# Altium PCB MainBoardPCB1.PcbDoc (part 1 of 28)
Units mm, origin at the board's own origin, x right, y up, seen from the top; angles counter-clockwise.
Board outline 258.95 x 308.86 mm, 16 copper layers (L1, L2 (GND), L3 (Sign), L4 (GND), L5 (Sign), L6 (PWR/GND), L7(PWR/GND), L8 (Plane_GND), L9 (PWR/GND), L10 (PWR/GND), L11 (PWR/GND), L12 (Sign), L13 (GND), L14 (Sign), L15 (GND), L16), stack 2.502 mm thick; 2397 components, 1744 nets, 8397 pads, 4112 vias.
Unrouted connection lines stored in the file: 3547.

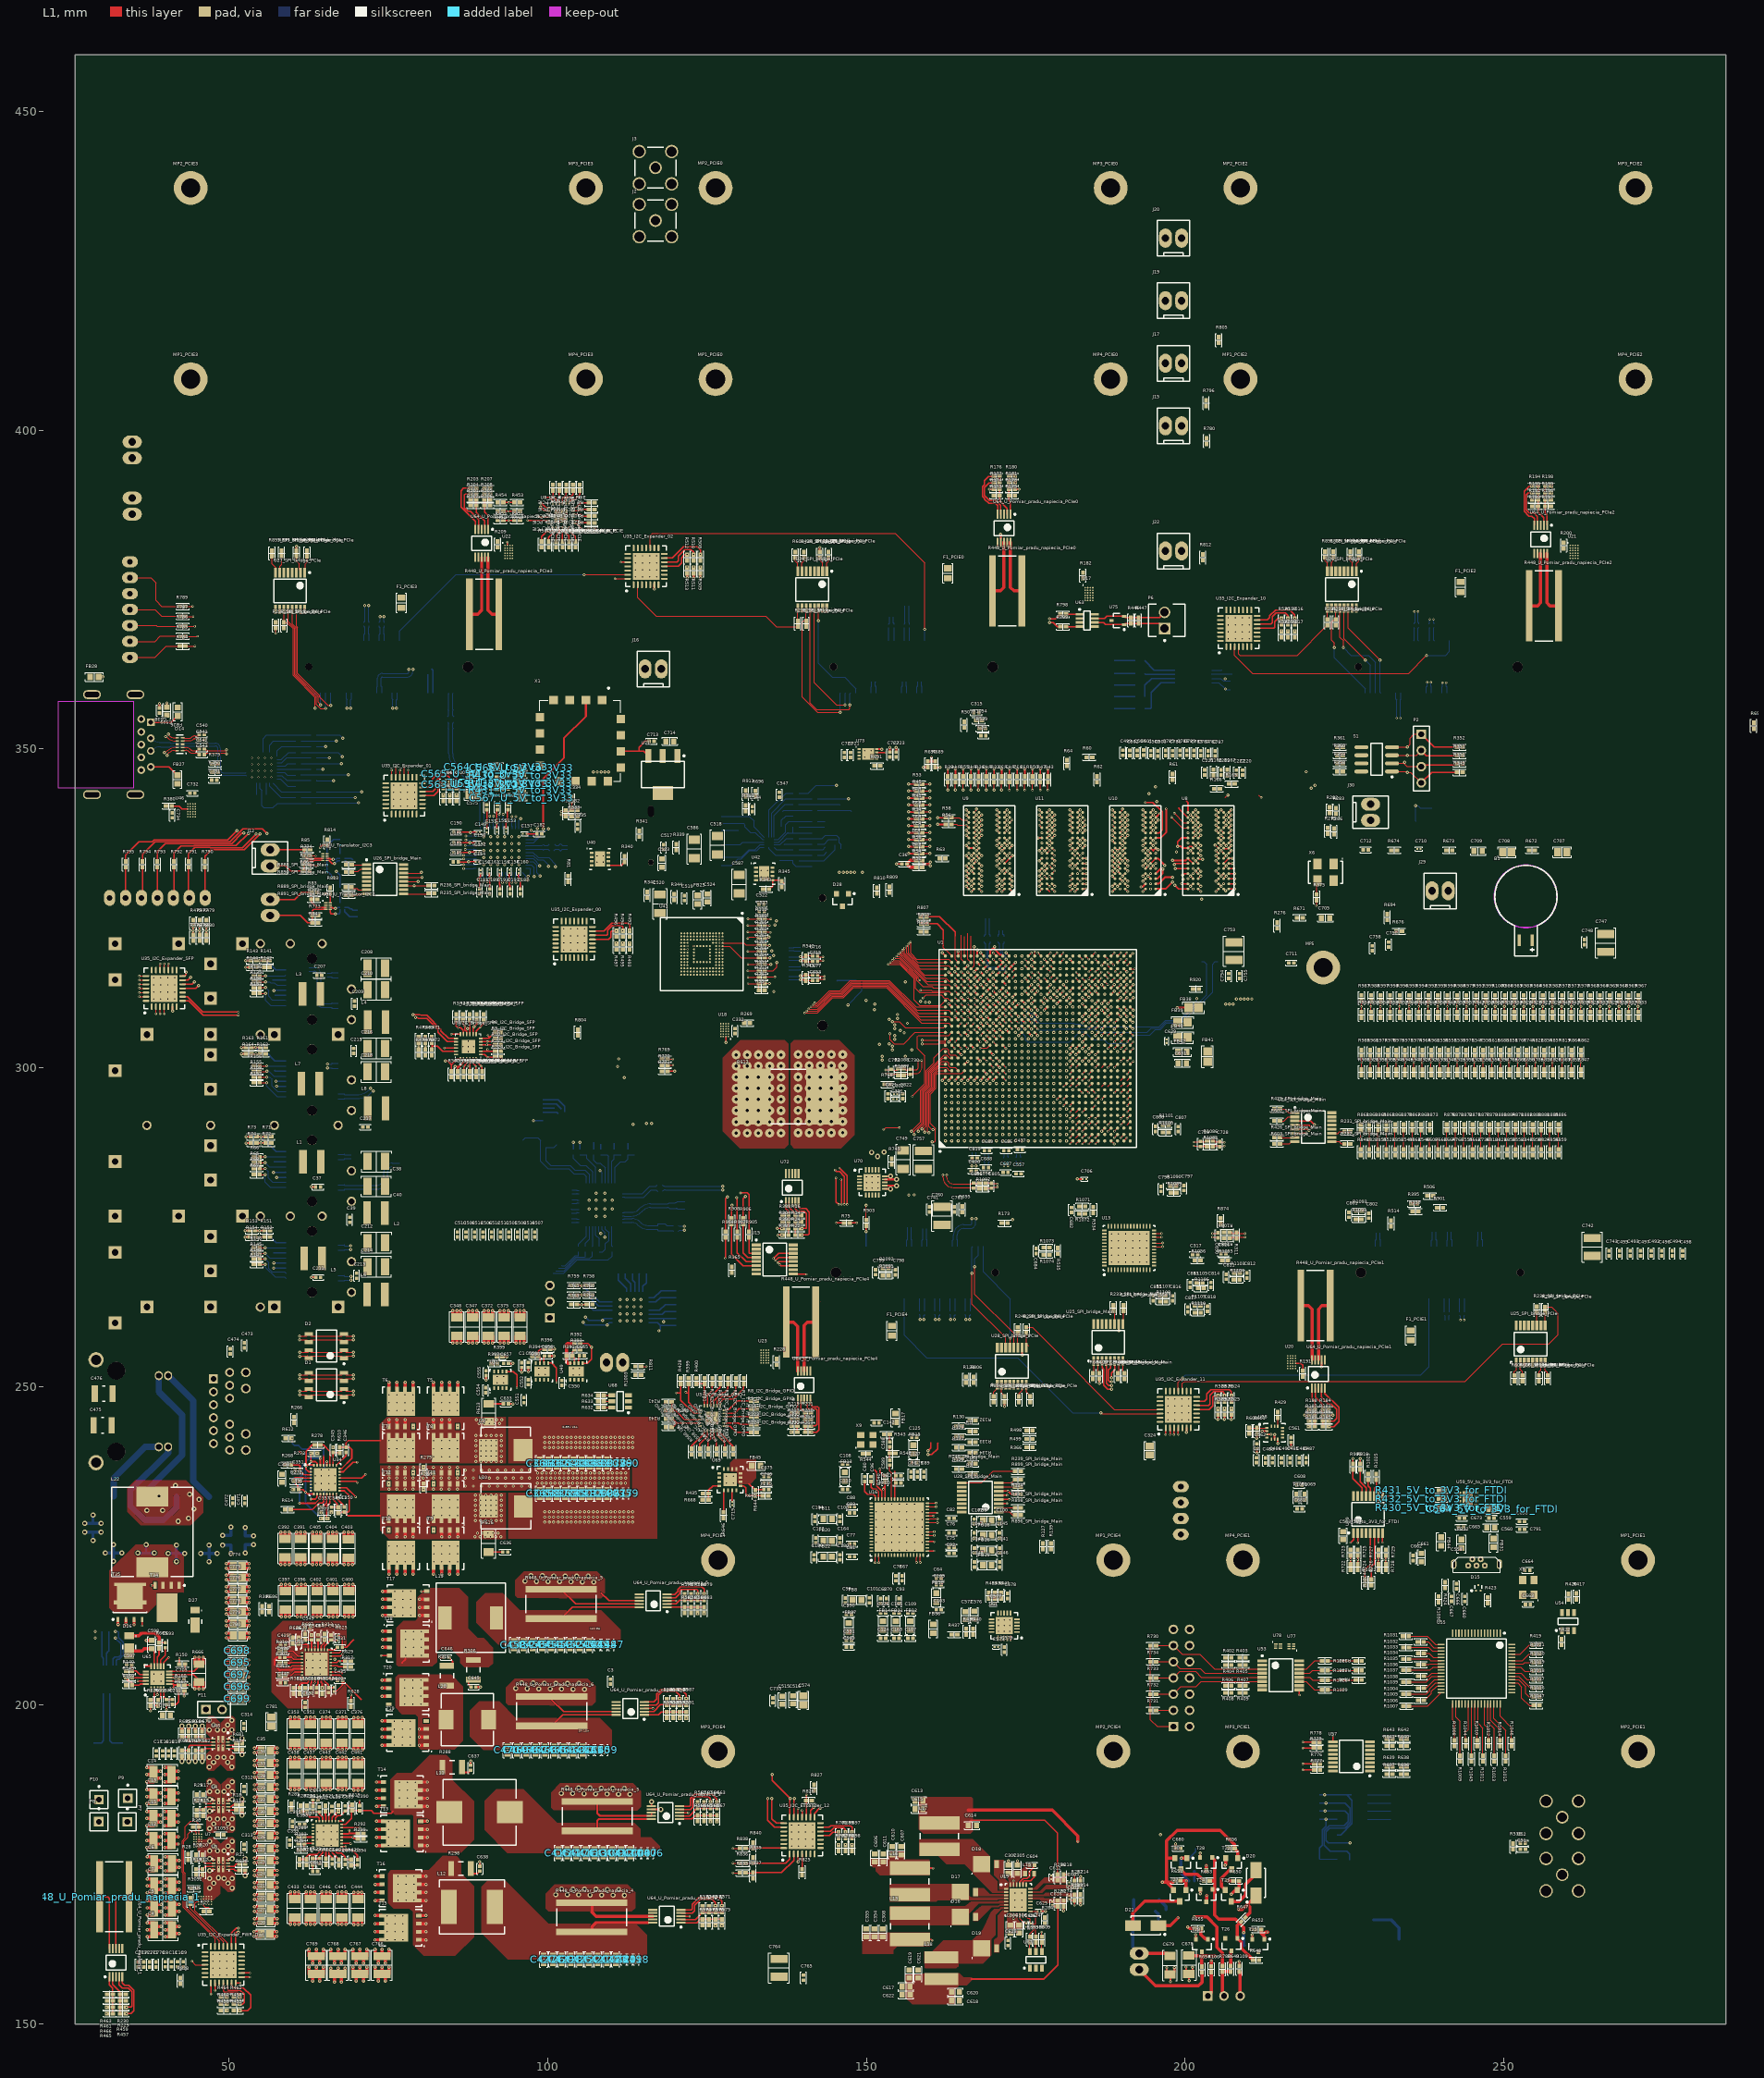
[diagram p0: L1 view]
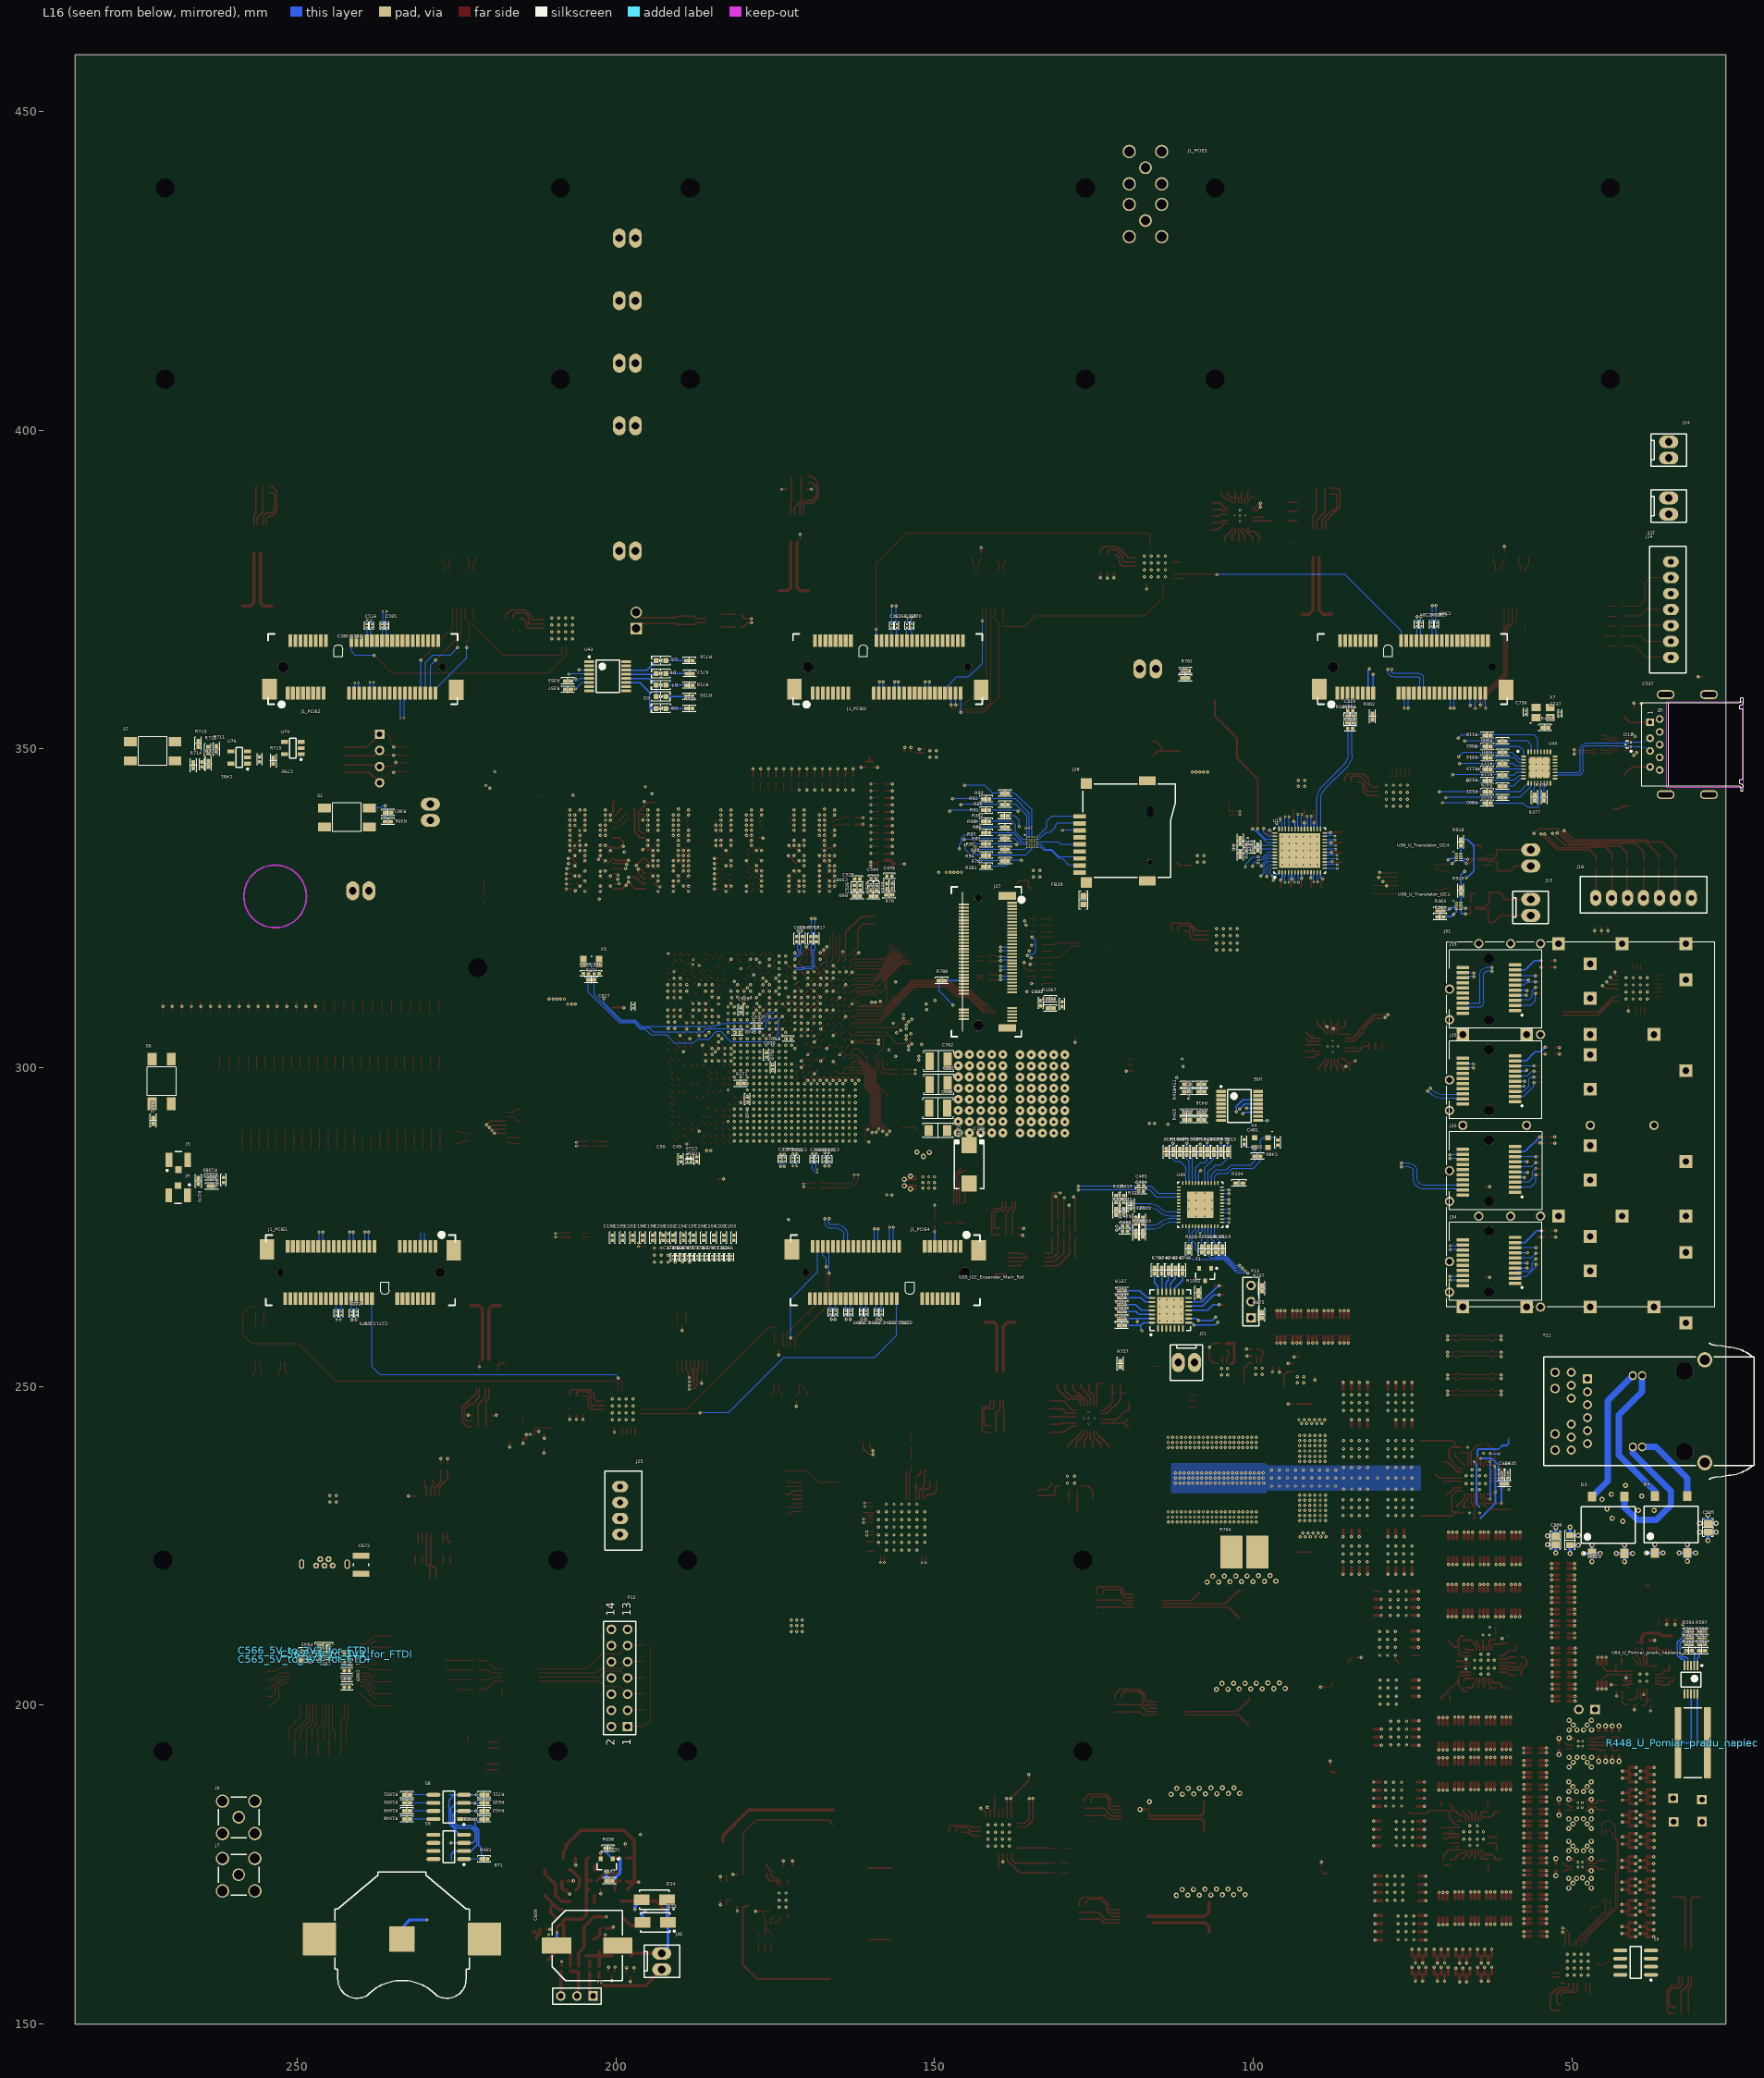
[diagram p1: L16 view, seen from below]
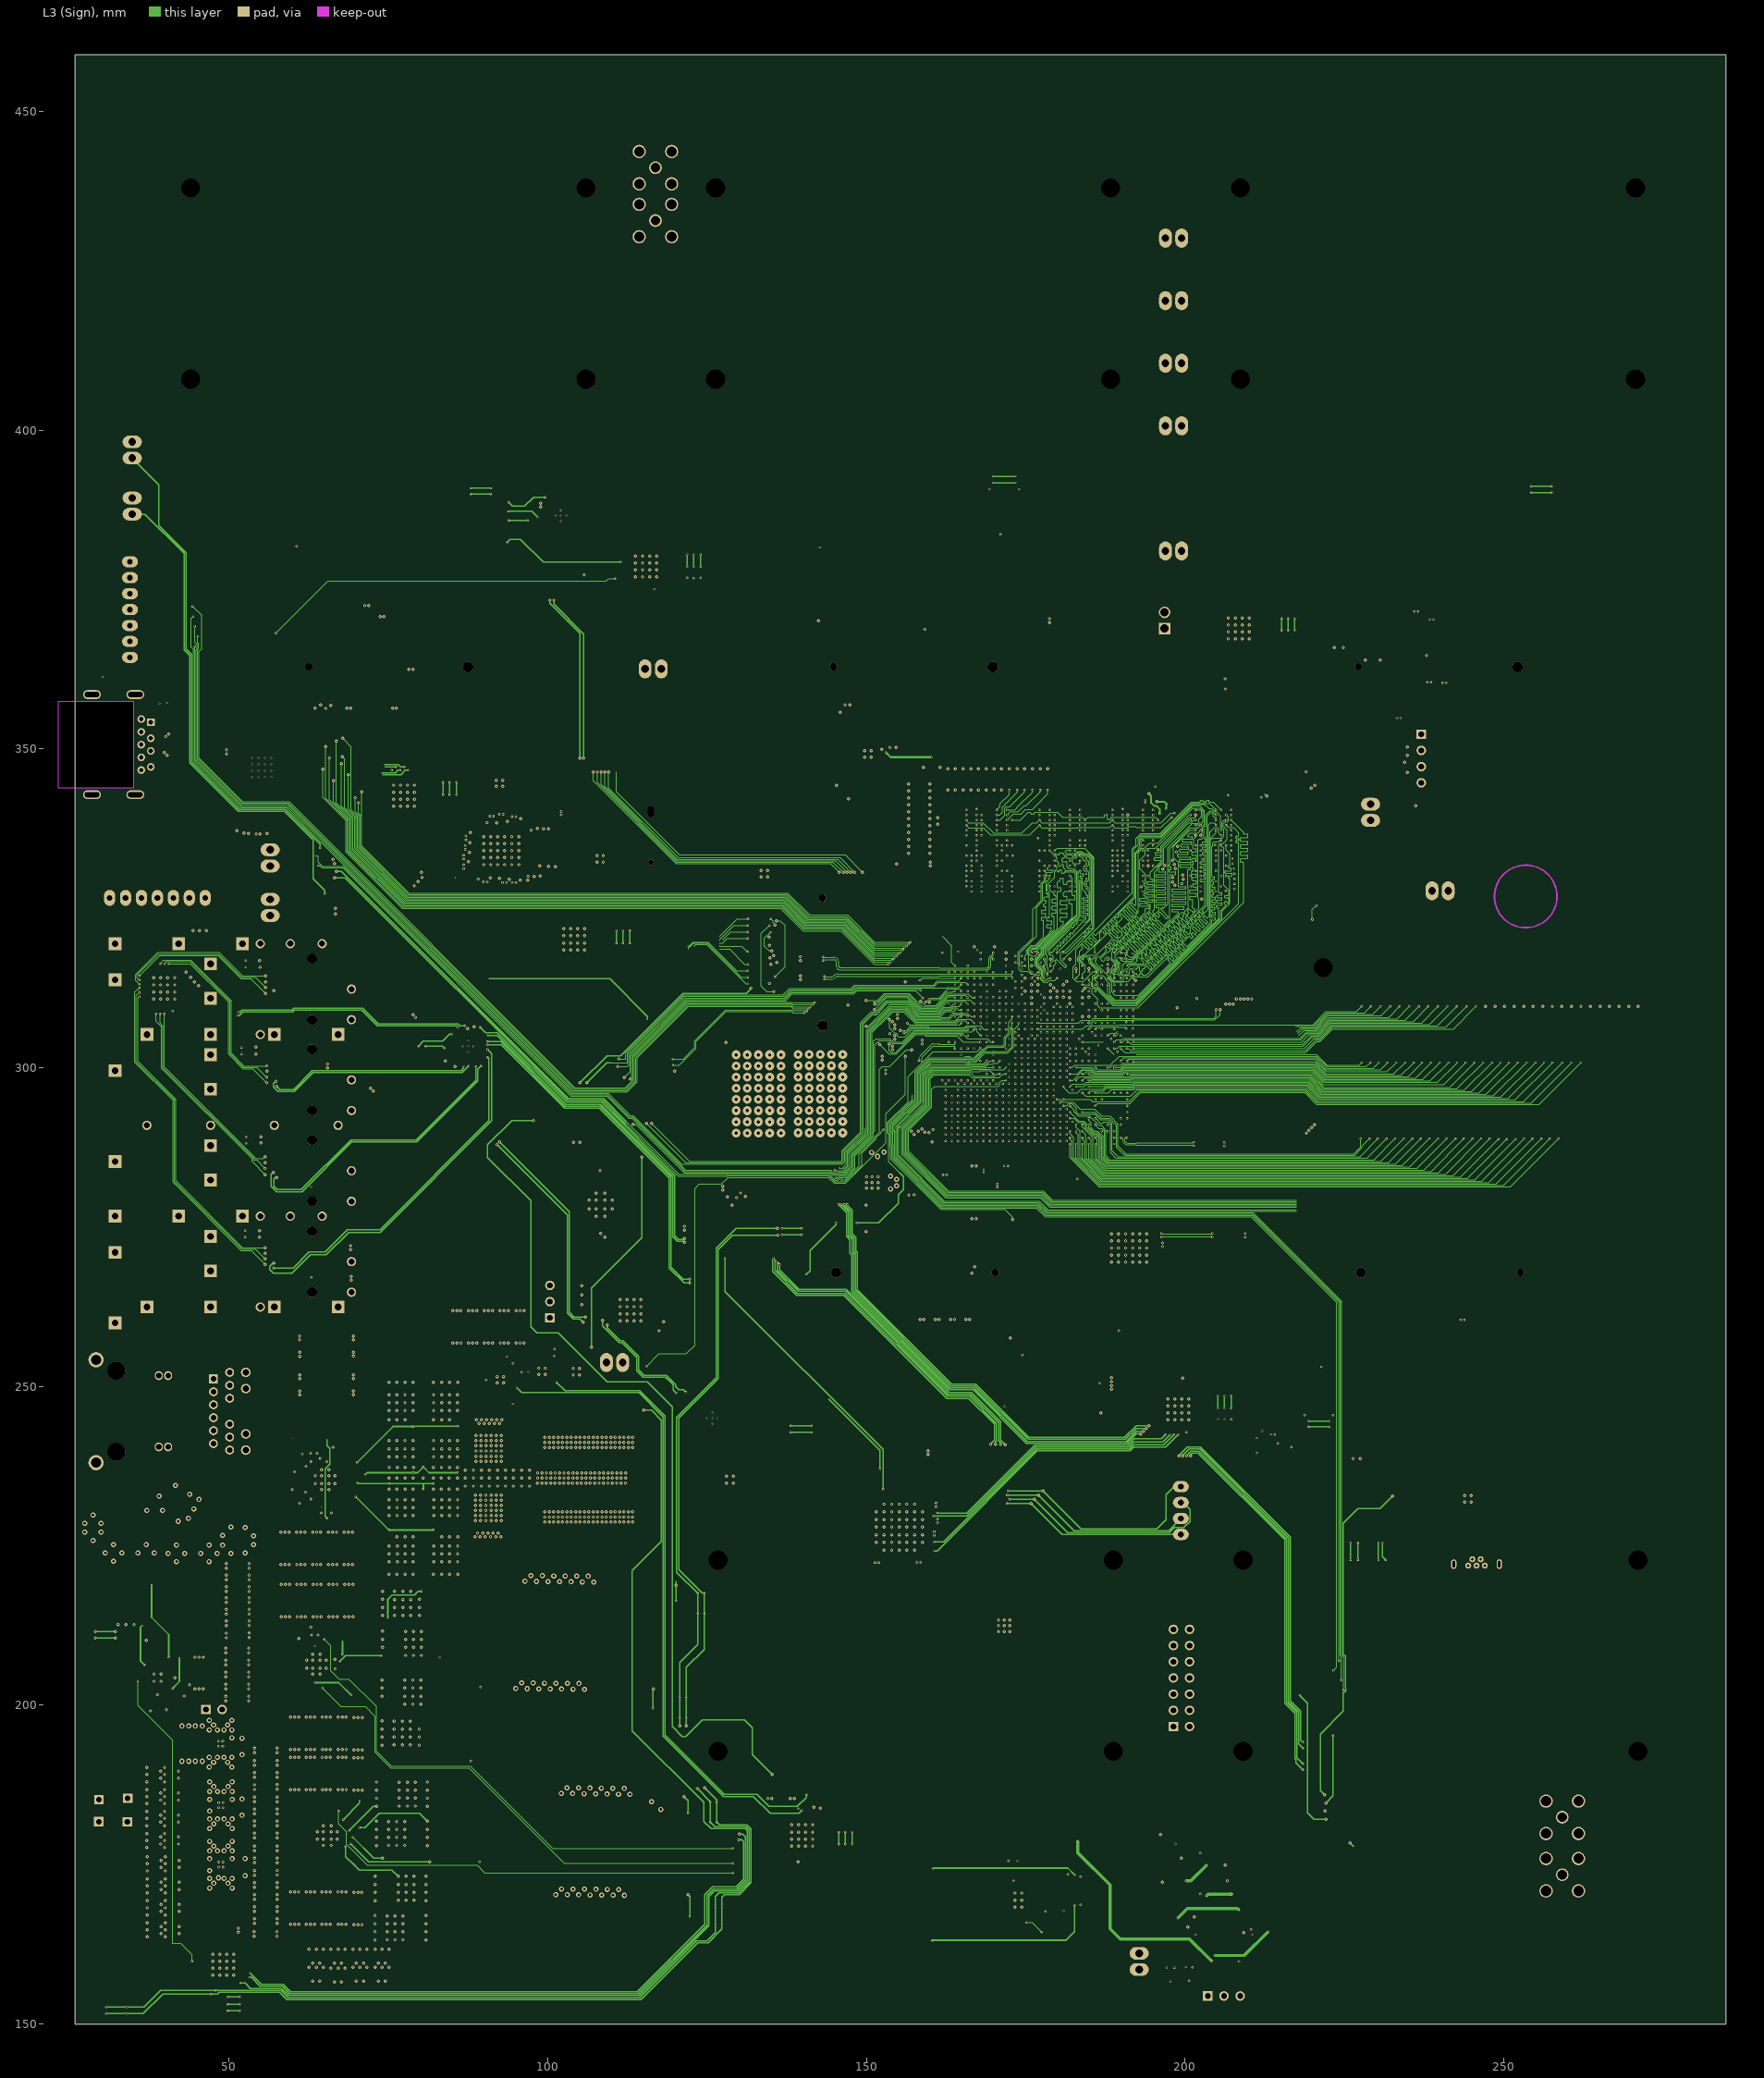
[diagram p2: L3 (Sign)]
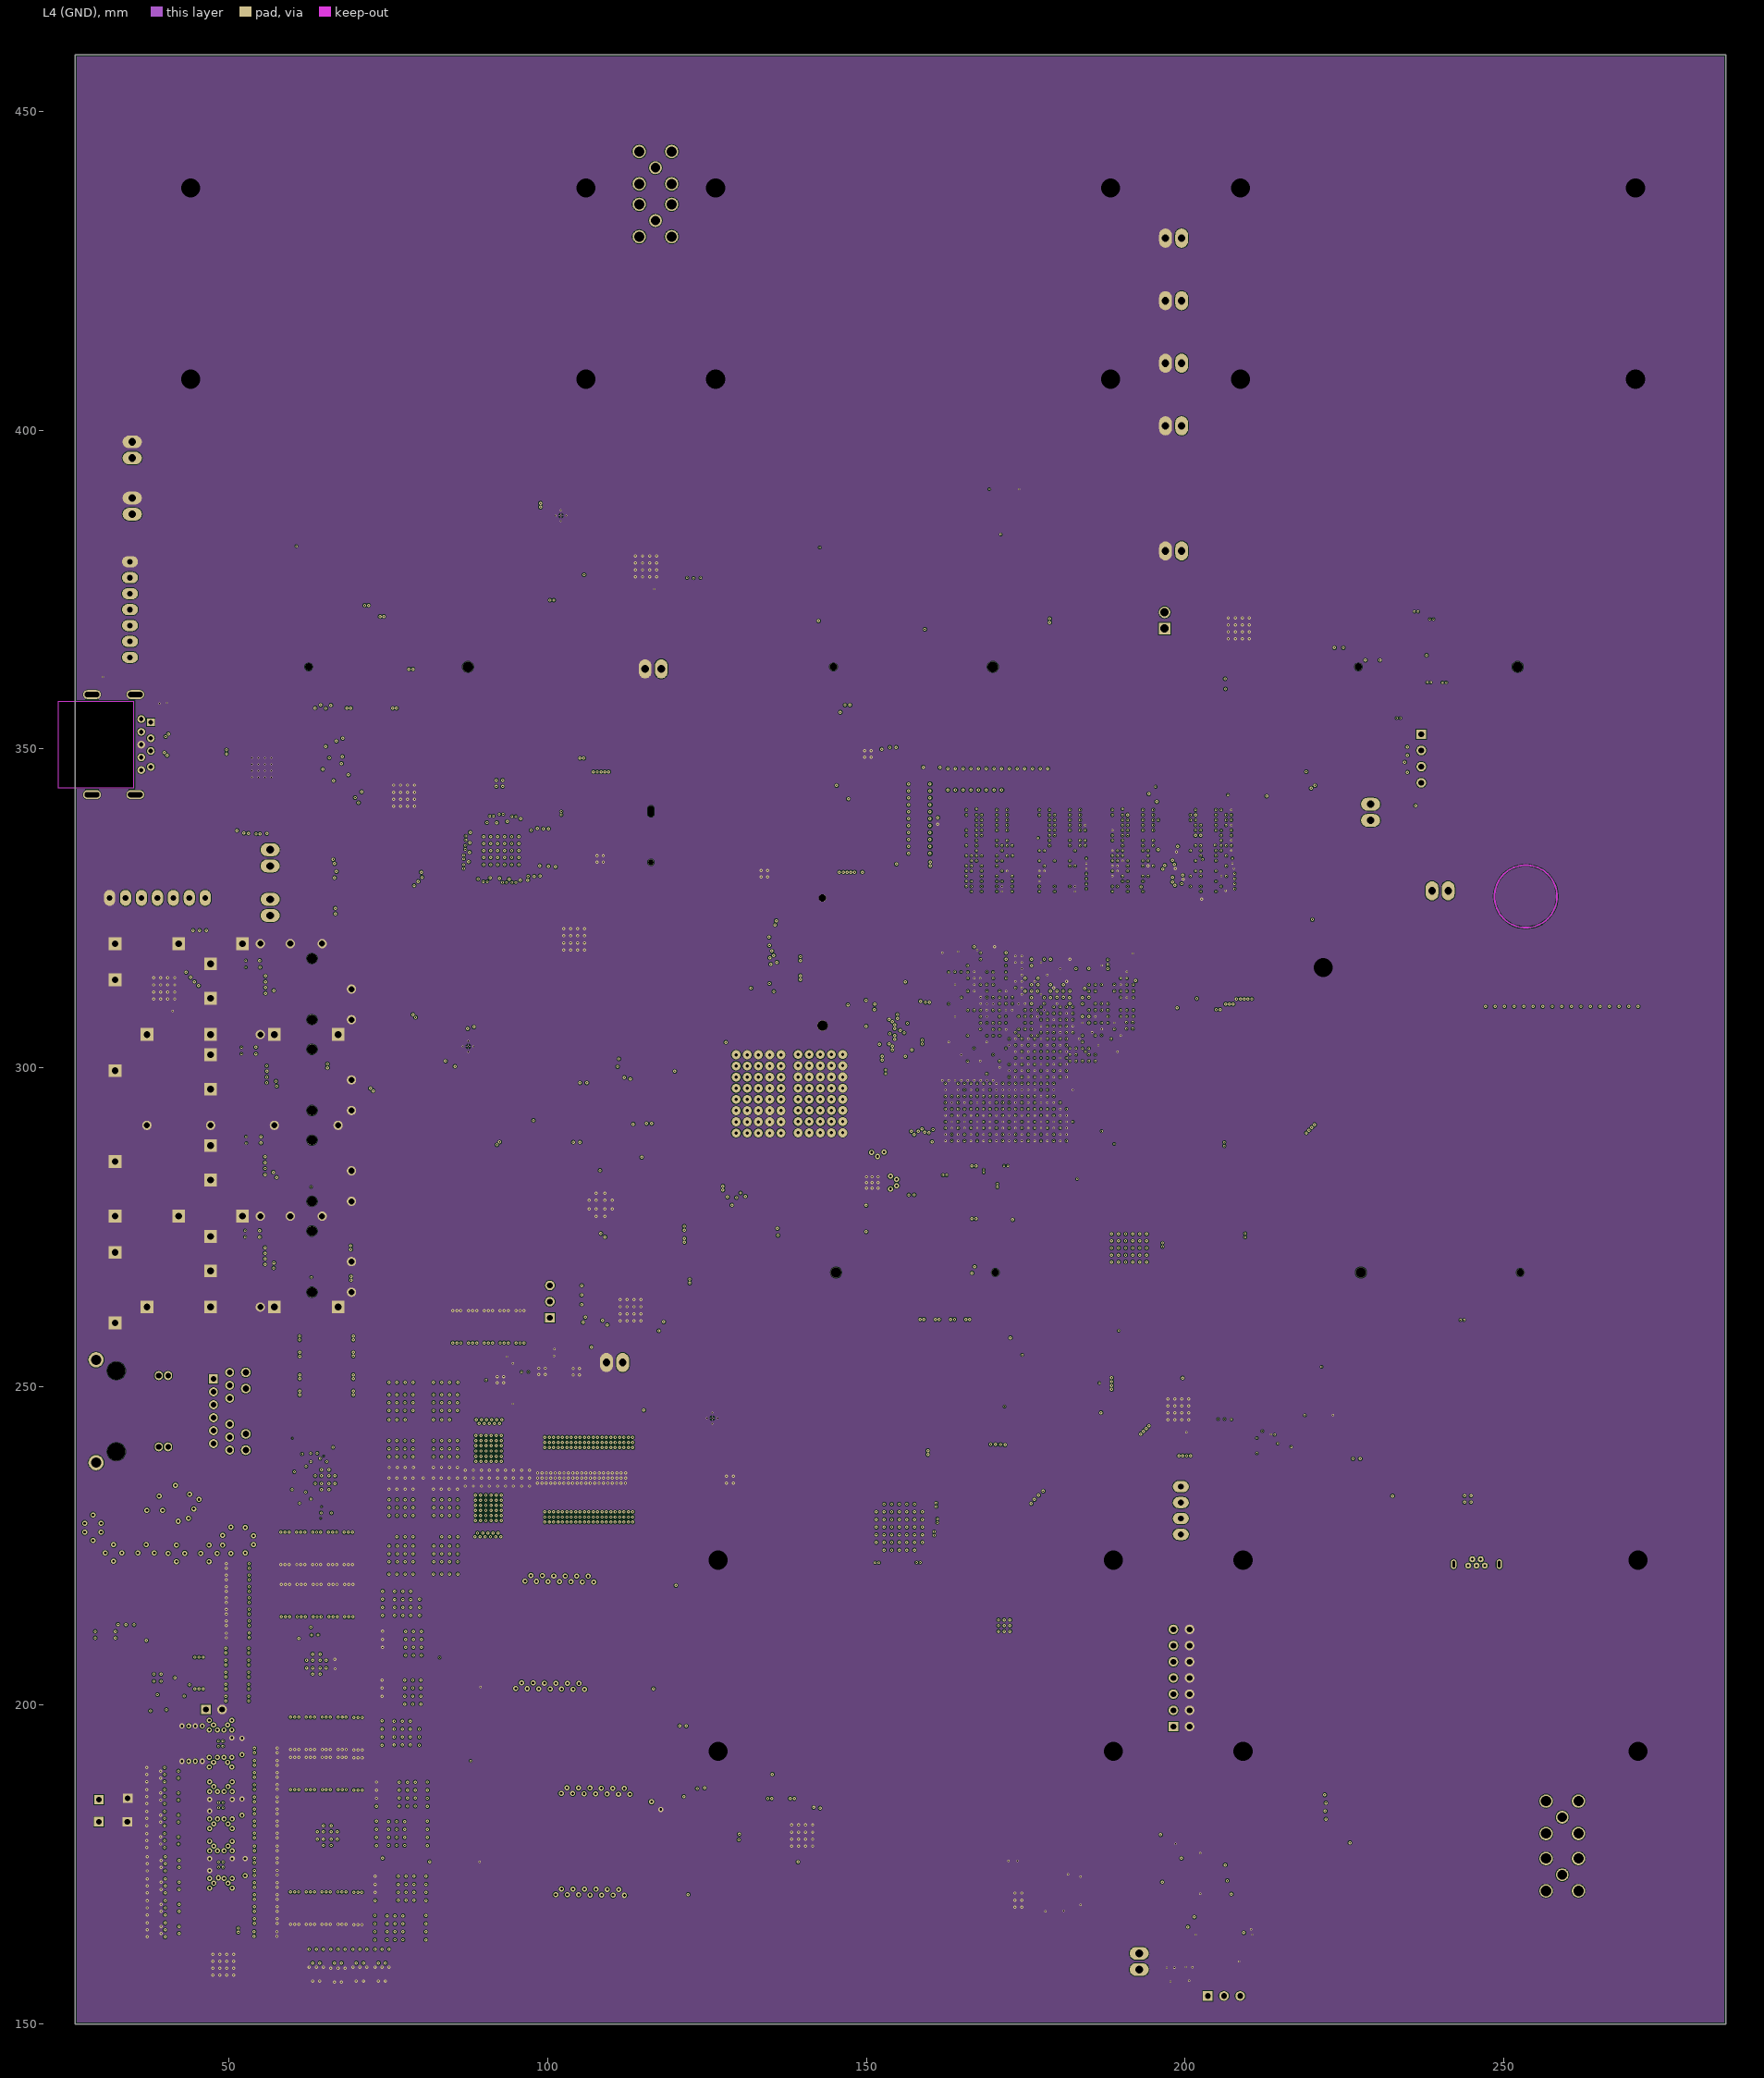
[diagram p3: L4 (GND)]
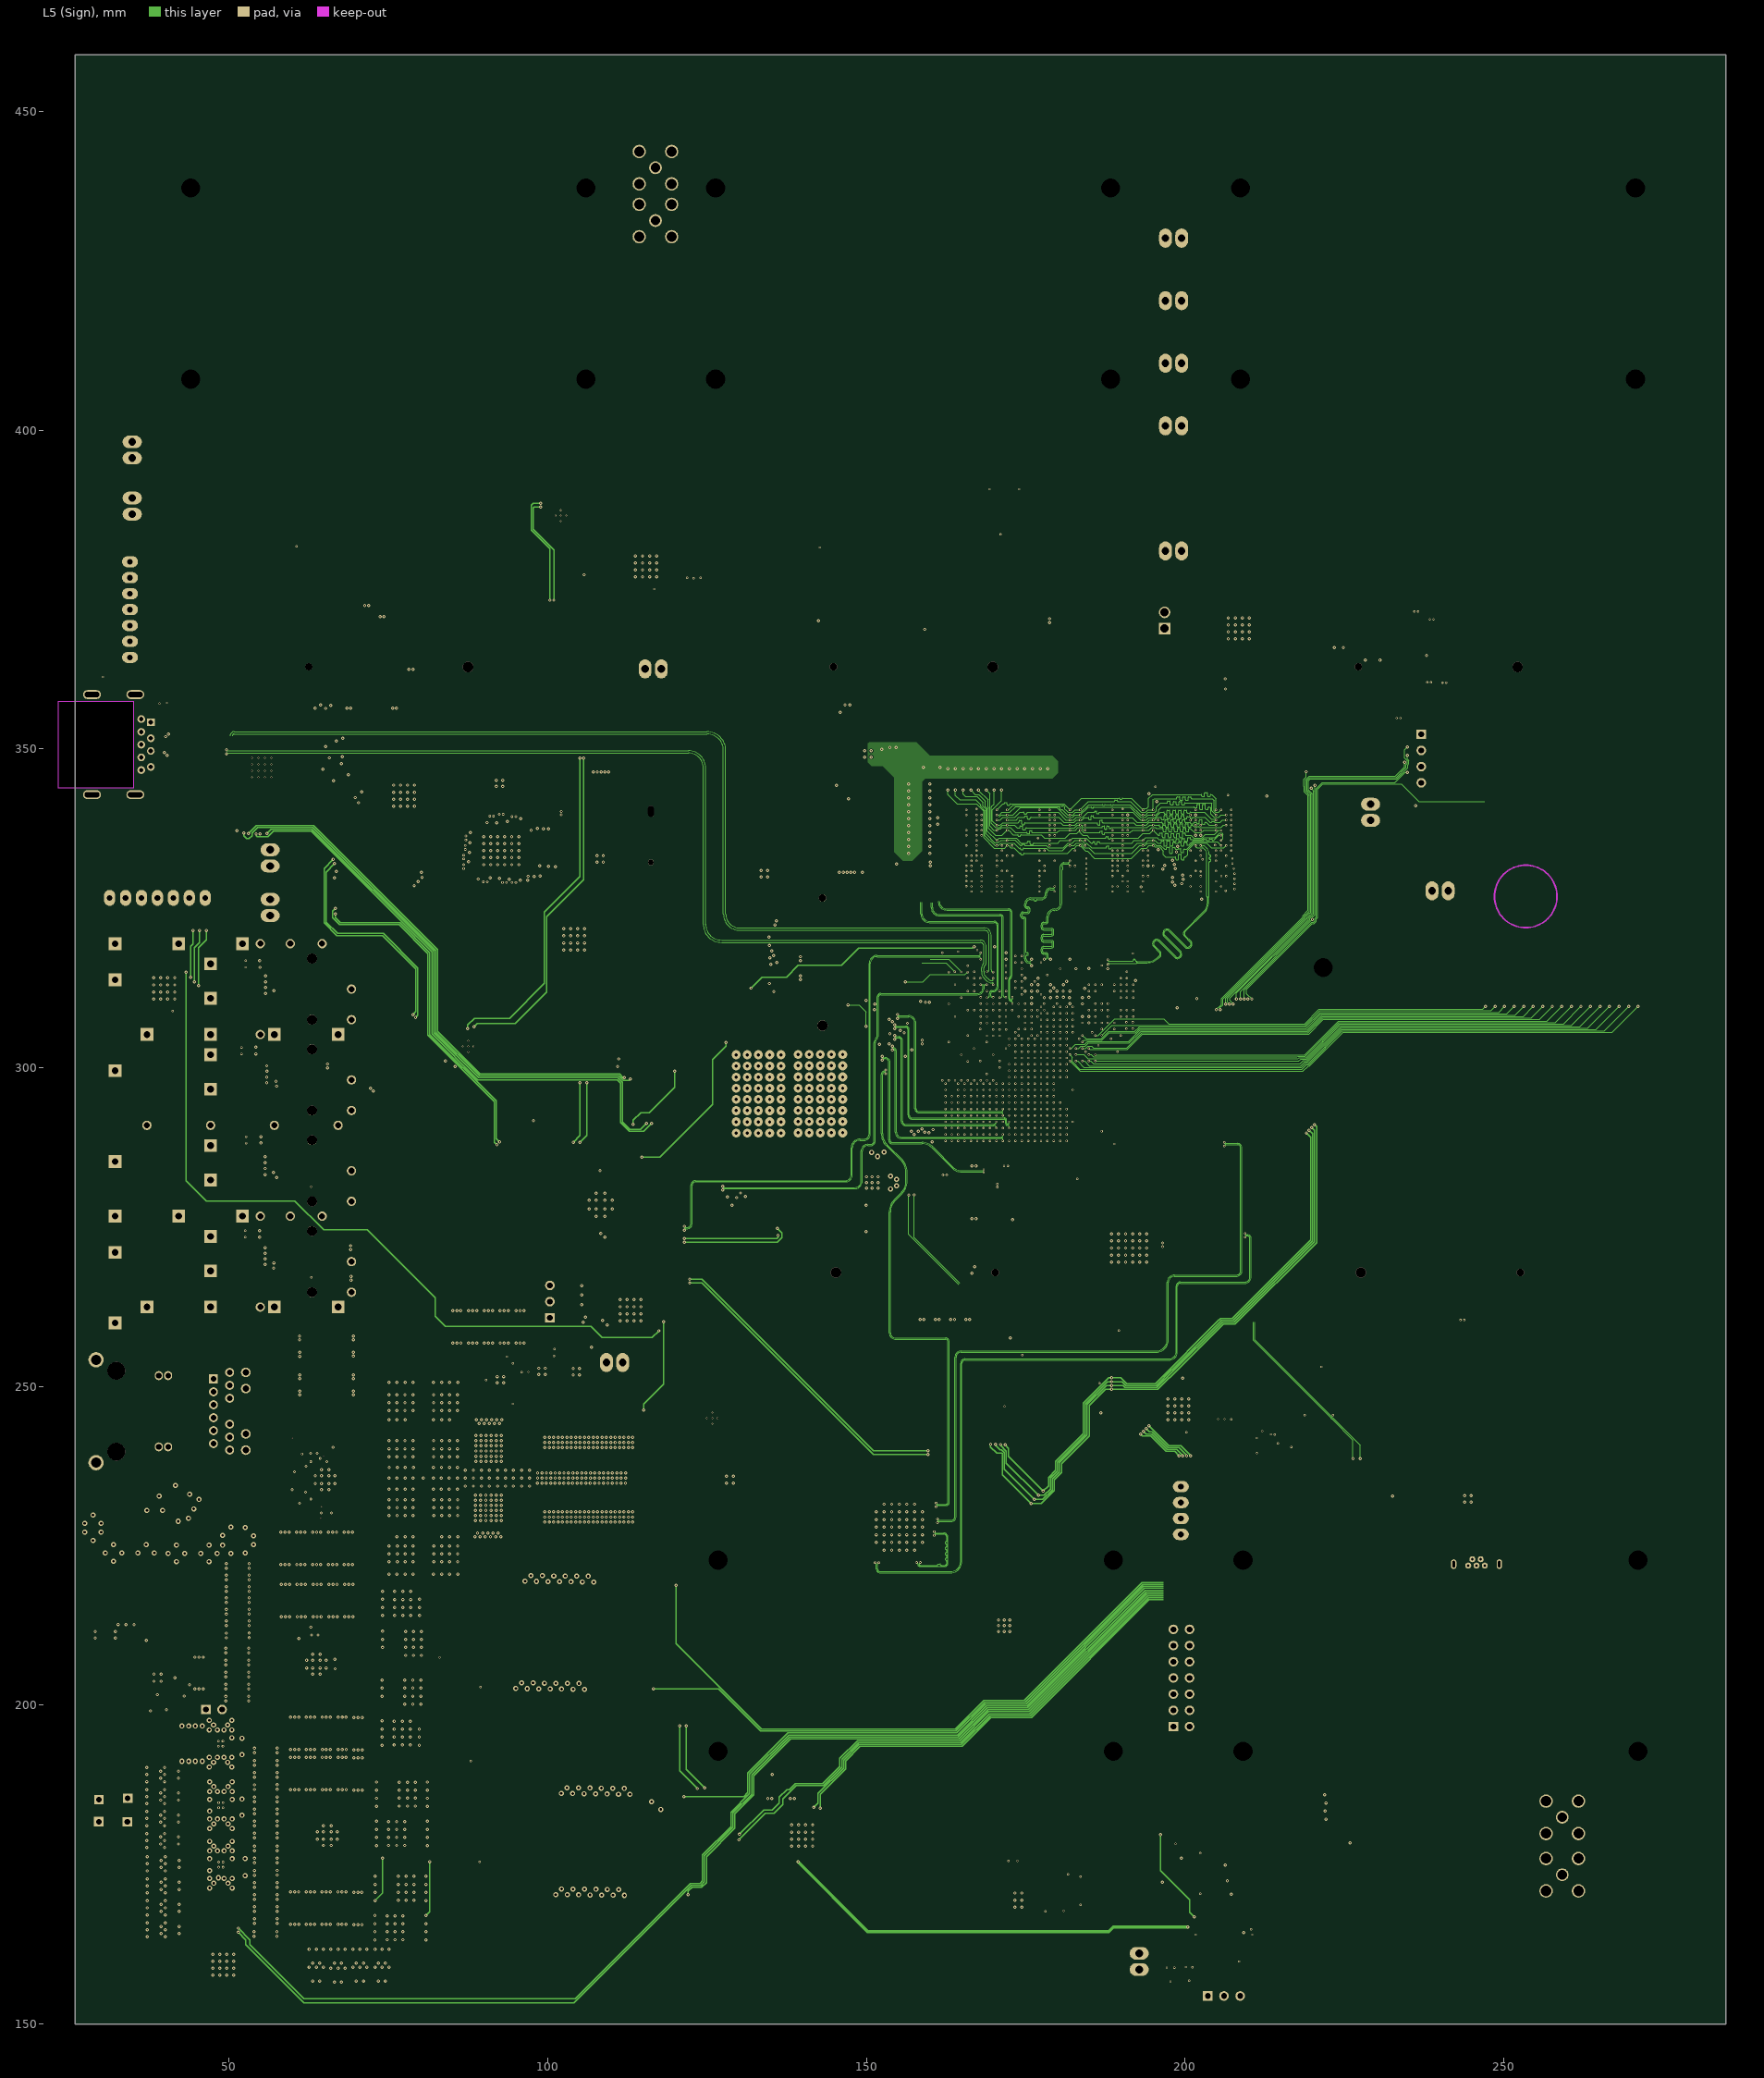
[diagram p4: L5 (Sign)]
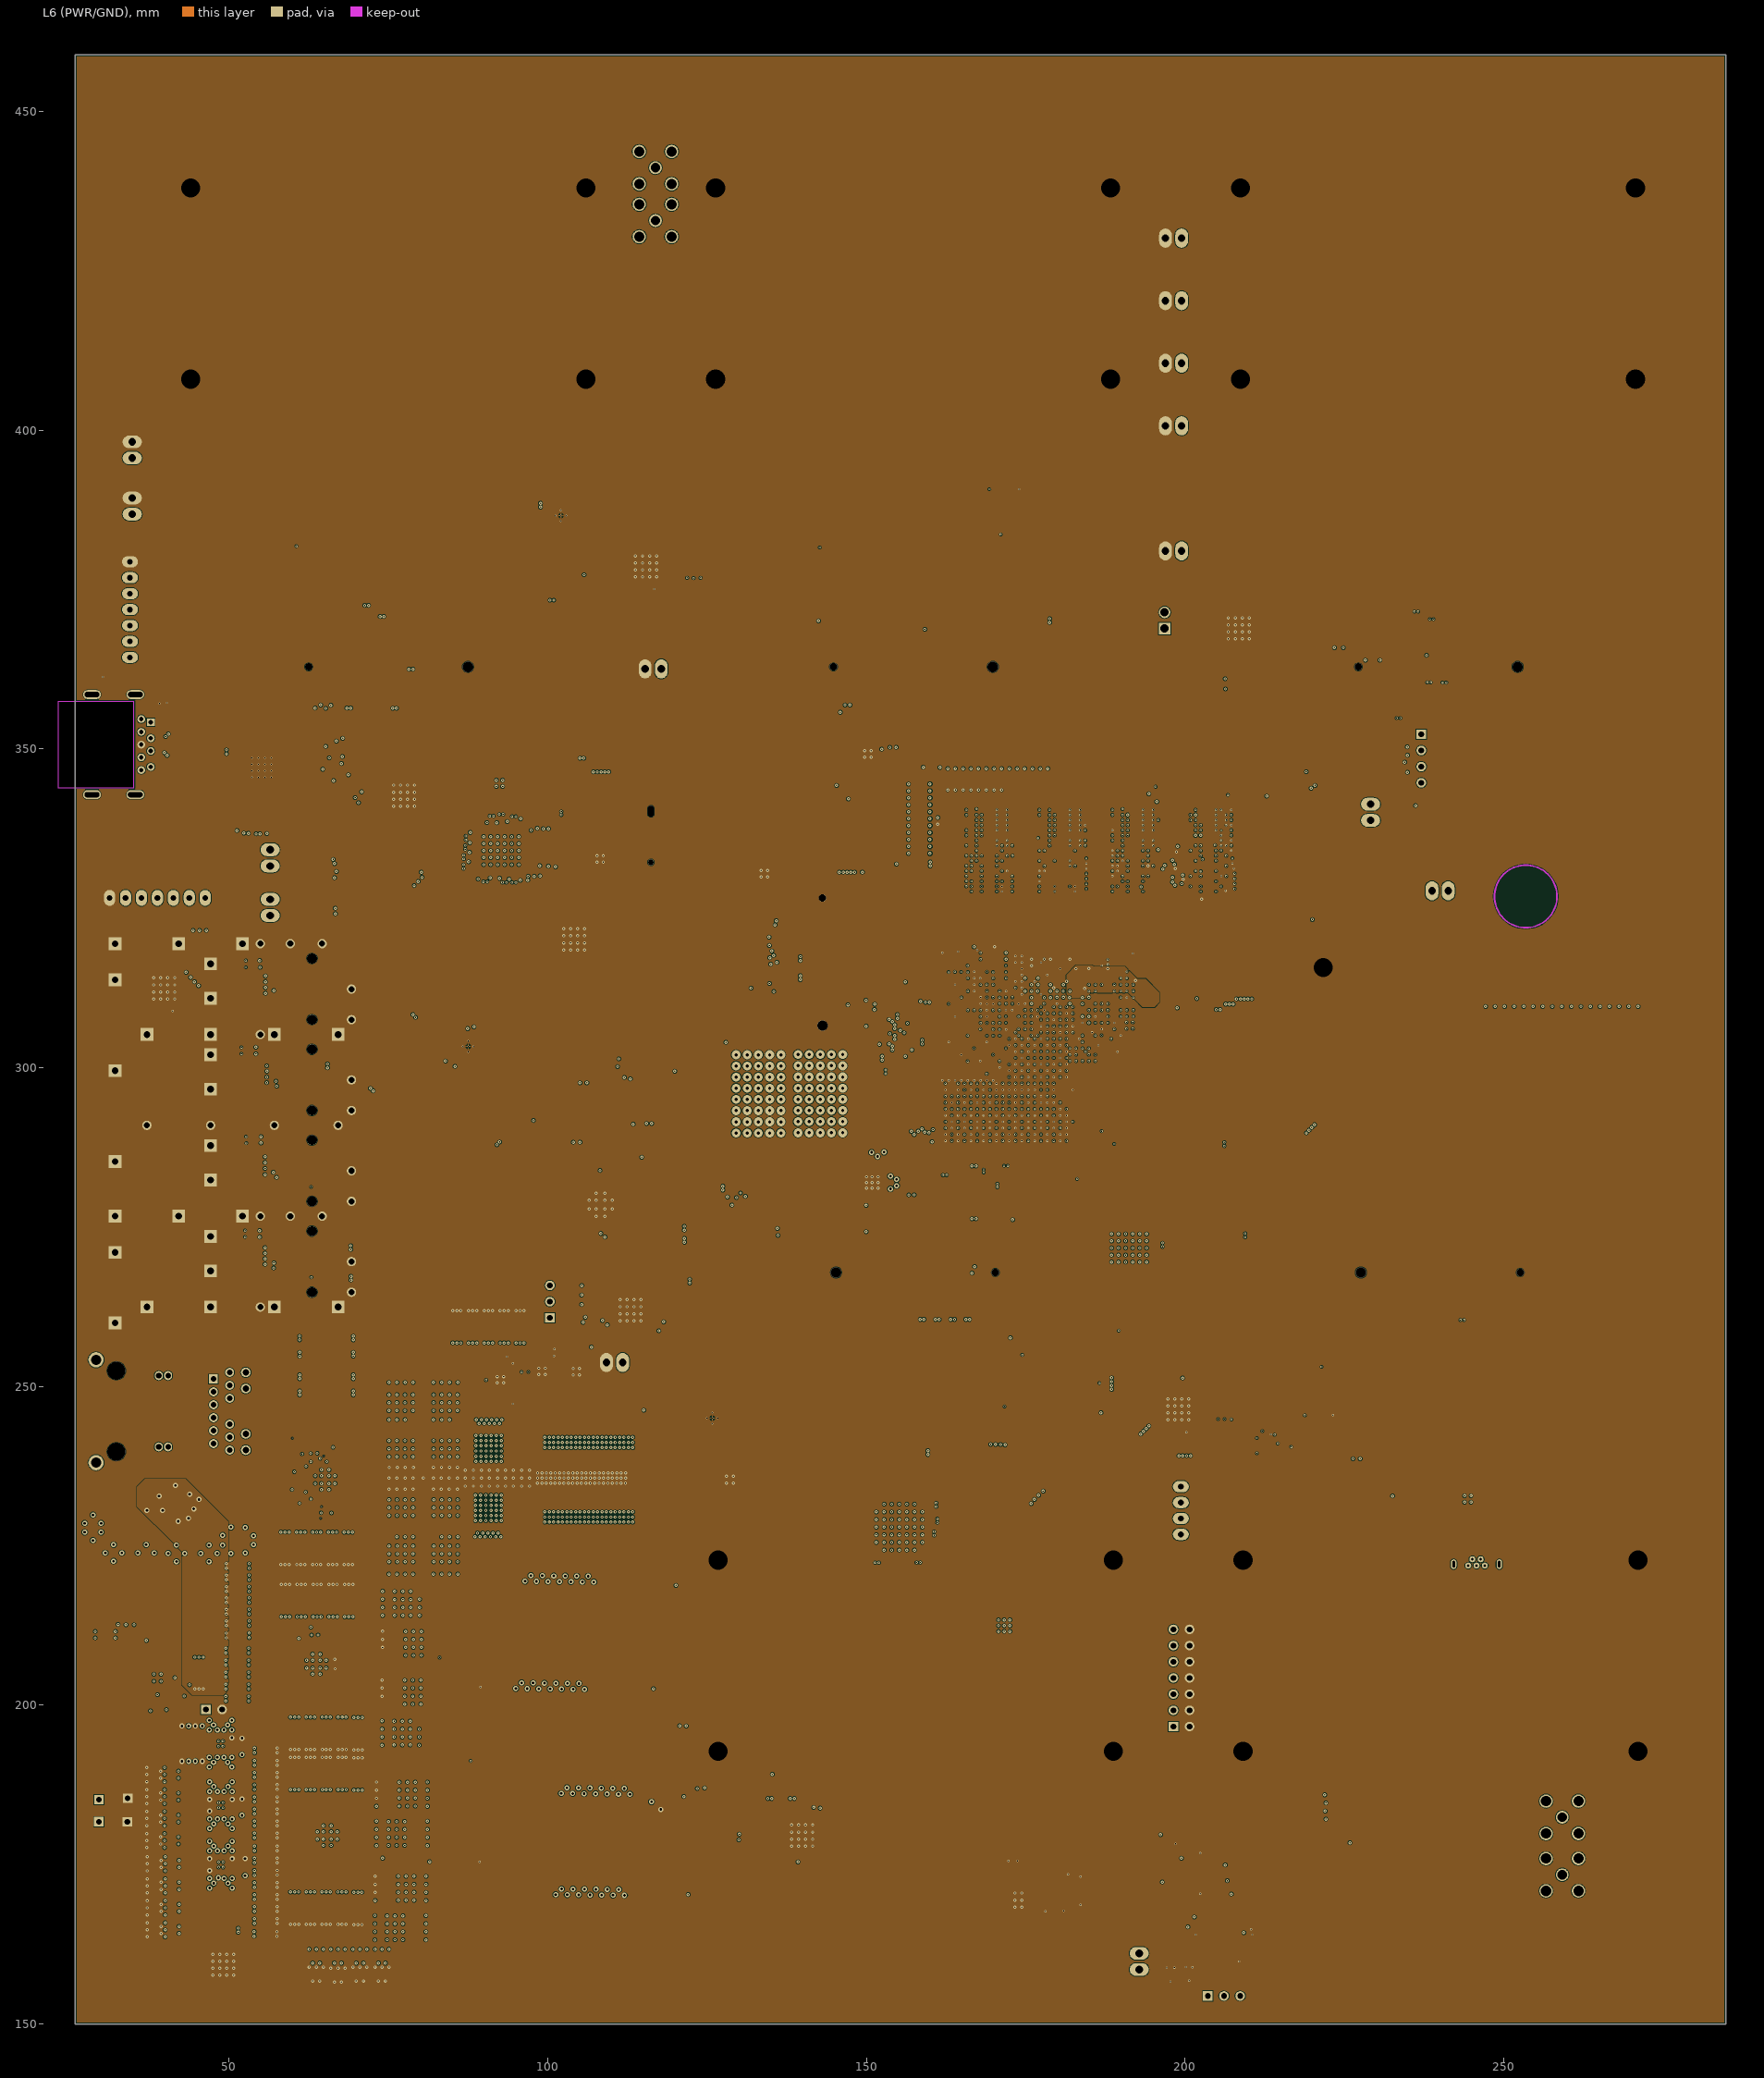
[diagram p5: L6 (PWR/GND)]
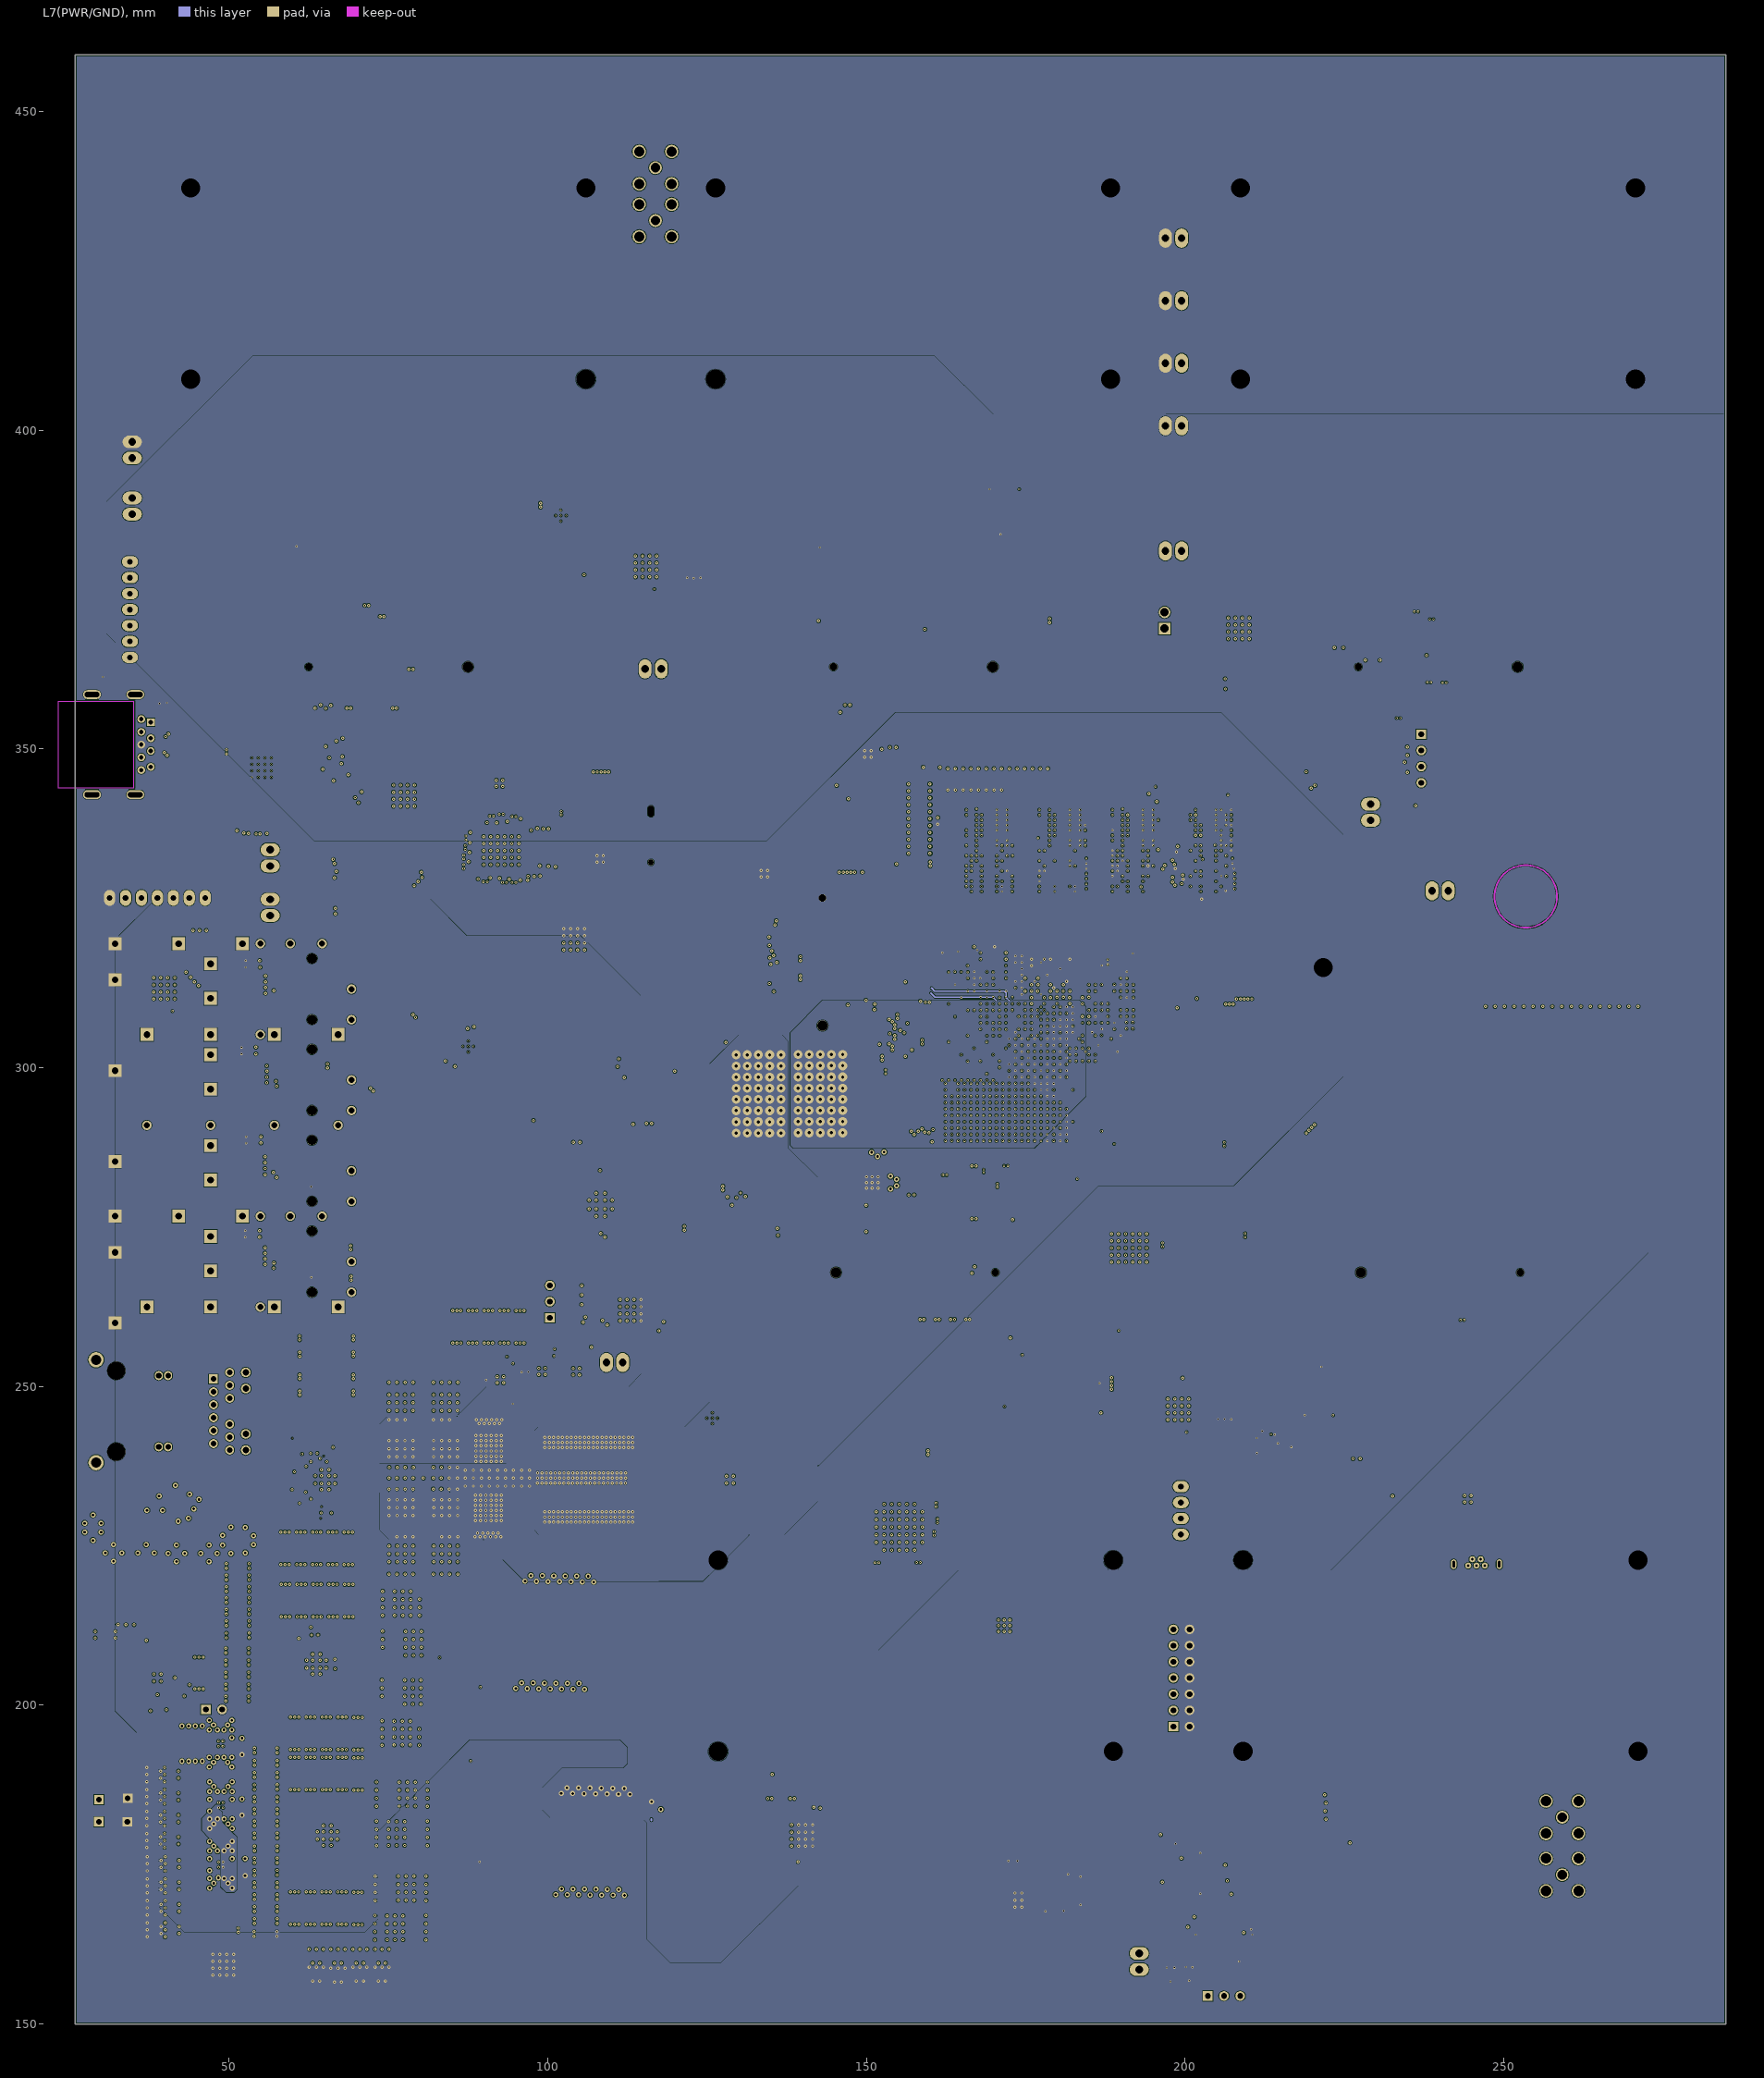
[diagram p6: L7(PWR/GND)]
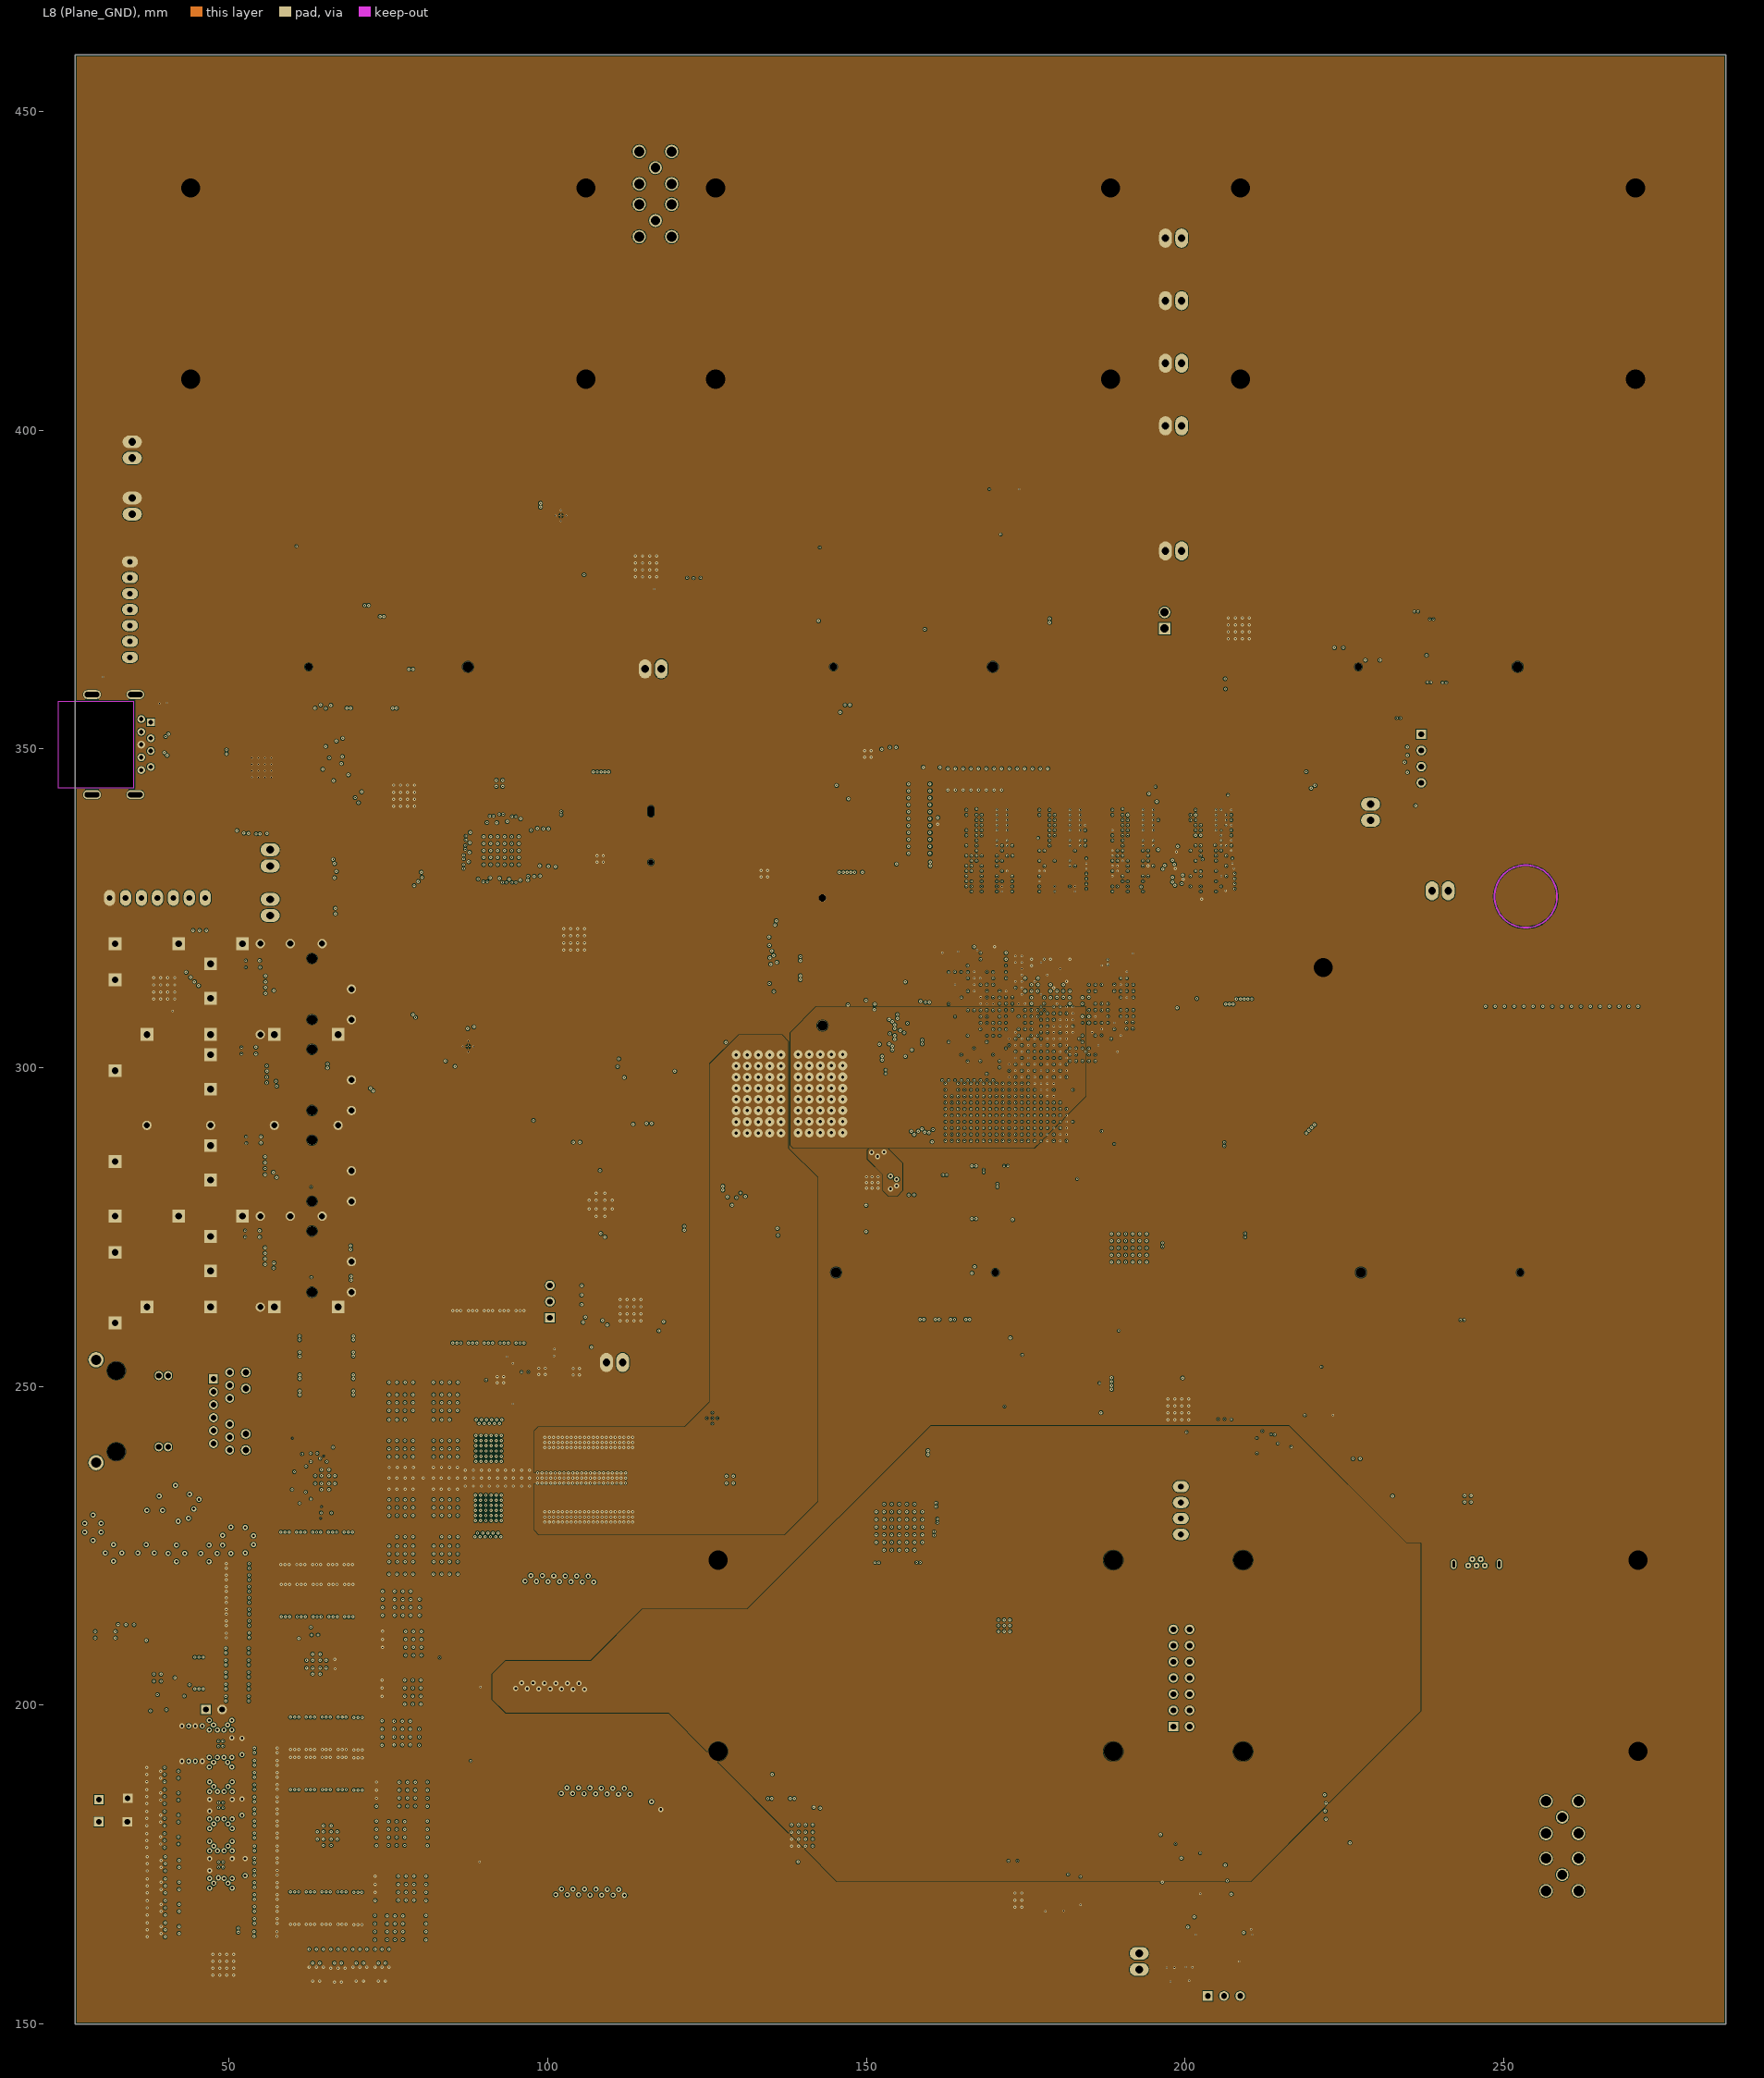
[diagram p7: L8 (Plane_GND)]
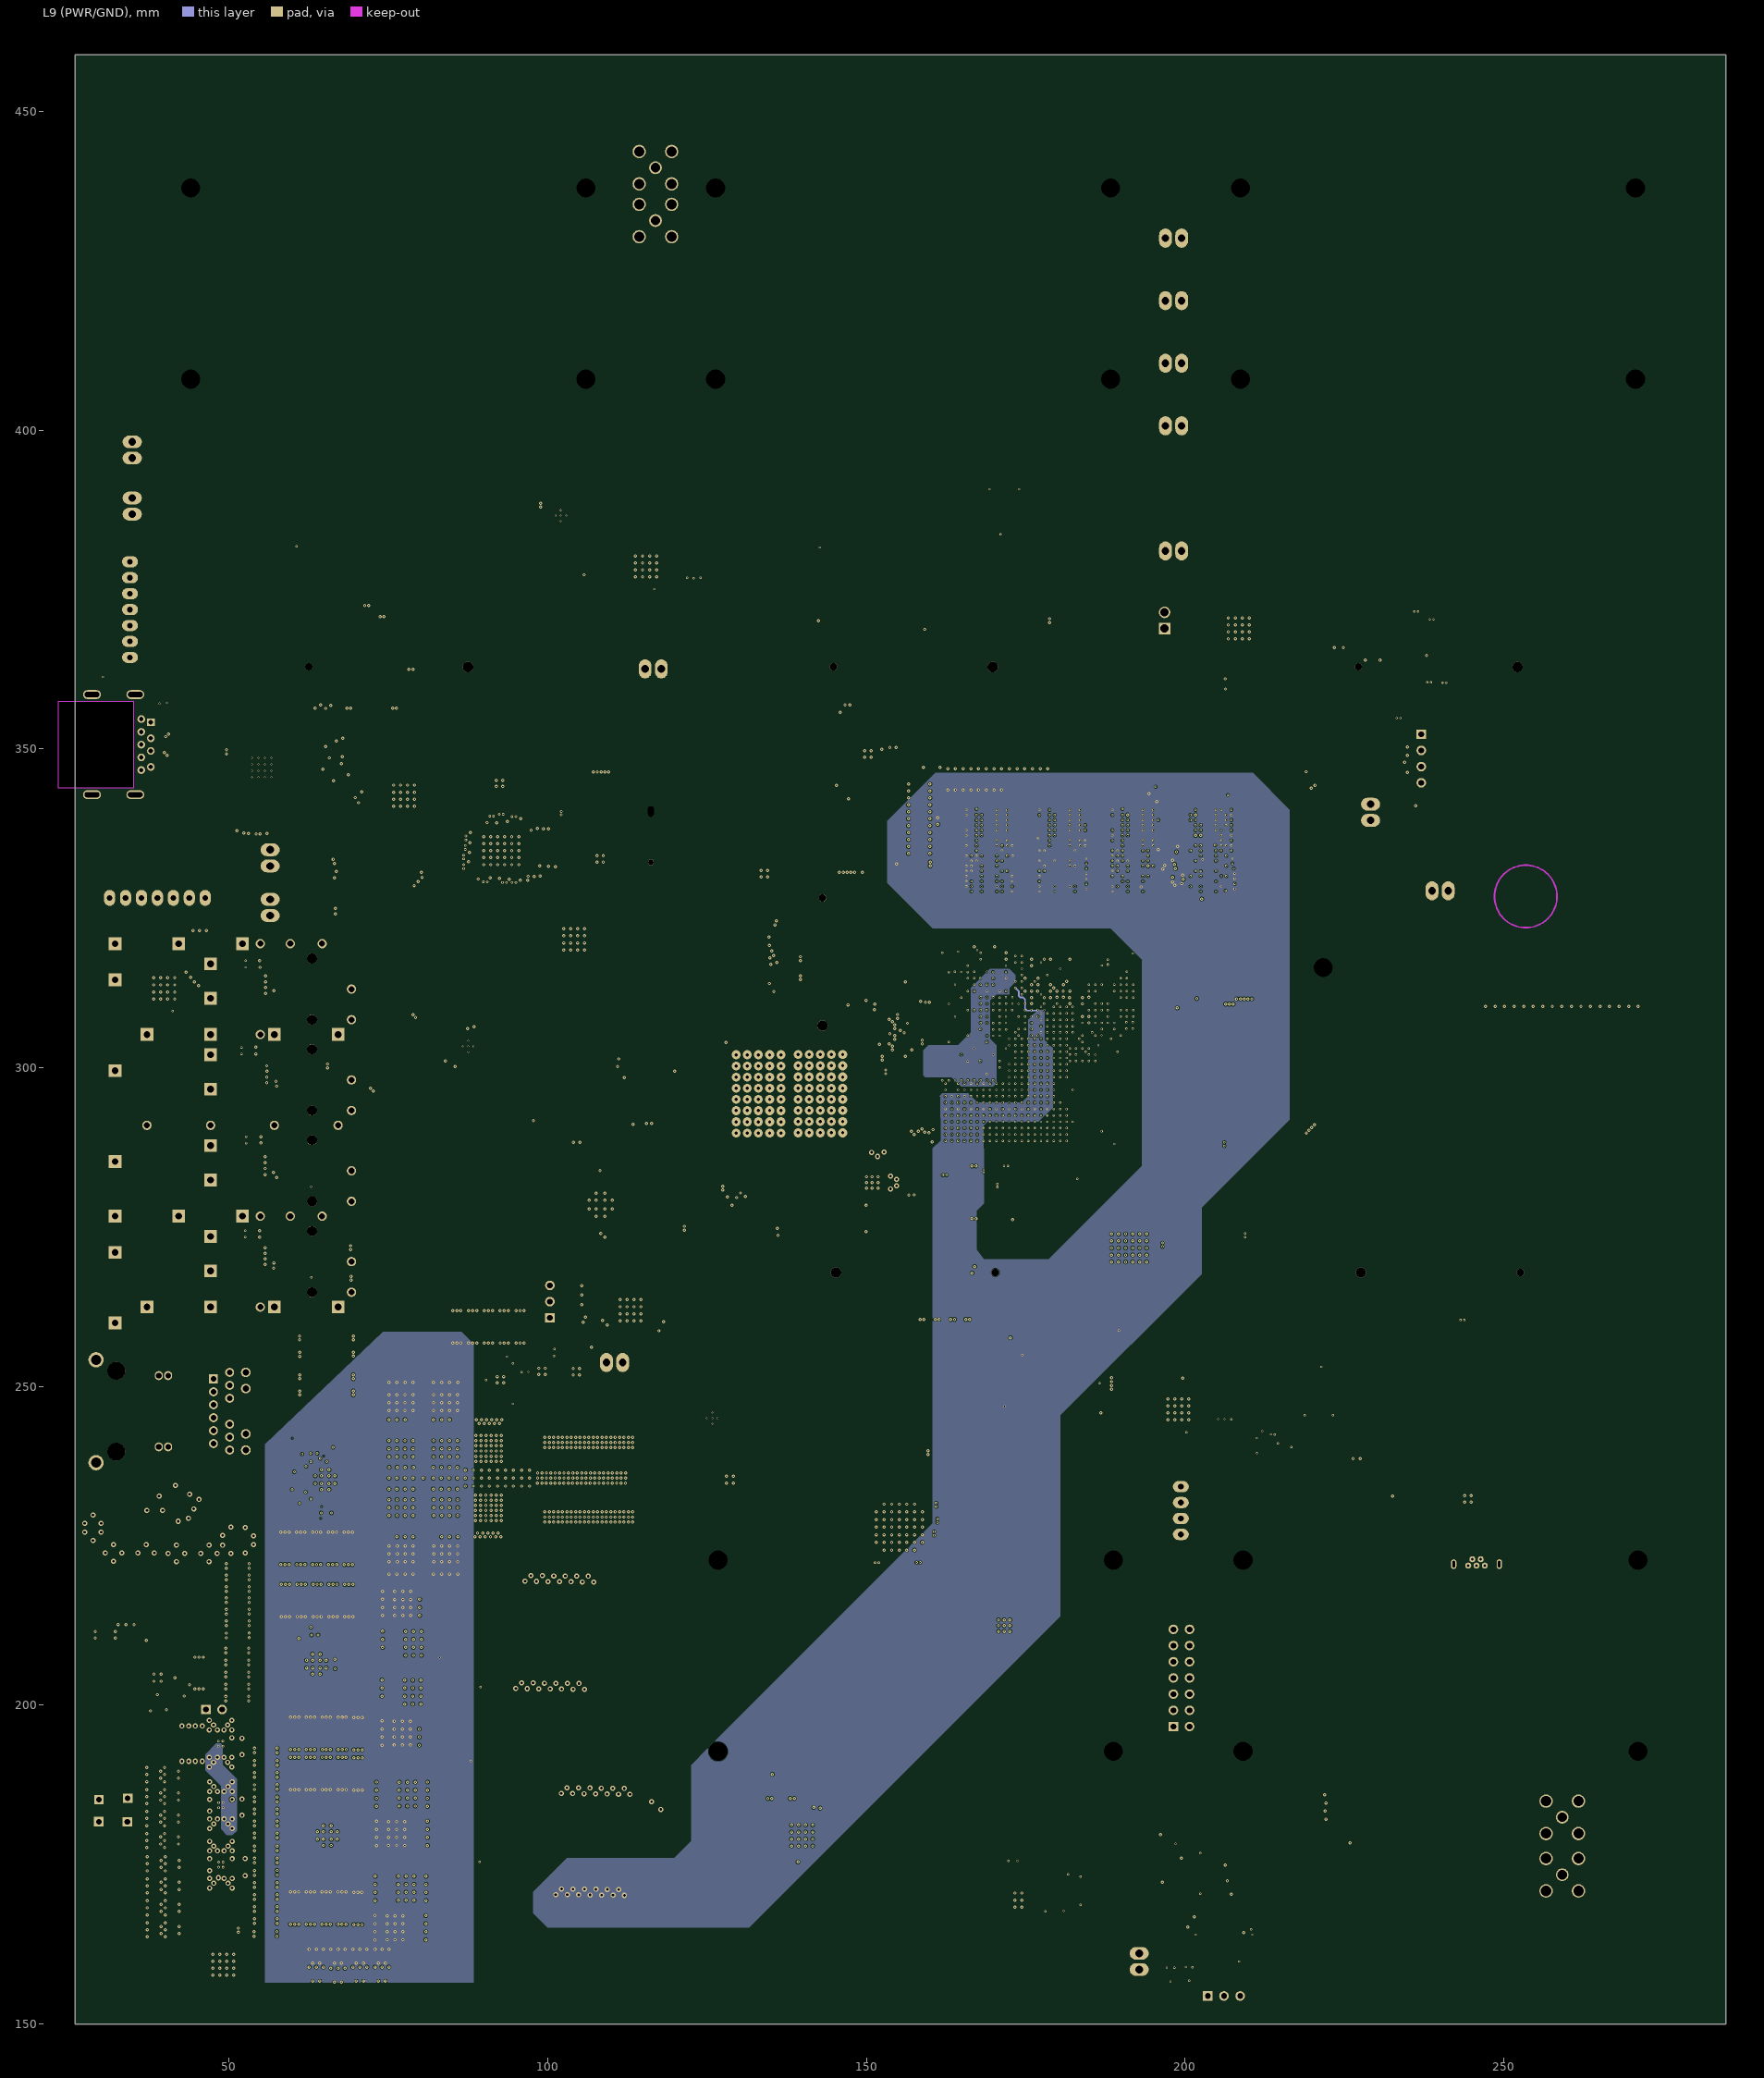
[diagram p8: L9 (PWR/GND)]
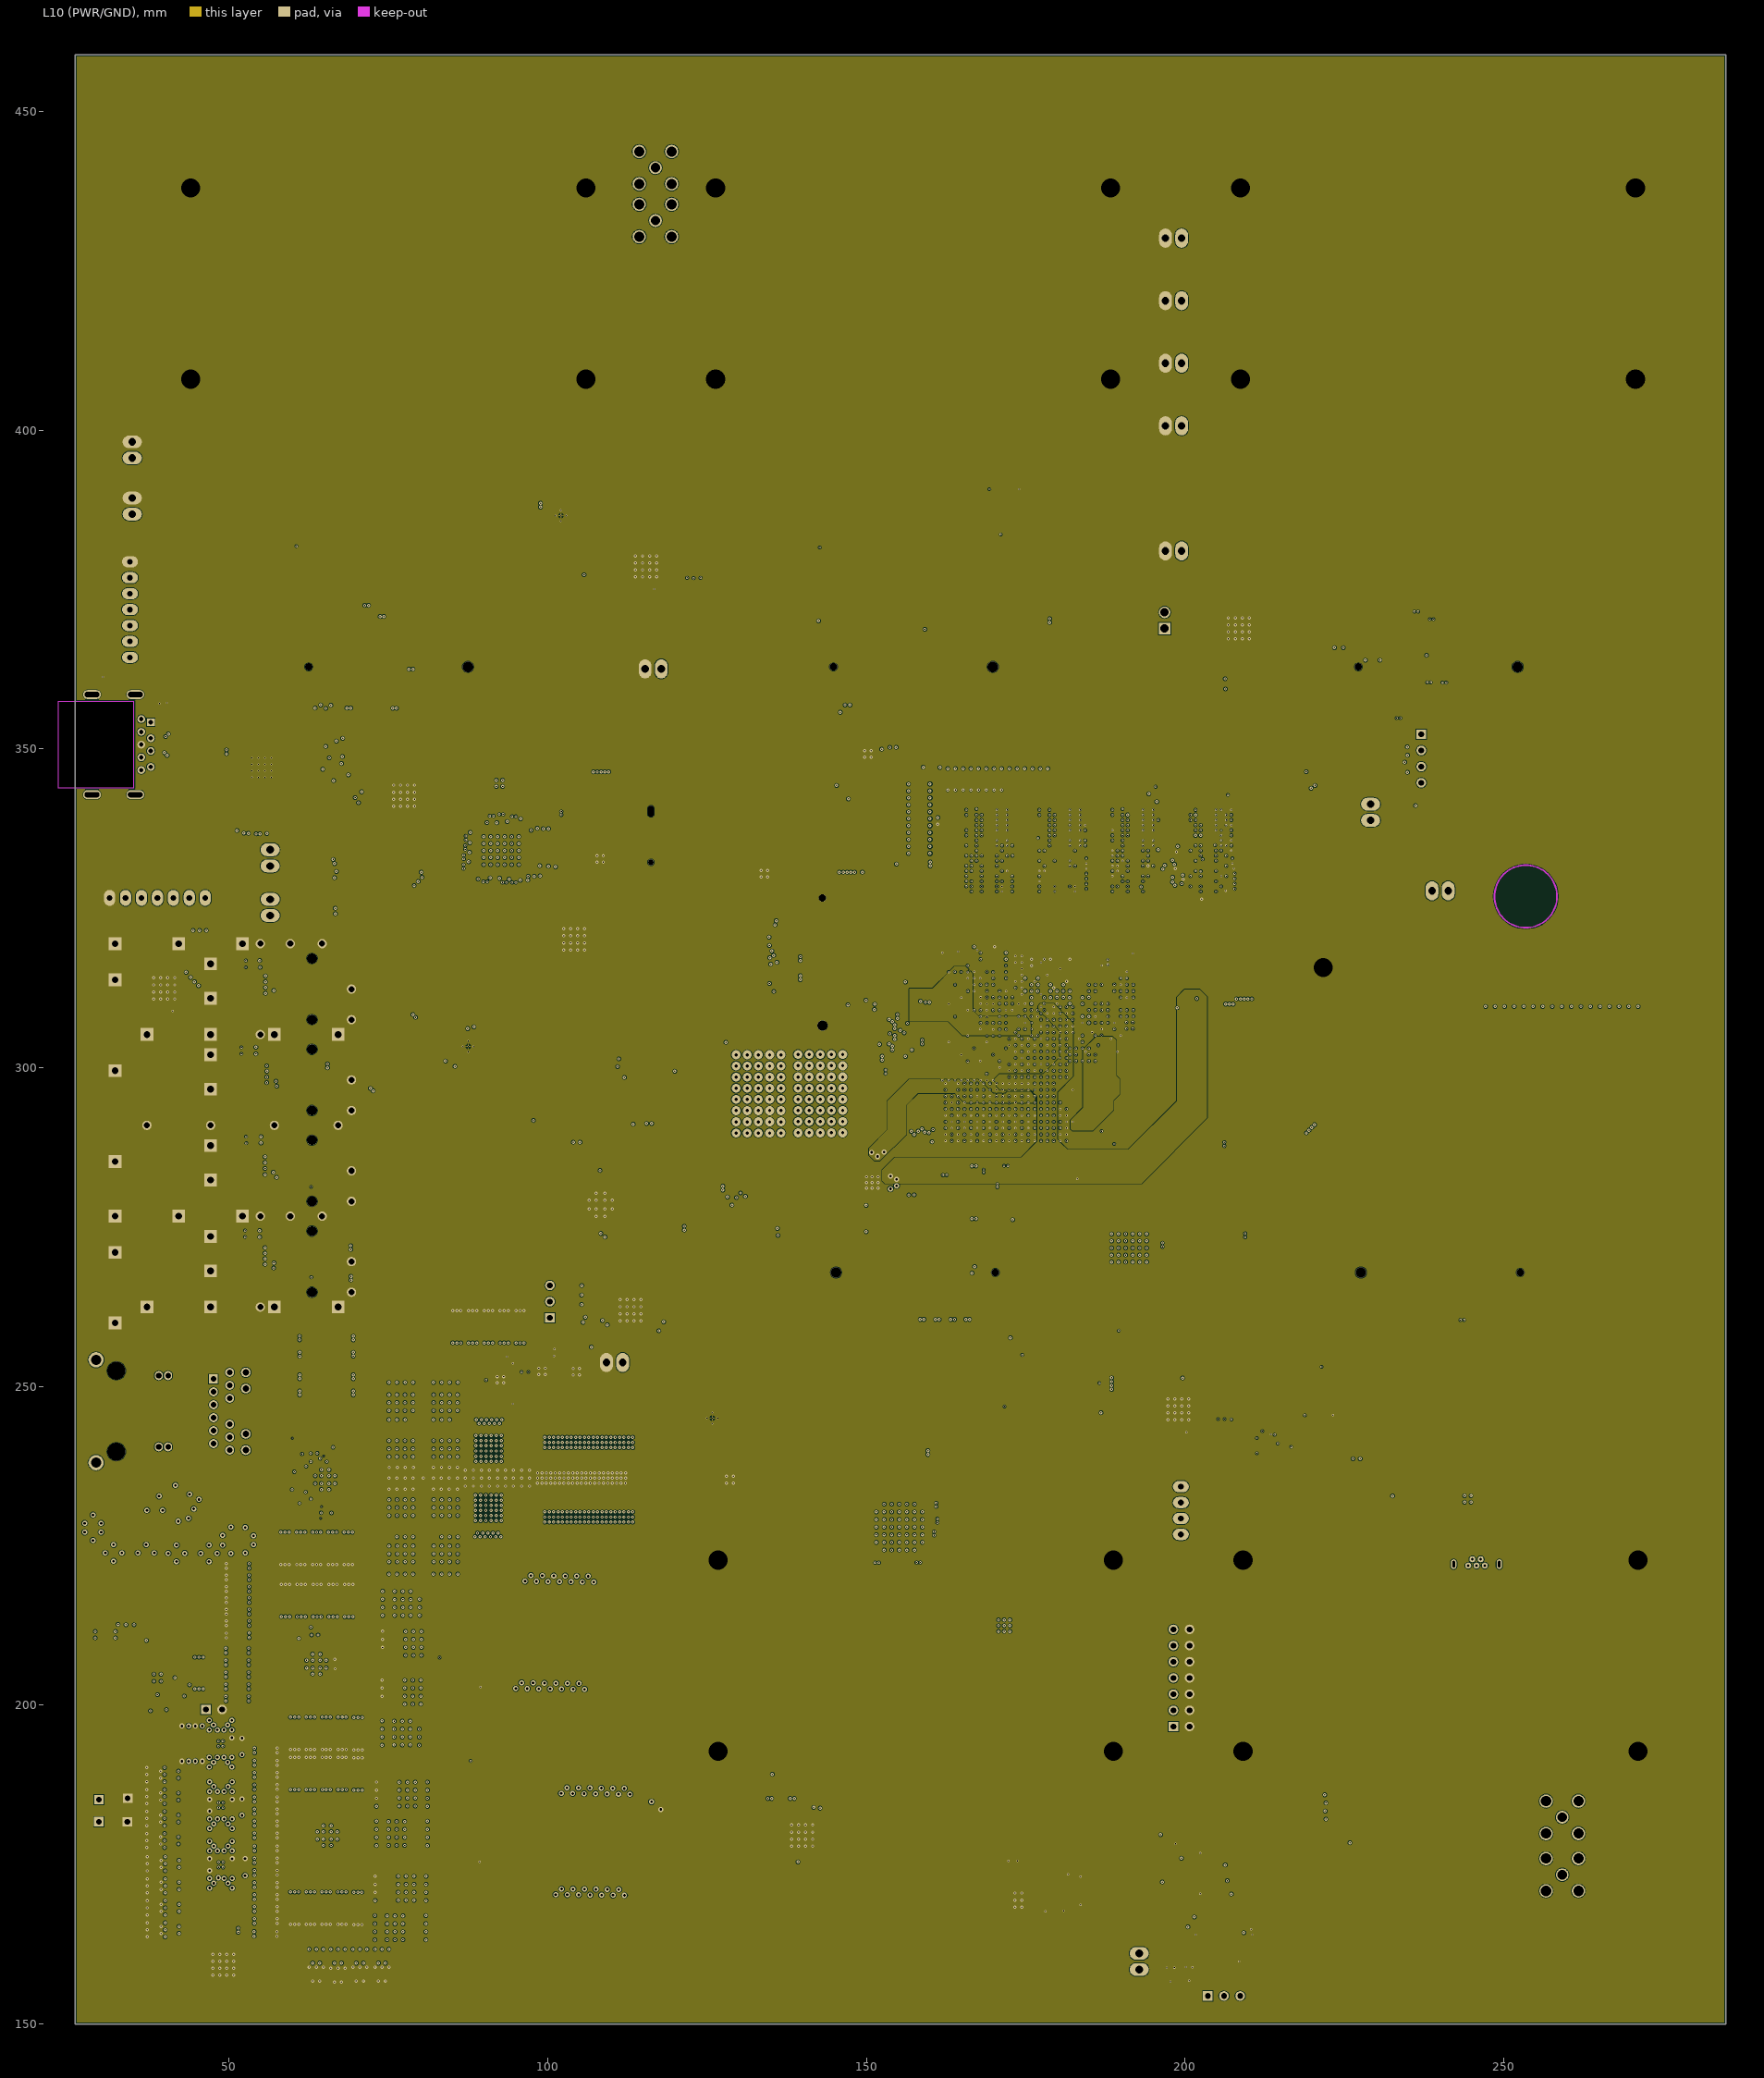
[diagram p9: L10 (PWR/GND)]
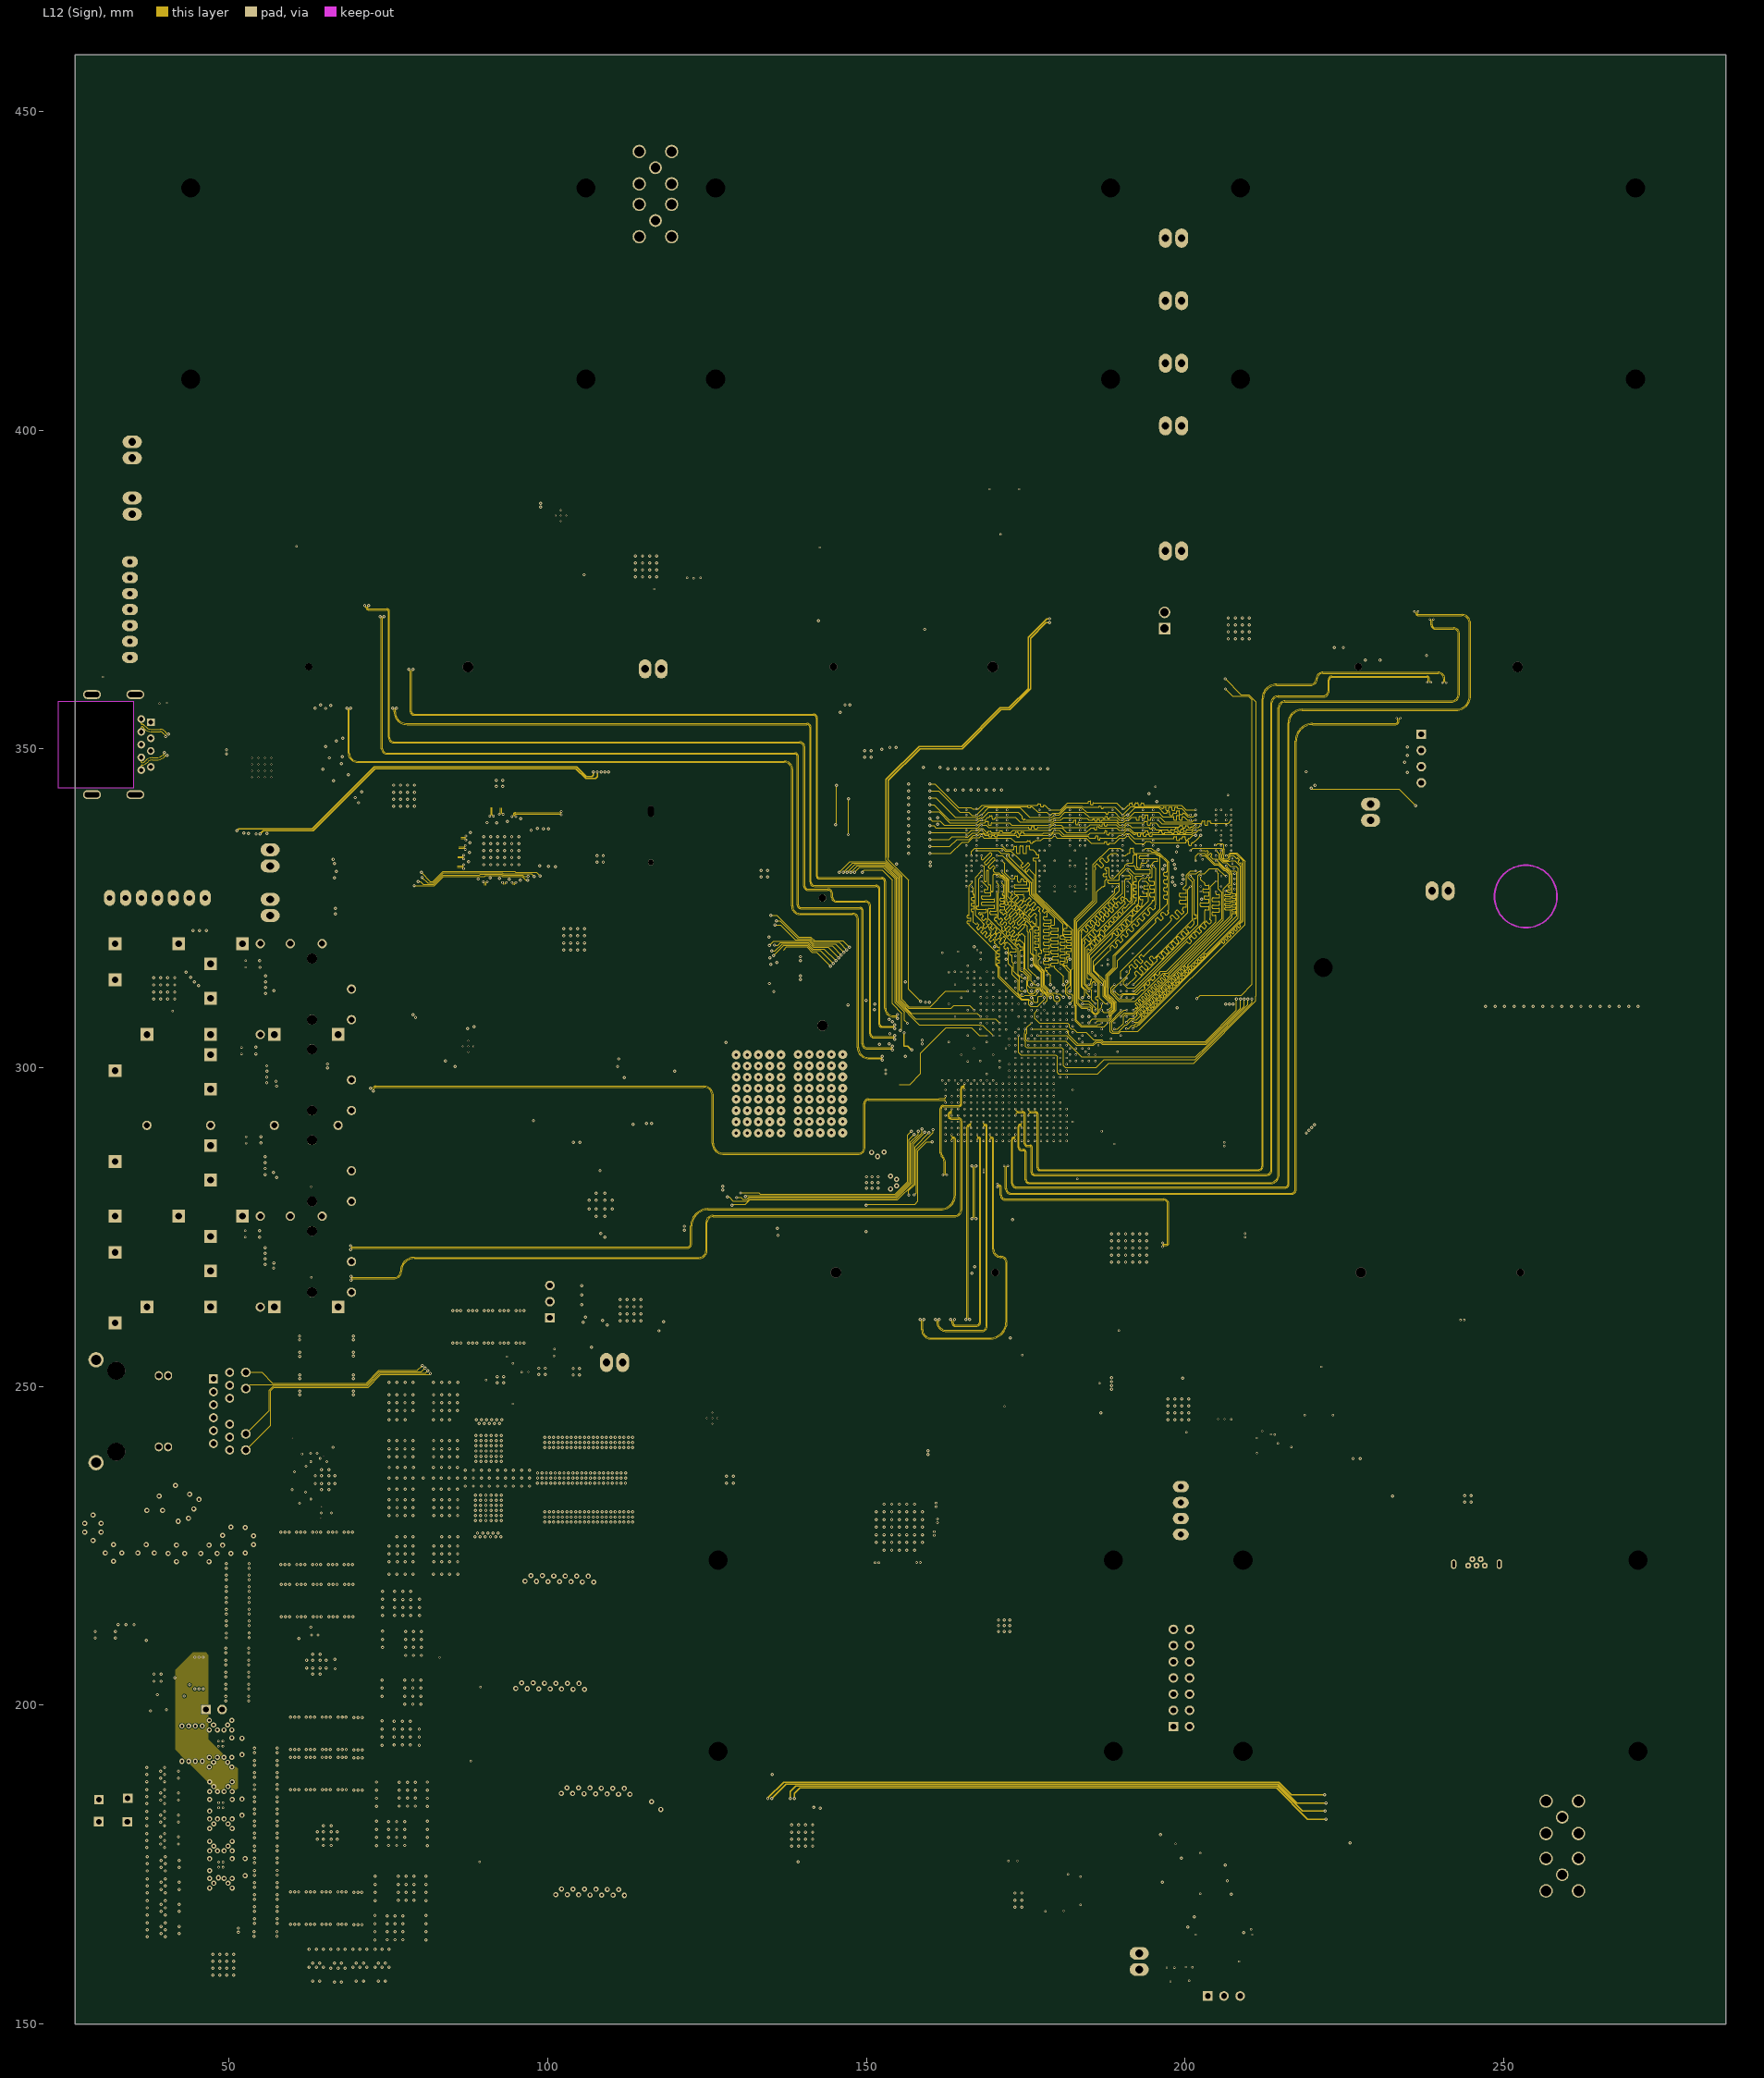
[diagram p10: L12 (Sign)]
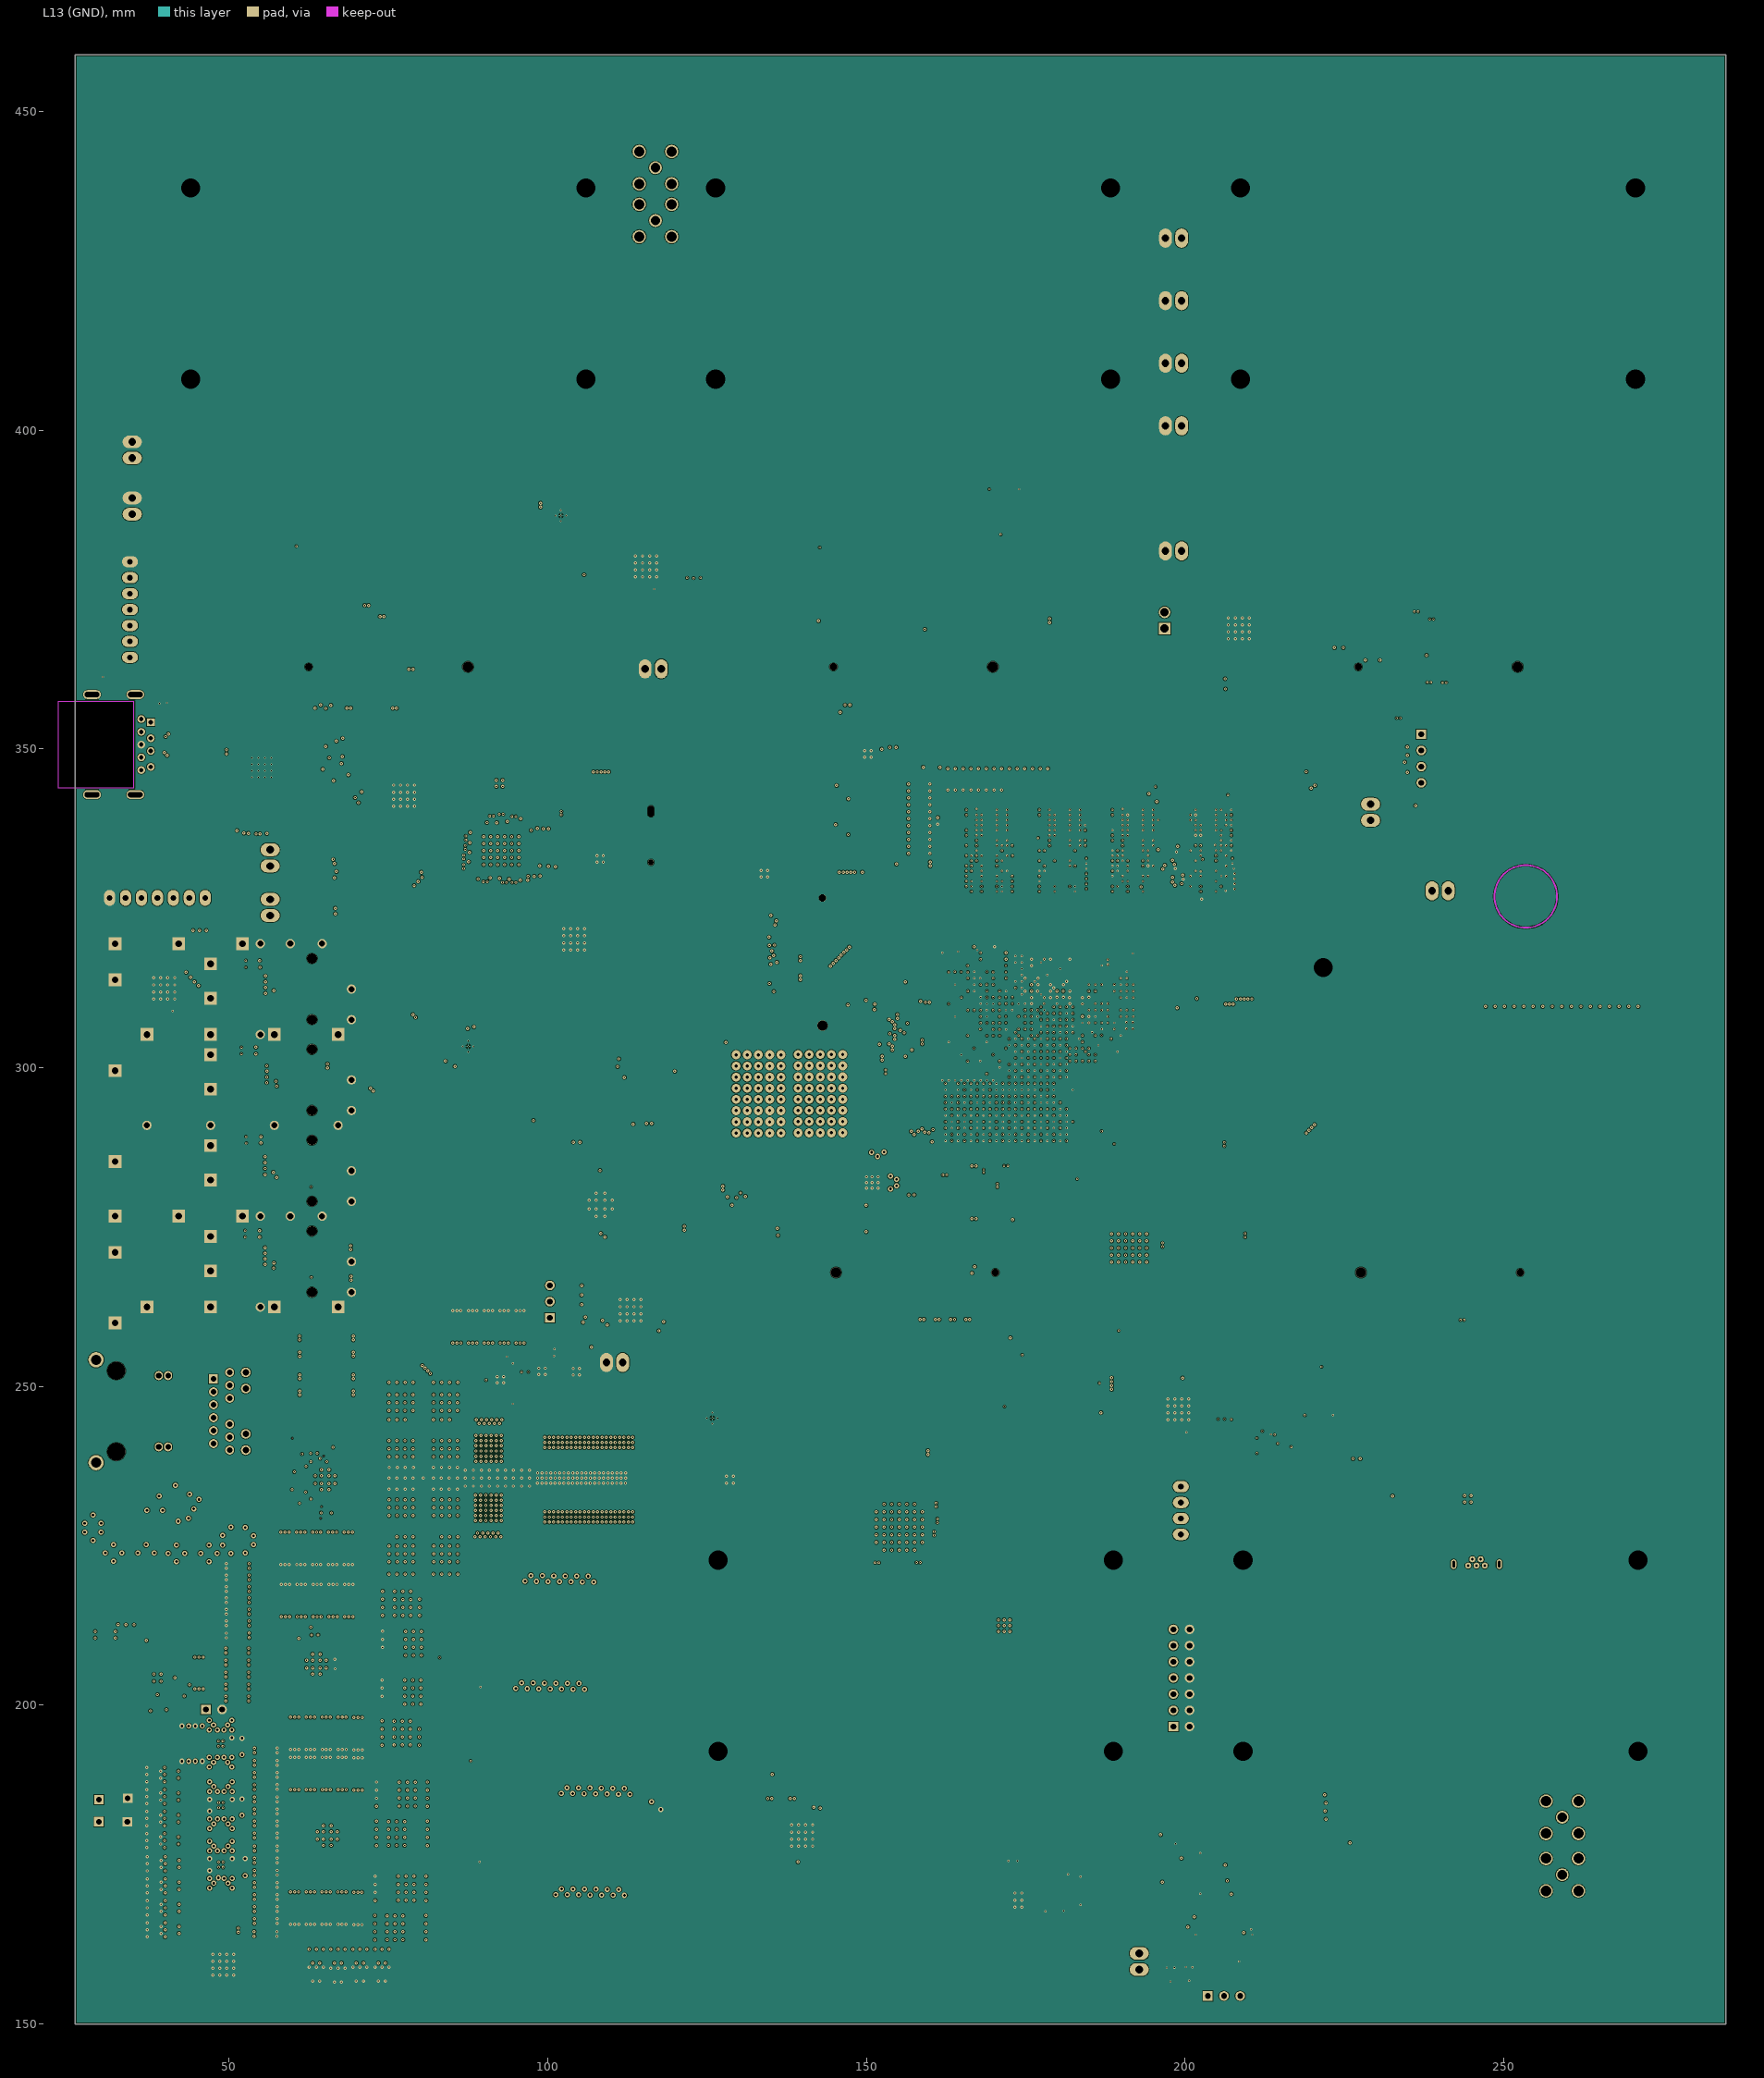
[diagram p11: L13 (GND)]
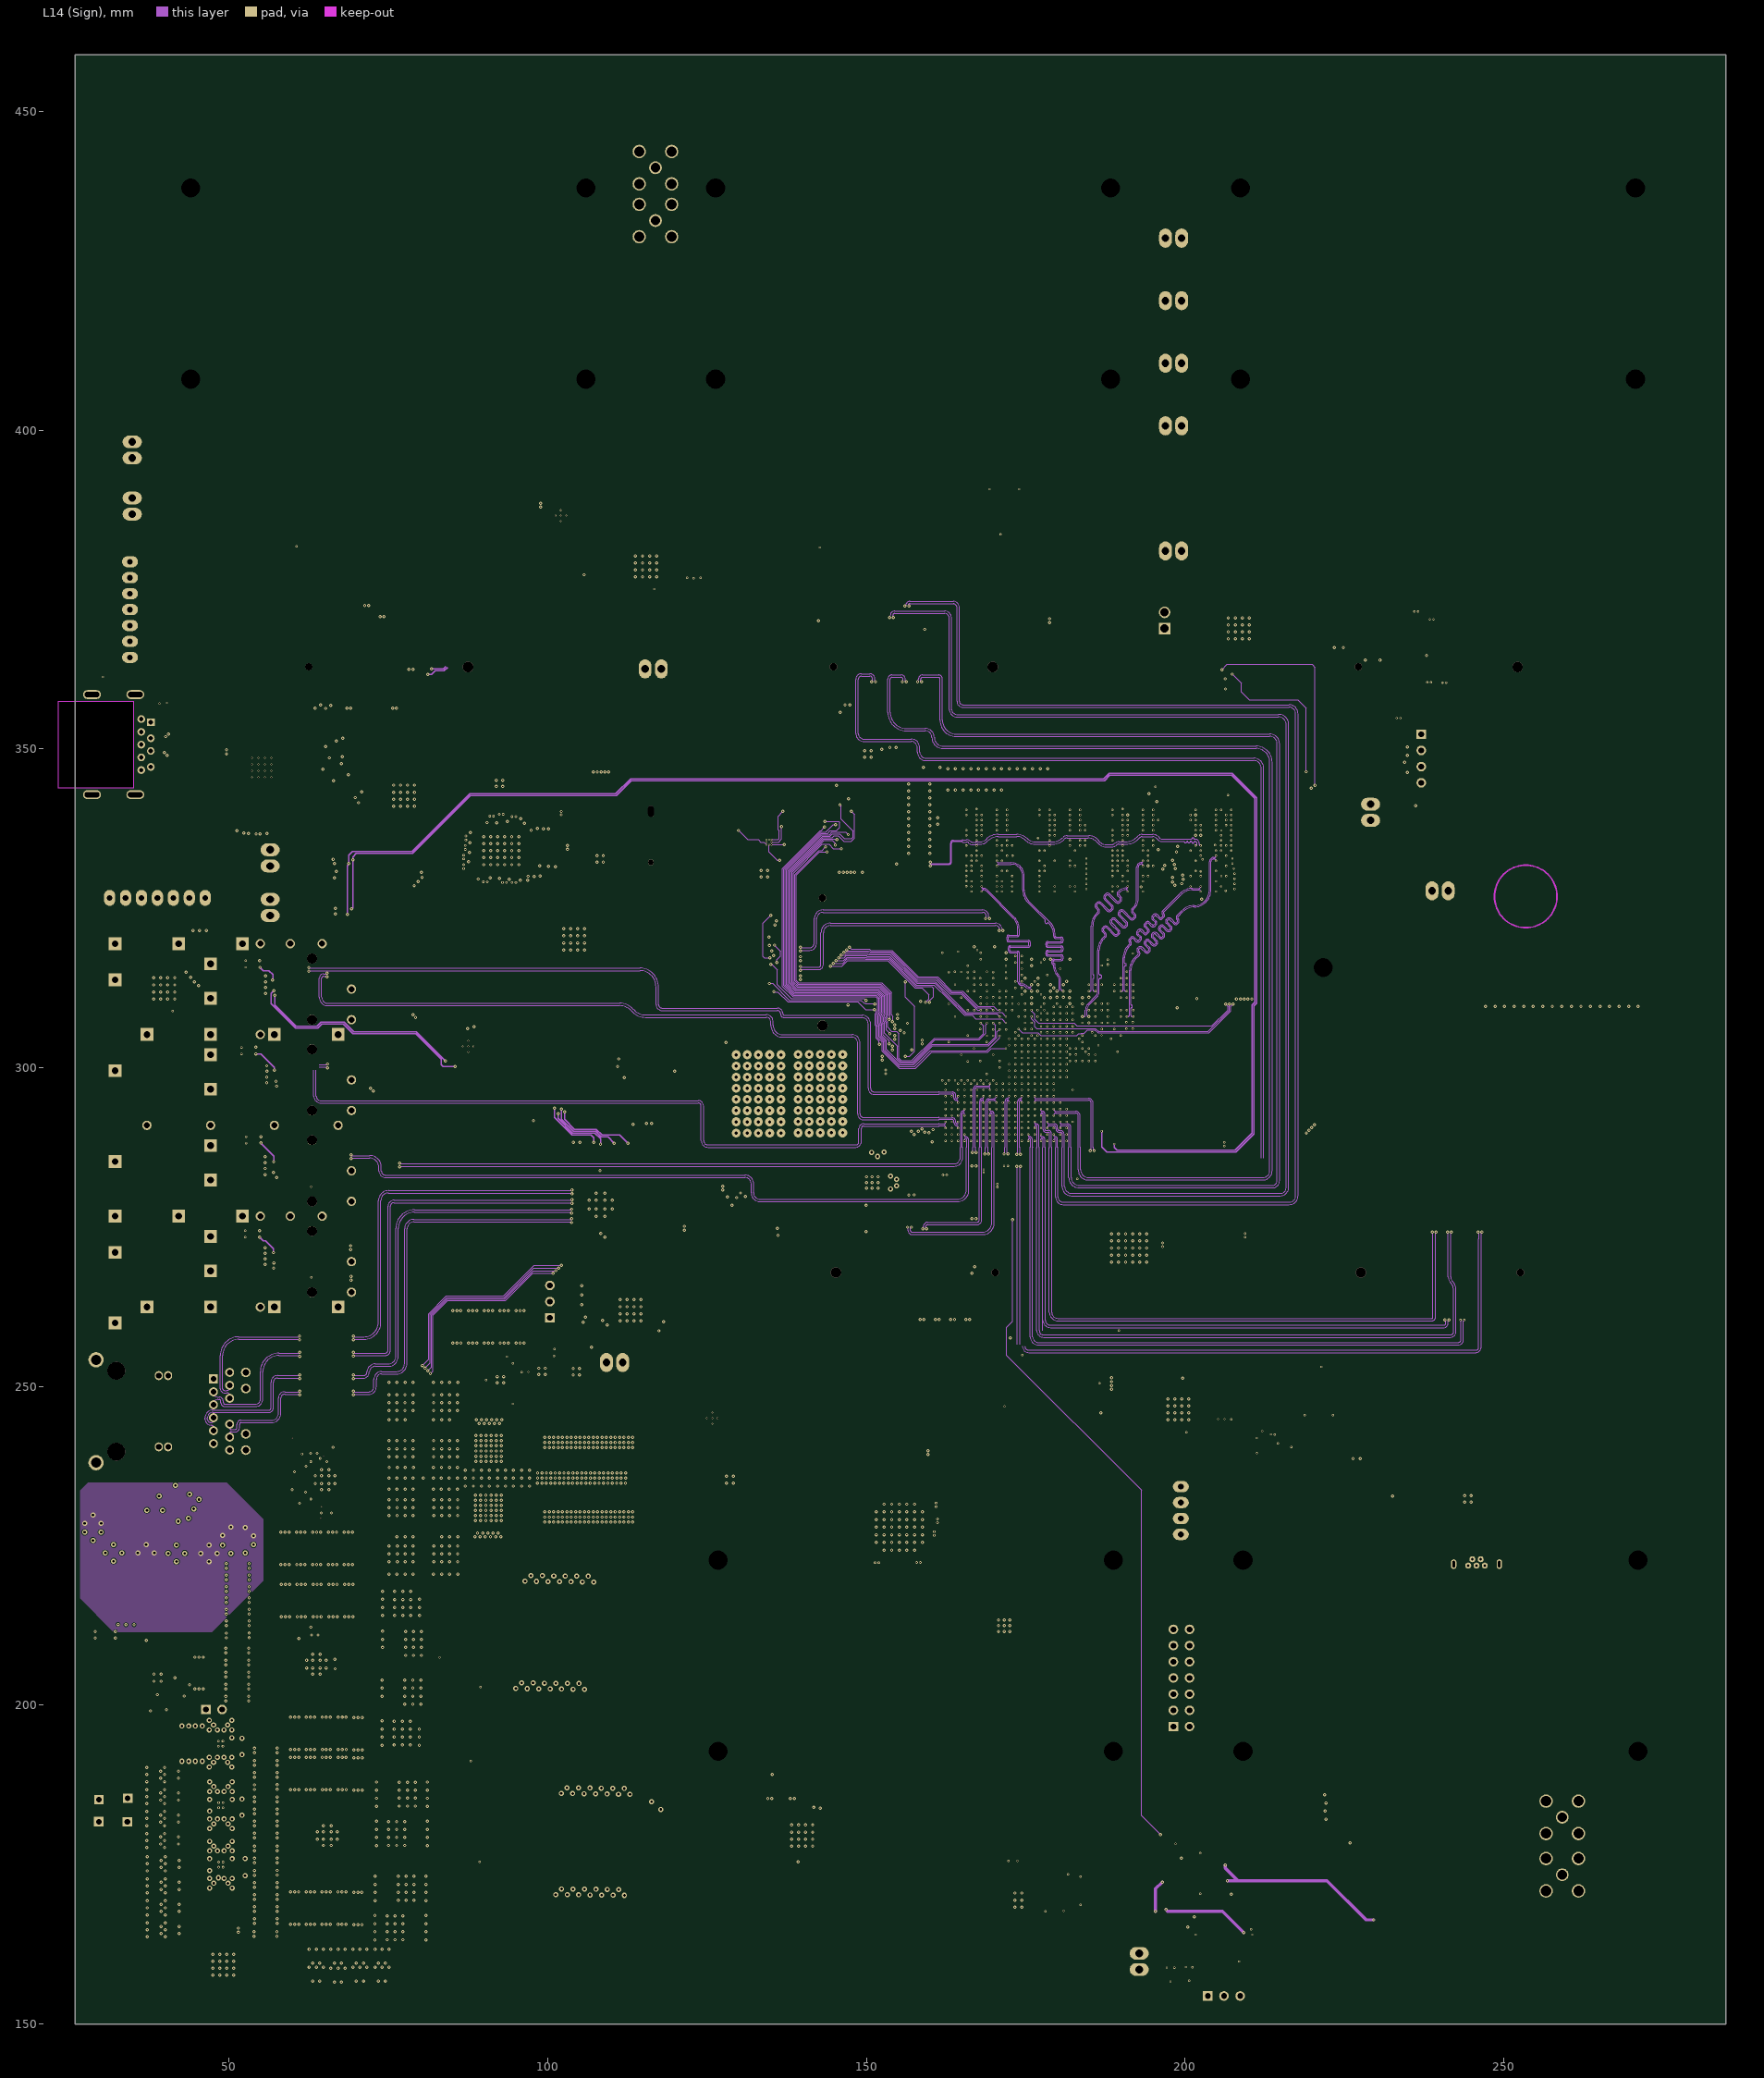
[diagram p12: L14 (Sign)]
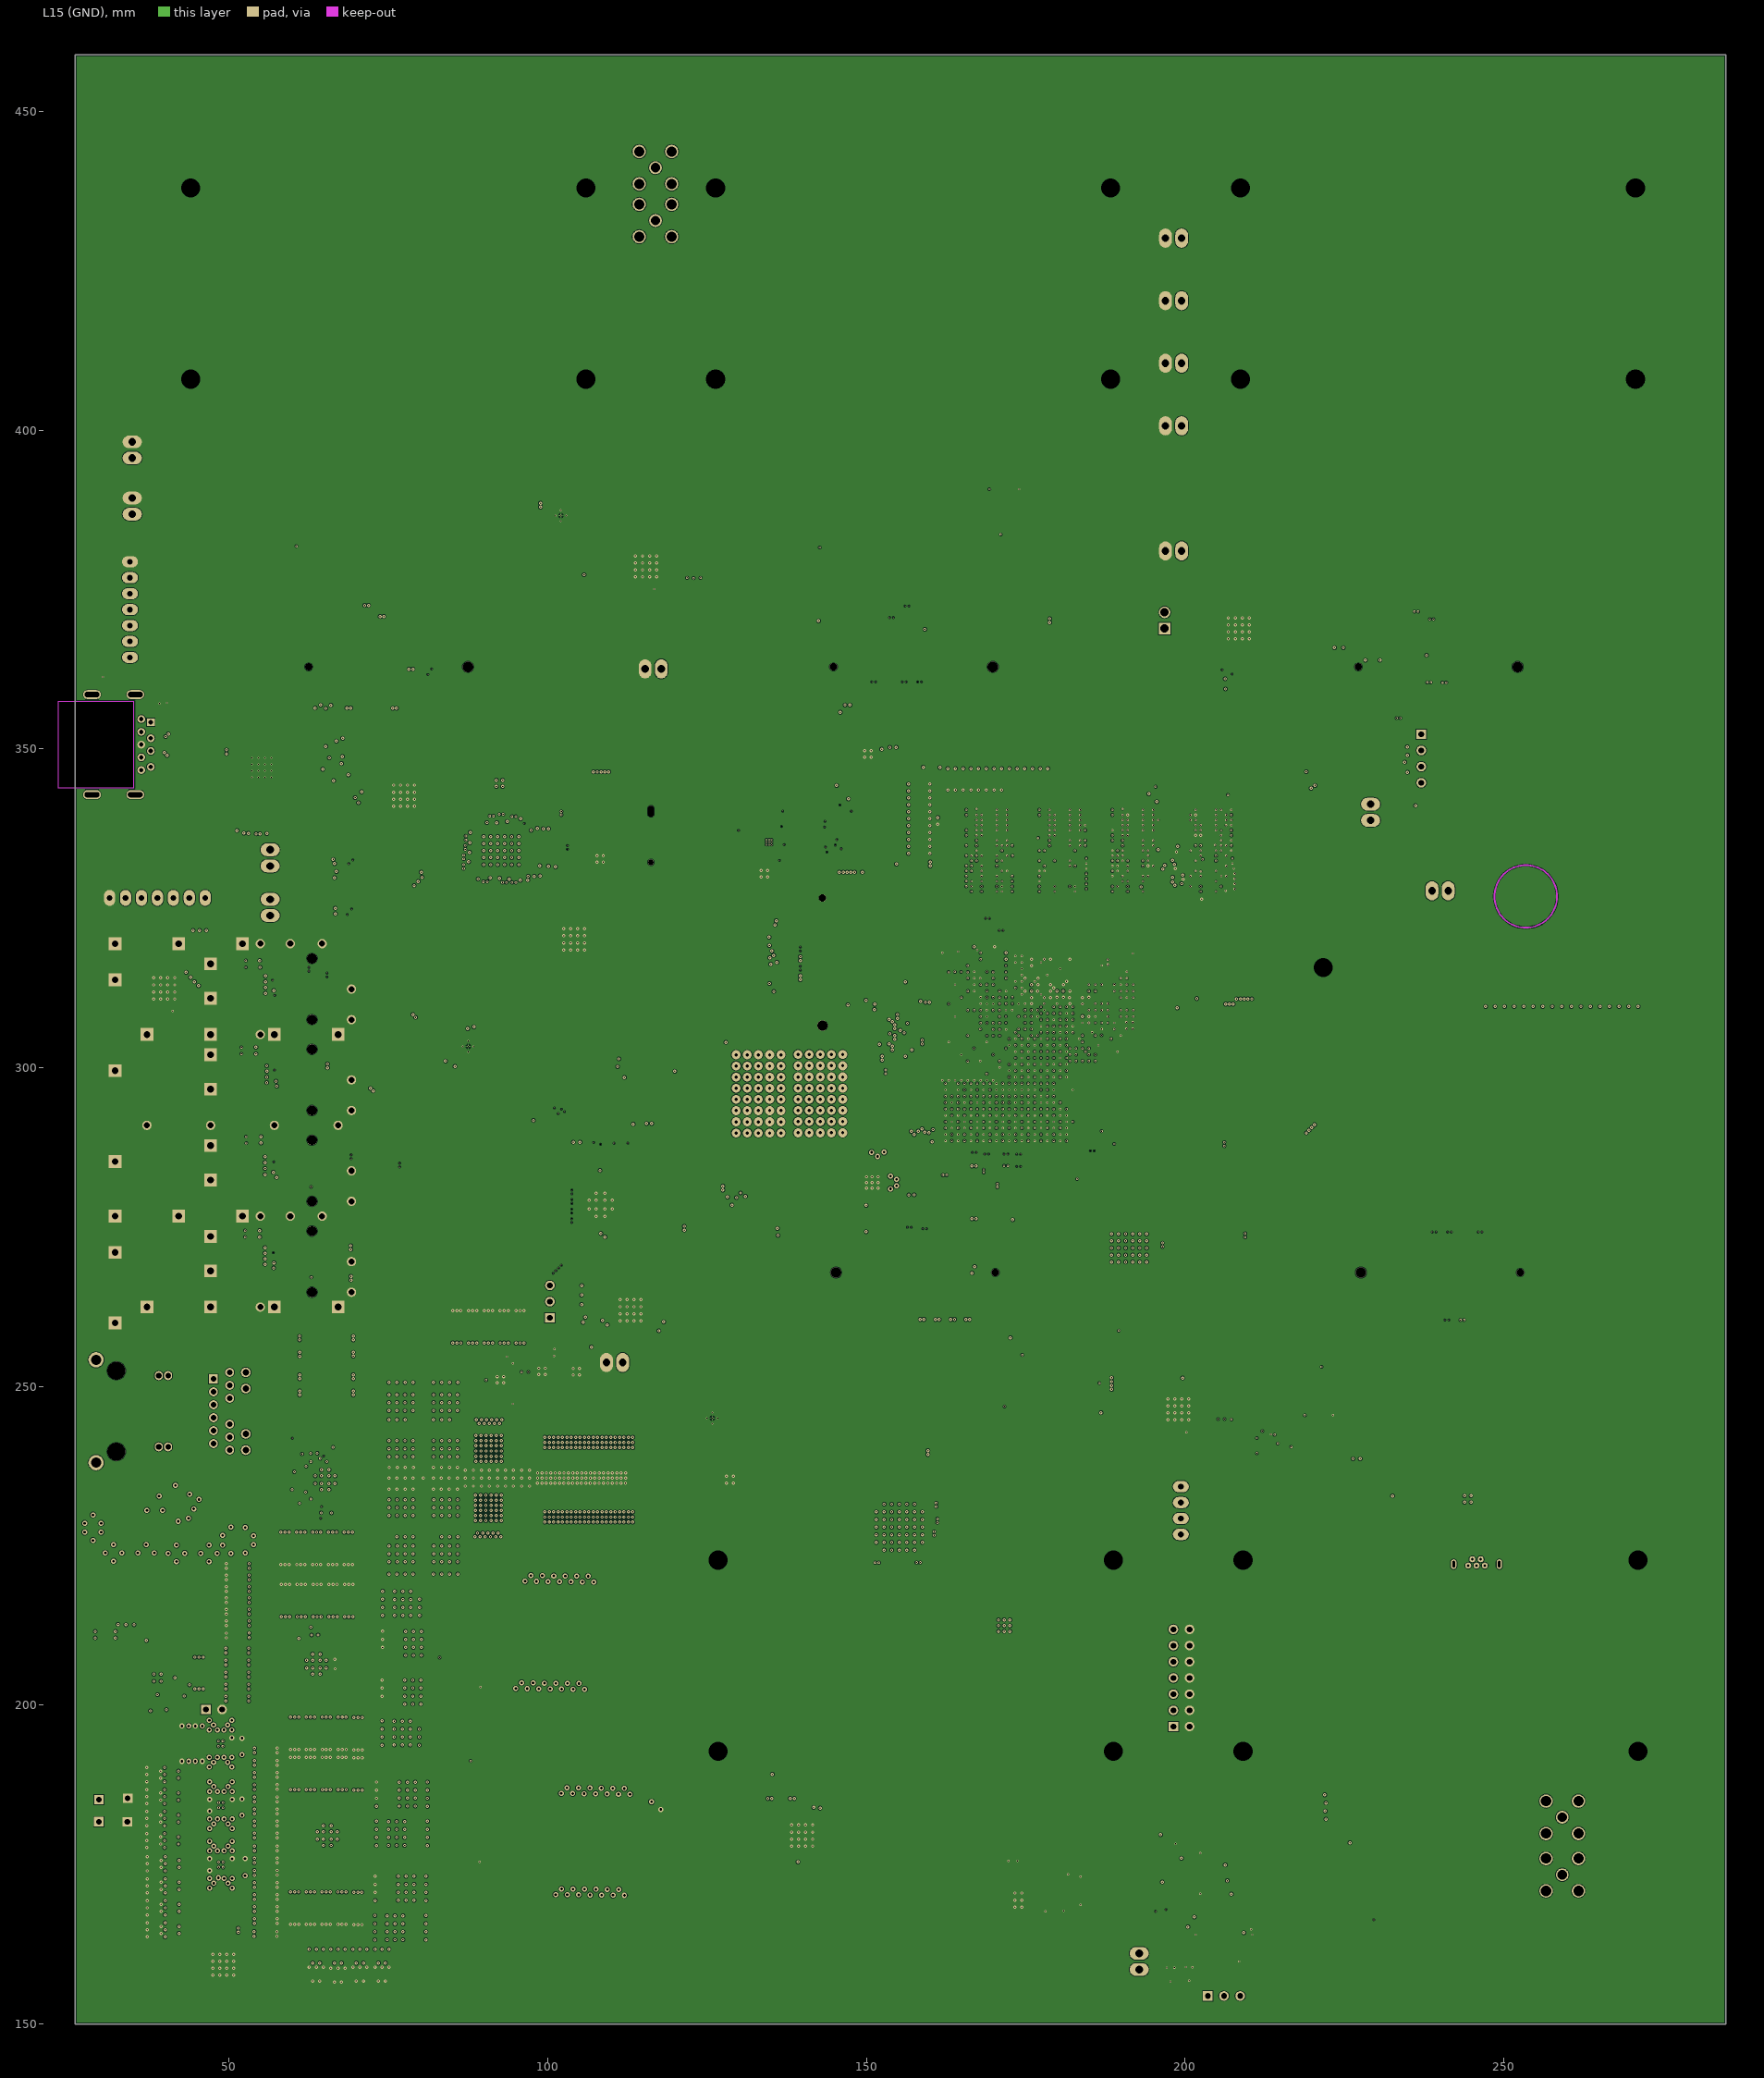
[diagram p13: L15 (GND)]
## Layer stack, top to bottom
Top Solder: solder mask 0.0254, SM-001, Dk 4
L1: signal copper 0.0635
Dielectric 1: prepreg 0.074, PP-013, Dk 4.3
L2 (GND): signal copper 0.015
Dielectric 2: core 0.114, Core-001, Dk 4.1
L3 (Sign): signal copper 0.015
Dielectric 3: prepreg 0.114, PP-013, Dk 4.3
L4 (GND): signal copper 0.015
Dielectric 4: core 0.114, Core-001, Dk 4.1
L5 (Sign): signal copper 0.015
Dielectric 5: prepreg 0.114, PP-013, Dk 4.3
L6 (PWR/GND): signal copper 0.03
Dielectric 6: core 0.203, Core-001, Dk 4.1
L7(PWR/GND): signal copper 0.03
Dielectric 7: prepreg 0.203, PP-013, Dk 4.3
L8 (Plane_GND): signal copper 0.03
Dielectric 8: core 0.203, Core-001, Dk 4.1
L9 (PWR/GND): signal copper 0.03
Dielectric 9: prepreg 0.203, PP-013, Dk 4.3
L10 (PWR/GND): signal copper 0.03
Dielectric 10: core 0.203, Core-001, Dk 4.1
L11 (PWR/GND): signal copper 0.03
Dielectric 11: prepreg 0.114, PP-013, Dk 4.3
L12 (Sign): signal copper 0.015
Dielectric 12: core 0.114, Core-001, Dk 4.1
L13 (GND): signal copper 0.015
Dielectric 13: prepreg 0.114, PP-013, Dk 4.3
L14 (Sign): signal copper 0.015
Dielectric 14: core 0.114, Core-001, Dk 4.1
L15 (GND): signal copper 0.015
Dielectric 15: prepreg 0.074, PP-013, Dk 4.3
L16: signal copper 0.0635
Bottom Solder: solder mask 0.0254, SM-001, Dk 4

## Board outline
25.87,150.012 284.823,150.012 284.823,458.876 25.87,458.876

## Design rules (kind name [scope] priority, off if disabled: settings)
BackDrilling [(InNetClass('RAM_Adress') Or InNetClass('RAM_Data_IO') Or InNetClass('RAM_Clock_Signal') Or InNetClass('RAM_DQS_Strobe'))  And IsVia] p1: maxstublength=0.381 usetopbackdrill=TRUE usebottombackdrill=TRUE holeoversize=0.025 holetolplus=0 holetolminus=0
BoardOutlineClearance [All] p1: gap=0.254 ignorepadtopadclearanceinfootprint=FALSE except(0: Arc-SplitContinuation Track-SplitContinuation SMDPad-SplitContinuation THPad-SplitContinuation Via-SplitContinuation Fill-SplitContinuation Poly-SplitContinuation Region-SplitContinuation Text-SplitContinuation)
Clearance RAM_Clearence [WithinRoom('RAM_CLK')] p1: gap=0.1 ignorepadtopadclearanceinfootprint=FALSE
Clearance "RAM_Addr to RAM_Addr" [InNetClass('Single_36_39_50_Adr') vs InNetClass('Single_36_39_50_Adr')] p2: gap=0.1 ignorepadtopadclearanceinfootprint=FALSE
Clearance "RAM_Addr to RAM_PWR" [InNetClass('Single_36_39_50_Adr') vs InNet('RAM_Vcc1V2')] p3: gap=0.1 ignorepadtopadclearanceinfootprint=FALSE
Clearance "RAM_Addr to other" [InNetClass('Single_36_39_50_Adr')] p4: gap=0.15 ignorepadtopadclearanceinfootprint=TRUE
Clearance [All] p5: gap=0.1 ignorepadtopadclearanceinfootprint=FALSE
DiffPairsRouting Diff100_Fpga [InDifferentialPairClass('Diff_100') and WithinRoom('FPGA_Room')] p1: maxlimit=0.254 minlimit=0.127 mostfreqgap=0.254 toplayer_mingap=0.2 toplayer_maxgap=0.2 toplayer_prefgap=0.2 toplayer_minwidth=0.063 toplayer_maxwidth=0.063 toplayer_prefwidth=0.063 midlayer2_maxgap=0.2 midlayer2_prefgap=0.127 midlayer2_minwidth=0.065 midlayer2_maxwidth=0.076 midlayer2_prefwidth=0.073 midlayer5_maxgap=0.2 midlayer5_prefgap=0.127 midlayer5_minwidth=0.065 midlayer5_maxwidth=0.076 midlayer5_prefwidth=0.073 midlayer8_mingap=0.2 midlayer8_maxgap=0.2 midlayer8_prefgap=0.2 midlayer8_minwidth=0.076 midlayer8_maxwidth=0.076 midlayer8_prefwidth=0.076 midlayer13_mingap=0.2 midlayer13_maxgap=0.2 midlayer13_prefgap=0.2 midlayer13_minwidth=0.076 midlayer13_maxwidth=0.076 midlayer13_prefwidth=0.076 bottomlayer_mingap=0.2 bottomlayer_maxgap=0.2 bottomlayer_prefgap=0.2 bottomlayer_minwidth=0.063 bottomlayer_maxwidth=0.063 bottomlayer_prefwidth=0.063 impedanceprofiledriven=TRUE impedanceprofileid={60D4C832-B92A-4812-B2AD-BB3BD3425739} maxuncoupledlength=12.7
DiffPairsRouting RAM_Diff86 [InDifferentialPairClass('Diff_76_to_90_Ram_CLK') and (WithinRoom('RAM_1')or WithinRoom('RAM_2')or WithinRoom('RAM_3')or WithinRoom('Ram_4')or WithinRoom('FPGA_Room'))and  OnTopLayer] p2: maxlimit=0.254 minlimit=0.148 mostfreqgap=0.254 toplayer_mingap=0.2 toplayer_maxgap=0.22 toplayer_prefgap=0.21 toplayer_minwidth=0.1 toplayer_maxwidth=0.12 toplayer_prefwidth=0.1 midlayer2_maxgap=0.15 midlayer2_prefgap=0.149 midlayer2_minwidth=0.1 midlayer2_maxwidth=0.12 midlayer2_prefwidth=0.1 midlayer5_maxgap=0.15 midlayer5_prefgap=0.149 midlayer5_minwidth=0.1 midlayer5_maxwidth=0.12 midlayer5_prefwidth=0.1 midlayer8_maxgap=0.15 midlayer8_prefgap=0.149 midlayer8_minwidth=0.1 midlayer8_maxwidth=0.12 midlayer8_prefwidth=0.1 midlayer13_maxgap=0.15 midlayer13_prefgap=0.149 midlayer13_minwidth=0.1 midlayer13_maxwidth=0.12 midlayer13_prefwidth=0.1 bottomlayer_mingap=0.2 bottomlayer_maxgap=0.22 bottomlayer_prefgap=0.21 bottomlayer_minwidth=0.1 bottomlayer_maxwidth=0.12 bottomlayer_prefwidth=0.1 impedanceprofiledriven=TRUE impedanceprofileid={1AFD27EA-460E-472B-BC44-4C5C59E93A8B} maxuncoupledlength=12.7 // breakout
DiffPairsRouting RAM_Diff90 [InDifferentialPairClass('Diff_76_to_90_Ram_CLK') and (WithinRoom('RAM_1')or WithinRoom('RAM_2')or WithinRoom('RAM_3')or WithinRoom('Ram_4')or WithinRoom('FPGA_Room')or WithinRoom('RAM_CLK'))and (not OnTopLayer)] p3: maxlimit=0.31 minlimit=0.127 mostfreqgap=0.254 toplayer_prefgap=0.31 toplayer_minwidth=0.018 toplayer_maxwidth=0.112 toplayer_prefwidth=0.1 midlayer2_maxgap=0.262 midlayer2_prefgap=0.262 midlayer2_minwidth=0.011 midlayer2_maxwidth=0.1 midlayer2_prefwidth=0.1 midlayer5_maxgap=0.262 midlayer5_prefgap=0.262 midlayer5_minwidth=0.011 midlayer5_maxwidth=0.1 midlayer5_prefwidth=0.1 midlayer8_maxgap=0.262 midlayer8_prefgap=0.262 midlayer8_minwidth=0.011 midlayer8_maxwidth=0.1 midlayer8_prefwidth=0.1 midlayer13_maxgap=0.262 midlayer13_prefgap=0.262 midlayer13_minwidth=0.011 midlayer13_maxwidth=0.1 midlayer13_prefwidth=0.1 bottomlayer_prefgap=0.31 bottomlayer_minwidth=0.018 bottomlayer_maxwidth=0.112 bottomlayer_prefwidth=0.1 impedanceprofiledriven=TRUE impedanceprofileid={1D82871A-FACB-482B-B08F-C93C2922060F} maxuncoupledlength=12.7
DiffPairsRouting Diff_76 [InDifferentialPairClass('Diff_76_to_90_Ram_CLK')] p4: maxlimit=0.254 minlimit=0.074 mostfreqgap=0.254 toplayer_mingap=0.115 toplayer_maxgap=0.154 toplayer_prefgap=0.115 toplayer_minwidth=0.1 toplayer_maxwidth=0.159 toplayer_prefwidth=0.1 midlayer2_maxgap=0.127 midlayer2_prefgap=0.074 midlayer2_minwidth=0.1 midlayer2_maxwidth=0.137 midlayer2_prefwidth=0.1 midlayer5_maxgap=0.127 midlayer5_prefgap=0.074 midlayer5_minwidth=0.1 midlayer5_maxwidth=0.137 midlayer5_prefwidth=0.1 midlayer8_maxgap=0.127 midlayer8_prefgap=0.074 midlayer8_minwidth=0.1 midlayer8_maxwidth=0.137 midlayer8_prefwidth=0.1 midlayer13_maxgap=0.127 midlayer13_prefgap=0.074 midlayer13_minwidth=0.1 midlayer13_maxwidth=0.137 midlayer13_prefwidth=0.1 bottomlayer_mingap=0.115 bottomlayer_maxgap=0.154 bottomlayer_prefgap=0.115 bottomlayer_minwidth=0.1 bottomlayer_maxwidth=0.159 bottomlayer_prefwidth=0.1 impedanceprofiledriven=TRUE impedanceprofileid={BD08387B-4D6E-4BB2-82BF-460CD7A1F64F} maxuncoupledlength=12.7
DiffPairsRouting RAM_DQS [InDifferentialPairClass('Diff_76_to_90_Ram_DQS')] p5: maxlimit=0.254 minlimit=0.127 mostfreqgap=0.254 toplayer_maxgap=0.127 toplayer_prefgap=0.127 toplayer_minwidth=0.123 toplayer_maxwidth=0.159 toplayer_prefwidth=0.124 midlayer1_maxgap=0.127 midlayer1_prefgap=0.127 midlayer1_minwidth=0.105 midlayer1_maxwidth=0.105 midlayer1_prefwidth=0.105 midlayer2_maxgap=0.127 midlayer2_prefgap=0.127 midlayer2_minwidth=0.105 midlayer2_maxwidth=0.137 midlayer2_prefwidth=0.105 midlayer3_mingap=0.254 midlayer3_minwidth=0.381 midlayer3_maxwidth=0.381 midlayer3_prefwidth=0.381 midlayer4_mingap=0.254 midlayer4_minwidth=0.381 midlayer4_maxwidth=0.381 midlayer4_prefwidth=0.381 midlayer5_maxgap=0.127 midlayer5_prefgap=0.127 midlayer5_minwidth=0.105 midlayer5_maxwidth=0.127 midlayer5_prefwidth=0.105 midlayer6_maxgap=0.127 midlayer6_prefgap=0.127 midlayer6_minwidth=0.105 midlayer6_maxwidth=0.105 midlayer6_prefwidth=0.105 midlayer7_maxgap=0.127 midlayer7_prefgap=0.127 midlayer7_minwidth=0.084 midlayer7_maxwidth=0.084 midlayer7_prefwidth=0.084 midlayer8_maxgap=0.127 midlayer8_prefgap=0.127 midlayer8_minwidth=0.105 midlayer8_maxwidth=0.137 midlayer8_prefwidth=0.105 midlayer9_mingap=0.254 midlayer9_minwidth=0.381 midlayer9_maxwidth=0.381 midlayer9_prefwidth=0.381 midlayer10_mingap=0.254 midlayer10_minwidth=0.381 midlayer10_maxwidth=0.381 midlayer10_prefwidth=0.381 midlayer11_mingap=0.254 midlayer11_minwidth=0.381 midlayer11_maxwidth=0.381 midlayer11_prefwidth=0.381 midlayer12_mingap=0.254 midlayer12_minwidth=0.381 midlayer12_maxwidth=0.381 midlayer12_prefwidth=0.381 midlayer13_maxgap=0.127 midlayer13_prefgap=0.127 midlayer13_minwidth=0.105 midlayer13_maxwidth=0.137 midlayer13_prefwidth=0.105 midlayer14_maxgap=0.127 midlayer14_prefgap=0.127 midlayer14_minwidth=0.084 midlayer14_maxwidth=0.102 midlayer14_prefwidth=0.084 bottomlayer_maxgap=0.127 bottomlayer_prefgap=0.127 bottomlayer_minwidth=0.123 bottomlayer_maxwidth=0.159 bottomlayer_prefwidth=0.124 maxuncoupledlength=12.7
DiffPairsRouting RAM_Diff_76_86_90_Addr [InDifferentialPairClass('Diff_76_to_90_Ram_CLK')] p6 off: maxlimit=0.254 minlimit=0.148 mostfreqgap=0.254 toplayer_mingap=0.2 toplayer_maxgap=0.22 toplayer_prefgap=0.21 toplayer_minwidth=0.1 toplayer_maxwidth=0.12 toplayer_prefwidth=0.1 midlayer2_maxgap=0.15 midlayer2_prefgap=0.149 midlayer2_minwidth=0.1 midlayer2_maxwidth=0.12 midlayer2_prefwidth=0.1 midlayer5_maxgap=0.15 midlayer5_prefgap=0.149 midlayer5_minwidth=0.1 midlayer5_maxwidth=0.12 midlayer5_prefwidth=0.1 midlayer8_maxgap=0.15 midlayer8_prefgap=0.149 midlayer8_minwidth=0.1 midlayer8_maxwidth=0.12 midlayer8_prefwidth=0.1 midlayer13_maxgap=0.15 midlayer13_prefgap=0.149 midlayer13_minwidth=0.1 midlayer13_maxwidth=0.12 midlayer13_prefwidth=0.1 bottomlayer_mingap=0.2 bottomlayer_maxgap=0.22 bottomlayer_prefgap=0.21 bottomlayer_minwidth=0.1 bottomlayer_maxwidth=0.12 bottomlayer_prefwidth=0.1 impedanceprofiledriven=TRUE impedanceprofileid={1AFD27EA-460E-472B-BC44-4C5C59E93A8B} maxuncoupledlength=0.2 // Differential pair 86 Ohm
DiffPairsRouting Diff100 [InDifferentialPairClass('Diff_100')] p7: maxlimit=0.504 minlimit=0.127 mostfreqgap=0.254 toplayer_prefgap=0.504 toplayer_minwidth=0.045 toplayer_maxwidth=0.1 toplayer_prefwidth=0.081 midlayer2_maxgap=0.127 midlayer2_prefgap=0.127 midlayer2_minwidth=0.072 midlayer2_maxwidth=0.073 midlayer2_prefwidth=0.073 midlayer5_maxgap=0.127 midlayer5_prefgap=0.127 midlayer5_minwidth=0.072 midlayer5_maxwidth=0.073 midlayer5_prefwidth=0.073 midlayer8_maxgap=0.3 midlayer8_prefgap=0.3 midlayer8_minwidth=0.072 midlayer8_maxwidth=0.08 midlayer8_prefwidth=0.08 midlayer13_maxgap=0.3 midlayer13_prefgap=0.3 midlayer13_minwidth=0.072 midlayer13_maxwidth=0.08 midlayer13_prefwidth=0.08 bottomlayer_prefgap=0.504 bottomlayer_minwidth=0.045 bottomlayer_maxwidth=0.1 bottomlayer_prefwidth=0.081 impedanceprofiledriven=TRUE impedanceprofileid={3149E961-6C2D-4C90-A41E-90A05D6C6F09} maxuncoupledlength=12.7 // Differential 100 Ohm
DiffPairsRouting "Diff 90" [InDifferentialPairClass('Diff_90')] p8: maxlimit=0.31 minlimit=0.127 mostfreqgap=0.254 toplayer_prefgap=0.31 toplayer_minwidth=0.018 toplayer_maxwidth=0.112 toplayer_prefwidth=0.1 midlayer2_maxgap=0.262 midlayer2_prefgap=0.262 midlayer2_minwidth=0.011 midlayer2_maxwidth=0.1 midlayer2_prefwidth=0.1 midlayer5_maxgap=0.262 midlayer5_prefgap=0.262 midlayer5_minwidth=0.011 midlayer5_maxwidth=0.1 midlayer5_prefwidth=0.1 midlayer8_maxgap=0.262 midlayer8_prefgap=0.262 midlayer8_minwidth=0.011 midlayer8_maxwidth=0.1 midlayer8_prefwidth=0.1 midlayer13_maxgap=0.262 midlayer13_prefgap=0.262 midlayer13_minwidth=0.011 midlayer13_maxwidth=0.1 midlayer13_prefwidth=0.1 bottomlayer_prefgap=0.31 bottomlayer_minwidth=0.018 bottomlayer_maxwidth=0.112 bottomlayer_prefwidth=0.1 impedanceprofiledriven=TRUE impedanceprofileid={1D82871A-FACB-482B-B08F-C93C2922060F} maxuncoupledlength=12.7 // Differential 90 Ohm
HoleSize DrillHole [All] p1: absolutevalues=TRUE maxlimit=5 minlimit=0.1 maxpercent=80.000 minpercent=20.000
HoleToHoleClearance [All] p1: gap=0.1 allowstackedmicrovias=TRUE
MatchedLengths MatchedLengths_DDR_CLOCKS_STROBES [InxSignalClass('ADDR_PP1') OR InxSignalClass('ADDR_PP2') OR InxSignalClass('ADDR_PP3') OR InxSignalClass('ADDR_PP4') OR InxSignalClass('DATA_BL0') OR InxSignalClass('DATA_BL1') OR InxSignalClass('DATA_BL2') OR InxSignalClass('DATA_BL3') OR InxSignalClass('DATA_BL4') OR InxSignalClass('DATA_BL5') OR InxSignalClass('DATA_BL6') OR InxSignalClass('DATA_BL7')] p1: tolerance=0.305 checknetsindiffpair=TRUE checkdiffpairvsdiffpair=FALSE checkxsignals=FALSE checkothers=FALSE
MatchedLengths MatchedLengths_DATA_BL7 [InxSignalClass('DATA_BL7')] p2: tolerance=1.473 checknetsindiffpair=FALSE checkdiffpairvsdiffpair=TRUE checkxsignals=TRUE checkothers=TRUE
MatchedLengths MatchedLengths_DATA_BL6 [InxSignalClass('DATA_BL6')] p3: tolerance=1.473 checknetsindiffpair=FALSE checkdiffpairvsdiffpair=TRUE checkxsignals=TRUE checkothers=TRUE
MatchedLengths MatchedLengths_DATA_BL5 [InxSignalClass('DATA_BL5')] p4: tolerance=1.473 checknetsindiffpair=FALSE checkdiffpairvsdiffpair=TRUE checkxsignals=TRUE checkothers=TRUE
MatchedLengths MatchedLengths_DATA_BL4 [InxSignalClass('DATA_BL4')] p5: tolerance=1.473 checknetsindiffpair=FALSE checkdiffpairvsdiffpair=TRUE checkxsignals=TRUE checkothers=TRUE
MatchedLengths MatchedLengths_DATA_BL3 [InxSignalClass('DATA_BL3')] p6: tolerance=1.473 checknetsindiffpair=FALSE checkdiffpairvsdiffpair=TRUE checkxsignals=TRUE checkothers=TRUE
MatchedLengths MatchedLengths_DATA_BL2 [InxSignalClass('DATA_BL2')] p7: tolerance=1.473 checknetsindiffpair=FALSE checkdiffpairvsdiffpair=TRUE checkxsignals=TRUE checkothers=TRUE
MatchedLengths MatchedLengths_DATA_BL1 [InxSignalClass('DATA_BL1')] p8: tolerance=1.473 checknetsindiffpair=FALSE checkdiffpairvsdiffpair=TRUE checkxsignals=TRUE checkothers=TRUE
MatchedLengths MatchedLengths_DATA_BL0 [InxSignalClass('DATA_BL0')] p9: tolerance=1.473 checknetsindiffpair=FALSE checkdiffpairvsdiffpair=TRUE checkxsignals=TRUE checkothers=TRUE
MatchedLengths MatchedLengths_ADDR_PP4 [InxSignalClass('ADDR_PP4')] p10: tolerance=1.194 checknetsindiffpair=FALSE checkdiffpairvsdiffpair=TRUE checkxsignals=TRUE checkothers=TRUE
MatchedLengths MatchedLengths_ADDR_PP3 [InxSignalClass('ADDR_PP3')] p11: tolerance=1.194 checknetsindiffpair=FALSE checkdiffpairvsdiffpair=TRUE checkxsignals=TRUE checkothers=TRUE
MatchedLengths MatchedLengths_ADDR_PP2 [InxSignalClass('ADDR_PP2')] p12: tolerance=1.194 checknetsindiffpair=FALSE checkdiffpairvsdiffpair=TRUE checkxsignals=TRUE checkothers=TRUE
MatchedLengths MatchedLengths_ADDR_PP1 [InxSignalClass('ADDR_PP1')] p13: tolerance=1.194 checknetsindiffpair=FALSE checkdiffpairvsdiffpair=TRUE checkxsignals=TRUE checkothers=TRUE
MatchedLengths SFP_Data [InNetClass('SFP_diff')] p14: tolerance=0.305 checknetsindiffpair=FALSE checkdiffpairvsdiffpair=TRUE checkxsignals=TRUE checkothers=TRUE
MatchedLengths DiferentialPairSkew [All] p15: tolerance=25.4 checknetsindiffpair=TRUE checkdiffpairvsdiffpair=FALSE checkxsignals=FALSE checkothers=FALSE
MatchedLengths RAM_Data_to_DQS [InNetClass('Lenght_DQS_to_Data')] p16 off: tolerance=25.4 checknetsindiffpair=FALSE checkdiffpairvsdiffpair=TRUE checkxsignals=TRUE checkothers=TRUE
MatchedLengths RAM_DQS_to_CK [InNetClass('Lenght_DQS_to_CK')] p17 off: tolerance=25.4 checknetsindiffpair=FALSE checkdiffpairvsdiffpair=TRUE checkxsignals=TRUE checkothers=TRUE
MatchedLengths MatchedLengths_DDR_DQS [InNetClass('RAM_DQS_Strobe')] p18 off: tolerance=0.305 checknetsindiffpair=TRUE checkdiffpairvsdiffpair=FALSE checkxsignals=FALSE checkothers=FALSE
MatchedLengths RAM_Addr_LenghMatch [InNetClass('RAM_Adress')] p19 off: tolerance=0.305 checknetsindiffpair=FALSE checkdiffpairvsdiffpair=TRUE checkxsignals=TRUE checkothers=TRUE
MatchedLengths Ram_Addr_Com_Ctrl_to_CK [InNetClass('Lenght_CK_to_Addr')] p20 off: tolerance=0.305 checknetsindiffpair=FALSE checkdiffpairvsdiffpair=TRUE checkxsignals=TRUE checkothers=TRUE
MatchedLengths RAM_MatchedLengths_DATA_IO [InNetClass('RAM_Data_IO')] p21 off: tolerance=0.305 checknetsindiffpair=FALSE checkdiffpairvsdiffpair=TRUE checkxsignals=TRUE checkothers=TRUE
MinimumAnnularRing DefRing [All] p1: minimumring=0.15
MinimumSolderMaskSliver [All] p1: minsoldermaskwidth=0.1
PlaneClearance [All] p1: clearance=0.2
PlaneConnect [All] p1: planeconnectstyle=Direct reliefexpansion=0.508 reliefentries=4 reliefconductorwidth=0.254 reliefairgap=0.254
PolygonConnect PowerPolygon [All] p1: connectstyle=Direct reliefconductorwidth=0.254 reliefentries=4 polygonreliefangle="90 Angle" airgapwidth=0.254
PolygonConnect PolygonConnect_1 [All] p2 off: connectstyle=Relief reliefconductorwidth=0.254 reliefentries=4 polygonreliefangle="90 Angle" airgapwidth=0.254
RoomDefinition RAM_3 [Not All] p1: confinementstyle=ConfineIn formatcopy=TRUE lockcomponents=FALSE outline 165.001,341.335 173.551,341.335 173.551,326.785 165.001,326.785
RoomDefinition Ram_4 [Not All] p2: confinementstyle=ConfineIn formatcopy=TRUE lockcomponents=FALSE outline 176.461,341.335 185.011,341.335 185.011,326.785 176.461,326.785
RoomDefinition RAM_2 [Not All] p3: confinementstyle=ConfineIn formatcopy=TRUE lockcomponents=FALSE outline 187.922,341.335 196.472,341.335 196.472,326.785 187.922,326.785
RoomDefinition RAM_1 [Not All] p4: confinementstyle=ConfineIn formatcopy=TRUE lockcomponents=FALSE outline 199.382,341.335 207.932,341.335 207.932,326.785 199.382,326.785
RoomDefinition FPGA_Room [Not All] p5: confinementstyle=ConfineIn formatcopy=TRUE lockcomponents=FALSE outline 161.397,318.539 192.397,318.539 192.397,287.539 161.397,287.539
RoomDefinition RAM_CLK [False] p6: confinementstyle=ConfineIn formatcopy=TRUE lockcomponents=FALSE outline 165.251,341.085 207.682,341.085 207.682,327.035 165.251,327.035
RoomDefinition RAMStubRoom_Addr [not All] p7: confinementstyle=ConfineIn formatcopy=TRUE lockcomponents=FALSE outline 158.259,345.172 185.298,345.172 185.298,330.46 158.259,330.46
RoutingTopology RoutingTopology_DDRAddressAndControls [InNetClass('DDR_AddressAndControls')] p1: topology=Daisy_Simple
RoutingTopology [All] p2: topology=Shortest
RoutingVias BackDrilled_1-5 [InDrillLayerPair('[BD] L5 (Sign) - L16')] p1: holewidth=0.2 width=0.5 viastyle="Through Hole" minholewidth=0.2 minwidth=0.5 maxholewidth=0.2 maxwidth=0.5
RoutingVias BackDrilled_1-14 [InDrillLayerPair('[BD] L14 (Sign) - L16')] p2: holewidth=0.2 width=0.5 viastyle="Through Hole" minholewidth=0.2 minwidth=0.5 maxholewidth=0.2 maxwidth=0.5
RoutingVias BackDrilled_1-12 [InDrillLayerPair('[BD] L12 (Sign) - L16')] p3: holewidth=0.2 width=0.5 viastyle="Through Hole" minholewidth=0.2 minwidth=0.5 maxholewidth=0.2 maxwidth=0.5
RoutingVias Vi14-16 [InDrillLayerPair('[UVIA] L14 (Sign) - L16')] p4: holewidth=0.127 width=0.35 viastyle="Through Hole" minholewidth=0.1 minwidth=0.2 maxholewidth=0.127 maxwidth=0.35
RoutingVias UVia1-2 [InDrillLayerPair('[UVIA] L1 - L2 (GND)')] p5: holewidth=0.127 width=0.35 viastyle="Through Hole" minholewidth=0.127 minwidth=0.35 maxholewidth=0.127 maxwidth=0.35
RoutingVias UVia1-3 [InDrillLayerPair('[UVIA] L1 - L3 (Sign)')] p6: holewidth=0.127 width=0.35 viastyle="Through Hole" minholewidth=0.1 minwidth=0.2 maxholewidth=0.127 maxwidth=0.35
RoutingVias UVia16-15 [InDrillLayerPair('[UVIA] L15 (GND) - L16')] p7: holewidth=0.127 width=0.35 viastyle="Through Hole" minholewidth=0.1 minwidth=0.2 maxholewidth=0.127 maxwidth=0.35
RoutingVias UVia14-15 [InDrillLayerPair('No Drill Pair')] p8: holewidth=0.127 width=0.35 viastyle="Through Hole" minholewidth=0.127 minwidth=0.35 maxholewidth=0.127 maxwidth=0.35
RoutingVias Diff_Pair_Via [InDifferentialPairClass('All Differential Pairs')] p9: holewidth=0.2 width=0.4 viastyle="Through Hole" minholewidth=0.127 minwidth=0.35 maxholewidth=0.3 maxwidth=0.5
RoutingVias [All] p10: holewidth=0.2 width=0.5 viastyle="Through Hole" minholewidth=0.1 minwidth=0.2 maxholewidth=2 maxwidth=2.25
ShortCircuit [InPadClass('All Pads') vs InPadClass('All Pads')] p1: allowed=FALSE
SilkToSilkClearance [All] p1: silktosilkclearance=0.1
SilkToSolderMaskClearance [IsPad] p1: minsilkscreentomaskgap=0 clearancetoexposedcopper=TRUE
SolderMaskExpansion [All] p1: expansion=0.102
Width Interrupts [InNetClass('Interrupt_Line')] p1: maxlimit=0.12 minlimit=0.12 preferedwidth=0.12
Width RAM_Address_50 [InNetClass('Single_36_39_50_Adr') and (WithinRoom('RAM_CLK')or WithinRoom('FPGA_Room'))] p2: maxlimit=0.254 minlimit=0.086 preferedwidth=0.254 toplayer_maxwidth=0.116 toplayer_prefwidth=0.086 midlayer2_minwidth=0.092 midlayer2_maxwidth=0.092 midlayer2_prefwidth=0.092 midlayer5_minwidth=0.092 midlayer5_maxwidth=0.092 midlayer5_prefwidth=0.092 midlayer8_minwidth=0.092 midlayer8_maxwidth=0.092 midlayer8_prefwidth=0.092 midlayer13_minwidth=0.092 midlayer13_maxwidth=0.092 midlayer13_prefwidth=0.092 bottomlayer_maxwidth=0.116 bottomlayer_prefwidth=0.086 impedanceprofiledriven=TRUE impedanceprofileid={C52096D4-C36E-4BDB-BB83-9E54FFDADA41} minimp=50.000000 maximp=50.000000 favimp=50.000000
Width RAM_StubAddress39 [InNetClass('Single_36_39_50_Adr') and WithinRoom('RAMStubRoom_Addr')] p3: maxlimit=0.254 minlimit=0.105 preferedwidth=0.254 toplayer_minwidth=0.155 toplayer_maxwidth=0.186 toplayer_prefwidth=0.155 midlayer1_minwidth=0.151 midlayer1_maxwidth=0.151 midlayer1_prefwidth=0.151 midlayer2_minwidth=0.151 midlayer2_maxwidth=0.151 midlayer2_prefwidth=0.151 midlayer5_minwidth=0.151 midlayer5_maxwidth=0.151 midlayer5_prefwidth=0.151 midlayer6_minwidth=0.151 midlayer6_maxwidth=0.151 midlayer6_prefwidth=0.151 midlayer7_maxwidth=0.115 midlayer7_prefwidth=0.105 midlayer8_minwidth=0.151 midlayer8_maxwidth=0.151 midlayer8_prefwidth=0.151 midlayer13_minwidth=0.151 midlayer13_maxwidth=0.151 midlayer13_prefwidth=0.151 midlayer14_maxwidth=0.115 midlayer14_prefwidth=0.105 bottomlayer_minwidth=0.155 bottomlayer_maxwidth=0.186 bottomlayer_prefwidth=0.155 impedanceprofiledriven=TRUE impedanceprofileid={9B370C13-2427-420A-A153-D73BE69366B2} minimp=50.000000 maximp=50.000000 favimp=50.000000
Width RAM_Addr36 [InNetClass('Single_36_39_50_Adr')and not (WithinRoom('RAM_CLK')or WithinRoom('FPGA_Room'))] p4: maxlimit=0.254 minlimit=0.122 preferedwidth=0.254 toplayer_minwidth=0.182 toplayer_maxwidth=0.212 toplayer_prefwidth=0.182 midlayer1_minwidth=0.173 midlayer1_maxwidth=0.173 midlayer1_prefwidth=0.173 midlayer2_minwidth=0.173 midlayer2_maxwidth=0.173 midlayer2_prefwidth=0.173 midlayer5_minwidth=0.173 midlayer5_maxwidth=0.173 midlayer5_prefwidth=0.173 midlayer6_minwidth=0.173 midlayer6_maxwidth=0.173 midlayer6_prefwidth=0.173 midlayer7_maxwidth=0.133 midlayer7_prefwidth=0.122 midlayer8_minwidth=0.173 midlayer8_maxwidth=0.173 midlayer8_prefwidth=0.173 midlayer13_minwidth=0.173 midlayer13_maxwidth=0.173 midlayer13_prefwidth=0.173 midlayer14_maxwidth=0.133 midlayer14_prefwidth=0.122 bottomlayer_minwidth=0.182 bottomlayer_maxwidth=0.212 bottomlayer_prefwidth=0.182 impedanceprofiledriven=TRUE impedanceprofileid={2EC469A3-C20B-4F07-A421-E0D2C58D58A8} minimp=50.000000 maximp=50.000000 favimp=50.000000
Width Single_Ram_CLK [InNetClass('RAM_Clock_Signal')] p5: maxlimit=0.152 minlimit=0.102 preferedwidth=0.127
Width Single_RAM_Com [InNetClass('RAM_Adress')] p6: maxlimit=0.254 minlimit=0.068 preferedwidth=0.254 toplayer_minwidth=0.116 toplayer_maxwidth=0.211 toplayer_prefwidth=0.184 midlayer1_minwidth=0.092 midlayer1_maxwidth=0.173 midlayer1_prefwidth=0.151 midlayer2_minwidth=0.092 midlayer2_maxwidth=0.173 midlayer2_prefwidth=0.151 midlayer3_minwidth=0.254 midlayer4_minwidth=0.254 midlayer5_minwidth=0.092 midlayer5_maxwidth=0.173 midlayer5_prefwidth=0.151 midlayer6_minwidth=0.092 midlayer6_maxwidth=0.173 midlayer6_prefwidth=0.151 midlayer7_maxwidth=0.132 midlayer7_prefwidth=0.114 midlayer8_minwidth=0.092 midlayer8_maxwidth=0.173 midlayer8_prefwidth=0.151 midlayer9_minwidth=0.092 midlayer9_prefwidth=0.151 midlayer10_minwidth=0.254 midlayer11_minwidth=0.254 midlayer12_minwidth=0.254 midlayer13_minwidth=0.092 midlayer13_maxwidth=0.173 midlayer13_prefwidth=0.151 midlayer14_maxwidth=0.132 midlayer14_prefwidth=0.114 bottomlayer_minwidth=0.116 bottomlayer_maxwidth=0.211 bottomlayer_prefwidth=0.184 minimp=50.000000 maximp=50.000000 favimp=50.000000 // Track's for Adress, comands and control
Width Single_RAM_Ten [InNet('DDR4_TEN')] p7: maxlimit=0.254 minlimit=0.068 preferedwidth=0.254 toplayer_minwidth=0.116 toplayer_maxwidth=0.211 toplayer_prefwidth=0.184 midlayer1_minwidth=0.092 midlayer1_maxwidth=0.173 midlayer1_prefwidth=0.151 midlayer2_minwidth=0.092 midlayer2_maxwidth=0.173 midlayer2_prefwidth=0.151 midlayer3_minwidth=0.254 midlayer4_minwidth=0.254 midlayer5_minwidth=0.092 midlayer5_maxwidth=0.173 midlayer5_prefwidth=0.151 midlayer6_minwidth=0.092 midlayer6_maxwidth=0.173 midlayer6_prefwidth=0.151 midlayer7_maxwidth=0.132 midlayer7_prefwidth=0.114 midlayer8_minwidth=0.092 midlayer8_maxwidth=0.173 midlayer8_prefwidth=0.151 midlayer9_minwidth=0.092 midlayer9_prefwidth=0.151 midlayer10_minwidth=0.254 midlayer11_minwidth=0.254 midlayer12_minwidth=0.254 midlayer13_minwidth=0.092 midlayer13_maxwidth=0.173 midlayer13_prefwidth=0.151 midlayer14_maxwidth=0.132 midlayer14_prefwidth=0.114 bottomlayer_minwidth=0.116 bottomlayer_maxwidth=0.211 bottomlayer_prefwidth=0.184 minimp=50.000000 maximp=50.000000 favimp=50.000000 // Track's for Adress, comands and control
Width SingleRam_Data [InNetClass('RAM_Data_IO')] p8: maxlimit=0.254 minlimit=0.068 preferedwidth=0.254 toplayer_minwidth=0.116 toplayer_maxwidth=0.211 toplayer_prefwidth=0.184 midlayer1_minwidth=0.092 midlayer1_maxwidth=0.173 midlayer1_prefwidth=0.151 midlayer2_minwidth=0.092 midlayer2_maxwidth=0.173 midlayer2_prefwidth=0.151 midlayer3_minwidth=0.254 midlayer4_minwidth=0.254 midlayer5_minwidth=0.092 midlayer5_maxwidth=0.173 midlayer5_prefwidth=0.151 midlayer6_minwidth=0.092 midlayer6_maxwidth=0.173 midlayer6_prefwidth=0.151 midlayer7_maxwidth=0.132 midlayer7_prefwidth=0.114 midlayer8_minwidth=0.092 midlayer8_maxwidth=0.173 midlayer8_prefwidth=0.151 midlayer9_minwidth=0.092 midlayer9_prefwidth=0.151 midlayer10_minwidth=0.254 midlayer11_minwidth=0.254 midlayer12_minwidth=0.254 midlayer13_minwidth=0.092 midlayer13_maxwidth=0.173 midlayer13_prefwidth=0.151 midlayer14_maxwidth=0.132 midlayer14_prefwidth=0.114 bottomlayer_minwidth=0.116 bottomlayer_maxwidth=0.211 bottomlayer_prefwidth=0.184 minimp=50.000000 maximp=50.000000 favimp=50.000000 // Track's for comand in r
Width Single45 [InNetClass('Single_45')] p9: maxlimit=0.198 minlimit=0.079 preferedwidth=0.198 toplayer_minwidth=0.113 toplayer_maxwidth=0.143 toplayer_prefwidth=0.113 midlayer1_minwidth=0.115 midlayer1_maxwidth=0.115 midlayer1_prefwidth=0.115 midlayer2_minwidth=0.115 midlayer2_maxwidth=0.115 midlayer2_prefwidth=0.115 midlayer3_minwidth=0.198 midlayer4_minwidth=0.198 midlayer5_minwidth=0.115 midlayer5_maxwidth=0.115 midlayer5_prefwidth=0.115 midlayer6_minwidth=0.115 midlayer6_maxwidth=0.115 midlayer6_prefwidth=0.115 midlayer7_maxwidth=0.087 midlayer7_prefwidth=0.079 midlayer8_minwidth=0.115 midlayer8_maxwidth=0.115 midlayer8_prefwidth=0.115 midlayer9_minwidth=0.133 midlayer9_maxwidth=0.133 midlayer9_prefwidth=0.133 midlayer10_minwidth=0.198 midlayer11_minwidth=0.198 midlayer12_minwidth=0.133 midlayer12_maxwidth=0.133 midlayer12_prefwidth=0.133 midlayer13_minwidth=0.115 midlayer13_maxwidth=0.115 midlayer13_prefwidth=0.115 midlayer14_maxwidth=0.087 midlayer14_prefwidth=0.079 bottomlayer_minwidth=0.113 bottomlayer_maxwidth=0.143 bottomlayer_prefwidth=0.113 impedanceprofiledriven=TRUE impedanceprofileid={F22BED46-E16F-4103-815A-6A081543B36A} minimp=50.000000 maximp=50.000000 favimp=50.000000 // Single line impedance 45 Ohm
Width "Single 50" [InNetClass('Single_50')] p10: maxlimit=0.254 minlimit=0.086 preferedwidth=0.254 toplayer_maxwidth=0.116 toplayer_prefwidth=0.086 midlayer2_minwidth=0.092 midlayer2_maxwidth=0.092 midlayer2_prefwidth=0.092 midlayer5_minwidth=0.092 midlayer5_maxwidth=0.092 midlayer5_prefwidth=0.092 midlayer8_minwidth=0.092 midlayer8_maxwidth=0.092 midlayer8_prefwidth=0.092 midlayer13_minwidth=0.092 midlayer13_maxwidth=0.092 midlayer13_prefwidth=0.092 bottomlayer_maxwidth=0.116 bottomlayer_prefwidth=0.086 impedanceprofiledriven=TRUE impedanceprofileid={C52096D4-C36E-4BDB-BB83-9E54FFDADA41} minimp=50.000000 maximp=50.000000 favimp=50.000000 checkconnectedcopper=TRUE // Single impedance line 50 Ohm
Width [InNetClass('SFP_diff')] p11 off: maxlimit=0.254 minlimit=0.254 preferedwidth=0.254
Width Power1A [InNetClass('Power_Line_1A')] p12: maxlimit=2 minlimit=0.2 preferedwidth=0.5
Width Power2A [InNetClass('Power_Line_2A')] p13: maxlimit=2 minlimit=0.2 preferedwidth=0.5
Width Power10A [InNetClass('Power_Line_10A')] p14: maxlimit=2 minlimit=0.2 preferedwidth=0.5
Width Power20A [InNetClass('Power_Line_20A')] p15: maxlimit=2 minlimit=0.2 preferedwidth=0.5
Width Power40A [InNetClass('Power_Line_40A')] p16: maxlimit=2 minlimit=0.2 preferedwidth=0.5
Width Power1A_5 [InNetClass('Ground')] p17: maxlimit=1 minlimit=0.2 preferedwidth=0.5
Width Other [All] p18: maxlimit=2 minlimit=0.12 preferedwidth=0.2
20 further rules are at their usual default settings.

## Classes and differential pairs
net class Ground: B503_Ground
net class USB2_Lines: MIO_52 MIO_53 MIO_54 MIO_55 MIO_56 MIO_57 MIO_58 MIO_59 MIO_60 MIO_61 MIO_62 MIO_63 USB2_CLK USB2_D0 USB2_D1 USB2_D2 USB2_D3 USB2_D4 USB2_D5 USB2_D6 USB2_D7 USB2_DIR USB2_NXT USB2_STP
net class uSD_Lines: MIO_13 MIO_14 MIO_15 MIO_16 MIO_17 MIO_18 MIO_19 MIO_20 MIO_21 MIO_22 MIO_24 uSD_CD uSD_CLK uSD_CMD uSD_D0 uSD_D1 uSD_D2 uSD_D3 uSD_D4 uSD_D5 uSD_D6 uSD_D7
net class eMMC_Lines: eMMC_clk eMMC_cmd eMMC_data0 eMMC_data1 eMMC_data2 eMMC_data3 eMMC_data4 eMMC_data5 eMMC_data6 eMMC_data7 eMMC_rst MIO_39 MIO_40 MIO_41 MIO_42 MIO_43 MIO_46 MIO_47 MIO_48 MIO_49 MIO_50 MIO_51
net class WR_CLK2: WR_LMK_CLK_RC_HF2_N WR_LMK_CLK_RC_HF2_P
net class WR_CLK1: WR_LMK_CLK_RC_HF1_N WR_LMK_CLK_RC_HF1_P
net class LTC_6952_2_MATCH_REF: LTC6952_1_REF_MATCH_N LTC6952_1_REF_MATCH_P
net class Interrupt_Line: Interrupt0 Interrupt1 Interrupt2 Interrupt3 Interrupt4 Interrupt5 Interrupt6 Interrupt7 Interrupt8 Interrupt9 Interrupt10 Interrupt11 Interrupt12 Interrupt13 Interrupt14 Interrupt15 Interrupt16 Interrupt17 Interrupt18 Interrupt19 Interrupt20 Interrupt21 Interrupt22 Interrupt23 Interrupt24 Interrupt25 Interrupt26 Interrupt27 Interrupt28 Interrupt29 Interrupt30 Interrupt31 Interrupt32 Interrupt33 Interrupt34 Interrupt35 Interrupt36 Interrupt37 Interrupt38 Interrupt39 Interrupt40 Interrupt41 Interrupt42 Interrupt43 Interrupt44 Interrupt45 Interrupt46 Interrupt47 Interrupt48 Interrupt49 Interrupt50 Interrupt51 Interrupt52 Interrupt53 Interrupt54 Interrupt55 Interrupt56 Interrupt57 Interrupt58 Interrupt59 Interrupt60 Interrupt61 Interrupt62 Interrupt63 Interrupt64 Interrupt65 Interrupt66 Interrupt67 Interrupt68 Interrupt69 Interrupt70 Interrupt71 Interrupt72 Interrupt73 Interrupt74 Interrupt75 Interrupt76 Interrupt77 Interrupt78 Interrupt79
component class I2C_Expander_02: C311_I2C_Expander_02 U35_I2C_Expander_02
component class I2C_Expander_01: C311_I2C_Expander_01 U35_I2C_Expander_01
component class I2C_Expander_00: C311_I2C_Expander_00 U35_I2C_Expander_00
net class Bank225_MGTREFx: Bank225_MGTREF0_N Bank225_MGTREF0_P Bank225_MGTREF1_N Bank225_MGTREF1_P
net class Bank224_MGTREFx: Bank224_MGTREF0_N Bank224_MGTREF0_P Bank224_MGTREF1_N Bank224_MGTREF1_P
net class Bank223_MGTREFx: Bank223_MGTREF0_N Bank223_MGTREF0_P Bank223_MGTREF1_N Bank223_MGTREF1_P
net class WR_CLK_C_LMK: CLK1_Out3.N CLK1_Out3.P
net class LTC_6952_1_REF: LTC6952_0_REF_N LTC6952_0_REF_P
component class "Xilinx FPGA": R75 R124 R363 R364 R365 R395 R398 R506 R507 R514 R900 R901 R902 R903 R904 R905 R906 R907 R908 R909 R910 R918 R919 TP43 TP44 TP45 TP46 TP47 TP48 TP49 U15
component class LTC6952_0: C43 C44 C47 C48 C54 C315 C316 C317 C318 C319 C478 C594 C599 C601 C602 C608 C681 C682 C684 J2 J3 R76 R78 R79 R80 R81 R82 R539 R1054 R1055 R1056 R1057 R1058 R1067 R1068 R1069 R1070 R1071 R1072 R1073 R1074 U12
component class Ext_GPIO: R241 R242 R243 R244 R281 R400 R428 R599 R825 R826 R827 R828 R835 R836 R837 R838 R839 R840
component class Ext_GPIO_Bank0: R492 R493 R494 R495 R496 R497 R500 R501 R502 R503 R504 R505 R508 R509 R510 R511 R512 R513
component class ClockDistrib: C45 C46 C334 C335 R77 R532 R533 TP19 TP20 X1
differential pair class Diff_86: DDR4_CK
differential pair class Diff_76: DDR4_CK
component class GND: J31
component class I2C_Expander_12: C311_I2C_Expander_12 U35_I2C_Expander_12
component class I2C_Expander_11: C311_I2C_Expander_11 U35_I2C_Expander_11
component class I2C_Expander_10: C311_I2C_Expander_10 U35_I2C_Expander_10
component class I2C_Expander_Main_Rst: C311_I2C_Expander_Main_Rst U35_I2C_Expander_Main_Rst
component class I2C_Bridge_GPIO: C303_I2C_Bridge_GPIO R3_I2C_Bridge_GPIO R4_I2C_Bridge_GPIO R5_I2C_Bridge_GPIO R6_I2C_Bridge_GPIO R7_I2C_Bridge_GPIO R8_I2C_Bridge_GPIO R9_I2C_Bridge_GPIO R10_I2C_Bridge_GPIO R223_I2C_Bridge_GPIO R224_I2C_Bridge_GPIO R225_I2C_Bridge_GPIO R226_I2C_Bridge_GPIO R227_I2C_Bridge_GPIO R558_I2C_Bridge_GPIO R559_I2C_Bridge_GPIO R560_I2C_Bridge_GPIO TP1_I2C_Bridge_GPIO TP2_I2C_Bridge_GPIO TP3_I2C_Bridge_GPIO TP4_I2C_Bridge_GPIO TP5_I2C_Bridge_GPIO TP6_I2C_Bridge_GPIO TP7_I2C_Bridge_GPIO TP8_I2C_Bridge_GPIO TP9_I2C_Bridge_GPIO TP10_I2C_Bridge_GPIO TP11_I2C_Bridge_GPIO TP12_I2C_Bridge_GPIO TP13_I2C_Bridge_GPIO TP14_I2C_Bridge_GPIO TP15_I2C_Bridge_GPIO TP16_I2C_Bridge_GPIO TP17_I2C_Bridge_GPIO TP18_I2C_Bridge_GPIO U3_I2C_Bridge_GPIO
differential pair class Diff_90: DDR4_CK USB_D USB_RX USB_RX_C USB_TX USB_TX_C
net class uSD_to_Driv: CMD_SD DATA0_SD DATA1_SD DATA2_SD DATA3_SD SD_Card_CLK
net class USB_2.0: USB_D_N
net class USB3._to_C: USB_RX_C_N USB_RX_C_P USB_TX_C_N USB_TX_C_P
net class USB3._C_to_FPGA: USB_RX_N USB_RX_P USB_TX_N USB_TX_P
net class Single_45: USB_D_N USB_D_P USB_RX_C_N USB_RX_C_P USB_RX_N USB_RX_P USB_TX_C_N USB_TX_C_P USB_TX_N USB_TX_P
net class SGMII_DATA_TO_C: SGMI_Rx_N SGMI_Rx_P SGMI_Tx_N SGMI_Tx_P
net class SGMII_DATA_C_FPGA: SGMI_C_Rx_N SGMI_C_Rx_P SGMI_C_Tx_N SGMI_C_Tx_P
net class Power_Line_40A: 0.85V@40A_INA US+_Vcc_PS_IntFp
net class Power_Line_20A: 3V3_RAIL RAM_Vcc1V2 Vout1_1 Vout2_1
net class Power_Line_10A: 3V3_NVMe 5V_RAIL 12V_LT3042 Vout1_2 Vout_5V@10A_INA
net class Power_Line_2A: 0V9@1A_REG3 0V85@2A 1V0@1.5A 1V8@0.5A_ADC_filtered 1V8@1.5A 2V5@1.5A 3.3V_LN_1 3.3V_Stable_1 3.3V_Stable_2 3.3V_Stable_3 12V_PCIE0 12V_PCIE0_CM 12V_PCIE1 12V_PCIE1_CM 12V_PCIE2 12V_PCIE2_CM 12V_PCIE3 12V_PCIE3_CM 12V_PCIE4 12V_PCIE4_CM FTDI_5V FTDI_VBUS FTDI_VccIO NetC568_2 NetC674_2
net class NVMe_DATA: NVMe_Rx_0_N NVMe_Rx_0_P NVMe_Rx_1_N NVMe_Rx_1_P NVMe_Tx_0_N NVMe_Tx_0_P NVMe_Tx_1_N NVMe_Tx_1_P
net class DATA_ETH_TO_PHY: TD_A_N TD_A_P TD_B_N TD_B_P TD_C_N TD_C_P TD_D_N TD_D_P
component class µSD: C544 C545 C546 C547 FB29 J28 R381 R382 R383 R911 U47
component class USB3.0: C1 C2 C3 C537 C538 C539 C540 C541 C542 C543 C731 C732 C733 C734 C735 C736 C737 D13 D14 FB26 FB27 FB28 R376 R377 R378 R379 R380 R490 R491 U45 U46 U74 X7
component class U_Expander_RESET: R746 R747 R748 R749 R750 R751 R752 R753 R754 R755 R756 R757 R758 R759 R760 R761 R762 R763 R1002 R1003 T1
component class U_CAN: C585 P6 R446 R447 U63 U75
component class NVMe: J27 MP5 R541 R542
component class "Gigabit Eth": C471 C472 C473 C474 C475 C476 C479 C480 C481 C482 C483 C484 C485 C486 C487 C488 C489 C490 C491 C492 C493 C494 C495 C496 C497 C498 C499 C500 C501 C502 C503 C504 C505 C506 C507 C508 C509 C510 C511 C512 C513 C514 C790 D1 D2 D3 D4 R319 R320 R321 R322 R323 R324 R325 R326 R327 R328 R329 R330 R331 R332 R333 R334 R335 R336 R337 R338 R709 R710 R711 R712 R713 R714 R715 S7 T21 U39 U76 X4
component class Flash_Memory: C515 C516 C517 C518 C519 C520 C521 C522 C523 C524 C586 C587 FB25 R339 R340 R341 R342 R343 R344 R345 U40 U41 U42
component class Debug: C558 C559 C560 C658 C659 C660 C661 C662 C663 C664 C665 C666 C667 C668 C669 C670 C671 C672 C673 C791 C792 D15 FB31 FB32 FB43 FB44 P12 R401 R402 R403 R404 R405 R406 R407 R408 R409 R410 R411 R412 R413 R414 R415 R416 R417 R418 R419 R420 R421 R422 R423 R424 R635 R636 R637 R638 R639 R640 R641 R642 R643 R721 R722 R723 R724 R725 R726 R727 R728 R729 R730 R731 R732 R733 R734 R1001 R1004 R1005 R1006 R1007 R1008 R1009 R1010 R1011 R1012 R1013 R1014 R1015 R1016 R1017 R1018 R1019 R1020 R1021 R1022 R1023 R1024 R1025 R1026 R1027 R1028 R1029 R1030 R1031 R1032 R1033 R1034 R1035 R1036 R1037 R1038 R1039 R1040 R1041 R1042 R1043 R1044 R1045 R1046 R1047 R1048 R1049 R1050 R1051 S8 S9 U53 U54 U55 U56 U57 U77 U78 U79 X8
component class 5V_to_3V3_for_FTDI: C563_5V_to_3V3_for_FTDI C564_5V_to_3V3_for_FTDI C565_5V_to_3V3_for_FTDI C566_5V_to_3V3_for_FTDI C567_5V_to_3V3_for_FTDI R430_5V_to_3V3_for_FTDI R431_5V_to_3V3_for_FTDI R432_5V_to_3V3_for_FTDI U59_5V_to_3V3_for_FTDI
component class I2C_Expander_PWR_CLK: C311_I2C_Expander_PWR_CLK U35_I2C_Expander_PWR_CLK
component class I2C_Expander_PWR_Dist: C311_I2C_Expander_PWR_Dist U35_I2C_Expander_PWR_Dist
component class U_FPGA_Decoupling: C738 C739 C740 C741 C742 C743 C744 C745 C746 C747 C748 C749 C750 C751 C752 C753 C754 C755 C756 C757 C758 C759 C760 C761 C762 C763 C764 C765
net class NVME_DATA_BANK: NVME_C_RX_1_N NVME_C_RX_1_P NVME_C_RX_O_N NVME_C_RX_O_P NVME_C_TX_1_N NVME_C_TX_1_P NVME_C_TX_O_N NVME_C_TX_O_P
component class U_ST1L08_5V_0V6: C720 C721 C722 C723 R689 R690 R691 U73
component class U_Pomiar_napiecia_high_curr: C310 R617 U72
component class U_UM78M_12_8V: C713 C714 U71
component class U_TPS7A88_3V3_1V8_0V9V@2x1A: C705 C706 C707 C708 C709 C710 C711 C712 R671 R672 R673 R674 R676 R745 U70
component class U_ADP1741_3V3_0V85: C674 C675 C676 C719 FB45 R435 R644 R645 R646 R668 U69
component class LowCurr: C304 C305 C306 C307 C308 C354 C355 C603 C604 C605 C606 C607 C610 C611 C612 C613 C614 C615 C616 C617 C618 C619 C620 C621 C622 C623 C624 C625 C626 D16 D17 D18 D19 L13 L15 L16 L17 L18 R113 R114 R212 R214 R216 R218 R220 R274 R284 R305 R308 R309 U19 U67
component class U_Detektor_otwarcia: BT1 BT? C609 C678 C679 C680 D20 D21 D23 D24 J36 R647 R648 R649 R650 R651 R652 R653 R654 R655 R656 R657 R658 T22 T23 T24 T25 T26 T27 T28 T29 T30 T31
net class RAM_DQS_Strobe: DDR4_DQS_0_N DDR4_DQS_0_P DDR4_DQS_1_N DDR4_DQS_1_P DDR4_DQS_2_N DDR4_DQS_2_P DDR4_DQS_3_N DDR4_DQS_3_P DDR4_DQS_4_N DDR4_DQS_4_P DDR4_DQS_5_N DDR4_DQS_5_P DDR4_DQS_6_N DDR4_DQS_6_P DDR4_DQS_7_N DDR4_DQS_7_P DDR4_DQS_8_N DDR4_DQS_8_P
net class RAM_Data_IO: DDR4_DM0 DDR4_DM1 DDR4_DM2 DDR4_DM3 DDR4_DM4 DDR4_DM5 DDR4_DM6 DDR4_DM7 DDR4_DQ0 DDR4_DQ1 DDR4_DQ2 DDR4_DQ3 DDR4_DQ4 DDR4_DQ5 DDR4_DQ6 DDR4_DQ7 DDR4_DQ8 DDR4_DQ9 DDR4_DQ10 DDR4_DQ11 DDR4_DQ12 DDR4_DQ13 DDR4_DQ14 DDR4_DQ15 DDR4_DQ16 DDR4_DQ17 DDR4_DQ18 DDR4_DQ19 DDR4_DQ20 DDR4_DQ21 DDR4_DQ22 DDR4_DQ23 DDR4_DQ24 DDR4_DQ25 DDR4_DQ26 DDR4_DQ27 DDR4_DQ28 DDR4_DQ29 DDR4_DQ30 DDR4_DQ31 DDR4_DQ32 DDR4_DQ33 DDR4_DQ34 DDR4_DQ35 DDR4_DQ36 DDR4_DQ37 DDR4_DQ38 DDR4_DQ39 DDR4_DQ40 DDR4_DQ41 DDR4_DQ42 DDR4_DQ43 DDR4_DQ44 DDR4_DQ45 DDR4_DQ46 DDR4_DQ47 DDR4_DQ48 DDR4_DQ49 DDR4_DQ50 DDR4_DQ51 DDR4_DQ52 DDR4_DQ53 DDR4_DQ54 DDR4_DQ55 DDR4_DQ56 DDR4_DQ57 DDR4_DQ58 DDR4_DQ59 DDR4_DQ60 DDR4_DQ61 DDR4_DQ62 DDR4_DQ63
net class Power_Line_1A: 12V_LT3042 ADP1741_3.6V ETH_VDDIO NetD16_2 NetD17_1 NetD17_2 NetD18_1 NetD18_2 NetD19_1 NetD19_2 Power_3.3_1 Power_3.3_2 US+_MGTVccAux US+_Vcc_PS_DDR_504
net class Lenght_DQS_to_Data: DDR4_DM0 DDR4_DM1 DDR4_DM2 DDR4_DM3 DDR4_DM4 DDR4_DM5 DDR4_DM6 DDR4_DM7 DDR4_DQ0 DDR4_DQ1 DDR4_DQ2 DDR4_DQ3 DDR4_DQ4 DDR4_DQ5 DDR4_DQ6 DDR4_DQ7 DDR4_DQ8 DDR4_DQ9 DDR4_DQ10 DDR4_DQ11 DDR4_DQ12 DDR4_DQ13 DDR4_DQ14 DDR4_DQ15 DDR4_DQ16 DDR4_DQ17 DDR4_DQ18 DDR4_DQ19 DDR4_DQ20 DDR4_DQ21 DDR4_DQ22 DDR4_DQ23 DDR4_DQ24 DDR4_DQ25 DDR4_DQ26 DDR4_DQ27 DDR4_DQ28 DDR4_DQ29 DDR4_DQ30 DDR4_DQ31 DDR4_DQ32 DDR4_DQ33 DDR4_DQ34 DDR4_DQ35 DDR4_DQ36 DDR4_DQ37 DDR4_DQ38 DDR4_DQ39 DDR4_DQ40 DDR4_DQ41 DDR4_DQ42 DDR4_DQ43 DDR4_DQ44 DDR4_DQ45 DDR4_DQ46 DDR4_DQ47 DDR4_DQ48 DDR4_DQ49 DDR4_DQ50 DDR4_DQ51 DDR4_DQ52 DDR4_DQ53 DDR4_DQ54 DDR4_DQ55 DDR4_DQ56 DDR4_DQ57 DDR4_DQ58 DDR4_DQ59 DDR4_DQ60 DDR4_DQ61 DDR4_DQ62 DDR4_DQ63
net class Lenght_DQS_to_CK: DDR4_DQS_0_N DDR4_DQS_0_P DDR4_DQS_1_N DDR4_DQS_1_P DDR4_DQS_2_N DDR4_DQS_2_P DDR4_DQS_3_N DDR4_DQS_3_P DDR4_DQS_4_N DDR4_DQS_4_P DDR4_DQS_5_N DDR4_DQS_5_P DDR4_DQS_6_N DDR4_DQS_6_P DDR4_DQS_7_N DDR4_DQS_7_P DDR4_DQS_8_N DDR4_DQS_8_P
net class Lenght_CK_to_Addr: DDR4_CK_N DDR4_CK_P
differential pair class Diff_76_to_90_Ram_CLK: DDR4_CK
net class RAM_Adress: DDR4_A0 DDR4_A1 DDR4_A2 DDR4_A3 DDR4_A4 DDR4_A5 DDR4_A6 DDR4_A7 DDR4_A8 DDR4_A9 DDR4_A10 DDR4_A11 DDR4_A12 DDR4_A13 DDR4_ACT_N DDR4_ALERT_N DDR4_BA0 DDR4_BA1 DDR4_BG0 DDR4_CAS DDR4_CKE0 DDR4_CS_B DDR4_DQS_ODT0 DDR4_PARITY DDR4_RAM_RST_N DDR4_RAS DDR4_TEN DDR4_WE
component class U_Power_48_20V@3A: C595 C596 C597 C598 C693 C694 C695 C696 C697 C698 C699 C700 C701 C702 C703 C704 D26 D27 L22 R140 R149 R150 R159 R160 R665 R666 R667 R669 R670 R764 T34 T35 U65
net class WR_CLK_C: WR_LMK_CLK_IN_N WR_LMK_CLK_IN_P
net class WR_CLK2_RC: WR_LMK_CLK_HF2_N WR_LMK_CLK_HF2_P
net class WR_CLK1_RC: WR_LMK_CLK_HF1_N WR_LMK_CLK_HF1_P
component class U_Pomiar_pradu_napiecia_1: C309_U_Pomiar_pradu_napiecia_1 R448_U_Pomiar_pradu_napiecia_1 U64_U_Pomiar_pradu_napiecia_1
component class U_Pomiar_pradu_napiecia_2: C309_U_Pomiar_pradu_napiecia_2 R448_U_Pomiar_pradu_napiecia_2 U64_U_Pomiar_pradu_napiecia_2
component class U_Pomiar_pradu_napiecia_3: C309_U_Pomiar_pradu_napiecia_3 R448_U_Pomiar_pradu_napiecia_3 U64_U_Pomiar_pradu_napiecia_3
component class U_Pomiar_pradu_napiecia_4: C309_U_Pomiar_pradu_napiecia_4 R448_U_Pomiar_pradu_napiecia_4 U64_U_Pomiar_pradu_napiecia_4
net class LTC_6952_2_REF_SMA: LTC6952_1_C_N LTC6952_1_C_P
component class DAC: C320 C321 C322 C323 R481 R608 R609 U30 X2 X3
net class Si53323_2_Q2_LVDS: Si53323_2_Q2_LVDS_N Si53323_2_Q2_LVDS_P
net class Si53323_1_Q2_LVDS: Si53323_1_Q2_LVDS_N Si53323_1_Q2_LVDS_P
component class SFP_Group+IMU: R469 R470 R471 R472 R473 R474 R475 R476 R477 R478 R479 R480
component class HighSpeed: R449 R450 R451 R452 R453 R454
component class CLK_MUX: C53 C324 C325 C326 C327 C328 C329 C330 C333 C336 C337 C338 C339 C340 C341 C342 C343 C344 C724 C725 C726 C727 FB23 FB24 J26 R245 R246 R247 R248 R249 R250 R251 R252 R253 R254 R255 R256 R257 R258 R259 R260 R261 R262 R263 R264 R265 R291 R301 R384 R385 R386 R387 R482 R483 R484 R485 R486 R487 R488 R489 R537 T36 U31 U32 U33
net class Si53323_2_Q2: Si53323_2_Q2_N Si53323_2_Q2_P
net class Si53323_2_Q1: Si53323_2_Q1_P
net class Si53323_2_CLK1: Si53323_2_CLK1_N Si53323_2_CLK1_P
net class Si53323_1_Q2: Si53323_1_Q2_N Si53323_1_Q2_P
net class Si53323_1_Q1: Si53323_1_Q1_N
net class RefClk_Si53323: RefClk_Si53323_P
net class MUX_DIV_OUT: OSC_Out_DIV_P
net class MUX_DIV_OUT_I: Osc_in_Si53323_2_P
net class CLM_M_OSC_IN_C: OSC_500Out
net class CLK_SMA1_C: CLK_SMA0_C_N CLK_SMA0_C_P LTC6952_1_C_Out10_N LTC6952_1_C_Out10_P
net class CLK_M_OSC_In: CLK_M_OSC_In
differential pair class Diff_76_to_90_Ram_DQS: DDR4_DQS_0 DDR4_DQS_1 DDR4_DQS_2 DDR4_DQS_3 DDR4_DQS_4 DDR4_DQS_5 DDR4_DQS_6 DDR4_DQS_7 DDR4_DQS_8
net class Single_36_39_50_Adr: DDR4_A0 DDR4_A1 DDR4_A2 DDR4_A3 DDR4_A4 DDR4_A5 DDR4_A6 DDR4_A7 DDR4_A8 DDR4_A9 DDR4_A10 DDR4_A11 DDR4_A12 DDR4_A13 DDR4_ACT_N DDR4_ALERT_N DDR4_BA0 DDR4_BA1 DDR4_BG0 DDR4_CAS DDR4_CKE0 DDR4_CS_B DDR4_DQS_ODT0 DDR4_PARITY DDR4_RAM_RST_N DDR4_RAS DDR4_TEN DDR4_WE
net class Diff_76_86_90: DDR4_DQS_0_N DDR4_DQS_0_P DDR4_DQS_1_N DDR4_DQS_1_P DDR4_DQS_2_N DDR4_DQS_2_P DDR4_DQS_3_N DDR4_DQS_3_P DDR4_DQS_4_N DDR4_DQS_4_P DDR4_DQS_5_N DDR4_DQS_5_P DDR4_DQS_6_N DDR4_DQS_6_P DDR4_DQS_7_N DDR4_DQS_7_P DDR4_DQS_8_N DDR4_DQS_8_P
net class RAM_Clock_Signal: DDR4_CK_N DDR4_CK_P
component class U_Pomiar_pradu_napiecia_5: C309_U_Pomiar_pradu_napiecia_5 R448_U_Pomiar_pradu_napiecia_5 U64_U_Pomiar_pradu_napiecia_5
component class U_Pomiar_pradu_napiecia_6: C309_U_Pomiar_pradu_napiecia_6 R448_U_Pomiar_pradu_napiecia_6 U64_U_Pomiar_pradu_napiecia_6
component class U_Pomiar_pradu_napiecia_PCIe0: C309_U_Pomiar_pradu_napiecia_PCIe0 R448_U_Pomiar_pradu_napiecia_PCIe0 U64_U_Pomiar_pradu_napiecia_PCIe0
component class U_Pomiar_pradu_napiecia_PCIe1: C309_U_Pomiar_pradu_napiecia_PCIe1 R448_U_Pomiar_pradu_napiecia_PCIe1 U64_U_Pomiar_pradu_napiecia_PCIe1
component class U_Pomiar_pradu_napiecia_PCIe2: C309_U_Pomiar_pradu_napiecia_PCIe2 R448_U_Pomiar_pradu_napiecia_PCIe2 U64_U_Pomiar_pradu_napiecia_PCIe2
component class U_5V_to_3V31: C563_U_5V_to_3V31 C564_U_5V_to_3V31 C565_U_5V_to_3V31 C566_U_5V_to_3V31 C567_U_5V_to_3V31 R430_U_5V_to_3V31 R431_U_5V_to_3V31 R432_U_5V_to_3V31 U59_U_5V_to_3V31
channel class Pomiar_pradu_napiecia: U_Pomiar_pradu_napiecia_PCIe3 U_Pomiar_pradu_napiecia_PCIe4
net class Single_39_50_D: DDR4_DM0 DDR4_DM1 DDR4_DM2 DDR4_DM3 DDR4_DM4 DDR4_DM5 DDR4_DM6 DDR4_DM7 DDR4_DQ0 DDR4_DQ1 DDR4_DQ2 DDR4_DQ3 DDR4_DQ4 DDR4_DQ5 DDR4_DQ6 DDR4_DQ7 DDR4_DQ8 DDR4_DQ9 DDR4_DQ10 DDR4_DQ11 DDR4_DQ12 DDR4_DQ13 DDR4_DQ14 DDR4_DQ15 DDR4_DQ16 DDR4_DQ17 DDR4_DQ18 DDR4_DQ19 DDR4_DQ20 DDR4_DQ21 DDR4_DQ22 DDR4_DQ23 DDR4_DQ24 DDR4_DQ25 DDR4_DQ26 DDR4_DQ27 DDR4_DQ28 DDR4_DQ29 DDR4_DQ30 DDR4_DQ31 DDR4_DQ32 DDR4_DQ33 DDR4_DQ34 DDR4_DQ35 DDR4_DQ36 DDR4_DQ37 DDR4_DQ38 DDR4_DQ39 DDR4_DQ40 DDR4_DQ41 DDR4_DQ42 DDR4_DQ43 DDR4_DQ44 DDR4_DQ45 DDR4_DQ46 DDR4_DQ47 DDR4_DQ48 DDR4_DQ49 DDR4_DQ50 DDR4_DQ51 DDR4_DQ52 DDR4_DQ53 DDR4_DQ54 DDR4_DQ55 DDR4_DQ56 DDR4_DQ57 DDR4_DQ58 DDR4_DQ59 DDR4_DQ60 DDR4_DQ61 DDR4_DQ62 DDR4_DQ63
component class US+_Interrupts: R515 R522 R523 R530 R531 R546 R547 R548 R549 R550 R551 R552 R553 R554 R555 R556 R557 R607 R618 R659 R660 R661 R662 R663 R664 R688 R735 R736 R744 R765 R766 R767 R817 R818 R819 R820 R821 R822 R823 R824 R847 R848 R849 R850 R851 R852 R853 R854 R855 R856 R857 R858 R859 R860 R861 R862 R863 R864 R865 R866 R867 R868 R869 R870 R871 R872 R873 R874 R875 R876 R877 R878 R879 R880 R881 R882 R883 R884 R885 R886 R921 R922 R923 R924 R925 R926 R927 R928 R929 R930 R931 R932 R933 R934 R935 R936 R937 R938 R939 R940 R941 R942 R943 R944 R945 R946 R947 R948 R949 R950 R951 R952 R953 R954 R955 R956 R957 R958 R959 R960 R961 R962 R963 R964 R965 R966 R967 R968 R969 R970 R971 R972 R973 R974 R975 R976 R977 R978 R979 R980 R981 R982 R983 R984 R985 R986 R987 R988 R989 R990 R991 R992 R993 R994 R995 R996 R997 R998 R999 R1000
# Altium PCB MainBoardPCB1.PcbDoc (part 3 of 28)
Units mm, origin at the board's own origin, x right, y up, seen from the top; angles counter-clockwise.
Board outline 258.95 x 308.86 mm, 16 copper layers (L1, L2 (GND), L3 (Sign), L4 (GND), L5 (Sign), L6 (PWR/GND), L7(PWR/GND), L8 (Plane_GND), L9 (PWR/GND), L10 (PWR/GND), L11 (PWR/GND), L12 (Sign), L13 (GND), L14 (Sign), L15 (GND), L16), stack 2.502 mm thick; 2397 components, 1744 nets, 8397 pads, 4112 vias.
Unrouted connection lines stored in the file: 3547.

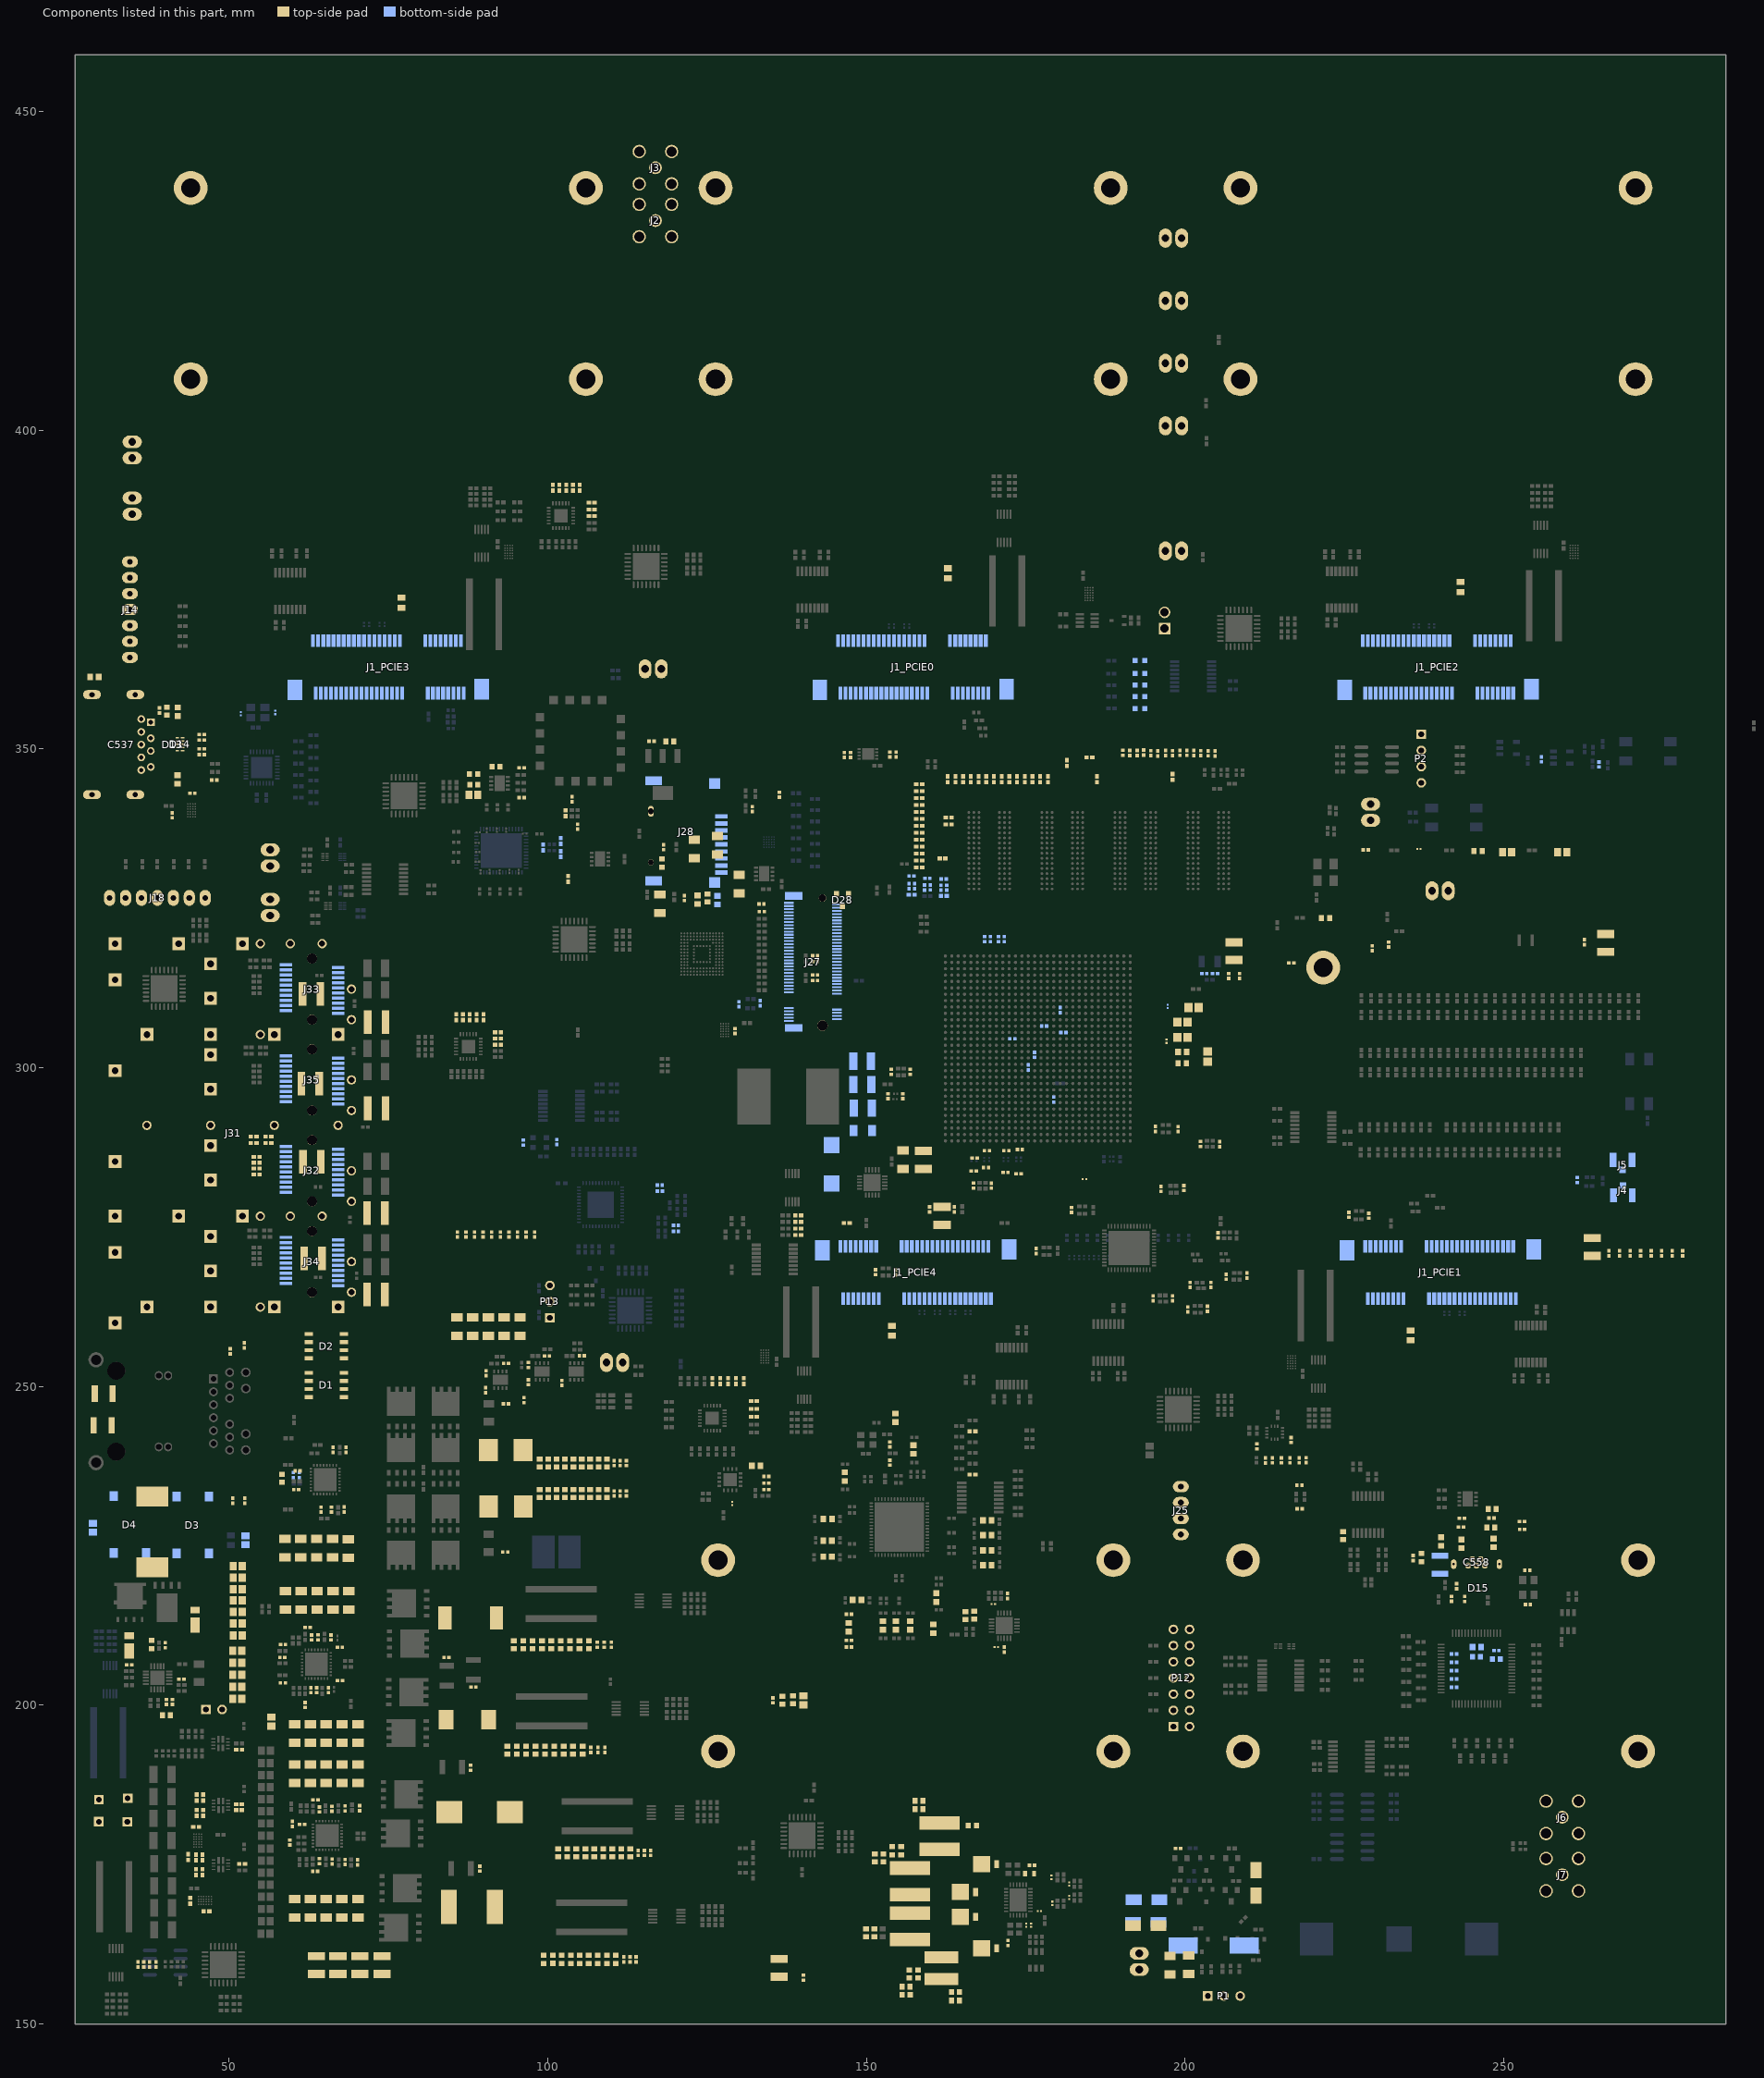
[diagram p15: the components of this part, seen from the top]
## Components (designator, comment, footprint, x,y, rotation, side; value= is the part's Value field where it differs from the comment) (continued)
C325 "100nF" "CAP 0402/1005 RF" 47.51,533.718 r0 top
C326 "1uF" "CAP 0402/1005 RF" 352.209,337.248 r90 top
C327 "1uF" "CAP 0402/1005 RF" 355.092,337.147 r90 top
C328 "1uF" "CAP 0402/1005 RF" 353.505,337.248 r90 top
C329 "1uF" "CAP 0402/1005 RF" 356.387,337.147 r90 top
C330 "100nF" "CAP 0402/1005 RF" 47.51,532.517 r0 top
C331 "1uF" "CAP 0402/1005 RF" 73.355,536.702 r270 top
C332 "1uF" "CAP 0402/1005 RF" 129.388,305.765 r270 top
C333 "10nF" "CAP 0201/0603 RF" 56.329,518.605 r270 top
C334 "100nF" "CAP 0402/1005 RF" 103.797,342.129 r270 top
C335 "100nF" "CAP 0402/1005 RF" 104.697,337.82 r90 top
C336 "100nF" "CAP 0402/1005 RF" 74.82,521.694 r90 top
C337 "100nF" "CAP 0402/1005 RF" 75.878,521.694 r90 top
C338 "100nF" "CAP 0402/1005 RF" 76.937,521.694 r90 top
C339 "10uF" "CAP 0805/2012 RF" 68.682,521.765 r90 top
C340 "1uF" "CAP 0402/1005 RF" 73.762,521.694 r90 top
C341 "100nF" "CAP 0402/1005 RF" 38.998,529.592 r90 top
C342 "100nF" "CAP 0402/1005 RF" 56.918,527.113 r90 top
C343 "100nF" "CAP 0402/1005 RF" 55.918,527.113 r90 top
C344 "10nF" "CAP 0201/0603 RF" 57.414,518.605 r270 top
C345 "22pF" "CAP 0402/1005 RF" 66.32,240.08 r270 top
C346 "100nF" "CAP 0402/1005 RF" 68.336,240.08 r90 top
C347 "10uF" "CAP 1206/3216" 88.21,259.372 r270 top
C348 "10uF" "CAP 1206/3216" 85.728,259.372 r270 top
C349 "22pF" "CAP 0402/1005 RF" 66.055,230.697 r90 top
C350 "100nF" "CAP 0402/1005 RF" 68.072,230.712 r270 top
C351 "1uF" "CAP 0402/1005 RF" 60.756,236.764 r0 top
C352 "10uF" "CAP 1206/3216" 62.772,195.58 r90 top
C353 "10uF" "CAP 1206/3216" 60.29,195.58 r90 top
C354 "4.7 µF" "CAP 0603/1608 RF" 151.25,164.289 r270 top
C355 "4.7 µF" "CAP 0603/1608 RF" 149.956,164.301 r270 top
C356 "1uF" "CAP 0402/1005 RF" 60.541,233.839 r0 top
C357 "100nF" "CAP 0402/1005 RF" 64.44,230.697 r90 top
C358 "1uF" "CAP 0603/1608 RF" 58.293,235.623 r270 top
C359 "100nF" "CAP 0402/1005 RF" 112.323,233.238 r270 top
C360 "470nF" "CAP 0402/1005 RF" 112.324,237.989 r90 top
C361 "1uF" "CAP 0402/1005 RF" 110.434,233.237 r270 top
C362 "4.7uF" "CAP 0603/1608 RF" 101.381,237.989 r90 top
C363 "10uF" "CAP 0603/1608 RF" 100.061,237.989 r90 top
C364 "22uF" "CAP 0603/1608 RF" 102.7,237.989 r90 top
C365 "10uF" "CAP 0603/1608 RF" 98.742,233.237 r270 top
C366 "22uF" "CAP 0603/1608 RF" 98.742,237.989 r90 top
C367 "10uF" "CAP 0603/1608 RF" 101.381,233.237 r270 top
C368 "22uF" "CAP 0603/1608 RF" 100.061,233.237 r270 top
C369 "10uF" "CAP 0603/1608 RF" 102.7,233.237 r270 top
C370 "22uF" "CAP 0603/1608 RF" 104.02,237.989 r90 top
C371 "10uF" "CAP 1206/3216 - 0.8MM" 67.736,195.58 r90 top
C372 "10uF" "CAP 1206/3216 - 0.8MM" 90.692,259.372 r270 top
C373 "10uF" "CAP 1206/3216 - 0.8MM" 95.656,259.372 r270 top
C374 "10uF" "CAP 1206/3216 - 0.8MM" 65.254,195.58 r90 top
C375 "10uF" "CAP 1206/3216 - 0.8MM" 93.174,259.372 r270 top
C376 "10uF" "CAP 1206/3216 - 0.8MM" 70.218,195.58 r90 top
C377 "100nF" "CAP 0402/1005 RF" 111.364,233.238 r270 top
C378 "470nF" "CAP 0402/1005 RF" 110.435,237.989 r90 top
C379 "1uF" "CAP 0402/1005 RF" 111.365,237.989 r90 top
C380 "4.7uF" "CAP 0603/1608 RF" 105.339,237.989 r90 top
C381 "10uF" "CAP 0603/1608 RF" 105.339,233.237 r270 top
C382 "22uF" "CAP 0603/1608 RF" 106.659,233.237 r270 top
C383 "10uF" "CAP 0603/1608 RF" 109.298,237.989 r90 top
C384 "22uF" "CAP 0603/1608 RF" 107.978,233.238 r270 top
C385 "10uF" "CAP 0603/1608 RF" 104.02,233.237 r270 top
C386 "22uF" "CAP 0603/1608 RF" 106.659,237.989 r90 top
C387 "10uF" "CAP 0603/1608 RF" 109.297,233.238 r270 top
C388 "22uF" "CAP 0603/1608 RF" 107.978,237.989 r90 top
C389 "22pF" "CAP 0402/1005 RF" 68.211,183.823 r270 top
C390 "100nF" "CAP 0402/1005 RF" 70.485,183.85 r270 top
C391 "10uF" "CAP 1206/3216" 61.258,224.638 r270 top
C392 "10uF" "CAP 1206/3216" 58.776,224.638 r90 top
C393 "22pF" "CAP 0402/1005 RF" 68.185,175.427 r90 top
C394 "100nF" "CAP 0402/1005 RF" 70.142,175.373 r270 top
C395 "1uF" "CAP 0402/1005 RF" 59.93,181.401 r270 top
C396 "10uF" "CAP 1206/3216" 61.334,216.433 r270 top
C397 "10uF" "CAP 1206/3216" 58.852,216.433 r90 top
C398 "1uF" "CAP 0402/1005 RF" 61.458,181.317 r0 top
C399 "100nF" "CAP 0402/1005 RF" 59.524,178.467 r90 top
C400 "10uF" "CAP 1206/3216 - 0.8MM" 68.78,216.433 r270 top
C401 "10uF" "CAP 1206/3216 - 0.8MM" 66.298,216.433 r270 top
C402 "10uF" "CAP 1206/3216 - 0.8MM" 63.816,216.433 r270 top
C403 "10uF" "CAP 1206/3216 - 0.8MM" 68.704,224.607 r90 top
C404 "10uF" "CAP 1206/3216 - 0.8MM" 66.222,224.637 r90 top
C405 "10uF" "CAP 1206/3216 - 0.8MM" 63.74,224.637 r90 top
C406 "100nF" "CAP 0402/1005 RF" 116.15,176.851 r90 top
C407 "470nF" "CAP 0402/1005 RF" 115.176,176.847 r90 top
C408 "1uF" "CAP 0402/1005 RF" 114.205,176.851 r90 top
C409 "4.7uF" "CAP 0603/1608 RF" 110.122,176.847 r90 top
C410 "10uF" "CAP 0603/1608 RF" 108.699,176.847 r90 top
C411 "22uF" "CAP 0603/1608 RF" 112.941,176.847 r90 top
C412 "10uF" "CAP 0603/1608 RF" 111.544,176.847 r90 top
C413 "22uF" "CAP 0603/1608 RF" 107.302,176.847 r90 top
C414 "10uF" "CAP 0603/1608 RF" 103.061,176.847 r90 top
C415 "22uF" "CAP 0603/1608 RF" 101.638,176.847 r90 top
C416 "10uF" "CAP 0603/1608 RF" 105.905,176.847 r90 top
C417 "22uF" "CAP 0603/1608 RF" 104.47,176.851 r90 top
C418 "100nF" "CAP 0402/1005 RF" 113.877,160.146 r90 top
C419 "470nF" "CAP 0402/1005 RF" 112.903,160.146 r90 top
C420 "1uF" "CAP 0402/1005 RF" 111.932,160.146 r90 top
C421 "4.7uF" "CAP 0603/1608 RF" 107.849,160.146 r90 top
C422 "10uF" "CAP 0603/1608 RF" 106.426,160.146 r90 top
C423 "22uF" "CAP 0603/1608 RF" 110.668,160.146 r90 top
C424 "10uF" "CAP 0603/1608 RF" 109.271,160.146 r90 top
C425 "22uF" "CAP 0603/1608 RF" 105.029,160.147 r90 top
C426 "10uF" "CAP 0603/1608 RF" 100.787,160.147 r90 top
C427 "22uF" "CAP 0603/1608 RF" 99.37,160.137 r90 top
C428 "10uF" "CAP 0603/1608 RF" 103.632,160.147 r90 top
C429 "22uF" "CAP 0603/1608 RF" 102.197,160.147 r90 top
C430 "22pF" "CAP 0402/1005 RF" 65.978,210.639 r270 top
C431 "100nF" "CAP 0402/1005 RF" 67.391,209.114 r0 top
C432 "10uF" "CAP 1206/3216" 62.758,168.173 r270 top
C433 "10uF" "CAP 1206/3216" 60.276,168.173 r90 top
C434 "22pF" "CAP 0402/1005 RF" 65.578,202.374 r90 top
C435 "100nF" "CAP 0402/1005 RF" 67.406,203.864 r0 top
C436 "1uF" "CAP 0402/1005 RF" 58.356,207.523 r0 top
C437 "10uF" "CAP 1206/3216" 62.772,189.281 r270 top
C438 "10uF" "CAP 1206/3216" 60.29,189.281 r90 top
C439 "1uF" "CAP 0402/1005 RF" 58.455,209.529 r0 top
C440 "100nF" "CAP 0402/1005 RF" 58.449,203.522 r0 top
C441 "10uF" "CAP 1206/3216 - 0.8MM" 70.218,189.281 r270 top
C442 "10uF" "CAP 1206/3216 - 0.8MM" 67.736,189.281 r270 top
C443 "10uF" "CAP 1206/3216 - 0.8MM" 65.254,189.281 r270 top
C444 "10uF" "CAP 1206/3216 - 0.8MM" 70.204,168.173 r90 top
C445 "10uF" "CAP 1206/3216 - 0.8MM" 67.722,168.173 r90 top
C446 "10uF" "CAP 1206/3216 - 0.8MM" 65.24,168.173 r90 top
C447 "100nF" "CAP 0402/1005 RF" 109.987,209.5 r90 top
C448 "470nF" "CAP 0402/1005 RF" 108.87,209.5 r90 top
C449 "1uF" "CAP 0402/1005 RF" 107.777,209.5 r90 top
C450 "4.7uF" "CAP 0603/1608 RF" 106.482,209.5 r90 top
C451 "10uF" "CAP 0603/1608 RF" 104.983,209.5 r90 top
C452 "22uF" "CAP 0603/1608 RF" 103.51,209.499 r90 top
C453 "10uF" "CAP 0603/1608 RF" 102.037,209.499 r90 top
C454 "22uF" "CAP 0603/1608 RF" 100.564,209.499 r90 top
C455 "10uF" "CAP 0603/1608 RF" 99.091,209.499 r90 top
C456 "22uF" "CAP 0603/1608 RF" 97.617,209.499 r90 top
C457 "10uF" "CAP 0603/1608 RF" 96.144,209.498 r90 top
C458 "22uF" "CAP 0603/1608 RF" 94.671,209.498 r90 top
C459 "100nF" "CAP 0402/1005 RF" 108.979,192.987 r90 top
C460 "470nF" "CAP 0402/1005 RF" 107.861,192.987 r90 top
C461 "1uF" "CAP 0402/1005 RF" 106.769,192.987 r90 top
C462 "4.7uF" "CAP 0603/1608 RF" 105.474,192.987 r90 top
C463 "10uF" "CAP 0603/1608 RF" 103.975,192.986 r90 top
C464 "22uF" "CAP 0603/1608 RF" 102.502,192.971 r90 top
C465 "10uF" "CAP 0603/1608 RF" 101.028,192.986 r90 top
C466 "22uF" "CAP 0603/1608 RF" 99.555,192.986 r90 top
C467 "10uF" "CAP 0603/1608 RF" 98.082,192.986 r90 top
C468 "22uF" "CAP 0603/1608 RF" 96.609,192.986 r90 top
C469 "10uF" "CAP 0603/1608 RF" 95.136,192.986 r90 top
C470 "22uF" "CAP 0603/1608 RF" 93.662,192.986 r90 top
C471 "100nF" "CAP 0402/1005 RF" 52.467,232.083 r90 top
C472 "100nF" "CAP 0402/1005 RF" 50.578,232.095 r90 top
C473 "100nF" "CAP 0402/1005 RF" 52.387,256.453 r270 top
C474 "100nF" "CAP 0402/1005 RF" 50.178,255.53 r270 top
C475 "Capacitor_1210" CAPC3326X17L 30.174,243.916 r180 top
C476 "Capacitor_1210" CAPC3326X17L 30.328,248.856 r180 top
C477 "100nF" "CAP 0402/1005 RF" 174.085,287.185 r0 top
C478 "100nF" "CAP 0402/1005 RF" 157.08,330.089 r0 bottom
C479 "100nF" "CAP 0402/1005 RF" 120.113,275.285 r180 bottom
C480 "27pF" "CAP 0402/1005 RF" 101.403,288.349 r270 bottom
C481 "27pF" "CAP 0402/1005 RF" 96.15,288.272 r90 bottom
C482 "100nF" "CAP 0402/1005 RF" 120.113,274.345 r180 bottom
C483 "100nF" "CAP 0402/1005 RF" 117.584,281.61 r180 bottom
C484 "100nF" "CAP 0402/1005 RF" 117.606,280.645 r180 bottom
C485 "1uF" "CAP 0402/1005 RF" 216.471,238.426 r90 top
C486 "1uF" "CAP 0402/1005 RF" 213.703,238.426 r90 top
C487 "100nF" "CAP 0402/1005 RF" 218.986,238.457 r90 top
C488 "100nF" "CAP 0402/1005 RF" 212.611,238.395 r90 top
C489 "10uF" "CAP 0402/1005 RF" 217.894,238.426 r90 top
C490 "10nF" "CAP 0402/1005 RF" 215.125,238.426 r90 top
C491 "1uF" "CAP 0402/1005 RF" 264.96,347.586 r270 bottom
C492 "1uF" "CAP 0402/1005 RF" 273.133,270.896 r90 top
C493 "1uF" "CAP 0402/1005 RF" 269.828,270.896 r90 top
C494 "100nF" "CAP 0402/1005 RF" 276.439,270.896 r90 top
C495 "100nF" "CAP 0402/1005 RF" 268.175,270.896 r90 top
C496 "100nF" "CAP 0402/1005 RF" 274.786,270.896 r90 top
C497 "10uF" "CAP 0402/1005 RF" 271.481,270.896 r90 top
C498 "10nF" "CAP 0402/1005 RF" 278.092,270.896 r90 top
C499 "1uF" "CAP 0402/1005 RF" 190.25,349.412 r90 top
C500 "1uF" "CAP 0402/1005 RF" 194.645,349.353 r90 top
C501 "100nF" "CAP 0402/1005 RF" 193.489,349.451 r90 top
C502 "100nF" "CAP 0402/1005 RF" 191.33,349.367 r90 top
C503 "10uF" "CAP 0402/1005 RF" 195.724,349.308 r90 top
C504 "10nF" "CAP 0402/1005 RF" 192.473,349.381 r90 top
C505 "1uF" "CAP 0402/1005 RF" 93.902,273.844 r90 top
C506 "1uF" "CAP 0402/1005 RF" 89.859,273.844 r90 top
C507 "1uF" "CAP 0402/1005 RF" 97.945,273.844 r90 top
C508 "1uF" "CAP 0402/1005 RF" 87.164,273.844 r90 top
C509 "100nF" "CAP 0402/1005 RF" 95.25,273.844 r90 top
C510 "100nF" "CAP 0402/1005 RF" 85.816,273.844 r90 top
C511 "100nF" "CAP 0402/1005 RF" 92.554,273.844 r90 top
C512 "100nF" "CAP 0402/1005 RF" 91.207,273.844 r90 top
C513 "10uF" "CAP 0402/1005 RF" 88.512,273.844 r90 top
C514 "10nF" "CAP 0402/1005 RF" 96.597,273.844 r90 top
C515 "4.7uF" "CAP 0603/1608 RF" 136.804,200.812 r90 top
C516 "4.7uF" "CAP 0603/1608 RF" 138.493,200.85 r90 top
C517 "100nF" "CAP 0402/1005 RF" 118.173,334.607 r90 top
C518 "2.2uF" "CAP 1206/3216 - 0.8MM" 126.632,334.937 r90 top
C519 "100nF" "CAP 0402/1005 RF" 121.45,326.621 r90 top
C520 "2.2uF" "CAP 1206/3216 - 0.8MM" 117.602,325.734 r90 top
C521 "100nF" "CAP 0402/1005 RF" 133.591,324.504 r180 top
C522 "1uF" "CAP 0402/1005 RF" 133.541,325.685 r180 top
C523 "4.7uF" "CAP 0603/1608 RF" 117.907,332.121 r90 top
C524 "4.7uF" "CAP 0603/1608 RF" 125.057,326.649 r90 top
C525 "10nF" "CAP 0402/1005 RF" 161.704,328.249 r270 bottom
C526 "10nF" "CAP 0402/1005 RF" 162.593,328.257 r270 bottom
C527 "10nF" "CAP 0402/1005 RF" 160.022,328.291 r270 bottom
C528 "10nF" "CAP 0402/1005 RF" 159.121,328.268 r270 bottom
C529 "10nF" "CAP 0402/1005 RF" 156.68,328.488 r270 bottom
C530 "10nF" "CAP 0402/1005 RF" 157.569,328.489 r270 bottom
C531 "100nF" "CAP 0402/1005 RF" 307.454,280.073 r180 top
C532 "100nF" "CAP 0402/1005 RF" 322.136,281.906 r90 top
C533 "100nF" "CAP 0402/1005 RF" 320.929,281.906 r90 top
C534 "100nF" "CAP 0402/1005 RF" 319.722,281.906 r90 top
C535 "22pF" "CAP 0402/1005 RF" 204.7,314.782 r180 bottom
C536 "22pF" "CAP 0402/1005 RF" 203.02,314.782 r0 bottom
C537 "WE-Communication Connectors 692121130100" 692121130100 35.291,358.548 r90 bottom locked
C538 "1uF" "CAP 0402/1005 RF" 39.078,356.048 r270 top
C539 "4.7uF" "CAP 0603/1608 RF" 40.237,355.93 r270 top
C540 "100nF" "CAP 0402/1005 RF" 45.72,352.291 r180 top
C541 "100nF" "CAP 0402/1005 RF" 45.72,351.396 r180 top
C542 "100nF" "CAP 0402/1005 RF" 45.72,350.012 r180 top
C543 "100nF" "CAP 0402/1005 RF" 45.72,349.116 r180 top
C544 "1uF" "CAP 0402/1005 RF" 132.117,340.589 r90 top
C545 "100nF" "CAP 0402/1005 RF" 360.832,215.989 r90 top
C546 "100nF" "CAP 0402/1005 RF" 365.185,215.849 r90 top
C547 "100nF" "CAP 0402/1005 RF" 136.334,342.83 r90 top
C548 "11pF" "CAP 0402/1005 RF" 62.953,210.639 r270 top
C549 "220pF" "CAP 0402/1005 RF" 62.338,212.229 r180 top
C550 "4.7uF" "CAP 0402/1005 RF" 102.225,250.563 r90 top
C551 "10uF" "CAP 0402/1005 RF" 96.268,247.873 r90 top
C552 "4.7uF" "CAP 0402/1005 RF" 96.964,250.684 r90 top
C553 "10uF" "CAP 0402/1005 RF" 96.964,253.376 r90 top
C554 "4.7uF" "CAP 0402/1005 RF" 90.265,249.429 r90 top
C555 "10uF" "CAP 0402/1005 RF" 90.322,252.088 r90 top
C557 "100nF" "CAP 0402/1005 RF" 173.876,283.362 r0 top
C558 "WR-Communication Connectors 614105150721" 614105150721 245.732,221.915 r180 top
C559 "1uF" "CAP 0402/1005 RF" 248.094,229.362 r0 top
C560 "4.7uF" "CAP 0603/1608 RF" 247.976,227.876 r0 top
C561 "100nF" "CAP 0402/1005 RF" 216.649,241.614 r90 top
C562 "100nF" "CAP 0402/1005 RF" 211.277,240.614 r90 top
C563_5V_to_3V3_for_FTDI "4.7uF" "CAP 0603/1608 RF" 224.799,226.593 r90 top (schematic designator C563)
C563_U_5V_to_3V31 "4.7uF" "CAP 0603/1608 RF" 348.304,346.04 r90 top (schematic designator C563)
C563_U_5V_to_3V32 "4.7uF" "CAP 0603/1608 RF" 333.619,326.268 r270 top (schematic designator C563)
C563_U_5V_to_3V33 "4.7uF" "CAP 0603/1608 RF" 88.395,344.43 r0 top (schematic designator C563)
C564_5V_to_3V3_for_FTDI "4.7uF" "CAP 0603/1608 RF" 248.219,230.784 r0 top (schematic designator C564)
C564_U_5V_to_3V31 "4.7uF" "CAP 0603/1608 RF" 350.298,345.95 r90 top (schematic designator C564)
C564_U_5V_to_3V32 "4.7uF" "CAP 0603/1608 RF" 336.004,326.369 r270 top (schematic designator C564)
C564_U_5V_to_3V33 "4.7uF" "CAP 0603/1608 RF" 91.885,347.231 r180 top (schematic designator C564)
C565_5V_to_3V3_for_FTDI "4.7uF" "CAP 0603/1608 RF" 248.844,207.246 r0 bottom (schematic designator C565)
C565_U_5V_to_3V31 "4.7uF" "CAP 0603/1608 RF" 357.13,348.52 r270 top (schematic designator C565)
C565_U_5V_to_3V32 "4.7uF" "CAP 0603/1608 RF" 322.682,325.332 r270 top (schematic designator C565)
C565_U_5V_to_3V33 "4.7uF" "CAP 0603/1608 RF" 88.372,346.081 r0 top (schematic designator C565)
C566_5V_to_3V3_for_FTDI "100nF" "CAP 0402/1005 RF" 248.862,208.605 r0 bottom (schematic designator C566)
C566_U_5V_to_3V31 "100nF" "CAP 0402/1005 RF" 363.067,345.65 r90 top (schematic designator C566)
C566_U_5V_to_3V32 "100nF" "CAP 0402/1005 RF" 324.612,325.366 r270 top (schematic designator C566)
C566_U_5V_to_3V33 "100nF" "CAP 0402/1005 RF" 95.905,347.053 r0 top (schematic designator C566)
C567_5V_to_3V3_for_FTDI "2.2uF" "CAP 0402/1005 RF" 242.221,208.034 r180 bottom (schematic designator C567)
C567_U_5V_to_3V31 "2.2uF" "CAP 0402/1005 RF" 361.779,345.662 r90 top (schematic designator C567)
C567_U_5V_to_3V32 "2.2uF" "CAP 0402/1005 RF" 326.655,322.61 r90 top (schematic designator C567)
C567_U_5V_to_3V33 "2.2uF" "CAP 0402/1005 RF" 95.905,342.367 r0 top (schematic designator C567)
C568 "4.7uF" "CAP 0402/1005 RF" 345.24,361.209 r0 top
C569 "4.7uF" "CAP 0402/1005 RF" 348.488,362.146 r0 top
C570 "4.7uF" "CAP 0402/1005 RF" 337.147,361.659 r0 top
C571 "1nF" "CAP 0201/0603 RF" 342.919,357.06 r0 top
C572 "10uF" "CAP 0603/1608 RF" 165.532,214.092 r270 top
C573 "10nF" "CAP 0201/0603 RF" 170.368,209.139 r180 top
C574 "10uF" "CAP 0805/2012 RF" 140.132,200.771 r90 top
C575 "10uF" "CAP 0805/2012 RF" 88.328,342.811 r0 top
C576 "10uF" "CAP 0603/1608 RF" 166.929,214.123 r270 top
C577 "10nF" "CAP 0201/0603 RF" 169.921,215.87 r180 top
C578 "100nF" "CAP 0402/1005 RF" 172.128,217.14 r270 top
C579 "100nF" "CAP 0402/1005 RF" 171.628,208.749 r90 top
C580 "4.7uF" "CAP 0805/2012 RF" 46.507,509.154 r270 top
C581 "10uF" "CAP 0805/2012 RF" 38.291,507.974 r270 top
C582 "4.7uF" "CAP 0805/2012 RF" 38.291,505.155 r90 top
C583 "100nF" "CAP 0402/1005 RF" 39.725,507.663 r270 top
C584 "4.7uF" "CAP 0805/2012 RF" 45.047,503.43 r90 top
C585 "100nF" "CAP 0402/1005 RF" 352.057,170.802 r90 top
C586 "2.2uF" "CAP 1206/3216 - 0.8MM" 122.999,334.34 r90 top
C587 "2.2uF" "CAP 1206/3216 - 0.8MM" 130.035,328.79 r90 top
C588 "100nF" "CAP 0402/1005 RF" 153.67,240.917 r270 top
C589 "100nF" "CAP 0402/1005 RF" 153.67,238.054 r270 top
C590 "100nF" "CAP 0402/1005 RF" 147.253,214.27 r0 top
C591 "10uF" "CAP 0402/1005 RF" 147.253,210.206 r0 top
C592 "100nF" "CAP 0402/1005 RF" 147.253,209.121 r0 top
C594 "100nF" "CAP 0402/1005 RF" 159.572,329.705 r0 bottom
C595 "10uF" "CAP 0805/2012 RF" 28.639,227.851 r90 bottom
C596 "10uF" "CAP 0805/2012 RF" 52.54,225.895 r90 bottom
C597 "1uF" "CAP 0402/1005 RF" 34.332,206.35 r0 top
C598 "10uF" "CAP 0603/1608 RF" 37.846,209.537 r270 top
C599 "100nF" "CAP 0402/1005 RF" 162.136,329.616 r0 bottom
C601 "100nF" "CAP 0402/1005 RF" 130.002,309.969 r270 bottom
C602 "100nF" "CAP 0402/1005 RF" 133.342,310.134 r90 bottom
C603 "43pF" "CAP 0201/0603 RF" 181.834,169.866 r270 top
C604 "1µF" "CAP 0402/1005 RF" 175.978,174.908 r180 top
C605 "100pF" "CAP 0201/0603 RF" 181.826,171.962 r90 top
C606 "4.7 µF" "CAP 0603/1608 RF" 151.325,176.047 r270 top
C607 "4.7 µF" "CAP 0603/1608 RF" 155.45,177.182 r270 top
C608 "100nF" "CAP 0402/1005 RF" 217.941,234.531 r180 top
C609 "FC0H224ZFTBR24" FC0H224ZFTBR24 204.495,162.332 r180 bottom
C610 "4.7 µF" "CAP 0603/1608 RF" 154.055,177.183 r270 top
C611 "4.7 µF" "CAP 0603/1608 RF" 152.653,176.047 r270 top
C612 "43pF" "CAP 0201/0603 RF" 179.024,173.015 r90 top
C613 "4.7 µF" "CAP 0603/1608 RF" 158.243,185.022 r0 top
C614 "4.7 µF" "CAP 0603/1608 RF" 166.626,181.153 r180 top
C615 "4.7 µF" "CAP 0603/1608 RF" 158.243,183.706 r0 top
C616 "100pF" "CAP 0201/0603 RF" 179.174,168.95 r270 top
C617 "4.7 µF" "CAP 0603/1608 RF" 156.237,155.868 r0 top
C618 "4.7 µF" "CAP 0603/1608 RF" 163.975,153.678 r180 top
C619 "4.7 µF" "CAP 0603/1608 RF" 156.729,157.871 r270 top
C620 "4.7 µF" "CAP 0603/1608 RF" 163.975,155.006 r180 top
C621 "4.7 µF" "CAP 0603/1608 RF" 158.119,157.87 r270 top
C622 "4.7 µF" "CAP 0603/1608 RF" 156.25,154.593 r0 top
C623 "100nF" "CAP 0402/1005 RF" 172.202,162.711 r90 top
C624 "10nF" "CAP 0201/0603 RF" 175.841,165.493 r90 top
C625 "10nF" "CAP 0201/0603 RF" 177.122,167.7 r180 top
C626 "10nF" "CAP 0201/0603 RF" 175.078,165.493 r90 top
C627 "100nF" "CAP 0201/0603 RF" 197.272,309.647 r90 bottom
C628 "470nF" "CAP 0402/1005 RF" 180.397,309.042 r90 bottom
C629 "100nF" "CAP 0201/0603 RF" 197.104,304.165 r90 top
C630 "470nF" "CAP 0402/1005 RF" 176.39,302.031 r90 bottom
C631 "10uF" "CAP 0603/1608 RF" 199.567,300.723 r180 top
C632 "470nF" "CAP 0402/1005 RF" 177.902,306.54 r0 bottom
C633 "3nF" "CAP 0402/1005 RF" 93.442,247.284 r180 top
C634 "330pF" "CAP 0402/1005 RF" 61.028,236.114 r270 bottom
C635 "6.8nF" "CAP 0402/1005 RF" 60.062,236.114 r270 bottom
C636 "3nF" "CAP 0402/1005 RF" 93.332,224.031 r180 top
C637 "1.2nF" "CAP 0402/1005 RF" 87.909,190.2 r270 top
C638 "1.2nF" "CAP 0402/1005 RF" 89.332,174.38 r270 top
C639 "47nF" "CAP 0402/1005 RF" 66.141,183.759 r270 top
C640 "47nF" "CAP 0402/1005 RF" 66.161,175.503 r90 top
C641 "470pF" "CAP 0402/1005 RF" 64.175,175.557 r90 top
C642 "56pF" "CAP 0402/1005 RF" 64.175,183.66 r270 top
C643 "8.2nF" "CAP 0402/1005 RF" 63.51,173.949 r180 top
C644 "820pF" "CAP 0402/1005 RF" 63.565,185.176 r180 top
C645 "1.2nF" "CAP 0402/1005 RF" 88.354,202.857 r180 top
C646 "1.2nF" "CAP 0402/1005 RF" 84.112,207.488 r0 top
C647 "47nF" "CAP 0402/1005 RF" 63.953,210.654 r270 top
C648 "47nF" "CAP 0402/1005 RF" 63.741,202.373 r90 top
C649 "100nF" "CAP 0402/1005 RF" 170.726,320.189 r90 bottom
C650 "180pF" "CAP 0402/1005 RF" 62.828,202.374 r90 top
C651 "100nF" "CAP 0402/1005 RF" 171.635,320.189 r90 bottom
C652 "2.2nF" "CAP 0402/1005 RF" 61.925,200.059 r90 top
C653 "100nF" "CAP 0402/1005 RF" 141.944,313.674 r180 top
C654 "100nF" "CAP 0402/1005 RF" 374.205,55.74 r0 top
C655 "5.6nF" "CAP 0402/1005 RF" 105.362,254.83 r0 top
C656 "5.6nF" "CAP 0402/1005 RF" 99.88,254.796 r0 top
C657 "5.6nF" "CAP 0402/1005 RF" 93.466,253.617 r0 top
C658 "100nF" "CAP 0402/1005 RF" 252.87,228.816 r0 top
C659 "4.7uF" "CAP 0603/1608 RF" 245.707,207.632 r180 bottom
C660 "100nF" "CAP 0402/1005 RF" 243.891,216.675 r270 top
C661 "4.7uF" "CAP 0603/1608 RF" 237.109,223.178 r270 top
C662 "100nF" "CAP 0402/1005 RF" 235.788,223.097 r270 top
C663 "27pF" "CAP 0402/1005 RF" 253.801,215.824 r0 top
C664 "27pF" "CAP 0402/1005 RF" 253.712,221.171 r180 top
C665 "100nF" "CAP 0402/1005 RF" 243.307,227.978 r180 top
C666 "100nF" "CAP 0402/1005 RF" 242.595,218.682 r270 top
C667 "100nF" "CAP 0402/1005 RF" 241.821,216.693 r270 top
C668 "100nF" "CAP 0402/1005 RF" 242.221,202.82 r180 bottom
C669 "100nF" "CAP 0402/1005 RF" 242.221,204.124 r180 bottom
C670 "100nF" "CAP 0402/1005 RF" 242.221,205.427 r180 bottom
C671 "100nF" "CAP 0402/1005 RF" 242.221,206.731 r180 bottom
C672 "Capacitor_1210" CAPC3326X17L 239.992,222.04 r90 bottom
C673 "100nF" "CAP 0402/1005 RF" 243.446,229.324 r180 top
C674 "4.7uF" "CAP 0402/1005 RF" 134.297,233.837 r180 top
C675 "4.7uF" "CAP 0402/1005 RF" 134.297,235.893 r180 top
C676 "4.7uF" "CAP 0402/1005 RF" 374.231,50.521 r0 top
C677 "100nF" "CAP 0402/1005 RF" 141.944,314.574 r180 top
C678 "100uF" "CAP 1206/3216" 200.596,159.284 r90 top
C679 "100uF" "CAP 1206/3216" 197.637,159.208 r90 top
C680 "1uF" "CAP 0402/1005 RF" 198.895,177.56 r0 top
C681 "100nF" "CAP 0402/1005 RF" 217.983,230.822 r0 top
C682 "100nF" "CAP 0402/1005 RF" 182.194,277.698 r270 top
C684 "100nF" "CAP 0402/1005 RF" 176.619,271.272 r270 top
C686 "100nF" "CAP 0402/1005 RF" 171.963,286.995 r180 top
C687 "100nF" "CAP 0402/1005 RF" 171.826,283.578 r180 top
C688 "100nF" "CAP 0402/1005 RF" 168.77,284.353 r0 top
C689 "100nF" "CAP 0402/1005 RF" 168.909,287.02 r0 top
C690 "100nF" "CAP 0402/1005 RF" 205.175,273.723 r270 top
C693 "470nF" "CAP 0402/1005 RF" 39.98,209.427 r90 top
C694 "4.7uF" "CAP 0603/1608 RF" 18.637,238.218 r0 top
C695 "10uF" "CAP 0805/2012 RF" 51.294,206.694 r180 top
C696 "10uF" "CAP 0805/2012 RF" 51.294,202.914 r180 top
C697 "10uF" "CAP 0805/2012 RF" 51.294,204.804 r180 top
C698 "10uF" "CAP 0805/2012 RF" 51.294,208.585 r180 top
C699 "10uF" "CAP 0805/2012 RF" 51.294,201.023 r180 top
C700 "1uF" "CAP 0402/1005 RF" 18.637,239.357 r0 top
C701 "12nF" "CAP 0402/1005 RF" 41.097,200.511 r90 top
C702 "36pF" "CAP 0402/1005 RF" 40.17,200.511 r90 top
C703 "15nF" "CAP 0402/1005 RF" 42.517,204.097 r180 top
C704 "1uF" "CAP 0603/1608 RF" 40.157,198.45 r180 top
C705 "10uF" "CAP 0603/1608 RF" 222.045,323.494 r0 top
C706 "10nF" "CAP 0201/0603 RF" 184.219,282.55 r180 top
C707 "10uF" "CAP 0805/2012 RF" 259.183,333.794 r0 top
C708 "10uF" "CAP 0805/2012 RF" 250.534,333.794 r0 top
C709 "10uF" "CAP 0603/1608 RF" 245.988,333.997 r0 top
C710 "10nF" "CAP 0201/0603 RF" 236.679,334.327 r0 top
C711 "100nF" "CAP 0402/1005 RF" 216.682,316.433 r0 top
C712 "100nF" "CAP 0402/1005 RF" 228.36,334.175 r0 top
C713 "100nF" "CAP 0402/1005 RF" 116.287,351.231 r180 top
C714 "330nF" "CAP 0603/1608 RF" 119.177,351.206 r0 top
C715 "100nF" "CAP 0402/1005 RF" 141.944,316.674 r180 top
C716 "100nF" "CAP 0402/1005 RF" 141.944,317.575 r180 top
C717 "100nF" "CAP 0402/1005 RF" 168.542,320.189 r90 bottom
C718 "100nF" "CAP 0402/1005 RF" 169.451,320.189 r90 bottom
C719 "1nF" "CAP 0201/0603 RF" 128.93,231.655 r90 top
C720 "1uF" "CAP 0402/1005 RF" 146.52,349.06 r90 top
C721 "1uF" "CAP 0402/1005 RF" 147.511,349.06 r90 top
C722 "1uF" "CAP 0402/1005 RF" 153.683,349.142 r90 top
C723 "1uF" "CAP 0402/1005 RF" 154.673,349.142 r90 top
C724 "10nF" "CAP 0201/0603 RF" 49.544,536.58 r0 top
C725 "10nF" "CAP 0201/0603 RF" 49.544,537.566 r0 top
C726 "10nF" "CAP 0201/0603 RF" 65.144,533.64 r0 top
C727 "10nF" "CAP 0201/0603 RF" 65.144,534.792 r0 top
C728 "100nF" "CAP 0402/1005 RF" 205.454,288.027 r90 top
C729 "100nF" "CAP 0402/1005 RF" 202.425,288.052 r270 top
C730 "100nF" "CAP 0402/1005 RF" 156.889,299.371 r270 top
C731 "2.2uF" "CAP 0402/1005 RF" 47.672,345.123 r0 top
C732 "100nF" "CAP 0402/1005 RF" 44.245,343.078 r0 top
C733 "1uF" "CAP 0402/1005 RF" 135.319,200.787 r90 top
C734 "1uF" "CAP 0402/1005 RF" 41.072,339.61 r90 top
C735 "100nF" "CAP 0402/1005 RF" 460.87,179.032 r90 top
C736 "9pF" "CAP 0201/0603 RF" 57.264,355.733 r270 bottom
C737 "9pF" "CAP 0201/0603 RF" 51.854,355.549 r90 bottom
C738 "6TPE680MI" "CAP POL 2917/7343" 144.564,284.861 r270 bottom
C739 "100uF" "CAP 1210/3225 - 1MM" 149.428,293.649 r0 bottom
C740 "4.7uF" "CAP 0402/1005 RF" 179.387,295.021 r90 bottom
C741 "4.7uF" "CAP 0402/1005 RF" 159.918,277.794 r90 top
C742 "100uF" "CAP 1210/3225 - 1MM" 263.893,271.894 r90 top
C743 "4.7uF" "CAP 0402/1005 RF" 266.522,270.896 r270 top
C744 "47uF" "CAP 1206/3216 - 0.8MM" 149.441,290.157 r180 bottom
C745 "4.7uF" "CAP 0402/1005 RF" 180.911,305.537 r0 bottom
C746 "4.7uF" "CAP 0402/1005 RF" 134.297,234.865 r180 top
C747 "100uF" "CAP 1210/3225 - 1MM" 265.997,319.591 r90 top
C748 "4.7uF" "CAP 0402/1005 RF" 262.669,319.706 r270 top
C749 "47uF" "CAP 1206/3216 - 0.8MM" 155.753,285.612 r270 top
C750 "4.7uF" "CAP 0402/1005 RF" 231.951,319.325 r90 top
C751 "100uF" "CAP 1210/3225 - 1MM" 149.368,297.37 r0 bottom
C752 "4.7uF" "CAP 0402/1005 RF" 175.387,300.047 r270 bottom
C753 "100uF" "CAP 1210/3225 - 1MM" 207.67,318.29 r90 top
C754 "4.7uF" "CAP 0402/1005 RF" 206.836,314.392 r90 top
C755 "4.7uF" "CAP 0402/1005 RF" 208.534,314.392 r90 top
C756 "47uF" "CAP 1206/3216 - 0.8MM" 488.683,267.03 r90 top
C757 "100uF" "CAP 1210/3225 - 1MM" 158.966,285.56 r90 top
C758 "4.7uF" "CAP 0402/1005 RF" 229.361,318.746 r90 top
C759 "47uF" "CAP 1206/3216 - 0.8MM" 485.762,267.221 r90 top
C760 "100uF" "CAP 1210/3225 - 1MM" 161.874,276.784 r270 top
C761 "4.7uF" "CAP 0402/1005 RF" 163.792,277.794 r90 top
C762 "100uF" "CAP 1210/3225 - 1MM" 149.339,301.028 r0 bottom
C763 "4.7uF" "CAP 0402/1005 RF" 172.899,304.533 r180 bottom
C764 "100uF" "CAP 1210/3225 - 1MM" 136.296,158.811 r90 top
C765 "4.7uF" "CAP 0402/1005 RF" 140.119,157.274 r90 top
C766 "22uF" "CAP 1210/3225 - 1MM" 73.992,159.249 r270 top
C767 "22uF" "CAP 1210/3225 - 1MM" 70.524,159.25 r270 top
C768 "22uF" "CAP 1210/3225 - 1MM" 67.084,159.249 r270 top
C769 "22uF" "CAP 1210/3225 - 1MM" 63.68,159.249 r270 top
C770 "100nF" "CAP 0402/1005 RF" 38.538,159.341 r270 top
C771 "100nF" "CAP 0402/1005 RF" 37.531,159.341 r270 top
C772 "100nF" "CAP 0402/1005 RF" 36.624,159.341 r270 top
C773 "100nF" "CAP 0402/1005 RF" 35.693,159.341 r270 top
C774 "10uF" "CAP 0805/2012 RF" 51.366,221.852 r0 top
C775 "10uF" "CAP 0805/2012 RF" 51.366,220.038 r0 top
C776 "10uF" "CAP 0805/2012 RF" 51.366,218.215 r0 top
C777 "10uF" "CAP 0805/2012 RF" 51.366,216.47 r0 top
C778 "4.7uF" "CAP 0805/2012 RF" 51.366,214.657 r0 top
C779 "4.7uF" "CAP 0805/2012 RF" 51.366,212.847 r0 top
C780 "4.7uF" "CAP 0805/2012 RF" 51.366,210.952 r0 top
C781 "4.7uF" "CAP 0805/2012 RF" 56.629,197.434 r90 top
C782 "4.7uF" "CAP 0402/1005 RF" 203.623,349.327 r90 top
C783 "100nF" "CAP 0402/1005 RF" 201.376,349.377 r90 top
C784 "4.7uF" "CAP 0402/1005 RF" 202.468,349.352 r90 top
C785 "100nF" "CAP 0402/1005 RF" 196.943,349.384 r90 top
C786 "4.7uF" "CAP 0402/1005 RF" 198.023,349.359 r90 top
C787 "100nF" "CAP 0402/1005 RF" 204.703,349.302 r90 top
C788 "4.7uF" "CAP 0402/1005 RF" 199.204,349.397 r90 top
C789 "100nF" "CAP 0402/1005 RF" 200.271,349.397 r90 top
C790 "100nF" "CAP 0402/1005 RF" 255.918,348.377 r270 bottom
C791 "100nF" "CAP 0402/1005 RF" 252.899,227.609 r0 top
C792 "100nF" "CAP 0402/1005 RF" 375.602,226.987 r90 top
C793 "100nF" "CAP 0402/1005 RF" 153.886,299.371 r270 top
C796 "100nF" "CAP 0402/1005 RF" 196.24,280.994 r90 top
C797 "100nF" "CAP 0402/1005 RF" 199.809,281.153 r270 top
C798 "100nF" "CAP 0402/1005 RF" 154.564,267.932 r90 top
C799 "100nF" "CAP 0402/1005 RF" 151.427,267.941 r270 top
C800 "100nF" "CAP 0402/1005 RF" 261.55,282.393 r90 bottom
C801 "100nF" "CAP 0402/1005 RF" 225.717,276.936 r270 top
C802 "100nF" "CAP 0402/1005 RF" 228.829,276.8 r90 top
C805 "100nF" "CAP 0402/1005 RF" 169.608,281.515 r90 top
C806 "100nF" "CAP 0402/1005 RF" 166.814,281.521 r270 top
C807 "100nF" "CAP 0402/1005 RF" 198.925,290.385 r90 top
C808 "100nF" "CAP 0402/1005 RF" 195.356,290.411 r270 top
C811 "100nF" "CAP 0402/1005 RF" 206.439,267.229 r270 top
C812 "100nF" "CAP 0402/1005 RF" 209.702,267.428 r90 top
C813 "100nF" "CAP 0402/1005 RF" 200.774,265.947 r270 top
C814 "100nF" "CAP 0402/1005 RF" 204.064,265.947 r90 top
C815 "100nF" "CAP 0402/1005 RF" 194.988,263.847 r270 top
C816 "100nF" "CAP 0402/1005 RF" 198.036,263.847 r90 top
C817 "100nF" "CAP 0402/1005 RF" 200.44,262.107 r270 top
C818 "100nF" "CAP 0402/1005 RF" 203.501,262.184 r90 top
C819 "100nF" "CAP 0402/1005 RF" 166.997,285.839 r180 top
C820 "100nF" "CAP 0402/1005 RF" 166.853,283.794 r180 top
C821 "100nF" "CAP 0402/1005 RF" 153.391,295.538 r90 top
C822 "100nF" "CAP 0402/1005 RF" 155.702,295.538 r90 top
D1 "SLVU2.8-4BTG TVS Array" SLVU2.8-4 65.278,250.254 r180 top
D2 "SLVU2.8-4BTG TVS Array" SLVU2.8-4 65.278,256.337 r180 top
D3 "DF01S2" "DF005S2 - DF10S2" 44.298,228.282 r90 bottom locked
D4 "DF01S2" "DF005S2 - DF10S2" 34.43,228.346 r90 bottom locked
D5 "LTST-C190GKT" "LED 0603/1608 GREEN" 192.916,363.868 r0 bottom
D6 "LTST-C190GKT" "LED 0603/1608 GREEN" 192.916,361.831 r0 bottom
D7 "LTST-C190GKT" "LED 0603/1608 GREEN" 192.916,360.007 r0 bottom
D8 "LTST-C190GKT" "LED 0603/1608 GREEN" 192.916,356.362 r0 bottom
D9 "LTST-C190GKT" "LED 0603/1608 GREEN" 192.916,358.229 r180 bottom
D10 "LTST-C190GKT" "LED 0603/1608 GREEN" 326.085,281.516 r270 bottom
D11 "BAT54T1G" BAT54T1G 326.377,272.999 r180 bottom
D12 "BAT54T1G" BAT54T1G 326.238,270.091 r180 bottom
D13 "TPD2EUSB30DRTR" TPD2EUSB30 41.148,350.698 r0 bottom
D14 "TPD4EUSB30DQAR" TPD4EUSB30 42.291,350.761 r180 top
D15 "TPD2EUSB30DRTR" TPD2EUSB30 246.024,218.402 r90 top
D16 "MBRM140T3" "CASE 457" 166.424,166.813 r0 top
D17 "MBRM140T3" "CASE 457" 166.423,170.7 r0 top
D18 "MBRM140T3" "CASE 457" 169.724,175.069 r0 top
D19 "MBRM140T3" "CASE 457" 169.724,161.863 r0 top
D20 "S1M-13-F" S1M-13-F 211.142,172.137 r90 top
D21 "S1M-13-F" S1M-13-F 193.826,165.452 r180 top
D23 "S1M-13-F" S1M-13-F 193.826,165.952 r0 bottom
D24 "S1M-13-F" S1M-13-F 193.954,169.495 r0 bottom
D26 "DFLS1100-7" DFLS1100 34.353,210.071 r270 top
D27 "DFLS1100-7" DFLS1100 44.666,214.084 r270 top
D28 "BAS40-04-TP" BAS40-04-TP 146.24,326.314 r270 top
F1_PCIE0 "Current" "RES 0805/2012 RF" 162.789,377.584 r90 top (schematic designator F1)
F1_PCIE1 "Current" "RES 0805/2012 RF" 235.407,258.039 r90 top (schematic designator F1)
F1_PCIE2 "Current" "RES 0805/2012 RF" 243.205,375.425 r90 top (schematic designator F1)
F1_PCIE3 "Current" "RES 0805/2012 RF" 77.025,372.961 r90 top (schematic designator F1)
F1_PCIE4 "Current" "RES 0805/2012 RF" 153.987,258.762 r90 top (schematic designator F1)
FB2 "220Ohm" "FER 0603/1608" 208.374,476.355 r90 top
FB3 "220Ohm" "FER 0603/1608" 201.955,479.026 r180 top
FB4 "220Ohm" "FER 0603/1608" 210.152,476.355 r90 top
FB5 "220Ohm" "FER 0603/1608" 198.312,480.423 r180 top
FB6 "220Ohm" "FER 0603/1608" 197.637,475.978 r180 top
FB7 "220Ohm" "FER 0603/1608" 201.955,480.677 r180 top
FB8 "220R" "FER 0603/1608" 148.532,216.525 r0 top
FB9 "220R" "FER 0603/1608" 168.961,228.993 r180 top
FB10 "220R" "FER 0603/1608" 160.969,216.897 r90 top
FB11 "220R" "FER 0603/1608" 143.924,229.212 r0 top
FB12 "220R" "FER 0603/1608" 156.896,212.528 r90 top
FB13 "220R" "FER 0603/1608" 146.609,235.867 r270 top
FB14 "220R" "FER 0603/1608" 152.622,212.528 r90 top
FB15 "220R" "FER 0603/1608" 157.404,240.127 r270 top
FB16 "220R" "FER 0603/1608" 168.961,224.318 r180 top
FB17 "220R" "FER 0603/1608" 154.534,245.097 r270 top
FB18 "220R" "FER 0603/1608" 168.961,226.665 r180 top
FB19 "220R" "FER 0603/1608" 168.961,221.966 r180 top
FB20 "220R" "FER 0603/1608" 143.902,225.818 r0 top
FB21 "220R" "FER 0603/1608" 154.622,212.528 r90 top
FB22 "220R" "FER 0603/1608" 143.902,223.318 r0 top
FB23 "Ferrite Chip" "FER 0603/1608" 41.573,543.674 r0 top
FB24 "Ferrite Chip" "FER 0603/1608" 71.389,522.465 r0 top
FB25 "Ferrite Chip" "FER 0603/1608" 123.533,326.369 r90 top
FB26 "220R" "FER 0603/1608" 41.948,355.864 r270 top
FB27 "220R" "FER 0603/1608" 41.93,345.237 r90 top
FB28 "220R" "FER 0603/1608" 28.854,361.315 r0 top
FB29 "220R" "FER 0603/1608" 126.606,326.288 r90 bottom
FB31 "220R" "FER 0603/1608" 248.412,225.463 r270 top
FB32 "220R" "FER 0603/1608" 243.37,225.323 r270 top
FB33 "120R" "FER 0603/1608" 348.992,360.026 r90 top
FB34 "330R" "FER 0603/1608" 35.903,506.463 r0 top
FB35 "220Ohm" "FER 0603/1608" 81.153,527.977 r90 top
FB36 "220R" "FER 0603/1608" 160.477,212.001 r270 top
FB37 "220R" "FER 0603/1608" 147.253,212.238 r270 top
FB38 "600R" "FER 0805/2012" 201.358,309.448 r180 top
FB39 "600R" "FER 0805/2012" 199.568,307.149 r180 top
FB40 "600R" "FER 0805/2012" 199.579,304.749 r180 top
FB41 "600R" "FER 0805/2012" 203.53,301.765 r90 top
FB42 "120R" "FER 0603/1608" 199.593,302.489 r180 top
FB43 "220R" "FER 0603/1608" 245.792,209.131 r180 bottom
FB44 "220R" "FER 0603/1608" 240.182,225.679 r90 top
FB45 "120R" "FER 0603/1608" 132.702,237.553 r0 top
J1_PCIE0 "2041262-1" "PCI Express / PCI Connectors Mini PCI-E 6.8H G/F - z otowrami" 161.187,362.892 r180 bottom locked (schematic designator J1)
J1_PCIE1 "2041262-1" "PCI Express / PCI Connectors Mini PCI-E 6.8H G/F - z otowrami" 236.24,267.894 r0 bottom locked (schematic designator J1)
J1_PCIE2 "2041262-1" "PCI Express / PCI Connectors Mini PCI-E 6.8H G/F - z otowrami" 243.54,362.892 r180 bottom locked (schematic designator J1)
J1_PCIE3 "2041262-1" "PCI Express / PCI Connectors Mini PCI-E 6.8H G/F - z otowrami" 78.835,362.892 r180 bottom locked (schematic designator J1)
J1_PCIE4 "2041262-1" "PCI Express / PCI Connectors Mini PCI-E 6.8H G/F - z otowrami" 153.887,267.894 r0 bottom locked (schematic designator J1)
J2 "5-1814832-1" TECO-5-1814832-1_V 116.902,432.905 r90 top
J3 "5-1814832-1" TECO-5-1814832-1_V 116.902,441.185 r90 top
J4 "1909763-1" TECO-1909763-1_V 268.699,279.997 r0 bottom
J5 "1909763-1" TECO-1909763-1_V 268.648,285.547 r180 bottom
J6 "5-1814832-1" TECO-5-1814832-1_V 259.183,182.432 r90 bottom
J7 "5-1814832-1" TECO-5-1814832-1_V 259.183,173.415 r90 bottom
J12 "MOLEX - 22-27-2021 - WIRE-BOARD CONNECTOR HEADER 2 POSITION, 2.54MM" "MOLEX KK 0022272021" 56.439,332.93 r270 top
J13 "MOLEX - 22-27-2021 - WIRE-BOARD CONNECTOR HEADER 2 POSITION, 2.54MM" "MOLEX KK 0022272021" 56.446,325.158 r270 bottom
J14 "7 Pin" "JST XH B7B-XH-A" 34.455,371.876 r270 bottom
J15 "MOLEX - 22-27-2021 - WIRE-BOARD CONNECTOR HEADER 2 POSITION, 2.54MM" "MOLEX KK 0022272021" 198.196,400.704 r0 top
J16 "MOLEX - 22-27-2021 - WIRE-BOARD CONNECTOR HEADER 2 POSITION, 2.54MM" "MOLEX KK 0022272021" 116.548,362.572 r0 top
J17 "MOLEX - 22-27-2021 - WIRE-BOARD CONNECTOR HEADER 2 POSITION, 2.54MM" "MOLEX KK 0022272021" 198.196,410.519 r0 top
J18 "7 Pin" "JST XH B7B-XH-A" 38.757,326.657 r0 bottom
J19 "MOLEX - 22-27-2021 - WIRE-BOARD CONNECTOR HEADER 2 POSITION, 2.54MM" "MOLEX KK 0022272021" 198.196,420.334 r0 top
J20 "MOLEX - 22-27-2021 - WIRE-BOARD CONNECTOR HEADER 2 POSITION, 2.54MM" "MOLEX KK 0022272021" 198.196,430.149 r0 top
J21 "MOLEX - 22-27-2021 - WIRE-BOARD CONNECTOR HEADER 2 POSITION, 2.54MM" "MOLEX KK 0022272021" 110.477,253.771 r0 bottom
J22 "MOLEX - 22-27-2021 - WIRE-BOARD CONNECTOR HEADER 2 POSITION, 2.54MM" "MOLEX KK 0022272021" 198.196,381.074 r0 top
J23 "MOLEX - 22-27-2021 - WIRE-BOARD CONNECTOR HEADER 2 POSITION, 2.54MM" "MOLEX KK 0022272021" 34.799,388.112 r270 bottom
J24 "MOLEX - 22-27-2021 - WIRE-BOARD CONNECTOR HEADER 2 POSITION, 2.54MM" "MOLEX KK 0022272021" 34.799,396.913 r270 bottom
J25 "JST (JAPAN SOLDERLESS TERMINALS) - B4B-XH-A (LF)(SN) - Wire-To-Board-Steckverbinder, vertikal, 2.5 mm, 4 Kontakt(e), Stiftleiste, Baureihe XH" "JST XH B4B-XH-A" 199.336,230.55 r90 bottom
J26 "5-1814832-1" TECO-5-1814832-1_V 31.966,524.624 r90 bottom
J27 "Key M-SATA CHINA" "M.2 KEY M - NVMe" 141.668,316.624 r270 bottom locked
J28 "693071020811" 693071020811 119.487,337.182 r90 bottom locked
J29 "SYSMON_VP_VN" "MOLEX KK 0022272021" 240.017,327.762 r0 top
J30 "SYSMON_VP_VN" "MOLEX KK 0022272021" 229.108,340.081 r270 top
J31 "SFP Connector" 2007132 37.104,262.472 r90 bottom locked
J32 "1703820001" 1703820001 63.005,279.047 r90 bottom locked
J33 "1703820001" 1703820001 63.005,307.547 r90 bottom locked
J34 "1703820001" 1703820001 63.005,264.797 r90 bottom locked
J35 "1703820001" 1703820001 63.004,293.297 r90 bottom locked
J36 "MOLEX - 22-27-2021 - WIRE-BOARD CONNECTOR HEADER 2 POSITION, 2.54MM" "MOLEX KK 0022272021" 192.799,159.817 r270 bottom
L1 "NRS4018T4R7MDGJV" NRS8040 62.992,285.258 r0 top
L2 "NRS4018T4R7MDGJV" NRS8040 73.051,277.241 r180 top
L3 "NRS4018T4R7MDGJV" NRS8040 62.916,311.582 r0 top
L4 "NRS4018T4R7MDGJV" NRS8040 73.151,307.134 r180 top
L5 "NRS4018T4R7MDGJV" NRS8040 63.185,270.104 r0 top
L6 "NRS4018T4R7MDGJV" NRS8040 73.051,264.465 r180 top
L7 "NRS4018T4R7MDGJV" NRS8040 62.738,297.539 r0 top
L8 "NRS4018T4R7MDGJV" NRS8040 73.151,293.637 r180 top
L9 "MGV0605R22M-10" MGV0605 93.417,240.05 r0 top
L10 "MGV0605R22M-10" MGV0605 93.442,231.202 r0 top
L11 "MGV10041R2M-10" "MGV1004 Series" 89.295,183.236 r0 top
L12 "744373560068" 744373560068 88.108,168.37 r0 top
L13 "CDRH5D28-8R2" CDRH5D28 156.819,165.326 r270 top
L15 "Inductance" FB0603 175.603,173.617 r0 top
L16 "CDRH5D28-4R2" CDRH5D28 156.819,172.367 r90 top
L17 "CDRH5D28-8R2" CDRH5D28 161.461,179.472 r90 top
L18 "CDRH4D28NP-3R3NC" CDRH4D28NP 161.768,158.743 r270 top
L19 "3.3uH, 13.8A" WE-CHSA_1011 87.928,213.721 r0 top
L20 "1.5 uH, 16.5 A" WE-HCC_8070 87.389,197.752 r0 top
L22 "SRP1265A-220M" SRP1265A-220M 37.948,227.19 r90 top locked
MP1_PCIE0 "M2x4.5mm" 9774045243 126.337,408.024 r90 top (schematic designator MP1)
MP1_PCIE1 "M2x4.5mm" 9774045243 271.09,222.762 r90 top (schematic designator MP1)
MP1_PCIE2 "M2x4.5mm" 9774045243 208.69,408.024 r90 top (schematic designator MP1)
MP1_PCIE3 "M2x4.5mm" 9774045243 43.985,408.024 r90 top (schematic designator MP1)
MP1_PCIE4 "M2x4.5mm" 9774045243 188.737,222.762 r90 top (schematic designator MP1)
MP2_PCIE0 "M2x4.5mm" 9774045243 126.337,438.024 r90 top (schematic designator MP2)
MP2_PCIE1 "M2x4.5mm" 9774045243 271.09,192.762 r90 top (schematic designator MP2)
MP2_PCIE2 "M2x4.5mm" 9774045243 208.69,438.024 r90 top (schematic designator MP2)
MP2_PCIE3 "M2x4.5mm" 9774045243 43.985,438.024 r90 top (schematic designator MP2)
MP2_PCIE4 "M2x4.5mm" 9774045243 188.737,192.762 r90 top (schematic designator MP2)
MP3_PCIE0 "M2x4.5mm" 9774045243 188.337,438.024 r90 top (schematic designator MP3)
MP3_PCIE1 "M2x4.5mm" 9774045243 209.09,192.762 r90 top (schematic designator MP3)
MP3_PCIE2 "M2x4.5mm" 9774045243 270.69,438.024 r90 top (schematic designator MP3)
MP3_PCIE3 "M2x4.5mm" 9774045243 105.985,438.024 r90 top (schematic designator MP3)
MP3_PCIE4 "M2x4.5mm" 9774045243 126.737,192.762 r90 top (schematic designator MP3)
MP4_PCIE0 "M2x4.5mm" 9774045243 188.337,408.024 r90 top (schematic designator MP4)
MP4_PCIE1 "M2x4.5mm" 9774045243 209.09,222.762 r90 top (schematic designator MP4)
MP4_PCIE2 "M2x4.5mm" 9774045243 270.69,408.024 r90 top (schematic designator MP4)
MP4_PCIE3 "M2x4.5mm" 9774045243 105.985,408.024 r90 top (schematic designator MP4)
MP4_PCIE4 "M2x4.5mm" 9774045243 126.737,222.762 r90 top (schematic designator MP4)
MP5 "M2x2.5mm" 9774025243 221.669,315.724 r0 top
P1 "Header 3" HDR1X3 203.568,154.407 r0 bottom
P2 "Header 4" HDR1X4 237.071,352.323 r270 top
P3 "Header 2" HDR1X2 327.558,286.029 r90 top
P4 "Header 2" HDR1X2 331.203,288.388 r270 top
P5 "Header 2" HDR1X2 323.85,286.106 r90 top
P6 "640456-2" TECO-640456-2_V 196.799,370.167 r270 top
P7 "Plug" PIN1 34.034,181.709 r0 top
P8 "Plug" PIN1 29.564,181.734 r0 top
P9 "Plug" PIN1 34.092,185.417 r0 top
P10 "Plug" PIN1 29.583,185.201 r0 top
P11 "Header 2" HDR1X2 46.368,199.339 r0 top
P12 "Header 7X2" HDR2X7 198.171,196.669 r90 bottom
P13 "Header 3" HDR1X3 100.343,260.782 r90 bottom
R1 "0mR" "RES 0402/1005 RF" 166.647,242.974 r180 top
R2 "0mR" "RES 0402/1005 RF" 166.649,236.195 r180 top
R3_I2C_Bridge_GPIO "1kR" "RES 0402/1005 RF" 125.807,250.869 r270 top (schematic designator R3)
R3_I2C_Bridge_PCIE "1kR" "RES 0402/1005 RF" 100.82,390.989 r270 top (schematic designator R3)
R3_I2C_Bridge_SFP "1kR" "RES 0402/1005 RF" 85.62,307.942 r270 top (schematic designator R3)
R4_I2C_Bridge_GPIO "1kR" "RES 0402/1005 RF" 127.043,250.869 r270 top (schematic designator R4)
R4_I2C_Bridge_PCIE "1kR" "RES 0402/1005 RF" 101.82,390.989 r270 top (schematic designator R4)
R4_I2C_Bridge_SFP "1kR" "RES 0402/1005 RF" 86.698,307.942 r270 top (schematic designator R4)
R5_I2C_Bridge_GPIO "1kR" "RES 0402/1005 RF" 128.28,250.869 r270 top (schematic designator R5)
R5_I2C_Bridge_PCIE "1kR" "RES 0402/1005 RF" 102.895,390.989 r270 top (schematic designator R5)
R5_I2C_Bridge_SFP "1kR" "RES 0402/1005 RF" 87.775,307.942 r270 top (schematic designator R5)
R6_I2C_Bridge_GPIO "1kR" "RES 0402/1005 RF" 129.517,250.869 r270 top (schematic designator R6)
R6_I2C_Bridge_PCIE "1kR" "RES 0402/1005 RF" 103.955,390.989 r270 top (schematic designator R6)
R6_I2C_Bridge_SFP "1kR" "RES 0402/1005 RF" 88.853,307.942 r270 top (schematic designator R6)
R7_I2C_Bridge_GPIO "1kR" "RES 0402/1005 RF" 130.753,250.869 r270 top (schematic designator R7)
R7_I2C_Bridge_PCIE "1kR" "RES 0402/1005 RF" 105.028,390.989 r270 top (schematic designator R7)
R7_I2C_Bridge_SFP "1kR" "RES 0402/1005 RF" 89.93,307.942 r270 top (schematic designator R7)
R8_I2C_Bridge_GPIO "1kR" "RES 0402/1005 RF" 132.354,247.732 r180 top (schematic designator R8)
R8_I2C_Bridge_PCIE "1kR" "RES 0402/1005 RF" 106.896,388.645 r180 top (schematic designator R8)
R8_I2C_Bridge_SFP "1kR" "RES 0402/1005 RF" 92.188,305.56 r180 top (schematic designator R8)
R9_I2C_Bridge_GPIO "1kR" "RES 0402/1005 RF" 132.354,246.497 r180 top (schematic designator R9)
R9_I2C_Bridge_PCIE "1kR" "RES 0402/1005 RF" 106.896,387.59 r180 top (schematic designator R9)
R9_I2C_Bridge_SFP "1kR" "RES 0402/1005 RF" 92.188,304.586 r180 top (schematic designator R9)
R10_I2C_Bridge_GPIO "1kR" "RES 0402/1005 RF" 132.354,245.261 r180 top (schematic designator R10)
R10_I2C_Bridge_PCIE "1kR" "RES 0402/1005 RF" 106.896,386.535 r180 top (schematic designator R10)
R10_I2C_Bridge_SFP "1kR" "RES 0402/1005 RF" 92.188,303.612 r180 top (schematic designator R10)
R11 "10kR" "RES 0402/1005 RF" 51.56,183.563 r0 top
R12 "95.3kR" "RES 0402/1005 RF" 45.844,173.839 r270 top
R13 "10kR" "RES 0402/1005 RF" 51.568,193.051 r180 top
R14 "1kR" "RES 0402/1005 RF" 139.304,275.821 r0 top
R15 "95.3kR" "RES 0402/1005 RF" 45.94,183.113 r270 top
R16 "1kR" "RES 0402/1005 RF" 139.304,276.846 r0 top
R17 "95.3kR" "RES 0402/1005 RF" 45.94,185.524 r90 top
R18 "24.9kR" "RES 0402/1005 RF" 51.56,184.471 r180 top
R19 "4.87kR" "RES 0402/1005 RF" 44.801,173.839 r90 top
R20 "95.3kR" "RES 0402/1005 RF" 45.822,176.136 r90 top
R21 "24.9kR" "RES 0402/1005 RF" 52.05,175.125 r180 top
R22 "1kR" "RES 0402/1005 RF" 139.304,273.772 r0 top
R23 "4.87kR" "RES 0402/1005 RF" 44.92,183.113 r90 top
R24 "1kR" "RES 0402/1005 RF" 139.304,274.797 r0 top
R25 "4.87kR" "RES 0402/1005 RF" 44.92,185.524 r270 top
R26 "4.87kR" "RES 0402/1005 RF" 44.801,176.136 r270 top
R27 "1.02kR" "RES 0402/1005 RF" 46.46,167.684 r0 top
R28 "1.02kR" "RES 0402/1005 RF" 43.574,176.177 r270 top
R29 "10kR" "RES 0402/1005 RF" 43.904,169.348 r90 top
R30 "10kR" "RES 0402/1005 RF" 44.831,180.9 r180 top
R31 "39.2R" "RES 0402/1005 RF" 174.855,345.25 r90 top
R32 "39.2R" "RES 0402/1005 RF" 170.02,345.25 r90 top
R33 "39.2R" "RES 0402/1005 RF" 158.287,340.144 r180 top
R34 "39.2R" "RES 0402/1005 RF" 158.287,339.055 r180 top
R35 "39.2R" "RES 0402/1005 RF" 173.646,345.25 r90 top
R36 "39.2R" "RES 0402/1005 RF" 167.603,345.25 r90 top
R37 "39.2R" "RES 0402/1005 RF" 158.287,337.967 r180 top
R38 "39.2R" "RES 0402/1005 RF" 162.769,345.25 r90 top
R39 "39.2R" "RES 0402/1005 RF" 171.229,345.25 r90 top
R40 "39.2R" "RES 0402/1005 RF" 166.395,345.25 r90 top
R41 "39.2R" "RES 0402/1005 RF" 158.287,341.233 r180 top
R42 "39.2R" "RES 0402/1005 RF" 172.438,345.25 r90 top
R43 "39.2R" "RES 0402/1005 RF" 178.481,345.25 r90 top
R44 "39.2R" "RES 0402/1005 RF" 163.977,345.25 r90 top
R45 "39.2R" "RES 0402/1005 RF" 158.287,343.411 r180 top
R46 "39.2R" "RES 0402/1005 RF" 158.287,333.611 r180 top
R47 "39.2R" "RES 0402/1005 RF" 177.272,345.25 r90 top
R48 "39.2R" "RES 0402/1005 RF" 158.287,342.322 r180 top
R49 "39.2R" "RES 0402/1005 RF" 168.812,345.25 r90 top
R50 "39.2R" "RES 0402/1005 RF" 176.063,345.25 r90 top
R51 "39.2R" "RES 0402/1005 RF" 158.287,335.789 r180 top
R52 "36R" "RES 0402/1005 RF" 158.287,331.433 r180 top
R53 "39.2R" "RES 0402/1005 RF" 158.287,344.5 r180 top
R54 "36R" "RES 0402/1005 RF" 158.287,332.522 r180 top
R55 "39.2R" "RES 0402/1005 RF" 165.186,345.25 r90 top
R56 "499R" "RES 0402/1005 RF" 162.91,338.184 r180 top
R57 "39.2R" "RES 0402/1005 RF" 158.287,336.878 r180 top
R58 "4.7kR" "RES 0402/1005 RF" 162.91,339.242 r180 top
R59 "39.2R" "RES 0402/1005 RF" 158.287,334.7 r180 top
R60 "1kR" "RES 0402/1005 RF" 184.994,348.704 r180 top
R61 "240R" "RES 0402/1005 RF" 198.031,345.611 r90 top
R62 "240R" "RES 0402/1005 RF" 186.195,345.262 r90 top
R63 "240R" "RES 0402/1005 RF" 161.95,332.842 r180 top
R64 "240R" "RES 0402/1005 RF" 181.458,347.789 r90 top
R65 "4.7kR" "RES 0402/1005 RF" 54.329,285.118 r180 top
R66 "4.7kR" "RES 0402/1005 RF" 54.329,286.047 r180 top
R67 "4.7kR" "RES 0402/1005 RF" 54.329,283.247 r180 top
R68 "4.7kR" "RES 0402/1005 RF" 54.329,284.205 r180 top
R69 "100R" "RES 0402/1005 RF" 162.149,326.956 r0 bottom
R70 "100R" "RES 0402/1005 RF" 157.119,327.139 r0 bottom
R71 "0mR" "RES 0402/1005 RF" 56.183,289.204 r180 top
R72 "0mR" "RES 0402/1005 RF" 56.183,288.188 r180 top
R73 "0mR" "RES 0402/1005 RF" 53.843,289.204 r180 top
R74 "0mR" "RES 0402/1005 RF" 53.843,288.188 r180 top
R75 "0mR" "RES 0402/1005 RF" 146.908,275.654 r180 top
R76 "150R" "RES 0402/1005 RF" 102.019,335.59 r90 bottom
R77 "7.5kR" "RES 0402/1005 RF" 61.036,538.05 r180 top
R78 "100R" "RES 0402/1005 RF" 99.293,334.575 r90 bottom
R79 "150R" "RES 0402/1005 RF" 102.019,333.535 r90 bottom
R80 "160R" "RES 0402/1005 RF" 102.806,339.934 r90 top
R81 "100R" "RES 0402/1005 RF" 103.2,329.628 r90 top
R82 "100R" "RES 0402/1005 RF" 82.347,512.059 r90 top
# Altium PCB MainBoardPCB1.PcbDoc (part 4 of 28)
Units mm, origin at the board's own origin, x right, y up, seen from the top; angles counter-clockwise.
Board outline 258.95 x 308.86 mm, 16 copper layers (L1, L2 (GND), L3 (Sign), L4 (GND), L5 (Sign), L6 (PWR/GND), L7(PWR/GND), L8 (Plane_GND), L9 (PWR/GND), L10 (PWR/GND), L11 (PWR/GND), L12 (Sign), L13 (GND), L14 (Sign), L15 (GND), L16), stack 2.502 mm thick; 2397 components, 1744 nets, 8397 pads, 4112 vias.
Unrouted connection lines stored in the file: 3547.

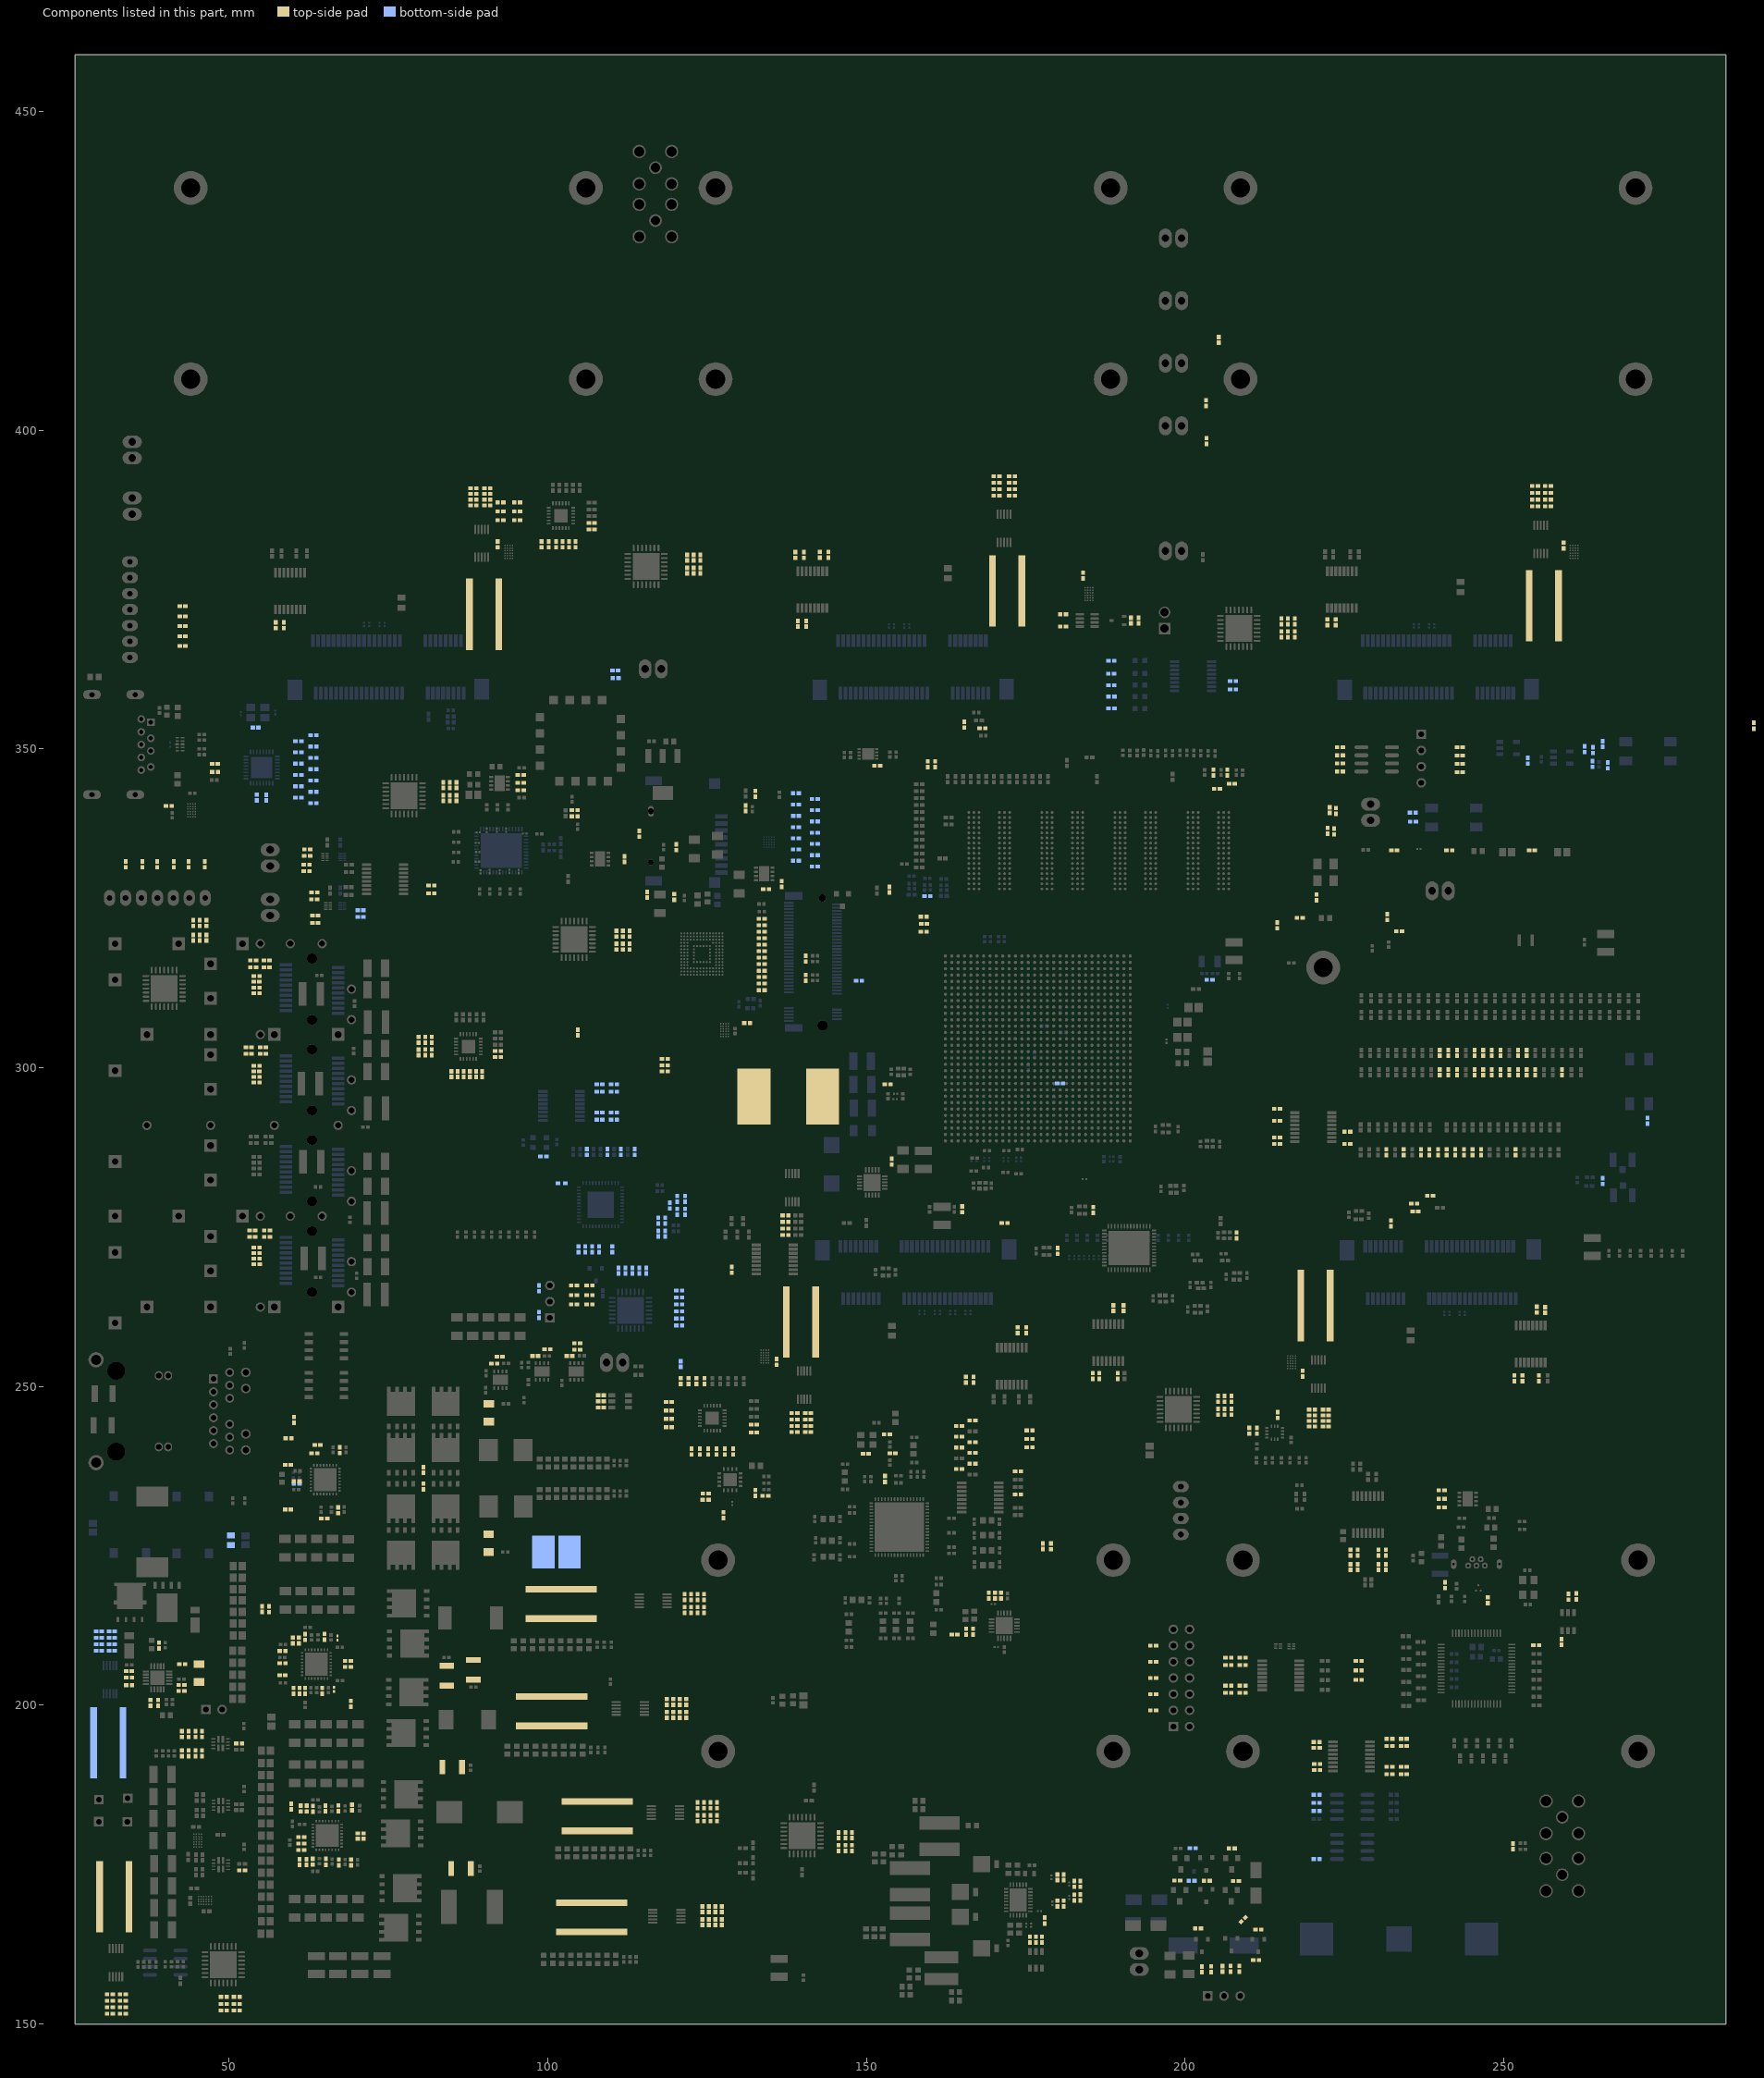
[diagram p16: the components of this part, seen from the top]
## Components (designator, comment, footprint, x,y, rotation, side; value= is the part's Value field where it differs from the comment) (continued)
R83 "4.7kR" "RES 0402/1005 RF" 63.409,327.515 r0 top
R84 "4.7kR" "RES 0402/1005 RF" 63.525,322.724 r0 top
R85 "4.7kR" "RES 0402/1005 RF" 62.261,334.259 r0 top
R86 "4.7kR" "RES 0402/1005 RF" 62.166,330.848 r0 top
R87 "30R" "RES 0402/1005 RF" 138.945,335.989 r180 bottom
R88 "30R" "RES 0402/1005 RF" 138.945,334.231 r180 bottom
R89 "30R" "RES 0402/1005 RF" 138.925,341.312 r180 bottom
R90 "30R" "RES 0402/1005 RF" 141.911,338.645 r180 bottom
R91 "0mR" "RES 0402/1005 RF" 141.911,340.411 r180 bottom
R92 "0mR" "RES 0402/1005 RF" 141.911,342.176 r180 bottom
R93 "0mR" "RES 0402/1005 RF" 138.945,343.065 r180 bottom
R94 "0mR" "RES 0402/1005 RF" 141.911,333.35 r180 bottom
R95 "30R" "RES 0402/1005 RF" 141.911,335.115 r180 bottom
R96 "30R" "RES 0402/1005 RF" 138.945,337.753 r180 bottom
R97 "4.7kR" "RES 0402/1005 RF" 141.911,336.88 r0 bottom
R98 "4.7kR" "RES 0402/1005 RF" 110.661,361.137 r180 bottom
R99 "4.7kR" "RES 0402/1005 RF" 133.579,312.179 r0 top
R101 "30R" "RES 0402/1005 RF" 133.566,322.351 r180 top
R102 "30R" "RES 0402/1005 RF" 133.566,320.319 r180 top
R103 "30R" "RES 0402/1005 RF" 133.566,318.287 r180 top
R104 "30R" "RES 0402/1005 RF" 133.566,316.255 r180 top
R105 "30R" "RES 0402/1005 RF" 133.566,321.335 r180 top
R106 "1kR" "RES 0402/1005 RF" 204.114,158.598 r270 top
R107 "30R" "RES 0402/1005 RF" 133.566,319.303 r180 top
R108 "30R" "RES 0402/1005 RF" 133.566,317.271 r180 top
R109 "1kR" "RES 0402/1005 RF" 208.509,158.674 r270 top
R110 "30R" "RES 0402/1005 RF" 133.566,323.367 r180 top
R111 "30R" "RES 0402/1005 RF" 133.566,315.214 r180 top
R112 "30R" "RES 0402/1005 RF" 133.566,314.223 r180 top
R113 "34.8kR" "RES 0402/1005 RF" 182.642,169.852 r270 top
R114 "10kR" "RES 0402/1005 RF" 183.592,169.86 r90 top
R115 "30R" "RES 0402/1005 RF" 63.251,346.841 r180 bottom
R116 "30R" "RES 0402/1005 RF" 63.251,348.619 r180 bottom
R117 "30R" "RES 0402/1005 RF" 60.877,347.702 r180 bottom
R118 "30R" "RES 0402/1005 RF" 63.251,352.175 r180 bottom
R119 "30R" "RES 0402/1005 RF" 60.877,345.929 r180 bottom
R120 "30R" "RES 0402/1005 RF" 63.251,345.063 r180 bottom
R121 "30R" "RES 0402/1005 RF" 63.251,343.285 r180 bottom
R122 "30R" "RES 0402/1005 RF" 60.877,342.383 r180 bottom
R123 "4.7kR" "RES 0402/1005 RF" 165.621,251.079 r270 top
R124 "1kR" "RES 0402/1005 RF" 173.803,233.083 r0 top
R126 "100R" "RES 0402/1005 RF" 159.572,326.943 r180 bottom
R127 "10kR" "RES 0402/1005 RF" 177.707,224.947 r90 top
R128 "10kR" "RES 0402/1005 RF" 164.528,242.135 r180 top
R129 "10kR" "RES 0402/1005 RF" 164.528,237.058 r0 top
R130 "0mR" "RES 0402/1005 RF" 164.529,243.828 r180 top
R131 "0mR" "RES 0402/1005 RF" 164.529,240.443 r0 top
R132 "0mR" "RES 0402/1005 RF" 166.647,244.669 r180 top
R133 "0mR" "RES 0402/1005 RF" 166.647,241.279 r180 top
R134 "0mR" "RES 0402/1005 RF" 166.647,239.584 r180 top
R135 "4.7kR" "RES 0402/1005 RF" 54.317,313.497 r180 top
R136 "4.7kR" "RES 0402/1005 RF" 54.326,314.403 r180 top
R137 "4.7kR" "RES 0402/1005 RF" 54.329,311.684 r180 top
R138 "4.7kR" "RES 0402/1005 RF" 54.329,312.59 r180 top
R139 "0mR" "RES 0402/1005 RF" 178.964,224.917 r270 top
R140 "2.2R" "RES 0402/1005 RF" 34.297,205.384 r180 top
R141 "0mR" "RES 0402/1005 RF" 55.911,316.827 r180 top
R142 "0mR" "RES 0402/1005 RF" 55.911,315.741 r180 top
R143 "0mR" "RES 0402/1005 RF" 53.772,316.827 r180 top
R144 "0mR" "RES 0402/1005 RF" 53.772,315.759 r180 top
R145 "4.7kR" "RES 0402/1005 RF" 54.344,270.912 r180 top
R146 "4.7kR" "RES 0402/1005 RF" 54.344,271.797 r180 top
R147 "4.7kR" "RES 0402/1005 RF" 54.348,269.173 r180 top
R148 "4.7kR" "RES 0402/1005 RF" 54.344,270.046 r180 top
R149 "196kR" "RES 0402/1005 RF" 34.323,204.343 r0 top
R150 "22k" "RES 0402/1005 RF" 42.652,206.468 r0 top
R151 "0mR" "RES 0402/1005 RF" 55.964,274.472 r180 top
R152 "0mR" "RES 0402/1005 RF" 55.964,273.456 r180 top
R153 "0mR" "RES 0402/1005 RF" 53.655,274.472 r180 top
R154 "0mR" "RES 0402/1005 RF" 53.655,273.456 r180 top
R155 "4.7kR" "RES 0402/1005 RF" 54.317,299.431 r180 top
R156 "4.7kR" "RES 0402/1005 RF" 54.326,300.308 r180 top
R157 "4.7kR" "RES 0402/1005 RF" 54.329,297.677 r180 top
R158 "4.7kR" "RES 0402/1005 RF" 54.329,298.554 r180 top
R159 "10kR" "RES 0402/1005 RF" 34.323,203.149 r0 top
R160 "910R" "RES 0402/1005 RF" 42.528,203.203 r180 top
R161 "0mR" "RES 0402/1005 RF" 55.321,303.205 r180 top
R162 "0mR" "RES 0402/1005 RF" 55.321,302.189 r180 top
R163 "0mR" "RES 0402/1005 RF" 53.082,303.205 r180 top
R164 "0mR" "RES 0402/1005 RF" 53.082,302.189 r180 top
R165 "100R" "RES 0402/1005 RF" 207.348,344.531 r0 top
R166 "100R" "RES 0402/1005 RF" 205.004,343.769 r0 top
R167 "100R" "RES 0402/1005 RF" 206.639,346.325 r90 top
R168 "100R" "RES 0402/1005 RF" 204.48,346.325 r90 top
R169 "100R" "RES 0402/1005 RF" 332.74,379.408 r0 top
R170 "100R" "RES 0402/1005 RF" 328.93,378.392 r0 top
R171 "100R" "RES 0402/1005 RF" 336.537,378.392 r0 top
R172 "100R" "RES 0402/1005 RF" 324.993,377.757 r0 top
R173 "500R" "RES 0402/1005 RF" 171.691,275.641 r180 top
R174 "1kR" "RES 0402/1005 RF" 170.427,390.756 r180 top
R175 "1kR" "RES 0402/1005 RF" 170.427,389.74 r180 top
R176 "1kR" "RES 0402/1005 RF" 170.427,392.788 r180 top
R177 "1kR" "RES 0402/1005 RF" 170.427,391.772 r180 top
R178 "1kR" "RES 0402/1005 RF" 172.84,390.756 r0 top
R179 "1kR" "RES 0402/1005 RF" 172.84,389.74 r0 top
R180 "1kR" "RES 0402/1005 RF" 172.84,392.788 r0 top
R181 "1kR" "RES 0402/1005 RF" 172.84,391.772 r0 top
R182 "1.02kR" "RES 0402/1005 RF" 183.978,377.216 r90 top
R183 "1kR" "RES 0402/1005 RF" 222.087,245.492 r0 top
R184 "1kR" "RES 0402/1005 RF" 222.087,246.381 r0 top
R185 "1kR" "RES 0402/1005 RF" 222.087,243.714 r0 top
R186 "1kR" "RES 0402/1005 RF" 222.087,244.603 r0 top
R187 "1kR" "RES 0402/1005 RF" 219.928,245.492 r180 top
R188 "1kR" "RES 0402/1005 RF" 219.928,246.381 r180 top
R189 "1kR" "RES 0402/1005 RF" 219.928,243.714 r180 top
R190 "1kR" "RES 0402/1005 RF" 219.928,244.603 r180 top
R191 "1.02kR" "RES 0402/1005 RF" 218.456,252.026 r90 top
R192 "1kR" "RES 0402/1005 RF" 254.924,389.134 r180 top
R193 "1kR" "RES 0402/1005 RF" 254.924,388.075 r180 top
R194 "1kR" "RES 0402/1005 RF" 254.924,391.25 r180 top
R195 "1kR" "RES 0402/1005 RF" 254.924,390.192 r180 top
R196 "1kR" "RES 0402/1005 RF" 256.956,389.134 r0 top
R197 "1kR" "RES 0402/1005 RF" 256.956,388.075 r0 top
R198 "1kR" "RES 0402/1005 RF" 256.956,391.25 r0 top
R199 "1kR" "RES 0402/1005 RF" 256.956,390.192 r0 top
R200 "1.02kR" "RES 0402/1005 RF" 259.399,381.94 r270 top
R201 "1kR" "RES 0402/1005 RF" 88.363,389.129 r180 top
R202 "1kR" "RES 0402/1005 RF" 88.363,388.24 r180 top
R203 "1kR" "RES 0402/1005 RF" 88.363,390.907 r180 top
R204 "1kR" "RES 0402/1005 RF" 88.363,390.018 r180 top
R205 "1kR" "RES 0402/1005 RF" 90.522,389.129 r0 top
R206 "1kR" "RES 0402/1005 RF" 90.522,388.24 r0 top
R207 "1kR" "RES 0402/1005 RF" 90.522,390.907 r0 top
R208 "1kR" "RES 0402/1005 RF" 90.522,390.018 r0 top
R209 "1.02kR" "RES 0402/1005 RF" 92.133,382.099 r270 top
R210 "1kR" "RES 0402/1005 RF" 140.841,244.823 r0 top
R211 "1kR" "RES 0402/1005 RF" 140.841,245.818 r0 top
R212 "12.5k" "RES 0402/1005 RF" 182.642,171.965 r90 top
R213 "1kR" "RES 0402/1005 RF" 140.844,242.844 r0 top
R214 "10kR" "RES 0402/1005 RF" 183.592,171.965 r270 top
R215 "1kR" "RES 0402/1005 RF" 140.844,243.828 r0 top
R216 "31.2kR" "RES 0402/1005 RF" 179.984,173.015 r270 top
R217 "1kR" "RES 0402/1005 RF" 138.715,244.823 r180 top
R218 "10kR" "RES 0402/1005 RF" 180.95,173.015 r270 top
R219 "1kR" "RES 0402/1005 RF" 138.714,245.818 r180 top
R220 "4.99kR" "RES 0402/1005 RF" 179.984,168.89 r270 top
R221 "1kR" "RES 0402/1005 RF" 138.715,242.844 r180 top
R222 "1kR" "RES 0402/1005 RF" 138.715,243.828 r180 top
R223_I2C_Bridge_GPIO "1kR" "RES 0402/1005 RF" 132.354,244.026 r180 top (schematic designator R223)
R223_I2C_Bridge_PCIE "1kR" "RES 0402/1005 RF" 106.896,385.48 r180 top (schematic designator R223)
R223_I2C_Bridge_SFP "1kR" "RES 0402/1005 RF" 92.188,302.638 r180 top (schematic designator R223)
R224_I2C_Bridge_GPIO "1kR" "RES 0402/1005 RF" 132.354,242.791 r180 top (schematic designator R224)
R224_I2C_Bridge_PCIE "1kR" "RES 0402/1005 RF" 106.896,384.424 r180 top (schematic designator R224)
R224_I2C_Bridge_SFP "1kR" "RES 0402/1005 RF" 92.188,301.665 r180 top (schematic designator R224)
R225_I2C_Bridge_GPIO "1kR" "RES 0402/1005 RF" 129.09,239.794 r90 top (schematic designator R225)
R225_I2C_Bridge_PCIE "1kR" "RES 0402/1005 RF" 104.356,382.099 r90 top (schematic designator R225)
R225_I2C_Bridge_SFP "1kR" "RES 0402/1005 RF" 89.707,298.998 r90 top (schematic designator R225)
R226_I2C_Bridge_GPIO "1kR" "RES 0402/1005 RF" 127.784,239.794 r90 top (schematic designator R226)
R226_I2C_Bridge_PCIE "1kR" "RES 0402/1005 RF" 103.32,382.099 r90 top (schematic designator R226)
R226_I2C_Bridge_SFP "1kR" "RES 0402/1005 RF" 88.742,298.998 r90 top (schematic designator R226)
R227_I2C_Bridge_GPIO "1kR" "RES 0402/1005 RF" 126.479,239.794 r90 top (schematic designator R227)
R227_I2C_Bridge_PCIE "1kR" "RES 0402/1005 RF" 102.32,382.099 r90 top (schematic designator R227)
R227_I2C_Bridge_SFP "1kR" "RES 0402/1005 RF" 87.777,298.998 r90 top (schematic designator R227)
R228 "1.02kR" "RES 0402/1005 RF" 135.903,253.873 r90 top
R229 "1kR" "RES 0402/1005 RF" 33.32,153.653 r0 top
R230 "1kR" "RES 0402/1005 RF" 33.32,154.669 r0 top
R231_SPI_bridge_Main "1kR" "RES 0402/1005 RF" 225.457,289.983 r0 top (schematic designator R231)
R231_SPI_bridge_PCIe "1kR" "RES 0402/1005 RF" 140.532,369.66 r270 top (schematic designator R231)
R232_SPI_bridge_Main "1kR" "RES 0402/1005 RF" 225.457,288.068 r180 top (schematic designator R232)
R232_SPI_bridge_PCIe "1kR" "RES 0402/1005 RF" 139.232,369.66 r90 top (schematic designator R232)
R233_SPI_bridge_Main "1kR" "RES 0402/1005 RF" 188.754,262.311 r90 top (schematic designator R233)
R233_SPI_bridge_PCIe "1kR" "RES 0402/1005 RF" 255.191,262.064 r90 top (schematic designator R233)
R234_SPI_bridge_Main "1kR" "RES 0402/1005 RF" 190.348,262.311 r270 top (schematic designator R234)
R234_SPI_bridge_PCIe "1kR" "RES 0402/1005 RF" 256.491,262.014 r270 top (schematic designator R234)
R235_SPI_bridge_Main "1kR" "RES 0402/1005 RF" 81.755,327.34 r0 top (schematic designator R235)
R235_SPI_bridge_PCIe "1kR" "RES 0402/1005 RF" 222.34,369.89 r270 top (schematic designator R235)
R236_SPI_bridge_Main "1kR" "RES 0402/1005 RF" 81.755,328.59 r0 top (schematic designator R236)
R236_SPI_bridge_PCIe "1kR" "RES 0402/1005 RF" 223.64,369.89 r270 top (schematic designator R236)
R237_SPI_bridge_Main "1kR" "RES 0402/1005 RF" 54.343,494.982 r0 top (schematic designator R237)
R237_SPI_bridge_PCIe "1kR" "RES 0402/1005 RF" 57.328,369.413 r270 top (schematic designator R237)
R238_SPI_bridge_Main "1kR" "RES 0402/1005 RF" 49.945,495.579 r180 top (schematic designator R238)
R238_SPI_bridge_PCIe "1kR" "RES 0402/1005 RF" 58.613,369.413 r270 top (schematic designator R238)
R239_SPI_bridge_Main "1kR" "RES 0402/1005 RF" 173.803,236.703 r180 top (schematic designator R239)
R239_SPI_bridge_PCIe "1kR" "RES 0402/1005 RF" 175.098,258.849 r270 top (schematic designator R239)
R240_SPI_bridge_Main "1kR" "RES 0402/1005 RF" 166.647,237.889 r180 top (schematic designator R240)
R240_SPI_bridge_PCIe "1kR" "RES 0402/1005 RF" 173.746,258.849 r90 top (schematic designator R240)
R241 "1kR" "RES 0402/1005 RF" 119.006,247.554 r0 top
R242 "0mR" "RES 0402/1005 RF" 119.006,246.246 r180 top
R243 "1kR" "RES 0402/1005 RF" 119.006,244.938 r0 top
R244 "0mR" "RES 0402/1005 RF" 119.006,243.63 r180 top
R245 "100R" "RES 0402/1005 RF" 51.105,533.133 r270 top
R246 "120R" "RES 0402/1005 RF" 46.122,534.168 r270 top
R247 "127R" "RES 0402/1005 RF" 49.932,534.168 r270 top
R248 "127R" "RES 0402/1005 RF" 49.932,532.067 r90 top
R249 "120R" "RES 0402/1005 RF" 46.122,532.067 r270 top
R250 "82.5R" "RES 0402/1005 RF" 48.916,534.168 r270 top
R251 "82.5R" "RES 0402/1005 RF" 48.916,532.067 r90 top
R252 "1kR" "RES 0402/1005 RF" 38.548,530.998 r180 top
R253 "1kR" "RES 0402/1005 RF" 40.552,530.998 r0 top
R254 "1kR" "RES 0402/1005 RF" 38.548,532.014 r0 top
R255 "1kR" "RES 0402/1005 RF" 40.552,532.014 r180 top
R256 "120R" "RES 0402/1005 RF" 57.397,525.716 r180 top
R257 "49.9R" "RES 0402/1005 RF" 56.779,519.869 r180 top
R258 "120R" "RES 0402/1005 RF" 55.46,525.716 r180 top
R259 "82.5R" "RES 0402/1005 RF" 55.46,529.526 r0 top
R260 "82.5R" "RES 0402/1005 RF" 57.397,529.526 r180 top
R261 "127R" "RES 0402/1005 RF" 55.46,528.51 r0 top
R262 "127R" "RES 0402/1005 RF" 57.397,528.51 r180 top
R263 "60.4kR" "RES 0402/1005 RF" 52.958,521.52 r0 top
R264 "0mR" "RES 0402/1005 RF" 52.958,524.03 r0 top
R265 "0mR" "RES 0402/1005 RF" 52.958,522.805 r0 top
R266 "84.5kR" "RES 0402/1005 RF" 60.181,244.78 r90 top
R267 "4.7kR" "RES 0402/1005 RF" 11.786,218.63 r0 top
R268 "2R" "RES 0402/1005 RF" 59.242,237.714 r0 top
R269 "1.02kR" "RES 0402/1005 RF" 131.293,307.022 r0 top
R270 "100R" "RES 0402/1005 RF" 265.511,282.219 r270 bottom
R271 "5kR" "RES 0402/1005 RF" 180.397,297.539 r180 bottom
R272 "2R" "RES 0402/1005 RF" 60.606,235.139 r180 top
R273 "12kR" "RES 0402/1005 RF" 63.389,239.52 r180 top
R274 "10kR" "RES 0402/1005 RF" 180.95,168.894 r90 top
R275 "47kR" "RES 0402/1005 RF" 80.488,236.914 r90 top
R276 "4.7kR" "RES 0402/1005 RF" 214.452,322.344 r270 top
R277 "12kR" "RES 0402/1005 RF" 64.94,229.317 r0 top
R278 "12kR" "RES 0402/1005 RF" 63.889,240.855 r0 top
R279 "0mR" "RES 0402/1005 RF" 222.377,337.185 r270 top
R280 "47kR" "RES 0402/1005 RF" 80.488,234.339 r270 top
R281 "1kR" "RES 0402/1005 RF" 124.57,250.869 r270 top
R282 "0mR" "RES 0402/1005 RF" 222.707,340.416 r270 top
R283 "0mR" "RES 0402/1005 RF" 223.698,340.296 r270 top
R284 "18.2k (1MHz)" "RES 0402/1005 RF" 177.98,166.233 r90 top
R285 "2R" "RES 0402/1005 RF" 59.753,184.12 r270 top
R286 "0mR" "RES 0402/1005 RF" 223.368,337.058 r270 top
R287 "49.9kR" "RES 0402/1005 RF" 61.241,183.809 r90 top
R288 "Resistor_1210" RES_1210 85.014,190.309 r180 top value=3.6R
R289 "2R" "RES 0402/1005 RF" 61.331,179.317 r180 top
R290 "10kR" "RES 0402/1005 RF" 62.191,183.809 r270 top
R291 "150R" "RES 0402/1005 RF" 46.122,536.13 r270 top
R292 "Resistance" "RES 0402/1005 RF" 70.661,179.917 r180 top
R293 "0mR" "RES 0402/1005 RF" 61.331,178.317 r180 top
R294 "0mR" "RES 0402/1005 RF" 61.331,177.317 r180 top
R295 "12kR" "RES 0402/1005 RF" 67.169,183.85 r270 top
R296 "12kR" "RES 0402/1005 RF" 67.204,175.367 r90 top
R297 "10kR" "RES 0402/1005 RF" 62.14,175.401 r270 top
R298 "Resistor_1210" RES_1210 86.39,174.414 r180 top value=3.6R
R299 "47kR" "RES 0402/1005 RF" 70.661,179.067 r180 top
R300 "10kR" "RES 0402/1005 RF" 61.068,175.401 r90 top
R301 "150R" "RES 0402/1005 RF" 46.122,538.016 r90 top
R302 "1.4kR" "RES 0201/0603" 66.453,202.488 r90 top
R303 "2R" "RES 0402/1005 RF" 55.203,215.087 r270 top
R304 "1kR" "RES 0402/1005 RF" 137.316,275.821 r180 top
R305 "100R" "RES 0402/1005 RF" 175.639,163.255 r270 top
R306 "Resistor_1210" RES_1210 88.316,205.562 r90 top value=3.6R
R307 "2R" "RES 0402/1005 RF" 58.395,206.596 r0 top
R308 "100R" "RES 0402/1005 RF" 176.589,163.255 r270 top
R309 "100R" "RES 0402/1005 RF" 177.539,163.255 r270 top
R310 "0mR" "RES 0402/1005 RF" 58.395,208.526 r180 top
R311 "100R" "RES 0402/1005 RF" 208.089,273.723 r90 top
R312 "0mR" "RES 0402/1005 RF" 58.376,204.716 r0 top
R313 "12kR" "RES 0402/1005 RF" 64.953,210.754 r270 top
R314 "12kR" "RES 0402/1005 RF" 64.623,202.273 r90 top
R315 "196kR" "RES 0402/1005 RF" 61.041,202.273 r270 top
R316 "Resistor_1210" RES_1210 84.163,204.643 r270 top value=3.6R
R317 "47kR" "RES 0402/1005 RF" 68.656,206.039 r180 top
R318 "27kR" "RES 0402/1005 RF" 60.114,202.273 r90 top
R319 "10kR" "RES 0402/1005 RF" 120.332,279.437 r90 bottom
R320 "10kR" "RES 0402/1005 RF" 120.332,277.401 r270 bottom
R321 "100R" "RES 0402/1005 RF" 119.139,278.384 r90 bottom
R322 "5.76kR" "RES 0402/1005 RF" 117.334,276.022 r90 bottom
R323 "5.76kR" "RES 0402/1005 RF" 117.334,273.977 r270 bottom
R324 "100kR" "RES 0805/2012 RF" 50.292,225.882 r90 bottom
R325 "2.49kR" "RES 0402/1005 RF" 121.539,279.437 r270 bottom
R326 "2.49kR" "RES 0402/1005 RF" 121.539,277.401 r90 bottom
R327 "2.49kR" "RES 0402/1005 RF" 118.427,276.022 r270 bottom
R328 "2.49kR" "RES 0402/1005 RF" 118.427,273.977 r90 bottom
R329 "100R" "RES 0402/1005 RF" 104.826,271.544 r270 bottom
R330 "100R" "RES 0402/1005 RF" 105.908,271.544 r270 bottom
R331 "100R" "RES 0402/1005 RF" 106.991,271.544 r270 bottom
R332 "100R" "RES 0402/1005 RF" 110.122,271.544 r90 bottom
R333 "2.2kR" "RES 0402/1005 RF" 106.145,286.787 r270 bottom
R334 "11kR" "RES 0402/1005" 102.197,281.889 r180 bottom
R335 "1MR" "RES 0402/1005 RF" 99.32,286.117 r180 bottom
R336 "2.2kR" "RES 0402/1005 RF" 113.633,286.787 r270 bottom
R337 "2.2kR" "RES 0402/1005 RF" 109.354,286.787 r270 bottom
R338 "2.2kR" "RES 0402/1005 RF" 111.494,286.787 r270 bottom
R339 "105kR" "RES 0402/1005 RF" 120.155,334.607 r90 top
R340 "10kR" "RES 0402/1005 RF" 112.037,332.737 r90 top
R341 "15kR" "RES 0402/1005 RF" 114.38,336.692 r90 top
R342 "105kR" "RES 0402/1005 RF" 115.595,327.144 r90 top
R343 "10kR" "RES 0402/1005 RF" 134.277,328.019 r180 top
R344 "15kR" "RES 0402/1005 RF" 119.837,326.801 r90 top
R345 "0mR" "RES 0402/1005 RF" 136.729,328.835 r90 top
R346 "4.7kR" "RES 0402/1005 RF" 227.247,203.962 r180 top
R347 "4.7kR" "RES 0402/1005 RF" 227.247,206.983 r180 top
R348 "4.7kR" "RES 0402/1005 RF" 227.247,205.472 r180 top
R349 "4.7kR" "RES 0402/1005 RF" 243.109,346.354 r0 top
R350 "4.7kR" "RES 0402/1005 RF" 243.109,347.667 r0 top
R351 "4.7kR" "RES 0402/1005 RF" 243.109,348.979 r0 top
R352 "4.7kR" "RES 0402/1005 RF" 243.109,350.291 r0 top
R353 "4.7kR" "RES 0402/1005 RF" 207.518,360.667 r180 bottom
R354 "4.7kR" "RES 0402/1005 RF" 330.975,290.665 r180 top
R355 "4.7kR" "RES 0402/1005 RF" 327.292,290.779 r0 top
R356 "4.7kR" "RES 0402/1005 RF" 235.757,338.633 r0 bottom
R357 "4.7kR" "RES 0402/1005 RF" 207.518,359.346 r0 bottom
R358 "499R" "RES 0402/1005 RF" 224.315,346.481 r180 top
R359 "499R" "RES 0402/1005 RF" 224.315,347.751 r180 top
R360 "499R" "RES 0402/1005 RF" 224.315,349.021 r180 top
R361 "499R" "RES 0402/1005 RF" 224.315,350.291 r180 top
R362 "30R" "RES 0402/1005 RF" 63.251,350.397 r180 bottom
R363 "4.7kR" "RES 0402/1005 RF" 70.63,324.714 r180 bottom
R364 "4.7kR" "RES 0402/1005 RF" 70.63,323.685 r180 bottom
R365 "4.7kR" "RES 0402/1005 RF" 128.892,268.301 r90 top
R366 "10kR" "RES 0402/1005 RF" 175.616,240.479 r0 top
R367 "4.7kR" "RES 0402/1005 RF" 235.744,340.03 r180 bottom
R368 "261R" "RES 0402/1005 RF" 324.599,282.047 r90 top
R369 "10kR" "RES 0402/1005 RF" 320.523,271.932 r270 top
R370 "10kR" "RES 0402/1005 RF" 321.755,271.958 r270 top
R371 "10kR" "RES 0402/1005 RF" 323.393,282.047 r90 top
R372 "8.06kR" "RES 0402/1005 RF" 316.717,275.45 r180 top
R373 "10kR" "RES 0402/1005 RF" 316.717,276.847 r0 top
R374 "4.7MR" "RES 0402/1005 RF" 203.86,313.797 r180 bottom
R375 "40.2R" "RES 0402/1005 RF" 220.65,326.735 r270 top
R376 "0mR" "RES 0402/1005 RF" 60.877,344.156 r0 bottom
R377 "0mR" "RES 0402/1005 RF" 55.855,342.386 r270 bottom
R378 "0mR" "RES 0402/1005 RF" 54.355,342.397 r270 bottom
R379 "8.06kR" "RES 0402/1005 RF" 47.79,347.688 r0 top
R380 "4.22kR" "RES 0402/1005 RF" 40.548,341.072 r0 top
R381 "4.7kR" "RES 0402/1005 RF" 141.911,331.584 r0 bottom
R382 "4.7kR" "RES 0402/1005 RF" 138.963,339.522 r0 bottom
R383 "10kR" "RES 0402/1005 RF" 131.051,340.703 r90 top
R384 "71.5R" "RES 0402/1005 RF" 47.79,536.58 r180 top
R385 "71.5R" "RES 0402/1005 RF" 47.79,537.566 r180 top
R386 "8.87kR" "RES 0402/1005 RF" 52.172,538.023 r270 top
R387 "5.1kR" "RES 0402/1005 RF" 51.13,538.016 r270 top
R388 "1kR" "RES 0402/1005 RF" 137.316,276.846 r180 top
R389 "1kR" "RES 0402/1005 RF" 137.316,273.772 r180 top
R390 "1kR" "RES 0402/1005 RF" 137.316,274.797 r180 top
R391 "75kR" "RES 0402/1005 RF" 103.42,254.796 r180 top
R392 "100kR" "RES 0402/1005 RF" 104.619,256.769 r180 top
R393 "15kR" "RES 0402/1005 RF" 104.62,255.77 r180 top
R394 "51.1kR" "RES 0402/1005 RF" 98.051,254.796 r180 top
R395 "0mR" "RES 0402/1005 RF" 235.964,278.676 r0 top
R396 "15kR" "RES 0402/1005 RF" 99.944,255.867 r180 top
R397 "21.5kR" "RES 0402/1005 RF" 91.606,253.618 r180 top
R398 "0mR" "RES 0402/1005 RF" 236.16,277.47 r0 top
R399 "15kR" "RES 0402/1005 RF" 92.461,254.68 r180 top
R400 "0mR" "RES 0402/1005 RF" 123.333,250.869 r90 top
R401 "10k" "RES 0402/1005 RF" 220.642,175.874 r180 bottom
R402 "0mR" "RES 0402/1005 RF" 206.789,207.472 r0 top
R403 "0mR" "RES 0402/1005 RF" 209.049,207.472 r180 top
R404 "0mR" "RES 0402/1005 RF" 206.789,206.333 r0 top
R405 "0mR" "RES 0402/1005 RF" 209.049,206.333 r180 top
R406 "0mR" "RES 0402/1005 RF" 206.789,203.083 r0 top
R407 "0mR" "RES 0402/1005 RF" 209.049,203.083 r180 top
R408 "0mR" "RES 0402/1005 RF" 206.789,201.944 r0 top
R409 "0mR" "RES 0402/1005 RF" 209.049,201.944 r180 top
R410 "10k" "RES 0402/1005 RF" 220.642,183.418 r180 bottom
R411 "0mR" "RES 0402/1005 RF" 110.394,297.394 r180 bottom
R412 "0mR" "RES 0402/1005 RF" 108.133,297.394 r0 bottom
R413 "0mR" "RES 0402/1005 RF" 110.394,296.255 r180 bottom
R414 "0mR" "RES 0402/1005 RF" 108.133,296.255 r0 bottom
R415 "0mR" "RES 0402/1005 RF" 110.394,293.005 r180 bottom
R416 "0mR" "RES 0402/1005 RF" 108.133,293.005 r0 bottom
R417 "10k" "RES 0402/1005 RF" 261.417,217.076 r270 top
R418 "0mR" "RES 0402/1005 RF" 110.394,291.866 r180 bottom
R419 "2kR" "RES 0402/1005 RF" 255.115,209.431 r0 top
R420 "10k" "RES 0402/1005 RF" 260.159,217.013 r270 top
R421 "0mR" "RES 0402/1005 RF" 108.133,291.866 r0 bottom
R422 "10k" "RES 0402/1005 RF" 259.093,209.926 r270 top
R423 "12kR" "RES 0402/1005 RF" 247.51,216.472 r270 top
R424 "1kR" "RES 0402/1005 RF" 240.805,218.84 r270 top
R425_SPI_bridge_Main "0mR" "RES 0402/1005 RF" 214.452,293.539 r180 top (schematic designator R425)
R425_SPI_bridge_PCIe "0mR" "RES 0402/1005 RF" 144.057,380.477 r90 top (schematic designator R425)
R426_SPI_bridge_Main "0mR" "RES 0402/1005 RF" 214.452,289.052 r0 top (schematic designator R426)
R426_SPI_bridge_PCIe "0mR" "RES 0402/1005 RF" 140.183,380.427 r270 top (schematic designator R426)
R428 "1kR" "RES 0402/1005 RF" 120.86,250.869 r90 top
R429 "0mR" "RES 0402/1005 RF" 214.553,245.515 r90 top
R430_5V_to_3V3_for_FTDI "105kR" "RES 0402/1005 RF" 240.271,231.026 r180 top (schematic designator R430)
R430_U_5V_to_3V31 "105kR" "RES 0402/1005 RF" 360.267,345.625 r270 top (schematic designator R430)
R430_U_5V_to_3V32 "105kR" "RES 0402/1005 RF" 326.428,325.332 r270 top (schematic designator R430)
R430_U_5V_to_3V33 "105kR" "RES 0402/1005 RF" 95.764,345.91 r0 top (schematic designator R430)
R431_5V_to_3V3_for_FTDI "100kR" "RES 0402/1005 RF" 240.271,233.729 r180 top (schematic designator R431)
R431_U_5V_to_3V31 "100kR" "RES 0402/1005 RF" 357.194,345.625 r90 top (schematic designator R431)
R431_U_5V_to_3V32 "100kR" "RES 0402/1005 RF" 324.904,327.558 r90 top (schematic designator R431)
R431_U_5V_to_3V33 "100kR" "RES 0402/1005 RF" 95.764,343.56 r0 top (schematic designator R431)
R432_5V_to_3V3_for_FTDI "15kR" "RES 0402/1005 RF" 240.271,232.378 r0 top (schematic designator R432)
R432_U_5V_to_3V31 "15kR" "RES 0402/1005 RF" 358.667,345.65 r90 top (schematic designator R432)
R432_U_5V_to_3V32 "15kR" "RES 0402/1005 RF" 330.086,323.042 r180 top (schematic designator R432)
R432_U_5V_to_3V33 "15kR" "RES 0402/1005 RF" 95.764,344.678 r180 top (schematic designator R432)
R433 "56kR" "RES 0402/1005 RF" 345.444,359.939 r0 top
R434 "10kR" "RES 0402/1005 RF" 344.834,358.707 r0 top
R435 "10kR" "RES 0402/1005 RF" 124.786,233.243 r180 top
R436 "3.57kR" "RES 0402/1005 RF" 165.659,211.548 r90 top
R437 "1.15kR" "RES 0402/1005 RF" 163.83,211.087 r0 top
R438 "3.57kR" "RES 0402/1005 RF" 170.181,217.2 r90 top
R439 "1.15kR" "RES 0402/1005 RF" 169.215,217.2 r270 top
R440 "20kR" "RES 0402/1005 RF" 166.736,211.548 r90 top
R441 "20kR" "RES 0402/1005 RF" 171.128,217.2 r90 top
R442 "100kR" "RES 0402/1005 RF" 39.725,505.754 r90 top
R443 "698kR" "RES 0805/2012 RF" 46.507,506.323 r90 top
R444 "49.9kR" "RES 0402/1005 RF" 43.075,503.93 r0 top
R445 "49.9kR" "RES 0402/1005 RF" 45.021,506.096 r270 top
R446 "120R" "RES 0402/1005 RF" 191.516,370.167 r90 top
R447 "120R" "RES 0402/1005 RF" 192.684,370.167 r90 top
R448_U_Pomiar_pradu_napiecia_1 "FCSL110R005FER" FCSL110R005FERCT-ND 31.979,169.964 r0 top (schematic designator R448)
R448_U_Pomiar_pradu_napiecia_2 "FCSL110R005FER" FCSL110R005FERCT-ND 31.033,194.11 r0 bottom (schematic designator R448)
R448_U_Pomiar_pradu_napiecia_3 "FCSL110R005FER" FCSL110R005FERCT-ND 107.759,182.601 r90 top (schematic designator R448)
R448_U_Pomiar_pradu_napiecia_4 "FCSL110R005FER" FCSL110R005FERCT-ND 106.904,166.738 r90 top (schematic designator R448)
R448_U_Pomiar_pradu_napiecia_5 "FCSL110R005FER" FCSL110R005FERCT-ND 102.092,215.887 r90 top (schematic designator R448)
R448_U_Pomiar_pradu_napiecia_6 "FCSL110R005FER" FCSL110R005FERCT-ND 100.635,199.06 r90 top (schematic designator R448)
R448_U_Pomiar_pradu_napiecia_PCIe0 "FCSL110R005FER" FCSL110R005FERCT-ND 172.087,374.81 r180 top (schematic designator R448)
R448_U_Pomiar_pradu_napiecia_PCIe1 "FCSL110R005FER" FCSL110R005FERCT-ND 220.463,262.693 r0 top (schematic designator R448)
R448_U_Pomiar_pradu_napiecia_PCIe2 "FCSL110R005FER" FCSL110R005FERCT-ND 256.299,372.466 r180 top (schematic designator R448)
R448_U_Pomiar_pradu_napiecia_PCIe3 "FCSL110R005FER" FCSL110R005FERCT-ND 90.022,371.136 r180 top (schematic designator R448)
R448_U_Pomiar_pradu_napiecia_PCIe4 "FCSL110R005FER" FCSL110R005FERCT-ND 139.729,260.108 r0 top (schematic designator R448)
R449 "1kR" "RES 0402/1005 RF" 95.195,387.28 r180 top
R450 "0mR" "RES 0402/1005 RF" 92.583,387.28 r180 top
R451 "1kR" "RES 0402/1005 RF" 95.195,385.877 r180 top
R452 "0mR" "RES 0402/1005 RF" 92.583,385.877 r180 top
R453 "1kR" "RES 0402/1005 RF" 95.195,388.683 r180 top
R454 "0mR" "RES 0402/1005 RF" 92.583,388.683 r180 top
R455 "1kR" "RES 0402/1005 RF" 51.217,152.11 r0 top
R456 "0mR" "RES 0402/1005 RF" 49.185,152.11 r180 top
R457 "1kR" "RES 0402/1005 RF" 33.32,151.621 r0 top
R458 "1kR" "RES 0402/1005 RF" 51.217,153.126 r0 top
R459 "1kR" "RES 0402/1005 RF" 33.32,152.637 r0 top
R460 "0mR" "RES 0402/1005 RF" 49.185,153.126 r180 top
R461 "1kR" "RES 0402/1005 RF" 31.288,153.653 r180 top
R462 "1kR" "RES 0402/1005 RF" 51.217,154.269 r0 top
R463 "1kR" "RES 0402/1005 RF" 31.288,154.669 r180 top
R464 "0mR" "RES 0402/1005 RF" 49.185,154.269 r180 top
R465 "1kR" "RES 0402/1005 RF" 31.288,151.621 r180 top
R466 "1kR" "RES 0402/1005 RF" 31.288,152.637 r180 top
R467 "1kR" "RES 0402/1005 RF" 31.608,209.555 r0 bottom
R468 "1kR" "RES 0402/1005 RF" 31.608,208.539 r0 bottom
R469 "1kR" "RES 0402/1005 RF" 80.807,304.401 r270 top
R470 "0mR" "RES 0402/1005 RF" 80.807,302.427 r270 top
R471 "1kR" "RES 0402/1005 RF" 81.823,304.401 r270 top
R472 "0mR" "RES 0402/1005 RF" 81.823,302.427 r270 top
R473 "1kR" "RES 0402/1005 RF" 79.743,304.389 r270 top
R474 "0mR" "RES 0402/1005 RF" 79.743,302.415 r270 top
R475 "1kR" "RES 0402/1005 RF" 44.356,322.712 r270 top
R476 "0mR" "RES 0402/1005 RF" 44.356,320.403 r270 top
R477 "1kR" "RES 0402/1005 RF" 45.372,322.712 r270 top
R478 "0mR" "RES 0402/1005 RF" 45.372,320.403 r270 top
R479 "1kR" "RES 0402/1005 RF" 46.434,322.712 r270 top
R480 "0mR" "RES 0402/1005 RF" 46.434,320.403 r270 top
R481 "0mR" "RES 0402/1005 RF" 52.807,496.519 r180 top
R482 "150R" "RES 0402/1005 RF" 61.226,533.19 r270 top
R483 "150R" "RES 0402/1005 RF" 61.217,535.242 r90 top
R484 "71.5R" "RES 0402/1005 RF" 62.721,533.64 r180 top
R485 "71.5R" "RES 0402/1005 RF" 62.721,534.792 r180 top
R486 "8.87kR" "RES 0402/1005 RF" 66.459,535.325 r270 top
R487 "5.1kR" "RES 0402/1005 RF" 67.539,535.325 r270 top
R488 "1kR" "RES 0402/1005 RF" 53.886,541.658 r180 top
R489 "100R" "RES 0402/1005 RF" 56.426,530.695 r0 top
R490 "10kR" "RES 0402/1005 RF" 47.808,346.405 r180 top
R491 "1MR" "RES 0402/1005 RF" 54.16,353.366 r180 bottom
R492 "1kR" "RES 0402/1005 RF" 112.859,321.035 r90 top
R493 "0mR" "RES 0402/1005 RF" 112.859,319.003 r270 top
R494 "1kR" "RES 0402/1005 RF" 111.785,321.035 r90 top
R495 "0mR" "RES 0402/1005 RF" 111.785,319.003 r270 top
R496 "1kR" "RES 0402/1005 RF" 110.769,321.035 r90 top
R497 "0mR" "RES 0402/1005 RF" 110.769,319.003 r270 top
R498 "0mR" "RES 0402/1005 RF" 175.616,243.12 r0 top
R499 "1kR" "RES 0402/1005 RF" 175.616,241.799 r0 top
R500 "1kR" "RES 0402/1005 RF" 85.683,344.334 r90 top
R501 "0mR" "RES 0402/1005 RF" 85.683,342.302 r270 top
R502 "1kR" "RES 0402/1005 RF" 84.609,344.334 r90 top
R503 "0mR" "RES 0402/1005 RF" 84.609,342.302 r270 top
R504 "1kR" "RES 0402/1005 RF" 83.593,344.334 r90 top
R505 "0mR" "RES 0402/1005 RF" 83.593,342.302 r270 top
R506 "0mR" "RES 0402/1005 RF" 238.449,279.904 r180 top
R507 "0mR" "RES 0402/1005 RF" 165.341,353.816 r90 top
R508 "1kR" "RES 0402/1005 RF" 123.963,380.028 r90 top
R509 "0mR" "RES 0402/1005 RF" 123.963,377.996 r270 top
R510 "1kR" "RES 0402/1005 RF" 122.889,380.028 r90 top
R511 "0mR" "RES 0402/1005 RF" 122.889,377.996 r270 top
R512 "1kR" "RES 0402/1005 RF" 121.873,380.028 r90 top
R513 "0mR" "RES 0402/1005 RF" 121.873,377.996 r270 top
R514 "0mR" "RES 0402/1005 RF" 232.321,275.596 r270 top
R515 "10kR" "RES 0402/1005 RF" 242.686,299.297 r90 top
R516 "1kR" "RES 0402/1005 RF" 217.215,370.045 r90 top
R517 "0mR" "RES 0402/1005 RF" 217.215,368.013 r270 top
R518 "1kR" "RES 0402/1005 RF" 216.141,370.045 r90 top
R519 "0mR" "RES 0402/1005 RF" 216.141,368.013 r270 top
R520 "1kR" "RES 0402/1005 RF" 215.125,370.045 r90 top
R521 "0mR" "RES 0402/1005 RF" 215.125,368.013 r270 top
R522 "10kR" "RES 0402/1005 RF" 245.413,299.297 r90 top
R523 "10kR" "RES 0402/1005 RF" 231.607,286.757 r270 top
R524 "1kR" "RES 0402/1005 RF" 207.265,248.06 r90 top
R525 "0mR" "RES 0402/1005 RF" 207.265,246.028 r270 top
R526 "1kR" "RES 0402/1005 RF" 206.191,248.06 r90 top
R527 "0mR" "RES 0402/1005 RF" 206.191,246.028 r270 top
R528 "1kR" "RES 0402/1005 RF" 205.175,248.06 r90 top
R529 "0mR" "RES 0402/1005 RF" 205.175,246.028 r270 top
R530 "0mR" "RES 0402/1005 RF" 242.686,302.335 r90 top
R531 "10kR" "RES 0402/1005 RF" 239.96,299.297 r90 top
R532 "75R" "RES 0402/1005 RF" 104.247,340.411 r180 top
R533 "30R" "RES 0402/1005 RF" 104.247,339.432 r0 top
R534 "160R" "RES 0402/1005 RF" 185.623,277.698 r90 top
R535 "100R" "RES 0402/1005 RF" 180.01,271.272 r90 top
R536 "100R" "RES 0402/1005 RF" 251.482,177.873 r270 top
R537 "0mR" "RES 0402/1005 RF" 53.946,518.622 r180 top
R539 "0mR" "RES 0402/1005 RF" 168.204,353.238 r0 top
R540 "0mR" "RES 0402/1005 RF" 152.915,235.5 r90 top
R541 "100R" "RES 0402/1005 RF" 140.462,314.124 r90 top
R542 "100R" "RES 0402/1005 RF" 140.462,317.125 r90 top
R543 "100R" "RES 0402/1005 RF" 153.22,242.481 r0 top
R544 "1kR" "RES 0402/1005 RF" 149.911,239.433 r0 top
R545 "49.9R" "RES 0402/1005 RF" 154.12,239.511 r180 top
R546 "10kR" "RES 0402/1005 RF" 237.005,286.757 r270 top
R547 "0mR" "RES 0402/1005 RF" 245.413,302.335 r90 top
R548 "10kR" "RES 0402/1005 RF" 241.323,299.297 r90 top
R549 "10kR" "RES 0402/1005 RF" 234.306,286.757 r270 top
R550 "0mR" "RES 0402/1005 RF" 239.96,302.335 r90 top
R551 "10kR" "RES 0402/1005 RF" 246.776,299.297 r90 top
R552 "10kR" "RES 0402/1005 RF" 251.85,286.757 r270 top
R553 "0mR" "RES 0402/1005 RF" 241.323,302.335 r90 top
R554 "10kR" "RES 0402/1005 RF" 248.14,299.297 r90 top
R555 "10kR" "RES 0402/1005 RF" 243.753,286.757 r270 top
R556 "0mR" "RES 0402/1005 RF" 246.776,302.335 r90 top
R557 "10kR" "RES 0402/1005 RF" 249.503,299.297 r90 top
R558_I2C_Bridge_GPIO "1kR" "RES 0402/1005 RF" 125.173,239.794 r90 top (schematic designator R558)
R558_I2C_Bridge_PCIE "1kR" "RES 0402/1005 RF" 101.32,382.099 r90 top (schematic designator R558)
R558_I2C_Bridge_SFP "1kR" "RES 0402/1005 RF" 86.811,298.998 r90 top (schematic designator R558)
R559_I2C_Bridge_GPIO "1kR" "RES 0402/1005 RF" 123.867,239.794 r90 top (schematic designator R559)
R559_I2C_Bridge_PCIE "1kR" "RES 0402/1005 RF" 100.135,382.099 r90 top (schematic designator R559)
R559_I2C_Bridge_SFP "1kR" "RES 0402/1005 RF" 85.846,298.998 r90 top (schematic designator R559)
R560_I2C_Bridge_GPIO "1kR" "RES 0402/1005 RF" 122.562,239.794 r90 top (schematic designator R560)
R560_I2C_Bridge_PCIE "1kR" "RES 0402/1005 RF" 99.022,382.099 r90 top (schematic designator R560)
R560_I2C_Bridge_SFP "1kR" "RES 0402/1005 RF" 84.88,298.998 r90 top (schematic designator R560)
R561 "1kR" "RES 0402/1005 RF" 124.498,184.31 r90 top
R562 "1kR" "RES 0402/1005 RF" 123.482,184.31 r90 top
R563 "1kR" "RES 0402/1005 RF" 126.53,184.31 r90 top
R564 "1kR" "RES 0402/1005 RF" 125.514,184.31 r90 top
R565 "1kR" "RES 0402/1005 RF" 124.498,182.278 r270 top
R566 "1kR" "RES 0402/1005 RF" 123.482,182.278 r270 top
R567 "1kR" "RES 0402/1005 RF" 126.53,182.278 r270 top
R568 "1kR" "RES 0402/1005 RF" 125.514,182.278 r270 top
R569 "1kR" "RES 0402/1005 RF" 125.281,168.011 r90 top
R570 "1kR" "RES 0402/1005 RF" 124.265,168.011 r90 top
R571 "1kR" "RES 0402/1005 RF" 127.313,168.011 r90 top
R572 "1kR" "RES 0402/1005 RF" 126.297,168.011 r90 top
R573 "1kR" "RES 0402/1005 RF" 125.281,165.979 r270 top
R574 "1kR" "RES 0402/1005 RF" 124.265,165.979 r270 top
R575 "1kR" "RES 0402/1005 RF" 127.313,165.979 r270 top
R576 "1kR" "RES 0402/1005 RF" 126.297,165.979 r270 top
R577 "1kR" "RES 0402/1005 RF" 122.504,216.987 r90 top
R578 "1kR" "RES 0402/1005 RF" 121.488,216.987 r90 top
R579 "1kR" "RES 0402/1005 RF" 124.536,216.987 r90 top
R580 "1kR" "RES 0402/1005 RF" 123.52,216.987 r90 top
R581 "1kR" "RES 0402/1005 RF" 122.504,214.955 r270 top
R582 "1kR" "RES 0402/1005 RF" 121.488,214.955 r270 top
R583 "1kR" "RES 0402/1005 RF" 124.536,214.955 r270 top
R584 "1kR" "RES 0402/1005 RF" 123.52,214.955 r270 top
R585 "1kR" "RES 0402/1005 RF" 119.698,200.521 r90 top
R586 "1kR" "RES 0402/1005 RF" 118.682,200.521 r90 top
R587 "1kR" "RES 0402/1005 RF" 121.73,200.521 r90 top
R588 "1kR" "RES 0402/1005 RF" 120.714,200.521 r90 top
R589 "1kR" "RES 0402/1005 RF" 119.698,198.489 r270 top
R590 "1kR" "RES 0402/1005 RF" 118.682,198.489 r270 top
R591 "1kR" "RES 0402/1005 RF" 121.73,198.489 r270 top
R592 "1kR" "RES 0402/1005 RF" 120.714,198.489 r270 top
R593 "1kR" "RES 0402/1005 RF" 31.608,211.587 r0 bottom
R594 "1kR" "RES 0402/1005 RF" 31.608,210.571 r0 bottom
R595 "1kR" "RES 0402/1005 RF" 29.576,209.555 r180 bottom
R596 "1kR" "RES 0402/1005 RF" 29.576,208.539 r180 bottom
R597 "1kR" "RES 0402/1005 RF" 29.576,211.587 r180 bottom
R598 "1kR" "RES 0402/1005 RF" 29.576,210.571 r180 bottom
R599 "1kR" "RES 0402/1005 RF" 122.097,250.869 r90 top
R600 "0mR" "RES 0402/1005 RF" 210.075,243.054 r270 top
R601 "0mR" "RES 0402/1005 RF" 211.261,243.054 r90 top
R602_SPI_bridge_Main "0mR" "RES 0402/1005 RF" 214.452,291.652 r180 top (schematic designator R602)
R602_SPI_bridge_PCIe "0mR" "RES 0402/1005 RF" 142.687,380.477 r90 top (schematic designator R602)
R603_SPI_bridge_Main "0mR" "RES 0402/1005 RF" 214.452,288.068 r0 top (schematic designator R603)
R603_SPI_bridge_PCIe "0mR" "RES 0402/1005 RF" 138.857,380.427 r270 top (schematic designator R603)
R604_SPI_bridge_Main "0mR" "RES 0402/1005 RF" 185.538,251.673 r270 top (schematic designator R604)
R604_SPI_bridge_PCIe "0mR" "RES 0402/1005 RF" 251.666,251.289 r270 top (schematic designator R604)
R605_SPI_bridge_Main "0mR" "RES 0402/1005 RF" 189.416,251.673 r90 top (schematic designator R605)
R605_SPI_bridge_PCIe "0mR" "RES 0402/1005 RF" 255.537,251.289 r90 top (schematic designator R605)
R606_SPI_bridge_Main "0mR" "RES 0402/1005 RF" 186.548,251.673 r270 top (schematic designator R606)
R606_SPI_bridge_PCIe "0mR" "RES 0402/1005 RF" 252.94,251.289 r270 top (schematic designator R606)
R607 "10kR" "RES 0402/1005 RF" 238.355,286.758 r270 top
R608 "10kR" "RES 0402/1005 RF" 60.341,496.291 r180 top
R609 "10kR" "RES 0402/1005 RF" 60.333,495.3 r0 top
R610 "1.33kR" "RES 0402/1005 RF" 67.378,240.02 r90 top
R611 "1.33kR" "RES 0402/1005 RF" 67.113,230.597 r270 top
R612 "270R" "RES 0402/1005 RF" 59.342,241.891 r180 top
R613 "2.4R" "RES 1206/3216" 90.765,245.884 r270 top
R614 "270R" "RES 0402/1005 RF" 59.242,230.712 r180 top
R615 "10kR" "RES 0402/1005 RF" 60.606,234.739 r0 bottom
R616 "2.4R" "RES 1206/3216" 90.717,225.431 r90 top
R617 "PU5931FKMP70R004L" PU5931 137.735,295.465 r0 top
R618 "0mR" "RES 0402/1005 RF" 248.14,302.335 r90 top
R619 "1.91kR" "RES 0402/1005 RF" 69.291,183.959 r270 top
R620 "2kR" "RES 0402/1005 RF" 69.151,175.367 r270 top
R621 "147kR" "RES 0402/1005 RF" 65.137,183.819 r90 top
R622 "340kR" "RES 0402/1005 RF" 65.175,175.443 r270 top
R623 "1.43kR" "RES 0402/1005 RF" 63.12,175.457 r90 top
R624 "15kR" "RES 0402/1005 RF" 63.175,183.76 r270 top
R625 "1.4kR" "RES 0201/0603" 67.001,210.554 r270 top
R626 "200kR" "RES 0402/1005 RF" 59.997,210.161 r90 top
R627 "10.5kR" "RES 0402/1005 RF" 60.944,210.183 r270 top
R628 "750kR" "RES 0402/1005 RF" 69.132,200.233 r270 top
R629 "Resistance" "RES 0402/1005 RF" 68.656,206.964 r180 top
R630 "10kR" "RES 0402/1005 RF" 52.05,174.091 r180 top
R631 "5.9kR" "RES 0402/1005 RF" 61.938,202.273 r90 top
R632 "100kR" "RES 0402/1005 RF" 108.341,246.733 r180 top
R633 "100kR" "RES 0402/1005 RF" 108.341,247.684 r180 top
R634 "100kR" "RES 0402/1005 RF" 108.341,248.634 r180 top
R635 "10k" "RES 0402/1005 RF" 220.642,184.688 r180 bottom
R636 "0mR" "RES 0402/1005 RF" 234.333,189.21 r180 top
R637 "0mR" "RES 0402/1005 RF" 232.073,189.21 r0 top
R638 "0mR" "RES 0402/1005 RF" 234.333,190.348 r180 top
R639 "0mR" "RES 0402/1005 RF" 232.073,190.348 r0 top
R640 "0mR" "RES 0402/1005 RF" 234.333,193.598 r180 top
R641 "0mR" "RES 0402/1005 RF" 232.073,193.598 r0 top
R642 "0mR" "RES 0402/1005 RF" 234.333,194.737 r180 top
R643 "0mR" "RES 0402/1005 RF" 232.073,194.737 r0 top
R644 "9.1kR" "RES 0402/1005 RF" 132.588,233.309 r90 top
R645 "13kR" "RES 0402/1005 RF" 134.156,232.859 r180 top
R646 "100kR" "RES 0402/1005 RF" 127.572,229.826 r90 top
R647 "100kR" "RES 0402/1005 RF" 209.143,166.395 r225 top
R648 "2R" "RES 0402/1005 RF" 211.137,160.033 r180 top
R649 "10kR" "RES 0402/1005 RF" 207.162,158.686 r90 top
R650 "100MR" "RES 0402/1005 RF" 208.001,172.453 r0 top
R651 "10kR" "RES 0402/1005 RF" 198.788,172.492 r180 top
R652 "1MR" "RES 0402/1005 RF" 211.506,164.834 r0 top
R653 "20R" "RES 0402/1005 RF" 203.416,172.467 r180 top
R654 "100R" "RES 0402/1005 RF" 202.667,158.573 r90 top
R655 "10kR" "RES 0402/1005 RF" 202.039,164.999 r180 top
R656 "10kR" "RES 0402/1005 RF" 207.34,177.547 r0 top
R657 "100R" "RES 0402/1005 RF" 201.028,172.467 r0 bottom
R658 "10kR" "RES 0402/1005 RF" 201.206,177.56 r180 bottom
R659 "10kR" "RES 0402/1005 RF" 253.593,299.297 r90 top
R660 "10kR" "RES 0402/1005 RF" 239.704,286.758 r270 top
R661 "10kR" "RES 0402/1005 RF" 252.23,299.297 r90 top
R662 "10kR" "RES 0402/1005 RF" 245.102,286.758 r270 top
R663 "10kR" "RES 0402/1005 RF" 259.161,299.297 r90 top
R664 "10kR" "RES 0402/1005 RF" 241.054,286.758 r270 top
R665 "0mR" "RES 0402/1005 RF" 39.014,209.378 r270 top
R666 "12mR" "RES 1206/3216" 45.266,205.057 r90 top
R667 "24.9kR" "RES 0402/1005 RF" 42.528,202.265 r180 top
R668 "20kR" "RES 0402/1005 RF" 124.777,232.245 r0 top
R669 "0mR" "RES 0402/1005 RF" 38.887,200.381 r270 top
R670 "0mR" "RES 0402/1005 RF" 37.668,200.388 r270 top
R671 "1.87kR" "RES 0402/1005 RF" 218.007,323.545 r0 top
R672 "1.5kR" "RES 0402/1005 RF" 254.433,334.124 r0 top
R673 "1.87kR" "RES 0402/1005 RF" 241.467,334.124 r0 top
R674 "15kR" "RES 0402/1005 RF" 232.818,334.124 r0 top
R675 "0mR" "RES 0402/1005 RF" 98.654,261.232 r270 bottom
R676 "20kR" "RES 0402/1005 RF" 233.582,321.424 r0 top
R677 "95.3kR" "RES 0402/1005 RF" 44.716,192.483 r270 top
R678 "95.3kR" "RES 0402/1005 RF" 43.658,192.483 r270 top
R679 "95.3kR" "RES 0402/1005 RF" 45.775,195.483 r90 top
R680 "95.3kR" "RES 0402/1005 RF" 43.658,195.483 r90 top
R681 "24.9kR" "RES 0402/1005 RF" 51.568,194.019 r180 top
R682 "7.5kR" "RES 0402/1005 RF" 45.775,192.483 r90 top
R683 "4.87kR" "RES 0402/1005 RF" 42.6,192.483 r90 top
R684 "7.15kR" "RES 0402/1005 RF" 44.716,195.483 r270 top
R685 "5.9kR" "RES 0402/1005 RF" 42.6,195.483 r270 top
R686 "412kR" "RES 0402/1005 RF" 56.27,215.062 r90 top
R687 "57.6kR" "RES 0402/1005 RF" 61.953,210.719 r270 top
R688 "0mR" "RES 0402/1005 RF" 249.503,302.335 r90 top
R689 "20kR" "RES 0402/1005 RF" 160.795,347.612 r90 top
R690 "100kR" "RES 0402/1005 RF" 159.652,347.612 r90 top
R691 "20kR" "RES 0402/1005 RF" 151.692,347.358 r0 top
R692 "0mR" "RES 0402/1005 RF" 272.586,291.706 r90 bottom
R693 "0mR" "RES 0402/1005 RF" 289.222,353.657 r90 top
R694 "1kR" "RES 0402/1005 RF" 231.723,323.635 r90 top
R695 "100R" "RES 0402/1005 RF" 165.024,277.812 r90 top
R696 "0mR" "RES 0402/1005 RF" 132.563,342.99 r90 top
R697 "1kR" "RES 0402/1005 RF" 147.739,179.615 r90 top
R698 "0mR" "RES 0402/1005 RF" 147.739,177.615 r270 top
R699 "1kR" "RES 0402/1005 RF" 146.698,179.615 r90 top
R700 "0mR" "RES 0402/1005 RF" 146.698,177.615 r270 top
R701 "1kR" "RES 0402/1005 RF" 145.653,179.615 r90 top
R702 "0mR" "RES 0402/1005 RF" 145.653,177.615 r270 top
R709 "2.2kR" "RES 0402/1005 RF" 108.074,271.544 r90 bottom
R710 "10kR" "RES 0402/1005 RF" 263.919,347.657 r270 bottom
R711 "0mR" "RES 0402/1005 RF" 262.674,349.961 r90 bottom
R712 "0mR" "RES 0402/1005 RF" 264.008,349.821 r270 bottom
R713 "0mR" "RES 0402/1005 RF" 265.532,350.794 r270 bottom
R714 "2.2kR" "RES 0402/1005 RF" 266.306,347.434 r90 bottom
R715 "10kR" "RES 0402/1005 RF" 253.771,348.166 r270 bottom
R716 "261R" "RES 0402/1005 RF" 188.452,363.868 r180 bottom
R717 "261R" "RES 0402/1005 RF" 188.412,361.831 r180 bottom
R718 "261R" "RES 0402/1005 RF" 188.455,360.007 r180 bottom
R719 "261R" "RES 0402/1005 RF" 188.462,356.362 r180 bottom
R720 "261R" "RES 0402/1005 RF" 188.462,358.229 r180 bottom
R721 "10k" "RES 0402/1005 RF" 220.642,185.958 r180 bottom
R722 "0mR" "RES 0402/1005 RF" 225.959,221.69 r90 top
R723 "0mR" "RES 0402/1005 RF" 225.959,223.95 r270 top
R724 "0mR" "RES 0402/1005 RF" 227.098,221.69 r90 top
R725 "0mR" "RES 0402/1005 RF" 227.098,223.95 r270 top
R726 "0mR" "RES 0402/1005 RF" 230.348,221.69 r90 top
R727 "0mR" "RES 0402/1005 RF" 230.348,223.95 r270 top
R728 "0mR" "RES 0402/1005 RF" 231.487,221.69 r90 top
R729 "0mR" "RES 0402/1005 RF" 231.487,223.95 r270 top
R730 "4.7kR" "RES 0402/1005 RF" 195.016,209.369 r180 top
R731 "4.7kR" "RES 0402/1005 RF" 195.016,199.209 r180 top
R732 "4.7kR" "RES 0402/1005 RF" 195.016,201.749 r180 top
R733 "4.7kR" "RES 0402/1005 RF" 195.016,204.289 r180 top
R734 "4.7kR" "RES 0402/1005 RF" 195.016,206.829 r180 top
R735 "10kR" "RES 0402/1005 RF" 254.956,299.297 r90 top
R736 "10kR" "RES 0402/1005 RF" 246.452,286.758 r270 top
R737 "10kR" "RES 0402/1005 RF" 98.641,265.412 r270 bottom
R738 "1kR" "RES 0402/1005 RF" 340.627,352.9 r90 top
R739 "1kR" "RES 0402/1005 RF" 338.995,352.931 r90 top
R740 "1kR" "RES 0402/1005 RF" 339.014,357.079 r90 top
R741 "1kR" "RES 0402/1005 RF" 340.563,357.244 r90 top
R742 "1kR" "RES 0402/1005 RF" 338.847,349.662 r90 top
R743 "1kR" "RES 0402/1005 RF" 337.4,349.535 r90 top
R744 "0mR" "RES 0402/1005 RF" 253.593,302.335 r90 top
R745 "20kR" "RES 0402/1005 RF" 153.962,285.28 r90 top
R746 "10kR" "RES 0402/1005 RF" 111.087,268.181 r90 bottom
R747 "10kR" "RES 0402/1005 RF" 112.185,268.181 r90 bottom
R748 "10kR" "RES 0402/1005 RF" 113.284,268.181 r90 bottom
R749 "10kR" "RES 0402/1005 RF" 114.383,268.181 r90 bottom
R750 "10kR" "RES 0402/1005 RF" 115.481,268.181 r90 bottom
R751 "10kR" "RES 0402/1005 RF" 120.619,265.049 r0 bottom
R752 "10kR" "RES 0402/1005 RF" 120.619,263.957 r0 bottom
R753 "10kR" "RES 0402/1005 RF" 120.619,262.865 r0 bottom
R754 "10kR" "RES 0402/1005 RF" 120.619,261.772 r0 bottom
R755 "10kR" "RES 0402/1005 RF" 120.619,260.68 r0 bottom
R756 "10kR" "RES 0402/1005 RF" 120.619,259.588 r0 bottom
R757 "10kR" "RES 0402/1005 RF" 120.853,253.53 r270 bottom
R758 "1kR" "RES 0402/1005 RF" 106.559,265.852 r180 top
R759 "0mR" "RES 0402/1005 RF" 104.133,265.852 r180 top
R760 "1kR" "RES 0402/1005 RF" 106.559,264.358 r180 top
R761 "0mR" "RES 0402/1005 RF" 104.133,264.358 r180 top
R762 "1kR" "RES 0402/1005 RF" 106.559,262.865 r180 top
R763 "0mR" "RES 0402/1005 RF" 104.133,262.865 r180 top
R764 "WSHP28184L000FEA" WSHP2818 101.381,224.041 r0 bottom
R765 "10kR" "RES 0402/1005 RF" 250.866,299.297 r90 top
R766 "10kR" "RES 0402/1005 RF" 242.403,286.758 r270 top
R767 "0mR" "RES 0402/1005 RF" 252.23,302.335 r90 top
R768 "0mR" "RES 0402/1005 RF" 153.34,297.394 r0 top
R769 "0mR" "RES 0402/1005 RF" 118.377,301.384 r0 top
R770 "0mR" "RES 0402/1005 RF" 118.377,300.406 r0 top
R771 "0mR" "RES 0402/1005 RF" 118.377,299.453 r0 top
R772 "0mR" "RES 0402/1005 RF" 63.366,326.428 r0 top
R773 "0mR" "RES 0402/1005 RF" 63.531,323.863 r0 top
R774 "0mR" "RES 0402/1005 RF" 62.255,333.235 r0 top
R775 "0mR" "RES 0402/1005 RF" 62.179,331.864 r0 top
R776 "0mR" "RES 0402/1005 RF" 220.717,190.809 r180 top
R777 "0mR" "RES 0402/1005 RF" 220.718,189.856 r180 top
R778 "0mR" "RES 0402/1005 RF" 220.664,194.229 r180 top
R779 "0mR" "RES 0402/1005 RF" 220.668,193.302 r180 top
R780 "0mR" "RES 0402/1005 RF" 203.378,398.335 r90 top
R781 "0mR" "RES 0402/1005 RF" 110.597,362.318 r180 bottom
R782 "0mR" "RES 0402/1005 RF" 138.945,332.473 r0 bottom
R783 "0mR" "RES 0402/1005 RF" 205.867,158.649 r90 top
R784 "0mR" "RES 0402/1005 RF" 42.71,366.145 r0 top
R785 "0mR" "RES 0402/1005 RF" 42.71,367.706 r0 top
R786 "0mR" "RES 0402/1005 RF" 42.71,369.267 r0 top
R787 "0mR" "RES 0402/1005 RF" 42.71,370.828 r0 top
R788 "0mR" "RES 0402/1005 RF" 148.849,313.665 r0 bottom
R789 "0mR" "RES 0402/1005 RF" 42.71,372.389 r0 top
R790 "0mR" "RES 0402/1005 RF" 46.199,331.914 r90 top
R791 "0mR" "RES 0402/1005 RF" 43.646,331.914 r90 top
R792 "0mR" "RES 0402/1005 RF" 41.335,331.914 r90 top
R793 "0mR" "RES 0402/1005 RF" 38.731,331.914 r90 top
R794 "0mR" "RES 0402/1005 RF" 36.407,331.914 r90 top
R795 "0mR" "RES 0402/1005 RF" 33.766,331.914 r90 top
R796 "0mR" "RES 0402/1005 RF" 203.302,404.261 r270 top
R797 "0mR" "RES 0402/1005 RF" 133.566,313.233 r0 top
R798 "0mR" "RES 0402/1005 RF" 180.855,371.142 r180 top
R799 "0mR" "RES 0402/1005 RF" 180.855,369.192 r180 top
R800 "0mR" "RES 0402/1005 RF" 60.877,351.248 r0 bottom
R801 "0mR" "RES 0402/1005 RF" 60.877,349.475 r0 bottom
R802 "0mR" "RES 0402/1005 RF" 63.251,341.507 r0 bottom
R803 "0mR" "RES 0402/1005 RF" 159.042,322.58 r0 top
R804 "0mR" "RES 0402/1005 RF" 104.699,305.539 r270 top
R805 "0mR" "RES 0402/1005 RF" 205.296,414.185 r270 top
R806 "0mR" "RES 0402/1005 RF" 166.814,251.074 r270 top
R807 "0mR" "RES 0402/1005 RF" 158.989,323.693 r0 top
R808 "0mR" "RES 0402/1005 RF" 159.004,321.348 r0 top
R809 "0mR" "RES 0402/1005 RF" 153.599,327.939 r90 top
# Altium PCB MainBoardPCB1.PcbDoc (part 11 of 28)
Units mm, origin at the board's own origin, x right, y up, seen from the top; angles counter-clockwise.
Board outline 258.95 x 308.86 mm, 16 copper layers (L1, L2 (GND), L3 (Sign), L4 (GND), L5 (Sign), L6 (PWR/GND), L7(PWR/GND), L8 (Plane_GND), L9 (PWR/GND), L10 (PWR/GND), L11 (PWR/GND), L12 (Sign), L13 (GND), L14 (Sign), L15 (GND), L16), stack 2.502 mm thick; 2397 components, 1744 nets, 8397 pads, 4112 vias.
Unrouted connection lines stored in the file: 3547.

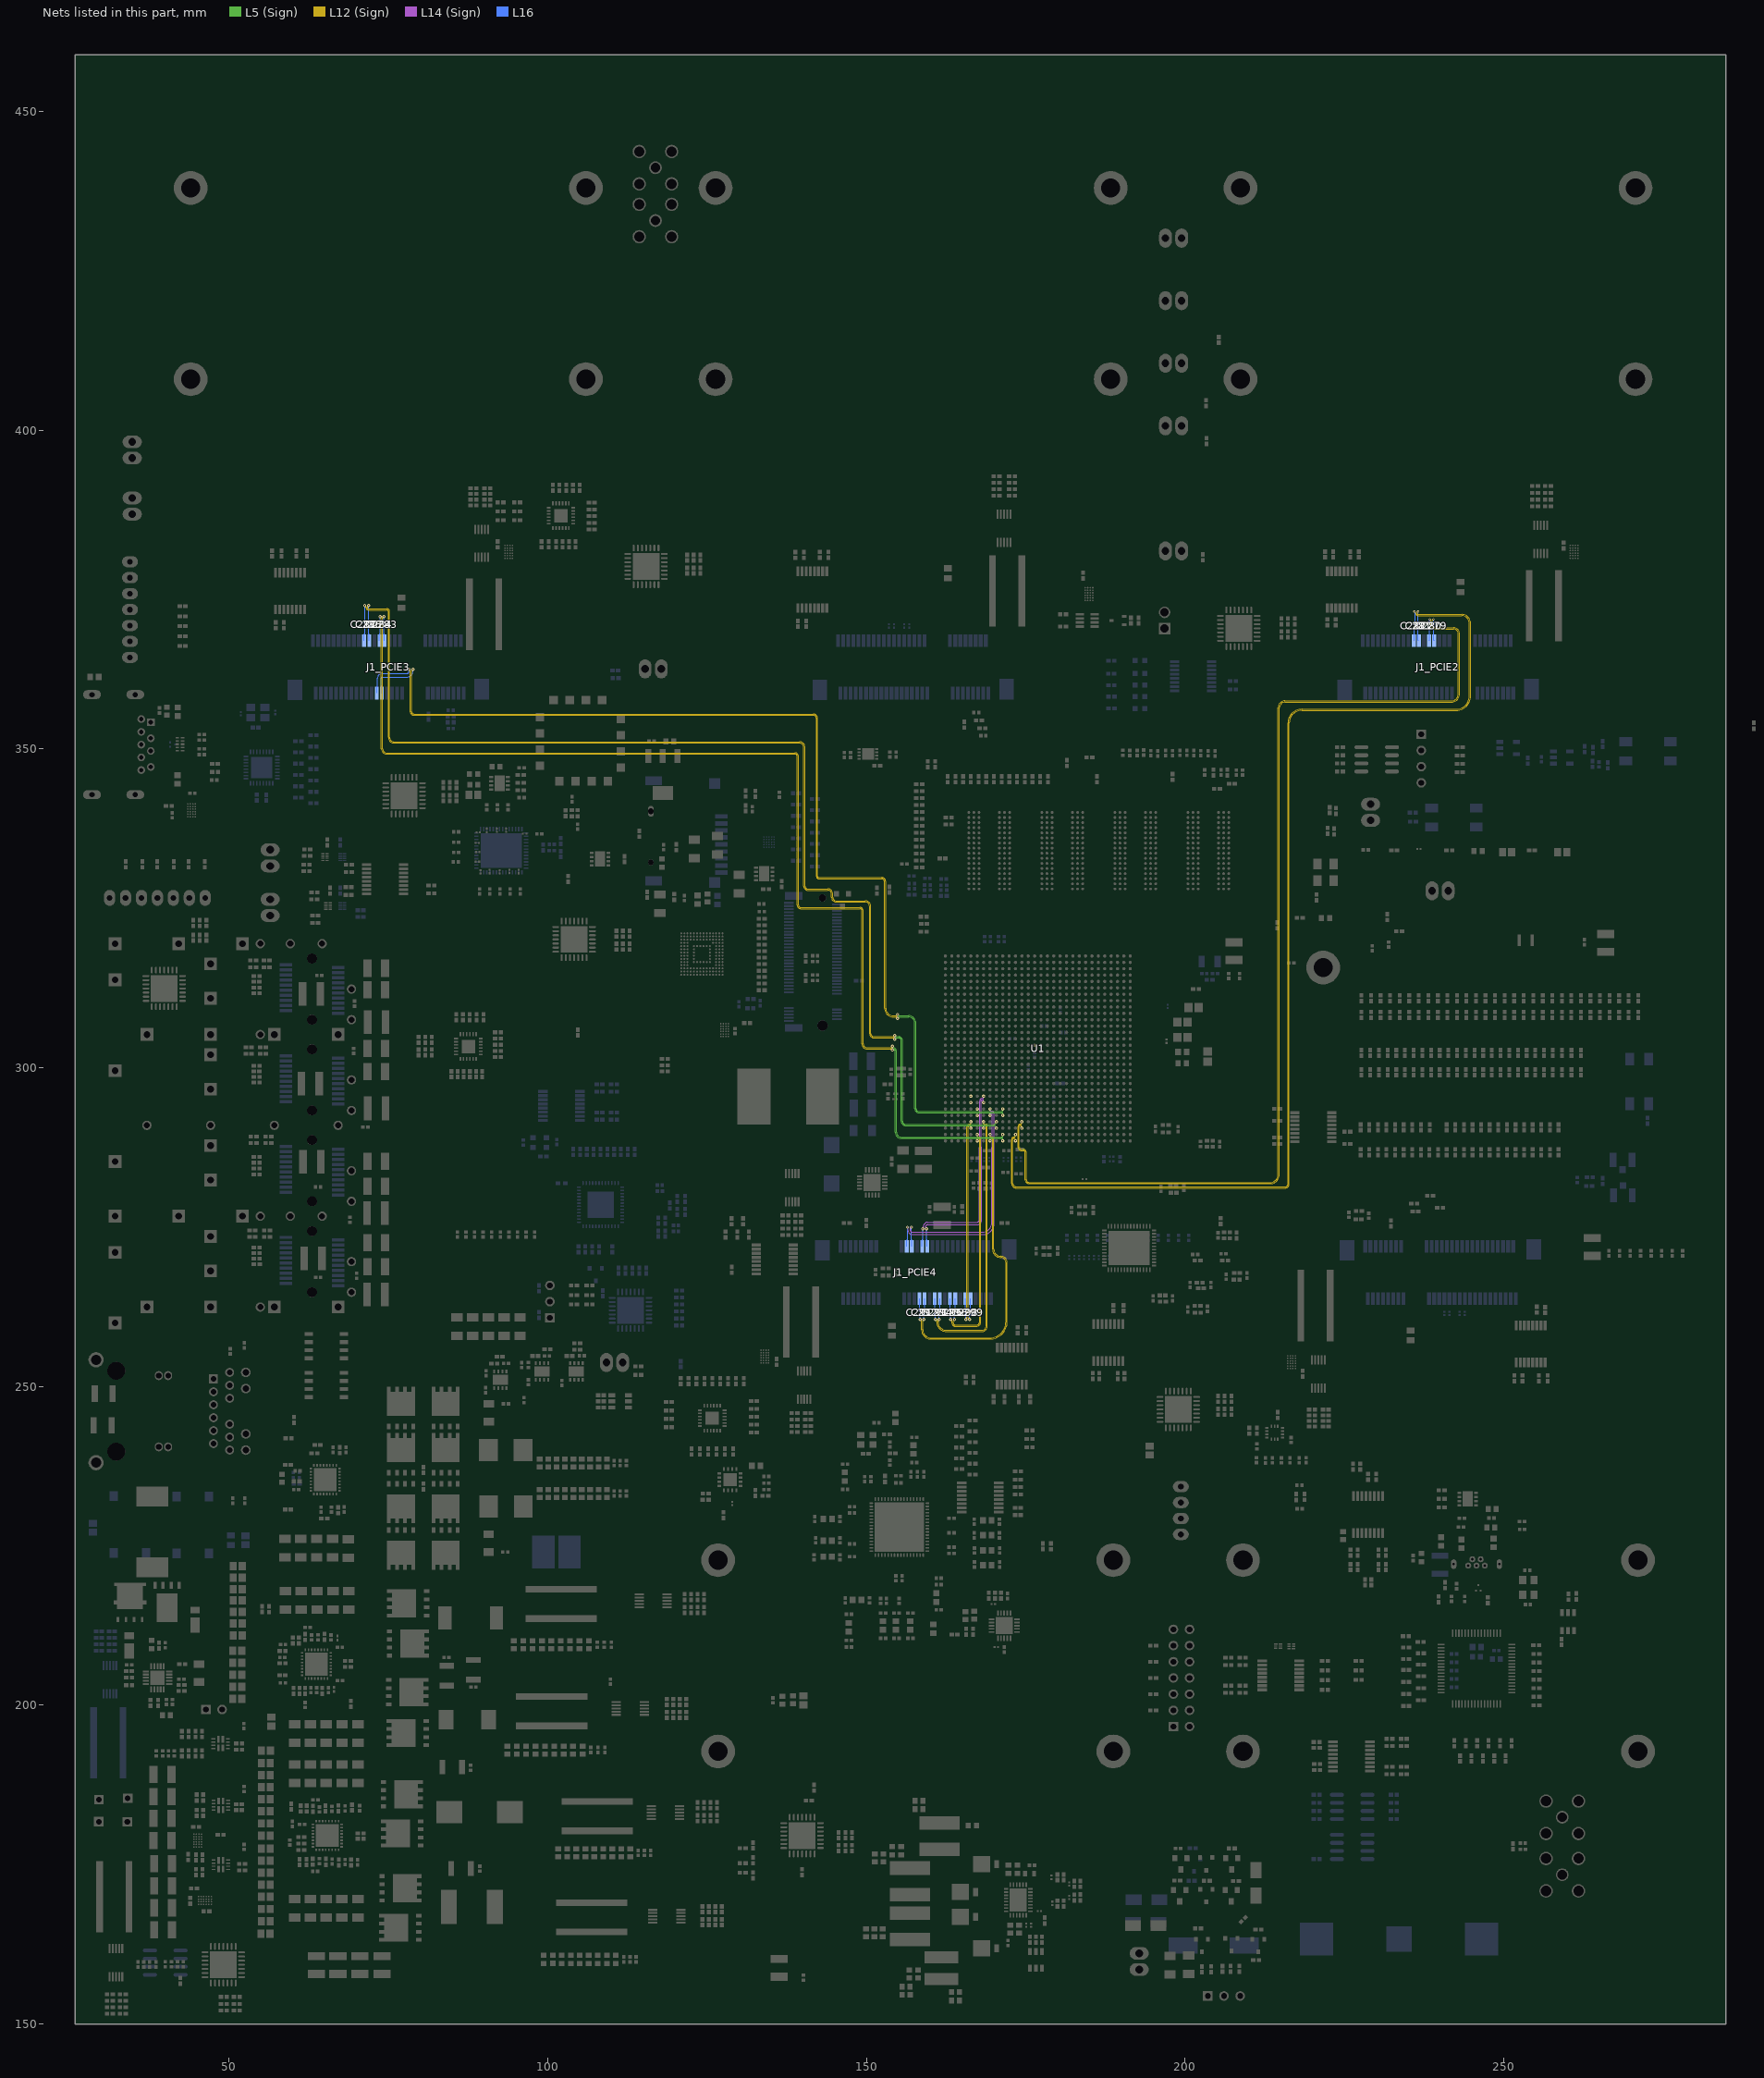
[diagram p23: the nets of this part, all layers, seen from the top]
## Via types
v1: diameter 0.5, hole 0.2, L1 to L16, tented both sides, 1457 vias
v2: diameter 0.35/0/0.35 (per signal layer), hole 0.127, L1 to L3 (Sign), tented both sides, 479 vias
v3: diameter 0.5/0.35/0.35/0.35/0.35/0.35/0.35/0.35/0.35/0.35/0.35/0.35/0.35/0.35/0.35/0.5 (per signal layer), hole 0.15, L1 to L16, tented both sides, 453 vias
v4: diameter 0.5, hole 0.2, L1 to L16, 451 vias
v5: diameter 0.5/0.35/0.35/0.35/0.35/0.35/0.35/0.35/0.35/0.35/0.35/0.35/0.35/0.35/0.35/0.5 (per signal layer), hole 0.2, L1 to L16, tented both sides, 373 vias
v6: diameter 0.8, hole 0.4, L1 to L16, tented both sides, 168 vias
v7: diameter 0.35/0/0.35 (per signal layer), hole 0.127, L1 to L3 (Sign), 138 vias
v8: diameter 2.54, hole 1.02, L1 to L16, 113 vias
v9: diameter 0.5/0/0.5 (per signal layer), hole 0.2, L14 (Sign) to L16, tented both sides, 102 vias
v10: diameter 1.4, hole 0.5, L1 to L16, tented both sides, 80 vias
v11: diameter 0.5, hole 0.2, L3 (Sign) to L6 (PWR/GND), tented both sides, 54 vias
v12: diameter 0.35, hole 0.127, L1 to L2 (GND), tented both sides, 47 vias
v13: diameter 0.4, hole 0.2, L1 to L16, tented both sides, 46 vias
v14: diameter 0.35, hole 0.127, L1 to L16, tented both sides, 16 vias
v15: diameter 0.25, hole 0.2, L1 to L16, 16 vias
v16: diameter 0.5, hole 0.2, L11 (PWR/GND) to L14 (Sign), tented both sides, 16 vias
v17: diameter 0.4, hole 0.2, L1 to L16, 16 vias
v18: diameter 0.3, hole 0.2, L1 to L16, 15 vias
v19: diameter 0.45, hole 0.15, L1 to L16, 12 vias
v20: diameter 0.5/0.35/0.35/0.35/0.35/0.35/0.35/0.35/0.35/0.35/0.35/0.35/0.35/0.35/0.35/0.45 (per signal layer), hole 0.15, L1 to L16, tented both sides, 10 vias
v21: diameter 0.2/0/0.2 (per signal layer), hole 0.1, L1 to L3 (Sign), tented both sides, 9 vias
v22: diameter 0.3, hole 0.127, L14 (Sign) to L16, tented both sides, 8 vias
v23: diameter 0.4, hole 0.1, L1 to L16, 7 vias
v24: diameter 1.15, hole 1.15, L1 to L16, 5 vias
v25: diameter 1.65, hole 1.65, L1 to L16, 5 vias
v26: diameter 0.2, hole 0.1, L1 to L16, 4 vias
v27: diameter 0.4, hole 0.15, L1 to L16, 2 vias
v28: diameter 0.5/0.35/0.35/0.35/0.35/0.35/0.35/0.35/0.35/0.35/0.35/0.35/0.35/0.35/0.35/0.5 (per signal layer), hole 0.15, L1 to L16, 2 vias
v29: diameter 0.35, hole 0.127, L3 (Sign) to L6 (PWR/GND), tented both sides, 2 vias
v30: diameter 0.3, hole 0.127, L15 (GND) to L16, tented both sides, 1 vias
v31: diameter 0.35, hole 0.127, L1 to L2 (GND), 1 vias
v32: diameter 0.5/0.35/0.35/0.35/0.35/0.35/0.35/0.35/0.35/0.35/0.35/0.35/0.35/0.35/0.35/0.5 (per signal layer), hole 0.2, L1 to L16, 1 vias
v33: diameter 0.35/0.35/0.35 (per signal layer), hole 0.127, L1 to L3 (Sign), tented both sides, 1 vias
v34: diameter 0.45/0/0.45 (per signal layer), hole 0.15, L1 to L3 (Sign), tented both sides, 1 vias
v35: diameter 0.45/0/0.45 (per signal layer), hole 0.2, L14 (Sign) to L16, tented both sides, 1 vias

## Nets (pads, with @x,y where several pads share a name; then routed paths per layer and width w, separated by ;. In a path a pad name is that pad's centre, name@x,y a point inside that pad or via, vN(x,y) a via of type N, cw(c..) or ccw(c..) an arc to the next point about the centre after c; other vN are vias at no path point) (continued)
B224_Rx3_N: J1_PCIE3.27 U1.K5 | length 169.4
  L5 (Sign) w0.073: v1(154.862,307.762) cw(c155.062,307.762) 155.062,307.962 156.62,307.962 cw(c156.62,306.984) 157.598,306.984 157.598,293.599 ccw(c158.257,293.599) 158.257,292.94 161.397,292.94 171.247,292.939 cw(c171.247,292.789) 171.397,292.789 v3(171.397,292.539)
  L12 (Sign) w0.073: v1(78.237,362.522) cw(c78.237,362.321) 78.438,362.321 78.438,355.867 ccw(c78.996,355.867) 78.996,355.308 141.656,355.308 cw(c141.656,354.813) 142.151,354.813 142.151,330.013 ccw(c142.507,330.013) 142.507,329.658 152.384,329.658 cw(c152.384,329.209) 152.832,329.209 152.832,309.363 ccw(c154.232,309.363) 154.232,307.962 154.662,307.962 cw(c154.662,307.762) v1(154.862,307.762)
  L16 w0.081: J1_PCIE3.27@73.185,358.792 73.185,359.725 cw(c73.292,359.725) 73.292,359.832 73.292,361.111 cw(c74.068,361.111) 74.068,361.888 78.005,361.888 ccw(c78.005,362.128) 78.245,362.128 78.245,362.522 v1(78.237,362.522)
B224_Rx3_P: J1_PCIE3.25 U1.K6 | length 169.1
  L5 (Sign) w0.073: v1(154.862,308.362) ccw(c155.062,308.362) 155.062,308.162 156.62,308.162 cw(c156.62,306.984) 157.797,306.984 157.797,293.599 ccw(c158.257,293.599) 158.257,293.139 161.397,293.139 171.247,293.139 ccw(c171.247,293.289) 171.397,293.289 v3(171.397,293.539)
  L12 (Sign) w0.073: v1(78.837,362.522) ccw(c78.837,362.321) 78.637,362.321 78.637,355.867 ccw(c78.996,355.867) 78.996,355.507 141.656,355.507 cw(c141.656,354.813) 142.351,354.813 142.351,330.013 ccw(c142.507,330.013) 142.507,329.857 152.384,329.857 cw(c152.384,329.209) 153.031,329.209 153.031,309.363 ccw(c154.232,309.363) 154.232,308.162 154.662,308.162 ccw(c154.662,308.362) v1(154.862,308.362)
  L16 w0.081: J1_PCIE3.25@73.985,358.792 73.985,359.725 ccw(c73.877,359.725) 73.877,359.832 73.877,361.111 cw(c74.068,361.111) 74.068,361.302 78.005,361.302 ccw(c78.005,362.128) 78.83,362.128 78.83,362.522 v1(78.837,362.522)
B224_Tx0_to_C_N: C280.1 J1_PCIE2.26 | length 2.2
  L16 w0.081: J1_PCIE2.26@238.29,366.992 238.397,367.099 238.397,368.967 C280.1@238.29,369.075
B224_Tx0_to_C_P: C279.1 J1_PCIE2.24 | length 2.2
  L16 w0.081: J1_PCIE2.24@239.09,366.992 238.982,367.099 238.982,368.967 C279.1@239.09,369.075
B224_Tx0C_to_B_N: C280.2 U1.N3 | length 169.5
  L12 (Sign) w0.073: v3(174.397,290.539) 174.397,290.698 ccw(c174.155,290.698) 174.155,290.939 ccw(c174.155,290.774) 173.99,290.774 173.99,287.539 ccw(c174.332,287.539) 174.332,287.198 174.634,287.198 cw(c174.634,286.74) 175.091,286.74 175.091,282.464 ccw(c175.539,282.464) 175.539,282.016 213.373,282.016 ccw(c213.373,283.248) 214.605,283.248 214.605,356.464 cw(c215.697,356.464) 215.697,357.556 241.795,357.556 ccw(c241.795,358.635) 242.875,358.635 242.875,368.109 ccw(c242.16,368.109) 242.16,368.824 239.208,368.824 cw(c239.208,369.443) 238.59,369.443 238.59,370.177 ccw(c238.397,370.177) v14(238.397,370.37)
  L16 w0.081: C280.2@238.29,369.595 238.29,369.678 cw(c238.397,369.678) 238.397,369.785 v14(238.397,370.37)
B224_Tx0C_to_B_P: C279.2 U1.N4 | length 170.4
  L12 (Sign) w0.073: v3(174.397,291.539) 174.397,291.381 cw(c174.155,291.381) 174.155,291.139 ccw(c174.155,290.774) 173.79,290.774 173.79,287.539 ccw(c174.331,287.539) 174.331,286.998 174.634,286.998 cw(c174.634,286.74) 174.892,286.74 174.892,282.464 ccw(c175.539,282.464) 175.539,281.817 213.373,281.817 ccw(c213.373,283.248) 214.804,283.248 214.804,356.464 cw(c215.697,356.464) 215.697,357.356 241.795,357.356 ccw(c241.795,358.635) 243.074,358.635 243.074,368.109 ccw(c242.16,368.109) 242.16,369.024 239.208,369.024 cw(c239.208,369.443) 238.789,369.443 238.789,370.177 cw(c238.982,370.177) v14(238.982,370.37)
  L16 w0.081: v14(238.982,370.37) 238.982,369.785 cw(c238.982,369.678) 239.09,369.678 C279.2@239.09,369.595
B224_Tx1_to_C_N: C282.1 J1_PCIE2.32 | length 2.2
  L16 w0.081: J1_PCIE2.32@235.89,366.992 235.997,367.099 235.997,368.967 C282.1@235.89,369.075
B224_Tx1_to_C_P: C281.1 J1_PCIE2.30 | length 2.2
  L16 w0.081: J1_PCIE2.30@236.69,366.992 236.582,367.099 236.582,368.967 C281.1@236.69,369.075
B224_Tx1C_to_B_N: C282.2 U1.M1 | length 177.9
  L12 (Sign) w0.073: v3(173.397,288.539) 173.397,288.707 ccw(c173.165,288.707) 173.165,288.939 ccw(c173.165,288.749) 172.974,288.749 172.974,287.539 172.974,281.876 ccw(c173.52,281.876) 173.52,281.33 215.709,281.33 ccw(c215.709,281.762) 216.141,281.762 216.141,354.072 cw(c218.313,354.072) 218.313,356.244 242.541,356.244 ccw(c242.541,358.318) 244.615,358.318 244.615,369.722 ccw(c243.421,369.722) 243.421,370.916 236.616,370.916 cw(c236.616,371.348) 236.184,371.348 236.184,371.371 ccw(c235.991,371.371) v14(235.991,371.564)
  L16 w0.073: v14(235.991,371.564) cw(c235.991,371.47) 236.086,371.47 236.086,369.785
  L16 w0.081: C282.2@235.89,369.595 cw(c236.08,369.595) 236.08,369.785 236.086,369.785
B224_Tx1C_to_B_P: C281.2 U1.M2 | length 178.7
  L12 (Sign) w0.073: v3(173.397,289.539) 173.397,289.372 cw(c173.165,289.372) 173.165,289.139 ccw(c173.165,288.749) 172.774,288.749 172.774,287.539 172.774,281.877 ccw(c173.52,281.877) 173.52,281.131 215.709,281.131 ccw(c215.709,281.762) 216.341,281.762 216.341,354.072 cw(c218.313,354.072) 218.313,356.044 242.541,356.044 ccw(c242.541,358.318) 244.814,358.318 244.814,369.722 ccw(c243.421,369.722) 243.421,371.116 236.616,371.116 cw(c236.616,371.348) 236.384,371.348 236.384,371.371 cw(c236.577,371.371) v14(236.577,371.564)
  L16 w0.073: v14(236.577,371.564) ccw(c236.577,371.523) 236.536,371.523 236.536,369.939 ccw(c236.69,369.939) 236.69,369.785
  L16 w0.081: C281.2@236.69,369.595 236.69,369.785
B224_Tx2_to_C_N: C284.1 J1_PCIE3.26 | length 2.4
  L16 w0.081: J1_PCIE3.26@73.585,366.992 73.585,367.925 cw(c73.692,367.925) 73.692,368.032 73.692,369.005 ccw(c73.585,369.005) 73.585,369.113 C284.1@73.585,369.303
B224_Tx2_to_C_P: C283.1 J1_PCIE3.24 | length 2.4
  L16 w0.081: J1_PCIE3.24@74.385,366.992 74.385,367.925 ccw(c74.277,367.925) 74.277,368.032 74.277,369.113 ccw(c74.277,369.22) 74.385,369.22 C283.1@74.385,369.303
B224_Tx2C_to_B_N: C284.2 U1.K1 | length 179.4
  L5 (Sign) w0.073: v1(154.076,302.784) 154.076,302.946 cw(c154.114,302.946) 154.114,302.984 cw(c154.114,302.587) 154.512,302.587 154.512,289.89 ccw(c155.463,289.89) 155.463,288.939 171.247,288.939 cw(c171.247,288.789) 171.397,288.789 v3(171.397,288.539)
  L12 (Sign) w0.073: v1(73.685,370.789) cw(c73.685,370.589) 73.885,370.589 73.885,350.059 ccw(c74.741,350.059) 74.741,349.203 138.798,349.203 cw(c138.798,348.869) 139.132,348.869 139.132,325.514 ccw(c139.678,325.514) 139.678,324.968 148.996,324.968 cw(c148.996,324.672) 149.292,324.672 149.292,303.739 ccw(c150.048,303.739) 150.048,302.984 153.876,302.984 cw(c153.876,302.784) v1(154.076,302.784)
  L16 w0.081: C284.2@73.585,369.823 73.585,369.907 cw(c73.692,369.907) 73.692,370.014 73.692,370.789 v1(73.685,370.789)
B224_Tx2C_to_B_P: C283.2 U1.K2 | length 179.1
  L5 (Sign) w0.073: v1(154.076,303.384) 154.076,303.222 ccw(c154.114,303.222) 154.114,303.183 cw(c154.114,302.587) 154.711,302.587 154.711,289.89 ccw(c155.462,289.89) 155.462,289.139 171.247,289.139 ccw(c171.247,289.29) 171.397,289.29 v3(171.397,289.539)
  L12 (Sign) w0.073: v1(74.285,370.789) ccw(c74.285,370.589) 74.084,370.589 74.084,350.059 ccw(c74.741,350.059) 74.741,349.402 138.798,349.402 cw(c138.798,348.869) 139.332,348.869 139.332,325.514 ccw(c139.678,325.514) 139.678,325.167 148.996,325.167 cw(c148.996,324.672) 149.492,324.672 149.492,303.739 ccw(c150.048,303.739) 150.048,303.183 153.876,303.183 ccw(c153.876,303.384) v1(154.076,303.384)
  L16 w0.081: v1(74.285,370.789) 74.277,370.789 74.277,370.014 cw(c74.277,369.907) 74.385,369.907 C283.2@74.385,369.823
B224_Tx3_to_C_N: C287.1 J1_PCIE3.32 | length 2.4
  L16 w0.081: J1_PCIE3.32@71.185,366.992 71.185,367.925 cw(c71.292,367.925) 71.292,368.032 71.292,369.113 cw(c71.292,369.22) 71.185,369.22 C287.1@71.185,369.303
B224_Tx3_to_C_P: C286.1 J1_PCIE3.30 | length 2.4
  L16 w0.081: J1_PCIE3.30@71.985,366.992 71.985,367.925 ccw(c71.877,367.925) 71.877,368.032 71.877,369.005 cw(c71.985,369.005) 71.985,369.113 C286.1@71.985,369.303
B224_Tx3C_to_B_N: C287.2 U1.J3 | length 181
  L5 (Sign) w0.073: v1(154.445,304.485) cw(c154.645,304.485) 154.645,304.686 155.092,304.686 cw(c155.092,304.326) 155.452,304.326 155.452,291.643 ccw(c156.15,291.643) 156.15,290.945 161.397,290.945 169.992,290.944 cw(c169.992,290.539) v3(170.397,290.539)
  L12 (Sign) w0.073: v1(71.285,372.529) cw(c71.285,372.329) 71.485,372.329 71.485,372.212 ccw(c71.879,372.212) 71.879,371.818 74.765,371.818 cw(c74.765,371.598) 74.984,371.598 74.984,351.815 ccw(c75.861,351.815) 75.861,350.939 77.216,350.939 139.497,350.939 cw(c139.497,350.262) 140.174,350.262 140.174,328.46 ccw(c140.772,328.46) 140.772,327.862 143.942,327.862 cw(c143.942,327.283) 144.521,327.283 144.521,326.771 ccw(c145.3,326.771) 145.3,325.992 149.809,325.992 cw(c149.809,325.303) 150.499,325.303 150.499,305.384 ccw(c151.197,305.384) 151.197,304.686 154.244,304.686 cw(c154.244,304.485) v1(154.445,304.485)
  L16 w0.081: C287.2@71.185,369.823 71.185,369.907 cw(c71.292,369.907) 71.292,370.014 71.292,372.529 v1(71.285,372.529)
B224_Tx3C_to_B_P: C286.2 U1.J4 | length 180.7
  L5 (Sign) w0.073: v1(154.445,305.085) ccw(c154.645,305.085) 154.645,304.885 155.092,304.885 cw(c155.092,304.326) 155.651,304.326 155.651,291.643 ccw(c156.15,291.643) 156.15,291.144 161.397,291.144 170.002,291.144 ccw(c170.002,291.539) v3(170.397,291.539)
  L12 (Sign) w0.073: v1(71.885,372.529) ccw(c71.885,372.329) 71.684,372.329 71.684,372.212 ccw(c71.879,372.212) 71.879,372.017 74.765,372.017 cw(c74.765,371.598) 75.184,371.598 75.184,351.815 ccw(c75.861,351.815) 75.861,351.139 77.216,351.139 139.497,351.139 cw(c139.497,350.262) 140.373,350.262 140.373,328.46 ccw(c140.772,328.46) 140.772,328.061 143.942,328.061 cw(c143.942,327.283) 144.721,327.283 144.721,326.771 ccw(c145.3,326.771) 145.3,326.192 149.809,326.192 cw(c149.809,325.303) 150.698,325.303 150.698,305.384 ccw(c151.197,305.384) 151.197,304.885 154.244,304.885 ccw(c154.244,305.085) v1(154.445,305.085)
  L16 w0.081: v1(71.885,372.529) 71.877,372.529 71.877,370.014 cw(c71.877,369.907) 71.985,369.907 C286.2@71.985,369.823
B225_Rx0_N: J1_PCIE4.21 U1.H5 | length 35.2
  L14 (Sign) w0.076: v3(169.397,292.539) 169.397,292.779 cw(c169.52,292.779) 169.52,292.902 169.62,292.902 cw(c169.62,292.786) 169.736,292.786 169.736,287.539 ccw(c169.736,287.487) 169.683,287.487
  L14 (Sign) w0.08: v9(157.037,274.993) ccw(c157.037,274.883) 156.927,274.883 156.927,274.467 ccw(c157.175,274.467) 157.175,274.218 168.212,274.218 ccw(c168.212,275.69) 169.683,275.69 169.683,287.487
  L16 w0.081: v9(157.037,274.993) 157.03,274.993 157.03,273.034 cw(c157.03,272.927) 157.137,272.927 J1_PCIE4.21@157.137,271.994
B225_Rx0_P: J1_PCIE4.19 U1.H6 | length 36.9
  L14 (Sign) w0.076: v3(169.397,293.539) 169.397,293.3 ccw(c169.52,293.3) 169.52,293.177 169.62,293.177 cw(c169.62,292.786) 170.011,292.786 170.011,287.539 cw(c170.011,287.487) 170.063,287.487
  L14 (Sign) w0.08: v9(156.437,274.993) cw(c156.437,274.883) 156.547,274.883 156.547,274.467 ccw(c157.175,274.467) 157.175,273.839 168.212,273.839 ccw(c168.212,275.69) 170.063,275.69 170.063,287.487
  L16 w0.081: J1_PCIE4.19@156.337,271.994 156.337,272.927 cw(c156.444,272.927) 156.444,273.034 156.444,274.993 v9(156.437,274.993)
B225_Rx1_N: J1_PCIE4.27 U1.G7 | length 32
  L14 (Sign) w0.076: 168.086,287.487 ccw(c168.034,287.487) 168.034,287.539 168.034,294.754 cw(c168.181,294.754) 168.181,294.902 168.313,294.902 cw(c168.313,294.818) 168.397,294.818 v3(168.397,294.539)
  L14 (Sign) w0.08: v9(159.437,274.752) cw(c159.437,274.862) 159.327,274.862 159.327,275.133 cw(c159.568,275.133) 159.568,275.374 167.321,275.374 ccw(c167.321,276.139) 168.086,276.139 168.086,287.487
  L16 w0.081: v9(159.437,274.752) 159.43,274.752 159.43,273.034 cw(c159.43,272.927) 159.537,272.927 J1_PCIE4.27@159.537,271.994
B225_Rx1_P: J1_PCIE4.25 U1.G8 | length 32.5
  L14 (Sign) w0.076: 167.706,287.487 cw(c167.758,287.487) 167.758,287.539 167.758,294.754 cw(c168.181,294.754) 168.181,295.177 168.313,295.177 ccw(c168.313,295.261) 168.397,295.261 v3(168.397,295.539)
  L14 (Sign) w0.08: v9(158.837,274.752) ccw(c158.837,274.862) 158.947,274.862 158.947,275.133 cw(c159.568,275.133) 159.568,275.754 167.321,275.754 ccw(c167.321,276.139) 167.706,276.139 167.706,287.487
  L16 w0.081: J1_PCIE4.25@158.737,271.994 158.737,272.927 cw(c158.844,272.927) 158.844,273.034 158.844,274.752 v9(158.837,274.752)
B225_Rx2_N: U1.F5
  other v3: 167.397,292.539
B225_Rx2_P: U1.F6
  other v3: 167.397,293.539
B225_Rx3_N: U1.E7
  other v3: 166.397,294.539
B225_Rx3_P: U1.E8
  other v3: 166.397,295.539
B225_Tx0_to_C_N: C292.1 J1_PCIE4.26 | length 1.9
  L16 w0.081: C292.1@159.137,261.861 J1_PCIE4.26@159.137,263.794
B225_Tx0_to_C_P: C291.1 J1_PCIE4.24 | length 1.9
  L16 w0.081: C291.1@158.337,261.861 J1_PCIE4.24@158.337,263.794
B225_Tx0C_to_B_N: C292.2 U1.H1 | length 48.4
  L12 (Sign) w0.073: v1(159.037,260.528) ccw(c159.037,260.328) 158.837,260.328 158.837,258.942 ccw(c160.134,258.942) 160.134,257.645 169.355,257.645 ccw(c169.355,260.185) 171.894,260.185 171.894,269.46 ccw(c171.12,269.46) 171.12,270.234 cw(c171.12,271.555) 169.799,271.555 169.799,287.539 169.799,288.698 ccw(c169.558,288.698) 169.558,288.939 ccw(c169.558,288.779) 169.397,288.779 v3(169.397,288.539)
  L16 w0.081: v1(159.037,260.528) 159.03,260.528 159.03,261.151 ccw(c159.03,261.258) 159.137,261.258 C292.2@159.137,261.341
B225_Tx0C_to_B_P: C291.2 U1.H2 | length 49.4
  L12 (Sign) w0.073: v1(158.437,260.528) cw(c158.437,260.328) 158.637,260.328 158.637,258.942 ccw(c160.134,258.942) 160.134,257.445 169.355,257.445 ccw(c169.355,260.185) 172.094,260.185 172.094,269.46 ccw(c171.12,269.46) 171.12,270.434 cw(c171.12,271.555) 169.999,271.555 169.999,287.539 169.999,288.698 ccw(c169.558,288.698) 169.558,289.139 cw(c169.558,289.3) 169.397,289.3 v3(169.397,289.539)
  L16 w0.081: C291.2@158.337,261.341 158.337,261.258 ccw(c158.444,261.258) 158.444,261.151 158.444,260.528 v1(158.437,260.528)
B225_Tx1_to_C_N: C294.1 J1_PCIE4.32 | length 1.9
  L16 w0.081: C294.1@161.537,261.861 J1_PCIE4.32@161.537,263.794
B225_Tx1_to_C_P: C293.1 J1_PCIE4.30 | length 1.9
  L16 w0.081: C293.1@160.737,261.861 J1_PCIE4.30@160.737,263.794
B225_Tx1C_to_B_N: C294.2 U1.G3 | length 42.2
  L12 (Sign) w0.073: v1(161.437,260.502) ccw(c161.437,260.292) 161.226,260.292 161.226,260.172 ccw(c162.573,260.172) 162.573,258.826 168.097,258.826 ccw(c168.097,259.512) 168.783,259.512 168.783,287.539 168.783,290.792 ccw(c168.635,290.792) 168.635,290.939 168.542,290.939 ccw(c168.542,290.795) 168.397,290.795 v3(168.397,290.539)
  L16 w0.081: v1(161.437,260.502) 161.43,260.502 161.43,261.151 ccw(c161.43,261.258) 161.537,261.258 C294.2@161.537,261.341
B225_Tx1C_to_B_P: C293.2 U1.G4 | length 43.1
  L12 (Sign) w0.073: v1(160.837,260.502) cw(c160.837,260.313) 161.027,260.313 161.027,260.172 ccw(c162.573,260.172) 162.573,258.626 168.097,258.626 ccw(c168.097,259.512) 168.983,259.512 168.983,287.539 168.983,290.792 ccw(c168.635,290.792) 168.635,291.139 168.542,291.139 cw(c168.542,291.284) 168.397,291.284 v3(168.397,291.539)
  L16 w0.081: C293.2@160.737,261.341 160.737,261.258 ccw(c160.844,261.258) 160.844,261.151 160.844,260.502 v1(160.837,260.502)
B225_Tx2_to_C_N: C296.1 J1_PCIE4.38 | length 1.9
  L16 w0.081: C296.1@163.937,261.861 J1_PCIE4.38@163.937,263.794
B225_Tx2_to_C_P: C295.1 J1_PCIE4.36 | length 1.9
  L16 w0.081: C295.1@163.137,261.861 J1_PCIE4.36@163.137,263.794
B225_Tx2C_to_B_N: C296.2 U1.F1 | length 35.6
  L12 (Sign) w0.073: v1(163.837,260.528) ccw(c163.837,260.328) 163.637,260.328 163.637,259.921 ccw(c163.893,259.921) 163.893,259.664 167.259,259.664 ccw(c167.259,260.172) 167.767,260.172 167.767,287.539 167.767,288.785 ccw(c167.613,288.785) 167.613,288.939 167.475,288.939 ccw(c167.475,288.861) 167.397,288.861 v3(167.397,288.539)
  L16 w0.081: v1(163.837,260.528) 163.83,260.528 163.83,261.151 ccw(c163.83,261.258) 163.937,261.258 C296.2@163.937,261.341
B225_Tx2C_to_B_P: C295.2 U1.F2 | length 36.5
  L12 (Sign) w0.073: v1(163.237,260.528) cw(c163.237,260.328) 163.437,260.328 163.437,259.921 ccw(c163.893,259.921) 163.893,259.465 167.259,259.465 ccw(c167.259,260.172) 167.967,260.172 167.967,287.539 167.967,288.785 ccw(c167.613,288.785) 167.613,289.139 167.475,289.139 cw(c167.475,289.217) 167.397,289.217 v3(167.397,289.539)
  L16 w0.081: C295.2@163.137,261.341 163.137,261.258 ccw(c163.244,261.258) 163.244,261.151 163.244,260.528 v1(163.237,260.528)
B225_Tx3_to_C_N: C299.1 J1_PCIE4.44 | length 1.9
  L16 w0.081: C299.1@166.337,261.861 J1_PCIE4.44@166.337,263.794
B225_Tx3_to_C_P: C298.1 J1_PCIE4.42 | length 1.9
  L16 w0.081: C298.1@165.537,261.861 J1_PCIE4.42@165.537,263.794
B225_Tx3C_to_B_N: C299.2 U1.E3 | length 32.1
  L12 (Sign) w0.073: v1(166.189,260.528) 166.179,260.528 cw(c166.179,260.718) 165.989,260.718 165.989,287.539 165.989,290.673 cw(c166.256,290.673) 166.256,290.939 cw(c166.256,290.798) 166.397,290.798 v3(166.397,290.539)
  L16 w0.081: v1(166.189,260.528) 166.189,261.151 ccw(c166.189,261.299) 166.337,261.299 C299.2@166.337,261.341
B225_Tx3C_to_B_P: C298.2 U1.E4 | length 32.3
  L12 (Sign) w0.073: v1(165.589,260.528) 165.599,260.528 ccw(c165.599,260.718) 165.789,260.718 165.789,287.539 165.789,290.673 cw(c166.256,290.673) 166.256,291.139 ccw(c166.256,291.281) 166.397,291.281 v3(166.397,291.539)
  L16 w0.081: C298.2@165.537,261.341 165.537,261.203 ccw(c165.589,261.203) 165.589,261.151 v1(165.589,260.528)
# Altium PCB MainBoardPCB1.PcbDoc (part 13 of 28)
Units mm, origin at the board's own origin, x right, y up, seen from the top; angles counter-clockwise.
Board outline 258.95 x 308.86 mm, 16 copper layers (L1, L2 (GND), L3 (Sign), L4 (GND), L5 (Sign), L6 (PWR/GND), L7(PWR/GND), L8 (Plane_GND), L9 (PWR/GND), L10 (PWR/GND), L11 (PWR/GND), L12 (Sign), L13 (GND), L14 (Sign), L15 (GND), L16), stack 2.502 mm thick; 2397 components, 1744 nets, 8397 pads, 4112 vias.
Unrouted connection lines stored in the file: 3547.

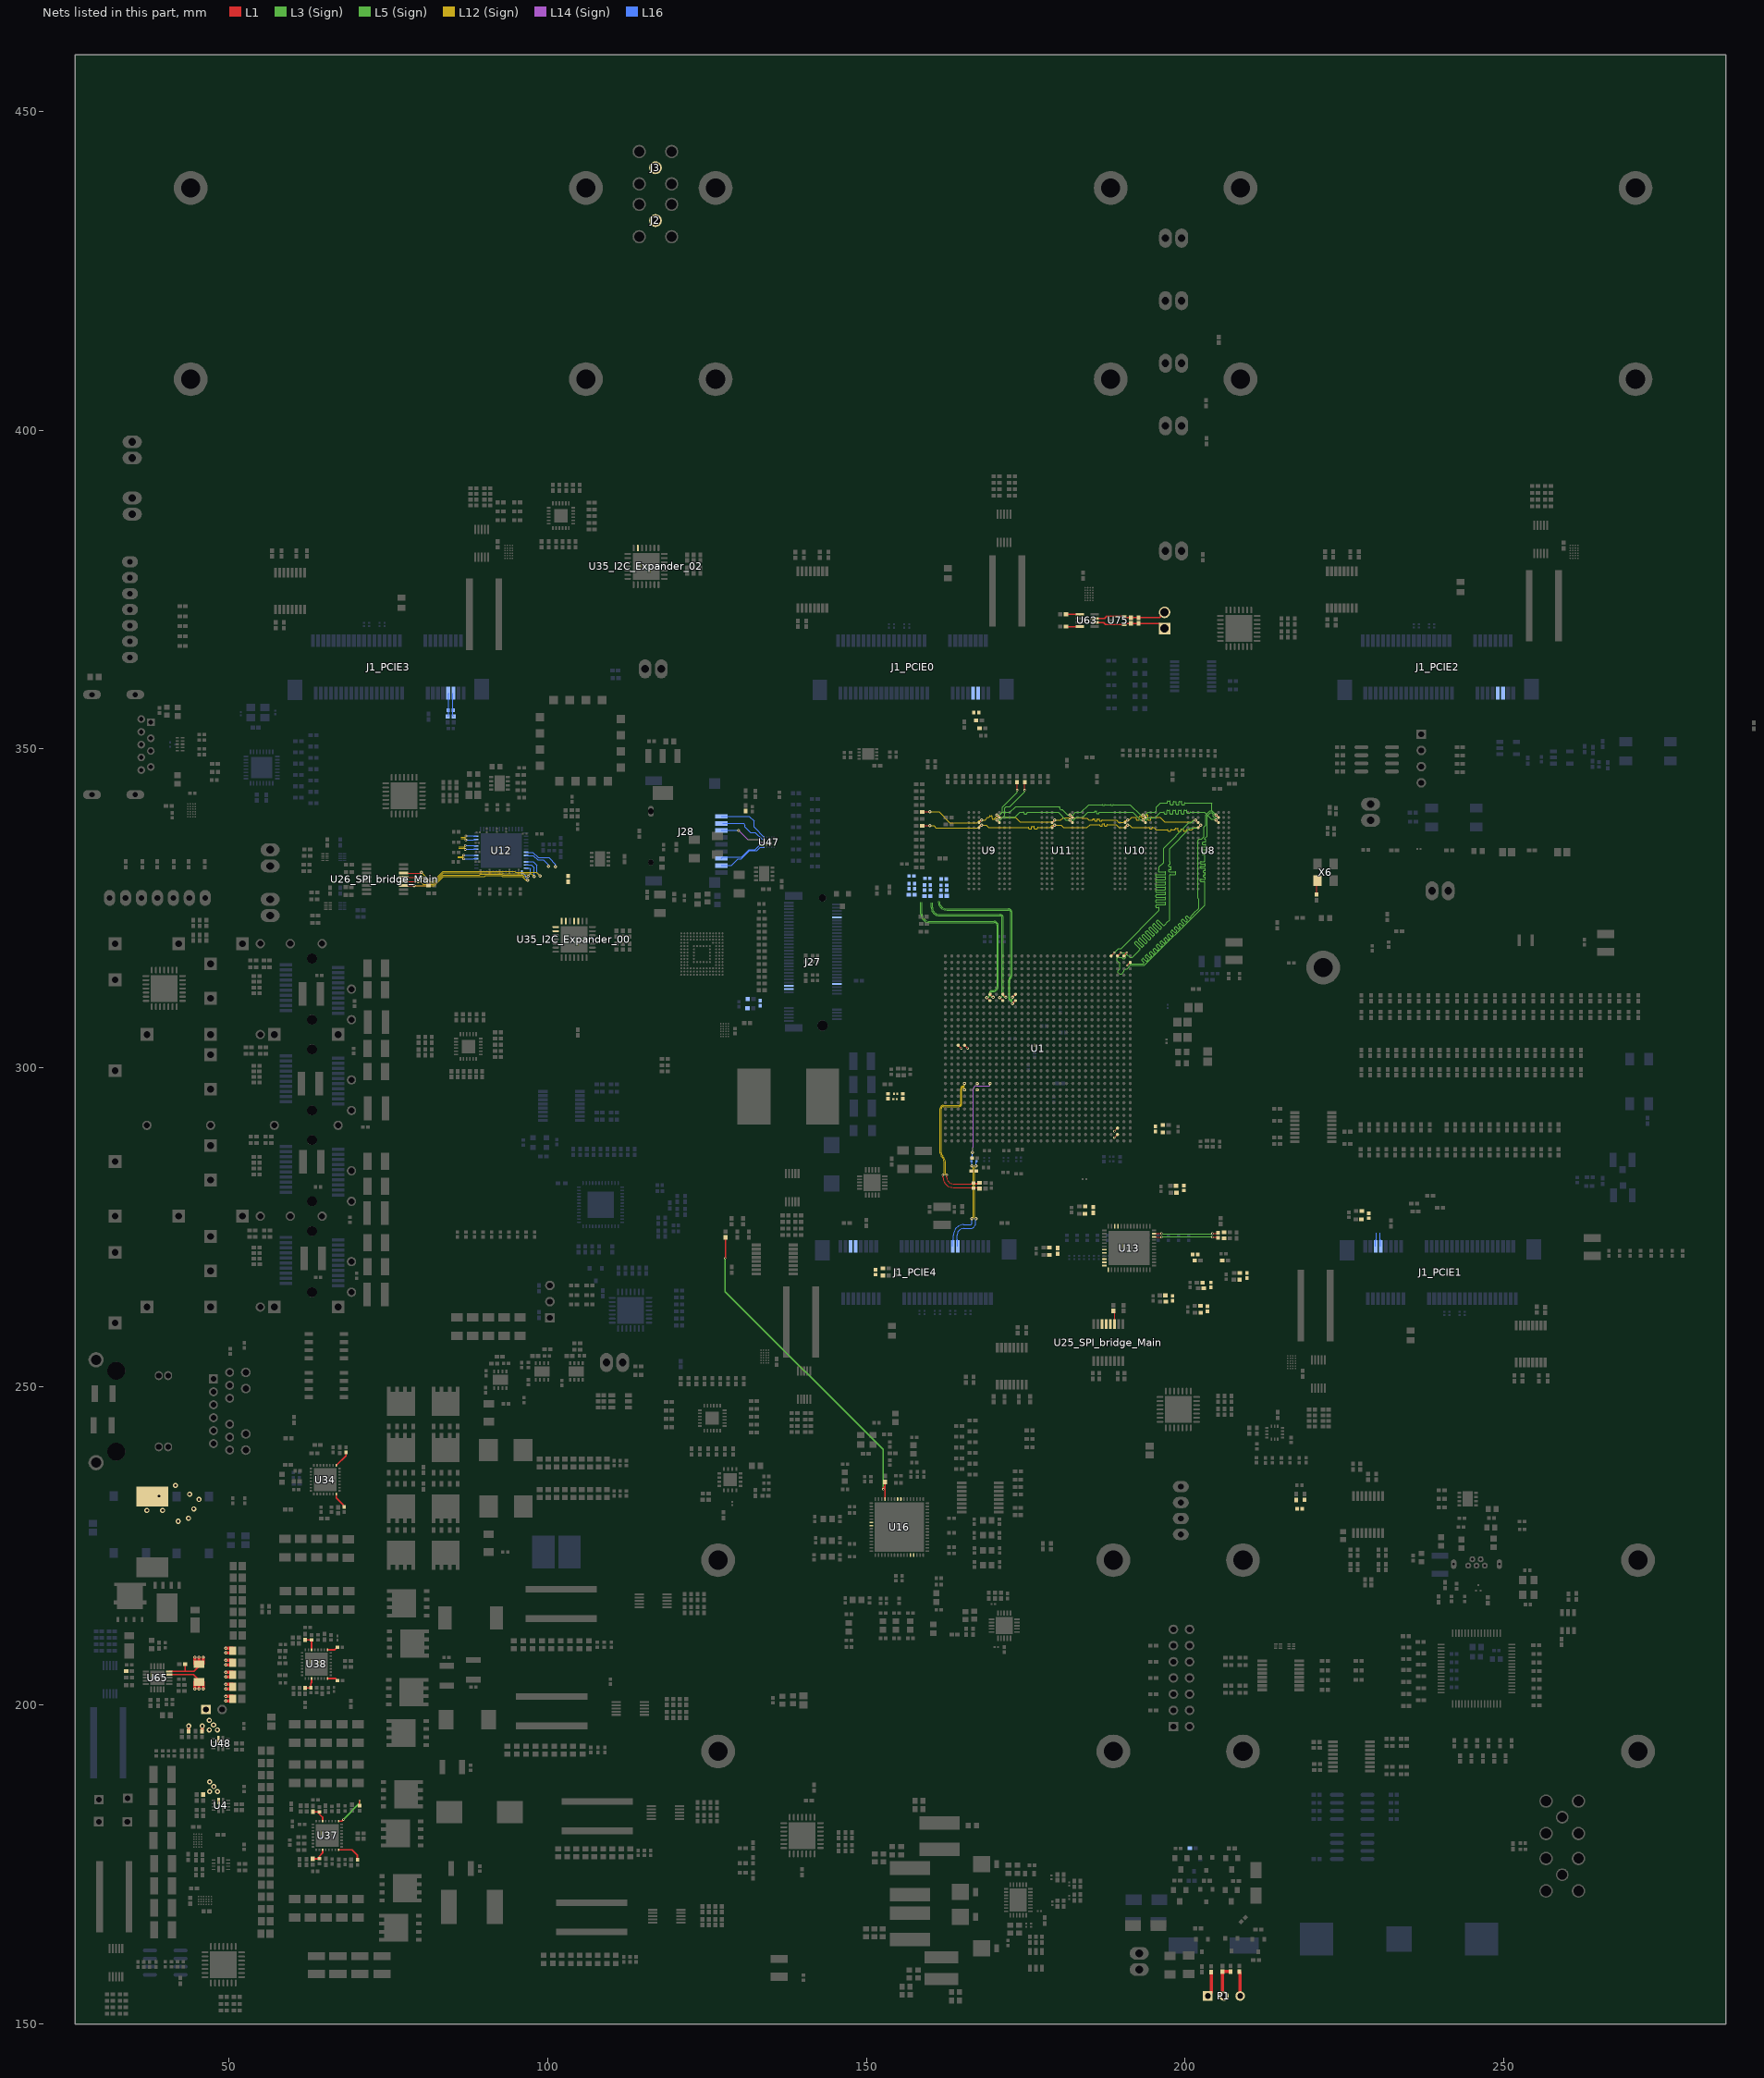
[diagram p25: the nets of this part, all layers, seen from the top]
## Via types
v1: diameter 0.5, hole 0.2, L1 to L16, tented both sides, 1457 vias
v2: diameter 0.35/0/0.35 (per signal layer), hole 0.127, L1 to L3 (Sign), tented both sides, 479 vias
v3: diameter 0.5/0.35/0.35/0.35/0.35/0.35/0.35/0.35/0.35/0.35/0.35/0.35/0.35/0.35/0.35/0.5 (per signal layer), hole 0.15, L1 to L16, tented both sides, 453 vias
v4: diameter 0.5, hole 0.2, L1 to L16, 451 vias
v5: diameter 0.5/0.35/0.35/0.35/0.35/0.35/0.35/0.35/0.35/0.35/0.35/0.35/0.35/0.35/0.35/0.5 (per signal layer), hole 0.2, L1 to L16, tented both sides, 373 vias
v6: diameter 0.8, hole 0.4, L1 to L16, tented both sides, 168 vias
v7: diameter 0.35/0/0.35 (per signal layer), hole 0.127, L1 to L3 (Sign), 138 vias
v8: diameter 2.54, hole 1.02, L1 to L16, 113 vias
v9: diameter 0.5/0/0.5 (per signal layer), hole 0.2, L14 (Sign) to L16, tented both sides, 102 vias
v10: diameter 1.4, hole 0.5, L1 to L16, tented both sides, 80 vias
v11: diameter 0.5, hole 0.2, L3 (Sign) to L6 (PWR/GND), tented both sides, 54 vias
v12: diameter 0.35, hole 0.127, L1 to L2 (GND), tented both sides, 47 vias
v13: diameter 0.4, hole 0.2, L1 to L16, tented both sides, 46 vias
v14: diameter 0.35, hole 0.127, L1 to L16, tented both sides, 16 vias
v15: diameter 0.25, hole 0.2, L1 to L16, 16 vias
v16: diameter 0.5, hole 0.2, L11 (PWR/GND) to L14 (Sign), tented both sides, 16 vias
v17: diameter 0.4, hole 0.2, L1 to L16, 16 vias
v18: diameter 0.3, hole 0.2, L1 to L16, 15 vias
v19: diameter 0.45, hole 0.15, L1 to L16, 12 vias
v20: diameter 0.5/0.35/0.35/0.35/0.35/0.35/0.35/0.35/0.35/0.35/0.35/0.35/0.35/0.35/0.35/0.45 (per signal layer), hole 0.15, L1 to L16, tented both sides, 10 vias
v21: diameter 0.2/0/0.2 (per signal layer), hole 0.1, L1 to L3 (Sign), tented both sides, 9 vias
v22: diameter 0.3, hole 0.127, L14 (Sign) to L16, tented both sides, 8 vias
v23: diameter 0.4, hole 0.1, L1 to L16, 7 vias
v24: diameter 1.15, hole 1.15, L1 to L16, 5 vias
v25: diameter 1.65, hole 1.65, L1 to L16, 5 vias
v26: diameter 0.2, hole 0.1, L1 to L16, 4 vias
v27: diameter 0.4, hole 0.15, L1 to L16, 2 vias
v28: diameter 0.5/0.35/0.35/0.35/0.35/0.35/0.35/0.35/0.35/0.35/0.35/0.35/0.35/0.35/0.35/0.5 (per signal layer), hole 0.15, L1 to L16, 2 vias
v29: diameter 0.35, hole 0.127, L3 (Sign) to L6 (PWR/GND), tented both sides, 2 vias
v30: diameter 0.3, hole 0.127, L15 (GND) to L16, tented both sides, 1 vias
v31: diameter 0.35, hole 0.127, L1 to L2 (GND), 1 vias
v32: diameter 0.5/0.35/0.35/0.35/0.35/0.35/0.35/0.35/0.35/0.35/0.35/0.35/0.35/0.35/0.35/0.5 (per signal layer), hole 0.2, L1 to L16, 1 vias
v33: diameter 0.35/0.35/0.35 (per signal layer), hole 0.127, L1 to L3 (Sign), tented both sides, 1 vias
v34: diameter 0.45/0/0.45 (per signal layer), hole 0.15, L1 to L3 (Sign), tented both sides, 1 vias
v35: diameter 0.45/0/0.45 (per signal layer), hole 0.2, L14 (Sign) to L16, tented both sides, 1 vias

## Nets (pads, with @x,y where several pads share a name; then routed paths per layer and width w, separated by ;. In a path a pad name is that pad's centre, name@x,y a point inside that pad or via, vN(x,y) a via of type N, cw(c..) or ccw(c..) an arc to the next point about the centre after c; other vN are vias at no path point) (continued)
Bank225_MGTREF0_C_P: C297.1 C819.2 U1.H10 | length 14.1
  L14 (Sign) w0.076: 166.728,287.487 cw(c166.78,287.487) 166.78,287.539 166.78,296.659 cw(c167.298,296.659) 167.298,297.177 169.227,297.177 ccw(c169.227,297.347) 169.397,297.347 v3(169.397,297.539)
  L14 (Sign) w0.08: v9(166.618,286.741) ccw(c166.618,286.851) 166.728,286.851 166.728,287.487
  L16 w0.081: C297.1@166.472,285.89 166.472,285.934 cw(c166.618,285.934) 166.618,286.08 v9(166.618,286.741)
Bank225_MGTREF0_N: C300.2 C820.1 J1_PCIE4.39 | length 15.9
  L12 (Sign) w0.073: v1(167.181,276.314) 167.158,276.314 cw(c167.158,276.492) 166.98,276.492 166.98,284.381 cw(c167.181,284.381) v1(167.181,284.582)
  L16 w0.073: v1@167.173,276.314 v1(167.181,276.314)
  L16 w0.081: J1_PCIE4.39@164.337,271.994 164.337,272.927 ccw(c164.23,272.927) 164.23,273.034 164.23,273.744 cw(c165.275,273.744) 165.275,274.789 166.258,274.789 ccw(c166.258,275.704) 167.173,275.704 v1@167.173,276.314 ; v1@167.177,284.493 v1@167.177,284.582 ; v1(167.181,284.582) v1@167.177,284.582 ; C300.2@167.297,285.37 167.297,285.299 cw(c167.177,285.299) 167.177,285.179 v1@167.177,284.582
Bank225_MGTREF0_P: C297.2 C820.2 J1_PCIE4.37 | length 16
  L12 (Sign) w0.073: v1(166.581,276.314) 166.603,276.314 ccw(c166.603,276.492) 166.781,276.492 166.781,284.381 ccw(c166.581,284.381) v1(166.581,284.582)
  L16 w0.073: v1(166.581,276.314) v1@166.588,276.314
  L16 w0.081: J1_PCIE4.37@163.537,271.994 163.537,272.927 cw(c163.644,272.927) 163.644,273.034 163.644,273.744 cw(c165.275,273.744) 165.275,275.374 166.258,275.374 ccw(c166.258,275.704) 166.588,275.704 v1@166.588,276.314 ; C297.2@166.472,285.37 166.472,285.299 ccw(c166.592,285.299) 166.592,285.179 166.592,284.493 166.584,284.493 166.584,284.582 v1(166.581,284.582)
Bank225_MGTREF1_C_N: C302.1 C821.2 U1.F9
  other v3: 167.397,296.539
Bank225_MGTREF1_C_P: C301.1 C821.1 U1.F10
  other v3: 167.397,297.539
Bank225_MGTREF1_N: C302.2 C822.2
Bank225_MGTREF1_P: C301.2 C822.1
Bank505_MGTRREF0_C_N: C526.2 R69.2 U1.M24 | length 27.5
  L1 w0.116: v5(172.909,311.052) U1.M24@173.397,311.539
  L5 (Sign) w0.073: 161.442,326.123 ccw(c162.614,326.123) 162.614,324.951 172.301,324.951 cw(c172.301,324.421) 172.831,324.421 172.831,318.539 172.831,314.49 cw(c172.272,314.49) 172.667,314.095 172.606,314.033 ccw(c172.79,313.849) 172.529,313.849 172.529,310.855 ccw(c172.733,310.855) 172.733,310.652 ccw(c172.733,310.829) 172.909,310.829 v5(172.909,311.052)
Bank505_MGTRREF0_C_P: C525.2 R69.1 U1.M23 | length 27.8
  L1 w0.116: v5(172.909,310.052) U1.M23@173.397,310.539
  L5 (Sign) w0.073: 161.243,326.123 ccw(c162.614,326.123) 162.614,324.752 172.301,324.752 cw(c172.301,324.421) 172.631,324.421 172.631,318.539 172.631,314.49 cw(c172.271,314.49) 172.526,314.236 172.463,314.173 ccw(c172.786,313.85) 172.329,313.85 172.33,310.855 ccw(c172.733,310.855) 172.733,310.452 cw(c172.733,310.275) 172.909,310.275 v5(172.909,310.052)
Bank505_MGTRREF2_C_N: C528.2 R126.2 U1.K24 | length 26.2
  L1 w0.116: U1.K24@171.397,311.539 v5(171.884,311.052)
  L5 (Sign) w0.073: 160.363,325.895 160.363,325.145 ccw(c161.471,325.145) 161.471,324.037 170.996,324.037 cw(c170.996,323.536) 171.497,323.536 171.497,318.539 171.497,311.328 ccw(c171.773,311.328) 171.773,311.052 v5(171.884,311.052)
Bank505_MGTRREF2_C_P: C527.2 R126.1 U1.K23 | length 26.3
  L1 w0.116: v5(170.909,311.027) U1.K23@171.397,310.539
  L5 (Sign) w0.073: 160.163,325.895 160.163,325.145 ccw(c161.471,325.145) 161.471,323.837 170.996,323.837 cw(c170.996,323.536) 171.297,323.536 171.297,318.539 171.297,311.328 cw(c170.996,311.328) 170.996,311.027 v5(170.909,311.027)
Bank505_MGTRREF3_C_N: C530.2 R70.2 U1.H24 | length 27.8
  L1 w0.116: U1.H24@169.397,311.539 v5(169.884,311.052)
  L5 (Sign) w0.073: 158.737,325.971 158.737,324.142 ccw(c159.897,324.142) 159.897,322.983 170.02,322.983 cw(c170.02,322.293) 170.71,322.293 170.71,318.539 170.71,312.788 cw(c169.847,312.788) 169.847,311.925 169.736,311.925 ccw(c169.736,311.686) 169.497,311.686 169.497,311.328 ccw(c169.773,311.328) 169.773,311.052 v5(169.884,311.052)
Bank505_MGTRREF3_C_P: C529.2 R70.1 U1.H23 | length 27.8
  L1 w0.116: v5(168.909,311.027) U1.H23@169.397,310.539
  L5 (Sign) w0.073: 158.538,325.971 158.538,324.142 ccw(c159.897,324.142) 159.897,322.783 170.02,322.783 cw(c170.02,322.293) 170.51,322.293 170.51,318.539 170.51,312.788 cw(c169.847,312.788) 169.847,312.125 169.736,312.125 ccw(c169.736,311.686) 169.297,311.686 169.297,311.328 cw(c168.996,311.328) 168.996,311.027 v5(168.909,311.027)
Battery_PWR: P11.1 R679.2 R680.2 U48.2 | length 1.6
  L1 w0.5: R680.2@43.658,195.933 v6(43.658,196.747) ; R679.2@45.775,195.933 v6(45.775,196.747)
  other v6: 46.906,196.145 48.155,196.145 47.566,196.91 46.907,197.647
  other v17: 48.327,194.383
BST1: C346.1 U34.25 | length 2.7
  L1 w0.254: U34.25@66.822,237.639 66.822,237.71 66.824,237.712 66.895,237.712 68.336,239.154 C346.1@68.336,239.69
BST1_1: C390.1 U37.25 | length 5.7
  L1 w0.2: U37.25@67.175,181.817 67.675,181.817 v2(67.925,182.067) ; C390.1@70.485,184.24 v2(70.485,185.052)
  L3 (Sign) w0.2: v2(67.925,182.067) 70.485,184.627 v2(70.485,185.052)
BST1_2: C431.1 U38.25 | length 1.7
  L1 w0.254: U38.25@65.453,208.714 66.596,208.714 66.996,209.114 C431.1@67.001,209.114
BST2: C350.1 U34.16 | length 2.6
  L1 w0.254: U34.16@66.822,233.139 66.822,232.556 67.929,231.449 67.929,231.245 C350.1@68.072,231.102
BST2_1: C394.1 U37.16 | length 4
  L1 w0.254: U37.16@67.175,177.317 69.292,177.317 70.142,176.466 C394.1@70.142,175.763
BST2_2: C435.1 U38.16 | length 1.7
  L1 w0.254: U38.16@65.453,204.214 66.661,204.214 67.011,203.864 C435.1@67.016,203.864
CAN0_H: P6.2 R446.2 R447.2 U63.7 U75.2 | length 11.5
  L1 w0.2: U63.7@185.82,370.492 187.392,370.492 187.717,370.817 U75.2@190.459,370.817 190.659,370.617 R446.2@191.516,370.617 195.979,370.617 P6.2@196.799,371.437
CAN0_L: P6.1 R446.1 R447.1 U63.6 U75.1 | length 11.5
  L1 w0.2: U63.6@185.82,369.842 187.227,369.842 187.552,369.517 U75.1@190.459,369.517 190.659,369.717 R446.1@191.516,369.717 R447.1@192.684,369.717 195.979,369.717 P6.1@196.799,368.897
CAN1_RxD: R798.1 U63.1 | length 2.2
  L1 w0.2: R798.1@181.305,371.142 U63.1@183.47,371.142
CAN1_TxD: R799.1 U63.4 | length 2.2
  L1 w0.2: R799.1@181.305,369.192 U63.4@183.47,369.192
Charge_CAP: R658.2 U35_I2C_Expander_02.20
CLK0_EZS.N: R81.1 U1.C16 U12.48 | length 5
  L1 w0.116: U1.C16@164.397,303.539 v2(164.884,303.052)
  L16 w0.12: U12.48@96.597,333.311 97.74,333.311 98.438,332.613 99.314,332.613 100.114,331.813 v1(100.114,331.635)
CLK0_EZS.P: R81.2 U1.D16 U12.47 | length 6.5
  L1 w0.116: U1.D16@165.397,303.539 v2(165.884,303.052)
  L3 (Sign) w0.12: v2@165.877,303.052 v2(165.884,303.052)
  L16 w0.12: U12.47@96.597,333.811 97.678,333.811 98.528,332.961 100.185,332.961 101.232,331.914 v1(101.232,331.521)
CLK0_Out0.N: C315.1 J1_PCIE0.7 R1054.1
CLK0_Out0.P: C315.2 J1_PCIE0.5 R539.1
CLK0_Out1.N: C317.1 J1_PCIE2.7 R1056.1
CLK0_Out1.P: C317.2 J1_PCIE2.5 R1055.1
CLK0_Out2.N: C319.1 J1_PCIE3.7 R1058.1 | length 3.9
  L16 w0.1: R1058.1@84.303,355.105 84.47,355.273 84.47,356.007 C319.1@84.383,356.095 84.483,356.195 84.483,358.694 J1_PCIE3.7@84.385,358.792
CLK0_Out2.P: C319.2 J1_PCIE3.5 R1057.1 | length 3.9
  L16 w0.1: J1_PCIE3.5@85.185,358.792 85.087,358.694 85.087,356.171 C319.2@85.163,356.095 85.075,356.007 85.075,355.273 R1057.1@85.242,355.105
CLK0_Out3.N: C478.2 C530.1 U12.24 | length 2.6
  L12 (Sign) w0.073: 86.374,335.961 86.958,335.961 cw(c86.958,335.759) v13(87.16,335.759)
  L16 w0.1: v13(87.16,335.759) 88.397,335.759 cw(c88.449,335.759) 88.449,335.811 U12.24@88.797,335.811
CLK0_Out3.P: C478.1 C529.1 U12.25 | length 2.6
  L12 (Sign) w0.073: 86.374,336.161 86.958,336.161 ccw(c86.958,336.363) v13(87.16,336.363)
  L16 w0.1: v13(87.16,336.363) 88.397,336.363 ccw(c88.449,336.363) 88.449,336.311 U12.25@88.797,336.311
CLK0_Out4.N: C528.1 C594.1 U12.21 | length 2.9
  L12 (Sign) w0.073: 86.03,334.461 86.844,334.461 cw(c86.844,334.259) v13(87.046,334.259)
  L16 w0.1: v13(87.046,334.259) 88.397,334.259 cw(c88.449,334.259) 88.449,334.311 U12.21@88.797,334.311
CLK0_Out4.P: C527.1 C594.2 U12.22 | length 2.9
  L12 (Sign) w0.073: 86.03,334.661 86.844,334.661 ccw(c86.844,334.863) v13(87.046,334.863)
  L16 w0.1: v13(87.046,334.863) 88.397,334.863 ccw(c88.449,334.863) 88.449,334.811 U12.22@88.797,334.811
CLK0_Out5.N: C526.1 C599.2 U12.18 | length 3
  L12 (Sign) w0.073: 85.915,332.961 86.615,332.961 cw(c86.615,332.759) v13(86.817,332.759)
  L16 w0.1: v13(86.817,332.759) 88.397,332.759 cw(c88.449,332.759) 88.449,332.811 U12.18@88.797,332.811
CLK0_Out5.P: C525.1 C599.1 U12.19 | length 3
  L12 (Sign) w0.073: 85.915,333.161 86.615,333.161 ccw(c86.615,333.363) v13(86.817,333.363)
  L16 w0.1: v13(86.817,333.363) 88.397,333.363 ccw(c88.449,333.363) 88.449,333.311 U12.19@88.797,333.311
CLK0_Out6.N: C602.1 J27.53 R1068.1
CLK0_Out6.P: C602.2 J27.55 R1067.1
CLK0_Out7.N: C681.1 R1070.1
CLK0_Out7.P: C681.2 R1069.1
CLK0_Out8.N: R534.1 R1072.1 U13.38
CLK0_Out8.P: R534.2 R1071.1 U13.37
CLK0_Out9.N: R535.1 R1074.1 U13.48
CLK0_Out9.P: R535.2 R1073.1 U13.47
CLK0_SPI.C\S\: R236_SPI_bridge_Main.1 U12.1 U26_SPI_bridge_Main.11 | length 24.4
  L1 w0.12: U26_SPI_bridge_Main.11@77.363,328.6 U26_SPI_bridge_Main.11@77.373,328.59 ; U26_SPI_bridge_Main.11@77.371,328.59 U26_SPI_bridge_Main.11@77.373,328.59 ; R236_SPI_bridge_Main.1@81.305,328.59 v1(79.045,328.59) U26_SPI_bridge_Main.11@77.373,328.59
  L12 (Sign) w0.12: v1(79.045,328.59) 79.064,328.57 82.228,328.57 83.684,330.026 90.101,330.026 90.258,330.182 92.687,330.182 92.869,330 96.008,330 96.571,329.438 v1(96.863,329.438)
  L16 w0.12: U12.1@95.947,330.661 96.542,330.066 96.542,329.876 96.782,329.636 96.863,329.636 v1(96.863,329.438)
CLK0_SPI.CLK: U12.50 U26_SPI_bridge_Main.14 | length 26.8
  L1 w0.12: U26_SPI_bridge_Main.14@77.373,330.54 80.02,330.54 v1(80.15,330.67)
  L12 (Sign) w0.12: v1(80.15,330.67) 81.572,329.248 81.972,329.248 83.567,330.842 94.799,330.842 94.964,330.677 98.214,330.677 v1(98.781,330.111)
  L16 w0.12: U12.50@96.597,332.311 97.724,332.311 98.285,331.749 98.285,330.606 v1(98.781,330.111)
CLK0_SPI.MISO: U12.51 U26_SPI_bridge_Main.13 | length 24.6
  L1 w0.12: U26_SPI_bridge_Main.13@77.373,329.895 v1(80.277,329.895)
  L12 (Sign) w0.12: v1(80.277,329.895) 81.152,329.02 82.056,329.02 83.658,330.622 92.87,330.622 93.035,330.457 97.444,330.457 v1(97.879,330.022)
  L16 w0.12: U12.51@96.597,331.811 97.437,331.811 97.879,331.368 v1(97.879,330.022)
CLK0_SPI.MOSI: U12.52 U26_SPI_bridge_Main.12 | length 22.6
  L1 w0.12: U26_SPI_bridge_Main.12@77.373,329.24 v1(79.667,329.24)
  L12 (Sign) w0.12: v1(79.667,329.24) 80.043,329.24 80.493,328.79 82.137,328.79 83.593,330.246 89.333,330.246 89.489,330.402 92.779,330.402 92.944,330.237 96.083,330.237 96.274,330.046 v1(96.952,330.046)
  L16 w0.12: U12.52@96.597,331.311 97.162,331.311 97.32,331.152 97.32,330.414 v1(96.952,330.046)
CLK1_Out0.N: C797.1 R1090.1
CLK1_Out0.P: C797.2 R1089.1
CLK1_Out1.N: C799.1 J1_PCIE4.7 R1092.1
CLK1_Out1.P: C799.2 J1_PCIE4.5 R1091.1
CLK1_Out2.N: C802.1 J1_PCIE1.7 R1094.1 | length 2.2
  L16 w0.081: 230.582,274.117 230.582,273.034 cw(c230.582,272.927) 230.69,272.927 J1_PCIE1.7@230.69,271.994
CLK1_Out2.P: C802.2 J1_PCIE1.5 R1093.1 | length 2.2
  L16 w0.081: J1_PCIE1.5@229.89,271.994 229.89,272.927 cw(c229.997,272.927) 229.997,273.034 229.997,274.117
CLK1_Out3.N: C690.2 R1084.1 U13.24 | length 10.2
  L1 w0.081: U13.24@195.123,273.481 195.471,273.481 cw(c195.471,273.439) 195.513,273.439 v2(196.317,273.439) ; v2(204.29,273.43) 204.94,273.43 cw(c204.94,273.098) C690.2@205.175,273.333
  L3 (Sign) w0.08: v2(196.317,273.439) cw(c196.419,273.439) 196.419,273.541 204.022,273.541 cw(c204.022,273.163) v2(204.29,273.43)
CLK1_Out3.P: C690.1 R1083.1 U13.25 | length 10.2
  L1 w0.081: U13.25@195.123,273.981 195.471,273.981 ccw(c195.471,274.024) 195.513,274.024 v2(196.317,274.024) ; v2(204.29,274.016) 204.94,274.016 ccw(c204.94,274.348) C690.1@205.175,274.113
  L3 (Sign) w0.08: v2(196.317,274.024) ccw(c196.419,274.024) 196.419,273.921 204.061,273.921 ccw(c204.061,274.244) v2(204.29,274.016)
CLK1_Out4.N: C806.1 R1098.1 U1.D9 | length 23.9
  L1 w0.081: v13(162.599,283.178) 162.599,282.842 ccw(c163.627,282.842) 163.627,281.814 166.504,281.814 cw(c166.601,281.814) 166.601,281.911 C806.1@166.814,281.911 167.125,281.911 167.125,281.898 ccw(c167.215,281.898) 167.215,281.808 167.384,281.808 cw(c167.554,281.808) 167.554,281.978 R1098.1@167.774,281.978
  L12 (Sign) w0.073: v13(162.599,283.178) cw(c162.599,283.371) 162.406,283.371 162.406,285.078 ccw(c160.865,285.078) 161.955,286.168 cw(c162.394,286.607) 161.773,286.607 161.773,287.539 161.773,293.624 cw(c162.067,293.624) 162.067,293.918 164.567,293.918 ccw(c164.567,294.347) 164.995,294.347 164.995,296.72 cw(c165.214,296.72) 165.214,296.939 cw(c165.214,296.756) 165.397,296.756 v3(165.397,296.539)
CLK1_Out4.P: C806.2 R1097.1 U1.D10 | length 25.1
  L1 w0.081: v13(162.014,283.178) 162.014,282.842 ccw(c163.627,282.842) 163.627,281.228 166.504,281.228 ccw(c166.601,281.228) 166.601,281.131 C806.2@166.814,281.131 167.033,281.131 ccw(c167.033,281.223) 167.125,281.223 167.384,281.223 ccw(c167.554,281.223) 167.554,281.053 R1097.1@167.774,281.053
  L12 (Sign) w0.073: v13(162.014,283.178) ccw(c162.014,283.371) 162.206,283.371 162.206,285.074 ccw(c160.855,285.074) 161.811,286.029 ; v3(165.397,297.539) 165.397,297.321 cw(c165.214,297.321) 165.214,297.139 ccw(c165.214,296.72) 164.795,296.72 164.795,294.347 cw(c164.567,294.347) 164.567,294.118 162.067,294.118 ccw(c162.067,293.624) 161.573,293.624 161.573,287.539 161.573,286.607 ccw(c162.394,286.607) 161.811,286.029 ; 161.811,286.029 ccw(c162.394,286.607) 161.813,286.026 161.811,286.029
CLK1_Out5.N: C808.1 R1101.1 U1.AH2 | length 0.7
  L1 w0.116: v2(188.909,289.052) U1.AH2@189.397,289.539
CLK1_Out5.P: C808.2 R1100.1 U1.AH3 | length 0.7
  L1 w0.116: v2(188.909,290.052) U1.AH3@189.397,290.539
CLK1_Out6.N: C812.1 R1104.1
CLK1_Out6.P: C812.2 R1103.1
CLK1_Out7.N: C814.1 R1106.1
CLK1_Out7.P: C814.2 R1105.1
CLK1_Out8.N: C816.1 R1108.1
CLK1_Out8.P: C816.2 R1107.1
CLK1_Out9.N: C818.1 R1110.1
CLK1_Out9.P: C818.2 R1109.1
CLK1_SPI.C\S\: R233_SPI_bridge_Main.1 U13.1 U25_SPI_bridge_Main.11 | length 2.1
  L1 w0.12: R233_SPI_bridge_Main.1@188.754,261.861 188.948,261.668 U25_SPI_bridge_Main.11@188.948,259.821
CLK1_SPI.CLK: U13.50 U25_SPI_bridge_Main.14
CLK1_SPI.MISO: U13.51 U25_SPI_bridge_Main.13
CLK1_SPI.MOSI: U13.52 U25_SPI_bridge_Main.12
CLK_M_OSC_In: C53.2 R257.2 R537.1 U33.2
CLK_SMA0_C_N: C48.2 J2.1
CLK_SMA0_C_P: C47.2 J3.1
CLKREF_R: R375.1 X6.3 | length 2.2
  L1 w0.12: R375.1@220.65,327.185 220.65,329.245 X6.3@220.777,329.372
CLKREQ: J27.52
CMD_SD: J28.3 U47.D4 | length 8
  L14 (Sign) w0.098: v35(129.927,337.233) 131.355,335.804 133.045,335.804 133.445,335.404 133.929,335.404 v22(134.329,335.004)
  L16 w0.098: J28.3@127.237,337.232 v35(129.927,337.233)
COMP1_1: C642.2 R624.2 U37.30 | length 2.7
  L1 w0.254: R624.2@63.175,183.31 63.195,183.29 64.155,183.29 C642.2@64.175,183.27 64.175,182.936 64.675,182.436 U37.30@64.675,181.817
COMP1_2: C548.2 R687.2 U38.30 | length 2.5
  L1 w0.254: R687.2@61.953,210.269 61.963,210.259 62.943,210.259 C548.2@62.953,210.249 U38.30@62.953,208.714
COMP2_1: C641.2 R623.2 U37.11 | length 2.6
  L1 w0.254: R623.2@63.12,175.907 63.14,175.927 64.155,175.927 C641.2@64.175,175.947 64.175,176.323 64.675,176.823 U37.11@64.675,177.317
COMP2_2: C650.2 R631.2 U38.11 | length 2.4
  L1 w0.254: R631.2@61.938,202.723 62.788,202.723 C650.2@62.828,202.764 62.828,203.439 62.953,203.564 U38.11@62.953,204.214
CSN: C694.2 C695.2 C696.2 C697.2 C698.2 C699.2 C700.2 R17.2 R140.2 R150.2 R666.2 U4.2 U65.10 | length 20.6
  L1 w0.254: U65.10@40.6,205.318 43.104,205.318 ; R150.2@43.102,206.468 43.102,205.319 43.104,205.318 ; R666.2@45.266,206.456 45.266,206.112 44.472,205.318 43.104,205.318
  L1 w0.5: R666.2@44.621,206.456 v1(44.621,207.543) ; R666.2@45.266,206.456 v1(45.266,207.543) ; R666.2@45.904,206.456 v1(45.904,207.543) ; v1(49.507,200.659) C699.2@50.594,200.659 ; v1(49.507,201.383) C699.2@50.593,201.383 ; v1(49.507,202.549) C696.2@50.594,202.549 ; v1(49.507,203.273) C696.2@50.593,203.273 ; v1(49.507,204.44) C697.2@50.594,204.44 ; v1(49.507,205.164) C697.2@50.594,205.164 ; v1(49.507,206.33) C695.2@50.594,206.33 ; v1(49.507,207.054) C695.2@50.593,207.054 ; v1(49.507,208.221) C698.2@50.594,208.221 ; v1(49.507,208.944) C698.2@50.594,208.944
  other v6: 46.939,186.483 48.188,186.483 47.599,187.248 46.94,187.985
  other v17: 48.36,184.721
CSP: L22.2 R666.1 U65.9 | length 8.6
  L1 w0.254: U65.9@40.6,204.818 44.43,204.818 45.266,203.981 R666.1@45.266,203.657
  L1 w0.5: v1(44.629,202.57) R666.1@44.629,203.657 ; v1(45.266,202.57) R666.1@45.266,203.657 ; v1(45.912,202.57) R666.1@45.912,203.657
  other v6: 42.02,228.866 43.644,229.333 37.109,230.581 39.58,230.581 44.463,230.811 45.281,232.29 39.025,232.804 43.802,233.108 41.58,234.493
CSU: P1.2 R649.1 R783.1 | length 5.2
  L1 w0.5: P1.2@206.108,154.407 205.867,154.649 R783.1@205.867,158.199 205.904,158.237 R649.1@207.162,158.237
CSU_Neg: P1.3 R109.2 | length 3.9
  L1 w0.5: R109.2@208.509,158.224 208.648,158.084 P1.3@208.648,154.407
CSU_Pos: P1.1 R106.2 | length 4
  L1 w0.5: P1.1@203.568,154.407 204.114,154.954 R106.2@204.114,158.148
D_05028_G0: R540.1 R904.2 U16.45 | length 53
  L1 w0.2: v2(127.851,270.142) 127.889,270.18 R904.2@127.889,273.4 ; v2(152.641,233.896) 152.641,234.04 152.915,234.314 ; U16.45@152.915,232.345 152.915,234.314 ; R540.1@152.915,235.05 152.915,234.314
  L3 (Sign) w0.2: v2(127.851,270.142) 127.851,264.909 128.004,264.756 152.641,240.119 v2(152.641,233.896)
D_05028_G3: U16.40 U35_I2C_Expander_00.20
D_05028_G4: U16.41 U35_I2C_Expander_00.21
D_05028_G5: U16.12 U35_I2C_Expander_00.22
D_05028_G6: U16.13 U35_I2C_Expander_00.23
D_05028_S0: U16.55 U35_I2C_Expander_00.18
D_05028_S1: U16.56 U35_I2C_Expander_00.17
DAC1220_Vref: C320.2 R608.1 R609.2 U30.12 | length 9.3
  L1 w0.2: v2(60.719,496.989) 60.719,496.363 R608.1@60.791,496.291 60.791,494.707 61.027,494.471 U30.12@61.027,492.711 ; C320.2@64.453,495.436 v2(64.453,496.252)
  L3 (Sign) w0.2: v2(60.719,496.989) 61.455,496.252 v2(64.453,496.252)
DAC_OUT: C321.2 U30.11 X2.2 | length 2.9
  L1 w0.2: U30.11@61.662,492.711 61.662,494.226 61.935,494.5 C321.2@61.935,495.465
DAC_SPI_CLK: U27_SPI_bridge_Main.14 U30.16 | length 12.2
  L1 w0.2: U27_SPI_bridge_Main.14@49.934,492.853 v2(49.934,494.6) ; U30.16@58.487,492.711 58.487,494.592 v2(58.496,494.601)
  L3 (Sign) w0.2: v2(49.934,494.6) v2@58.496,494.6
DAC_SPI_MOSI: R481.1 U27_SPI_bridge_Main.12 U30.15 | length 13.3
  L1 w0.2: U27_SPI_bridge_Main.12@51.234,492.853 51.257,492.876 v2(51.257,494.182) ; v2(52.514,494.182) 52.514,495.198 53.257,495.94 R481.1@53.257,496.519 ; U30.15@59.122,492.711 v2(59.122,494.182)
  L3 (Sign) w0.2: v2@51.244,494.182 v2(51.257,494.182) v2(52.514,494.182) v2(59.122,494.182)
DAS/DSS#: J27.10
DATA0_SD: J28.7 U47.D5 | length 7.6
  L16 w0.098: J28.7@127.237,332.832 127.468,333.064 130.429,333.064 131.61,334.244 132.563,334.244 133.324,335.004 U47.D5@133.927,335.004
DATA1_SD: J28.8 U47.E5 | length 7.9
  L16 w0.098: J28.8@127.237,331.732 128.871,331.732 129.876,332.737 130.384,332.737 131.692,334.046 132.797,334.046 133.356,334.604 U47.E5@133.927,334.604
DATA2_SD: J28.1 U47.A5 | length 8.6
  L16 w0.098: J28.1@127.237,339.432 131.629,339.432 132.374,338.687 132.374,337.757 U47.A5@133.927,336.204
DATA3_SD: J28.2 R383.1 U47.B5 | length 7.7
  L16 w0.098: J28.2@127.452,338.336 130.729,338.336 130.975,338.09 130.975,337.798 131.844,336.928 132.556,336.928 133.68,335.804 U47.B5@133.927,335.804
DDR4_A0: R31.1 U1.AH30 U8.P3 U9.P3 U10.P3 U11.P3 | length 101.4
  L1 w0.116: v3(170.472,338.864) U9.P3@170.876,338.46 ; v3(181.933,338.864) U11.P3@182.336,338.46 ; U1.AH30@189.397,317.539 v2(189.884,318.027) ; v3(193.393,338.864) U10.P3@193.797,338.46 ; v20(204.853,338.864) U8.P3@205.257,338.46
  L1 w0.155: v2(174.855,343.555) R31.1@174.855,344.8
  L5 (Sign) w0.092: v3(170.472,338.864) 171.003,338.864 171.42,339.28 173.296,339.28 174.076,340.06 174.498,340.06 174.632,340.06 cw(c174.632,339.971) 174.722,339.971 174.722,339.917 ccw(c174.811,339.917) 174.811,339.828 175.08,339.828 ccw(c175.08,339.917) 175.17,339.917 175.17,339.971 cw(c175.259,339.971) 175.259,340.06 176.111,340.06 180.091,340.06 181.287,338.864 v3(181.933,338.864) 182.528,338.864 182.944,339.28 183.962,339.28 184.742,340.06 185.649,340.06 185.752,340.06 ccw(c185.752,340.13) 185.822,340.13 185.822,340.205 cw(c185.891,340.205) 185.891,340.274 186.099,340.274 cw(c186.099,340.205) 186.168,340.205 186.168,340.06 186.168,339.916 ccw(c186.237,339.916) 186.237,339.847 186.445,339.847 ccw(c186.445,339.916) 186.514,339.916 186.514,339.991 cw(c186.583,339.991) 186.583,340.06 186.944,340.06 191.829,340.06 193.025,338.864 v3(193.393,338.864) 193.902,338.864 194.281,339.242 195.294,339.242 196.17,340.119 196.647,340.119 cw(c196.647,340.029) 196.736,340.029 196.736,339.923 ccw(c196.826,339.923) 196.826,339.833 197.094,339.833 ccw(c197.094,339.923) 197.184,339.923 197.184,340.119 197.184,340.314 cw(c197.273,340.314) 197.273,340.404 197.542,340.404 cw(c197.542,340.314) 197.632,340.314 197.632,340.119 197.632,339.923 ccw(c197.721,339.923) 197.721,339.833 197.99,339.833 ccw(c197.99,339.923) 198.08,339.923 198.08,340.119 198.08,340.314 cw(c198.169,340.314) 198.169,340.404 198.438,340.404 cw(c198.438,340.314) 198.527,340.314 198.527,340.119 198.527,339.923 ccw(c198.617,339.923) 198.617,339.833 198.886,339.833 ccw(c198.886,339.923) 198.975,339.923 198.975,340.119 198.975,340.314 cw(c199.065,340.314) 199.065,340.404 199.333,340.404 cw(c199.333,340.314) 199.423,340.314 199.423,340.119 199.423,339.923 ccw(c199.512,339.923) 199.512,339.833 199.781,339.833 ccw(c199.781,339.923) 199.871,339.923 199.871,340.119 199.871,340.314 cw(c199.96,340.314) 199.96,340.404 200.229,340.404 cw(c200.229,340.314) 200.319,340.314 200.319,340.119 200.319,340.034 ccw(c200.408,340.034) 200.408,339.945 200.677,339.945 ccw(c200.677,340.034) 200.766,340.034 cw(c200.851,340.034) 200.851,340.119 200.99,340.119 203.022,340.119 204.102,339.039 204.678,339.039 v20(204.853,338.864)
  L3 (Sign) w0.092: v3(170.472,338.864) 171.003,338.864 171.739,339.6 171.739,340.77 171.922,340.953 172.538,340.953 172.671,341.085 ; v2(189.884,318.027) 190.395,318.027 190.64,317.782 190.64,317.763 190.692,317.71 ; 190.692,317.709 190.74,317.661 190.74,317.349 190.517,317.125 190.303,317.125 190.081,317.348 189.55,317.348 189.36,317.158 189.36,316.828 189.738,316.449 189.738,315.504 189.479,315.245 189.479,314.952 189.674,314.757 189.7,314.757 189.751,314.706 190.024,314.706 190.452,315.134 190.452,315.263 190.728,315.539 190.896,315.539 191.437,316.081 193.641,316.081 203.086,325.526 203.086,328.902 203.086,329.13 ccw(c202.999,329.13) 202.999,329.217 202.511,329.217 cw(c202.511,329.303) 202.424,329.303 202.424,329.476 cw(c202.511,329.476) 202.511,329.563 203.086,329.563 203.093,329.563 ccw(c203.093,329.649) 203.179,329.649 203.179,329.822 ccw(c203.093,329.822) 203.093,329.909 203.086,329.909 202.981,329.909 cw(c202.981,329.996) 202.894,329.996 202.894,330.169 cw(c202.981,330.169) 202.981,330.255 203.086,330.255 203.093,330.255 ccw(c203.093,330.342) 203.179,330.342 203.179,330.515 ccw(c203.093,330.515) 203.093,330.601 203.086,330.601 202.994,330.601 cw(c202.994,330.688) 202.907,330.688 202.907,330.861 cw(c202.994,330.861) 202.994,330.948 203.086,330.948 203.093,330.948 ccw(c203.093,331.034) 203.179,331.034 203.179,331.207 ccw(c203.093,331.207) 203.093,331.294 203.086,331.294 202.511,331.294 cw(c202.511,331.38) 202.424,331.38 202.424,331.553 cw(c202.511,331.553) 202.511,331.64 203.086,331.64 203.093,331.64 ccw(c203.093,331.727) 203.179,331.727 203.179,331.9 ccw(c203.093,331.9) 203.093,331.986 203.086,331.986 202.511,331.986 cw(c202.511,332.073) 202.424,332.073 202.424,332.246 cw(c202.511,332.246) 202.511,332.332 202.999,332.332 ccw(c202.999,332.419) 203.086,332.419 203.086,332.506 203.128,332.548 203.128,332.856 203.122,332.862 203.122,333.257 203.122,333.337 ccw(c203.023,333.337) 203.023,333.436 202.839,333.436 cw(c202.839,333.536) 202.74,333.536 202.74,333.734 cw(c202.839,333.734) 202.839,333.833 203.122,333.833 203.143,333.833 ccw(c203.143,333.933) 203.242,333.933 203.242,334.131 ccw(c203.143,334.131) 203.143,334.23 203.122,334.23 202.844,334.23 cw(c202.844,334.33) 202.744,334.33 202.744,334.528 cw(c202.844,334.528) 202.844,334.627 203.122,334.627 203.143,334.627 ccw(c203.143,334.727) 203.242,334.727 203.242,334.925 ccw(c203.143,334.925) 203.143,335.024 203.122,335.024 202.844,335.024 cw(c202.844,335.124) 202.745,335.124 202.745,335.322 cw(c202.844,335.322) 202.844,335.421 203.122,335.421 203.143,335.421 ccw(c203.143,335.521) 203.242,335.521 203.242,335.719 ccw(c203.143,335.719) 203.143,335.818 cw(c203.143,335.839) 203.122,335.839 203.122,336.017 203.456,336.351 203.456,339.499 203.949,339.992 204.174,339.992 204.432,339.734 204.432,339.407 204.559,339.28 204.768,339.28 204.853,339.195 v20(204.853,338.864)
  L3 (Sign) w0.151: 172.671,341.085 174.855,343.27 v2(174.855,343.555)
DDR4_A1: R33.1 U1.AG30 U8.P4 U9.P4 U10.P4 U11.P4 | length 100.3
  L1 w0.116: U9.P4@167.676,338.46 168.072,338.857 v3(168.075,338.857) ; U11.P4@179.136,338.46 179.533,338.857 v3(179.535,338.857) ; U1.AG30@188.397,317.539 v2(188.884,318.027) ; U10.P4@190.597,338.46 190.993,338.857 v3(190.995,338.857) v3@190.954,338.815 ; v20(201.646,338.856) U8.P4@202.049,338.453
  L1 w0.155: R33.1@158.737,340.144 v1(159.982,340.144)
  L12 (Sign) w0.092: 165.251,338.46 166.723,338.46 167.356,338.46 167.711,338.815 168.033,338.815 v3(168.075,338.857) ; v3@168.072,338.857 v3(168.075,338.857) ; v3@179.533,338.857 v3(179.535,338.857) ; v20(201.646,338.856) 201.379,338.856 201.058,338.536 196.832,338.536 196.108,339.26 194.843,339.26 194.709,339.26 ccw(c194.709,339.171) 194.62,339.171 194.62,338.947 cw(c194.53,338.947) 194.53,338.858 194.261,338.858 cw(c194.261,338.947) 194.172,338.947 194.172,339.26 194.172,339.573 ccw(c194.082,339.573) 194.082,339.663 193.813,339.663 ccw(c193.813,339.573) 193.724,339.573 193.724,339.26 193.724,339.241 cw(c193.634,339.241) 193.634,339.152 193.366,339.152 cw(c193.366,339.241) 193.276,339.241 193.276,339.26 193.276,339.349 ccw(c193.187,339.349) 193.187,339.439 192.918,339.439 ccw(c192.918,339.349) 192.828,339.349 192.828,339.26 192.828,338.947 cw(c192.739,338.947) 192.739,338.858 192.47,338.858 cw(c192.47,338.947) 192.381,338.947 192.381,339.171 ccw(c192.291,339.171) 192.291,339.26 191.795,339.26 191.636,339.26 191.232,338.857 v3(190.995,338.857) 190.954,338.815 190.632,338.815 190.335,338.518 189.586,338.518 189.24,338.864 187.088,338.864 186.984,338.864 ccw(c186.984,338.795) 186.914,338.795 186.914,338.77 cw(c186.845,338.77) 186.845,338.701 186.637,338.701 cw(c186.637,338.77) 186.568,338.77 186.568,338.864 186.568,338.97 ccw(c186.499,338.97) 186.499,339.04 186.291,339.04 ccw(c186.291,338.97) 186.222,338.97 186.222,338.864 186.222,338.77 cw(c186.153,338.77) 186.153,338.701 185.945,338.701 cw(c185.945,338.77) 185.876,338.77 185.876,338.864 185.876,338.97 ccw(c185.807,338.97) 185.807,339.04 185.599,339.04 ccw(c185.599,338.97) 185.53,338.97 185.53,338.933 cw(c185.46,338.933) 185.46,338.864 185.204,338.864 184.935,338.864 184.633,339.166 183.804,339.166 183.715,339.255 180.886,339.255 180.488,338.857 v3(179.535,338.857) ; v3(168.075,338.857) 168.651,338.857 169.055,339.26 169.189,339.26 ccw(c169.189,339.35) 169.279,339.35 169.279,339.404 cw(c169.368,339.404) 169.368,339.493 169.637,339.493 cw(c169.637,339.404) 169.727,339.404 169.727,339.26 169.727,339.117 ccw(c169.816,339.117) 169.816,339.027 170.085,339.027 ccw(c170.085,339.117) 170.175,339.117 170.175,339.171 cw(c170.264,339.171) 170.264,339.26 170.472,339.26 173.402,339.26 174.126,338.536 179.214,338.536 v3(179.535,338.857)
  L12 (Sign) w0.151: v1(159.982,340.144) 161.387,340.144 163.071,338.46 165.251,338.46
  L3 (Sign) w0.092: v2(188.884,318.027) 189.551,318.694 189.968,318.694 195.968,324.694 195.968,324.965 195.968,325.064 ccw(c195.869,325.064) 195.869,325.164 195.517,325.164 cw(c195.517,325.263) 195.418,325.263 195.418,325.461 cw(c195.517,325.461) 195.517,325.561 195.968,325.561 196.862,325.561 ccw(c196.862,325.66) 196.961,325.66 196.961,325.858 ccw(c196.862,325.858) 196.862,325.958 195.968,325.958 195.517,325.958 cw(c195.517,326.057) 195.418,326.057 195.418,326.255 cw(c195.517,326.255) 195.517,326.355 195.968,326.355 196.874,326.355 ccw(c196.874,326.454) 196.974,326.454 196.974,326.652 ccw(c196.874,326.652) 196.874,326.752 195.968,326.752 195.517,326.752 cw(c195.517,326.851) 195.418,326.851 195.418,327.049 cw(c195.517,327.049) 195.517,327.149 195.968,327.149 196.874,327.149 ccw(c196.874,327.248) 196.974,327.248 196.974,327.446 ccw(c196.874,327.446) 196.874,327.546 195.968,327.546 195.517,327.546 cw(c195.517,327.645) 195.418,327.645 195.418,327.843 cw(c195.517,327.843) 195.517,327.943 195.968,327.943 196.874,327.943 ccw(c196.874,328.042) 196.974,328.042 196.974,328.24 ccw(c196.874,328.24) 196.874,328.34 195.968,328.34 195.517,328.34 cw(c195.517,328.439) 195.418,328.439 195.418,328.637 cw(c195.517,328.637) 195.517,328.737 195.968,328.737 196.874,328.737 ccw(c196.874,328.836) 196.974,328.836 196.974,329.034 ccw(c196.874,329.034) 196.874,329.134 195.968,329.134 195.517,329.134 cw(c195.517,329.233) 195.418,329.233 195.418,329.431 cw(c195.517,329.431) 195.517,329.531 195.968,329.531 196.874,329.531 ccw(c196.874,329.63) 196.974,329.63 196.974,329.828 ccw(c196.874,329.828) 196.874,329.928 195.968,329.928 195.517,329.928 cw(c195.517,330.027) 195.418,330.027 195.418,330.225 cw(c195.517,330.225) 195.517,330.325 195.968,330.325 196.874,330.325 ccw(c196.874,330.424) 196.974,330.424 196.974,330.622 ccw(c196.874,330.622) 196.874,330.722 195.968,330.722 195.933,330.722 cw(c195.933,330.821) 195.833,330.821 195.833,331.019 cw(c195.933,331.019) 195.933,331.119 195.918,331.119 ccw(c195.918,331.169) 195.968,331.169 195.968,331.241 195.968,331.549 196.63,332.21 196.63,334.457 200.602,338.43 200.947,338.43 201.088,338.571 201.093,338.571 201.379,338.856 v20(201.646,338.856)
DDR4_A2: R35.1 U1.AK29 U8.R3 U9.R3 U10.R3 U11.R3 | length 99
  L1 w0.116: v3(170.472,339.664) U9.R3@170.876,339.26 ; v3(181.933,339.664) U11.R3@182.336,339.26 ; v2(190.909,316.052) U1.AK29@191.397,316.539 ; v3(193.393,339.664) U10.R3@193.797,339.26 ; v20(204.853,339.664) U8.R3@205.257,339.26
  L1 w0.155: v2(173.646,343.555) R35.1@173.646,344.8
  L5 (Sign) w0.092: v3(170.472,339.664) 170.901,339.664 171.305,340.068 172.536,340.068 173.449,340.981 180.235,340.981 180.335,340.881 cw(c180.276,340.822) 180.335,340.764 ccw(c180.398,340.701) 180.335,340.637 180.525,340.447 ccw(c180.588,340.511) 180.651,340.447 cw(c180.71,340.389) 180.768,340.447 181.326,339.89 181.552,339.664 v3(181.933,339.664) 182.433,339.664 182.837,340.068 183.672,340.068 184.891,341.287 186.792,341.287 186.987,341.287 cw(c186.987,341.218) 187.056,341.218 187.056,341.216 ccw(c187.125,341.216) 187.125,341.147 187.333,341.147 ccw(c187.333,341.216) 187.402,341.216 187.402,341.218 cw(c187.471,341.218) 187.471,341.287 187.748,341.287 187.922,341.287 188.299,341.287 cw(c188.299,341.218) 188.368,341.218 188.368,341.216 ccw(c188.437,341.216) 188.437,341.147 188.645,341.147 ccw(c188.645,341.216) 188.714,341.216 188.714,341.218 cw(c188.783,341.218) 188.783,341.287 188.887,341.287 191.389,341.287 193.012,339.664 v3(193.393,339.664) 193.822,339.664 194.226,340.068 195.277,340.068 195.516,340.307 195.516,340.906 196.164,341.554 196.913,341.554 197.164,341.554 ccw(c197.164,341.643) 197.254,341.643 197.254,341.758 cw(c197.344,341.758) 197.344,341.848 197.612,341.848 cw(c197.612,341.758) 197.702,341.758 197.702,341.554 197.702,341.349 ccw(c197.791,341.349) 197.791,341.26 198.06,341.26 ccw(c198.06,341.349) 198.15,341.349 198.15,341.554 198.15,341.658 cw(c198.239,341.658) 198.239,341.748 198.508,341.748 cw(c198.508,341.658) 198.597,341.658 198.597,341.554 198.597,341.349 ccw(c198.687,341.349) 198.687,341.26 198.956,341.26 ccw(c198.956,341.349) 199.045,341.349 199.045,341.554 199.045,341.658 cw(c199.135,341.658) 199.135,341.748 199.403,341.748 cw(c199.403,341.658) 199.493,341.658 199.493,341.554 199.493,341.349 ccw(c199.583,341.349) 199.583,341.26 199.851,341.26 ccw(c199.851,341.349) 199.941,341.349 199.941,341.464 cw(c200.03,341.464) 200.03,341.554 200.165,341.554 204.127,341.554 204.23,341.451 204.23,340.289 204.853,339.666 v20(204.853,339.664)
  L3 (Sign) w0.092: v3(170.472,339.664) 170.901,339.664 171.317,340.079 171.317,340.881 171.456,341.02 171.471,341.02 171.536,341.085 ; v2(190.909,316.052) 191.179,316.322 193.462,316.322 193.533,316.392 ccw(c193.462,316.462) 193.533,316.532 193.212,316.853 cw(c193.282,316.924) 193.212,316.994 193.352,317.134 cw(c193.422,317.064) 193.492,317.134 193.884,316.743 ccw(c193.954,316.813) 194.024,316.743 194.164,316.883 ccw(c194.094,316.953) 194.164,317.024 193.773,317.415 cw(c193.843,317.485) 193.773,317.555 193.913,317.696 cw(c193.984,317.625) 194.054,317.696 194.445,317.304 ccw(c194.515,317.374) 194.585,317.304 194.726,317.445 ccw(c194.656,317.515) 194.726,317.585 194.416,317.895 cw(c194.486,317.965) 194.416,318.035 194.556,318.175 cw(c194.627,318.105) 194.697,318.175 195.006,317.866 ccw(c195.077,317.936) 195.147,317.866 195.287,318.006 ccw(c195.217,318.076) 195.287,318.146 195.021,318.412 cw(c195.092,318.482) 195.021,318.553 195.162,318.693 cw(c195.232,318.623) 195.302,318.693 195.568,318.427 ccw(c195.638,318.497) 195.708,318.427 195.849,318.568 ccw(c195.778,318.638) 195.849,318.708 195.508,319.048 cw(c195.579,319.118) 195.508,319.188 195.649,319.329 cw(c195.719,319.259) 195.789,319.329 196.129,318.989 ccw(c196.199,319.059) 196.27,318.989 196.41,319.129 ccw(c196.34,319.199) 196.41,319.269 196.093,319.586 cw(c196.163,319.657) 196.093,319.727 196.233,319.867 cw(c196.304,319.797) 196.374,319.867 196.691,319.55 ccw(c196.761,319.62) 196.831,319.55 196.971,319.69 ccw(c196.901,319.761) 196.971,319.831 196.707,320.095 cw(c196.778,320.165) 196.707,320.235 196.848,320.376 cw(c196.918,320.305) 196.988,320.376 197.252,320.112 ccw(c197.322,320.182) 197.393,320.112 197.533,320.252 ccw(c197.463,320.322) 197.533,320.392 197.269,320.656 cw(c197.34,320.726) 197.269,320.796 197.41,320.936 cw(c197.48,320.866) 197.55,320.936 197.814,320.673 ccw(c197.884,320.743) 197.954,320.673 198.094,320.813 ccw(c198.024,320.884) 198.094,320.954 197.769,321.279 cw(c197.839,321.349) 197.769,321.419 197.909,321.56 cw(c197.98,321.489) 198.05,321.56 198.375,321.234 ccw(c198.445,321.305) 198.515,321.234 198.656,321.375 ccw(c198.586,321.445) 198.656,321.515 198.358,321.813 cw(c198.428,321.883) 198.358,321.953 198.499,322.093 cw(c198.569,322.023) 198.639,322.093 198.937,321.796 ccw(c199.007,321.866) 199.077,321.796 199.217,321.936 ccw(c199.147,322.006) 199.217,322.077 198.955,322.338 cw(c199.026,322.409) 198.955,322.479 199.096,322.619 cw(c199.166,322.549) 199.236,322.619 199.498,322.357 ccw(c199.568,322.427) 199.638,322.357 199.779,322.498 ccw(c199.708,322.568) 199.779,322.638 199.444,322.973 cw(c199.514,323.043) 199.444,323.113 199.584,323.253 cw(c199.654,323.183) 199.725,323.253 200.059,322.919 ccw(c200.13,322.989) 200.2,322.919 200.34,323.059 ccw(c200.27,323.129) 200.34,323.199 200.079,323.46 cw(c200.15,323.53) 200.079,323.6 200.22,323.741 cw(c200.29,323.671) 200.36,323.741 200.621,323.48 ccw(c200.691,323.55) 200.761,323.48 200.902,323.621 ccw(c200.831,323.691) 200.902,323.761 201.068,323.928 201.077,323.928 201.147,323.998 201.154,323.991 201.215,324.052 201.215,324.074 201.247,324.106 201.269,324.106 201.33,324.167 201.323,324.174 201.393,324.244 201.393,324.253 202.135,324.994 202.135,326.499 202.057,326.576 202.057,335.669 202.253,335.864 202.578,335.864 202.969,336.255 202.969,337.779 203.249,338.06 203.249,339.66 203.898,340.309 204.208,340.309 v20(204.853,339.664)
  L3 (Sign) w0.151: 171.536,341.085 173.63,343.18 173.63,343.539 v2(173.646,343.555)
DDR4_A3: R37.1 U1.AJ30 U8.N4 U9.N4 U10.N4 U11.N4 | length 99.3
  L1 w0.116: U9.N4@167.676,337.66 168.072,338.057 v3(168.075,338.057) ; U11.N4@179.136,337.66 179.533,338.057 v3(179.535,338.057) ; U1.AJ30@190.397,317.539 v2(190.884,318.027) ; U10.N4@190.597,337.66 190.993,338.057 v3(190.995,338.057) ; U8.N4@202.057,337.66 202.453,338.057 v3(202.456,338.057)
  L1 w0.155: R37.1@158.737,337.967 v1(159.982,337.967)
  L12 (Sign) w0.092: 165.251,337.661 166.76,337.661 167.508,337.661 167.896,338.049 v3(168.075,338.057) ; v3@168.075,338.049 168.821,338.049 169.171,337.698 173.927,337.698 175.389,337.698 cw(c175.389,337.609) 175.479,337.609 175.479,337.545 ccw(c175.568,337.545) 175.568,337.456 175.837,337.456 ccw(c175.837,337.545) 175.927,337.545 175.927,337.698 175.927,337.773 cw(c176.016,337.773) 176.016,337.863 176.285,337.863 cw(c176.285,337.773) 176.374,337.773 176.374,337.698 176.374,337.545 ccw(c176.464,337.545) 176.464,337.456 176.733,337.456 ccw(c176.733,337.545) 176.822,337.545 176.822,337.609 cw(c176.912,337.609) 176.912,337.698 177.046,337.698 177.931,337.698 177.934,337.695 178.053,337.695 178.053,337.698 178.201,337.698 178.201,337.695 178.32,337.695 178.323,337.698 178.831,337.698 179.189,338.057 v3@179.533,338.057 ; v3(179.535,338.057) 180.56,338.057 180.95,337.668 184.651,337.668 185.134,338.15 186.39,338.15 186.616,338.15 cw(c186.616,338.081) 186.685,338.081 186.685,337.958 ccw(c186.754,337.958) 186.754,337.889 186.962,337.889 ccw(c186.962,337.958) 187.031,337.958 187.031,338.15 187.031,338.183 cw(c187.1,338.183) 187.1,338.252 187.308,338.252 cw(c187.308,338.183) 187.377,338.183 187.377,338.15 187.377,337.958 ccw(c187.446,337.958) 187.446,337.889 187.654,337.889 ccw(c187.654,337.958) 187.723,337.958 187.723,338.081 cw(c187.793,338.081) 187.793,338.15 187.897,338.15 189.219,338.15 189.633,337.736 190.504,337.736 190.817,338.049 191.312,338.049 191.662,337.698 193.827,337.698 194.311,337.698 cw(c194.311,337.609) 194.4,337.609 ; 194.4,337.608 ccw(c194.49,337.608) 194.49,337.519 194.759,337.519 ccw(c194.759,337.608) 194.848,337.608 ; 194.848,337.609 cw(c194.938,337.609) 194.938,337.698 195.072,337.698 195.123,337.698 195.458,337.363 196.532,337.363 197.232,337.363 cw(c197.232,337.273) 197.321,337.273 197.321,337.214 ccw(c197.411,337.214) 197.411,337.125 197.68,337.125 ccw(c197.68,337.214) 197.769,337.214 197.769,337.273 cw(c197.859,337.273) 197.859,337.363 197.993,337.363 198.352,337.363 ccw(c198.352,337.452) 198.442,337.452 198.442,337.5 cw(c198.531,337.5) 198.531,337.59 198.8,337.59 cw(c198.8,337.5) 198.89,337.5 198.89,337.363 198.89,337.214 ccw(c198.979,337.214) 198.979,337.125 199.248,337.125 ccw(c199.248,337.214) 199.337,337.214 199.337,337.363 cw(c199.427,337.363) 199.427,337.452 199.696,337.452 cw(c199.696,337.363) 199.785,337.363 199.785,337.214 ccw(c199.875,337.214) 199.875,337.125 200.143,337.125 ccw(c200.143,337.214) 200.233,337.214 200.233,337.273 cw(c200.322,337.273) 200.322,337.363 200.457,337.363 201.112,337.363 201.447,337.698 202.097,337.698 v3(202.456,338.057)
  L12 (Sign) w0.151: v1(159.982,337.967) 160.623,337.967 160.928,337.661 165.251,337.661
  L3 (Sign) w0.092: v2(190.884,318.027) 190.884,317.789 191.329,317.344 191.726,317.344 191.867,317.484 192.147,317.765 192.428,318.046 192.709,318.327 192.919,318.537 ccw(c192.849,318.607) 192.919,318.677 192.123,319.474 cw(c192.193,319.544) 192.123,319.614 192.263,319.755 cw(c192.333,319.684) 192.403,319.755 193.2,318.958 ccw(c193.27,319.028) 193.34,318.958 193.481,319.099 ccw(c193.411,319.169) 193.481,319.239 192.684,320.035 cw(c192.754,320.106) 192.684,320.176 192.825,320.316 cw(c192.895,320.246) 192.965,320.316 193.761,319.52 ccw(c193.832,319.59) 193.902,319.52 194.042,319.66 ccw(c193.972,319.73) 194.042,319.8 193.246,320.597 cw(c193.316,320.667) 193.246,320.737 193.386,320.878 cw(c193.456,320.807) 193.526,320.878 194.323,320.081 ccw(c194.393,320.151) 194.463,320.081 194.604,320.221 ccw(c194.533,320.292) 194.604,320.362 193.807,321.158 cw(c193.877,321.228) 193.807,321.299 193.947,321.439 cw(c194.018,321.369) 194.088,321.439 194.884,320.642 ccw(c194.954,320.713) 195.025,320.642 195.165,320.783 ccw(c195.095,320.853) 195.165,320.923 194.368,321.72 cw(c194.439,321.79) 194.368,321.86 194.509,322 cw(c194.579,321.93) 194.649,322 195.446,321.204 ccw(c195.516,321.274) 195.586,321.204 195.726,321.344 ccw(c195.656,321.414) 195.726,321.485 194.93,322.281 cw(c195,322.351) 194.93,322.422 195.07,322.562 cw(c195.14,322.492) 195.211,322.562 196.007,321.765 ccw(c196.077,321.836) 196.148,321.765 196.288,321.906 ccw(c196.218,321.976) 196.288,322.046 195.491,322.843 cw(c195.562,322.913) 195.491,322.983 195.632,323.123 cw(c195.702,323.053) 195.772,323.123 196.569,322.327 ccw(c196.639,322.397) 196.709,322.327 196.92,322.537 197.2,322.818 197.574,323.192 197.574,329.171 197.574,330.229 cw(c197.673,330.229) 197.673,330.328 198.456,330.328 ccw(c198.456,330.427) 198.555,330.427 198.555,330.626 ccw(c198.456,330.626) 198.456,330.725 197.574,330.725 cw(c197.574,330.824) 197.475,330.824 197.475,331.023 cw(c197.574,331.023) 197.574,331.122 197.75,331.122 ccw(c197.75,331.221) 197.849,331.221 197.849,331.42 ccw(c197.75,331.42) 197.75,331.519 197.574,331.519 cw(c197.574,331.618) 197.475,331.618 197.475,331.817 cw(c197.574,331.817) 197.574,331.916 ccw(c197.574,332.015) 197.673,332.015 197.673,332.214 ccw(c197.574,332.214) 197.574,332.313 197.574,332.511 197.574,334.379 200.822,337.627 202.026,337.627 v3(202.456,338.057)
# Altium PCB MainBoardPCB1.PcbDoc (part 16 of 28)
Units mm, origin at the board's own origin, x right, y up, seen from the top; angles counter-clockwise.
Board outline 258.95 x 308.86 mm, 16 copper layers (L1, L2 (GND), L3 (Sign), L4 (GND), L5 (Sign), L6 (PWR/GND), L7(PWR/GND), L8 (Plane_GND), L9 (PWR/GND), L10 (PWR/GND), L11 (PWR/GND), L12 (Sign), L13 (GND), L14 (Sign), L15 (GND), L16), stack 2.502 mm thick; 2397 components, 1744 nets, 8397 pads, 4112 vias.
Unrouted connection lines stored in the file: 3547.

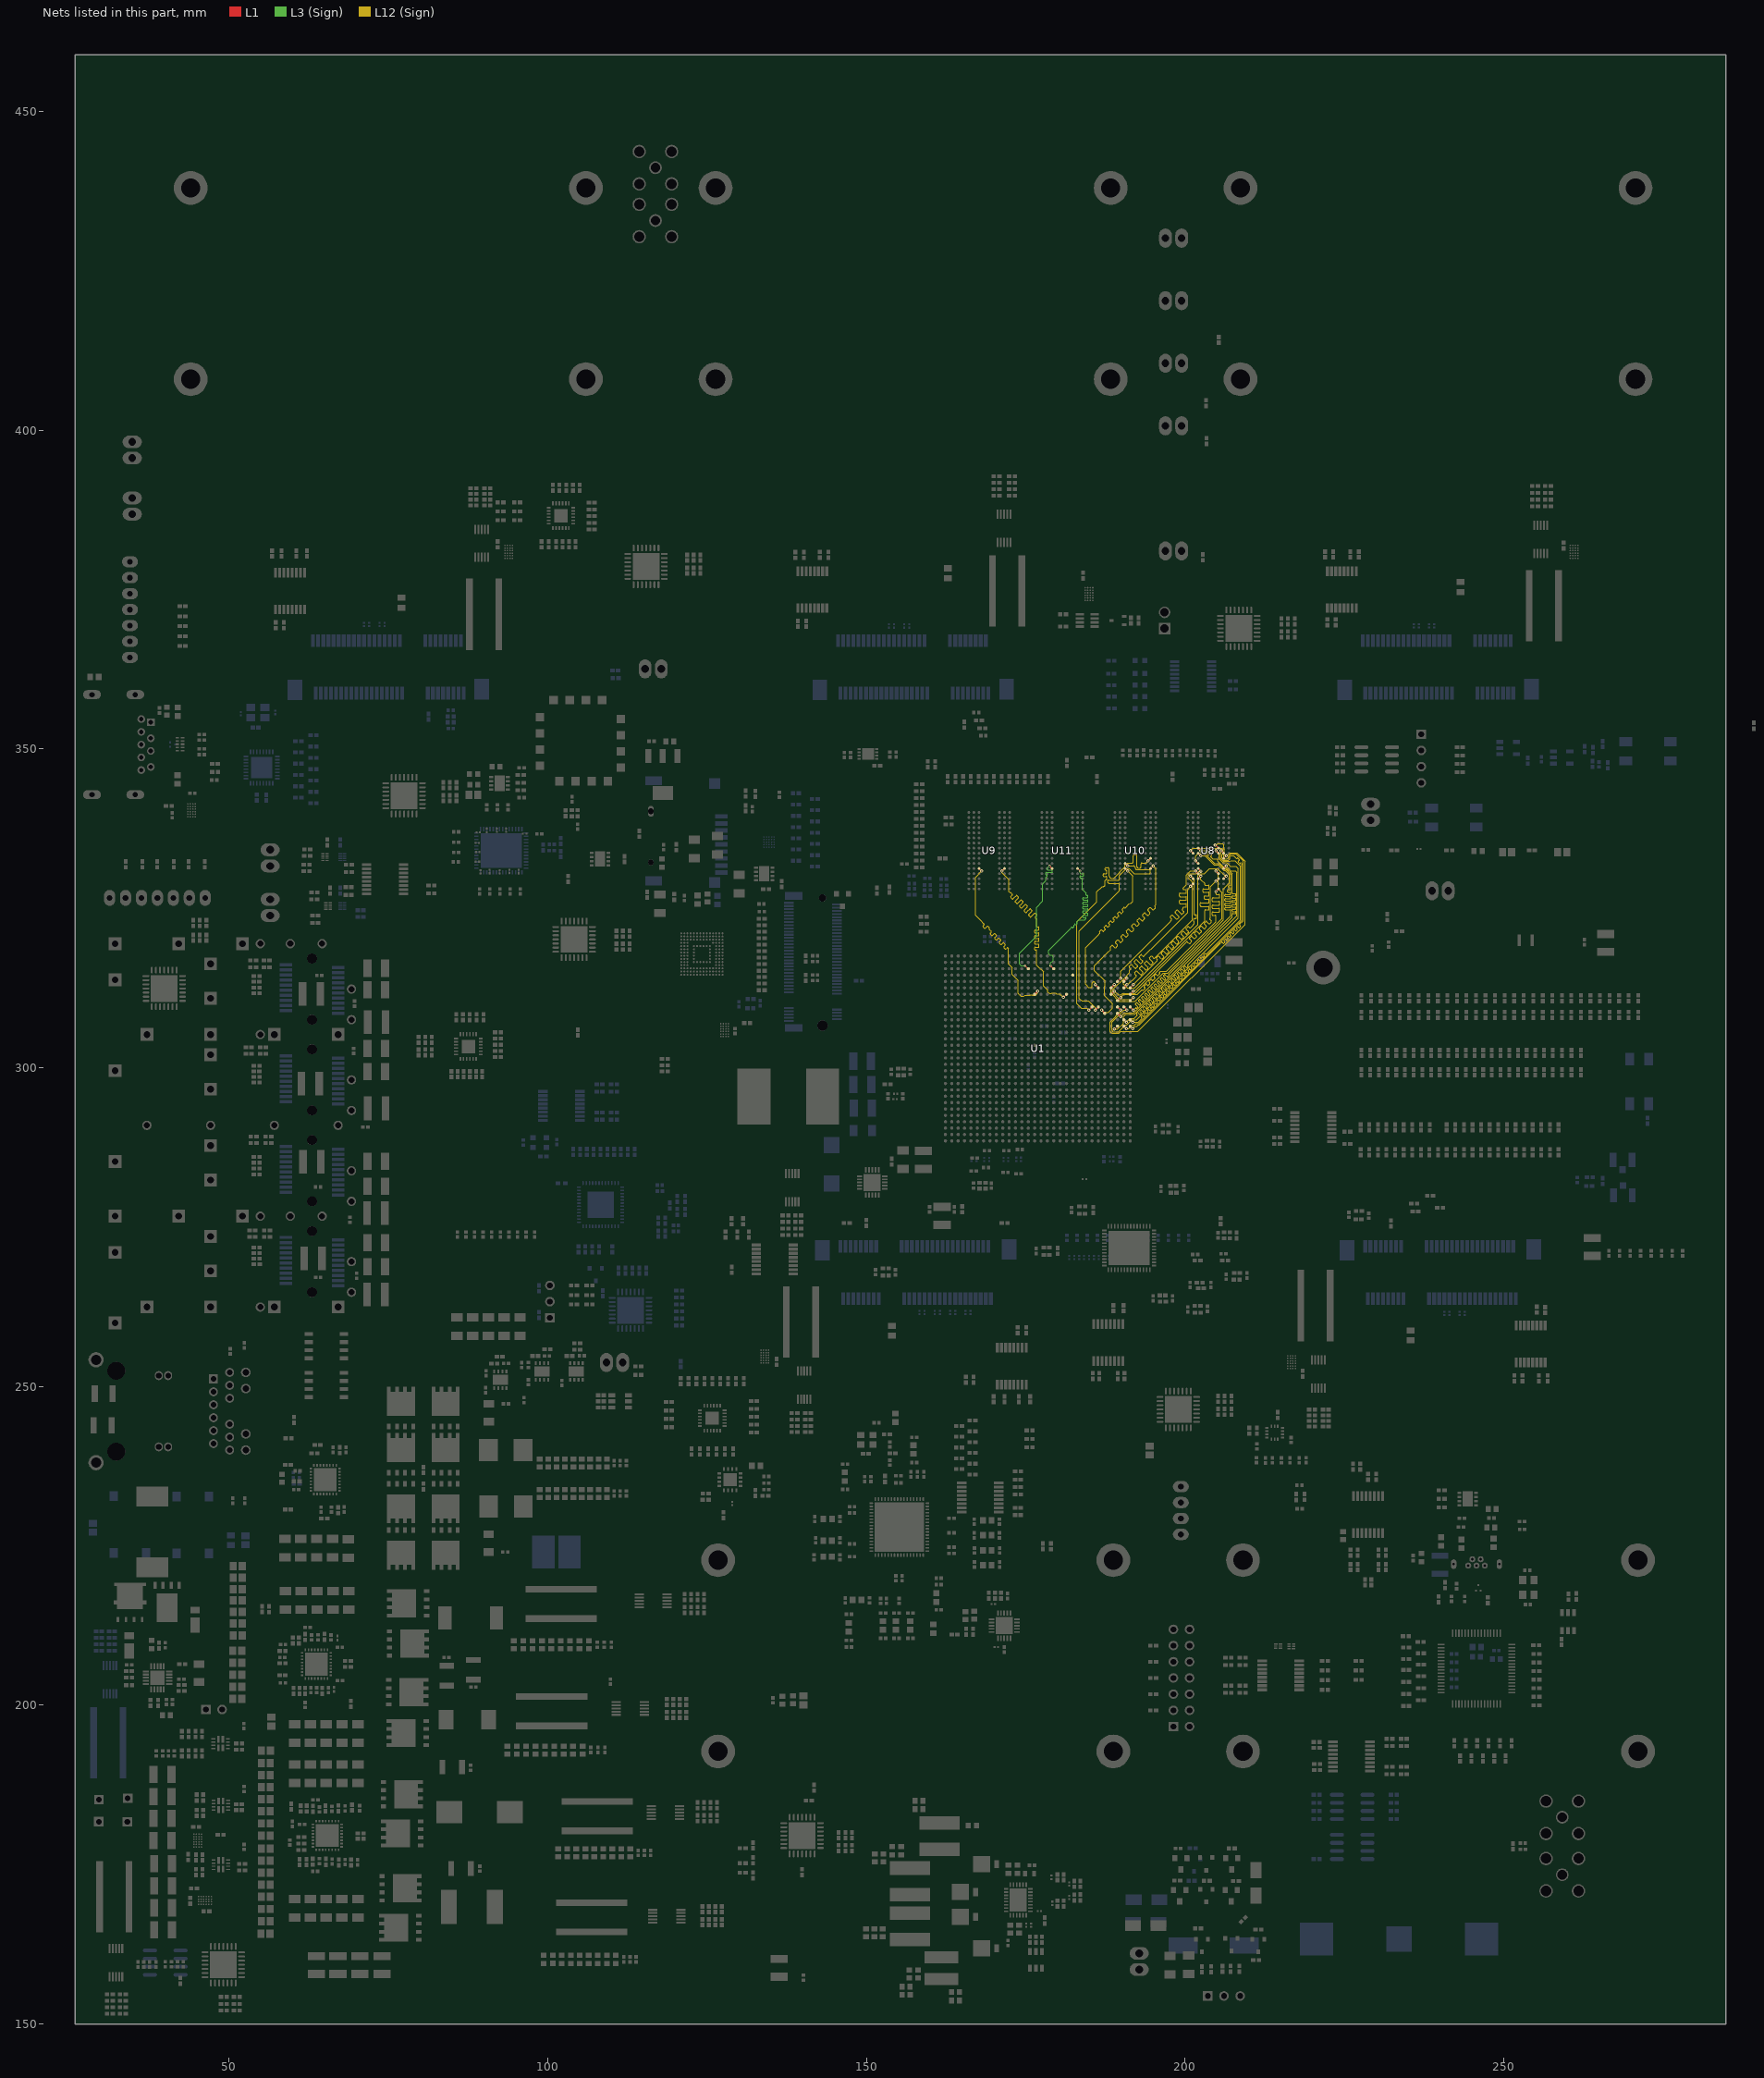
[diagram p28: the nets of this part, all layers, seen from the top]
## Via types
v1: diameter 0.5, hole 0.2, L1 to L16, tented both sides, 1457 vias
v2: diameter 0.35/0/0.35 (per signal layer), hole 0.127, L1 to L3 (Sign), tented both sides, 479 vias
v3: diameter 0.5/0.35/0.35/0.35/0.35/0.35/0.35/0.35/0.35/0.35/0.35/0.35/0.35/0.35/0.35/0.5 (per signal layer), hole 0.15, L1 to L16, tented both sides, 453 vias
v4: diameter 0.5, hole 0.2, L1 to L16, 451 vias
v5: diameter 0.5/0.35/0.35/0.35/0.35/0.35/0.35/0.35/0.35/0.35/0.35/0.35/0.35/0.35/0.35/0.5 (per signal layer), hole 0.2, L1 to L16, tented both sides, 373 vias
v6: diameter 0.8, hole 0.4, L1 to L16, tented both sides, 168 vias
v7: diameter 0.35/0/0.35 (per signal layer), hole 0.127, L1 to L3 (Sign), 138 vias
v8: diameter 2.54, hole 1.02, L1 to L16, 113 vias
v9: diameter 0.5/0/0.5 (per signal layer), hole 0.2, L14 (Sign) to L16, tented both sides, 102 vias
v10: diameter 1.4, hole 0.5, L1 to L16, tented both sides, 80 vias
v11: diameter 0.5, hole 0.2, L3 (Sign) to L6 (PWR/GND), tented both sides, 54 vias
v12: diameter 0.35, hole 0.127, L1 to L2 (GND), tented both sides, 47 vias
v13: diameter 0.4, hole 0.2, L1 to L16, tented both sides, 46 vias
v14: diameter 0.35, hole 0.127, L1 to L16, tented both sides, 16 vias
v15: diameter 0.25, hole 0.2, L1 to L16, 16 vias
v16: diameter 0.5, hole 0.2, L11 (PWR/GND) to L14 (Sign), tented both sides, 16 vias
v17: diameter 0.4, hole 0.2, L1 to L16, 16 vias
v18: diameter 0.3, hole 0.2, L1 to L16, 15 vias
v19: diameter 0.45, hole 0.15, L1 to L16, 12 vias
v20: diameter 0.5/0.35/0.35/0.35/0.35/0.35/0.35/0.35/0.35/0.35/0.35/0.35/0.35/0.35/0.35/0.45 (per signal layer), hole 0.15, L1 to L16, tented both sides, 10 vias
v21: diameter 0.2/0/0.2 (per signal layer), hole 0.1, L1 to L3 (Sign), tented both sides, 9 vias
v22: diameter 0.3, hole 0.127, L14 (Sign) to L16, tented both sides, 8 vias
v23: diameter 0.4, hole 0.1, L1 to L16, 7 vias
v24: diameter 1.15, hole 1.15, L1 to L16, 5 vias
v25: diameter 1.65, hole 1.65, L1 to L16, 5 vias
v26: diameter 0.2, hole 0.1, L1 to L16, 4 vias
v27: diameter 0.4, hole 0.15, L1 to L16, 2 vias
v28: diameter 0.5/0.35/0.35/0.35/0.35/0.35/0.35/0.35/0.35/0.35/0.35/0.35/0.35/0.35/0.35/0.5 (per signal layer), hole 0.15, L1 to L16, 2 vias
v29: diameter 0.35, hole 0.127, L3 (Sign) to L6 (PWR/GND), tented both sides, 2 vias
v30: diameter 0.3, hole 0.127, L15 (GND) to L16, tented both sides, 1 vias
v31: diameter 0.35, hole 0.127, L1 to L2 (GND), 1 vias
v32: diameter 0.5/0.35/0.35/0.35/0.35/0.35/0.35/0.35/0.35/0.35/0.35/0.35/0.35/0.35/0.35/0.5 (per signal layer), hole 0.2, L1 to L16, 1 vias
v33: diameter 0.35/0.35/0.35 (per signal layer), hole 0.127, L1 to L3 (Sign), tented both sides, 1 vias
v34: diameter 0.45/0/0.45 (per signal layer), hole 0.15, L1 to L3 (Sign), tented both sides, 1 vias
v35: diameter 0.45/0/0.45 (per signal layer), hole 0.2, L14 (Sign) to L16, tented both sides, 1 vias

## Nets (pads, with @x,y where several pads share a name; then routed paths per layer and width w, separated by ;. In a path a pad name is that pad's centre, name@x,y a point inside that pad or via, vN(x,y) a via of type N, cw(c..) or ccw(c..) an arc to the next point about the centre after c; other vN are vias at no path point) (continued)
DDR4_DM0: U1.AJ20 U8.E2 | length 46.3
  L1 w0.116: U1.AJ20@190.397,307.539 v3(190.8,307.136) ; U8.E2@206.057,331.26 v3(206.461,331.664)
  L12 (Sign) w0.092: v3(190.8,307.136) 191.396,307.731 191.751,307.731 192.017,307.731 192.401,308.115 192.462,308.176 ccw(c192.401,308.237) 192.462,308.298 192.426,308.334 cw(c192.487,308.396) 192.426,308.457 192.549,308.579 cw(c192.61,308.518) 192.671,308.579 192.768,308.482 192.866,308.384 ccw(c192.928,308.445) 192.989,308.384 193.111,308.506 ccw(c193.05,308.567) 193.111,308.629 193.013,308.727 192.916,308.824 cw(c192.977,308.885) 192.916,308.946 193.038,309.069 cw(c193.099,309.008) 193.161,309.069 193.258,308.971 193.356,308.873 ccw(c193.417,308.935) 193.478,308.873 193.601,308.996 ccw(c193.54,309.057) 193.601,309.118 193.503,309.216 193.405,309.314 cw(c193.467,309.375) 193.405,309.436 193.528,309.558 cw(c193.589,309.497) 193.65,309.558 193.747,309.461 193.846,309.363 ccw(c193.907,309.424) 193.968,309.363 194.09,309.485 ccw(c194.029,309.547) 194.09,309.608 193.992,309.706 193.895,309.803 cw(c193.956,309.864) 193.895,309.926 194.017,310.048 cw(c194.079,309.987) 194.14,310.048 194.237,309.951 194.335,309.853 ccw(c194.396,309.914) 194.458,309.853 194.58,309.975 ccw(c194.519,310.036) 194.58,310.097 194.482,310.195 194.385,310.293 cw(c194.446,310.354) 194.385,310.415 194.507,310.538 cw(c194.568,310.476) 194.629,310.538 194.727,310.44 194.825,310.342 ccw(c194.886,310.403) 194.947,310.342 195.07,310.465 ccw(c195.008,310.526) 195.07,310.587 194.971,310.685 194.874,310.782 cw(c194.935,310.844) 194.874,310.905 194.997,311.027 cw(c195.058,310.966) 195.119,311.027 195.216,310.93 195.314,310.832 ccw(c195.376,310.893) 195.437,310.832 195.559,310.954 ccw(c195.498,311.015) 195.559,311.077 195.461,311.175 195.364,311.272 cw(c195.425,311.333) 195.364,311.394 195.486,311.517 cw(c195.547,311.456) 195.609,311.517 195.706,311.419 195.804,311.321 ccw(c195.865,311.383) 195.926,311.321 196.049,311.444 ccw(c195.988,311.505) 196.049,311.566 195.951,311.664 195.853,311.762 cw(c195.915,311.823) 195.853,311.884 195.976,312.006 cw(c196.037,311.945) 196.098,312.006 196.195,311.909 196.294,311.811 ccw(c196.355,311.872) 196.416,311.811 196.538,311.933 ccw(c196.477,311.995) 196.538,312.056 196.44,312.154 196.343,312.251 cw(c196.404,312.312) 196.343,312.374 196.465,312.496 cw(c196.527,312.435) 196.588,312.496 196.685,312.399 196.783,312.301 ccw(c196.844,312.362) 196.906,312.301 197.028,312.423 ccw(c196.967,312.484) 197.028,312.545 196.93,312.643 196.833,312.741 cw(c196.894,312.802) 196.833,312.863 196.955,312.986 cw(c197.016,312.924) 197.077,312.986 197.175,312.888 197.273,312.79 ccw(c197.334,312.851) 197.395,312.79 197.518,312.913 ccw(c197.456,312.974) 197.518,313.035 197.419,313.133 197.322,313.23 cw(c197.383,313.292) 197.322,313.353 197.445,313.475 cw(c197.506,313.414) 197.567,313.475 197.664,313.378 197.762,313.28 ccw(c197.824,313.341) 197.885,313.28 198.007,313.402 ccw(c197.946,313.463) 198.007,313.525 197.909,313.623 197.812,313.72 cw(c197.873,313.781) 197.812,313.842 197.934,313.965 cw(c197.995,313.904) 198.057,313.965 198.154,313.867 198.252,313.769 ccw(c198.313,313.831) 198.374,313.769 198.497,313.892 ccw(c198.436,313.953) 198.497,314.014 198.399,314.112 198.301,314.21 cw(c198.363,314.271) 198.301,314.332 198.424,314.454 cw(c198.485,314.393) 198.546,314.454 198.643,314.357 198.742,314.259 ccw(c198.803,314.32) 198.864,314.259 198.986,314.381 ccw(c198.925,314.443) 198.986,314.504 198.888,314.602 198.791,314.699 cw(c198.852,314.76) 198.791,314.822 198.913,314.944 cw(c198.975,314.883) 199.036,314.944 199.133,314.847 199.231,314.749 ccw(c199.292,314.81) 199.354,314.749 199.476,314.871 ccw(c199.415,314.932) 199.476,314.993 199.378,315.091 199.281,315.189 cw(c199.342,315.25) 199.281,315.311 199.403,315.434 cw(c199.464,315.372) 199.525,315.434 199.623,315.336 199.721,315.238 ccw(c199.782,315.299) 199.843,315.238 199.966,315.361 ccw(c199.904,315.422) 199.966,315.483 199.867,315.581 199.77,315.678 cw(c199.831,315.74) 199.77,315.801 199.893,315.923 cw(c199.954,315.862) 200.015,315.923 200.112,315.826 200.21,315.728 ccw(c200.272,315.789) 200.333,315.728 200.455,315.85 ccw(c200.394,315.911) 200.455,315.973 200.418,316.009 cw(c200.479,316.071) 200.418,316.132 204.906,320.62 208.152,323.865 208.152,330.633 207.912,330.873 207.191,330.873 206.461,331.604 v3(206.461,331.664)
DDR4_DM1: U1.AJ25 U8.E4 | length 31.4
  L1 w0.116: U1.AJ25@190.397,312.539 v5(190.884,313.027) ; U8.E4@202.07,331.241 v3(202.473,330.838)
  L12 (Sign) w0.092: v5(190.884,313.027) 191.031,313.027 192.22,314.216 192.336,314.333 ccw(c192.259,314.41) 192.336,314.488 192.089,314.735 cw(c192.167,314.813) 192.089,314.89 192.322,315.123 cw(c192.4,315.046) 192.478,315.123 192.803,314.799 192.999,314.603 ccw(c193.076,314.68) 193.154,314.603 193.387,314.836 ccw(c193.309,314.913) 193.387,314.991 193.191,315.187 192.866,315.512 cw(c192.944,315.59) 192.866,315.667 193.099,315.9 cw(c193.177,315.823) 193.255,315.9 193.579,315.576 193.776,315.38 ccw(c193.853,315.457) 193.931,315.38 194.164,315.613 ccw(c194.086,315.69) 194.164,315.768 193.968,315.964 193.643,316.289 cw(c193.721,316.367) 193.643,316.444 193.876,316.677 cw(c193.954,316.6) 194.032,316.677 194.356,316.353 194.553,316.156 ccw(c194.63,316.234) 194.708,316.156 194.941,316.39 ccw(c194.863,316.467) 194.941,316.545 194.745,316.741 194.42,317.066 cw(c194.498,317.143) 194.42,317.221 194.653,317.454 cw(c194.731,317.377) 194.809,317.454 195.056,317.207 ccw(c195.133,317.285) 195.211,317.207 196.361,318.357 201.178,323.174 201.178,329.123 200.5,329.802 200.5,330.193 200.738,330.432 201.757,330.432 202.16,330.835 202.471,330.835 v3(202.473,330.838)
DDR4_DM2: U1.AF21 U10.E2 | length 39.6
  L1 w0.116: v5(186.909,309.027) U1.AF21@187.397,308.539 ; U10.E2@194.597,331.26 v3(195,331.664)
  L12 (Sign) w0.092: v5(186.909,309.027) 187.261,308.675 187.96,308.675 188.016,308.731 188.017,308.731 188.205,308.919 188.205,308.921 188.62,309.335 188.62,310.067 188.122,310.565 188.092,310.565 187.357,311.3 187.357,312.749 187.422,312.814 187.422,313.589 185.814,315.198 185.814,316.001 187.966,318.154 188.281,318.468 ccw(c188.175,318.575) 188.281,318.681 188.256,318.706 cw(c188.362,318.812) 188.256,318.918 188.468,319.13 cw(c188.574,319.024) 188.68,319.13 188.811,318.999 188.942,318.868 ccw(c189.049,318.974) 189.155,318.868 189.367,319.08 ccw(c189.261,319.186) 189.367,319.292 189.236,319.423 189.104,319.555 cw(c189.21,319.661) 189.104,319.767 189.317,319.979 cw(c189.423,319.873) 189.529,319.979 189.66,319.848 189.791,319.716 ccw(c189.897,319.823) 190.003,319.716 190.216,319.929 ccw(c190.11,320.035) 190.216,320.141 190.084,320.272 189.953,320.403 cw(c190.059,320.509) 189.953,320.616 190.165,320.828 cw(c190.271,320.722) 190.378,320.828 190.509,320.697 190.64,320.565 ccw(c190.746,320.671) 190.852,320.565 191.064,320.777 ccw(c190.958,320.884) 191.064,320.99 190.933,321.121 190.802,321.252 cw(c190.908,321.358) 190.802,321.464 191.014,321.677 cw(c191.12,321.57) 191.226,321.677 191.358,321.545 191.489,321.414 ccw(c191.595,321.52) 191.701,321.414 191.913,321.626 ccw(c191.807,321.732) 191.913,321.839 191.782,321.97 191.651,322.101 cw(c191.757,322.207) 191.651,322.313 191.863,322.525 cw(c191.969,322.419) 192.075,322.525 192.206,322.394 192.338,322.263 ccw(c192.444,322.369) 192.55,322.263 192.762,322.475 ccw(c192.656,322.581) 192.762,322.687 192.631,322.819 192.5,322.95 cw(c192.606,323.056) 192.5,323.162 192.712,323.374 cw(c192.818,323.268) 192.924,323.374 193.055,323.243 193.187,323.112 ccw(c193.293,323.218) 193.399,323.112 193.611,323.324 ccw(c193.505,323.43) 193.611,323.536 193.48,323.667 193.348,323.799 cw(c193.455,323.905) 193.348,324.011 193.561,324.223 cw(c193.667,324.117) 193.773,324.223 193.904,324.092 194.035,323.961 ccw(c194.141,324.067) 194.248,323.961 194.46,324.173 ccw(c194.354,324.279) 194.46,324.385 194.328,324.516 194.197,324.647 cw(c194.303,324.754) 194.197,324.86 194.409,325.072 cw(c194.516,324.966) 194.622,325.072 194.753,324.941 194.884,324.809 ccw(c194.99,324.915) 195.096,324.809 195.309,325.022 ccw(c195.202,325.128) 195.309,325.234 195.283,325.259 cw(c195.39,325.365) 195.283,325.471 195.389,325.577 195.389,331.275 v3(195,331.664)
DDR4_DM3: U1.AE25 U10.E4 | length 29
  L1 w0.116: v5(185.909,313.027) U1.AE25@186.397,312.539 ; U10.E4@190.597,331.26 v3(191,330.857)
  L12 (Sign) w0.092: v5(185.909,313.027) 185.909,313.251 ccw(c185.712,313.251) 185.712,313.449 185.603,313.449 ccw(c185.603,313.278) 185.433,313.278 185.433,312.793 cw(c185.255,312.793) 185.255,312.615 184.868,312.615 184.396,313.086 184.396,318.867 186.505,320.975 186.611,321.081 ccw(c186.54,321.152) 186.611,321.222 186.608,321.225 cw(c186.678,321.295) 186.608,321.366 186.819,321.577 cw(c186.89,321.507) 186.96,321.577 187.034,321.504 187.107,321.431 ccw(c187.177,321.502) 187.248,321.431 187.459,321.643 ccw(c187.389,321.713) 187.459,321.784 187.386,321.857 187.313,321.93 cw(c187.384,322) 187.313,322.071 187.525,322.283 cw(c187.595,322.212) 187.666,322.283 187.739,322.209 187.812,322.136 ccw(c187.882,322.207) 187.953,322.136 188.165,322.348 ccw(c188.094,322.418) 188.165,322.489 188.091,322.562 188.018,322.635 cw(c188.089,322.706) 188.018,322.776 188.23,322.988 cw(c188.3,322.917) 188.371,322.988 188.444,322.914 188.517,322.841 ccw(c188.588,322.912) 188.658,322.841 188.87,323.053 ccw(c188.799,323.123) 188.87,323.194 188.796,323.267 188.723,323.34 cw(c188.794,323.411) 188.723,323.481 188.935,323.693 cw(c189.005,323.622) 189.076,323.693 189.149,323.62 189.222,323.546 ccw(c189.293,323.617) 189.363,323.546 189.575,323.758 ccw(c189.504,323.829) 189.575,323.899 189.502,323.972 189.428,324.045 cw(c189.499,324.116) 189.428,324.186 189.64,324.398 cw(c189.71,324.327) 189.781,324.398 189.854,324.325 189.927,324.252 ccw(c189.998,324.322) 190.068,324.252 190.28,324.463 ccw(c190.209,324.534) 190.28,324.604 190.207,324.677 190.134,324.75 cw(c190.204,324.821) 190.134,324.891 190.345,325.103 cw(c190.416,325.033) 190.486,325.103 190.489,325.1 ccw(c190.559,325.171) 190.63,325.1 191.253,325.723 191.358,325.829 191.476,325.829 191.771,326.125 ; v3(191,330.857) 191.771,330.085 191.771,326.125 ; 191.771,326.432 191.771,326.125
DDR4_DM4: U1.Y24 U9.E2 | length 39.1
  L1 w0.116: v3(171.272,330.857) U9.E2@171.676,331.26 ; v1(180.909,311.052) U1.Y24@181.397,311.539
  L12 (Sign) w0.092: v3(171.272,330.857) 171.272,330.591 172.37,329.493 172.37,327.634 172.547,327.458 cw(c172.586,327.419) 172.625,327.458 172.899,327.183 cw(c172.86,327.144) 172.899,327.105 172.646,326.852 ccw(c172.717,326.782) 172.646,326.711 172.858,326.5 ccw(c172.929,326.57) 172.999,326.5 173.252,326.752 173.489,326.99 cw(c173.56,326.919) 173.63,326.99 173.842,326.778 cw(c173.771,326.708) 173.842,326.637 173.604,326.4 173.352,326.147 ccw(c173.422,326.077) 173.352,326.006 173.563,325.794 ccw(c173.634,325.865) 173.704,325.794 173.957,326.047 174.21,326.3 cw(c174.28,326.23) 174.351,326.3 174.562,326.089 cw(c174.492,326.018) 174.562,325.947 174.309,325.695 174.057,325.442 ccw(c174.127,325.371) 174.057,325.301 174.268,325.089 ccw(c174.339,325.16) 174.409,325.089 174.662,325.342 174.915,325.595 cw(c174.985,325.524) 175.056,325.595 175.267,325.383 cw(c175.197,325.313) 175.267,325.242 175.015,324.99 174.762,324.737 ccw(c174.832,324.666) 174.762,324.596 174.973,324.384 ccw(c175.044,324.455) 175.114,324.384 175.367,324.637 175.62,324.89 cw(c175.69,324.819) 175.761,324.89 175.973,324.678 cw(c175.902,324.608) 175.973,324.537 175.72,324.284 175.467,324.032 ccw(c175.537,323.961) 175.467,323.891 175.678,323.679 ccw(c175.749,323.75) 175.82,323.679 176.072,323.932 176.325,324.185 cw(c176.396,324.114) 176.466,324.185 176.678,323.973 cw(c176.607,323.903) 176.678,323.832 176.495,323.65 ccw(c176.566,323.579) 176.495,323.509 176.662,323.342 176.746,323.258 176.746,322.999 176.746,322.165 ccw(c176.835,322.165) 176.835,322.075 176.998,322.075 cw(c176.998,321.986) 177.088,321.986 177.088,321.717 cw(c176.998,321.717) 176.998,321.627 176.746,321.627 176.492,321.627 ccw(c176.492,321.538) 176.402,321.538 176.402,321.269 ccw(c176.492,321.269) 176.492,321.18 176.746,321.18 176.998,321.18 cw(c176.998,321.09) 177.088,321.09 177.088,320.821 cw(c176.998,320.821) 176.998,320.732 176.746,320.732 176.492,320.732 ccw(c176.492,320.642) 176.402,320.642 176.402,320.373 ccw(c176.492,320.373) 176.492,320.284 176.746,320.284 176.998,320.284 cw(c176.998,320.194) 177.088,320.194 177.088,319.926 cw(c176.998,319.926) 176.998,319.836 176.746,319.836 176.492,319.836 ccw(c176.492,319.747) 176.402,319.747 176.402,319.478 ccw(c176.492,319.478) 176.492,319.388 176.746,319.388 176.998,319.388 cw(c176.998,319.299) 177.088,319.299 177.088,319.03 cw(c176.998,319.03) 176.998,318.941 176.746,318.941 176.492,318.941 ccw(c176.492,318.851) 176.402,318.851 176.402,318.582 ccw(c176.492,318.582) 176.492,318.493 176.656,318.493 cw(c176.656,318.403) 176.746,318.403 176.746,318.269 176.746,316.114 177.786,315.074 177.786,312.854 178.488,312.151 178.488,311.863 178.72,311.631 179.048,311.631 179.124,311.706 179.695,311.706 179.812,311.589 180.325,311.589 180.862,311.052 v1(180.909,311.052)
DDR4_DM5: U1.R24 U9.E4 | length 31.6
  L1 w0.116: U9.E4@167.676,331.26 v3(168.079,330.857) ; U1.R24@176.397,311.539 v1(176.884,312.027)
  L12 (Sign) w0.092: v3(168.079,330.857) 167.118,329.895 167.118,323.904 167.781,323.241 168.448,322.574 cw(c168.36,322.486) 168.448,322.397 168.317,322.266 ccw(c168.405,322.178) 168.317,322.089 168.493,321.913 ccw(c168.581,322.001) 168.669,321.913 168.889,322.133 168.916,322.16 cw(c169.004,322.072) 169.092,322.16 169.269,321.983 cw(c169.18,321.895) 169.269,321.807 ; 169.269,321.807 ccw(c169.295,321.78) 169.269,321.754 169.418,321.604 169.58,321.442 cw(c169.492,321.354) 169.58,321.266 169.448,321.134 ccw(c169.536,321.046) 169.448,320.958 169.624,320.782 ccw(c169.713,320.87) 169.801,320.782 170.021,321.002 cw(c170.093,320.929) 170.165,321.002 170.373,320.793 cw(c170.301,320.721) 170.373,320.649 170.153,320.429 ccw(c170.241,320.341) 170.153,320.253 170.33,320.077 ccw(c170.418,320.165) 170.506,320.077 170.726,320.296 cw(c170.798,320.224) 170.87,320.296 171.078,320.088 cw(c171.006,320.016) 171.078,319.944 170.858,319.724 ccw(c170.947,319.636) 170.858,319.548 171.035,319.372 ccw(c171.123,319.46) 171.211,319.372 171.431,319.591 cw(c171.503,319.519) 171.575,319.591 171.783,319.383 cw(c171.711,319.311) 171.783,319.239 171.564,319.019 ccw(c171.652,318.931) 171.564,318.843 171.74,318.666 ccw(c171.828,318.755) 171.916,318.666 172.048,318.798 cw(c172.136,318.71) 172.224,318.798 172.312,318.71 172.312,316.282 172.885,315.709 172.885,314.617 173.841,313.662 173.841,311.654 174.076,311.418 174.076,311.406 174.264,311.218 174.276,311.218 174.293,311.201 174.701,311.201 174.892,311.391 175.689,311.391 175.72,311.423 176.048,311.423 176.08,311.391 176.545,311.391 176.884,311.73 v1(176.884,312.027)
DDR4_DM6: U1.V28 U11.E2 | length 28.8
  L1 w0.116: v2(178.91,316.027) U1.V28@179.397,315.539 ; U11.E2@183.136,331.26 183.533,330.864 v2(183.533,330.862)
  L3 (Sign) w0.092: v2(178.91,316.027) 178.91,316.425 179.324,316.84 179.324,317.462 179.08,317.706 178.751,317.706 178.563,317.894 178.563,318.416 182.062,321.915 182.149,322.001 cw(c182.21,321.94) 182.271,322.001 182.303,321.97 ccw(c182.364,322.031) 182.425,321.97 182.548,322.092 ccw(c182.487,322.153) 182.548,322.215 182.516,322.246 cw(c182.577,322.307) 182.516,322.369 182.639,322.491 cw(c182.7,322.43) 182.761,322.491 182.793,322.459 ccw(c182.854,322.521) 182.915,322.459 183.037,322.582 ccw(c182.976,322.643) 183.037,322.704 183.006,322.736 cw(c183.067,322.797) 183.006,322.858 183.189,323.042 183.312,323.164 184.273,323.164 184.507,323.398 184.507,323.484 ccw(c184.42,323.484) 184.42,323.571 184.06,323.571 cw(c184.06,323.658) 183.973,323.658 183.973,323.831 cw(c184.06,323.831) 184.06,323.917 184.507,323.917 184.66,323.917 ccw(c184.66,324.004) 184.746,324.004 184.746,324.177 ccw(c184.66,324.177) 184.66,324.263 184.507,324.263 184.06,324.263 cw(c184.06,324.35) 183.973,324.35 183.973,324.523 cw(c184.06,324.523) 184.06,324.61 184.507,324.61 184.66,324.61 ccw(c184.66,324.696) 184.746,324.696 184.746,324.869 ccw(c184.66,324.869) 184.66,324.956 184.507,324.956 184.06,324.956 cw(c184.06,325.042) 183.973,325.042 183.973,325.215 cw(c184.06,325.215) 184.06,325.302 184.507,325.302 184.66,325.302 ccw(c184.66,325.389) 184.746,325.389 184.746,325.562 ccw(c184.66,325.562) 184.66,325.648 184.507,325.648 184.06,325.648 cw(c184.06,325.735) 183.973,325.735 183.973,325.908 cw(c184.06,325.908) 184.06,325.994 184.507,325.994 184.66,325.994 ccw(c184.66,326.081) 184.746,326.081 184.746,326.254 ccw(c184.66,326.254) 184.66,326.341 184.507,326.341 184.06,326.341 cw(c184.06,326.427) 183.973,326.427 183.973,326.6 cw(c184.06,326.6) 184.06,326.687 184.507,326.687 184.66,326.687 ccw(c184.66,326.773) 184.746,326.773 184.746,326.946 ccw(c184.66,326.946) 184.66,327.033 184.593,327.033 cw(c184.593,327.12) 184.507,327.12 184.507,327.381 184.507,327.411 183.909,328.009 183.909,329.603 ccw(c183.777,329.603) 183.777,329.735 183.642,329.735 cw(c183.642,329.862) 183.515,329.862 183.515,329.991 cw(c183.623,329.991) 183.623,330.098 183.972,330.098 ccw(c183.972,330.247) 184.121,330.247 184.121,330.276 ccw(c183.962,330.276) 183.962,330.436 183.693,330.436 cw(c183.693,330.596) 183.533,330.596 v2(183.533,330.862)
DDR4_DM7: U1.P28 U11.E4 | length 21.5
  L1 w0.116: v2(174.91,316.027) U1.P28@175.397,315.539 ; v2(178.74,331.659) 178.74,331.657 U11.E4@179.136,331.26
  L3 (Sign) w0.092: v2(174.91,316.027) 174.249,316.027 174.001,316.274 174.001,317.963 176.682,320.645 176.682,325.153 177.662,326.133 177.662,328.85 178.192,329.38 178.192,329.857 178.384,330.05 178.384,330.169 ccw(c178.305,330.169) 178.305,330.248 178.248,330.248 cw(c178.248,330.328) 178.169,330.328 178.169,330.566 cw(c178.248,330.566) 178.248,330.645 178.384,330.645 179.123,330.645 ccw(c179.123,330.725) 179.203,330.725 179.203,330.963 ccw(c179.123,330.963) 179.123,331.042 178.464,331.042 cw(c178.464,331.122) 178.384,331.122 178.384,331.304 v2(178.74,331.659)
DDR4_DM8: U1.AA27
DDR4_DQ0: U1.AH22 U8.G2 | length 47.3
  L1 w0.116: U1.AH22@189.397,309.539 v5(189.884,309.052) ; U8.G2@206.057,332.86 v3(206.461,333.264)
  L12 (Sign) w0.092: v5(189.884,309.052) 189.884,308.898 189.128,308.142 189.128,308.056 188.314,307.242 188.265,307.242 188.265,305.671 188.539,305.397 189.635,305.397 189.947,305.709 192.629,305.709 209.396,322.477 209.396,332.421 208.083,333.734 207.084,333.734 206.614,333.264 v3(206.461,333.264)
DDR4_DQ1: U1.AH21 U8.F4 | length 47.3
  L1 w0.116: U1.AH21@189.397,308.539 v5(189.884,308.052) ; v3(201.653,332.464) U8.F4@202.057,332.06
  L12 (Sign) w0.092: v5(189.884,308.052) 190.468,308.635 191.96,308.635 207.166,323.84 207.166,323.875 207.166,324.438 207.166,324.697 ccw(c207.079,324.697) 207.079,324.784 206.353,324.784 cw(c206.353,324.871) 206.266,324.871 206.266,325.044 cw(c206.353,325.044) 206.353,325.13 207.079,325.13 ccw(c207.079,325.217) 207.166,325.217 207.166,325.39 ccw(c207.079,325.39) 207.079,325.476 206.353,325.476 cw(c206.353,325.563) 206.266,325.563 206.266,325.736 cw(c206.353,325.736) 206.353,325.823 207.079,325.823 ccw(c207.079,325.909) 207.166,325.909 207.166,326.082 ccw(c207.079,326.082) 207.079,326.169 206.353,326.169 cw(c206.353,326.255) 206.266,326.255 206.266,326.428 cw(c206.353,326.428) 206.353,326.515 207.079,326.515 ccw(c207.079,326.602) 207.166,326.602 207.166,326.775 ccw(c207.079,326.775) 207.079,326.861 206.353,326.861 cw(c206.353,326.948) 206.266,326.948 206.266,327.121 cw(c206.353,327.121) 206.353,327.207 207.079,327.207 ccw(c207.079,327.294) 207.166,327.294 207.166,327.467 ccw(c207.079,327.467) 207.079,327.554 206.782,327.554 cw(c206.782,327.64) 206.696,327.64 206.696,327.813 cw(c206.782,327.813) 206.782,327.9 207.079,327.9 ccw(c207.079,327.986) 207.166,327.986 207.166,328.159 ccw(c207.079,328.159) 207.079,328.246 206.921,328.246 cw(c206.921,328.333) 206.835,328.333 206.835,328.506 cw(c206.921,328.506) 206.921,328.592 207.079,328.592 ccw(c207.079,328.679) 207.166,328.679 207.166,328.765 207.166,330.356 206.371,331.151 206.188,331.151 205.325,332.014 204.659,332.014 203.019,333.654 202.129,333.654 201.653,333.179 v3(201.653,332.464)
DDR4_DQ2: U1.AJ22 U8.H3 | length 45.9
  L1 w0.116: U1.AJ22@190.397,309.539 v5(190.884,309.052) ; v3(204.853,334.064) U8.H3@205.257,333.66
  L12 (Sign) w0.092: v5(190.884,309.052) 190.396,309.052 188.506,307.162 188.506,305.829 188.659,305.676 189.585,305.676 190.664,306.756 190.874,306.756 191.636,307.518 192.399,307.518 208.343,323.463 208.343,331.254 207.982,331.615 207.132,331.615 206.549,332.198 205.912,332.198 205.366,332.744 205.366,333.551 v3(204.853,334.064)
DDR4_DQ3: U1.AK22 U8.H4 | length 45.5
  L1 w0.116: U1.AK22@191.397,309.539 v5(191.884,309.052) ; U8.H4@202.06,333.66 U8.H4@202.057,333.66 v3(202.461,333.257)
  L12 (Sign) w0.092: v5(191.884,309.052) 192.007,309.174 192.202,309.37 cw(c192.252,309.32) 192.301,309.37 ccw(c192.362,309.431) 192.423,309.37 192.546,309.492 ccw(c192.485,309.553) 192.546,309.615 192.496,309.664 192.22,309.94 cw(c192.282,310.001) 192.22,310.062 192.343,310.185 cw(c192.404,310.124) 192.465,310.185 192.741,309.909 192.778,309.872 ccw(c192.839,309.933) 192.9,309.872 193.023,309.994 ccw(c192.962,310.055) 193.023,310.117 192.986,310.154 192.71,310.43 cw(c192.771,310.491) 192.71,310.552 192.832,310.674 cw(c192.894,310.613) 192.955,310.674 193.231,310.398 193.268,310.361 ccw(c193.329,310.423) 193.39,310.361 193.512,310.484 ; 193.512,310.484 ccw(c193.451,310.545) 193.512,310.606 193.476,310.643 193.2,310.919 cw(c193.261,310.98) 193.2,311.042 193.322,311.164 cw(c193.383,311.103) 193.444,311.164 193.72,310.888 193.757,310.851 ccw(c193.818,310.912) 193.88,310.851 194.002,310.973 ccw(c193.941,311.035) 194.002,311.096 193.965,311.133 193.689,311.409 cw(c193.75,311.47) 193.689,311.531 193.812,311.654 cw(c193.873,311.592) 193.934,311.654 194.21,311.378 194.247,311.341 ccw(c194.308,311.402) 194.369,311.341 194.492,311.463 ccw(c194.43,311.524) 194.492,311.585 194.455,311.622 194.179,311.898 cw(c194.24,311.96) 194.179,312.021 194.301,312.143 cw(c194.362,312.082) 194.424,312.143 194.7,311.867 194.736,311.83 ccw(c194.798,311.891) 194.859,311.83 194.981,311.953 ccw(c194.92,312.014) 194.981,312.075 194.944,312.112 194.668,312.388 cw(c194.73,312.449) 194.668,312.51 194.791,312.633 cw(c194.852,312.572) 194.913,312.633 195.189,312.357 195.226,312.32 ccw(c195.287,312.381) 195.348,312.32 195.471,312.442 ccw(c195.41,312.503) 195.471,312.565 195.434,312.602 195.158,312.878 cw(c195.219,312.939) 195.158,313 195.28,313.122 cw(c195.342,313.061) 195.403,313.122 195.679,312.846 195.716,312.809 ccw(c195.777,312.871) 195.838,312.809 195.96,312.932 ccw(c195.899,312.993) 195.96,313.054 195.924,313.091 195.648,313.367 cw(c195.709,313.428) 195.648,313.49 195.77,313.612 cw(c195.831,313.551) 195.892,313.612 196.168,313.336 196.205,313.299 ccw(c196.266,313.36) 196.328,313.299 196.45,313.421 ccw(c196.389,313.483) 196.45,313.544 196.413,313.581 196.137,313.857 cw(c196.198,313.918) 196.137,313.979 196.26,314.102 cw(c196.321,314.04) 196.382,314.102 196.658,313.826 196.695,313.789 ccw(c196.756,313.85) 196.817,313.789 196.94,313.911 ccw(c196.878,313.972) 196.94,314.033 196.903,314.07 196.627,314.346 cw(c196.688,314.408) 196.627,314.469 196.749,314.591 cw(c196.81,314.53) 196.872,314.591 197.148,314.315 197.184,314.278 ccw(c197.246,314.339) 197.307,314.278 197.429,314.401 ccw(c197.368,314.462) 197.429,314.523 197.441,314.511 cw(c197.491,314.56) 197.442,314.609 200.84,318.007 206.029,323.196 206.029,328.039 206.974,328.984 206.974,330.276 206.291,330.959 206.109,330.959 205.245,331.822 204.579,331.822 203.145,333.257 v3(202.461,333.257)
DDR4_DQ4: U1.AK20 U8.H2 | length 45.7
  L1 w0.116: U1.AK20@191.397,307.539 v3(191.8,307.136) ; v3(205.653,334.064) U8.H2@206.057,333.66
  L12 (Sign) w0.092: v3(191.8,307.136) 192.653,307.136 192.776,307.258 193.02,307.503 193.204,307.687 ccw(c193.143,307.748) 193.204,307.809 193.147,307.866 cw(c193.208,307.927) 193.147,307.988 193.27,308.111 cw(c193.331,308.049) 193.392,308.111 193.449,308.054 ccw(c193.51,308.115) 193.571,308.054 193.694,308.176 ccw(c193.632,308.237) 193.694,308.299 193.637,308.355 cw(c193.698,308.417) 193.637,308.478 193.759,308.6 cw(c193.82,308.539) 193.882,308.6 193.938,308.543 ccw(c194,308.605) 194.061,308.543 194.183,308.666 ccw(c194.122,308.727) 194.183,308.788 194.126,308.845 cw(c194.188,308.906) 194.126,308.967 194.249,309.09 cw(c194.31,309.029) 194.371,309.09 194.428,309.033 ccw(c194.489,309.094) 194.55,309.033 194.673,309.155 ccw(c194.612,309.217) 194.673,309.278 194.616,309.335 cw(c194.677,309.396) 194.616,309.457 194.738,309.579 cw(c194.8,309.518) 194.861,309.579 194.918,309.523 ccw(c194.979,309.584) 195.04,309.523 195.162,309.645 ccw(c195.101,309.706) 195.162,309.767 195.106,309.824 cw(c195.167,309.885) 195.106,309.947 195.228,310.069 cw(c195.289,310.008) 195.35,310.069 195.407,310.012 ccw(c195.468,310.073) 195.53,310.012 195.652,310.135 ccw(c195.591,310.196) 195.652,310.257 195.595,310.314 cw(c195.656,310.375) 195.595,310.436 195.718,310.559 cw(c195.779,310.497) 195.84,310.559 195.897,310.502 ccw(c195.958,310.563) 196.019,310.502 196.142,310.624 ccw(c196.08,310.685) 196.142,310.747 196.085,310.803 cw(c196.146,310.865) 196.085,310.926 196.207,311.048 cw(c196.268,310.987) 196.33,311.048 196.386,310.991 ccw(c196.448,311.053) 196.509,310.991 196.631,311.114 ccw(c196.57,311.175) 196.631,311.236 196.574,311.293 cw(c196.636,311.354) 196.574,311.415 196.697,311.538 cw(c196.758,311.477) 196.819,311.538 196.876,311.481 ccw(c196.937,311.542) 196.998,311.481 197.121,311.603 ccw(c197.06,311.665) 197.121,311.726 197.064,311.783 cw(c197.125,311.844) 197.064,311.905 197.186,312.027 cw(c197.248,311.966) 197.309,312.027 197.366,311.971 ccw(c197.427,312.032) 197.488,311.971 197.61,312.093 ccw(c197.549,312.154) 197.61,312.215 197.554,312.272 cw(c197.615,312.333) 197.554,312.395 197.676,312.517 cw(c197.737,312.456) 197.798,312.517 197.855,312.46 ccw(c197.916,312.521) 197.978,312.46 198.1,312.583 ccw(c198.039,312.644) 198.1,312.705 198.043,312.762 cw(c198.104,312.823) 198.043,312.884 198.166,313.007 cw(c198.227,312.945) 198.288,313.007 198.345,312.95 ccw(c198.406,313.011) 198.467,312.95 198.59,313.072 ccw(c198.528,313.133) 198.59,313.195 198.533,313.251 cw(c198.594,313.313) 198.533,313.374 198.655,313.496 cw(c198.716,313.435) 198.778,313.496 198.834,313.439 ccw(c198.896,313.501) 198.957,313.439 199.079,313.562 ccw(c199.018,313.623) 199.079,313.684 199.022,313.741 cw(c199.084,313.802) 199.022,313.863 199.145,313.986 cw(c199.206,313.925) 199.267,313.986 199.324,313.929 ccw(c199.385,313.99) 199.446,313.929 199.569,314.051 ccw(c199.508,314.113) 199.569,314.174 199.512,314.231 cw(c199.573,314.292) 199.512,314.353 199.634,314.475 cw(c199.696,314.414) 199.757,314.475 199.814,314.419 ccw(c199.875,314.48) 199.936,314.419 200.058,314.541 ccw(c199.997,314.602) 200.058,314.663 200.002,314.72 cw(c200.063,314.781) 200.002,314.843 200.124,314.965 cw(c200.185,314.904) 200.246,314.965 200.303,314.908 ccw(c200.364,314.969) 200.426,314.908 200.548,315.031 ccw(c200.487,315.092) 200.548,315.153 200.491,315.21 cw(c200.552,315.271) 200.491,315.332 200.614,315.455 cw(c200.675,315.393) 200.736,315.455 200.793,315.398 ccw(c200.854,315.459) 200.915,315.398 201.038,315.52 ccw(c200.976,315.581) 201.038,315.643 200.981,315.699 cw(c201.042,315.761) 200.981,315.822 201.103,315.944 cw(c201.164,315.883) 201.226,315.944 201.282,315.887 ccw(c201.344,315.949) 201.405,315.887 201.527,316.01 ccw(c201.466,316.071) 201.527,316.132 201.47,316.189 cw(c201.532,316.25) 201.47,316.311 201.593,316.434 cw(c201.654,316.373) 201.715,316.434 201.772,316.377 ccw(c201.833,316.438) 201.894,316.377 202.017,316.499 ccw(c201.956,316.561) 202.017,316.622 201.96,316.679 cw(c202.021,316.74) 201.96,316.801 202.082,316.923 cw(c202.144,316.862) 202.205,316.923 202.262,316.867 ccw(c202.323,316.928) 202.384,316.867 202.506,316.989 ccw(c202.445,317.05) 202.506,317.111 202.45,317.168 cw(c202.511,317.229) 202.45,317.291 202.572,317.413 cw(c202.633,317.352) 202.694,317.413 202.751,317.356 ccw(c202.812,317.417) 202.874,317.356 202.996,317.479 ccw(c202.935,317.54) 202.996,317.601 202.939,317.658 cw(c203,317.719) 202.939,317.78 203.062,317.903 cw(c203.123,317.841) 203.184,317.903 203.241,317.846 ccw(c203.302,317.907) 203.363,317.846 206.44,320.923 208.715,323.198 208.715,331.594 207.797,332.511 207.141,332.511 207.019,332.39 205.992,332.39 205.558,332.823 205.558,333.572 205.653,333.667 v3(205.653,334.064)
DDR4_DQ5: U1.AJ19 U8.H5 | length 46.7
  L1 w0.116: U1.AJ19@190.397,306.539 v3(190.8,306.136) ; v3(200.853,334.064) U8.H5@201.257,333.66
  L12 (Sign) w0.092: v3(190.8,306.136) 191.125,306.136 191.618,306.629 192.016,306.629 192.331,306.944 192.733,306.944 208.907,323.118 208.907,332 208.812,332.095 ccw(c208.748,332.031) 208.685,332.095 cw(c208.622,332.158) 208.558,332.095 208.369,332.285 cw(c208.432,332.348) 208.369,332.411 208.432,332.474 208.501,332.543 ccw(c208.437,332.607) 208.501,332.67 208.311,332.86 ccw(c208.247,332.797) 208.184,332.86 208.179,332.854 cw(c208.115,332.918) 208.052,332.854 207.956,332.95 207.633,333.273 207.169,333.273 207.01,333.114 207.01,332.778 206.814,332.582 206.071,332.582 205.765,332.888 205.765,333.389 205.974,333.598 205.974,334.197 205.711,334.46 201.25,334.46 v3(200.853,334.064)
DDR4_DQ6: U1.AK19 U8.J3 | length 46
  L1 w0.116: U1.AK19@191.397,306.539 v3(191.8,306.136) ; v3(204.72,334.924) 204.793,334.924 U8.J3@205.257,334.46
  L12 (Sign) w0.092: v3(191.8,306.136) 192.001,306.337 192.19,306.526 192.431,306.526 192.657,306.752 192.812,306.752 205.603,319.542 205.733,319.672 cw(c205.794,319.611) 205.855,319.672 205.977,319.55 ccw(c206.038,319.612) 206.1,319.55 206.222,319.673 ccw(c206.161,319.734) 206.222,319.795 206.1,319.917 cw(c206.161,319.978) 206.1,320.04 206.222,320.162 cw(c206.284,320.101) 206.345,320.162 206.467,320.04 ccw(c206.528,320.101) 206.589,320.04 206.712,320.162 ccw(c206.65,320.224) 206.712,320.285 206.59,320.407 cw(c206.651,320.468) 206.59,320.529 206.712,320.652 cw(c206.773,320.59) 206.834,320.652 206.956,320.53 ccw(c207.018,320.591) 207.079,320.53 207.201,320.652 ccw(c207.14,320.713) 207.201,320.774 207.079,320.896 cw(c207.14,320.958) 207.079,321.019 207.202,321.141 cw(c207.263,321.08) 207.324,321.141 207.446,321.019 ccw(c207.507,321.08) 207.568,321.019 207.691,321.142 ccw(c207.63,321.203) 207.691,321.264 207.569,321.386 cw(c207.63,321.447) 207.569,321.508 207.691,321.631 cw(c207.752,321.57) 207.814,321.631 207.936,321.509 ccw(c207.997,321.57) 208.058,321.509 208.18,321.631 ccw(c208.119,321.692) 208.18,321.754 208.058,321.876 cw(c208.12,321.937) 208.058,321.998 208.181,322.12 cw(c208.242,322.059) 208.303,322.12 208.425,321.998 ccw(c208.486,322.06) 208.548,321.998 208.67,322.121 ccw(c208.609,322.182) 208.67,322.243 208.548,322.365 cw(c208.609,322.426) 208.548,322.488 208.732,322.671 208.976,322.916 209.099,323.038 209.099,332.447 208.004,333.542 207.166,333.542 206.785,333.161 206.785,332.947 206.612,332.774 206.151,332.774 206.057,332.868 206.057,333.409 206.166,333.518 206.166,334.276 206.084,334.359 206.084,334.949 205.863,335.17 205.159,335.17 204.85,334.861 204.787,334.924 v3(204.72,334.924)
DDR4_DQ7: U1.AH19 U8.J4 | length 47.5
  L1 w0.116: v5(188.909,306.052) U1.AH19@189.397,306.539 ; U8.J4@202.06,334.46 U8.J4@202.057,334.46 v3(202.461,334.057)
  L12 (Sign) w0.092: v5(188.909,306.052) 189.436,306.052 190.332,306.948 190.335,306.948 190.335,308.067 190.69,308.423 192.116,308.423 207.358,323.664 207.358,323.837 207.358,324.097 cw(c207.444,324.097) 207.444,324.183 207.873,324.183 ccw(c207.873,324.27) 207.96,324.27 207.96,324.443 ccw(c207.873,324.443) 207.873,324.53 207.444,324.53 cw(c207.444,324.616) 207.358,324.616 207.358,324.789 cw(c207.444,324.789) 207.444,324.876 207.873,324.876 ccw(c207.873,324.962) 207.96,324.962 207.96,325.135 ccw(c207.873,325.135) 207.873,325.222 207.444,325.222 cw(c207.444,325.309) 207.358,325.309 207.358,325.482 cw(c207.444,325.482) 207.444,325.568 207.873,325.568 ccw(c207.873,325.655) 207.96,325.655 207.96,325.828 ccw(c207.873,325.828) 207.873,325.914 207.444,325.914 cw(c207.444,326.001) 207.358,326.001 207.358,326.174 cw(c207.444,326.174) 207.444,326.261 207.873,326.261 ccw(c207.873,326.347) 207.96,326.347 207.96,326.52 ccw(c207.873,326.52) 207.873,326.607 207.444,326.607 cw(c207.444,326.693) 207.358,326.693 207.358,326.866 cw(c207.444,326.866) 207.444,326.953 207.873,326.953 ccw(c207.873,327.04) 207.96,327.04 207.96,327.213 ccw(c207.873,327.213) 207.873,327.299 207.444,327.299 cw(c207.444,327.386) 207.358,327.386 207.358,327.645 207.358,327.736 207.358,330.436 206.45,331.343 206.268,331.343 205.174,332.436 205.174,332.597 204.986,332.785 204.35,332.785 204.228,332.907 204.044,333.091 cw(c204.105,333.152) 204.044,333.213 204.211,333.38 ccw(c204.15,333.442) 204.211,333.503 204.089,333.625 ccw(c204.027,333.564) 203.966,333.625 203.738,333.397 cw(c203.677,333.458) 203.616,333.397 203.493,333.519 cw(c203.554,333.581) 203.493,333.642 203.643,333.791 ccw(c203.582,333.853) 203.643,333.914 203.52,334.036 ccw(c203.459,333.975) 203.398,334.036 203.275,333.913 cw(c203.248,333.939) 203.222,333.913 203.078,334.057 v3(202.461,334.057)
DDR4_DQ8: U1.AH23 U8.A3 | length 34
  L1 w0.116: U1.AH23@189.397,310.539 v5(189.884,311.027) ; v3(204.853,327.657) U8.A3@205.257,328.06
  L12 (Sign) w0.092: v5(189.884,311.027) 190.341,311.483 192.499,311.483 192.87,311.854 193.198,312.182 cw(c193.253,312.128) 193.307,312.182 ccw(c193.385,312.26) 193.462,312.182 193.696,312.415 ccw(c193.618,312.493) 193.696,312.571 193.641,312.625 193.589,312.677 cw(c193.667,312.755) 193.589,312.833 193.822,313.066 cw(c193.9,312.988) 193.978,313.066 194.03,313.014 194.084,312.959 ccw(c194.162,313.037) 194.239,312.959 194.473,313.192 ccw(c194.395,313.27) 194.473,313.348 194.418,313.402 194.366,313.454 cw(c194.444,313.532) 194.366,313.61 194.599,313.843 cw(c194.677,313.765) 194.755,313.843 194.806,313.791 194.861,313.736 ccw(c194.939,313.814) 195.016,313.736 195.25,313.969 ccw(c195.172,314.047) 195.249,314.125 195.195,314.179 195.143,314.231 cw(c195.221,314.309) 195.143,314.387 195.376,314.62 cw(c195.454,314.542) 195.531,314.62 195.583,314.568 195.638,314.513 ccw(c195.716,314.591) 195.793,314.513 196.026,314.746 ccw(c195.949,314.824) 196.026,314.902 cw(c196.081,314.956) 196.026,315.011 196.166,315.15 197.098,315.15 204.853,322.906 204.853,323.497 204.853,323.784 ccw(c204.744,323.784) 204.744,323.894 204.388,323.894 cw(c204.388,324.004) 204.278,324.004 204.278,324.334 cw(c204.388,324.334) 204.388,324.444 204.853,324.444 205.319,324.444 ccw(c205.319,324.554) 205.429,324.554 205.429,324.883 ccw(c205.319,324.883) 205.319,324.993 204.853,324.993 204.388,324.993 cw(c204.388,325.103) 204.278,325.103 204.278,325.433 cw(c204.388,325.433) 204.388,325.543 204.853,325.543 205.319,325.543 ccw(c205.319,325.652) 205.429,325.652 205.429,325.982 ccw(c205.319,325.982) 205.319,326.092 204.853,326.092 204.388,326.092 cw(c204.388,326.202) 204.278,326.202 204.278,326.531 cw(c204.388,326.531) 204.388,326.641 204.853,326.641 205.319,326.641 ccw(c205.319,326.751) 205.429,326.751 205.429,327.081 ccw(c205.319,327.081) 205.319,327.191 204.963,327.191 cw(c204.963,327.301) 204.853,327.301 204.853,327.465 v3(204.853,327.657)
DDR4_DQ9: U1.AK23 U8.B5 | length 31.1
  L1 w0.116: U1.AK23@191.397,310.539 v5(191.884,311.027) ; v3(200.853,328.457) U8.B5@201.257,328.86
  L12 (Sign) w0.092: v5(191.884,311.027) 191.55,310.693 189.73,310.693 188.579,311.844 188.579,312.172 188.767,312.36 188.767,312.363 190.563,314.16 191.318,314.914 191.318,315.295 191.434,315.412 ccw(c191.357,315.489) 191.434,315.567 191.251,315.751 cw(c191.328,315.829) 191.251,315.906 191.484,316.139 cw(c191.562,316.062) 191.639,316.139 191.901,315.878 192.162,315.617 ccw(c192.24,315.694) 192.317,315.617 192.55,315.85 ccw(c192.473,315.927) 192.55,316.005 192.289,316.266 192.028,316.528 cw(c192.105,316.605) 192.028,316.683 192.261,316.916 cw(c192.339,316.839) 192.416,316.916 192.678,316.655 192.939,316.394 ccw(c193.017,316.471) 193.094,316.394 193.327,316.627 ccw(c193.25,316.704) 193.327,316.782 193.066,317.043 192.805,317.305 cw(c192.882,317.382) 192.805,317.46 193.038,317.693 cw(c193.115,317.616) 193.193,317.693 193.377,317.51 ccw(c193.455,317.587) 193.532,317.51 195.682,319.659 200.408,324.385 200.408,328.011 v3(200.853,328.457)
DDR4_DQ10: U1.AG24 U8.C3 | length 33.1
  L1 w0.116: U1.AG24@188.397,311.539 188.4,311.539 v5(188.9,312.039) ; v3(204.853,329.257) U8.C3@205.257,329.66
  L12 (Sign) w0.092: v5(188.9,312.039) 189.522,311.417 189.942,311.417 190.201,311.675 192.16,311.675 198.535,318.05 200.232,319.747 cw(c200.31,319.669) 200.387,319.747 200.614,319.52 ccw(c200.692,319.597) 200.77,319.52 201.003,319.753 ccw(c200.925,319.83) 201.003,319.908 200.698,320.213 cw(c200.776,320.291) 200.698,320.368 200.931,320.602 cw(c201.009,320.524) 201.086,320.602 201.391,320.297 ccw(c201.469,320.374) 201.547,320.297 201.78,320.53 ccw(c201.702,320.607) 201.78,320.685 201.475,320.99 cw(c201.553,321.068) 201.475,321.145 201.708,321.379 cw(c201.786,321.301) 201.863,321.379 202.168,321.074 ccw(c202.246,321.151) 202.324,321.074 202.557,321.307 ccw(c202.479,321.384) 202.557,321.462 202.252,321.767 cw(c202.33,321.845) 202.252,321.922 202.485,322.155 cw(c202.563,322.078) 202.64,322.155 202.945,321.85 ccw(c203.023,321.928) 203.101,321.85 203.334,322.084 ccw(c203.256,322.161) 203.334,322.239 203.029,322.544 cw(c203.107,322.622) 203.029,322.699 203.262,322.932 cw(c203.34,322.855) 203.417,322.932 203.722,322.627 ccw(c203.8,322.705) 203.878,322.627 204.111,322.861 ccw(c204.033,322.938) 204.111,323.016 203.884,323.243 cw(c203.961,323.321) 203.884,323.399 204,323.515 204,328.404 v3(204.853,329.257)
DDR4_DQ11: U1.AK24 U8.C4 | length 31.4
  L1 w0.116: U1.AK24@191.397,311.539 v5(191.884,312.027) ; U8.C4@202.057,329.66 v3(202.461,330.064)
  L12 (Sign) w0.092: v5(191.884,312.027) 192.07,312.027 203.086,323.043 203.086,324.396 203.086,324.672 cw(c203.196,324.672) 203.196,324.782 203.687,324.782 ccw(c203.687,324.892) 203.797,324.892 203.797,325.221 ccw(c203.687,325.221) 203.687,325.331 203.086,325.331 202.484,325.331 cw(c202.484,325.441) 202.374,325.441 202.374,325.771 cw(c202.484,325.771) 202.484,325.88 203.086,325.88 203.687,325.88 ccw(c203.687,325.99) 203.797,325.99 203.797,326.32 ccw(c203.687,326.32) 203.687,326.43 203.086,326.43 cw(c203.086,326.501) 203.015,326.501 203.015,326.908 cw(c203.086,326.908) 203.086,326.979 203.687,326.979 ccw(c203.687,327.089) 203.797,327.089 203.797,327.419 ccw(c203.687,327.419) 203.687,327.529 203.086,327.529 202.897,327.529 cw(c202.897,327.639) 202.787,327.639 202.787,327.968 cw(c202.897,327.968) 202.897,328.078 203.086,328.078 203.687,328.078 ccw(c203.687,328.188) 203.797,328.188 203.797,328.518 ccw(c203.687,328.518) 203.687,328.627 203.196,328.627 cw(c203.196,328.737) 203.086,328.737 203.086,328.902 202.461,329.527 v3(202.461,330.064)
DDR4_DQ12: U1.AJ26 U8.C2 | length 31.5
  L1 w0.116: U1.AJ26@190.397,313.539 v5(190.884,314.027) ; U8.C2@206.057,329.66 v3(206.461,330.064)
  L12 (Sign) w0.092: v5(190.884,314.027) 190.375,313.517 190.375,313.082 190.943,312.514 192.097,312.514 202.026,322.443 202.026,330.171 202.283,330.429 203.035,330.429 203.867,331.26 205.081,331.26 206.277,330.064 v3(206.461,330.064)
DDR4_DQ13: U1.AK25 U8.C5 | length 31.5
  L1 w0.116: U1.AK25@191.397,312.539 v5(191.884,313.027) ; v3(200.853,330.064) U8.C5@201.257,329.66
  L12 (Sign) w0.092: v5(191.884,313.027) 195.527,316.67 195.644,316.787 ccw(c195.566,316.864) 195.644,316.942 195.508,317.078 cw(c195.586,317.155) 195.508,317.233 195.741,317.466 cw(c195.819,317.388) 195.897,317.466 196.11,317.253 196.259,317.103 ccw(c196.337,317.181) 196.415,317.103 196.648,317.336 ccw(c196.57,317.414) 196.648,317.492 196.499,317.641 196.285,317.855 cw(c196.363,317.932) 196.285,318.01 196.518,318.243 cw(c196.596,318.165) 196.674,318.243 196.887,318.03 197.036,317.88 ccw(c197.114,317.958) 197.192,317.88 197.425,318.113 ccw(c197.347,318.191) 197.425,318.269 197.276,318.418 197.062,318.632 cw(c197.14,318.709) 197.062,318.787 197.295,319.02 cw(c197.373,318.942) 197.451,319.02 197.664,318.807 197.813,318.657 ccw(c197.891,318.735) 197.969,318.657 198.202,318.89 ccw(c198.124,318.968) 198.202,319.046 198.053,319.195 197.839,319.409 cw(c197.917,319.486) 197.839,319.564 198.072,319.797 cw(c198.15,319.719) 198.228,319.797 198.441,319.584 198.59,319.434 ccw(c198.668,319.512) 198.746,319.434 198.979,319.667 ccw(c198.901,319.745) 198.979,319.823 198.83,319.972 198.616,320.185 cw(c198.694,320.263) 198.616,320.341 198.849,320.574 cw(c198.927,320.496) 199.005,320.574 199.218,320.361 199.367,320.211 ccw(c199.445,320.289) 199.523,320.211 199.756,320.444 ccw(c199.678,320.522) 199.756,320.6 199.607,320.749 199.393,320.962 cw(c199.471,321.04) 199.393,321.118 199.626,321.351 cw(c199.704,321.273) 199.782,321.351 199.995,321.138 200.144,320.988 ccw(c200.222,321.066) 200.3,320.988 200.533,321.221 ccw(c200.455,321.299) 200.533,321.377 200.384,321.526 200.17,321.739 cw(c200.248,321.817) 200.17,321.895 200.403,322.128 cw(c200.481,322.05) 200.559,322.128 200.694,321.992 ccw(c200.772,322.07) 200.85,321.992 201.136,322.278 201.46,322.603 201.46,322.877 cw(c201.46,322.967) 201.37,322.967 201.37,323.337 cw(c201.46,323.337) 201.46,323.427 201.692,323.427 ccw(c201.692,323.537) 201.802,323.537 201.802,323.866 ccw(c201.692,323.866) 201.692,323.976 201.57,323.976 cw(c201.57,324.086) 201.46,324.086 201.46,326.643 201.46,329.457 v3(200.853,330.064)
DDR4_DQ14: U1.AG25 U8.D3 | length 34.1
  L1 w0.116: U1.AG25@188.397,312.539 188.403,312.539 188.9,313.036 v5(188.9,313.068) ; v3(204.853,330.864) U8.D3@205.257,330.46
  L12 (Sign) w0.092: v5(188.9,313.068) 188.359,312.527 188.359,311.737 189.631,310.465 192.16,310.465 196.554,314.858 197.279,314.858 205.811,323.391 205.811,327.506 205.245,328.072 205.245,330.472 v3(204.853,330.864)
DDR4_DQ15: U1.AH26 U8.D4 | length 32
  L1 w0.116: U1.AH26@189.397,313.539 v5(189.884,314.027) ; v3(201.653,330.864) U8.D4@202.057,330.46
  L12 (Sign) w0.092: v5(189.884,314.027) 189.884,315.174 197.57,322.859 197.878,323.167 ccw(c197.8,323.245) 197.878,323.322 197.67,323.53 cw(c197.748,323.607) 197.67,323.685 197.903,323.918 cw(c197.981,323.841) 198.059,323.918 198.344,323.633 198.629,323.348 ccw(c198.707,323.426) 198.784,323.348 199.017,323.581 ccw(c198.94,323.659) 199.017,323.737 198.732,324.022 198.447,324.307 cw(c198.525,324.384) 198.447,324.462 198.68,324.695 cw(c198.758,324.618) 198.836,324.695 199.121,324.41 199.406,324.125 ccw(c199.484,324.203) 199.561,324.125 199.794,324.358 ccw(c199.717,324.436) 199.794,324.513 199.587,324.721 cw(c199.665,324.799) 199.587,324.876 199.704,324.993 199.704,325.166 cw(c199.736,325.166) 199.736,325.199 200.106,325.199 ccw(c200.106,325.309) 200.216,325.309 200.216,325.638 ccw(c200.106,325.638) 200.106,325.748 199.704,325.748 199.22,325.748 cw(c199.22,325.858) 199.11,325.858 199.11,326.188 cw(c199.22,326.188) 199.22,326.298 199.704,326.298 200.106,326.298 ccw(c200.106,326.408) 200.216,326.408 200.216,326.737 ccw(c200.106,326.737) 200.106,326.847 199.704,326.847 199.22,326.847 cw(c199.22,326.957) 199.11,326.957 199.11,327.287 cw(c199.22,327.287) 199.22,327.397 199.704,327.397 200.106,327.397 ccw(c200.106,327.506) 200.216,327.506 200.216,327.836 ccw(c200.106,327.836) 200.106,327.946 199.813,327.946 cw(c199.813,328.056) 199.704,328.056 199.704,328.221 200.207,328.724 200.207,330.233 200.838,330.864 v3(201.653,330.864)
DDR4_DQ16: U1.AD22 U10.G2 | length 41.3
  L1 w0.116: v5(184.909,309.052) U1.AD22@185.397,309.539 ; v3(194.193,332.457) U10.G2@194.597,332.86
  L12 (Sign) w0.092: v5(184.909,309.052) 184.617,309.344 183.735,309.344 183.013,310.066 183.013,322.87 186.169,326.026 186.169,327.624 186.993,328.447 187.173,328.447 ccw(c187.173,328.743) 187.469,328.743 187.469,329.334 cw(c187.618,329.334) 187.618,329.484 187.621,329.484 ccw(c187.621,329.633) 187.77,329.633 187.77,329.833 ccw(c187.621,329.833) 187.621,329.982 187.469,329.982 187.317,329.982 cw(c187.317,330.132) 187.167,330.132 187.167,330.331 cw(c187.317,330.331) 187.317,330.481 187.469,330.481 187.621,330.481 ccw(c187.621,330.63) 187.77,330.63 187.77,330.83 ccw(c187.621,330.83) 187.621,330.979 187.618,330.979 cw(c187.618,331.129) 187.469,331.129 187.469,331.229 cw(c187.621,331.229) 187.621,331.381 187.897,331.381 cw(c187.897,331.179) 188.098,331.179 188.098,330.098 ccw(c188.48,330.098) 188.48,329.717 188.789,329.717 190.597,331.525 190.597,331.767 190.966,332.136 191.186,332.136 191.27,332.136 191.69,332.136 ccw(c191.69,332.316) 191.87,332.316 191.87,333.26 cw(c192.05,333.26) 192.05,333.44 192.29,333.44 cw(c192.29,333.26) 192.47,333.26 192.47,332.136 192.47,331.511 ccw(c192.65,331.511) 192.65,331.331 192.89,331.331 ccw(c192.89,331.511) 193.07,331.511 193.07,331.956 cw(c193.25,331.956) 193.25,332.136 193.37,332.136 193.872,332.136 v3(194.193,332.457)
DDR4_DQ17: U1.AE22 U10.F4 | length 40.2
  L1 w0.116: v5(185.909,309.052) U1.AE22@186.397,309.539 ; U10.F4@190.597,332.06 v3(191,331.657)
  L12 (Sign) w0.092: v5(185.909,309.052) 186.095,309.238 184.856,310.477 183.789,310.477 183.397,310.869 183.397,321.424 189.714,327.741 189.714,328.59 189.714,328.879 ccw(c189.64,328.879) 189.64,328.953 188.047,328.953 cw(c188.047,329.103) 187.897,329.103 187.897,329.302 cw(c188.047,329.302) 188.047,329.452 189.564,329.452 ccw(c189.564,329.601) 189.714,329.601 189.714,329.701 189.714,330.125 190.805,331.216 191.249,331.216 192.024,330.441 194.404,330.441 ccw(c194.404,330.581) 194.543,330.581 194.543,330.955 ccw(c194.409,330.955) 194.409,331.089 192.497,331.089 cw(c192.497,331.457) 192.129,331.457 ccw(c191.929,331.457) 191.929,331.657 v3(191,331.657)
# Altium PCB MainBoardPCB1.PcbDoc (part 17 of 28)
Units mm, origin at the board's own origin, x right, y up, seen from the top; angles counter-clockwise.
Board outline 258.95 x 308.86 mm, 16 copper layers (L1, L2 (GND), L3 (Sign), L4 (GND), L5 (Sign), L6 (PWR/GND), L7(PWR/GND), L8 (Plane_GND), L9 (PWR/GND), L10 (PWR/GND), L11 (PWR/GND), L12 (Sign), L13 (GND), L14 (Sign), L15 (GND), L16), stack 2.502 mm thick; 2397 components, 1744 nets, 8397 pads, 4112 vias.
Unrouted connection lines stored in the file: 3547.

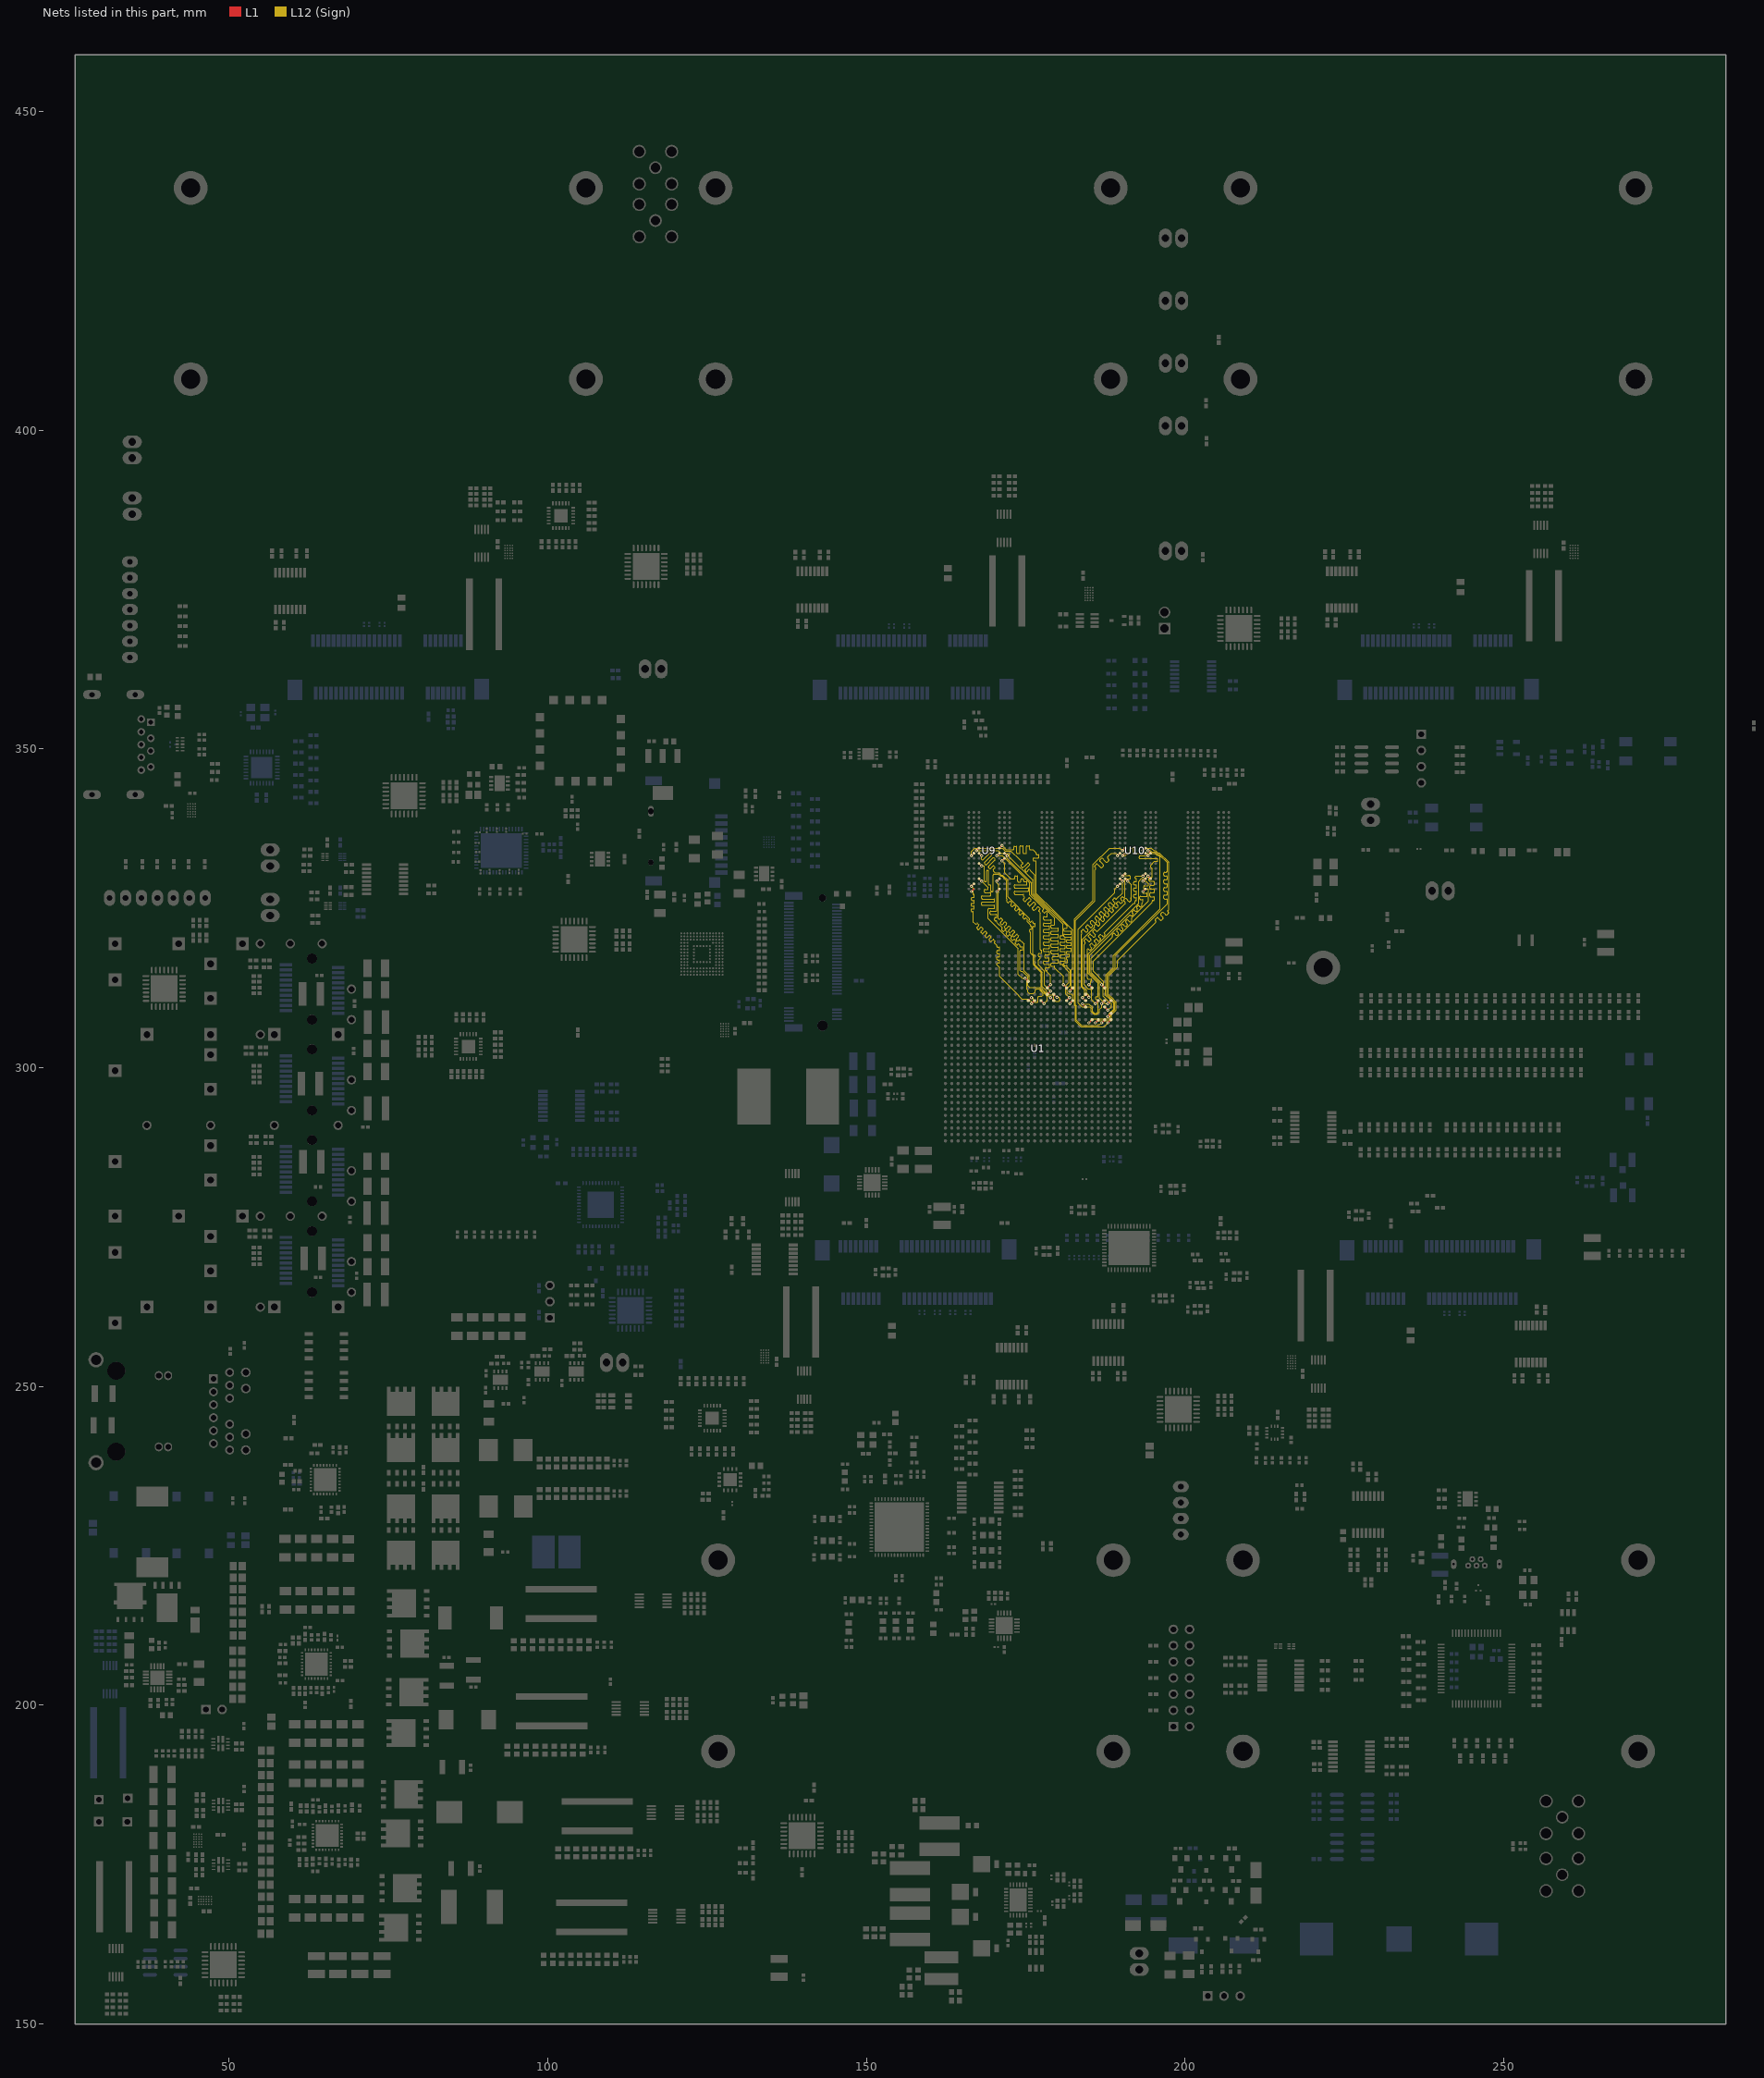
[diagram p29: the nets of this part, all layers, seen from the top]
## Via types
v1: diameter 0.5, hole 0.2, L1 to L16, tented both sides, 1457 vias
v2: diameter 0.35/0/0.35 (per signal layer), hole 0.127, L1 to L3 (Sign), tented both sides, 479 vias
v3: diameter 0.5/0.35/0.35/0.35/0.35/0.35/0.35/0.35/0.35/0.35/0.35/0.35/0.35/0.35/0.35/0.5 (per signal layer), hole 0.15, L1 to L16, tented both sides, 453 vias
v4: diameter 0.5, hole 0.2, L1 to L16, 451 vias
v5: diameter 0.5/0.35/0.35/0.35/0.35/0.35/0.35/0.35/0.35/0.35/0.35/0.35/0.35/0.35/0.35/0.5 (per signal layer), hole 0.2, L1 to L16, tented both sides, 373 vias
v6: diameter 0.8, hole 0.4, L1 to L16, tented both sides, 168 vias
v7: diameter 0.35/0/0.35 (per signal layer), hole 0.127, L1 to L3 (Sign), 138 vias
v8: diameter 2.54, hole 1.02, L1 to L16, 113 vias
v9: diameter 0.5/0/0.5 (per signal layer), hole 0.2, L14 (Sign) to L16, tented both sides, 102 vias
v10: diameter 1.4, hole 0.5, L1 to L16, tented both sides, 80 vias
v11: diameter 0.5, hole 0.2, L3 (Sign) to L6 (PWR/GND), tented both sides, 54 vias
v12: diameter 0.35, hole 0.127, L1 to L2 (GND), tented both sides, 47 vias
v13: diameter 0.4, hole 0.2, L1 to L16, tented both sides, 46 vias
v14: diameter 0.35, hole 0.127, L1 to L16, tented both sides, 16 vias
v15: diameter 0.25, hole 0.2, L1 to L16, 16 vias
v16: diameter 0.5, hole 0.2, L11 (PWR/GND) to L14 (Sign), tented both sides, 16 vias
v17: diameter 0.4, hole 0.2, L1 to L16, 16 vias
v18: diameter 0.3, hole 0.2, L1 to L16, 15 vias
v19: diameter 0.45, hole 0.15, L1 to L16, 12 vias
v20: diameter 0.5/0.35/0.35/0.35/0.35/0.35/0.35/0.35/0.35/0.35/0.35/0.35/0.35/0.35/0.35/0.45 (per signal layer), hole 0.15, L1 to L16, tented both sides, 10 vias
v21: diameter 0.2/0/0.2 (per signal layer), hole 0.1, L1 to L3 (Sign), tented both sides, 9 vias
v22: diameter 0.3, hole 0.127, L14 (Sign) to L16, tented both sides, 8 vias
v23: diameter 0.4, hole 0.1, L1 to L16, 7 vias
v24: diameter 1.15, hole 1.15, L1 to L16, 5 vias
v25: diameter 1.65, hole 1.65, L1 to L16, 5 vias
v26: diameter 0.2, hole 0.1, L1 to L16, 4 vias
v27: diameter 0.4, hole 0.15, L1 to L16, 2 vias
v28: diameter 0.5/0.35/0.35/0.35/0.35/0.35/0.35/0.35/0.35/0.35/0.35/0.35/0.35/0.35/0.35/0.5 (per signal layer), hole 0.15, L1 to L16, 2 vias
v29: diameter 0.35, hole 0.127, L3 (Sign) to L6 (PWR/GND), tented both sides, 2 vias
v30: diameter 0.3, hole 0.127, L15 (GND) to L16, tented both sides, 1 vias
v31: diameter 0.35, hole 0.127, L1 to L2 (GND), 1 vias
v32: diameter 0.5/0.35/0.35/0.35/0.35/0.35/0.35/0.35/0.35/0.35/0.35/0.35/0.35/0.35/0.35/0.5 (per signal layer), hole 0.2, L1 to L16, 1 vias
v33: diameter 0.35/0.35/0.35 (per signal layer), hole 0.127, L1 to L3 (Sign), tented both sides, 1 vias
v34: diameter 0.45/0/0.45 (per signal layer), hole 0.15, L1 to L3 (Sign), tented both sides, 1 vias
v35: diameter 0.45/0/0.45 (per signal layer), hole 0.2, L14 (Sign) to L16, tented both sides, 1 vias

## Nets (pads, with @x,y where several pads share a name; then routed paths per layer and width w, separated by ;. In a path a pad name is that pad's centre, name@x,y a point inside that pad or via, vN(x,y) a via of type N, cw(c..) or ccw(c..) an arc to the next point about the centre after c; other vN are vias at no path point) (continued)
DDR4_DQ18: U1.AF22 U10.H3 | length 39.4
  L1 w0.116: U1.AF22@187.397,309.539 v5(187.884,309.052) ; U10.H3@193.797,333.66 v3(194.2,333.257)
  L12 (Sign) w0.092: v5(187.884,309.052) 187.906,309.052 188.428,309.573 188.428,309.987 188.042,310.373 188.013,310.373 187.165,311.221 187.165,312.828 187.23,312.894 187.23,313.51 185.622,315.118 185.622,316.741 194.831,325.95 194.831,326.1 cw(c194.981,326.1) 194.981,326.25 195.031,326.25 ccw(c195.031,326.4) 195.181,326.4 195.181,326.7 ccw(c195.031,326.7) 195.031,326.85 194.831,326.85 194.605,326.85 cw(c194.605,327) 194.455,327 194.455,327.3 cw(c194.605,327.3) 194.605,327.45 194.831,327.45 195.031,327.45 ccw(c195.031,327.601) 195.181,327.601 195.181,327.901 ccw(c195.031,327.901) 195.031,328.051 194.831,328.051 194.605,328.051 cw(c194.605,328.201) 194.455,328.201 194.455,328.501 cw(c194.605,328.501) 194.605,328.651 194.831,328.651 195.031,328.651 ccw(c195.031,328.801) 195.181,328.801 195.181,329.101 ccw(c195.031,329.101) 195.031,329.251 194.831,329.251 194.51,329.251 cw(c194.51,329.401) 194.36,329.401 194.36,329.701 cw(c194.51,329.701) 194.51,329.851 194.685,329.851 ccw(c194.685,329.997) 194.831,329.997 194.831,331.219 194.591,331.459 194.591,331.753 195.229,332.39 195.598,332.39 ccw(c195.598,332.524) 195.732,332.524 195.732,332.699 ccw(c195.616,332.699) 195.616,332.816 192.918,332.816 cw(c192.918,332.947) 192.788,332.947 192.788,333.081 cw(c192.955,333.081) 192.955,333.248 194.2,333.248 v3(194.2,333.257)
DDR4_DQ19: U1.AG21 U10.H4 | length 38.3
  L1 w0.116: v5(187.909,308.052) U1.AG21@188.397,308.539 ; v3(190.193,333.257) U10.H4@190.597,333.66
  L12 (Sign) w0.092: v5(187.909,308.052) 188.038,308.181 188.038,308.211 188.094,308.266 188.094,308.513 188.812,309.231 188.812,310.147 188.201,310.757 188.172,310.757 187.549,311.38 187.549,312.669 187.614,312.735 187.614,314.572 188.785,315.743 188.785,317.598 196.098,324.911 196.098,333.027 195.793,333.332 195.535,333.332 195.206,333.66 193.332,333.66 192.102,333.66 cw(c192.102,333.81) 191.952,333.81 191.952,334.282 ccw(c191.802,334.282) 191.802,334.432 191.502,334.432 ccw(c191.502,334.282) 191.352,334.282 191.352,333.81 cw(c191.202,333.81) 191.202,333.66 191.052,333.66 190.649,333.257 v3(190.193,333.257)
DDR4_DQ20: U1.AD20 U10.H2 | length 41.2
  L1 w0.116: v1(184.909,307.052) U1.AD20@185.397,307.539 ; v3(194.193,334.064) U10.H2@194.597,333.66
  L12 (Sign) w0.092: v1(184.909,307.052) 185.513,307.656 188.098,307.656 188.254,307.812 188.254,308.155 188.256,308.155 188.286,308.185 188.286,308.434 189.004,309.151 189.004,310.226 188.281,310.949 188.251,310.949 187.741,311.459 187.741,312.59 187.806,312.655 187.806,314.492 189.04,315.725 189.04,317.58 197.208,325.749 197.208,325.831 197.208,326.337 ccw(c197.058,326.337) 197.058,326.487 196.817,326.487 cw(c196.817,326.637) 196.667,326.637 196.667,326.937 cw(c196.817,326.937) 196.817,327.087 197.058,327.087 ccw(c197.058,327.237) 197.208,327.237 197.208,327.537 ccw(c197.058,327.537) 197.058,327.687 196.817,327.687 cw(c196.817,327.837) 196.667,327.837 196.667,328.137 cw(c196.817,328.137) 196.817,328.287 197.058,328.287 ccw(c197.058,328.437) 197.208,328.437 197.208,328.737 ccw(c197.058,328.737) 197.058,328.887 196.817,328.887 cw(c196.817,329.038) 196.667,329.038 196.667,329.338 cw(c196.817,329.338) 196.817,329.488 197.058,329.488 ccw(c197.058,329.638) 197.208,329.638 197.208,329.938 ccw(c197.058,329.938) 197.058,330.088 196.817,330.088 cw(c196.817,330.238) 196.667,330.238 196.667,330.538 cw(c196.817,330.538) 196.817,330.688 197.058,330.688 ccw(c197.058,330.838) 197.208,330.838 197.208,331.288 197.208,331.888 197.208,332.189 195.873,333.524 195.629,333.524 195.3,333.852 194.746,333.852 194.534,334.064 v3(194.193,334.064)
DDR4_DQ21: U1.AF20 U10.H5 | length 39.1
  L1 w0.116: v5(186.909,307.052) U1.AF20@187.397,307.539 ; v3(189.393,333.257) U10.H5@189.797,333.66
  L12 (Sign) w0.092: v5(186.909,307.052) 186.656,306.799 186.385,306.799 186.24,306.654 183.747,306.654 182.982,307.42 182.982,309.705 182.821,309.866 182.821,323.125 185.852,326.156 185.852,331.058 185.958,331.164 ccw(c185.852,331.27) 185.958,331.376 185.83,331.504 cw(c185.936,331.61) 185.83,331.716 186.042,331.928 cw(c186.148,331.822) 186.254,331.928 186.488,331.694 186.762,331.421 ccw(c186.868,331.527) 186.974,331.421 187.186,331.633 ccw(c187.08,331.739) 187.186,331.845 186.913,332.119 186.639,332.392 cw(c186.746,332.498) 186.639,332.604 186.852,332.816 cw(c186.958,332.71) 187.064,332.816 187.337,332.543 187.611,332.27 ccw(c187.717,332.376) 187.823,332.27 188.035,332.482 ccw(c187.929,332.588) 188.035,332.694 187.868,332.861 cw(c187.974,332.967) 187.868,333.073 188.058,333.264 188.455,333.66 189.195,333.66 189.393,333.462 v3(189.393,333.257)
DDR4_DQ22: U1.AE20 U10.J3 | length 41
  L1 w0.116: v5(185.909,307.052) U1.AE20@186.397,307.539 ; v3(193.393,334.057) U10.J3@193.797,334.46
  L12 (Sign) w0.092: v5(185.909,307.052) 186.261,307.404 188.117,307.404 188.478,307.765 188.478,308.354 189.196,309.072 189.196,310.306 188.361,311.141 188.331,311.141 187.933,311.539 187.933,312.51 187.998,312.576 187.998,314.412 189.397,315.811 189.397,316.791 193.735,321.129 195.406,322.799 ccw(c195.299,322.905) 195.406,323.011 195.343,323.074 cw(c195.449,323.18) 195.343,323.286 195.555,323.498 cw(c195.661,323.392) 195.767,323.498 195.936,323.33 196.105,323.161 ccw(c196.211,323.267) 196.317,323.161 196.529,323.373 ccw(c196.423,323.479) 196.529,323.586 196.36,323.754 196.192,323.923 cw(c196.298,324.029) 196.192,324.135 196.404,324.347 cw(c196.51,324.241) 196.616,324.347 196.785,324.179 196.954,324.01 ccw(c197.06,324.116) 197.166,324.01 197.378,324.222 ccw(c197.272,324.328) 197.378,324.434 197.315,324.497 cw(c197.422,324.603) 197.315,324.709 197.421,324.815 197.421,332.246 195.952,333.716 195.708,333.716 195.375,334.049 195.122,334.049 194.711,334.46 193.797,334.46 v3(193.393,334.057)
DDR4_DQ23: U1.AG20 U10.J4 | length 38.7
  L1 w0.116: v5(187.909,307.052) U1.AG20@188.397,307.539 ; v3(190.193,334.057) U10.J4@190.597,334.46
  L12 (Sign) w0.092: v5(187.909,307.052) 187.308,306.451 183.642,306.451 183.23,306.863 183.23,306.899 182.79,307.34 182.79,309.626 182.629,309.786 182.629,323.307 185.59,326.267 185.59,331.501 185.587,331.503 185.587,331.717 185.59,331.72 185.59,331.906 188.144,334.46 189.789,334.46 v3(190.193,334.057)
DDR4_DQ24: U1.AG23 U10.A3 | length 27.3
  L1 w0.116: v5(187.909,310.052) U1.AG23@188.397,310.539 ; v3(193.393,327.657) U10.A3@193.797,328.06
  L12 (Sign) w0.092: v5(187.909,310.052) 187.431,310.052 186.578,310.905 186.578,313.348 185.046,314.88 185.046,317.652 191.062,323.669 191.295,323.902 cw(c191.368,323.829) 191.44,323.902 ccw(c191.58,324.043) 191.721,323.902 191.792,323.973 ccw(c191.651,324.114) 191.792,324.255 191.72,324.326 cw(c191.817,324.423) 191.72,324.519 191.88,324.679 cw(c191.976,324.583) 192.073,324.679 192.145,324.607 ccw(c192.286,324.748) 192.427,324.607 192.497,324.678 ccw(c192.356,324.819) 192.497,324.96 192.425,325.032 cw(c192.522,325.128) 192.425,325.224 192.585,325.384 cw(c192.681,325.288) 192.778,325.384 192.85,325.312 ccw(c192.991,325.453) 193.132,325.312 193.203,325.382 ccw(c193.062,325.523) 193.203,325.664 cw(c193.275,325.737) 193.203,325.809 193.307,325.913 193.393,325.999 193.393,326.263 193.393,326.311 ccw(c193.293,326.311) 193.293,326.41 193.012,326.41 cw(c193.012,326.51) 192.912,326.51 192.912,326.809 cw(c193.012,326.809) 193.012,326.909 193.393,326.909 193.955,326.909 ccw(c193.955,327.009) 194.055,327.009 194.055,327.308 ccw(c193.955,327.308) 193.955,327.408 193.493,327.408 cw(c193.493,327.507) 193.393,327.507 v3(193.393,327.657)
DDR4_DQ25: U1.AF23 U10.B5 | length 28.1
  L1 w0.116: v5(186.909,310.052) U1.AF23@187.397,310.539 ; v3(189.393,328.457) U10.B5@189.797,328.86
  L12 (Sign) w0.092: v5(186.909,310.052) 186.909,309.481 186.588,309.16 186.588,308.731 186.233,308.375 185.675,308.375 185.242,308.808 185.242,309.33 185.033,309.539 183.837,309.539 183.205,310.171 183.205,321.724 188.981,327.5 188.981,328.045 v3(189.393,328.457)
DDR4_DQ26: U1.AF25 U10.C3 | length 27.7
  L1 w0.116: v5(186.909,313.027) U1.AF25@187.397,312.539 ; v3(193.393,329.257) U10.C3@193.797,329.66
  L12 (Sign) w0.092: v5(186.909,313.027) 186.909,313.287 185.238,314.959 185.238,317.146 188.243,320.151 188.606,320.514 ccw(c188.534,320.587) 188.606,320.659 188.609,320.656 ; 188.61,320.655 cw(c188.751,320.796) 188.61,320.937 188.68,321.008 cw(c188.821,320.867) 188.962,321.008 189.031,320.939 189.145,320.825 ccw(c189.286,320.966) 189.427,320.825 189.497,320.895 ccw(c189.356,321.036) 189.497,321.177 189.383,321.292 189.315,321.36 cw(c189.456,321.501) 189.315,321.642 189.385,321.713 cw(c189.526,321.572) 189.667,321.713 189.736,321.644 189.85,321.53 ccw(c189.991,321.671) 190.132,321.53 190.203,321.6 ccw(c190.062,321.742) 190.203,321.883 190.088,321.997 190.02,322.065 cw(c190.161,322.206) 190.02,322.347 190.09,322.418 cw(c190.231,322.277) 190.372,322.418 190.441,322.349 190.555,322.235 ccw(c190.696,322.376) 190.837,322.235 190.908,322.306 ccw(c190.767,322.447) 190.908,322.588 190.794,322.702 190.725,322.771 cw(c190.866,322.912) 190.725,323.053 190.795,323.123 cw(c190.936,322.982) 191.077,323.123 191.146,323.054 191.264,322.937 ccw(c191.405,323.078) 191.546,322.937 191.616,323.007 ccw(c191.475,323.148) 191.616,323.289 cw(c191.734,323.407) 191.616,323.525 191.675,323.583 194.246,326.155 194.246,327.8 194.246,327.949 ccw(c194.147,327.949) 194.147,328.049 193.612,328.049 cw(c193.612,328.149) 193.512,328.149 193.512,328.448 cw(c193.612,328.448) 193.612,328.548 194.147,328.548 ccw(c194.147,328.647) 194.246,328.647 194.246,328.879 193.84,329.286 193.422,329.286 v3(193.393,329.257)
DDR4_DQ27: U1.AE23 U10.C4 | length 29.6
  L1 w0.116: v5(185.909,310.052) U1.AE23@186.397,310.539 ; U10.C4@190.597,329.66 v3(191,329.257)
  L12 (Sign) w0.092: v5(185.909,310.052) 185.331,310.63 185.331,312.165 185.073,312.423 184.788,312.423 184.204,313.006 184.204,319.358 184.239,319.392 184.309,319.463 ccw(c184.204,319.569) 184.309,319.674 184.158,319.826 cw(c184.264,319.931) 184.158,320.037 184.299,320.178 cw(c184.405,320.072) 184.511,320.178 184.768,319.921 184.857,319.832 ccw(c184.963,319.938) 185.069,319.832 185.21,319.973 ccw(c185.104,320.079) 185.21,320.184 185.12,320.274 184.838,320.556 cw(c184.943,320.662) 184.838,320.768 184.979,320.909 cw(c185.084,320.803) 185.19,320.909 185.473,320.626 185.562,320.537 ccw(c185.668,320.643) 185.774,320.537 185.915,320.678 ccw(c185.809,320.784) 185.915,320.89 185.825,320.979 185.543,321.262 cw(c185.649,321.367) 185.543,321.473 185.684,321.614 cw(c185.79,321.508) 185.895,321.614 186.072,321.437 ccw(c186.178,321.543) 186.284,321.437 186.938,322.091 190.525,325.679 190.592,325.746 ccw(c190.487,325.851) 190.592,325.957 190.405,326.145 cw(c190.511,326.251) 190.405,326.356 190.546,326.497 cw(c190.652,326.392) 190.757,326.497 191.051,326.204 191.183,326.072 ccw(c191.289,326.177) 191.395,326.072 191.536,326.213 ccw(c191.43,326.318) 191.536,326.424 191.509,326.451 cw(c191.615,326.557) 191.509,326.662 191.579,326.733 191.579,328.677 v3(191,329.257)
DDR4_DQ28: U1.AC22 U10.C2 | length 31.5
  L1 w0.116: v1(183.909,310.027) U1.AC22@184.397,309.539 ; v3(194.193,330.064) U10.C2@194.597,329.66
  L12 (Sign) w0.092: v1(183.909,310.027) 184.909,310.027 185.481,309.455 185.481,308.84 185.754,308.567 186.127,308.567 186.386,308.826 186.386,310.236 186.386,310.578 ccw(c186.286,310.578) 186.286,310.678 186.128,310.678 cw(c186.128,310.778) 186.028,310.778 186.028,311.077 cw(c186.128,311.077) 186.128,311.177 186.286,311.177 ccw(c186.286,311.277) 186.386,311.277 186.386,311.675 186.386,311.925 186.386,313.268 184.854,314.8 184.854,317.924 192.72,325.791 192.72,329.25 193.16,329.69 193.819,329.69 v3(194.193,330.064)
DDR4_DQ29: U1.AC23 U10.C5 | length 31.3
  L1 w0.116: v1(183.909,311.027) U1.AC23@184.397,310.539 ; U10.C5@189.797,329.66 v3(190.2,329.257)
  L12 (Sign) w0.092: v1(183.909,311.027) 184.266,311.383 184.266,312.156 183.72,312.702 183.72,320.943 183.79,321.014 ccw(c183.684,321.119) 183.79,321.225 183.746,321.269 cw(c183.852,321.375) 183.746,321.481 183.887,321.622 cw(c183.993,321.516) 184.099,321.622 184.249,321.472 184.398,321.322 ccw(c184.504,321.428) 184.61,321.322 184.751,321.463 ccw(c184.645,321.569) 184.751,321.675 184.601,321.825 184.451,321.974 cw(c184.557,322.08) 184.451,322.186 184.592,322.327 cw(c184.698,322.221) 184.804,322.327 184.954,322.177 185.103,322.028 ccw(c185.209,322.133) 185.315,322.028 185.456,322.169 ccw(c185.35,322.274) 185.456,322.38 185.306,322.53 185.157,322.679 cw(c185.262,322.785) 185.157,322.891 185.298,323.032 cw(c185.403,322.926) 185.509,323.032 185.659,322.882 185.808,322.733 ccw(c185.914,322.838) 186.02,322.733 186.161,322.874 ccw(c186.055,322.979) 186.161,323.085 186.011,323.235 185.862,323.385 cw(c185.967,323.49) 185.862,323.596 186.003,323.737 cw(c186.108,323.631) 186.214,323.737 186.364,323.587 186.514,323.438 ccw(c186.619,323.544) 186.725,323.438 186.866,323.579 ccw(c186.76,323.685) 186.866,323.79 186.716,323.94 186.567,324.09 cw(c186.673,324.195) 186.567,324.301 186.708,324.442 cw(c186.814,324.336) 186.919,324.442 187.069,324.293 187.219,324.143 ccw(c187.324,324.249) 187.43,324.143 187.571,324.284 ccw(c187.465,324.39) 187.571,324.495 187.422,324.645 187.272,324.795 cw(c187.378,324.901) 187.272,325.006 187.413,325.147 cw(c187.519,325.042) 187.625,325.147 187.774,324.998 187.924,324.848 ccw(c188.03,324.954) 188.135,324.848 188.276,324.989 ccw(c188.171,325.095) 188.276,325.201 188.127,325.35 187.977,325.5 cw(c188.083,325.606) 187.977,325.711 188.118,325.852 cw(c188.224,325.747) 188.33,325.852 188.479,325.703 188.629,325.553 ccw(c188.735,325.659) 188.84,325.553 188.982,325.694 ccw(c188.876,325.8) 188.982,325.906 188.832,326.055 188.682,326.205 cw(c188.788,326.311) 188.682,326.417 188.823,326.558 cw(c188.929,326.452) 189.035,326.558 189.079,326.514 ccw(c189.184,326.619) 189.29,326.514 190.2,327.424 190.2,327.469 v3(190.2,329.257)
DDR4_DQ30: U1.AD25 U10.D3 | length 29.3
  L1 w0.116: v5(184.909,313.027) U1.AD25@185.397,312.539 ; v3(193.393,330.057) U10.D3@193.797,330.46
  L12 (Sign) w0.092: v5(184.909,313.027) 184.998,313.027 ccw(c184.998,313.195) 185.166,313.195 185.166,313.521 cw(c185.255,313.521) 185.255,313.61 ccw(c185.255,313.711) 185.356,313.711 185.356,313.826 ccw(c185.272,313.826) 185.272,313.911 184.831,313.911 cw(c184.831,314.084) 184.658,314.084 184.658,318.524 184.683,318.549 184.725,318.591 cw(c184.795,318.52) 184.866,318.591 184.976,318.48 ccw(c185.047,318.551) 185.117,318.48 185.329,318.692 ccw(c185.258,318.762) 185.329,318.833 185.148,319.014 185.052,319.11 cw(c185.122,319.18) 185.052,319.251 185.263,319.462 cw(c185.334,319.392) 185.404,319.462 185.5,319.366 185.681,319.185 ccw(c185.752,319.256) 185.822,319.185 186.034,319.397 ccw(c185.963,319.467) 186.034,319.538 185.853,319.719 185.757,319.815 cw(c185.827,319.885) 185.757,319.956 185.968,320.167 cw(c186.039,320.097) 186.109,320.167 186.205,320.071 186.386,319.89 ccw(c186.457,319.961) 186.527,319.89 186.739,320.102 ccw(c186.668,320.172) 186.739,320.243 186.558,320.424 186.462,320.52 cw(c186.532,320.59) 186.462,320.661 186.673,320.873 cw(c186.744,320.802) 186.814,320.873 186.91,320.776 187.091,320.596 ccw(c187.162,320.666) 187.232,320.596 187.444,320.807 ccw(c187.373,320.878) 187.444,320.948 187.334,321.059 cw(c187.404,321.129) 187.334,321.2 187.439,321.305 191.955,325.821 192.174,325.821 192.176,325.823 192.176,326.107 cw(c192.276,326.107) 192.276,326.206 192.279,326.206 ccw(c192.279,326.306) 192.379,326.306 192.379,326.605 ccw(c192.279,326.605) 192.279,326.705 192.176,326.705 192.072,326.705 cw(c192.072,326.805) 191.973,326.805 191.973,327.104 cw(c192.072,327.104) 192.072,327.204 192.176,327.204 192.279,327.204 ccw(c192.279,327.303) 192.379,327.303 192.379,327.602 ccw(c192.279,327.602) 192.279,327.702 192.176,327.702 192.072,327.702 cw(c192.072,327.802) 191.973,327.802 191.973,328.101 cw(c192.072,328.101) 192.072,328.201 192.176,328.201 192.279,328.201 ccw(c192.279,328.3) 192.379,328.3 192.379,328.6 ccw(c192.279,328.6) 192.279,328.699 192.176,328.699 192.072,328.699 cw(c192.072,328.799) 191.973,328.799 191.973,329.098 cw(c192.072,329.098) 192.072,329.198 192.176,329.198 192.279,329.198 ccw(c192.279,329.298) 192.379,329.298 192.379,329.597 ccw(c192.279,329.597) 192.279,329.697 192.276,329.697 cw(c192.276,329.796) 192.176,329.796 192.176,329.946 192.287,330.057 v3(193.393,330.057)
DDR4_DQ31: U1.AC24 U10.D4 | length 30.7
  L1 w0.116: U1.AC24@184.397,311.539 v1(184.884,311.052) ; v3(190.193,330.057) U10.D4@190.597,330.46
  L12 (Sign) w0.092: v1(184.884,311.052) 184.884,311.372 184.519,311.737 184.519,312.175 183.912,312.782 183.912,320.157 184.849,321.094 185.762,322.008 ccw(c185.712,322.059) 185.762,322.11 185.763,322.109 cw(c185.869,322.214) 185.763,322.32 185.905,322.461 cw(c186.01,322.355) 186.116,322.461 186.166,322.411 186.279,322.299 ccw(c186.384,322.405) 186.49,322.299 186.631,322.44 ccw(c186.525,322.546) 186.631,322.651 186.518,322.764 186.469,322.814 cw(c186.574,322.92) 186.469,323.025 186.61,323.166 cw(c186.715,323.061) 186.821,323.166 186.871,323.117 186.984,323.004 ccw(c187.089,323.11) 187.195,323.004 187.336,323.145 ccw(c187.23,323.251) 187.336,323.356 187.224,323.469 187.174,323.519 cw(c187.28,323.625) 187.174,323.73 187.315,323.872 cw(c187.421,323.766) 187.526,323.872 187.576,323.822 187.689,323.709 ccw(c187.795,323.815) 187.9,323.709 188.041,323.85 ccw(c187.936,323.956) 188.041,324.062 187.929,324.174 187.879,324.224 cw(c187.985,324.33) 187.879,324.436 188.02,324.577 cw(c188.126,324.471) 188.231,324.577 188.281,324.527 188.394,324.414 ccw(c188.5,324.52) 188.605,324.414 188.746,324.555 ccw(c188.641,324.661) 188.746,324.767 188.634,324.879 188.584,324.929 cw(c188.69,325.035) 188.584,325.141 188.725,325.282 cw(c188.831,325.176) 188.937,325.282 188.986,325.232 189.099,325.119 ccw(c189.205,325.225) 189.311,325.119 189.452,325.26 ccw(c189.346,325.366) 189.452,325.472 189.339,325.585 189.261,325.662 cw(c189.367,325.768) 189.261,325.874 189.402,326.015 cw(c189.508,325.909) 189.614,326.015 189.691,325.937 189.804,325.824 ccw(c189.91,325.93) 190.016,325.824 190.157,325.965 ccw(c190.051,326.071) 190.157,326.177 190.044,326.29 189.931,326.402 cw(c190.037,326.508) 189.931,326.614 190.072,326.755 cw(c190.178,326.649) 190.284,326.755 190.291,326.748 ccw(c190.397,326.854) 190.502,326.748 190.573,326.818 190.573,329.438 cw(c190.751,329.438) 190.751,329.616 191.3,329.616 ccw(c191.3,329.73) 191.414,329.73 191.414,329.933 ccw(c191.173,329.933) 191.173,330.175 190.311,330.175 ccw(c190.311,330.057) v3(190.193,330.057)
DDR4_DQ32: U1.U24 U9.G2 | length 41.6
  L1 w0.116: v3(171.272,332.457) U9.G2@171.676,332.86 ; U1.U24@178.397,311.539 v1(178.884,312.027)
  L12 (Sign) w0.092: v3(171.272,332.457) 171.704,332.025 171.704,330.594 172.668,329.63 173.152,329.63 173.169,329.63 ccw(c173.169,329.73) 173.268,329.73 173.268,329.987 cw(c173.368,329.987) 173.368,330.087 173.667,330.087 cw(c173.667,329.987) 173.767,329.987 173.767,329.63 173.767,329.273 ccw(c173.867,329.273) 173.867,329.173 174.166,329.173 ccw(c174.166,329.273) 174.266,329.273 174.266,329.53 cw(c174.365,329.53) 174.365,329.63 174.515,329.63 174.69,329.455 174.69,329.305 ccw(c174.79,329.305) 174.79,329.206 175.101,329.206 cw(c175.101,329.106) 175.201,329.106 175.201,328.807 cw(c175.101,328.807) 175.101,328.707 174.69,328.707 173.3,328.707 ccw(c173.3,328.607) 173.2,328.607 173.2,328.308 ccw(c173.3,328.308) 173.3,328.208 174.69,328.208 175.362,328.208 cw(c175.362,328.109) 175.462,328.109 175.462,327.809 cw(c175.362,327.809) 175.362,327.71 174.69,327.71 173.297,327.71 ccw(c173.297,327.61) 173.198,327.61 173.198,327.311 ccw(c173.297,327.311) 173.297,327.211 174.618,327.211 cw(c174.618,327.139) 174.69,327.139 174.69,326.904 174.796,326.798 cw(c174.725,326.728) 174.796,326.657 174.613,326.475 ccw(c174.684,326.405) 174.613,326.334 174.825,326.123 ccw(c174.896,326.193) 174.966,326.123 175.219,326.375 175.472,326.628 cw(c175.542,326.558) 175.613,326.628 175.824,326.417 cw(c175.754,326.346) 175.824,326.276 175.571,326.023 175.319,325.77 ccw(c175.389,325.699) 175.319,325.629 175.53,325.417 ccw(c175.601,325.488) 175.671,325.417 175.924,325.67 176.177,325.923 cw(c176.247,325.852) 176.318,325.923 176.529,325.711 cw(c176.459,325.641) 176.529,325.57 176.276,325.318 176.024,325.065 ccw(c176.094,324.994) 176.024,324.924 176.235,324.712 ccw(c176.306,324.783) 176.376,324.712 176.629,324.965 176.882,325.218 cw(c176.952,325.147) 177.023,325.218 177.234,325.006 cw(c177.164,324.936) 177.234,324.865 177.052,324.683 ccw(c177.123,324.613) 177.052,324.542 177.283,324.311 177.292,324.302 177.292,319.214 177.292,318.541 ccw(c177.392,318.541) 177.392,318.442 177.445,318.442 cw(c177.445,318.342) 177.545,318.342 177.545,318.043 cw(c177.445,318.043) 177.445,317.943 177.292,317.943 177.099,317.943 ccw(c177.099,317.843) 176.999,317.843 176.999,317.544 ccw(c177.099,317.544) 177.099,317.444 177.192,317.444 cw(c177.192,317.345) 177.292,317.345 177.292,317.195 177,316.903 177,316.132 177.978,315.154 177.978,312.933 v1(178.884,312.027)
DDR4_DQ33: U1.V23 U9.F4 | length 40.2
  L1 w0.116: U9.F4@167.676,332.06 v3(168.079,331.657) ; v1(178.909,311.027) U1.V23@179.397,310.539
  L12 (Sign) w0.092: v3(168.079,331.657) 168.415,331.657 cw(c168.415,331.568) 168.504,331.568 168.504,329.324 ccw(c168.618,329.324) 168.618,329.209 168.732,329.209 ccw(c168.732,329.349) 168.872,329.349 168.872,330.848 cw(c168.974,330.848) 168.974,330.949 169.086,330.949 cw(c169.086,330.848) 169.188,330.848 169.188,328.792 ccw(c169.304,328.792) 169.304,328.676 169.398,328.676 cw(c169.398,328.542) 169.532,328.542 169.532,327.79 ccw(c169.675,327.79) 169.675,327.647 169.783,327.647 ccw(c169.783,327.762) 169.897,327.762 169.897,330.26 cw(c170.028,330.26) 170.028,330.39 170.713,330.39 171.032,330.072 171.249,330.072 171.986,329.334 171.986,326.539 172.05,326.476 cw(c171.955,326.381) 172.05,326.286 172.026,326.262 ccw(c172.121,326.167) 172.026,326.072 172.152,325.945 ccw(c172.247,326.04) 172.342,325.945 172.461,326.064 172.472,326.075 cw(c172.567,325.98) 172.662,326.075 172.789,325.948 cw(c172.694,325.853) 172.789,325.758 172.778,325.748 172.653,325.623 ccw(c172.748,325.528) 172.653,325.433 172.78,325.306 ccw(c172.875,325.401) 172.97,325.306 173.095,325.431 173.105,325.442 cw(c173.2,325.347) 173.295,325.442 173.422,325.315 cw(c173.327,325.22) 173.422,325.125 173.411,325.115 173.287,324.99 ccw(c173.382,324.895) 173.287,324.8 173.413,324.673 ccw(c173.508,324.768) 173.603,324.673 173.728,324.798 173.738,324.808 cw(c173.833,324.713) 173.928,324.808 174.055,324.682 cw(c173.96,324.587) 174.055,324.492 174.045,324.481 173.92,324.356 ccw(c174.015,324.261) 173.92,324.167 174.046,324.04 ccw(c174.141,324.135) 174.236,324.04 174.361,324.165 174.372,324.175 cw(c174.467,324.08) 174.562,324.175 174.688,324.049 cw(c174.593,323.954) 174.688,323.859 174.678,323.848 174.553,323.723 ccw(c174.648,323.628) 174.553,323.533 174.68,323.407 ccw(c174.775,323.502) 174.87,323.407 174.9,323.436 cw(c174.994,323.341) 175.089,323.436 175.244,323.281 175.244,322.923 175.778,322.389 175.778,322.233 ccw(c175.845,322.233) 175.845,322.166 cw(c175.845,322.054) 175.957,322.054 175.957,321.83 cw(c175.845,321.83) 175.845,321.718 175.778,321.718 175.711,321.718 ccw(c175.711,321.606) 175.599,321.606 175.599,321.382 ccw(c175.711,321.382) 175.711,321.27 ; 175.691,321.27 cw(c175.691,321.183) 175.778,321.183 175.778,317.947 176.211,317.514 176.211,316.273 176.251,316.233 176.251,316.067 177.402,314.915 177.402,312.612 177.664,312.35 177.664,312.272 178.104,311.832 178.104,311.704 178.561,311.247 178.581,311.247 178.801,311.027 v1(178.909,311.027)
DDR4_DQ34: U1.U25 U9.H3 | length 40.7
  L1 w0.116: v3(170.472,333.257) U9.H3@170.876,333.66 ; U1.U25@178.397,312.539 v1(178.884,313.027)
  L12 (Sign) w0.092: v3(170.472,333.257) 171.363,333.257 175.654,328.966 175.654,327.147 176.623,326.178 177.528,325.272 177.81,324.99 cw(c177.74,324.92) 177.81,324.849 177.632,324.671 ccw(c177.703,324.601) 177.632,324.53 177.844,324.319 ccw(c177.914,324.389) 177.985,324.319 178.163,324.497 cw(c178.233,324.426) 178.304,324.497 178.41,324.391 178.41,324.155 178.41,323.819 cw(c178.31,323.819) 178.31,323.719 177.9,323.719 ccw(c177.9,323.619) 177.8,323.619 177.8,323.32 ccw(c177.9,323.32) 177.9,323.221 178.41,323.221 178.919,323.221 cw(c178.919,323.121) 179.019,323.121 179.019,322.822 cw(c178.919,322.822) 178.919,322.722 178.41,322.722 177.9,322.722 ccw(c177.9,322.622) 177.8,322.622 177.8,322.323 ccw(c177.9,322.323) 177.9,322.223 178.41,322.223 178.671,322.223 cw(c178.671,322.124) 178.771,322.124 178.771,321.825 cw(c178.671,321.825) 178.671,321.725 178.41,321.725 177.9,321.725 ccw(c177.9,321.625) 177.8,321.625 177.8,321.326 ccw(c177.9,321.326) 177.9,321.226 178.41,321.226 178.671,321.226 cw(c178.671,321.126) 178.771,321.126 178.771,320.827 cw(c178.671,320.827) 178.671,320.728 178.41,320.728 177.9,320.728 ccw(c177.9,320.628) 177.8,320.628 177.8,320.329 ccw(c177.9,320.329) 177.9,320.229 178.41,320.229 178.671,320.229 cw(c178.671,320.129) 178.771,320.129 178.771,319.83 cw(c178.671,319.83) 178.671,319.73 178.41,319.73 177.9,319.73 ccw(c177.9,319.631) 177.8,319.631 177.8,319.332 ccw(c177.9,319.332) 177.9,319.232 178.41,319.232 178.671,319.232 cw(c178.671,319.132) 178.771,319.132 178.771,318.833 cw(c178.671,318.833) 178.671,318.733 178.41,318.733 177.9,318.733 ccw(c177.9,318.633) 177.8,318.633 177.8,318.334 ccw(c177.9,318.334) 177.9,318.235 178.41,318.235 178.671,318.235 cw(c178.671,318.135) 178.771,318.135 178.771,317.836 cw(c178.671,317.836) 178.671,317.736 178.41,317.736 178.089,317.736 ccw(c178.089,317.636) 177.989,317.636 177.989,317.337 ccw(c178.089,317.337) 178.089,317.237 178.41,317.237 178.551,317.237 cw(c178.551,317.138) 178.651,317.138 178.651,316.839 cw(c178.551,316.839) 178.551,316.739 178.41,316.739 177.9,316.739 ccw(c177.9,316.639) 177.8,316.639 177.8,316.34 ccw(c177.9,316.34) 177.9,316.24 178.41,316.24 178.671,316.24 cw(c178.671,316.14) 178.771,316.14 178.771,315.841 cw(c178.671,315.841) 178.671,315.742 178.41,315.742 178.2,315.742 ccw(c178.2,315.642) 178.1,315.642 178.1,315.343 ccw(c178.2,315.343) 178.2,315.243 178.31,315.243 cw(c178.31,315.143) 178.41,315.143 178.41,314.994 178.884,314.519 v1(178.884,313.027)
DDR4_DQ35: U1.V24 U9.H4 | length 39.9
  L1 w0.116: U9.H4@167.676,333.66 v3(168.079,333.257) ; U1.V24@179.397,311.539 v1(179.884,311.052)
  L12 (Sign) w0.092: v3(168.079,333.257) 168.079,332.72 168.143,332.657 ccw(c168.238,332.751) 168.333,332.657 169.354,333.678 cw(c169.449,333.583) 169.544,333.678 169.671,333.551 cw(c169.576,333.456) 169.671,333.361 168.554,332.245 168.519,332.21 ccw(c168.614,332.115) 168.519,332.02 168.646,331.893 ccw(c168.741,331.988) 168.836,331.893 168.871,331.928 169.829,332.887 cw(c169.924,332.792) 170.019,332.887 170.146,332.76 cw(c170.051,332.665) 170.146,332.57 169.188,331.612 169.165,331.589 ccw(c169.26,331.494) 169.165,331.399 169.291,331.272 ccw(c169.386,331.367) 169.481,331.272 169.504,331.295 169.819,331.61 cw(c169.914,331.515) 170.009,331.61 170.136,331.483 cw(c170.041,331.388) 170.136,331.293 169.916,331.073 ccw(c170.011,330.978) 169.916,330.883 169.989,330.81 170.217,330.582 170.793,330.582 171.112,330.263 171.328,330.263 172.178,329.413 172.178,326.83 175.565,323.444 175.611,323.398 cw(c175.547,323.334) 175.611,323.271 175.486,323.146 ccw(c175.549,323.083) 175.486,323.02 175.676,322.83 ccw(c175.739,322.893) 175.803,322.83 175.927,322.954 cw(c175.991,322.891) 176.054,322.954 176.149,322.859 176.149,322.725 ccw(c176.239,322.725) 176.239,322.636 176.415,322.636 cw(c176.415,322.546) 176.505,322.546 176.505,322.277 cw(c176.415,322.277) 176.415,322.188 176.239,322.188 ccw(c176.239,322.098) 176.149,322.098 176.149,322.047 176.149,317.848 176.403,317.594 176.403,316.352 176.451,316.304 176.451,316.138 177.594,314.995 177.594,312.715 178.296,312.013 178.296,311.783 178.65,311.429 179.197,311.429 cw(c179.197,311.233) 179.393,311.233 179.393,310.801 ccw(c179.743,310.801) 179.743,310.452 180.111,310.452 ccw(c180.111,310.718) 180.378,310.718 ccw(c180.044,310.718) 180.044,311.052 v1(179.884,311.052)
DDR4_DQ36: U1.Y25 U9.H2 | length 38.8
  L1 w0.116: U9.H2@171.676,333.66 v3(172.079,333.257) ; v1(180.909,313.027) U1.Y25@181.397,312.539
  L12 (Sign) w0.092: v3(172.079,333.257) 172.079,332.822 175.91,328.992 175.91,327.163 178.602,324.47 178.602,324.445 179.553,323.494 179.553,322.847 179.553,322.514 cw(c179.453,322.514) 179.453,322.414 179.063,322.414 ccw(c179.063,322.315) 178.963,322.315 178.963,322.016 ccw(c179.063,322.016) 179.063,321.916 179.553,321.916 180.042,321.916 cw(c180.042,321.816) 180.142,321.816 180.142,321.517 cw(c180.042,321.517) 180.042,321.417 179.553,321.417 179.063,321.417 ccw(c179.063,321.318) 178.963,321.318 178.963,321.018 ccw(c179.063,321.018) 179.063,320.919 179.553,320.919 180.042,320.919 cw(c180.042,320.819) 180.142,320.819 180.142,320.52 cw(c180.042,320.52) 180.042,320.42 179.553,320.42 179.063,320.42 ccw(c179.063,320.32) 178.963,320.32 178.963,320.021 ccw(c179.063,320.021) 179.063,319.921 179.553,319.921 180.042,319.921 cw(c180.042,319.822) 180.142,319.822 180.142,319.523 cw(c180.042,319.523) 180.042,319.423 179.553,319.423 179.063,319.423 ccw(c179.063,319.323) 178.963,319.323 178.963,319.024 ccw(c179.063,319.024) 179.063,318.924 179.553,318.924 180.042,318.924 cw(c180.042,318.825) 180.142,318.825 180.142,318.525 cw(c180.042,318.525) 180.042,318.426 179.553,318.426 179.063,318.426 ccw(c179.063,318.326) 178.963,318.326 178.963,318.027 ccw(c179.063,318.027) 179.063,317.927 179.553,317.927 180.042,317.927 cw(c180.042,317.827) 180.142,317.827 180.142,317.528 cw(c180.042,317.528) 180.042,317.428 179.553,317.428 179.288,317.428 ccw(c179.288,317.329) 179.188,317.329 179.188,317.03 ccw(c179.288,317.03) 179.288,316.93 179.553,316.93 180.042,316.93 cw(c180.042,316.83) 180.142,316.83 180.142,316.531 cw(c180.042,316.531) 180.042,316.431 179.553,316.431 179.063,316.431 ccw(c179.063,316.332) 178.963,316.332 178.963,316.032 ccw(c179.063,316.032) 179.063,315.933 179.453,315.933 cw(c179.453,315.833) 179.553,315.833 179.553,315.683 180.909,314.326 v1(180.909,313.027)
DDR4_DQ37: U1.AA23 U9.H5 | length 49.6
  L1 w0.116: v3(166.472,333.257) U9.H5@166.876,333.66 ; v1(181.909,310.052) U1.AA23@182.397,310.539
  L12 (Sign) w0.092: v3@166.472,333.257 166.472,333.934 166.998,334.46 171.343,334.46 171.78,334.023 172.683,334.023 174.022,332.684 174.558,332.148 cw(c174.494,332.085) 174.558,332.022 174.253,331.717 ccw(c174.317,331.654) 174.253,331.591 174.443,331.401 ccw(c174.507,331.464) 174.57,331.401 174.938,331.768 175.305,332.136 cw(c175.369,332.073) 175.432,332.136 175.622,331.946 cw(c175.559,331.883) 175.622,331.819 175.254,331.452 174.887,331.084 ccw(c174.95,331.021) 174.887,330.957 175.076,330.767 ccw(c175.14,330.831) 175.203,330.767 175.508,331.072 cw(c175.571,331.008) 175.634,331.072 175.729,330.977 176.451,330.255 176.451,327.244 181.47,322.224 181.47,322.174 181.47,321.958 cw(c181.381,321.958) 181.381,321.869 181.091,321.869 ccw(c181.091,321.779) 181.002,321.779 181.002,321.511 ccw(c181.091,321.511) 181.091,321.421 181.47,321.421 182.09,321.421 cw(c182.09,321.332) 182.18,321.332 182.18,321.063 cw(c182.09,321.063) 182.09,320.973 181.47,320.973 181.091,320.973 ccw(c181.091,320.884) 181.002,320.884 181.002,320.615 ccw(c181.091,320.615) 181.091,320.525 181.47,320.525 182.09,320.525 cw(c182.09,320.436) 182.18,320.436 182.18,320.167 cw(c182.09,320.167) 182.09,320.078 181.47,320.078 ccw(c181.47,320.006) 181.398,320.006 181.398,319.702 ccw(c181.47,319.702) 181.47,319.63 182.09,319.63 cw(c182.09,319.54) 182.18,319.54 182.18,319.272 cw(c182.09,319.272) 182.09,319.182 181.47,319.182 ccw(c181.47,319.11) 181.398,319.11 181.398,318.806 ccw(c181.47,318.806) 181.47,318.734 182.09,318.734 cw(c182.09,318.645) 182.18,318.645 182.18,318.376 cw(c182.09,318.376) 182.09,318.286 181.47,318.286 ccw(c181.47,318.214) 181.398,318.214 181.398,317.911 ccw(c181.47,317.911) 181.47,317.839 181.736,317.839 cw(c181.736,317.749) 181.826,317.749 181.826,317.48 cw(c181.736,317.48) 181.736,317.391 181.47,317.391 ccw(c181.47,317.319) 181.398,317.319 181.398,317.015 ccw(c181.47,317.015) 181.47,316.943 cw(c181.47,316.874) 181.539,316.874 181.539,316.564 cw(c181.47,316.564) 181.47,316.495 181.091,316.495 ccw(c181.091,316.406) 181.002,316.406 181.002,316.137 ccw(c181.091,316.137) 181.091,316.047 181.381,316.047 cw(c181.381,315.958) 181.47,315.958 181.47,315.824 181.985,315.309 181.985,312.941 181.508,312.464 181.508,311.839 181.781,311.566 182.172,311.566 182.397,311.341 182.397,310.539 v1(181.909,310.052)
DDR4_DQ38: U1.AA25 U9.J3 | length 38.2
  L1 w0.116: U9.J3@170.876,334.46 v3(171.279,334.864) ; v1(181.909,312.052) U1.AA25@182.397,312.539
  L12 (Sign) w0.092: v3(171.279,334.864) 171.929,334.215 172.872,334.215 173.022,334.215 ccw(c173.022,334.314) 173.122,334.314 173.122,334.619 cw(c173.221,334.619) 173.221,334.719 173.521,334.719 cw(c173.521,334.619) 173.62,334.619 173.62,334.215 173.62,333.705 ccw(c173.72,333.705) 173.72,333.605 174.019,333.605 ccw(c174.019,333.705) 174.119,333.705 174.119,334.215 174.119,334.725 cw(c174.219,334.725) 174.219,334.824 174.518,334.824 cw(c174.518,334.725) 174.617,334.725 174.617,334.215 174.617,333.705 ccw(c174.717,333.705) 174.717,333.605 175.016,333.605 ccw(c175.016,333.705) 175.116,333.705 175.116,334.215 175.116,334.725 cw(c175.216,334.725) 175.216,334.824 175.515,334.824 cw(c175.515,334.725) 175.615,334.725 175.615,334.314 ccw(c175.714,334.314) 175.714,334.215 175.844,334.215 176.122,334.215 176.643,333.694 176.643,333.544 ccw(c176.743,333.544) 176.743,333.445 176.98,333.445 cw(c176.98,333.345) 177.08,333.345 177.08,333.046 cw(c176.98,333.046) 176.98,332.946 176.643,332.946 176.306,332.946 ccw(c176.306,332.846) 176.206,332.846 176.206,332.547 ccw(c176.306,332.547) 176.306,332.448 176.543,332.448 cw(c176.543,332.348) 176.643,332.348 176.643,331.483 176.643,327.352 179.36,324.634 179.36,324.617 182.372,321.605 182.372,315.584 182.177,315.389 182.177,312.319 v1(181.909,312.052)
DDR4_DQ39: U1.Y23 U9.J4 | length 39.7
  L1 w0.116: v3(167.272,334.057) U9.J4@167.676,334.46 ; U1.Y23@181.397,310.539 v1(181.884,311.027)
  L12 (Sign) w0.092: 170.679,334.057 171.12,333.616 172.273,333.616 172.466,333.424 172.466,333.054 176.102,329.418 176.102,327.262 180.81,322.554 180.81,321.462 180.81,320.825 cw(c180.71,320.825) 180.71,320.725 180.513,320.725 ccw(c180.513,320.626) 180.414,320.626 180.414,320.327 ccw(c180.513,320.327) 180.513,320.227 180.81,320.227 181.106,320.227 cw(c181.106,320.127) 181.206,320.127 181.206,319.828 cw(c181.106,319.828) 181.106,319.728 180.81,319.728 180.513,319.728 ccw(c180.513,319.628) 180.414,319.628 180.414,319.329 ccw(c180.513,319.329) 180.513,319.23 180.81,319.23 181.106,319.23 cw(c181.106,319.13) 181.206,319.13 181.206,318.831 cw(c181.106,318.831) 181.106,318.731 180.81,318.731 180.513,318.731 ccw(c180.513,318.631) 180.414,318.631 180.414,318.332 ccw(c180.513,318.332) 180.513,318.232 180.81,318.232 181.106,318.232 cw(c181.106,318.133) 181.206,318.133 181.206,317.834 cw(c181.106,317.834) 181.106,317.734 180.81,317.734 180.513,317.734 ccw(c180.513,317.634) 180.414,317.634 180.414,317.335 ccw(c180.513,317.335) 180.513,317.235 180.81,317.235 181.106,317.235 cw(c181.106,317.135) 181.206,317.135 181.206,316.836 cw(c181.106,316.836) 181.106,316.737 180.81,316.737 180.513,316.737 ccw(c180.513,316.637) 180.414,316.637 180.414,316.338 ccw(c180.513,316.338) 180.513,316.238 180.71,316.238 cw(c180.71,316.138) 180.81,316.138 180.81,315.989 181.793,315.006 181.793,313.375 181.316,312.899 181.316,311.595 v1(181.884,311.027)
  L12 (Sign) w0.1: v3(167.272,334.057) 170.679,334.057
DDR4_DQ40: U1.P23 U9.A3 | length 31.5
  L1 w0.116: v3(170.472,327.657) U9.A3@170.876,328.06 ; U1.P23@175.397,310.539 v1(175.884,311.027)
  L12 (Sign) w0.092: v3(170.472,327.657) 170.472,325.12 170.472,325.056 170.472,324.682 cw(c170.348,324.682) 170.348,324.558 169.524,324.558 ccw(c169.524,324.433) 169.399,324.433 169.399,324.184 ccw(c169.524,324.184) 169.524,324.059 170.348,324.059 cw(c170.348,323.934) 170.472,323.934 170.472,323.685 cw(c170.348,323.685) 170.348,323.56 170.226,323.56 ccw(c170.226,323.436) 170.101,323.436 170.101,323.186 ccw(c170.226,323.186) 170.226,323.062 170.348,323.062 cw(c170.348,322.937) 170.472,322.937 170.472,322.813 170.574,322.711 171.287,321.998 cw(c171.199,321.91) 171.287,321.821 171.245,321.779 ccw(c171.333,321.691) 171.245,321.603 171.421,321.427 ccw(c171.509,321.515) 171.597,321.427 171.728,321.557 cw(c171.788,321.497) 171.847,321.557 172.08,321.324 cw(c172.02,321.264) 172.08,321.204 171.95,321.074 ccw(c172.038,320.986) 171.95,320.898 172.126,320.722 ccw(c172.214,320.81) 172.303,320.722 172.433,320.852 cw(c172.48,320.805) 172.527,320.852 172.785,320.594 cw(c172.738,320.546) 172.785,320.499 172.655,320.369 ccw(c172.743,320.281) 172.655,320.193 172.831,320.016 ccw(c172.92,320.105) 173.008,320.016 173.138,320.147 cw(c173.185,320.1) 173.232,320.147 173.491,319.889 cw(c173.443,319.841) 173.491,319.794 173.36,319.664 ccw(c173.448,319.576) 173.36,319.488 173.537,319.311 ccw(c173.625,319.399) 173.713,319.311 173.755,319.353 cw(c173.843,319.265) 173.931,319.353 174.019,319.265 174.079,319.206 174.079,319.081 ccw(c174.204,319.081) 174.204,318.956 174.401,318.956 cw(c174.401,318.832) 174.526,318.832 174.526,318.583 cw(c174.401,318.583) 174.401,318.458 174.204,318.458 ccw(c174.204,318.333) 174.079,318.333 174.079,318.072 174.079,317.675 174.076,317.672 174.076,317.406 174.079,317.403 174.079,316.675 174.076,316.672 174.076,316.406 174.079,316.403 174.079,315.675 174.076,315.672 174.076,315.406 174.079,315.403 174.079,315.303 174.23,315.152 174.484,315.152 175.362,314.274 175.362,313.919 175.158,313.716 175.158,312.338 175.305,312.191 175.305,311.875 175.524,311.656 176.073,311.656 176.076,311.658 176.234,311.658 176.488,311.912 176.488,312.191 176.72,312.423 177.048,312.423 177.28,312.191 177.28,312.113 177.718,311.675 177.718,311.406 177.508,311.196 177.032,311.196 ccw(c177.032,311.114) 176.949,311.114 176.949,310.483 cw(c176.771,310.483) 176.771,310.306 176.371,310.306 cw(c176.371,310.452) 176.225,310.452 176.225,310.686 ccw(c175.884,310.686) v1(175.884,311.027)
DDR4_DQ41: U1.R23 U9.B5 | length 33.5
  L1 w0.116: v3(166.472,328.457) U9.B5@166.876,328.86 ; v1(175.909,310.052) U1.R23@176.397,310.539
  L1 w0.25: v3(166.472,327.657) 166.876,328.06
  L12 (Sign) w0.092: v3(166.472,328.457) 166.795,328.134 166.795,327.389 166.795,327.206 ccw(c166.836,327.206) 166.836,327.165 cw(c166.836,327.075) 166.926,327.075 166.926,326.806 cw(c166.836,326.806) 166.836,326.717 166.795,326.717 166.582,326.717 ccw(c166.582,326.627) 166.492,326.627 166.492,326.359 ccw(c166.582,326.359) 166.582,326.269 166.795,326.269 166.834,326.269 cw(c166.834,326.18) 166.923,326.18 166.923,325.911 cw(c166.834,325.911) 166.834,325.821 166.795,325.821 166.582,325.821 ccw(c166.582,325.732) 166.492,325.732 166.492,325.463 ccw(c166.582,325.463) 166.582,325.374 166.795,325.374 166.834,325.374 cw(c166.834,325.284) 166.923,325.284 166.923,325.015 cw(c166.834,325.015) 166.834,324.926 166.795,324.926 166.582,324.926 ccw(c166.582,324.836) 166.492,324.836 166.492,324.567 ccw(c166.582,324.567) 166.582,324.478 166.705,324.478 cw(c166.705,324.388) 166.795,324.388 166.795,323.698 166.795,322.866 166.96,322.7 167.111,322.549 ccw(c167.174,322.613) 167.238,322.549 167.326,322.638 cw(c167.39,322.575) 167.453,322.638 167.643,322.448 cw(c167.58,322.385) 167.643,322.322 167.491,322.169 167.339,322.017 ccw(c167.402,321.954) 167.339,321.89 167.529,321.701 ccw(c167.592,321.764) 167.655,321.701 167.808,321.853 167.96,322.005 cw(c168.023,321.942) 168.086,322.005 168.276,321.815 cw(c168.213,321.752) 168.276,321.688 168.124,321.536 167.972,321.384 ccw(c168.035,321.321) 167.972,321.257 168.162,321.067 ccw(c168.225,321.131) 168.289,321.067 168.441,321.219 168.593,321.372 cw(c168.656,321.308) 168.72,321.372 168.91,321.182 cw(c168.846,321.118) 168.91,321.055 168.757,320.903 168.605,320.751 ccw(c168.669,320.687) 168.605,320.624 168.795,320.434 ccw(c168.859,320.497) 168.922,320.434 169.074,320.586 169.226,320.738 cw(c169.29,320.675) 169.353,320.738 169.543,320.548 cw(c169.48,320.485) 169.543,320.422 169.391,320.269 169.239,320.117 ccw(c169.302,320.054) 169.239,319.991 169.429,319.801 ccw(c169.492,319.864) 169.555,319.801 169.707,319.953 169.86,320.105 cw(c169.923,320.042) 169.986,320.105 170.176,319.915 cw(c170.113,319.852) 170.176,319.788 170.087,319.7 ccw(c170.151,319.636) 170.087,319.573 170.341,319.32 170.499,319.161 170.499,319.037 ccw(c170.624,319.037) 170.624,318.912 170.813,318.912 cw(c170.813,318.787) 170.937,318.787 170.937,318.538 cw(c170.813,318.538) 170.813,318.413 170.624,318.413 ccw(c170.624,318.289) 170.499,318.289 170.499,318.039 ccw(c170.624,318.039) 170.624,317.915 170.813,317.915 cw(c170.813,317.79) 170.937,317.79 170.937,317.541 cw(c170.813,317.541) 170.813,317.416 170.624,317.416 ccw(c170.624,317.292) 170.499,317.292 170.499,317.042 ccw(c170.624,317.042) 170.624,316.918 170.813,316.918 cw(c170.813,316.793) 170.937,316.793 170.937,316.544 cw(c170.813,316.544) 170.813,316.419 170.624,316.419 ccw(c170.624,316.294) 170.499,316.294 170.499,316.167 170.912,315.754 170.912,314.311 173.884,311.339 173.884,311.327 174.184,311.026 174.196,311.026 174.401,310.822 175.433,310.822 175.909,310.346 v1(175.909,310.052)
DDR4_DQ42: U1.T23 U9.C3 | length 30.8
  L1 w0.116: v3(170.472,329.257) U9.C3@170.876,329.66 ; U1.T23@177.397,310.539 v5(177.884,310.052)
  L12 (Sign) w0.092: v3(170.472,329.257) 170.472,328.975 170.793,328.654 170.793,327.465 170.709,327.381 170.709,323.429 170.788,323.35 ccw(c170.868,323.429) 170.947,323.35 171.032,323.436 cw(c171.112,323.357) 171.191,323.436 171.349,323.278 cw(c171.27,323.198) 171.349,323.119 171.184,322.954 171.019,322.79 ccw(c171.098,322.71) 171.019,322.631 171.178,322.473 ccw(c171.257,322.552) 171.336,322.473 171.501,322.638 171.666,322.803 cw(c171.745,322.723) 171.824,322.803 171.982,322.644 cw(c171.903,322.565) 171.982,322.486 171.817,322.321 171.653,322.156 ccw(c171.732,322.077) 171.653,321.998 171.811,321.84 ccw(c171.89,321.919) 171.969,321.84 172.134,322.004 172.299,322.169 cw(c172.378,322.09) 172.457,322.169 172.616,322.011 cw(c172.536,321.932) 172.616,321.853 172.451,321.688 172.286,321.523 ccw(c172.365,321.444) 172.286,321.365 172.444,321.206 ccw(c172.523,321.286) 172.603,321.206 172.767,321.371 172.932,321.536 cw(c173.011,321.457) 173.091,321.536 173.249,321.378 cw(c173.17,321.299) 173.249,321.219 173.084,321.055 172.919,320.89 ccw(c172.998,320.811) 172.919,320.731 173.077,320.573 ccw(c173.157,320.652) 173.236,320.573 173.401,320.738 173.541,320.878 cw(c173.62,320.799) 173.699,320.878 173.858,320.72 cw(c173.779,320.641) 173.858,320.562 173.717,320.421 173.552,320.256 ccw(c173.632,320.177) 173.552,320.098 173.711,319.94 ccw(c173.79,320.019) 173.869,319.94 173.955,320.025 cw(c174.034,319.946) 174.113,320.025 174.387,319.751 174.718,319.421 174.718,315.218 175.552,314.384 175.552,314.355 175.554,314.354 175.554,313.839 175.552,313.838 175.552,313.779 175.362,313.588 175.362,312.885 175.616,312.631 177.112,312.631 177.472,312.27 177.472,312.192 177.91,311.755 177.91,311.627 178.371,311.165 178.371,310.539 v5(177.884,310.052)
DDR4_DQ43: U1.P26 U9.C4 | length 29.3
  L1 w0.116: U9.C4@167.676,329.66 v3(168.079,329.257) ; v1(174.909,314.027) U1.P26@175.397,313.539
  L12 (Sign) w0.092: v3(168.079,329.257) 169.1,328.236 169.1,328.111 cw(c168.976,328.111) 168.976,327.986 168.612,327.986 ccw(c168.612,327.862) 168.487,327.862 168.487,327.612 ccw(c168.612,327.612) 168.612,327.488 169.1,327.488 169.418,327.488 cw(c169.418,327.363) 169.543,327.363 169.543,327.114 cw(c169.418,327.114) 169.418,326.989 169.1,326.989 168.188,326.989 ccw(c168.188,326.864) 168.064,326.864 168.064,326.615 ccw(c168.188,326.615) 168.188,326.491 169.1,326.491 170.013,326.491 cw(c170.013,326.366) 170.137,326.366 170.137,326.117 cw(c170.013,326.117) 170.013,325.992 169.1,325.992 168.188,325.992 ccw(c168.188,325.867) 168.064,325.867 168.064,325.618 ccw(c168.188,325.618) 168.188,325.493 169.1,325.493 170.013,325.493 cw(c170.013,325.369) 170.137,325.369 170.137,325.119 cw(c170.013,325.119) 170.013,324.995 169.204,324.995 ccw(c169.204,324.891) 169.1,324.891 169.1,323.418 173.838,318.681 173.838,314.645 174.456,314.027 v1(174.909,314.027)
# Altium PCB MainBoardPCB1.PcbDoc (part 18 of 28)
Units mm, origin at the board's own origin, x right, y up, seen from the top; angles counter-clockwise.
Board outline 258.95 x 308.86 mm, 16 copper layers (L1, L2 (GND), L3 (Sign), L4 (GND), L5 (Sign), L6 (PWR/GND), L7(PWR/GND), L8 (Plane_GND), L9 (PWR/GND), L10 (PWR/GND), L11 (PWR/GND), L12 (Sign), L13 (GND), L14 (Sign), L15 (GND), L16), stack 2.502 mm thick; 2397 components, 1744 nets, 8397 pads, 4112 vias.
Unrouted connection lines stored in the file: 3547.

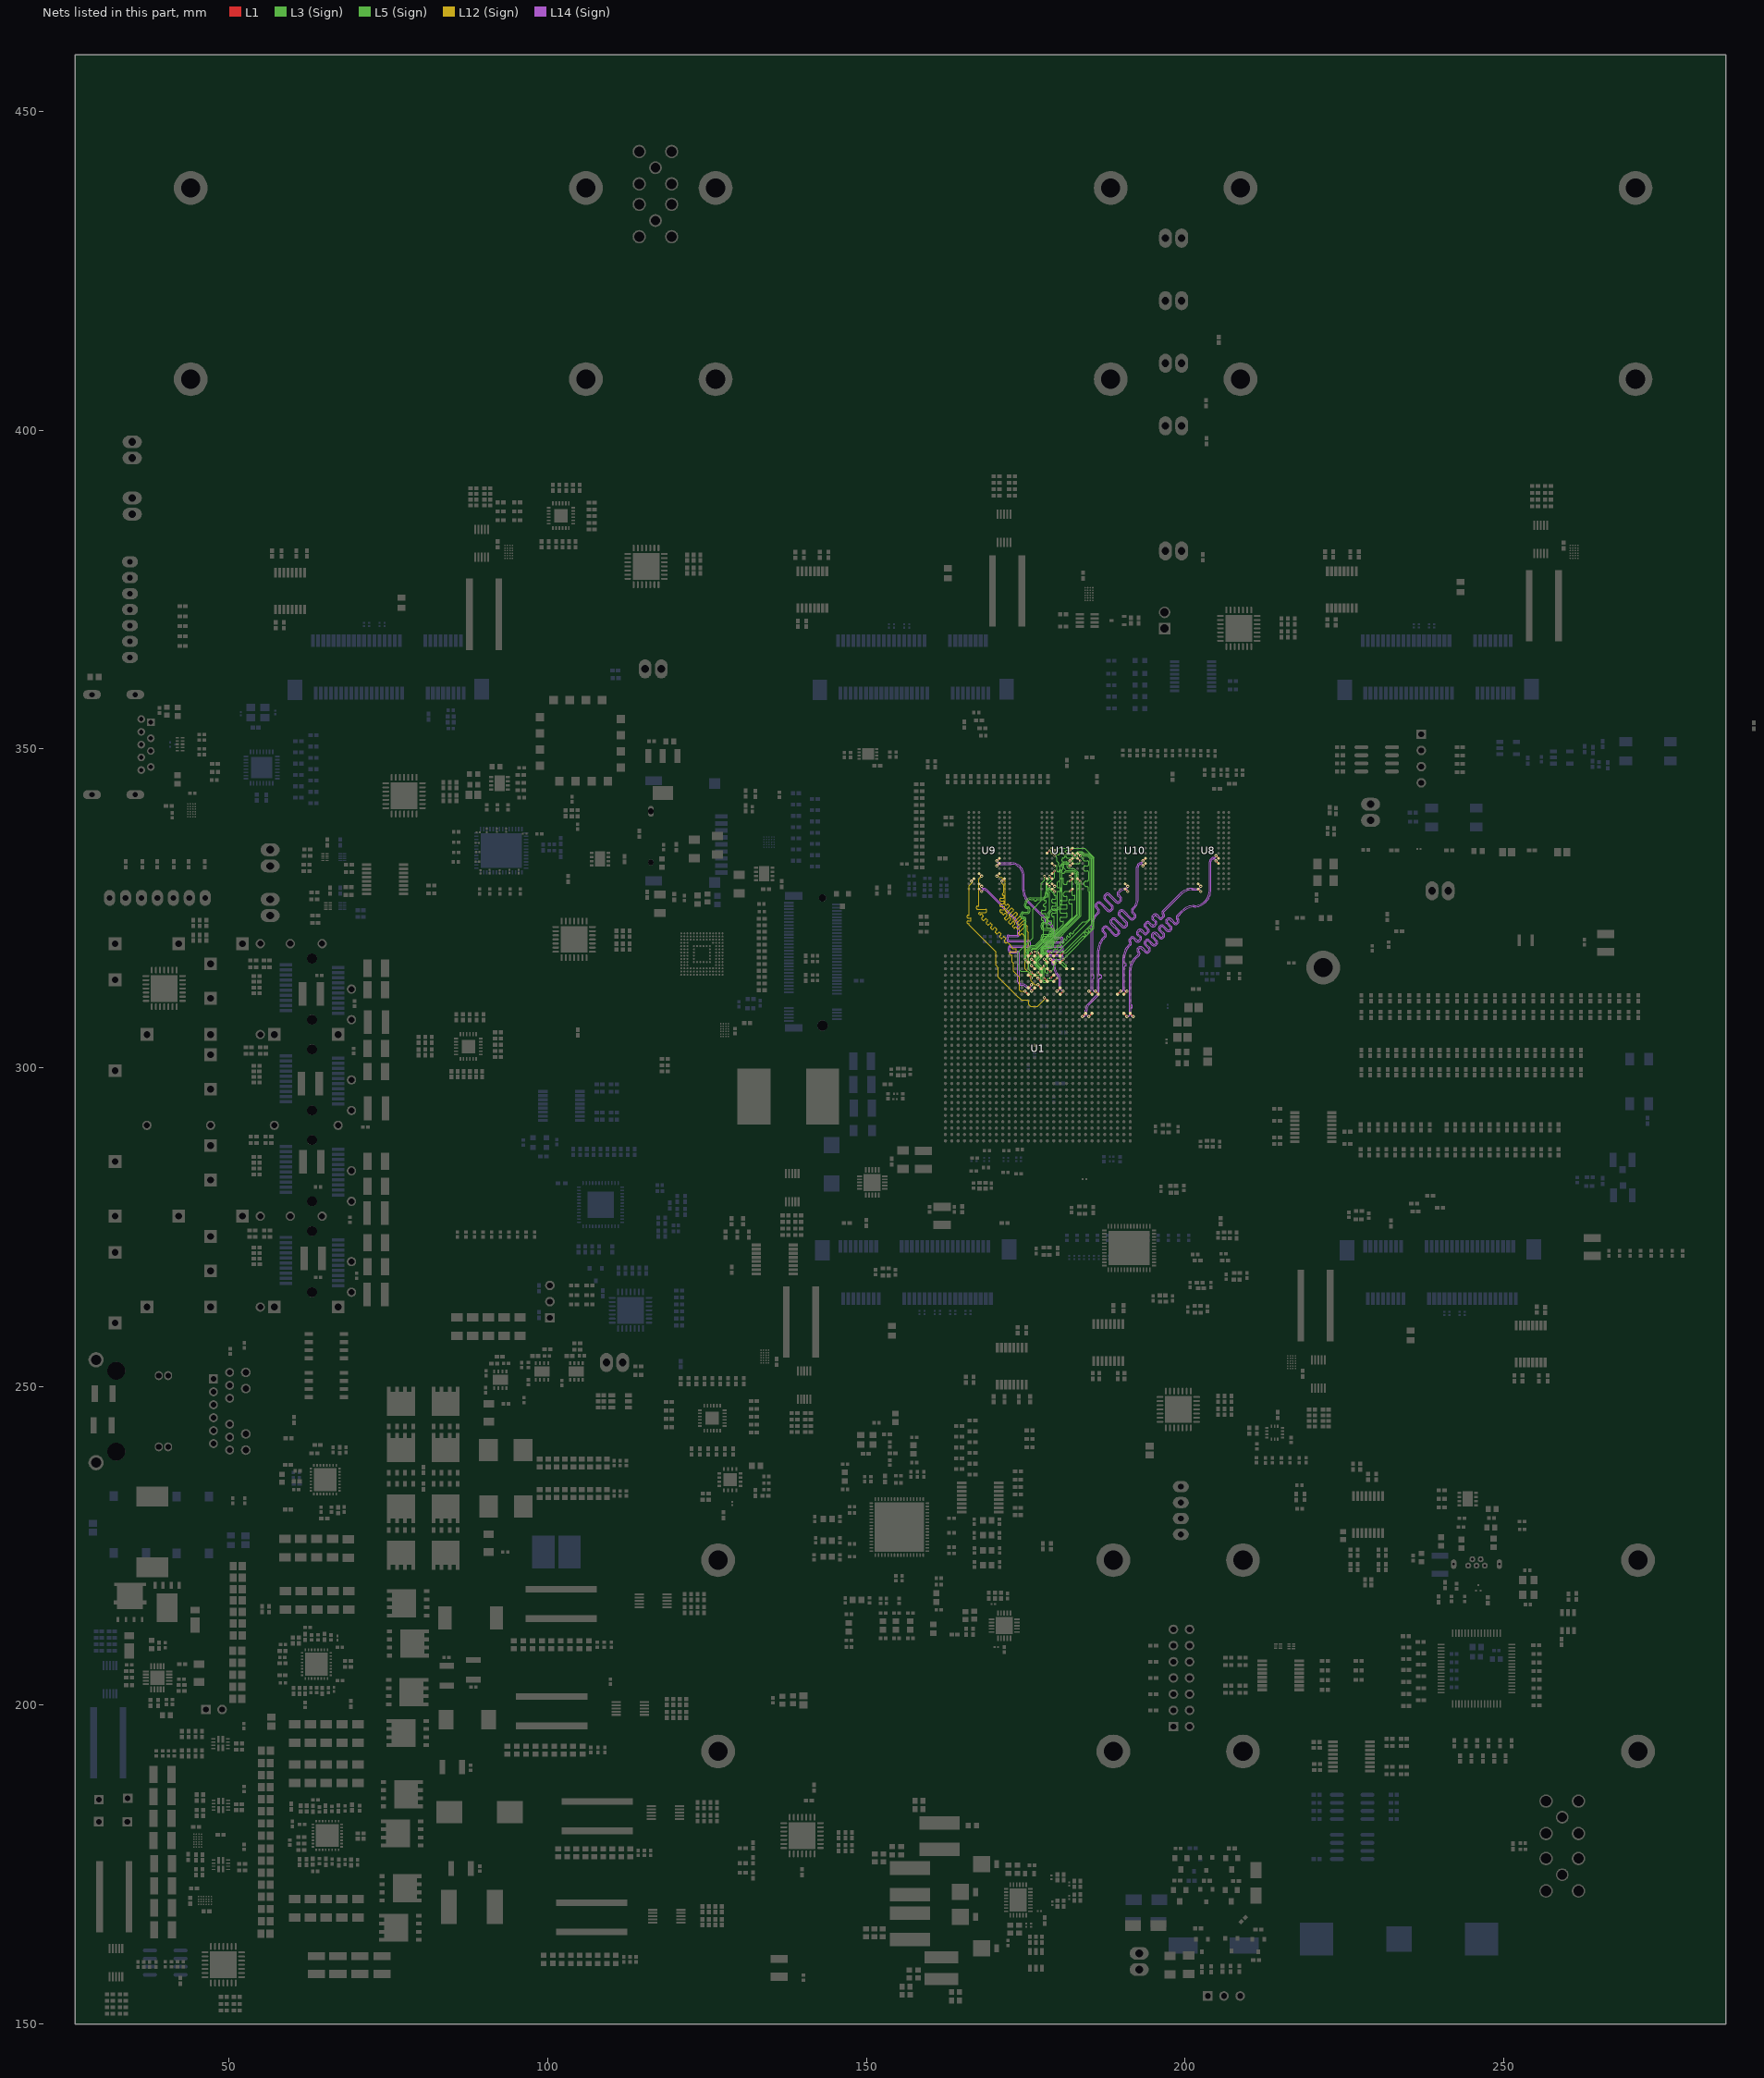
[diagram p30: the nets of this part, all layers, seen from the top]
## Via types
v1: diameter 0.5, hole 0.2, L1 to L16, tented both sides, 1457 vias
v2: diameter 0.35/0/0.35 (per signal layer), hole 0.127, L1 to L3 (Sign), tented both sides, 479 vias
v3: diameter 0.5/0.35/0.35/0.35/0.35/0.35/0.35/0.35/0.35/0.35/0.35/0.35/0.35/0.35/0.35/0.5 (per signal layer), hole 0.15, L1 to L16, tented both sides, 453 vias
v4: diameter 0.5, hole 0.2, L1 to L16, 451 vias
v5: diameter 0.5/0.35/0.35/0.35/0.35/0.35/0.35/0.35/0.35/0.35/0.35/0.35/0.35/0.35/0.35/0.5 (per signal layer), hole 0.2, L1 to L16, tented both sides, 373 vias
v6: diameter 0.8, hole 0.4, L1 to L16, tented both sides, 168 vias
v7: diameter 0.35/0/0.35 (per signal layer), hole 0.127, L1 to L3 (Sign), 138 vias
v8: diameter 2.54, hole 1.02, L1 to L16, 113 vias
v9: diameter 0.5/0/0.5 (per signal layer), hole 0.2, L14 (Sign) to L16, tented both sides, 102 vias
v10: diameter 1.4, hole 0.5, L1 to L16, tented both sides, 80 vias
v11: diameter 0.5, hole 0.2, L3 (Sign) to L6 (PWR/GND), tented both sides, 54 vias
v12: diameter 0.35, hole 0.127, L1 to L2 (GND), tented both sides, 47 vias
v13: diameter 0.4, hole 0.2, L1 to L16, tented both sides, 46 vias
v14: diameter 0.35, hole 0.127, L1 to L16, tented both sides, 16 vias
v15: diameter 0.25, hole 0.2, L1 to L16, 16 vias
v16: diameter 0.5, hole 0.2, L11 (PWR/GND) to L14 (Sign), tented both sides, 16 vias
v17: diameter 0.4, hole 0.2, L1 to L16, 16 vias
v18: diameter 0.3, hole 0.2, L1 to L16, 15 vias
v19: diameter 0.45, hole 0.15, L1 to L16, 12 vias
v20: diameter 0.5/0.35/0.35/0.35/0.35/0.35/0.35/0.35/0.35/0.35/0.35/0.35/0.35/0.35/0.35/0.45 (per signal layer), hole 0.15, L1 to L16, tented both sides, 10 vias
v21: diameter 0.2/0/0.2 (per signal layer), hole 0.1, L1 to L3 (Sign), tented both sides, 9 vias
v22: diameter 0.3, hole 0.127, L14 (Sign) to L16, tented both sides, 8 vias
v23: diameter 0.4, hole 0.1, L1 to L16, 7 vias
v24: diameter 1.15, hole 1.15, L1 to L16, 5 vias
v25: diameter 1.65, hole 1.65, L1 to L16, 5 vias
v26: diameter 0.2, hole 0.1, L1 to L16, 4 vias
v27: diameter 0.4, hole 0.15, L1 to L16, 2 vias
v28: diameter 0.5/0.35/0.35/0.35/0.35/0.35/0.35/0.35/0.35/0.35/0.35/0.35/0.35/0.35/0.35/0.5 (per signal layer), hole 0.15, L1 to L16, 2 vias
v29: diameter 0.35, hole 0.127, L3 (Sign) to L6 (PWR/GND), tented both sides, 2 vias
v30: diameter 0.3, hole 0.127, L15 (GND) to L16, tented both sides, 1 vias
v31: diameter 0.35, hole 0.127, L1 to L2 (GND), 1 vias
v32: diameter 0.5/0.35/0.35/0.35/0.35/0.35/0.35/0.35/0.35/0.35/0.35/0.35/0.35/0.35/0.35/0.5 (per signal layer), hole 0.2, L1 to L16, 1 vias
v33: diameter 0.35/0.35/0.35 (per signal layer), hole 0.127, L1 to L3 (Sign), tented both sides, 1 vias
v34: diameter 0.45/0/0.45 (per signal layer), hole 0.15, L1 to L3 (Sign), tented both sides, 1 vias
v35: diameter 0.45/0/0.45 (per signal layer), hole 0.2, L14 (Sign) to L16, tented both sides, 1 vias

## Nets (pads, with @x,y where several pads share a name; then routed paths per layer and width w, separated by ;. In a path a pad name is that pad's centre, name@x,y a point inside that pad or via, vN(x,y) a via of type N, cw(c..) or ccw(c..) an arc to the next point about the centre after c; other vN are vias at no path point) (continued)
DDR4_DQ44: U1.T25 U9.C2 | length 29.8
  L1 w0.116: v3(171.272,329.257) U9.C2@171.676,329.66 ; v1(176.909,313.027) U1.T25@177.397,312.539
  L12 (Sign) w0.092: v3(171.272,329.257) 171.272,328.944 171.593,328.623 171.593,327.524 171.352,327.283 171.352,327.171 ccw(c171.464,327.171) 171.464,327.059 171.49,327.059 cw(c171.49,326.947) 171.602,326.947 171.602,326.723 cw(c171.49,326.723) 171.49,326.612 171.352,326.612 171.097,326.612 ccw(c171.097,326.5) 170.985,326.5 170.985,326.276 ccw(c171.097,326.276) 171.097,326.164 171.352,326.164 171.49,326.164 cw(c171.49,326.052) 171.602,326.052 171.602,325.828 cw(c171.49,325.828) 171.49,325.716 171.352,325.716 171.097,325.716 ccw(c171.097,325.604) 170.985,325.604 170.985,325.38 ccw(c171.097,325.38) 171.097,325.268 171.352,325.268 171.627,325.268 cw(c171.627,325.156) 171.739,325.156 171.739,324.932 cw(c171.627,324.932) 171.627,324.82 171.352,324.82 171.097,324.82 ccw(c171.097,324.708) 170.985,324.708 170.985,324.484 ccw(c171.097,324.484) 171.097,324.373 171.241,324.373 cw(c171.241,324.261) 171.352,324.261 171.352,324.193 171.352,324.136 171.432,324.057 ccw(c171.511,324.136) 171.59,324.057 171.723,324.19 cw(c171.802,324.111) 171.882,324.19 172.04,324.032 cw(c171.961,323.953) 172.04,323.874 171.827,323.661 171.7,323.534 ccw(c171.779,323.454) 171.7,323.375 171.858,323.217 ccw(c171.937,323.296) 172.016,323.217 172.144,323.345 172.317,323.518 cw(c172.396,323.438) 172.475,323.518 172.634,323.359 cw(c172.554,323.28) 172.634,323.201 172.461,323.028 172.333,322.9 ccw(c172.412,322.821) 172.333,322.742 172.491,322.584 ccw(c172.57,322.663) 172.65,322.584 172.777,322.711 172.95,322.884 cw(c173.029,322.805) 173.109,322.884 173.267,322.726 cw(c173.188,322.647) 173.267,322.568 173.094,322.395 172.966,322.267 ccw(c173.045,322.188) 172.966,322.109 173.125,321.95 ccw(c173.204,322.029) 173.283,321.95 173.332,321.999 cw(c173.411,321.92) 173.49,321.999 173.493,321.996 173.609,321.88 173.688,321.801 ccw(c173.767,321.88) 173.846,321.801 174.493,322.448 cw(c174.573,322.368) 174.652,322.448 174.81,322.289 cw(c174.731,322.21) 174.81,322.131 174.084,321.405 173.855,321.176 ccw(c173.934,321.097) 173.855,321.018 174.013,320.859 ccw(c174.093,320.938) 174.172,320.859 174.321,321.009 cw(c174.401,320.93) 174.48,321.009 174.91,320.579 174.91,315.539 175.87,314.579 175.87,313.602 176.444,313.027 v1(176.909,313.027)
DDR4_DQ45: U1.U23 U9.C5 | length 30.1
  L1 w0.116: v3(166.472,329.257) U9.C5@166.876,329.66 ; v1(177.909,311.027) U1.U23@178.397,310.539
  L12 (Sign) w0.092: v3(166.472,329.257) 166.612,329.117 166.612,329.045 166.345,328.778 166.339,328.778 166.151,328.59 166.151,326.022 166.151,324.036 cw(c166.062,324.036) 166.062,323.946 165.945,323.946 ccw(c165.945,323.857) 165.856,323.857 165.856,323.588 ccw(c165.945,323.588) 165.945,323.498 166.151,323.498 166.357,323.498 cw(c166.357,323.409) 166.446,323.409 166.446,323.14 cw(c166.357,323.14) 166.357,323.051 166.151,323.051 165.945,323.051 ccw(c165.945,322.961) 165.856,322.961 165.856,322.692 ccw(c165.945,322.692) 165.945,322.603 166.062,322.603 cw(c166.062,322.513) 166.151,322.513 166.151,322.379 170.307,318.223 170.307,316.088 170.72,315.675 170.72,314.231 173.692,311.259 173.692,311.247 174.105,310.834 174.117,310.834 174.321,310.63 175.306,310.63 175.513,310.423 175.513,309.888 175.745,309.656 175.796,309.656 175.8,309.652 176.848,309.652 177.909,310.713 v1(177.909,311.027)
DDR4_DQ46: U1.T26 U9.D3 | length 29.1
  L1 w0.116: v3(170.472,330.057) U9.D3@170.876,330.46 ; v1(176.909,314.027) U1.T26@177.397,313.539
  L12 (Sign) w0.092: v3(170.472,330.057) 170.482,330.047 170.785,330.047 170.953,329.88 171.169,329.88 171.794,329.254 171.794,325.62 171.874,325.541 ccw(c171.953,325.62) 172.032,325.541 172.101,325.609 cw(c172.18,325.53) 172.259,325.609 172.417,325.451 cw(c172.338,325.372) 172.417,325.293 172.269,325.145 171.828,324.703 ccw(c171.907,324.624) 171.828,324.545 171.986,324.386 ccw(c172.065,324.465) 172.144,324.386 172.586,324.828 172.734,324.976 cw(c172.813,324.897) 172.892,324.976 173.051,324.818 cw(c172.971,324.739) 173.051,324.659 172.903,324.511 172.403,324.012 ccw(c172.482,323.933) 172.403,323.854 172.562,323.695 ccw(c172.641,323.775) 172.72,323.695 173.219,324.195 173.367,324.343 cw(c173.446,324.264) 173.526,324.343 173.684,324.184 cw(c173.605,324.105) 173.684,324.026 173.536,323.878 173.037,323.379 ccw(c173.116,323.3) 173.037,323.22 173.195,323.062 ccw(c173.274,323.141) 173.353,323.062 173.853,323.562 174.001,323.71 cw(c174.08,323.63) 174.159,323.71 174.317,323.551 cw(c174.238,323.472) 174.317,323.393 174.169,323.245 173.67,322.746 ccw(c173.749,322.666) 173.67,322.587 173.828,322.429 ccw(c173.907,322.508) 173.986,322.429 174.486,322.928 174.7,323.142 cw(c174.779,323.063) 174.858,323.142 175.016,322.984 cw(c174.937,322.905) 175.016,322.825 174.882,322.691 ccw(c174.961,322.612) 174.882,322.532 175.235,322.179 175.248,322.166 175.248,321.379 175.397,321.23 175.397,315.539 v1(176.909,314.027)
DDR4_DQ47: U1.P24 U9.D4 | length 32.2
  L1 w0.116: U9.D4@167.676,330.46 v3(168.079,330.057) ; v1(174.909,312.027) U1.P24@175.397,311.539
  L12 (Sign) w0.092: v3(168.079,330.057) 167.676,329.653 167.676,325.704 167.676,325.501 cw(c167.551,325.501) 167.551,325.376 167.434,325.376 ccw(c167.434,325.252) 167.31,325.252 167.31,325.003 ccw(c167.434,325.003) 167.434,324.878 167.676,324.878 168.725,324.878 cw(c168.725,324.753) 168.85,324.753 168.85,324.504 cw(c168.725,324.504) 168.725,324.379 167.8,324.379 ccw(c167.8,324.255) 167.676,324.255 167.676,324.13 167.764,324.042 ccw(c167.852,324.13) 167.94,324.042 167.948,324.049 cw(c168.036,323.961) 168.124,324.049 168.3,323.873 cw(c168.212,323.785) 168.3,323.697 168.205,323.601 168.109,323.505 ccw(c168.197,323.417) 168.109,323.329 168.285,323.153 ccw(c168.373,323.241) 168.461,323.153 168.557,323.249 168.653,323.344 cw(c168.741,323.256) 168.829,323.344 169.005,323.168 cw(c168.917,323.08) 169.005,322.992 168.91,322.896 168.814,322.8 ccw(c168.902,322.712) 168.814,322.624 168.99,322.448 ccw(c169.078,322.536) 169.167,322.448 169.262,322.543 169.358,322.639 cw(c169.446,322.551) 169.534,322.639 169.71,322.463 cw(c169.622,322.375) 169.71,322.287 169.615,322.191 169.519,322.095 ccw(c169.607,322.007) 169.519,321.919 169.695,321.743 ccw(c169.784,321.831) 169.872,321.743 169.967,321.838 170.063,321.934 cw(c170.151,321.846) 170.239,321.934 170.416,321.758 cw(c170.327,321.67) 170.416,321.581 170.32,321.486 170.224,321.39 ccw(c170.312,321.302) 170.224,321.214 170.401,321.037 ccw(c170.489,321.126) 170.577,321.037 170.672,321.133 170.768,321.229 cw(c170.856,321.141) 170.944,321.229 171.121,321.053 cw(c171.033,320.964) 171.121,320.876 171.025,320.781 170.929,320.685 ccw(c171.018,320.597) 170.929,320.509 171.106,320.332 ccw(c171.194,320.421) 171.282,320.332 171.378,320.428 171.473,320.524 cw(c171.561,320.436) 171.65,320.524 171.826,320.347 cw(c171.738,320.259) 171.826,320.171 171.73,320.075 171.635,319.98 ccw(c171.723,319.892) 171.635,319.804 171.811,319.627 ccw(c171.899,319.715) 171.987,319.627 171.995,319.635 cw(c172.083,319.547) 172.171,319.635 172.344,319.461 172.892,318.913 172.892,318.789 ccw(c173.017,318.789) 173.017,318.664 173.415,318.664 cw(c173.415,318.539) 173.539,318.539 173.539,318.29 cw(c173.415,318.29) 173.415,318.165 172.892,318.165 172.648,318.165 ccw(c172.648,318.041) 172.524,318.041 172.524,317.792 ccw(c172.648,317.792) 172.648,317.667 172.768,317.667 cw(c172.768,317.542) 172.892,317.542 172.892,316.903 172.892,316.59 173.077,316.405 173.077,315.134 174.033,314.178 174.033,312.2 174.205,312.027 v1(174.909,312.027)
DDR4_DQ48: U1.U26 U11.G2 | length 29.3
  L1 w0.116: v2(177.91,314.027) U1.U26@178.397,313.539 ; U11.G2@183.136,332.86 v2(183.54,332.457)
  L3 (Sign) w0.092: v2(177.91,314.027) 177.875,314.062 177.875,315.495 177.001,316.369 177.001,316.841 178.003,317.843 178.003,318.452 183.466,323.916 183.466,328.874 183.212,329.129 183.212,330.646 182.591,331.267 181.813,331.267 cw(c181.813,331.572) 181.508,331.572 181.508,332.13 ccw(c181.318,332.13) 181.318,332.321 180.823,332.321 cw(c180.823,332.475) 180.668,332.475 180.668,332.726 cw(c180.823,332.726) 180.823,332.88 180.835,332.88 180.915,332.88 ccw(c180.915,332.999) 181.034,332.999 181.034,333.006 cw(c181.153,333.006) 181.153,333.125 181.312,333.125 cw(c181.312,333.006) 181.431,333.006 181.431,332.999 ccw(c181.55,332.999) 181.55,332.88 181.839,332.88 182.155,332.88 cw(c182.155,332.688) 182.347,332.688 182.347,332.181 ccw(c182.474,332.181) 182.474,332.054 183.403,332.054 ccw(c183.403,332.192) 183.54,332.192 v2(183.54,332.457) ; v2(183.54,332.457) v2@183.54,332.464
DDR4_DQ49: U1.V26 U11.F4 | length 28.9
  L1 w0.116: U11.F4@179.136,332.06 179.533,331.664 v2(179.533,331.662) ; U1.V26@179.397,313.539 v2(179.884,314.027)
  L3 (Sign) w0.092: v2(179.533,331.662) 179.533,331.657 179.794,331.657 cw(c179.794,331.541) 179.909,331.541 179.909,330.924 ccw(c180.062,330.924) 180.062,330.772 180.141,330.772 ccw(c180.141,330.891) 180.26,330.891 180.26,330.923 cw(c180.379,330.923) 180.379,331.042 180.538,331.042 cw(c180.538,330.923) 180.657,330.923 180.657,330.772 180.657,330.62 ccw(c180.776,330.62) 180.776,330.501 180.935,330.501 ccw(c180.935,330.62) 181.054,330.62 181.054,330.652 cw(c181.173,330.652) 181.173,330.772 181.316,330.772 182.538,330.772 182.828,330.482 182.828,328.97 183.058,328.739 183.058,324.1 179.478,320.521 179.478,320.517 178.95,319.988 178.945,319.988 177.597,318.639 177.597,317.98 176.617,317 176.617,316.138 177.491,315.264 177.491,314.333 177.397,314.239 177.397,313.814 177.775,313.436 178.435,313.436 178.676,313.677 179.535,313.677 v2(179.884,314.027)
DDR4_DQ50: U1.U28 U11.H3 | length 28.8
  L1 w0.116: U1.U28@178.397,315.539 v2(178.884,315.052) ; U11.H3@182.336,333.66 v2(182.74,333.257)
  L3 (Sign) w0.092: v2(178.884,315.052) 179.397,315.565 179.397,316.049 179.531,316.183 179.755,316.407 ccw(c179.699,316.464) 179.755,316.52 179.58,316.695 cw(c179.637,316.751) 179.58,316.807 179.749,316.975 cw(c179.805,316.919) 179.861,316.975 180.092,316.744 181.101,315.736 ccw(c181.157,315.792) 181.213,315.736 181.382,315.904 ccw(c181.325,315.96) 181.382,316.016 180.429,316.969 cw(c180.485,317.025) 180.429,317.081 180.513,317.165 180.513,318.11 180.751,318.348 181.126,318.348 185.343,322.565 185.343,332.829 184.762,333.411 184.111,333.411 183.752,333.77 183.246,333.77 182.74,333.264 v2(182.74,333.257)
DDR4_DQ51: U1.V27 U11.H4 | length 28.5
  L1 w0.116: v2(178.91,314.052) U1.V27@179.397,314.539 ; U11.H4@179.136,333.66 v2(179.54,333.257)
  L3 (Sign) w0.092: v2(178.91,314.052) 178.884,314.026 178.529,314.026 178.208,313.706 177.777,313.706 177.589,313.894 177.589,314.16 177.683,314.254 177.683,315.344 176.809,316.218 176.809,316.92 177.789,317.9 177.789,318.56 179.025,319.796 179.029,319.796 179.67,320.437 179.67,320.442 183.274,324.045 183.274,328.795 183.02,329.049 183.02,330.561 182.617,330.963 181.316,330.963 181.064,331.216 180.895,331.384 cw(c180.98,331.469) 180.895,331.553 180.968,331.625 ccw(c180.884,331.71) 180.968,331.794 180.856,331.906 ccw(c180.771,331.822) 180.687,331.906 180.53,331.749 180.434,331.653 cw(c180.35,331.738) 180.266,331.653 180.154,331.766 cw(c180.238,331.85) 180.154,331.934 180.166,331.946 ccw(c180.081,332.03) 180.166,332.114 180.109,332.17 179.87,332.41 179.87,332.926 ccw(c179.54,332.926) v2(179.54,333.257) v2@179.54,333.261
DDR4_DQ52: U1.U30 U11.H2 | length 26
  L1 w0.116: U1.U30@178.397,317.539 v2(178.884,318.027) ; U11.H2@183.136,333.66 v2(183.54,333.257)
  L3 (Sign) w0.092: v2(178.884,318.027) 179.102,318.027 179.349,318.274 179.411,318.335 ccw(c179.349,318.396) 179.411,318.457 179.401,318.467 cw(c179.462,318.528) 179.401,318.59 179.523,318.712 cw(c179.585,318.651) 179.646,318.712 179.717,318.641 179.787,318.57 ccw(c179.849,318.631) 179.91,318.57 180.032,318.693 ccw(c179.971,318.754) 180.032,318.815 179.961,318.886 179.891,318.957 cw(c179.952,319.018) 179.891,319.079 180.013,319.202 cw(c180.074,319.14) 180.135,319.202 180.206,319.131 180.277,319.06 ccw(c180.338,319.121) 180.399,319.06 180.522,319.182 ccw(c180.461,319.243) 180.522,319.305 180.451,319.375 180.38,319.446 cw(c180.441,319.508) 180.38,319.569 180.503,319.691 cw(c180.564,319.63) 180.625,319.691 180.696,319.62 180.767,319.549 ccw(c180.828,319.611) 180.889,319.549 181.011,319.672 ccw(c180.95,319.733) 181.011,319.794 180.941,319.865 180.87,319.936 cw(c180.931,319.997) 180.87,320.058 180.992,320.181 cw(c181.053,320.12) 181.115,320.181 181.185,320.11 181.256,320.039 ccw(c181.317,320.1) 181.379,320.039 181.501,320.161 ccw(c181.44,320.223) 181.501,320.284 181.43,320.355 181.359,320.426 cw(c181.421,320.487) 181.359,320.548 181.482,320.67 cw(c181.543,320.609) 181.604,320.67 181.675,320.599 181.746,320.529 ccw(c181.807,320.59) 181.868,320.529 181.991,320.651 ccw(c181.929,320.712) 181.991,320.773 181.92,320.844 181.849,320.915 cw(c181.91,320.976) 181.849,321.038 181.971,321.16 cw(c182.033,321.099) 182.094,321.16 182.165,321.089 182.235,321.018 ccw(c182.297,321.079) 182.358,321.018 182.48,321.141 ccw(c182.419,321.202) 182.48,321.263 182.471,321.273 cw(c182.532,321.334) 182.471,321.395 182.563,321.487 183.968,322.892 184.478,322.892 184.959,323.373 184.959,327.605 184.841,327.724 184.841,328.142 ccw(c184.544,328.142) 184.544,328.439 184.526,328.439 cw(c184.526,328.828) 184.136,328.828 184.136,328.933 cw(c184.468,328.933) 184.468,329.264 184.586,329.264 ccw(c184.586,329.552) 184.874,329.552 184.874,330.67 ccw(c184.64,330.67) 184.64,330.904 184.256,330.904 cw(c184.256,331.047) 184.112,331.047 184.112,331.491 cw(c184.307,331.491) 184.307,331.686 184.709,331.686 ccw(c184.709,331.864) 184.887,331.864 184.887,332.29 ccw(c184.703,332.29) 184.703,332.473 184.188,332.473 cw(c184.188,332.626) 184.036,332.626 184.036,332.761 v2(183.54,333.257)
DDR4_DQ53: U1.V30 U11.H5 | length 26.1
  L1 w0.116: U11.H5@178.336,333.66 v2(178.74,334.064) ; U1.V30@179.397,317.539 v2(179.884,318.027)
  L3 (Sign) w0.092: v2(178.74,334.064) 179.143,333.66 179.66,333.66 179.933,333.388 179.943,333.388 180.139,333.388 ccw(c180.139,333.518) 180.269,333.518 180.269,333.574 cw(c180.399,333.574) 180.399,333.704 180.79,333.704 cw(c180.79,333.574) 180.92,333.574 180.92,333.518 ccw(c181.05,333.518) 181.05,333.388 181.458,333.388 182.155,333.388 182.607,332.936 182.873,332.936 183.061,333.124 183.061,333.269 183.37,333.578 183.673,333.578 184.031,333.219 184.682,333.219 185.151,332.75 185.151,323.294 v2(179.884,318.027)
DDR4_DQ54: U1.W30 U11.J3 | length 25.7
  L1 w0.116: U1.W30@180.397,317.539 v2(180.884,318.027) ; v2(181.933,334.057) U11.J3@182.336,334.46
  L3 (Sign) w0.092: v2(180.884,318.027) 180.913,318.056 181.34,318.056 183.159,319.875 183.935,320.651 cw(c183.991,320.595) 184.048,320.651 184.083,320.615 ccw(c184.139,320.671) 184.196,320.615 184.364,320.784 ccw(c184.308,320.84) 184.364,320.896 184.272,320.988 184.219,321.04 cw(c184.276,321.097) 184.219,321.153 184.388,321.321 cw(c184.444,321.265) 184.5,321.321 184.553,321.268 184.645,321.177 ccw(c184.701,321.233) 184.757,321.177 184.925,321.345 ccw(c184.869,321.401) 184.925,321.457 184.834,321.549 184.781,321.602 cw(c184.837,321.658) 184.781,321.714 184.949,321.883 cw(c185.005,321.826) 185.062,321.883 185.114,321.83 185.206,321.738 ccw(c185.262,321.794) 185.318,321.738 185.487,321.906 ccw(c185.431,321.963) 185.487,322.019 185.451,322.054 cw(c185.507,322.111) 185.451,322.167 185.535,322.251 185.535,332.909 184.841,333.604 184.19,333.604 183.832,333.962 183.166,333.962 182.833,333.629 181.445,333.629 181.241,333.833 181.241,334.027 181.391,334.177 181.813,334.177 v2(181.933,334.057)
DDR4_DQ55: U1.W29 U11.J4 | length 26.2
  L1 w0.116: U11.J4@179.136,334.46 v2(179.54,334.057) ; U1.W29@180.403,316.535 v2(180.891,317.022)
  L3 (Sign) w0.092: v2(179.54,334.057) 179.943,334.46 184.256,334.46 185.727,332.989 185.727,321.859 v2(180.891,317.022)
DDR4_DQ56: U1.R30 U11.A3 | length 19.4
  L1 w0.116: U1.R30@176.397,317.539 v2(176.397,318.229) ; v2(181.937,327.664) 181.94,327.664 U11.A3@182.336,328.06
  L3 (Sign) w0.092: v2(176.397,318.229) 176.446,318.278 176.692,318.278 178.786,320.372 178.791,320.372 179.094,320.676 179.094,320.68 180.95,322.535 180.95,322.643 180.95,322.839 ccw(c180.819,322.839) 180.819,322.969 180.529,322.969 cw(c180.529,323.099) 180.399,323.099 180.399,323.49 cw(c180.529,323.49) 180.529,323.62 180.95,323.62 181.37,323.62 ccw(c181.37,323.75) 181.5,323.75 181.5,324.141 ccw(c181.37,324.141) 181.37,324.271 180.95,324.271 180.529,324.271 cw(c180.529,324.401) 180.399,324.401 180.399,324.792 cw(c180.529,324.792) 180.529,324.922 180.95,324.922 181.37,324.922 ccw(c181.37,325.052) 181.5,325.052 181.5,325.443 ccw(c181.37,325.443) 181.37,325.573 180.95,325.573 180.529,325.573 cw(c180.529,325.703) 180.399,325.703 180.399,326.094 cw(c180.529,326.094) 180.529,326.224 180.95,326.224 181.37,326.224 ccw(c181.37,326.354) 181.5,326.354 181.5,326.745 ccw(c181.37,326.745) 181.37,326.875 181.08,326.875 cw(c181.08,327.005) 180.95,327.005 180.95,327.393 180.95,327.406 181.208,327.664 v2(181.937,327.664)
DDR4_DQ57: U1.T30 U11.B5 | length 18.9
  L1 w0.116: v2(176.91,318.027) U1.T30@177.397,317.539 ; U11.B5@178.336,328.86 v2(178.733,328.462)
  L3 (Sign) w0.092: v2(176.91,318.027) 176.446,317.563 175.874,317.563 175.514,317.924 175.514,318.275 176.023,318.783 176.655,318.783 179.464,321.592 179.464,322.351 179.464,323.598 ccw(c179.354,323.598) 179.354,323.708 179.239,323.708 cw(c179.239,323.818) 179.129,323.818 179.129,324.147 cw(c179.239,324.147) 179.239,324.257 179.464,324.257 179.637,324.257 ccw(c179.637,324.367) 179.746,324.367 179.746,324.697 ccw(c179.637,324.697) 179.637,324.807 179.464,324.807 179.239,324.807 cw(c179.239,324.916) 179.129,324.916 179.129,325.246 cw(c179.239,325.246) 179.239,325.356 179.464,325.356 179.637,325.356 ccw(c179.637,325.466) 179.746,325.466 179.746,325.796 ccw(c179.637,325.796) 179.637,325.905 179.464,325.905 179.239,325.905 cw(c179.239,326.015) 179.129,326.015 179.129,326.345 cw(c179.239,326.345) 179.239,326.455 179.464,326.455 179.637,326.455 ccw(c179.637,326.565) 179.746,326.565 179.746,326.894 ccw(c179.637,326.894) 179.637,327.004 179.574,327.004 cw(c179.574,327.114) 179.464,327.114 179.464,327.279 178.733,328.01 v2(178.733,328.462)
DDR4_DQ58: U1.P30 U11.C3 | length 19
  L1 w0.116: U1.P30@175.397,317.539 v2(175.884,318.027) ; v2(181.937,329.264) 181.94,329.264 U11.C3@182.336,329.66
  L3 (Sign) w0.092: v2(175.884,318.027) 175.884,318.339 176.136,318.591 176.734,318.591 178.707,320.564 178.711,320.564 178.902,320.755 178.902,320.76 179.959,321.816 179.959,327.139 179.959,327.577 cw(c180.069,327.577) 180.069,327.687 180.448,327.687 ccw(c180.448,327.797) 180.558,327.797 180.558,328.126 ccw(c180.448,328.126) 180.448,328.236 180.069,328.236 cw(c180.069,328.346) 179.959,328.346 179.959,328.511 179.959,329.105 180.118,329.264 180.283,329.264 ccw(c180.283,329.374) 180.393,329.374 180.393,329.611 cw(c180.503,329.611) 180.503,329.721 180.832,329.721 cw(c180.832,329.611) 180.942,329.611 180.942,329.264 180.942,328.917 ccw(c181.052,328.917) 181.052,328.807 181.382,328.807 ccw(c181.382,328.917) 181.492,328.917 181.492,329.154 cw(c181.602,329.154) 181.602,329.264 v2(181.937,329.264)
DDR4_DQ59: U1.P29 U11.C4 | length 19.6
  L1 w0.116: v2(174.91,317.027) U1.P29@175.397,316.539 ; v2@178.74,330.057 U11.C4@179.136,329.66
  L3 (Sign) w0.092: v2(174.91,317.027) 174.884,317.052 174.884,317.556 175.119,317.791 175.119,318.469 175.828,319.178 176.506,319.178 177.825,320.497 177.825,322.77 177.825,322.987 ccw(c177.716,322.987) 177.716,323.097 177.596,323.097 cw(c177.596,323.207) 177.486,323.207 177.486,323.537 cw(c177.596,323.537) 177.596,323.647 177.825,323.647 178.055,323.647 ccw(c178.055,323.757) 178.165,323.757 178.165,324.086 ccw(c178.055,324.086) 178.055,324.196 177.825,324.196 177.596,324.196 cw(c177.596,324.306) 177.486,324.306 177.486,324.636 cw(c177.596,324.636) 177.596,324.745 177.825,324.745 178.055,324.745 ccw(c178.055,324.855) 178.165,324.855 178.165,325.185 ccw(c178.055,325.185) 178.055,325.295 177.935,325.295 cw(c177.935,325.405) 177.825,325.405 177.825,325.57 178.219,325.963 178.219,326.128 ccw(c178.109,326.128) 178.109,326.238 177.964,326.238 cw(c177.964,326.348) 177.854,326.348 177.854,326.677 cw(c177.964,326.677) 177.964,326.787 178.219,326.787 178.413,326.787 ccw(c178.413,326.897) 178.522,326.897 178.522,327.227 ccw(c178.413,327.227) 178.413,327.337 178.329,327.337 cw(c178.329,327.447) 178.219,327.447 178.219,327.749 178.219,329.136 178.74,329.656 v2@178.74,330.057
  other v2: 178.74,330.059
DDR4_DQ60: U1.T28 U11.C2 | length 20.4
  L1 w0.116: U1.T28@177.397,315.539 v2(177.884,316.027) ; U11.C2@183.136,329.66 v2(183.533,329.262) v2(183.533,329.262)
  L3 (Sign) w0.092: v2(177.884,316.027) 177.884,315.772 178.118,315.539 178.118,315.024 ccw(c178.27,315.024) 178.27,314.871 178.397,314.871 ccw(c178.397,315.024) 178.549,315.024 178.549,315.633 178.41,315.773 178.41,316.116 178.41,316.202 ccw(c178.323,316.202) 178.323,316.289 178.072,316.289 cw(c178.072,316.375) 177.985,316.375 177.985,316.548 cw(c178.072,316.548) 178.072,316.635 178.323,316.635 ccw(c178.323,316.722) 178.41,316.722 178.41,316.916 178.41,317.498 178.206,317.701 178.206,318.352 183.709,323.855 183.709,329.085 v2(183.533,329.262)
DDR4_DQ61: U1.T27 U11.C5 | length 21
  L1 w0.116: v2(176.91,315.027) U1.T27@177.397,314.539 ; v2@177.94,330.057 U11.C5@178.336,329.66
  L3 (Sign) w0.092: v2(176.91,315.027) 176.589,314.706 175.777,314.706 175.33,315.152 174.224,315.152 174.001,315.375 174.001,315.381 173.988,315.394 173.988,316.016 173.809,316.195 173.809,318.081 176.109,320.381 176.109,324.852 177.47,326.213 177.47,328.93 177.94,329.399 v2@177.94,330.057
  other v2: 177.94,330.059
DDR4_DQ62: U1.P27 U11.D3 | length 22.8
  L1 w0.116: U1.P27@175.397,314.539 v2(175.884,314.052) ; v2(181.937,330.064) 181.94,330.064 U11.D3@182.336,330.46
  L3 (Sign) w0.092: v2(175.884,314.052) 176.346,314.514 176.668,314.514 176.706,314.552 177.138,314.552 177.299,314.713 177.299,315.182 176.403,316.078 176.403,317.036 176.425,317.058 176.425,317.079 177.405,318.059 177.405,318.719 178.866,320.18 178.87,320.18 179.286,320.596 179.286,320.601 182.266,323.58 182.266,323.875 182.266,324.663 182.266,325.61 ccw(c182.136,325.61) 182.136,325.74 181.908,325.74 cw(c181.908,325.871) 181.778,325.871 181.778,326.261 cw(c181.908,326.261) 181.908,326.391 182.266,326.391 182.624,326.391 ccw(c182.624,326.522) 182.754,326.522 182.754,326.912 ccw(c182.624,326.912) 182.624,327.042 182.396,327.042 cw(c182.396,327.173) 182.266,327.173 182.266,327.368 182.266,329.735 v2(181.937,330.064)
DDR4_DQ63: U1.R27 U11.D4 | length 22.1
  L1 w0.116: v2(175.91,315.027) U1.R27@176.397,314.539 ; U11.D4@179.136,330.46 179.533,330.857 v2(179.535,330.857)
  L3 (Sign) w0.092: 175.514,315.862 175.514,315.422 v2(175.91,315.027) ; 175.514,315.863 175.514,317.577 175.311,317.779 175.311,318.389 175.908,318.986 176.586,318.986 178.714,321.115 178.714,321.279 cw(c178.824,321.279) 178.824,321.389 178.914,321.389 ccw(c178.914,321.499) 179.024,321.499 179.024,321.829 ccw(c178.914,321.829) 178.914,321.939 178.714,321.939 178.447,321.939 cw(c178.447,322.049) 178.337,322.049 178.337,322.378 cw(c178.447,322.378) 178.447,322.488 178.714,322.488 178.982,322.488 ccw(c178.982,322.598) 179.092,322.598 179.092,322.928 ccw(c178.982,322.928) 178.982,323.038 178.714,323.038 178.447,323.038 cw(c178.447,323.147) 178.337,323.147 178.337,323.477 cw(c178.447,323.477) 178.447,323.587 178.605,323.587 ccw(c178.605,323.697) 178.714,323.697 178.714,325.374 178.714,326.123 178.714,327.532 178.412,327.835 178.412,328.729 179.535,329.852 v2(179.535,330.857)
DDR4_DQS_0_N: U1.AK21 U8.F3 | length 45.3
  L1 w0.116: U1.AK21@191.397,308.539 v5(191.884,308.052) ; v3(204.853,332.464) U8.F3@205.257,332.06
  L14 (Sign) w0.105: v5(191.884,308.052) 191.677,308.052 cw(c191.677,308.229) 191.5,308.229 191.5,309.207 191.5,309.33 cw(c191.582,309.33) 191.582,309.412 191.648,309.412 ccw(c191.648,309.494) 191.73,309.494 191.73,309.74 ccw(c191.648,309.74) 191.648,309.822 191.582,309.822 cw(c191.582,309.904) 191.5,309.904 191.5,310.363 191.5,315.274 cw(c194.04,315.274) 192.244,317.07 192.807,317.632 ccw(c192.5,317.939) 192.934,317.939 ccw(c192.5,317.939) 192.807,318.246 192.727,318.326 cw(c192.87,318.468) 192.727,318.611 192.84,318.723 cw(c192.982,318.581) 193.125,318.723 193.733,318.115 ccw(c194.04,318.422) 194.347,318.115 194.459,318.227 ccw(c194.153,318.534) 194.587,318.534 ccw(c194.153,318.534) 194.459,318.841 193.851,319.45 cw(c193.994,319.592) 193.851,319.735 193.964,319.847 cw(c194.106,319.705) 194.249,319.847 194.857,319.239 ccw(c195.164,319.546) 195.471,319.239 195.583,319.351 ccw(c195.277,319.658) 195.71,319.658 ccw(c195.277,319.658) 195.583,319.965 194.975,320.573 ; 194.975,320.859 195.088,320.971 cw(c195.23,320.828) 195.373,320.971 195.981,320.363 ccw(c196.288,320.67) 196.595,320.363 196.707,320.475 ccw(c196.4,320.782) 196.834,320.782 ccw(c196.4,320.782) 196.707,321.089 196.099,321.697 ; 194.975,320.573 cw(c195.118,320.716) 194.975,320.859 ; 196.099,321.982 196.211,322.095 cw(c196.354,321.952) 196.497,322.095 197.105,321.487 ccw(c197.412,321.793) 197.719,321.487 197.831,321.599 ccw(c197.524,321.906) 197.958,321.906 ccw(c197.524,321.906) 197.831,322.213 197.223,322.821 ; 196.099,321.697 cw(c196.242,321.84) 196.099,321.983 ; 197.223,323.106 197.335,323.219 cw(c197.478,323.076) 197.621,323.219 198.229,322.611 ccw(c198.536,322.917) 198.843,322.611 198.955,322.723 ccw(c198.648,323.03) 199.082,323.03 ccw(c198.648,323.03) 198.955,323.337 198.875,323.416 cw(c199.018,323.559) 198.876,323.701 199.652,324.478 cw(c201.448,322.682) 201.448,325.222 201.461,325.222 ccw(c201.461,327.711) 203.222,325.951 203.257,325.986 ccw(c201.301,327.942) 204.067,327.942 204.067,332.324 cw(c204.495,332.324) 204.495,332.753 204.565,332.753 cw(c204.565,332.464) v3(204.853,332.464) ; 197.223,322.821 cw(c197.366,322.964) 197.223,323.107
DDR4_DQS_0_P: U1.AJ21 U8.G3 | length 45.3
  L1 w0.116: U1.AJ21@190.397,308.539 v5(190.884,308.052) ; v3(204.853,333.264) U8.G3@205.257,332.86
  L14 (Sign) w0.105: v5(190.884,308.052) 191.091,308.052 ccw(c191.091,308.229) 191.268,308.229 191.268,315.275 cw(c194.039,315.275) 192.08,317.234 192.643,317.797 ccw(c192.5,317.939) 192.702,317.939 ccw(c192.5,317.939) 192.642,318.082 192.563,318.161 cw(c192.87,318.468) 192.563,318.775 192.675,318.887 cw(c192.982,318.581) 193.289,318.887 193.898,318.279 ccw(c194.04,318.422) 194.183,318.279 194.296,318.392 ; 194.295,318.391 ccw(c194.153,318.534) 194.354,318.534 ccw(c194.153,318.534) 194.295,318.677 ; 194.296,318.677 193.687,319.285 cw(c193.994,319.592) 193.687,319.899 193.799,320.011 cw(c194.106,319.705) 194.413,320.011 195.021,319.403 ccw(c195.164,319.546) 195.307,319.403 195.419,319.516 ; 195.419,319.515 ccw(c195.277,319.658) 195.478,319.658 ccw(c195.277,319.658) 195.419,319.801 ; 195.419,319.801 194.811,320.409 cw(c195.118,320.716) 194.811,321.023 194.923,321.135 cw(c195.23,320.828) 195.537,321.135 196.145,320.527 ccw(c196.288,320.67) 196.431,320.527 196.543,320.639 ccw(c196.4,320.782) 196.602,320.782 ccw(c196.4,320.782) 196.543,320.925 ; 196.543,320.924 195.935,321.533 cw(c196.242,321.84) 195.935,322.147 196.047,322.259 cw(c196.354,321.952) 196.661,322.259 197.269,321.651 ccw(c197.412,321.793) 197.555,321.651 197.667,321.763 ccw(c197.524,321.906) 197.726,321.906 ccw(c197.524,321.906) 197.667,322.049 197.059,322.657 cw(c197.366,322.964) 197.059,323.271 197.171,323.383 cw(c197.478,323.076) 197.785,323.383 198.393,322.775 ccw(c198.536,322.917) 198.679,322.775 198.791,322.887 ccw(c198.648,323.03) 198.85,323.03 ccw(c198.648,323.03) 198.791,323.172 198.712,323.252 cw(c199.018,323.559) 198.712,323.866 199.488,324.642 cw(c201.447,322.683) 201.447,325.454 201.46,325.454 ccw(c201.46,327.714) 203.058,326.116 203.091,326.149 ccw(c201.295,327.945) 203.835,327.945 203.835,332.324 cw(c204.495,332.324) 204.495,332.985 204.574,332.985 ccw(c204.574,333.264) v3(204.853,333.264)
DDR4_DQS_1_N: U1.AJ24 U8.A4 | length 31.6
  L1 w0.116: U1.AJ24@190.397,311.539 v5(190.884,312.027) ; U8.A4@202.057,328.06 v3(202.461,327.657)
  L14 (Sign) w0.105: v5(190.884,312.027) 190.649,312.027 cw(c190.649,312.175) 190.5,312.175 190.5,315.455 190.5,315.635 190.5,315.904 cw(c190.59,315.904) 190.59,315.994 190.676,315.994 ccw(c190.676,316.084) 190.766,316.084 190.766,316.264 ccw(c190.676,316.264) 190.676,316.354 190.59,316.354 cw(c190.59,316.444) 190.5,316.444 190.5,316.514 190.5,317.236 cw(c193.04,317.236) 191.244,319.032 191.483,319.27 ccw(c191.222,319.532) 191.591,319.532 ccw(c191.222,319.532) 191.483,319.793 191.422,319.854 cw(c191.519,319.951) 191.422,320.049 191.661,320.288 cw(c191.758,320.191) 191.856,320.288 192.336,319.807 ccw(c192.598,320.069) 192.859,319.807 193.098,320.046 ccw(c192.837,320.308) 193.207,320.308 ccw(c192.837,320.308) 193.098,320.569 192.618,321.05 cw(c192.715,321.147) 192.618,321.244 192.857,321.484 cw(c192.954,321.386) 193.052,321.484 193.532,321.003 ccw(c193.793,321.265) 194.055,321.003 194.294,321.242 ccw(c194.033,321.504) 194.402,321.504 ccw(c194.033,321.504) 194.294,321.765 193.814,322.246 cw(c193.911,322.343) 193.814,322.44 194.053,322.679 cw(c194.15,322.582) 194.247,322.679 194.728,322.199 ccw(c194.989,322.46) 195.251,322.199 195.49,322.438 ccw(c195.228,322.699) 195.598,322.699 ccw(c195.228,322.699) 195.49,322.961 195.009,323.441 cw(c195.107,323.539) 195.009,323.636 195.248,323.875 cw(c195.346,323.778) 195.443,323.875 195.923,323.395 ccw(c196.185,323.656) 196.446,323.395 196.686,323.634 ccw(c196.424,323.895) 196.794,323.895 ccw(c196.424,323.895) 196.686,324.157 196.625,324.217 cw(c196.722,324.315) 196.625,324.412 199.383,327.17 cw(c201.179,325.374) 201.179,327.914 202.203,327.914 cw(c202.203,327.657) v3(202.461,327.657)
DDR4_DQS_1_P: U1.AH24 U8.B4 | length 31.6
  L1 w0.116: U1.AH24@189.397,311.539 v5(189.884,312.027) ; U8.B4@202.057,328.86 v3(202.461,328.457)
  L14 (Sign) w0.105: v5(189.884,312.027) 190.12,312.027 ccw(c190.12,312.175) 190.268,312.175 190.268,316.514 190.268,317.236 cw(c193.039,317.236) 191.08,319.195 191.319,319.435 ccw(c191.222,319.532) 191.359,319.532 ccw(c191.222,319.532) 191.319,319.629 191.258,319.69 cw(c191.519,319.951) 191.258,320.213 191.497,320.452 cw(c191.758,320.191) 192.02,320.452 192.5,319.971 ccw(c192.598,320.069) 192.695,319.971 192.934,320.211 ccw(c192.837,320.308) 192.974,320.308 ccw(c192.837,320.308) 192.934,320.405 192.454,320.886 cw(c192.715,321.147) 192.454,321.409 192.693,321.648 cw(c192.954,321.386) 193.216,321.648 193.696,321.167 ccw(c193.793,321.265) 193.891,321.167 194.13,321.406 ccw(c194.033,321.504) 194.17,321.504 ccw(c194.033,321.504) 194.13,321.601 193.649,322.081 cw(c193.911,322.343) 193.649,322.604 193.889,322.843 cw(c194.15,322.582) 194.411,322.843 194.892,322.363 ccw(c194.989,322.46) 195.086,322.363 195.326,322.602 ccw(c195.228,322.699) 195.366,322.699 ccw(c195.228,322.699) 195.326,322.797 194.845,323.277 cw(c195.107,323.539) 194.845,323.8 195.084,324.039 cw(c195.346,323.778) 195.607,324.039 196.088,323.559 ccw(c196.185,323.656) 196.282,323.559 196.521,323.798 ccw(c196.424,323.895) 196.562,323.895 ccw(c196.424,323.895) 196.521,323.992 196.46,324.053 cw(c196.722,324.315) 196.46,324.576 199.218,327.334 ; 199.219,327.335 cw(c201.178,325.376) 201.178,328.146 202.15,328.146 ccw(c202.15,328.457) v3(202.461,328.457)
DDR4_DQS_2_N: U1.AD21 U10.F3 | length 41.3
  L1 w0.116: v1(184.909,308.052) U1.AD21@185.397,308.539 ; v3(193.393,331.657) U10.F3@193.797,332.06
  L14 (Sign) w0.105: v1(184.909,308.052) 184.784,308.052 cw(c184.784,308.242) 184.594,308.242 184.594,309.029 cw(c185.855,309.029) 184.964,309.921 186.211,311.168 ccw(c185.422,311.957) 186.538,311.957 186.538,313.271 186.538,313.527 186.538,313.882 cw(c186.694,313.882) 186.694,314.039 ccw(c186.694,314.294) 186.95,314.294 ccw(c186.694,314.294) 186.694,314.55 cw(c186.694,314.706) 186.538,314.706 186.538,315.811 186.538,318.431 cw(c189.078,318.431) 187.282,320.227 187.539,320.485 ccw(c187.204,320.82) 187.678,320.82 ccw(c187.204,320.82) 187.539,321.156 187.231,321.464 cw(c187.402,321.636) 187.231,321.807 187.357,321.934 cw(c187.529,321.762) 187.7,321.934 188.824,320.81 ccw(c189.16,321.146) 189.495,320.81 189.622,320.937 ccw(c189.287,321.272) 189.761,321.272 ccw(c189.287,321.272) 189.622,321.608 188.498,322.732 cw(c188.67,322.903) 188.498,323.075 188.625,323.201 cw(c188.797,323.03) 188.968,323.201 190.092,322.078 ccw(c190.427,322.413) 190.763,322.078 190.89,322.204 ccw(c190.554,322.54) 191.029,322.54 ccw(c190.554,322.54) 190.89,322.876 189.766,323.999 cw(c189.937,324.171) 189.766,324.342 189.893,324.469 cw(c190.064,324.298) 190.236,324.469 191.359,323.345 ccw(c191.695,323.681) 192.031,323.345 192.157,323.472 ccw(c191.822,323.808) 192.296,323.808 ccw(c191.822,323.808) 192.157,324.143 191.849,324.452 cw(c192.02,324.623) 191.849,324.794 192.032,324.977 ccw(c190.548,326.461) 192.646,326.461 192.646,331.457 cw(c193.142,331.457) 193.142,331.953 cw(c193.142,331.701) 193.393,331.701 v3(193.393,331.657)
DDR4_DQS_2_P: U1.AC21 U10.G3 | length 41.3
  L1 w0.116: v1(183.909,308.052) U1.AC21@184.397,308.539 ; v3(193.393,332.457) U10.G3@193.797,332.86
  L14 (Sign) w0.105: v1(183.909,308.052) 184.173,308.052 ccw(c184.173,308.242) 184.362,308.242 184.362,309.03 cw(c185.854,309.03) 184.799,310.084 185.978,311.264 ccw(c185.189,312.053) 186.305,312.053 186.305,318.431 cw(c189.077,318.431) 187.117,320.391 187.375,320.649 ccw(c187.204,320.82) 187.446,320.82 ccw(c187.204,320.82) 187.375,320.992 187.067,321.3 cw(c187.402,321.636) 187.067,321.971 187.193,322.098 cw(c187.529,321.762) 187.865,322.098 188.988,320.974 ccw(c189.16,321.146) 189.331,320.974 189.458,321.101 ccw(c189.287,321.272) 189.529,321.272 ccw(c189.287,321.272) 189.458,321.444 188.334,322.568 cw(c188.67,322.903) 188.334,323.239 188.461,323.366 cw(c188.797,323.03) 189.132,323.366 190.256,322.242 ccw(c190.427,322.413) 190.599,322.242 190.726,322.369 ccw(c190.554,322.54) 190.797,322.54 ccw(c190.554,322.54) 190.726,322.711 189.602,323.835 cw(c189.937,324.171) 189.602,324.506 189.728,324.633 cw(c190.064,324.298) 190.4,324.633 191.524,323.509 ccw(c191.695,323.681) 191.866,323.509 191.993,323.636 ccw(c191.822,323.808) 192.064,323.808 ccw(c191.822,323.808) 191.993,323.979 191.685,324.287 cw(c192.02,324.623) 191.685,324.959 191.867,325.141 ccw(c190.548,326.461) 192.414,326.461 192.414,331.457 cw(c193.142,331.457) 193.142,332.185 ccw(c193.142,332.436) 193.393,332.436 v3(193.393,332.457)
DDR4_DQS_3_N: U1.AE24 U10.A4 | length 28.2
  L1 w0.116: v5(185.909,312.027) U1.AE24@186.397,311.539 ; U10.A4@190.597,328.06 v3(191,327.657)
  L14 (Sign) w0.105: v5(185.909,312.027) 185.71,312.027 cw(c185.71,312.212) 185.526,312.212 185.526,313.271 185.526,313.527 185.526,313.987 cw(c185.577,313.987) 185.577,314.039 185.661,314.039 ccw(c185.661,314.09) 185.712,314.09 185.712,314.499 ccw(c185.661,314.499) 185.661,314.55 185.577,314.55 cw(c185.577,314.601) 185.526,314.601 185.526,315.519 185.526,322.262 cw(c188.066,322.262) 186.27,324.058 186.455,324.244 ccw(c186.106,324.594) 186.6,324.594 ccw(c186.106,324.594) 186.455,324.944 186.181,325.218 cw(c186.367,325.404) 186.181,325.59 186.315,325.724 cw(c186.501,325.538) 186.687,325.724 187.771,324.639 ccw(c188.121,324.989) 188.471,324.639 188.605,324.773 ccw(c188.255,325.123) 188.75,325.123 ccw(c188.255,325.123) 188.605,325.473 187.521,326.558 cw(c187.706,326.743) 187.521,326.929 187.655,327.063 cw(c187.84,326.877) 188.026,327.063 189.111,325.979 ccw(c189.46,326.329) 189.81,325.979 189.944,326.113 ccw(c189.594,326.463) 190.089,326.463 ccw(c189.594,326.463) 189.944,326.813 189.591,327.166 cw(c189.699,327.273) 189.591,327.38 189.71,327.499 cw(c190.805,326.404) 190.805,327.952 cw(c190.805,327.757) 191,327.757 v3(191,327.657)
DDR4_DQS_3_P: U1.AD24 U10.B4 | length 28.2
  L1 w0.116: v5(184.909,312.027) U1.AD24@185.397,311.539 ; U10.B4@190.597,328.86 v3(191,328.457)
  L14 (Sign) w0.105: v5(184.909,312.027) 185.109,312.027 ccw(c185.109,312.212) 185.293,312.212 185.293,322.263 cw(c188.064,322.263) 186.105,324.222 186.291,324.408 ccw(c186.106,324.594) 186.368,324.594 ccw(c186.106,324.594) 186.291,324.78 186.017,325.054 cw(c186.367,325.404) 186.017,325.754 186.151,325.888 cw(c186.501,325.538) 186.851,325.888 187.935,324.803 ccw(c188.121,324.989) 188.307,324.803 188.441,324.937 ccw(c188.255,325.123) 188.518,325.123 ccw(c188.255,325.123) 188.441,325.309 187.356,326.393 cw(c187.706,326.743) 187.356,327.093 187.49,327.227 cw(c187.84,326.877) 188.19,327.227 189.275,326.143 ccw(c189.46,326.329) 189.646,326.143 189.78,326.277 ccw(c189.594,326.463) 189.857,326.463 ccw(c189.594,326.463) 189.78,326.648 189.427,327.001 cw(c189.699,327.273) 189.427,327.544 189.547,327.664 cw(c190.804,326.407) 190.804,328.184 ; 190.805,328.184 ccw(c190.805,328.38) 191,328.38 v3(191,328.457)
DDR4_DQS_4_N: U1.W25 U9.F3 | length 39
  L1 w0.116: v3(170.472,331.657) U9.F3@170.876,332.06 ; v1(179.909,312.052) U1.W25@180.397,312.539
  L14 (Sign) w0.105: v3(170.472,331.657) cw(c170.743,331.657) 170.743,331.927 172.742,331.927 cw(c172.742,330.149) 174.52,330.149 174.52,327.92 ccw(c177.29,327.92) 175.331,325.962 177.799,323.494 178.05,323.243 cw(c177.936,323.129) 178.05,323.015 178.041,323.007 ccw(c178.155,322.893) 178.041,322.778 178.139,322.681 ccw(c178.253,322.795) 178.367,322.681 178.376,322.689 cw(c178.49,322.575) 178.604,322.689 178.653,322.64 cw(c176.857,320.844) 179.397,320.844 179.397,320.639 ccw(c179.755,320.639) 179.755,320.28 180.527,320.28 cw(c180.527,320.154) 180.654,320.154 180.654,319.946 cw(c180.527,319.946) 180.527,319.819 178.498,319.819 ccw(c178.498,319.46) 178.139,319.46 178.139,319.252 ccw(c178.498,319.252) 178.498,318.894 180.527,318.894 cw(c180.527,318.767) 180.654,318.767 180.654,318.559 cw(c180.527,318.559) 180.527,318.433 178.498,318.433 ccw(c178.498,318.074) 178.139,318.074 178.139,317.866 ccw(c178.498,317.866) 178.498,317.508 180.527,317.508 cw(c180.527,317.381) 180.654,317.381 180.654,317.173 cw(c180.527,317.173) 180.527,317.047 179.433,317.047 ccw(c179.433,316.688) 179.075,316.688 179.075,316.48 ccw(c179.433,316.48) 179.397,316.123 179.397,315.721 ccw(c181.057,315.721) 179.883,314.547 179.884,314.546 cw(c178.927,313.589) 180.281,313.589 180.281,312.423 cw(c179.909,312.423) v1(179.909,312.052)
DDR4_DQS_4_P: U1.W24 U9.G3 | length 39
  L1 w0.116: v3(170.472,332.457) U9.G3@170.876,332.86 ; U1.W24@180.397,311.539 v1(180.884,312.027)
  L14 (Sign) w0.105: v3(170.472,332.457) ccw(c170.77,332.457) 170.77,332.159 172.742,332.159 cw(c172.742,330.149) 174.752,330.149 174.752,327.921 ccw(c177.292,327.921) 175.496,326.125 178.817,322.804 cw(c176.859,320.845) 179.629,320.845 179.629,320.639 ccw(c179.755,320.639) 179.755,320.512 180.527,320.512 cw(c180.527,320.154) 180.886,320.154 180.886,319.946 cw(c180.527,319.946) 180.527,319.587 178.498,319.587 ccw(c178.498,319.46) 178.371,319.46 178.371,319.252 ccw(c178.498,319.252) 178.498,319.126 180.527,319.126 cw(c180.527,318.767) 180.886,318.767 180.886,318.559 cw(c180.527,318.559) 180.527,318.201 178.498,318.201 ccw(c178.498,318.074) 178.371,318.074 178.371,317.866 ccw(c178.498,317.866) 178.498,317.74 180.527,317.74 cw(c180.527,317.381) 180.886,317.381 180.886,317.173 cw(c180.527,317.173) 180.527,316.814 179.433,316.814 ccw(c179.433,316.688) 179.307,316.688 179.307,316.48 ccw(c179.433,316.48) 179.433,316.354 cw(c179.433,316.158) 179.629,316.158 179.629,315.723 ccw(c181.062,315.723) 180.048,314.71 180.05,314.708 cw(c178.934,313.591) 180.513,313.591 180.513,312.398 ccw(c180.884,312.398) v1(180.884,312.027)
DDR4_DQS_5_N: U1.R25 U9.A4 | length 30.4
  L1 w0.116: U9.A4@167.676,328.06 v3(168.079,327.657) ; v1(175.909,312.052) U1.R25@176.397,312.539
  L14 (Sign) w0.105: v3(168.079,327.657) cw(c168.324,327.657) 168.324,327.901 168.397,327.901 cw(c168.397,327.368) 168.774,327.745 173.027,323.493 cw(c171.231,321.697) 173.771,321.697 173.771,320.925 cw(c173.675,320.925) 173.675,320.829 172.368,320.829 ccw(c172.368,320.502) 172.041,320.502 172.041,320.079 ccw(c172.368,320.079) 172.368,319.752 175.405,319.752 cw(c175.405,319.656) 175.501,319.656 175.501,319.234 cw(c175.405,319.234) 175.405,319.138 172.592,319.138 ccw(c172.592,318.811) 172.264,318.811 172.264,318.388 ccw(c172.592,318.388) 172.592,318.061 173.675,318.061 cw(c173.675,317.965) 173.771,317.965 173.771,313.478 ccw(c174.32,313.478) 174.32,312.928 174.407,312.928 cw(c174.407,312.151) 174.956,312.7 174.958,312.699 ccw(c175.623,313.364) 175.623,312.423 175.641,312.423 cw(c175.641,312.155) 175.909,312.155 v1(175.909,312.052)
DDR4_DQS_5_P: U1.P25 U9.B4 | length 30.4
  L1 w0.116: U9.B4@167.676,328.86 v3(168.079,328.457) ; U1.P25@175.397,312.539 v1(175.884,313.027)
  L14 (Sign) w0.105: v3(168.079,328.457) 168.079,328.451 ccw(c168.397,328.451) 168.397,328.134 cw(c168.397,327.369) 168.938,327.91 173.191,323.656 cw(c171.233,321.697) 174.003,321.697 174.003,320.925 cw(c173.675,320.925) 173.675,320.597 172.368,320.597 ccw(c172.368,320.502) 172.273,320.502 172.273,320.079 ccw(c172.368,320.079) 172.368,319.984 175.405,319.984 cw(c175.405,319.656) 175.733,319.656 175.733,319.234 cw(c175.405,319.234) 175.405,318.906 172.592,318.906 ccw(c172.592,318.811) 172.496,318.811 172.496,318.388 ccw(c172.592,318.388) 172.592,318.293 173.675,318.293 cw(c173.675,317.965) 174.003,317.965 174.003,313.478 ccw(c174.32,313.478) 174.32,313.16 174.407,313.16 cw(c174.407,312.151) 175.12,312.865 ccw(c175.625,313.369) 175.625,312.655 175.641,312.655 ccw(c175.641,312.899) 175.884,312.899 v1(175.884,313.027)
DDR4_DQS_6_N: U1.V29 U11.F3 | length 26.5
  L1 w0.116: v4(178.91,317.027) U1.V29@179.397,316.539 ; v3(181.933,331.657) U11.F3@182.336,332.06
  L5 (Sign) w0.105: v4(178.91,317.027) 178.745,317.027 cw(c178.745,317.246) 178.526,317.246 178.526,317.677 ccw(c178.125,317.677) 178.125,318.077 177.815,318.077 cw(c177.815,318.245) 177.647,318.245 177.647,318.624 cw(c177.815,318.624) 177.815,318.792 179.004,318.792 ccw(c179.004,319.192) 179.404,319.192 179.404,319.571 ccw(c179.004,319.571) 179.004,319.971 177.815,319.971 cw(c177.815,320.139) 177.647,320.139 177.647,320.518 cw(c177.815,320.518) 177.815,320.686 179.004,320.686 ccw(c179.004,321.086) 179.404,321.086 179.404,321.465 ccw(c179.004,321.465) 179.004,321.865 177.815,321.865 cw(c177.815,322.033) 177.647,322.033 177.647,322.412 cw(c177.815,322.412) 177.815,322.58 178.125,322.58 ccw(c178.125,322.981) 178.526,322.981 178.526,323.632 cw(c179.565,323.632) 179.565,324.672 ccw(c179.565,325.777) 180.67,325.777 180.67,330.835 180.67,331.044 cw(c180.747,331.044) 180.747,331.121 ccw(c180.747,331.199) 180.824,331.199 180.824,331.353 ccw(c180.747,331.353) 180.747,331.43 cw(c180.747,331.507) 180.67,331.507 180.67,331.584 cw(c181.026,331.584) 181.026,331.94 181.65,331.94 cw(c181.65,331.657) v3(181.933,331.657)
DDR4_DQS_6_P: U1.U29 U11.G3 | length 26.6
  L1 w0.116: v2(177.91,317.027) U1.U29@178.397,316.539 ; v3(181.933,332.457) U11.G3@182.336,332.86
  L5 (Sign) w0.105: v2(177.91,317.027) 178.075,317.027 ccw(c178.075,317.245) 178.293,317.245 178.293,317.677 ccw(c178.125,317.677) 178.125,317.845 177.815,317.845 cw(c177.815,318.245) 177.415,318.245 177.415,318.624 cw(c177.815,318.624) 177.815,319.024 179.004,319.024 ccw(c179.004,319.192) 179.172,319.192 179.172,319.571 ccw(c179.004,319.571) 179.004,319.739 177.815,319.739 cw(c177.815,320.139) 177.415,320.139 177.415,320.518 cw(c177.815,320.518) 177.815,320.918 179.004,320.918 ccw(c179.004,321.086) 179.172,321.086 179.172,321.465 ccw(c179.004,321.465) 179.004,321.633 177.815,321.633 cw(c177.815,322.033) 177.415,322.033 177.415,322.412 cw(c177.815,322.412) 177.815,322.812 178.125,322.812 ccw(c178.125,322.981) 178.293,322.981 178.293,323.632 cw(c179.565,323.632) 179.565,324.904 ccw(c179.565,325.777) 180.438,325.777 180.438,331.584 cw(c181.026,331.584) 181.026,332.172 181.648,332.172 ccw(c181.648,332.457) v3@181.933,332.457
  other v4: 177.91,317.027
DDR4_DQS_7_N: U1.R29 U11.A4 | length 19.7
  L1 w0.116: v4(175.91,317.027) U1.R29@176.397,316.539 ; U11.A4@179.136,328.06 v3(179.54,327.657)
  L5 (Sign) w0.105: v4(175.91,317.027) 175.91,317.01 cw(c175.542,317.01) 175.542,316.643 cw(c175.542,317.128) 175.057,317.128 175.057,317.308 175.057,317.541 cw(c175.183,317.541) 175.183,317.667 175.283,317.667 ccw(c175.283,317.793) 175.409,317.793 175.409,317.901 ccw(c175.283,317.901) 175.283,318.026 175.183,318.026 cw(c175.183,318.152) 175.057,318.152 175.057,318.237 175.057,323.254 ccw(c174.663,323.254) 174.663,323.649 174.602,323.649 cw(c174.602,323.811) 174.44,323.811 174.44,324.049 cw(c174.602,324.049) 174.602,324.211 175.28,324.211 ccw(c175.28,324.605) 175.674,324.605 175.674,324.844 ccw(c175.28,324.844) 175.28,325.238 175.219,325.238 cw(c175.219,325.4) 175.057,325.4 175.057,325.688 cw(c175.781,325.688) 175.781,326.412 175.96,326.412 176.194,326.412 cw(c176.194,326.286) 176.32,326.286 ccw(c176.446,326.286) 176.446,326.16 176.553,326.16 ccw(c176.553,326.286) 176.679,326.286 cw(c176.805,326.286) 176.805,326.412 177.356,326.412 177.508,326.412 ccw(c177.508,327.225) 178.321,327.225 178.321,327.406 cw(c178.855,327.406) 178.855,327.941 179.286,327.941 cw(c179.286,327.687) 179.54,327.687 v3(179.54,327.657)
  other v2: 175.91,317.027
DDR4_DQS_7_P: U1.R28 U11.B4 | length 19.7
  L1 w0.116: v4(175.91,316.027) U1.R28@176.397,315.539 ; U11.B4@179.136,328.86 v3(179.54,328.457)
  L5 (Sign) w0.105: v4(175.91,316.027) 175.91,316.043 ccw(c175.542,316.043) 175.542,316.411 cw(c175.542,317.128) 174.825,317.128 174.825,323.254 ccw(c174.663,323.254) 174.663,323.416 174.602,323.416 cw(c174.602,323.811) 174.207,323.811 174.207,324.049 cw(c174.602,324.049) 174.602,324.443 175.28,324.443 ccw(c175.28,324.605) 175.442,324.605 175.442,324.844 ccw(c175.28,324.844) 175.28,325.006 175.219,325.006 cw(c175.219,325.4) 174.825,325.4 174.825,325.688 cw(c175.781,325.688) 175.781,326.644 177.508,326.644 ccw(c177.508,327.225) 178.089,327.225 178.089,327.406 cw(c178.855,327.406) 178.855,328.173 179.286,328.173 ccw(c179.286,328.427) 179.54,328.427 v3(179.54,328.457)
  other v2: 175.91,316.027
DDR4_DQS_8_N: U1.AA28
DDR4_DQS_8_P: U1.Y28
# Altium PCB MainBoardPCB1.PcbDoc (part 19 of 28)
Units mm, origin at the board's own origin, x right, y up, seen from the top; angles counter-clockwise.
Board outline 258.95 x 308.86 mm, 16 copper layers (L1, L2 (GND), L3 (Sign), L4 (GND), L5 (Sign), L6 (PWR/GND), L7(PWR/GND), L8 (Plane_GND), L9 (PWR/GND), L10 (PWR/GND), L11 (PWR/GND), L12 (Sign), L13 (GND), L14 (Sign), L15 (GND), L16), stack 2.502 mm thick; 2397 components, 1744 nets, 8397 pads, 4112 vias.
Unrouted connection lines stored in the file: 3547.

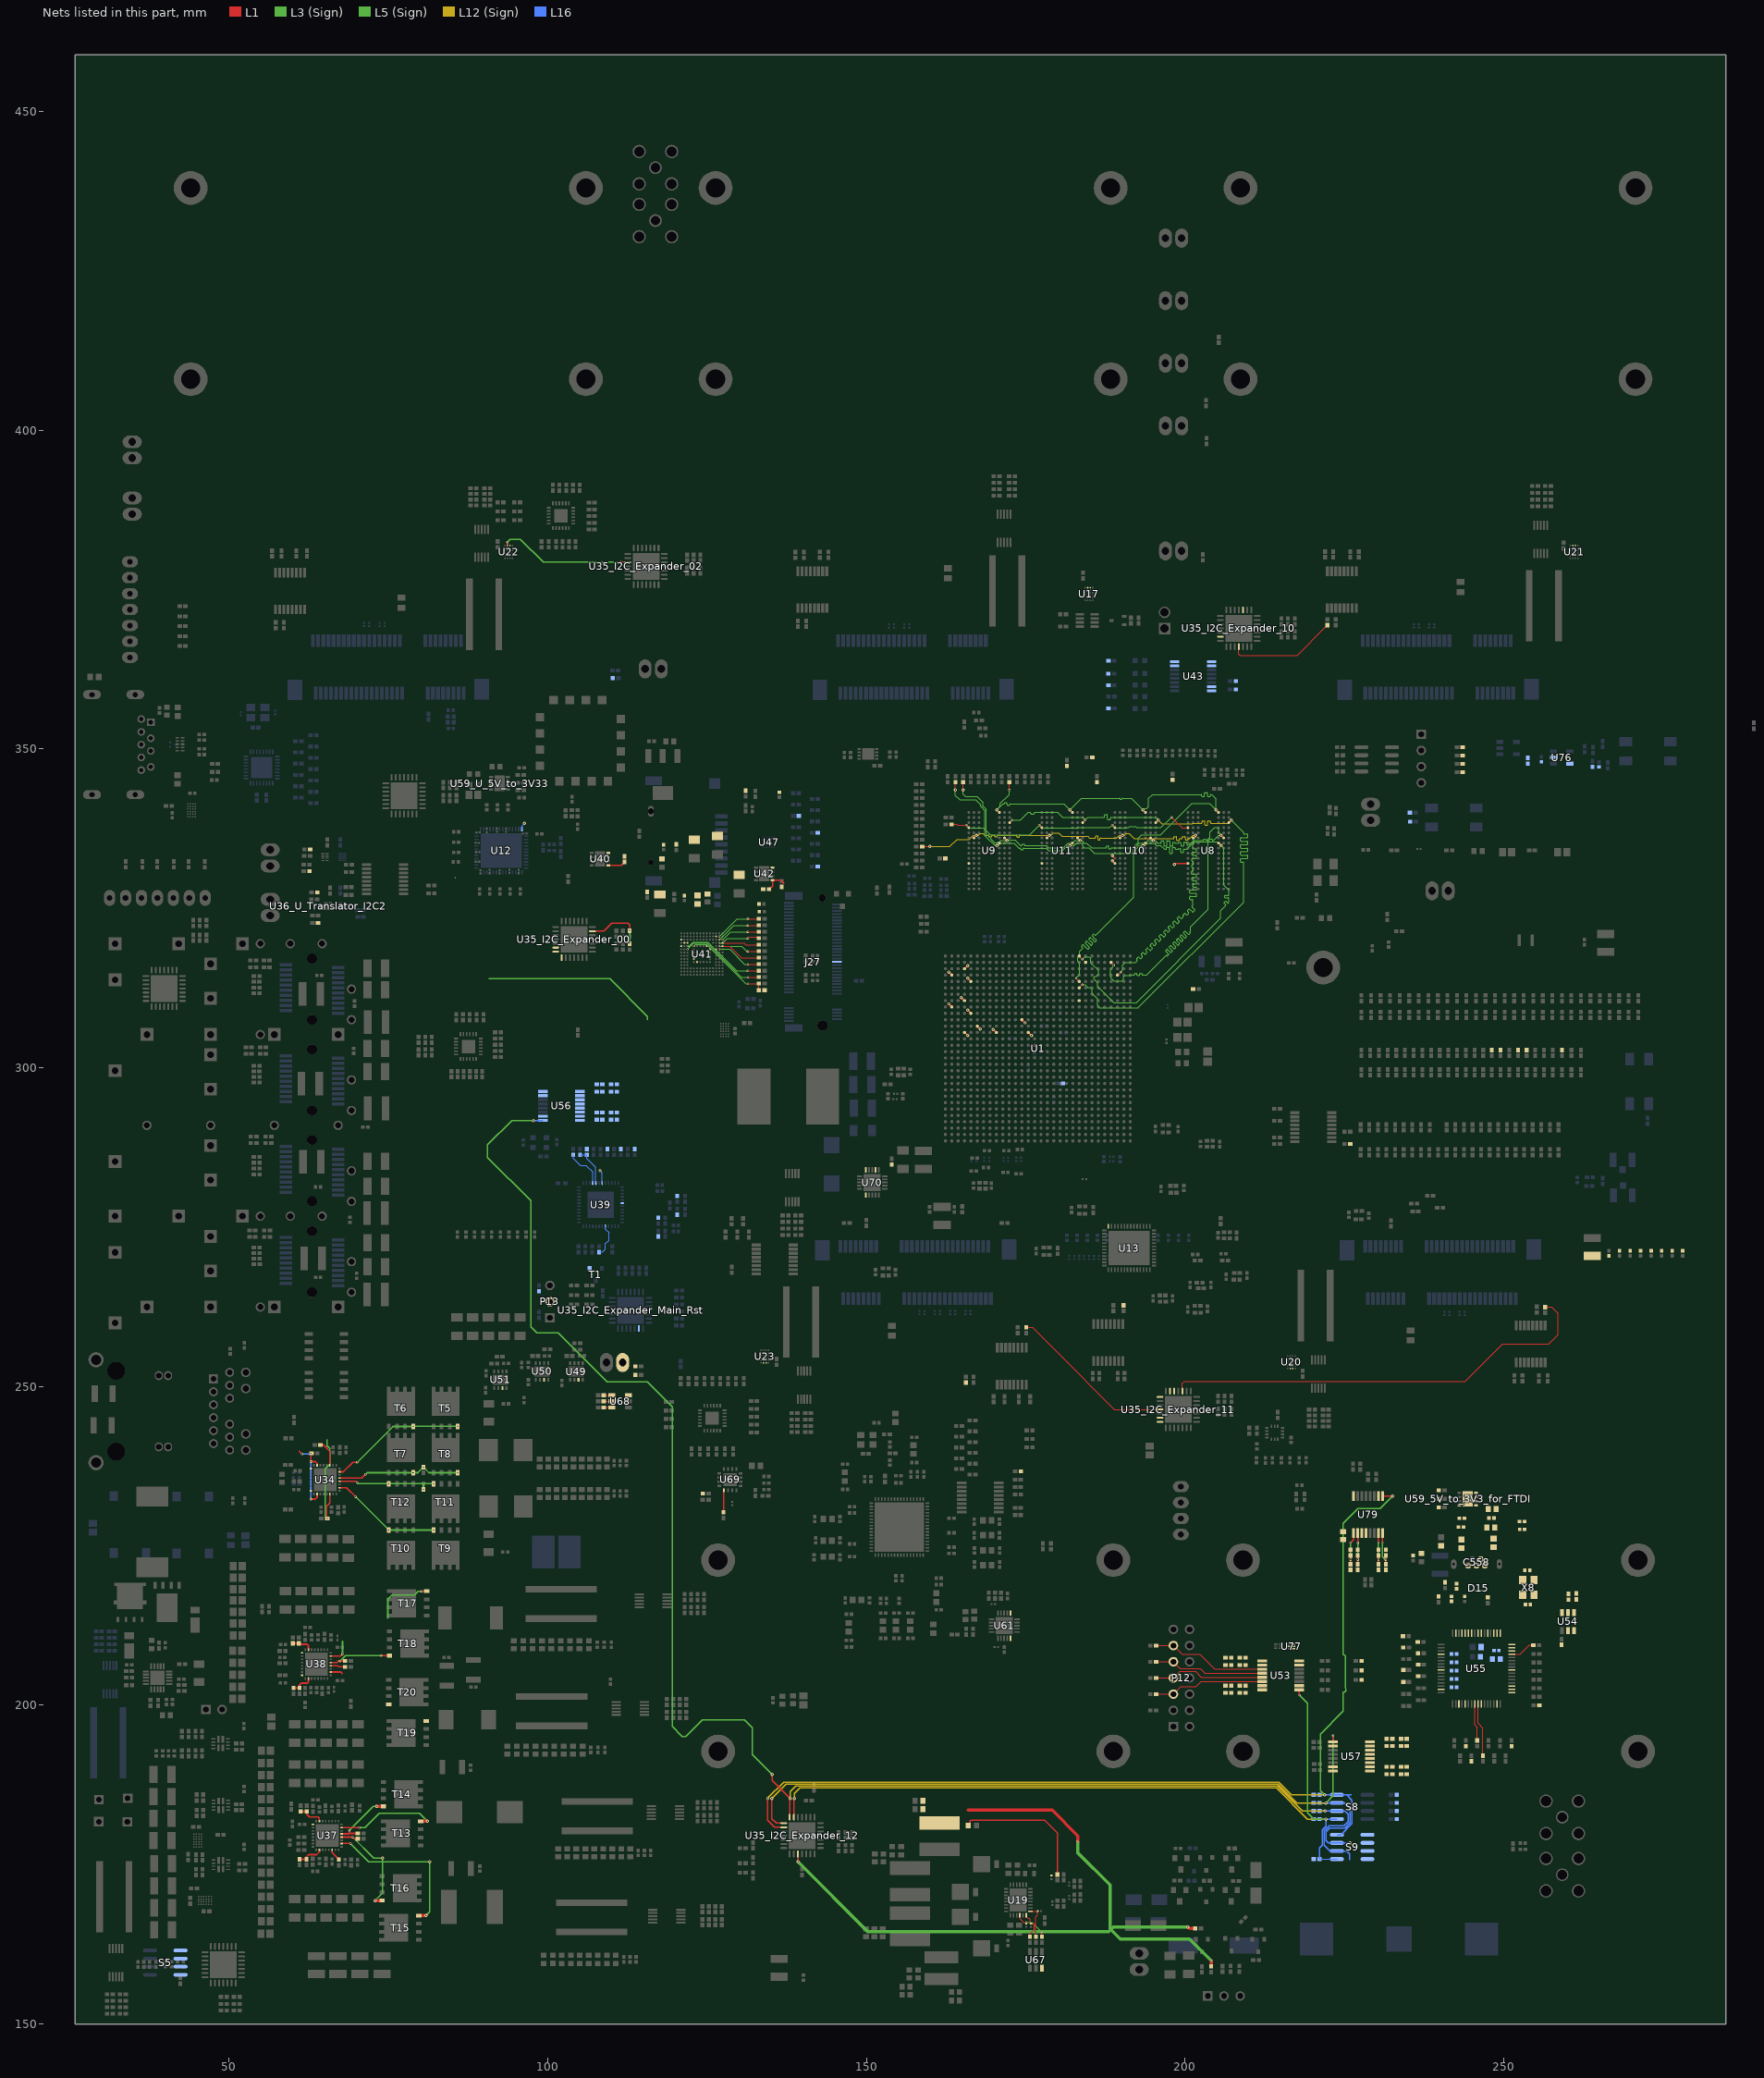
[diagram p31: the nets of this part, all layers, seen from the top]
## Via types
v1: diameter 0.5, hole 0.2, L1 to L16, tented both sides, 1457 vias
v2: diameter 0.35/0/0.35 (per signal layer), hole 0.127, L1 to L3 (Sign), tented both sides, 479 vias
v3: diameter 0.5/0.35/0.35/0.35/0.35/0.35/0.35/0.35/0.35/0.35/0.35/0.35/0.35/0.35/0.35/0.5 (per signal layer), hole 0.15, L1 to L16, tented both sides, 453 vias
v4: diameter 0.5, hole 0.2, L1 to L16, 451 vias
v5: diameter 0.5/0.35/0.35/0.35/0.35/0.35/0.35/0.35/0.35/0.35/0.35/0.35/0.35/0.35/0.35/0.5 (per signal layer), hole 0.2, L1 to L16, tented both sides, 373 vias
v6: diameter 0.8, hole 0.4, L1 to L16, tented both sides, 168 vias
v7: diameter 0.35/0/0.35 (per signal layer), hole 0.127, L1 to L3 (Sign), 138 vias
v8: diameter 2.54, hole 1.02, L1 to L16, 113 vias
v9: diameter 0.5/0/0.5 (per signal layer), hole 0.2, L14 (Sign) to L16, tented both sides, 102 vias
v10: diameter 1.4, hole 0.5, L1 to L16, tented both sides, 80 vias
v11: diameter 0.5, hole 0.2, L3 (Sign) to L6 (PWR/GND), tented both sides, 54 vias
v12: diameter 0.35, hole 0.127, L1 to L2 (GND), tented both sides, 47 vias
v13: diameter 0.4, hole 0.2, L1 to L16, tented both sides, 46 vias
v14: diameter 0.35, hole 0.127, L1 to L16, tented both sides, 16 vias
v15: diameter 0.25, hole 0.2, L1 to L16, 16 vias
v16: diameter 0.5, hole 0.2, L11 (PWR/GND) to L14 (Sign), tented both sides, 16 vias
v17: diameter 0.4, hole 0.2, L1 to L16, 16 vias
v18: diameter 0.3, hole 0.2, L1 to L16, 15 vias
v19: diameter 0.45, hole 0.15, L1 to L16, 12 vias
v20: diameter 0.5/0.35/0.35/0.35/0.35/0.35/0.35/0.35/0.35/0.35/0.35/0.35/0.35/0.35/0.35/0.45 (per signal layer), hole 0.15, L1 to L16, tented both sides, 10 vias
v21: diameter 0.2/0/0.2 (per signal layer), hole 0.1, L1 to L3 (Sign), tented both sides, 9 vias
v22: diameter 0.3, hole 0.127, L14 (Sign) to L16, tented both sides, 8 vias
v23: diameter 0.4, hole 0.1, L1 to L16, 7 vias
v24: diameter 1.15, hole 1.15, L1 to L16, 5 vias
v25: diameter 1.65, hole 1.65, L1 to L16, 5 vias
v26: diameter 0.2, hole 0.1, L1 to L16, 4 vias
v27: diameter 0.4, hole 0.15, L1 to L16, 2 vias
v28: diameter 0.5/0.35/0.35/0.35/0.35/0.35/0.35/0.35/0.35/0.35/0.35/0.35/0.35/0.35/0.35/0.5 (per signal layer), hole 0.15, L1 to L16, 2 vias
v29: diameter 0.35, hole 0.127, L3 (Sign) to L6 (PWR/GND), tented both sides, 2 vias
v30: diameter 0.3, hole 0.127, L15 (GND) to L16, tented both sides, 1 vias
v31: diameter 0.35, hole 0.127, L1 to L2 (GND), 1 vias
v32: diameter 0.5/0.35/0.35/0.35/0.35/0.35/0.35/0.35/0.35/0.35/0.35/0.35/0.35/0.35/0.35/0.5 (per signal layer), hole 0.2, L1 to L16, 1 vias
v33: diameter 0.35/0.35/0.35 (per signal layer), hole 0.127, L1 to L3 (Sign), tented both sides, 1 vias
v34: diameter 0.45/0/0.45 (per signal layer), hole 0.15, L1 to L3 (Sign), tented both sides, 1 vias
v35: diameter 0.45/0/0.45 (per signal layer), hole 0.2, L14 (Sign) to L16, tented both sides, 1 vias

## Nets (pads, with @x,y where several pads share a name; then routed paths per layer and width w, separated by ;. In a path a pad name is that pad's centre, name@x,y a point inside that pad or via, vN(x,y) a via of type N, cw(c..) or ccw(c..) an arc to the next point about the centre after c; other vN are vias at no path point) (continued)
DDR4_DQS_ODT0: R44.1 U1.AB30 U8.K3 U9.K3 U10.K3 U11.K3 | length 107.6
  L1 w0.116: v3(170.472,334.857) U9.K3@170.876,335.26 ; v3(181.933,334.857) U11.K3@182.336,335.26 ; U1.AB30@183.397,317.539 v2(183.884,317.052) ; v3(193.393,334.857) U10.K3@193.797,335.26 ; U8.K3@205.257,335.26 v3(205.661,334.857)
  L1 w0.155: v1(163.977,343.555) R44.1@163.977,344.8
  L1 w0.25: v3(188.593,333.264) 188.997,332.86
  L5 (Sign) w0.092: 167.944,341.085 167.944,341.002 168.602,340.344 168.602,336.427 170.172,334.857 v3(170.472,334.857) 170.709,334.857 171.12,335.267 173.139,335.267 173.954,334.453 174.088,334.453 cw(c174.088,334.363) 174.178,334.363 174.178,334.334 ccw(c174.267,334.334) 174.267,334.245 174.536,334.245 ccw(c174.536,334.334) 174.626,334.334 174.626,334.363 cw(c174.715,334.363) 174.715,334.453 176.441,334.453 178.208,334.453 178.601,334.06 180.755,334.06 181.551,334.857 v3(181.933,334.857) 182.566,334.857 182.977,335.267 183.747,335.267 183.972,335.043 183.972,334.696 184.172,334.496 184.934,334.496 185.77,333.66 191.687,333.66 192.884,334.857 193.709,334.857 194.12,335.267 195.118,335.267 195.484,334.901 196.186,334.901 196.783,334.304 196.895,334.304 197.03,334.304 ccw(c197.03,334.393) 197.119,334.393 197.119,334.474 cw(c197.209,334.474) 197.209,334.564 197.477,334.564 cw(c197.477,334.474) 197.567,334.474 197.567,334.304 197.567,333.733 ccw(c197.657,333.733) 197.657,333.644 197.925,333.644 ccw(c197.925,333.733) 198.015,333.733 198.015,334.304 198.015,334.475 cw(c198.104,334.475) 198.104,334.565 198.373,334.565 cw(c198.373,334.475) 198.463,334.475 198.463,334.393 ccw(c198.552,334.393) 198.552,334.304 198.91,334.304 cw(c198.98,334.304) 198.98,334.373 199.289,334.373 cw(c199.289,334.304) 199.358,334.304 199.358,333.855 ccw(c199.448,333.855) 199.448,333.765 199.716,333.765 ccw(c199.716,333.855) 199.806,333.855 199.806,334.214 cw(c199.896,334.214) 199.896,334.304 200.29,334.304 201.429,335.442 205.075,335.442 v3(205.661,334.857)
  L5 (Sign) w0.151: v1(163.977,343.555) 163.977,342.74 164.655,342.062 167.145,342.062 167.944,341.263 167.944,341.085
  L3 (Sign) w0.092: v2(183.884,317.052) 184.243,317.411 184.979,317.411 185.205,317.185 185.205,316.482 186.422,315.264 186.422,314.708 186.421,314.706 186.418,314.706 186.066,314.354 185.884,314.354 185.696,314.166 185.696,313.9 186.28,313.315 186.28,312.749 188.799,310.23 192.379,310.23 205.605,323.456 205.605,324.666 206.306,325.367 206.366,325.428 ccw(c206.296,325.498) 206.366,325.568 206.14,325.794 cw(c206.21,325.865) 206.14,325.935 206.28,326.075 cw(c206.351,326.005) 206.421,326.075 206.647,325.849 ccw(c206.717,325.919) 206.787,325.849 206.858,325.919 206.858,326.275 206.858,326.573 ccw(c206.758,326.573) 206.758,326.672 206.306,326.672 cw(c206.306,326.771) 206.207,326.771 206.207,326.97 cw(c206.306,326.97) 206.306,327.069 206.758,327.069 ccw(c206.758,327.168) 206.858,327.168 206.858,327.466 206.858,327.665 206.858,327.863 206.055,328.665 206.055,334.462 v3(205.661,334.857)
DDR4_DQS_ODT1: U1.AC29
DDR4_PARITY: R42.1 U1.AB26 U8.T3 U9.T3 U10.T3 U11.T3 | length 98
  L1 w0.116: v3(170.472,340.464) U9.T3@170.876,340.06 ; v3(181.933,340.464) U11.T3@182.336,340.06 ; v2(182.909,314.027) U1.AB26@183.397,313.539 ; v3(193.393,340.464) U10.T3@193.797,340.06 ; v20(204.853,340.464) U8.T3@205.257,340.06
  L1 w0.155: v2(172.438,343.555) R42.1@172.438,344.799
  L5 (Sign) w0.092: v3(170.472,340.464) 171.401,341.393 171.535,341.393 ccw(c171.535,341.482) 171.625,341.482 171.625,341.494 cw(c171.714,341.494) 171.714,341.584 171.983,341.584 cw(c171.983,341.494) 172.073,341.494 172.073,341.393 172.073,341.291 ccw(c172.162,341.291) 172.162,341.202 172.431,341.202 ccw(c172.431,341.291) 172.52,341.291 172.52,341.303 cw(c172.61,341.303) 172.61,341.393 173.009,341.393 181.004,341.393 v3(181.933,340.464) 183.734,342.265 188.493,342.265 189.683,342.265 cw(c189.683,342.196) 189.752,342.196 189.752,342.188 ccw(c189.821,342.188) 189.821,342.118 190.029,342.118 ccw(c190.029,342.188) 190.098,342.188 190.098,342.196 cw(c190.168,342.196) 190.168,342.265 190.271,342.265 191.592,342.265 v3(193.393,340.464) 193.568,340.639 193.943,340.639 194.285,340.982 194.285,342.24 194.907,342.862 200.863,342.862 202.534,342.862 cw(c202.534,342.772) 202.623,342.772 202.623,342.659 ccw(c202.713,342.659) 202.713,342.57 202.982,342.57 ccw(c202.982,342.659) 203.071,342.659 203.071,342.862 203.071,343.065 cw(c203.161,343.065) 203.161,343.154 203.429,343.154 cw(c203.429,343.065) 203.519,343.065 203.519,342.862 203.519,342.659 ccw(c203.608,342.659) 203.608,342.57 203.877,342.57 ccw(c203.877,342.659) 203.967,342.659 203.967,342.772 cw(c204.056,342.772) 204.056,342.862 204.191,342.862 204.853,342.199 v20(204.853,340.464)
  L3 (Sign) w0.092: v3(170.472,340.464) 171.013,341.005 171.013,341.085 ; v2(182.909,314.027) 183.49,314.607 183.49,316.403 183.179,316.713 183.179,317.344 183.49,317.654 183.49,318.295 183.84,318.646 183.911,318.716 ccw(c183.84,318.786) 183.911,318.857 183.788,318.979 cw(c183.858,319.049) 183.788,319.119 183.929,319.26 cw(c183.999,319.189) 184.069,319.26 184.261,319.067 184.676,318.653 ccw(c184.746,318.723) 184.816,318.653 184.957,318.793 ccw(c184.886,318.863) 184.957,318.933 184.542,319.348 184.35,319.54 cw(c184.42,319.611) 184.35,319.681 184.49,319.821 cw(c184.56,319.751) 184.63,319.821 184.823,319.629 185.201,319.251 ccw(c185.271,319.321) 185.341,319.251 185.481,319.391 ccw(c185.411,319.461) 185.481,319.531 185.104,319.909 184.911,320.102 cw(c184.981,320.172) 184.911,320.242 185.051,320.383 cw(c185.122,320.312) 185.192,320.383 185.384,320.19 185.76,319.814 ccw(c185.83,319.884) 185.9,319.814 186.041,319.955 ccw(c185.971,320.025) 186.041,320.095 185.665,320.471 185.472,320.663 cw(c185.543,320.733) 185.472,320.804 185.613,320.944 cw(c185.683,320.874) 185.753,320.944 185.876,320.822 ccw(c185.946,320.892) 186.016,320.822 186.715,321.521 191.937,326.742 191.937,334.292 192.646,335.002 192.646,336.014 193.206,336.574 196.129,336.574 201.059,341.503 203.814,341.503 v20(204.853,340.464)
  L3 (Sign) w0.151: 171.013,341.085 171.013,341.464 172.428,342.879 172.428,343.545 v2(172.438,343.555)
DDR4_RAM_RST_N: R60.1 U1.AB25 U8.P1 U9.P1 U10.P1 U11.P1 | length 99.4
  L1 w0.116: U9.P1@172.476,338.46 v2(172.879,338.864) ; U1.AB25@183.397,312.539 v2(183.884,313.027) ; U11.P1@183.936,338.46 v2(184.34,338.864) ; U10.P1@195.397,338.46 v3(195.8,338.864) ; U8.P1@206.857,338.46 v3(207.261,338.864)
  L12 (Sign) w0.092: v3(195.8,338.864) 196.374,338.29 201.123,338.29 201.218,338.385 202.425,338.385 202.56,338.385 ccw(c202.56,338.475) 202.649,338.475 202.649,338.652 cw(c202.739,338.652) 202.739,338.742 203.007,338.742 cw(c203.007,338.652) 203.097,338.652 203.097,338.385 203.097,338.118 ccw(c203.187,338.118) 203.187,338.028 203.455,338.028 ccw(c203.455,338.118) 203.545,338.118 203.545,338.385 203.545,338.652 cw(c203.634,338.652) 203.634,338.742 203.903,338.742 cw(c203.903,338.652) 203.993,338.652 203.993,338.475 ccw(c204.082,338.475) 204.082,338.385 204.483,338.385 206.782,338.385 v3(207.261,338.864)
  L3 (Sign) w0.092: v2(172.879,338.864) 174.191,338.864 175.387,340.06 175.672,340.06 cw(c175.672,339.951) 175.782,339.951 175.782,339.92 ccw(c175.892,339.92) 175.892,339.81 176.222,339.81 ccw(c176.222,339.92) 176.332,339.92 176.332,339.951 cw(c176.441,339.951) 176.441,340.06 176.606,340.06 179.992,340.06 180.792,339.26 183.943,339.26 v2(184.34,338.864) 184.736,339.26 185.89,339.26 187.297,339.26 ccw(c187.297,339.35) 187.387,339.35 187.387,339.625 cw(c187.476,339.625) 187.476,339.715 187.745,339.715 cw(c187.745,339.625) 187.834,339.625 187.834,339.26 187.834,339.02 ccw(c187.924,339.02) 187.924,338.93 188.193,338.93 ccw(c188.193,339.02) 188.282,339.02 188.282,339.171 cw(c188.372,339.171) 188.372,339.26 188.506,339.26 195.404,339.26 v3(195.8,338.864) ; v2(183.884,313.027) 184.305,313.027 184.7,312.632 185.055,312.632 185.382,312.306 185.382,311.656 186.28,310.757 186.28,309.749 186.606,309.423 187.731,309.423 192.65,309.423 192.689,309.462 192.697,309.462 209.194,325.959 209.194,331.495 209.194,332.123 ccw(c209.057,332.123) 209.057,332.26 208.801,332.26 cw(c208.801,332.398) 208.663,332.398 208.663,332.672 cw(c208.801,332.672) 208.801,332.81 209.194,332.81 209.71,332.81 ccw(c209.71,332.947) 209.847,332.947 209.847,333.222 ccw(c209.71,333.222) 209.71,333.359 209.194,333.359 208.801,333.359 cw(c208.801,333.496) 208.663,333.496 208.663,333.771 cw(c208.801,333.771) 208.801,333.908 209.194,333.908 209.71,333.908 ccw(c209.71,334.046) 209.847,334.046 209.847,334.32 ccw(c209.71,334.32) 209.71,334.458 209.194,334.458 208.801,334.458 cw(c208.801,334.595) 208.663,334.595 208.663,334.87 cw(c208.801,334.87) 208.801,335.007 209.194,335.007 209.71,335.007 ccw(c209.71,335.145) 209.847,335.145 209.847,335.419 ccw(c209.71,335.419) 209.71,335.557 209.194,335.557 208.801,335.557 cw(c208.801,335.694) 208.663,335.694 208.663,335.969 cw(c208.801,335.969) 208.801,336.106 209.194,336.106 209.71,336.106 ccw(c209.71,336.243) 209.847,336.243 209.847,336.518 ccw(c209.71,336.518) 209.71,336.655 209.332,336.655 cw(c209.332,336.793) 209.194,336.793 209.194,336.93 v3(207.261,338.864)
DDR4_RAS: R59.1 U1.AH27 U8.L5 U9.L5 U10.L5 U11.L5 | length 99.3
  L1 w0.116: U9.L5@166.876,336.06 167.272,336.457 v3(167.275,336.457) ; U11.L5@178.336,336.06 178.733,336.457 v3(178.735,336.457) ; U1.AH27@189.397,314.539 v2(189.884,315.027) ; U10.L5@189.797,336.06 190.193,336.457 v3(190.195,336.457) ; U8.L5@201.257,336.06 201.653,336.457 v4(201.656,336.457)
  L1 w0.155: R59.1@158.737,334.7 v1(159.982,334.7)
  L12 (Sign) w0.092: 165.251,335.813 166.114,335.813 166.758,336.457 v3(167.275,336.457) 167.537,336.457 167.858,336.778 168.277,336.778 168.566,336.488 168.79,336.488 169.149,336.488 cw(c169.149,336.398) 169.238,336.398 169.238,336.342 ccw(c169.328,336.342) 169.328,336.252 169.596,336.252 ccw(c169.596,336.342) 169.686,336.342 169.686,336.398 cw(c169.775,336.398) 169.775,336.488 170.044,336.488 cw(c170.044,336.398) 170.134,336.398 170.134,336.342 ccw(c170.223,336.342) 170.223,336.252 170.492,336.252 ccw(c170.492,336.342) 170.582,336.342 170.582,336.398 cw(c170.671,336.398) 170.671,336.488 170.715,336.488 172.923,336.488 173.147,336.488 173.505,336.488 cw(c173.505,336.398) 173.595,336.398 173.595,336.3 ccw(c173.684,336.3) 173.684,336.211 173.953,336.211 ccw(c173.953,336.3) 174.043,336.3 174.043,336.398 cw(c174.132,336.398) 174.132,336.488 175.628,336.488 175.659,336.457 v3(178.735,336.457) 178.977,336.457 179.349,336.829 180.162,336.829 180.705,336.287 184.769,336.287 184.996,336.06 185.807,336.06 185.91,336.06 ccw(c185.91,336.13) 185.98,336.13 185.98,336.293 cw(c186.049,336.293) 186.049,336.362 186.257,336.362 cw(c186.257,336.293) 186.326,336.293 186.326,336.06 186.326,335.828 ccw(c186.395,335.828) 186.395,335.758 186.603,335.758 ccw(c186.603,335.828) 186.672,335.828 186.672,335.991 cw(c186.741,335.991) 186.741,336.06 186.868,336.06 189.282,336.06 189.679,336.457 v3(190.195,336.457) 190.458,336.457 190.779,336.778 191.197,336.778 191.487,336.488 192.022,335.953 197.764,335.953 198.156,335.953 ccw(c198.156,336.043) 198.245,336.043 198.245,336.152 cw(c198.335,336.152) 198.335,336.241 198.603,336.241 cw(c198.603,336.152) 198.693,336.152 198.693,335.953 198.693,335.754 ccw(c198.782,335.754) 198.782,335.665 199.051,335.665 ccw(c199.051,335.754) 199.141,335.754 199.141,335.864 cw(c199.23,335.864) 199.23,335.953 199.365,335.953 199.502,335.953 ccw(c199.502,336.043) 199.592,336.043 199.592,336.152 cw(c199.681,336.152) 199.681,336.241 199.95,336.241 cw(c199.95,336.152) 200.04,336.152 200.04,335.953 200.04,335.864 ccw(c200.129,335.864) 200.129,335.774 200.398,335.774 ccw(c200.398,335.864) 200.487,335.864 cw(c200.577,335.864) 200.577,335.953 200.711,335.953 201.215,336.457 v4(201.656,336.457)
  L12 (Sign) w0.151: v1(159.982,334.7) 163.09,334.7 164.203,335.813 165.251,335.813
  L3 (Sign) w0.092: v2(189.884,315.027) 190.232,315.374 190.232,316.074 190.672,316.514 190.938,316.514 192.232,316.514 192.381,316.663 192.469,316.751 ccw(c192.381,316.839) 192.469,316.928 192.438,316.959 cw(c192.526,317.047) 192.438,317.135 192.614,317.311 cw(c192.702,317.223) 192.79,317.311 192.91,317.192 192.931,317.17 ccw(c193.019,317.259) 193.107,317.17 193.284,317.347 ccw(c193.196,317.435) 193.284,317.523 193.262,317.544 193.143,317.664 cw(c193.231,317.752) 193.143,317.84 193.319,318.017 cw(c193.407,317.928) 193.495,318.017 193.615,317.897 193.639,317.873 ccw(c193.727,317.961) 193.815,317.873 193.992,318.049 ccw(c193.903,318.137) 193.992,318.225 193.967,318.25 193.848,318.369 cw(c193.936,318.457) 193.848,318.545 194.024,318.722 cw(c194.112,318.634) 194.2,318.722 194.32,318.602 194.473,318.449 ccw(c194.562,318.537) 194.65,318.449 194.826,318.625 ccw(c194.738,318.713) 194.826,318.801 194.673,318.955 194.553,319.074 cw(c194.641,319.162) 194.553,319.251 194.729,319.427 cw(c194.817,319.339) 194.906,319.427 195.025,319.307 195.098,319.235 ccw(c195.186,319.323) 195.274,319.235 195.45,319.411 ccw(c195.362,319.499) 195.45,319.587 195.378,319.66 195.258,319.779 cw(c195.346,319.868) 195.258,319.956 195.434,320.132 cw(c195.523,320.044) 195.611,320.132 195.73,320.012 195.826,319.917 ccw(c195.914,320.005) 196.002,319.917 196.179,320.093 ccw(c196.09,320.181) 196.179,320.269 196.083,320.365 195.963,320.485 cw(c196.051,320.573) 195.963,320.661 196.14,320.837 cw(c196.228,320.749) 196.316,320.837 196.435,320.718 196.589,320.564 ccw(c196.677,320.652) 196.765,320.564 196.941,320.74 ccw(c196.853,320.829) 196.941,320.917 196.788,321.07 196.668,321.19 cw(c196.757,321.278) 196.668,321.366 196.845,321.542 cw(c196.933,321.454) 197.021,321.542 197.14,321.423 197.232,321.331 ccw(c197.32,321.419) 197.408,321.331 197.585,321.508 ccw(c197.496,321.596) 197.585,321.684 197.493,321.775 197.373,321.895 cw(c197.462,321.983) 197.373,322.071 197.55,322.247 cw(c197.638,322.159) 197.726,322.247 197.846,322.128 197.961,322.013 ccw(c198.049,322.101) 198.137,322.013 198.313,322.189 ccw(c198.225,322.277) 198.313,322.365 198.198,322.48 198.079,322.6 cw(c198.167,322.688) 198.079,322.776 198.255,322.953 cw(c198.343,322.864) 198.431,322.953 198.551,322.833 198.702,322.682 ccw(c198.79,322.77) 198.878,322.682 199.054,322.858 ccw(c198.966,322.946) 199.054,323.035 198.903,323.186 198.784,323.305 cw(c198.872,323.393) 198.784,323.481 198.96,323.658 cw(c199.048,323.569) 199.136,323.658 199.256,323.538 199.341,323.453 ccw(c199.43,323.541) 199.518,323.453 199.694,323.629 ccw(c199.606,323.717) 199.694,323.805 199.697,323.802 cw(c199.785,323.891) 199.697,323.979 199.873,324.155 cw(c199.961,324.067) 200.049,324.155 200.201,324.003 ccw(c200.289,324.091) 200.377,324.003 200.554,324.179 ccw(c200.466,324.267) 200.554,324.356 200.402,324.508 cw(c200.49,324.596) 200.402,324.684 200.578,324.86 cw(c200.666,324.772) 200.754,324.86 201.149,324.465 ccw(c201.237,324.554) 201.325,324.465 201.502,324.642 ccw(c201.413,324.73) 201.502,324.818 201.107,325.213 cw(c201.195,325.301) 201.107,325.389 201.224,325.507 201.224,325.653 201.224,326.255 ccw(c201.1,326.255) 201.1,326.38 200.859,326.38 cw(c200.859,326.505) 200.734,326.505 200.734,326.754 cw(c200.859,326.754) 200.859,326.879 201.224,326.879 201.708,326.879 ccw(c201.708,327.003) 201.833,327.003 201.833,327.253 ccw(c201.708,327.253) 201.708,327.377 201.224,327.377 200.859,327.377 cw(c200.859,327.502) 200.734,327.502 200.734,327.751 cw(c200.859,327.751) 200.859,327.876 201.224,327.876 201.708,327.876 ccw(c201.708,328) 201.833,328 201.833,328.25 ccw(c201.708,328.25) 201.708,328.374 201.349,328.374 cw(c201.349,328.499) 201.224,328.499 201.224,328.748 cw(c201.349,328.748) 201.349,328.873 201.708,328.873 ccw(c201.708,328.998) 201.833,328.998 201.833,329.247 ccw(c201.708,329.247) 201.708,329.372 201.224,329.372 cw(c201.224,329.478) 201.118,329.478 201.118,329.764 cw(c201.224,329.764) 201.224,329.87 201.708,329.87 ccw(c201.708,329.995) 201.833,329.995 201.833,330.244 ccw(c201.708,330.244) 201.708,330.369 201.224,330.369 201.133,330.369 cw(c201.133,330.493) 201.009,330.493 201.009,330.743 cw(c201.133,330.743) 201.133,330.867 201.224,330.867 ccw(c201.224,330.931) 201.288,330.931 201.288,331.303 ccw(c201.224,331.303) 201.224,331.366 201.223,331.366 cw(c201.223,331.491) 201.098,331.491 201.098,331.74 cw(c201.223,331.74) 201.223,331.865 201.224,331.865 ccw(c201.224,331.969) 201.329,331.969 201.329,332.259 ccw(c201.224,332.259) 201.224,332.363 cw(c201.224,332.484) 201.103,332.484 201.103,332.741 cw(c201.224,332.741) 201.224,332.862 201.708,332.862 ccw(c201.708,332.986) 201.833,332.986 201.833,333.236 ccw(c201.708,333.236) 201.708,333.36 201.224,333.36 cw(c201.224,333.485) 201.1,333.485 201.1,333.734 cw(c201.224,333.734) 201.224,333.859 201.708,333.859 ccw(c201.708,333.984) 201.833,333.984 201.833,334.233 ccw(c201.708,334.233) 201.708,334.358 201.349,334.358 cw(c201.349,334.482) 201.224,334.482 201.224,334.607 201.224,335.03 201.371,335.177 201.371,335.877 201.656,336.162 v4(201.656,336.457)
DDR4_TEN: R56.1 U8.N6 U9.N6 U10.N6 U11.N6 | length 42.1
  L1 w0.112: 165.251,338.056 v2(165.665,338.056)
  L1 w0.116: v2(165.665,338.056) U9.N6@166.068,337.653 ; v2(177.125,338.056) U11.N6@177.529,337.653 ; v2(188.586,338.056) U10.N6@188.989,337.653 ; v2(197.878,339.319) 199.536,337.66 U8.N6@200.457,337.66
  L1 w0.155: R56.1@163.36,338.184 164.159,338.184 164.287,338.056 165.251,338.056
  L3 (Sign) w0.092: v2(165.665,338.056) 166.061,337.66 168.338,337.66 169.439,336.56 175.628,336.56 176.729,337.66
  L3 (Sign) w0.116: 176.729,337.66 v2(177.125,338.056) 177.521,337.66 183.136,337.66 183.143,337.668 188.197,337.668 v2(188.586,338.056) 188.982,337.66 190.855,337.66 190.869,337.674 191.154,337.674 191.313,337.833 192.222,337.833 192.387,337.668 196.227,337.668 v2(197.878,339.319)
DDR4_WE: R55.1 U1.AG29 U8.L2 U9.L2 U10.L2 U11.L2 | length 108.5
  L1 w0.116: U9.L2@171.676,336.06 v3(172.079,335.657) ; U11.L2@183.136,336.06 v3(183.54,335.657) ; U1.AG29@188.397,316.539 188.811,316.125 v2(188.811,316.088) ; U10.L2@194.597,336.06 v3(195,335.657) ; v3(205.653,336.464) U8.L2@206.057,336.06
  L1 w0.155: v1(165.186,343.555) R55.1@165.186,344.8
  L5 (Sign) w0.092: 168.291,341.085 168.291,341.007 168.793,340.505 168.793,336.675 170.132,335.336 170.605,335.336 170.62,335.351 170.791,335.351 171.097,335.657 171.317,335.657 v3(172.079,335.657) 172.129,335.706 173.291,335.706 174.157,334.84 174.291,334.84 ccw(c174.291,334.93) 174.38,334.93 174.38,334.97 cw(c174.47,334.97) 174.47,335.06 174.739,335.06 cw(c174.739,334.97) 174.828,334.97 174.828,334.93 ccw(c174.918,334.93) 174.918,334.84 176.289,334.84 178.225,334.84 178.587,334.478 180.897,334.478 181.669,335.25 182.326,335.25 182.733,335.657 ; v3(205.653,336.464) 205.316,336.464 204.486,335.634 204.352,335.634 cw(c204.352,335.724) 204.262,335.724 204.262,335.829 ccw(c204.173,335.829) 204.173,335.919 203.904,335.919 ccw(c203.904,335.829) 203.814,335.829 203.814,335.724 cw(c203.725,335.724) 203.725,335.634 203.456,335.634 cw(c203.456,335.724) 203.367,335.724 203.367,335.75 ccw(c203.277,335.75) 203.277,335.839 203.008,335.839 ccw(c203.008,335.75) 202.919,335.75 202.919,335.724 cw(c202.829,335.724) 202.829,335.634 202.552,335.634 201.349,335.634 200.925,335.21 200.79,335.21 ccw(c200.79,335.12) 200.701,335.12 200.701,335.023 cw(c200.611,335.023) 200.611,334.933 200.342,334.933 cw(c200.342,335.023) 200.253,335.023 200.253,335.21 200.253,335.257 ccw(c200.163,335.257) 200.163,335.347 199.895,335.347 ccw(c199.895,335.257) 199.805,335.257 199.805,335.21 199.805,334.893 cw(c199.715,334.893) 199.715,334.803 199.447,334.803 cw(c199.447,334.893) 199.357,334.893 199.357,335.21 199.357,335.257 ccw(c199.268,335.257) 199.268,335.347 198.999,335.347 ccw(c198.999,335.257) 198.909,335.257 cw(c198.862,335.257) 198.862,335.21 198.509,335.21 cw(c198.509,335.257) 198.462,335.257 ccw(c198.372,335.257) 198.372,335.347 198.103,335.347 ccw(c198.103,335.257) 198.014,335.257 198.014,335.209 198.014,334.893 cw(c197.924,334.893) 197.924,334.803 197.656,334.803 cw(c197.656,334.893) 197.566,334.893 197.566,335.209 197.566,335.526 ccw(c197.476,335.526) 197.476,335.616 197.208,335.616 ccw(c197.208,335.526) 197.118,335.526 197.118,335.209 197.118,334.893 cw(c197.029,334.893) 197.029,334.803 196.76,334.803 cw(c196.76,334.893) 196.67,334.893 196.67,335.209 196.67,335.526 ccw(c196.581,335.526) 196.581,335.616 196.312,335.616 ccw(c196.312,335.526) 196.223,335.526 196.223,335.299 cw(c196.133,335.299) 196.133,335.209 195.783,335.209 195.721,335.209 195.274,335.657 v3(195,335.657) 194.193,335.657 193.797,335.26 192.558,335.26 191.777,334.48 188.561,334.48 188.457,334.48 ccw(c188.457,334.411) 188.387,334.411 cw(c188.318,334.411) 188.318,334.341 188.111,334.341 cw(c188.111,334.411) 188.041,334.411 188.041,334.48 188.041,334.707 ccw(c187.972,334.707) 187.972,334.776 187.764,334.776 ccw(c187.764,334.707) 187.695,334.707 187.695,334.549 cw(c187.626,334.549) 187.626,334.48 186.969,334.48 185.344,334.48 184.556,335.267 184.187,335.267 183.798,335.657 v3(183.54,335.657) ; 182.733,335.657 v3(183.54,335.657) ; 182.733,335.657 v3(183.54,335.657)
  L5 (Sign) w0.151: v1(165.186,343.555) 165.186,342.893 165.535,342.544 167.348,342.544 168.291,341.601 168.291,341.085
  L3 (Sign) w0.092: v2(188.811,316.088) 188.92,316.088 188.563,315.731 188.563,315.57 188.335,315.341 188.335,314.327 188.397,314.264 188.397,314.06 188.826,313.631 190.119,313.631 190.33,313.842 190.33,314.212 190.592,314.473 191.534,314.473 191.651,314.59 191.872,314.59 191.971,314.59 ccw(c191.971,314.689) 192.07,314.689 cw(c192.169,314.689) 192.169,314.788 192.368,314.788 cw(c192.368,314.689) 192.467,314.689 192.467,314.59 ccw(c192.566,314.59) 192.566,314.491 192.765,314.491 ccw(c192.765,314.59) 192.864,314.59 192.864,314.697 cw(c192.963,314.697) 192.963,314.796 193.162,314.796 cw(c193.162,314.697) 193.261,314.697 193.261,314.689 ccw(c193.36,314.689) 193.36,314.59 193.789,314.59 194.01,314.59 ; 194.009,314.591 196.884,317.466 196.995,317.576 cw(c197.065,317.506) 197.135,317.576 197.133,317.579 ; 197.132,317.579 ccw(c197.203,317.649) 197.273,317.579 197.413,317.719 ccw(c197.343,317.79) 197.413,317.86 197.345,317.927 196.991,318.281 cw(c197.062,318.352) 196.991,318.422 197.132,318.562 cw(c197.202,318.492) 197.272,318.562 197.626,318.208 197.694,318.14 ccw(c197.764,318.211) 197.834,318.14 197.975,318.281 ccw(c197.904,318.351) 197.975,318.421 197.907,318.489 197.553,318.843 cw(c197.623,318.913) 197.553,318.983 197.693,319.124 cw(c197.763,319.053) 197.834,319.124 198.188,318.77 198.255,318.702 ccw(c198.325,318.772) 198.396,318.702 198.536,318.842 ccw(c198.466,318.912) 198.536,318.983 198.468,319.05 198.114,319.404 cw(c198.184,319.475) 198.114,319.545 198.255,319.685 cw(c198.325,319.615) 198.395,319.685 198.749,319.331 198.817,319.263 ccw(c198.887,319.333) 198.957,319.263 199.097,319.404 ccw(c199.027,319.474) 199.097,319.544 199.03,319.612 198.676,319.966 cw(c198.746,320.036) 198.676,320.106 198.816,320.247 cw(c198.886,320.176) 198.956,320.247 199.311,319.892 199.376,319.827 ccw(c199.446,319.897) 199.516,319.827 199.656,319.968 ccw(c199.586,320.038) 199.656,320.108 199.591,320.173 199.237,320.527 cw(c199.307,320.597) 199.237,320.668 199.377,320.808 cw(c199.448,320.738) 199.518,320.808 199.872,320.454 199.937,320.389 ccw(c200.007,320.459) 200.078,320.389 200.218,320.529 ccw(c200.148,320.599) 200.218,320.669 200.153,320.735 199.799,321.089 cw(c199.869,321.159) 199.799,321.229 199.939,321.369 cw(c200.009,321.299) 200.079,321.369 200.433,321.015 200.504,320.945 ccw(c200.574,321.015) 200.644,320.945 200.784,321.085 ccw(c200.714,321.156) 200.784,321.226 cw(c200.855,321.296) 200.784,321.366 200.855,321.436 200.855,322.107 203.626,324.879 203.626,335.895 203.898,336.168 203.898,336.931 203.91,336.942 203.91,336.947 204.419,337.456 204.423,337.456 204.635,337.668 205.034,337.668 205.263,337.439 205.263,336.855 v3(205.653,336.464)
DDR4_ZQ: R920.1 U1.AB23
DDR4_ZQ_1: R61.1 U8.F6 | length 2.2
  L1 w0.254: v1(198.343,331.916) 198.475,332.048 200.445,332.048 U8.F6@200.457,332.06
DDR4_ZQ_2: R62.1 U10.F6 | length 0.6
  L1 w0.25: v3(188.593,332.464) U10.F6@188.997,332.06
DDR4_ZQ_3: R63.1 U9.F6
DDR4_ZQ_4: R64.1 U11.F6
DEVSLP: J27.38
DH1: T5.4 T6.4 U34.23 | length 21.5
  L1 w0.254: U34.23@67.322,236.639 67.949,236.639 69.436,238.125 v2(70.117,238.125) ; T5.4@85.882,243.723 v2(85.882,243.755)
  L3 (Sign) w0.254: v2(70.117,238.125) 75.714,243.723 v2(78.882,243.723) 78.914,243.755 v2(85.882,243.755)
DH1_1: T13.4 U37.23 | length 16
  L1 w0.2: U37.23@67.675,180.817 v2(70.427,180.817) v2@70.46,180.784
  L1 w0.5: T13.4@80.042,181.813 v1(81.129,181.813)
  L3 (Sign) w0.2: v2(70.427,180.817) 71.354,180.817 73.57,183.032 79.91,183.032 v1(81.129,181.813)
DH1_2: T17.4 U38.23 | length 13.5
  L1 w0.254: U38.23@65.953,207.714 67.479,207.714 v2(67.796,208.031) ; v2(80.18,217.889) T17.4@80.998,217.889
  L3 (Sign) w0.254: v2(67.796,208.031) 67.796,210.036 ; 74.923,213.696 74.923,216.666 75.567,217.31 79.083,217.31 79.662,217.889 v2(80.18,217.889)
DH2: T9.4 T10.4 U34.18 | length 17.5
  L1 w0.254: U34.18@67.322,234.139 67.324,234.137 68.428,234.137 v2(69.863,232.702) ; v2(82.067,227.505) T9.4@82.072,227.501
  L3 (Sign) w0.254: v2(69.863,232.702) 75.064,227.501 v2(75.078,227.501) 75.082,227.505 v2(82.067,227.505)
DH2_1: T15.4 U37.18 | length 24.8
  L1 w0.2: U37.18@67.675,178.317 69.062,178.317 69.068,178.323 v2(69.068,178.302)
  L1 w0.5: T15.4@79.789,167.011 v1(80.876,167.011)
  L5 (Sign) w0.2: v1(80.876,167.011) 81.454,167.589 v11(81.454,175.476)
  L3 (Sign) w0.2: v2(69.068,178.302) 71.895,175.476 v11(81.454,175.476)
DH2_2: T19.4 U38.18 | length 1.9
  L1 w0.254: U38.18@65.953,205.214 67.536,205.214 67.744,205.006
DL1: R275.2 T7.4 T8.4 U34.21 | length 19.6
  L1 w0.254: U34.21@67.322,235.639 70.805,235.639 v2(71.387,236.22) ; v2(85.869,236.489) T8.4@85.882,236.489
  L3 (Sign) w0.254: v2(71.387,236.22) 71.655,236.489 v2(78.867,236.489) 79.613,236.489 v2(80.488,237.364) 81.363,236.489 v2(85.869,236.489)
DL1_1: R292.2 T14.4 U37.21 | length 9.9
  L1 w0.254: U37.21@67.675,179.817 68.726,179.817 68.825,179.915 ; v2(68.847,180.391) 68.847,179.937 68.825,179.915 ; R292.2@70.161,179.915 68.825,179.915
  L1 w0.5: v1(73.127,184.15) T14.4@74.214,184.15
  L3 (Sign) w0.254: v2(68.847,180.391) 72.606,184.15 v1(73.127,184.15)
DL1_2: R629.2 T18.4 U38.21 | length 10.5
  L1 w0.254: U38.21@65.953,206.714 66.916,206.714 67.166,206.964 R629.2@68.206,206.964 ; v2(73.85,207.802) 73.855,207.797 T18.4@75.173,207.797
  L3 (Sign) w0.254: v2(67.43,206.951) 68.28,207.802 v2(73.85,207.802)
DL2: R280.2 T11.4 T12.4 U34.20 | length 15.8
  L1 w0.254: U34.20@67.322,235.139 69.941,235.139 v2(70.129,234.95)
  L3 (Sign) w0.254: v2(70.129,234.95) 70.316,234.764 v2(75.072,234.764) v2(82.072,234.764) ; v2(80.488,233.889) 80.488,234.764
DL2_1: R299.2 T16.4 U37.20 | length 16.9
  L1 w0.254: U37.20@67.675,179.317 v2(69.396,179.317) 69.646,179.067 R299.2@70.211,179.067
  L1 w0.5: v1(72.923,169.38) T16.4@74.01,169.38
  L5 (Sign) w0.254: v1(72.923,169.38) 74.092,170.548 v11(74.092,176.022)
  L3 (Sign) w0.254: v2(69.396,179.317) 72.691,176.022 v11(74.092,176.022)
DL2_2: R317.2 T20.4 U38.20 | length 2.3
  L1 w0.254: U38.20@65.953,206.214 66.991,206.214 67.166,206.039 68.212,206.039 R317.2@68.206,206.039
eMMC_clk: R112.2 U41.M6 | length 13.8
  L1 w0.098: v2(131.416,314.211) 133.103,314.211 R112.2@133.116,314.223
  L3 (Sign) w0.098: v21(121.938,318.591) 122.886,319.54 125.022,319.54 130.352,314.211 v2(131.416,314.211)
eMMC_cmd: R111.2 U41.M5 | length 13.3
  L1 w0.098: v2(131.407,315.214) R111.2@133.116,315.214
  L3 (Sign) w0.098: v21(121.938,319.091) 122.157,319.091 122.804,319.738 125.104,319.738 129.629,315.214 v2(131.407,315.214)
eMMC_data0: R105.2 U41.A3 | length 6.2
  L1 w0.098: v2(131.407,321.335) R105.2@133.116,321.335
  L3 (Sign) w0.098: v21(127.438,320.091) 128.682,321.335 v2(131.407,321.335)
eMMC_data1: R107.2 U41.A4 | length 5.8
  L1 w0.098: U41.A4@127.438,319.591 130.833,319.591 131.121,319.303 R107.2@133.116,319.303
eMMC_data2: R108.2 U41.A5 | length 6.4
  L1 w0.098: U41.A5@127.438,319.091 128.558,319.091 130.378,317.271 R108.2@133.116,317.271
eMMC_data3: R110.2 U41.B2 | length 7.3
  L1 w0.098: v34(131.416,323.367) R110.2@133.116,323.367
  L3 (Sign) w0.098: v21(126.938,320.591) 129.714,323.367 v34(131.416,323.367)
eMMC_data4: R101.2 U41.B3 | length 7.1
  L1 w0.098: v21(126.929,320.091) U41.B3@126.938,320.091 ; v2(131.407,322.351) R101.2@133.116,322.351
  L3 (Sign) w0.098: v21(126.929,320.091) 128.897,322.059 128.905,322.059 129.197,322.351 v2(131.407,322.351)
eMMC_data5: R102.2 U41.B4 | length 6.6
  L1 w0.098: v2(131.407,320.319) 131.466,320.319 131.665,320.518 132.917,320.518 R102.2@133.116,320.319
  L3 (Sign) w0.098: v21(126.938,319.591) 127.478,319.591 128.207,320.319 v2(131.407,320.319)
eMMC_data6: R103.2 U41.B5 | length 6.5
  L1 w0.098: v2(131.407,318.287) R103.2@133.116,318.287
  L3 (Sign) w0.098: v21(126.938,319.091) 130.427,319.091 131.231,318.287 v2(131.407,318.287)
eMMC_data7: R104.2 U41.B6 | length 7.1
  L1 w0.098: v2(131.416,316.255) R104.2@133.116,316.255
  L3 (Sign) w0.098: v21(126.938,318.591) 128.563,318.591 130.899,316.255 v2(131.416,316.255)
eMMC_PG1: R340.1 U35_I2C_Expander_00.28 U40.5 | length 2.8
  L1 w0.2: U40.5@109.512,331.771 111.571,331.771 112.037,332.237 R340.1@112.037,332.287
eMMC_PG2: R343.1 R345.1 U35_I2C_Expander_00.27 U42.5 | length 3.8
  L1 w0.2: R343.1@134.727,328.019 134.777,328.019 135.276,328.517 U42.5@135.276,329.46 136.554,329.46 136.729,329.285 136.729,329.235 137.029,328.935 137.111,328.935
eMMC_rst: R99.1 R797.1 U41.K5 | length 13.9
  L1 w0.098: v2(131.416,313.22) R797.1@133.103,313.22
  L1 w0.12: R797.1@133.103,313.22 133.103,312.204 R99.1@133.129,312.179
  L1 w0.254: U41.K5@122.938,319.091 v21(122.949,319.091)
  L3 (Sign) w0.098: v21(122.949,319.091) 123.199,319.341 124.94,319.341 131.062,313.22 v2(131.416,313.22)
eMMC_Vcc: C517.2 C518.2 C523.2 C586.2 FB25.1 R339.2 R340.2 U40.8 U41.E6 U41.F5 U41.J10 U41.K9
eMMC_VccQ: C519.2 C520.2 C524.2 C587.2 FB25.2 R342.2 R343.2 U41.C6 U41.M4 U41.N4 U41.P3 U41.P5 U42.8
eMMC_Vddim: C521.2 C522.2 U41.C2
EN1: U35_I2C_Expander_PWR_CLK.26 U61.20
EN1_TPS: R277.2 R278.2 U34.14 U34.27 U70.20 | length 21.1
  L1 w0.254: R278.2@64.339,240.856 64.783,240.856 65.822,239.817 U34.27@65.822,237.639 ; v2(65.39,229.317) 65.295,229.412 65.295,231.213 65.815,231.733 65.815,232.984 65.82,232.989 65.82,233.137 U34.14@65.822,233.139
  L3 (Sign) w0.254: v2(65.39,229.317) 65.1,229.607 65.1,237.122 65.822,237.843 65.822,240.309 65.39,240.741 65.39,241.677
EN2: U35_I2C_Expander_PWR_CLK.27 U61.6
EN2_TPS: R745.1 U70.6 U70.17
EN_0.85V_REG1: S5.8 U34.1 U34.8
En_0V85@2A: R296.2 R435.2 U37.14 | length 1.9
  L1 w0.254: U37.14@66.175,177.317 66.177,177.315 66.177,176.889 66.836,176.23 66.841,176.23 67.204,175.867 R296.2@67.204,175.817
EN_1V0@1.5A: R634.1 U51.3 U68.4 | length 1.3
  L1 w0.12: R634.1@108.791,248.634 U68.4@110.064,248.634
EN_1V8@1.5A: R633.1 U50.3 U68.5 | length 1.3
  L1 w0.12: R633.1@108.791,247.684 U68.5@110.064,247.684
EN_2V5@1.5A: R632.1 U49.3 U68.6 | length 1.3
  L1 w0.12: R632.1@108.791,246.733 U68.6@110.064,246.733
EN_3V3V_REG0: S5.6 U37.1
EN_5V_REG0: S5.7 U38.8
EN_12@8A: S5.5 U38.1
EN_Detect: R655.2 U35_I2C_Expander_12.3 | length 68.5
  L1 w0.2: v1(139.266,175.425) U35_I2C_Expander_12.3@139.266,176.69
  L1 w0.5: v1(200.453,165.24) 200.694,164.999 R655.2@201.589,164.999
  L5 (Sign) w0.5: v1(139.266,175.425) 150.195,164.496 188.023,164.496 188.767,165.24 v1(200.453,165.24)
EN_PS_LTC6952_1: U35_I2C_Expander_PWR_CLK.18 U59_U_5V_to_3V33.3
EN_PS_LTC6952_2: U35_I2C_Expander_PWR_CLK.22 U59_U_5V_to_3V32.3
EN_PS_LTC6952_3: U35_I2C_Expander_PWR_CLK.24 U59_U_5V_to_3V31.3
EN_PWR_PCIE_3: U22.A2 U35_I2C_Expander_02.24 | length 21.1
  L1 w0.2: U22.A2@93.673,381.921 v7(93.673,382.471) ; v7(111.472,379.307) U35_I2C_Expander_02.24@112.555,379.307
  L3 (Sign) w0.2: v7(93.673,382.471) 94.123,382.921 95.694,382.921 99.308,379.307 v7(111.472,379.307)
En_PWRSwitch_PCIE0: U17.A2 U35_I2C_Expander_10.27
En_PWRSwitch_PCIE1: U20.A2 U35_I2C_Expander_11.19
En_PWRSwitch_PCIE2: U21.A2 U35_I2C_Expander_10.17
En_PWRSwitch_PCIE4: U23.A2 U35_I2C_Expander_11.27 | length 0
  L1 w0.2: 142.85,263.263 142.856,263.257
EN_SEQ_LT3504: R646.2 U67.3 U69.5 | length 3.5
  L1 w0.2: R646.2@127.572,230.276 127.63,230.335 U69.5@127.63,233.718
EN_SPI_Q0_MAIN: R232_SPI_bridge_Main.1 U35_I2C_Expander_11.20
EN_SPI_Q1: R234_SPI_bridge_PCIe.1 U35_I2C_Expander_11.17 | length 69.1
  L1 w0.12: U35_I2C_Expander_11.17@199.589,249.285 199.589,250.485 199.943,250.839 243.975,250.839 249.802,256.667 257.102,256.667 258.537,258.102 258.537,261.452 257.525,262.464 R234_SPI_bridge_PCIe.1@256.491,262.464
EN_SPI_Q1_MAIN: R234_SPI_bridge_Main.1 U35_I2C_Expander_11.22
EN_SPI_Q2: R235_SPI_bridge_PCIe.2 U35_I2C_Expander_10.4 | length 17.2
  L1 w0.12: U35_I2C_Expander_10.4@208.43,366.065 208.43,364.914 208.655,364.689 217.589,364.689 222.05,369.15 222.1,369.15 222.34,369.39 R235_SPI_bridge_PCIe.2@222.34,369.44
EN_SPI_Q4: R239_SPI_bridge_PCIe.1 U35_I2C_Expander_11.25 | length 26.3
  L1 w0.12: R239_SPI_bridge_PCIe.1@175.098,259.299 176.033,259.299 179.678,255.653 188.922,246.41 U35_I2C_Expander_11.25@196.064,246.41
EN_SPI_Q4_MAIN: R239_SPI_bridge_Main.1 U35_I2C_Expander_11.28
EN_VSUP_1V2: C626.2 R309.1 U19.12 | length 5.8
  L1 w0.12: U19.12@174.078,167.05 174.078,166.539 174.654,165.963 v7(175.078,165.963) C626.2@175.078,165.753 ; R309.1@177.539,163.705 v7(177.539,164.439)
  L3 (Sign) w0.12: v7(175.078,165.963) 176.015,165.963 v7(177.539,164.439)
EN_VSUP_1V8: C625.2 R308.1 U19.15 | length 5.2
  L1 w0.12: U19.15@175.728,167.7 C625.2@176.862,167.7 176.862,167.108 176.589,166.835 R308.1@176.589,163.705
EN_VSUP_3V3: C624.2 R305.1 U19.14 | length 4.6
  L1 w0.12: U19.14@175.078,167.05 175.078,166.825 175.313,166.59 175.525,166.59 175.676,166.44 175.676,165.918 175.741,165.853 175.741,165.843 175.831,165.753 C624.2@175.841,165.753 176.298,165.753 176.369,165.683 176.369,164.831 175.639,164.101 R305.1@175.639,163.705
Enable_CLK: U12.40 U13.40 U35_I2C_Expander_Main_Rst.2 | length 1
  L16 w0.12: U12.40@95.947,337.461 95.947,337.946 v9(96.329,338.328)
ETH_VDDIO: C491.2 C492.2 C493.2 C494.2 C495.2 C496.2 C497.2 C498.2 C531.1 C547.2 C612.2 C613.2 C614.2 C615.2 C742.1 C743.2 C790.2 L17.2 R83.2 R84.2 R85.2 R86.2 R97.2 R98.2 R99.2 R106.1 R123.2 R216.1 R319.2 R320.2 R322.2 R323.2 R333.1 R336.1 R337.1 R338.1 R346.1 R347.1 R348.1 R349.2 R350.2 R351.2 R352.2 R353.1 R354.2 R355.1 R356.1 R357.2 R367.2 R368.2 R369.2 R370.2 R371.2 R372.2 R381.2 R382.2 R709.1 R710.2 R715.2 R716.2 R717.2 R718.2 R719.2 R737.2 R911.1 U1.B22 U1.B27 U1.D18 U1.D23 U1.D28 U1.E21 U1.E26 U1.F19 U1.J18 U1.N20 U1.P18 U36_U_Translator_I2C2.2 U39.19 U39.30 U39.41 U43.1 U43.2 U43.7 U43.8 U43.15 U43.16 U44.1 U47.B3 U53.15 U56.15 U57.15 U68.3 U76.5 | length 91.1
  L1 w0.254: C614.2@166.001,181.153 166.274,181.426 166.274,181.83 166.424,181.98 177.976,181.98 179.984,179.972 R216.1@179.984,173.465
  L1 w0.3: v5(162.909,310.027) U1.B22@163.397,309.539 ; v5(162.909,315.027) U1.B27@163.397,314.539 ; v5(164.909,311.027) U1.D23@165.397,310.539 ; U1.D18@165.397,305.539 v5(165.884,305.052) ; U1.D28@165.397,315.539 v5(165.884,316.027) ; v5(165.909,309.027) U1.E21@166.397,308.539 ; v5(165.909,314.027) U1.E26@166.397,313.539 ; U1.F19@167.397,306.539 v5(167.884,306.052) ; v5(169.909,306.027) U1.J18@170.397,305.539 ; U1.N20@174.397,307.539 v5(174.884,307.052) ; U1.P18@175.397,305.539 v5(175.884,305.052)
  L1 w0.5: 165.989,183.54 179.159,183.54 183.192,179.507 v2(183.192,178.663) ; v2(204.102,159.893) 204.114,159.88 R106.1@204.114,159.048
  L3 (Sign) w0.5: v2(183.192,178.663) 183.192,176.853 188.233,171.812 188.233,164.943 189.867,163.309 200.685,163.309 v2(204.102,159.893)
  L16 w0.12: R709.1@108.074,271.094 108.567,271.094 109.029,271.557 109.029,272.39 109.601,272.961 109.601,274.141 109.049,274.693 U39.41@109.049,275.125 ; v1(108.204,283.896) 108.549,283.55 U39.19@108.549,281.925
  other v22: 134.729,335.804
EXPANDER_RESET: J21.2 P13.2 R811.1 R1003.2 T1.1
FB1/FB2: R271.1 R273.2 U34.10 U34.31 | length 12.3
  L1 w0.254: 61.041,239.87 61.041,239.82 v27(61.441,239.42) ; v23(62.82,232.364) 63.543,232.364 63.82,232.64 63.82,233.137 U34.10@63.822,233.139 ; R273.2@62.939,239.52 62.822,239.403 v23(62.822,238.22) 62.831,238.229 63.571,238.229 63.82,237.981 63.82,237.641 U34.31@63.822,237.639
  L16 w0.254: v27(61.441,239.42) 62.674,239.42 62.774,239.52 v27(62.814,239.52) ; v23(62.82,232.364) 62.821,232.365 v23(62.822,238.22) v23(62.822,238.22)
FB1_1: R287.1 R290.2 U37.31 | length 4.2
  L1 w0.2: R287.1@61.241,183.359 R290.2@62.191,183.359 62.191,182.894 62.586,182.499 64.021,182.499 64.175,182.345 U37.31@64.175,181.817
FB1_2: R626.1 R627.2 U38.31 | length 3.3
  L1 w0.254: R626.1@59.997,209.711 60.008,209.722 60.932,209.722 R627.2@60.944,209.733 61.102,209.575 62.252,209.575 62.453,209.374 U38.31@62.453,208.714
FB2_1: R297.1 R300.2 U37.10 | length 4.1
  L1 w0.254: R300.2@61.068,175.851 R297.1@62.14,175.851 62.14,176.257 62.455,176.572 63.749,176.572 64.175,176.997 U37.10@64.175,177.317
FB2_2: R315.1 R318.2 U38.10 | length 3.5
  L1 w0.254: R318.2@60.114,202.723 R315.1@61.041,202.723 61.041,203.148 61.384,203.491 62.28,203.491 62.453,203.664 U38.10@62.453,204.214
Flag_PWRSwitch_PCIE0: R618.2 U17.A3
Flag_PWRSwitch_PCIE1: R688.2 U20.A3
Flag_PWRSwitch_PCIE2: R744.2 U21.A3
Flag_PWRSwitch_PCIE3: R767.2 U22.A3
Flag_PWRSwitch_PCIE4: R819.2 U23.A3
FTD_DS_Dir1: R411.2 R412.2 U56.1
FTD_DS_Dir2: R413.2 R414.2 U56.2
FTD_DS_Dir3: R415.2 R416.2 U56.7
FTD_DS_Dir4: R418.2 R421.2 U56.8
FTD_JTAG_Dir1: R402.2 R403.2 U53.1
FTD_JTAG_Dir2: R404.2 R405.2 U53.2
FTD_JTAG_Dir3: R406.2 R407.2 U53.7
FTD_JTAG_Dir4: R408.2 R409.2 U53.8
FTD_U1_DIR1: R722.2 R723.2 U79.1 | length 5.8
  L1 w0.2: v2(225.958,225.527) 226.448,226.016 U79.1@226.448,227.025 ; R722.2@225.959,222.14 v2(225.958,222.821) ; v2(225.958,222.821) R723.2@225.959,223.5
  L3 (Sign) w0.2: v2(225.958,222.821) v2(225.958,225.527)
FTD_U1_DIR2: R724.2 R725.2 U79.2 | length 5.6
  L1 w0.2: R724.2@227.098,222.14 v2(227.098,222.821) R725.2@227.098,223.5 ; U79.2@227.098,227.025 227.101,227.022 v2(227.101,225.501)
  L3 (Sign) w0.2: v2(227.098,222.821) v2(227.098,222.821) 227.1,225.499 v2(227.101,225.501)
FTD_U1_DIR3: R726.2 R727.2 U79.7 | length 5.6
  L1 w0.2: R726.2@230.348,222.14 v7(230.348,222.82) R727.2@230.348,223.5 ; v7(230.348,225.527) U79.7@230.348,227.025
  L3 (Sign) w0.2: v7(230.348,222.82) v7(230.348,225.527)
FTD_U1_DIR4: R728.2 R729.2 U79.8 | length 5.8
  L1 w0.2: v7(230.998,225.527) U79.8@230.998,227.025 ; R728.2@231.487,222.14 v7(231.487,222.82) R729.2@231.487,223.5
  L3 (Sign) w0.2: v7(230.998,225.527) 230.998,223.309 v7(231.487,222.82)
FTD_U_DIR1: R636.2 R637.2 U57.1
FTD_U_DIR2: R638.2 R639.2 U57.2
FTD_U_DIR3: R640.2 R641.2 U57.7
FTD_U_DIR4: R642.2 R643.2 U57.8
FTDI_5V: C559.2 C560.2 C563_5V_to_3V3_for_FTDI.2 C564_5V_to_3V3_for_FTDI.2 FB31.1 U59_5V_to_3V3_for_FTDI.1 U59_5V_to_3V3_for_FTDI.2 U59_5V_to_3V3_for_FTDI.3
FTDI_DM: C558.2 D15.2 U55.7
FTDI_DP: C558.3 D15.1 U55.8
FTDI_EECLK: R417.2 U54.4 U55.62
FTDI_EECS: R420.2 U54.5 U55.63
FTDI_EED: R419.1 U54.3 U55.61 | length 4
  L1 w0.12: U55.61@251.27,208.016 252.606,208.016 254.021,209.431 R419.1@254.665,209.431
FTDI_GND: C559.1 C560.1 C563_5V_to_3V3_for_FTDI.1 C564_5V_to_3V3_for_FTDI.1 C565_5V_to_3V3_for_FTDI.1 C566_5V_to_3V3_for_FTDI.1 C567_5V_to_3V3_for_FTDI.1 C658.1 C659.1 C660.1 C661.1 C662.1 C663.1 C664.1 C665.1 C666.1 C667.1 C668.1 C669.1 C670.1 C671.1 C673.1 C791.1 FB32.1 R403.1 R405.1 R407.1 R409.1 R412.1 R414.1 R416.1 R421.1 R423.1 R432_5V_to_3V3_for_FTDI.1 R637.1 R639.1 R641.1 R643.1 R723.1 R725.1 R727.1 R729.1 S9.5 S9.6 S9.7 S9.8 U53.10 U54.2 U55.1 U55.5 U55.10 U55.11 U55.13 U55.15 U55.25 U55.35 U55.47 U55.51 U56.10 U57.10 U59_5V_to_3V3_for_FTDI.4 U59_5V_to_3V3_for_FTDI.9 U77.2 U79.10 X8.2 X8.4
  other v4: 243.861,231.859 244.861,231.859 243.861,232.859 244.861,232.859
FTDI_JTAG_ON: R1001.2 R1034.2
FTDI_JTAG_ON_1: R401.1 R1001.1 S8.1 S9.1 U35_I2C_Expander_12.20 U53.9 | length 124.9
  L1 w0.2: U35_I2C_Expander_12.20@138.616,182.44 138.616,185.314 v1(138.684,185.382) ; U53.9@217.924,202.433 217.924,201.621 v2(217.957,201.587)
  L12 (Sign) w0.2: v1(138.684,185.382) 138.684,186.155 139.567,187.038 214.346,187.038 219.235,182.148 v1(222.102,182.148)
  L3 (Sign) w0.2: 85.472,329.763 85.509,329.763 ; v2(217.957,201.587) 219.215,200.33 219.215,183.165 220.232,182.148 v1(222.102,182.148)
  L16 w0.12: R401.1@221.092,175.874 S9.1@223.829,175.874
  L16 w0.2: R401.1@221.092,175.874 221.092,177.6 221.543,178.052 221.543,180.455 222.102,181.014 v1(222.102,182.148) ; R1001.1@221.092,182.148 v1(222.102,182.148) ; S8.1@223.829,182.148 v1(222.102,182.148)
FTDI_JTAG_ON_2: R410.1 S8.2 S9.2 U35_I2C_Expander_12.21 U56.9 | length 255.6
  L1 w0.2: v1(135.23,189.166) 135.23,188.186 v1(138.034,185.382) 137.966,185.314 U35_I2C_Expander_12.21@137.966,182.44
  L12 (Sign) w0.2: v1(138.034,185.382) 138.034,186.472 138.9,187.338 214.47,187.338 218.39,183.418 v1(221.988,183.418)
  L3 (Sign) w0.2: v1(97.761,291.73) 94.385,291.73 90.576,287.922 90.576,285.932 97.346,279.162 97.346,259.359 98.285,258.42 101.638,258.42 109.334,250.723 115.621,250.723 119.52,246.825 119.52,196.672 121.094,195.097 121.691,195.097 124.282,197.688 130.887,197.688 132.105,196.469 132.105,192.291 v1(135.23,189.166)
  L16 w0.2: v1(97.761,291.73) U56.9@99.259,291.73 ; R410.1@221.092,183.418 S8.2@223.829,183.418 225.105,183.418 225.604,182.92 225.604,181.72 224.955,181.07 222.596,181.07 221.843,180.317 221.843,178.057 222.756,177.144 225.388,177.144 225.836,176.697 225.836,175.703
FTDI_JTAG_ON_3: R635.1 S8.3 S9.3 U35_I2C_Expander_12.22 U57.9 | length 152.3
  L1 w0.2: v1(135.133,185.382) 135.133,182.223 135.84,181.515 U35_I2C_Expander_12.22@137.041,181.515 ; U57.9@223.198,194.248 223.198,195.202 v2(223.215,195.219)
  L12 (Sign) w0.2: v1(135.133,185.382) 137.391,187.641 206.637,187.641 206.64,187.638 214.594,187.638 217.544,184.688 v1(222.102,184.688)
  L3 (Sign) w0.2: 90.78,313.982 109.728,313.982 115.646,308.064 115.646,307.518 ; v1(222.102,184.688) 223.215,185.801 v2(223.215,195.219) ; v1(225.874,178.433) 226.496,177.811
  L16 w0.2: R635.1@221.092,184.688 S8.3@223.829,184.688 225.105,184.688 225.904,183.89 225.904,181.595 225.079,180.77 222.72,180.77 222.143,180.193 222.143,178.752 222.481,178.414 S9.3@223.829,178.414 ; S9.3@223.848,178.433 v1(225.874,178.433)
FTDI_JTAG_ON_4: R721.1 S8.4 S9.4 U35_I2C_Expander_12.23 U79.9 | length 164.6
  L1 w0.2: v1(134.533,185.382) 134.533,181.951 135.619,180.865 U35_I2C_Expander_12.23@137.041,180.865 ; U79.9@230.998,232.825 v1(232.562,232.825)
  L12 (Sign) w0.2: v1(134.533,185.382) 134.533,185.418 137.055,187.941 206.761,187.941 206.764,187.938 214.719,187.938 216.698,185.958 v1(221.924,185.958)
  L3 (Sign) w0.2: v1(221.924,185.958) 221.239,186.643 221.239,195.471 224.828,199.06 224.828,202.063 225.047,202.063 225.267,202.283 225.267,202.593 225.152,202.708 225.152,207.689 224.828,208.013 224.828,228.575 227.089,230.835 230.573,230.835 v1(232.562,232.825)
  L16 w0.2: R721.1@221.092,185.958 S8.4@223.829,185.958 225.366,185.958 ; S9.4@223.829,179.684 224.417,179.684 226.204,181.471 226.204,185.12 225.366,185.958 ; 226.09,185.952 226.083,185.958 225.366,185.958
FTDI_LS_UART0_RXD: R1039.2 U79.4
FTDI_LS_UART0_TXD: R1038.2 U79.3
FTDI_LS_UART2_CTS_B: R1011.1 U55.41 | length 8.4
  L1 w0.12: U55.41@245.97,200.216 245.97,197.2 246.729,196.44 R1011.1@246.729,192.101
FTDI_LS_UART2_RTS_B: R1010.1 U55.40 | length 5.9
  L1 w0.12: U55.40@245.47,200.216 245.47,196.935 245.839,196.566 R1010.1@245.839,194.487
FTDI_LS_UART2_RXD: R1045.2 U57.6
FTDI_LS_UART2_TXD: R1044.2 U57.5
FTDI_LS_UART_RXD: R1047.2 U57.4
FTDI_LS_UART_TXD: R1046.2 U57.3
FTDI_PS_POR: R1036.2 U77.1
FTDI_PS_SRST+B: R1037.2 U77.3
FTDI_Sock_GND: C558.5 FB32.2
FTDI_TCK: P12.7 R733.1 R1030.2 U53.5 U56.5 | length 17.5
  L1 w0.12: R733.1@195.466,204.289 P12.7@198.171,204.289 199.183,205.301 201.642,205.301 202.56,204.383 U53.5@212.124,204.383
FTDI_TDI: P12.11 R730.1 R1031.2 U53.3 U56.3 | length 18.2
  L1 w0.12: R730.1@195.466,209.369 P12.11@198.171,209.369 199.555,207.985 202.324,207.985 204.625,205.683 U53.3@212.124,205.683
FTDI_TDO: P12.5 R732.1 R1032.2 U53.6 U56.6 | length 17.5
  L1 w0.12: R732.1@195.466,201.749 P12.5@198.171,201.749 199.326,202.905 201.714,202.905 202.542,203.733 U53.6@212.124,203.733
FTDI_TMS: P12.9 R734.1 R1033.2 U53.4 U56.4 | length 17.4
  L1 w0.12: R734.1@195.466,206.829 P12.9@198.171,206.829 199.212,205.787 202.374,205.787 203.129,205.033 U53.4@212.124,205.033
FTDI_VBUS: C558.1 FB31.2
FTDI_VCC1P8: C665.2 C666.2 C667.2 C673.2 U55.12 U55.37 U55.49 U55.64
FTDI_VccIO: C565_5V_to_3V3_for_FTDI.2 C566_5V_to_3V3_for_FTDI.2 C567_5V_to_3V3_for_FTDI.2 C658.2 C668.2 C669.2 C670.2 C671.2 C791.2 FB43.1 FB44.1 R401.2 R402.1 R404.1 R406.1 R408.1 R410.2 R411.1 R413.1 R415.1 R417.1 R418.1 R420.1 R422.2 R424.1 R430_5V_to_3V3_for_FTDI.2 R431_5V_to_3V3_for_FTDI.2 R635.2 R636.1 R638.1 R640.1 R642.1 R721.2 R722.1 R724.1 R726.1 R728.1 R1048.1 R1049.1 R1050.1 R1051.1 U53.16 U54.6 U55.20 U55.31 U55.42 U55.50 U55.56 U56.16 U57.16 U59_5V_to_3V3_for_FTDI.8 U77.5 U79.16
FTDI_X_IN: C663.2 U55.2 X8.1
FTDI_X_OUT: C664.2 U55.3 X8.3
GEM3_MDC: R815.1 U39.16 | length 6.2
  L16 w0.12: R815.1@104.005,286.337 104.005,285.783 105.105,284.683 106.007,284.683 107.049,283.641 U39.16@107.049,281.925
GEM3_MDIO: R333.2 R816.1 U39.17 | length 6.1
  L16 w0.12: R816.1@105.075,286.337 R333.2@106.145,286.337 106.145,285.765 107.549,284.36 U39.17@107.549,281.925
GPIO_ETH_EXPANDER: R715.1 U35_I2C_Expander_00.1 U76.2
GPIO_Exp10_Adress0: R492.2 R493.1 U35_I2C_Expander_00.13 | length 9.5
  L1 w0.2: U35_I2C_Expander_00.13@107.008,321.446 108.822,321.446 110.05,322.675 112.609,322.675 112.859,322.425 R492.2@112.859,321.485 ; R493.1@112.859,319.453 v7(112.859,319.578)
  L3 (Sign) w0.2: v7(112.859,319.578) v7(112.859,321.535)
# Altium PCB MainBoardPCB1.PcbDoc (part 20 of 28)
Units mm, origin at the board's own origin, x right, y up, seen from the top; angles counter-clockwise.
Board outline 258.95 x 308.86 mm, 16 copper layers (L1, L2 (GND), L3 (Sign), L4 (GND), L5 (Sign), L6 (PWR/GND), L7(PWR/GND), L8 (Plane_GND), L9 (PWR/GND), L10 (PWR/GND), L11 (PWR/GND), L12 (Sign), L13 (GND), L14 (Sign), L15 (GND), L16), stack 2.502 mm thick; 2397 components, 1744 nets, 8397 pads, 4112 vias.
Unrouted connection lines stored in the file: 3547.

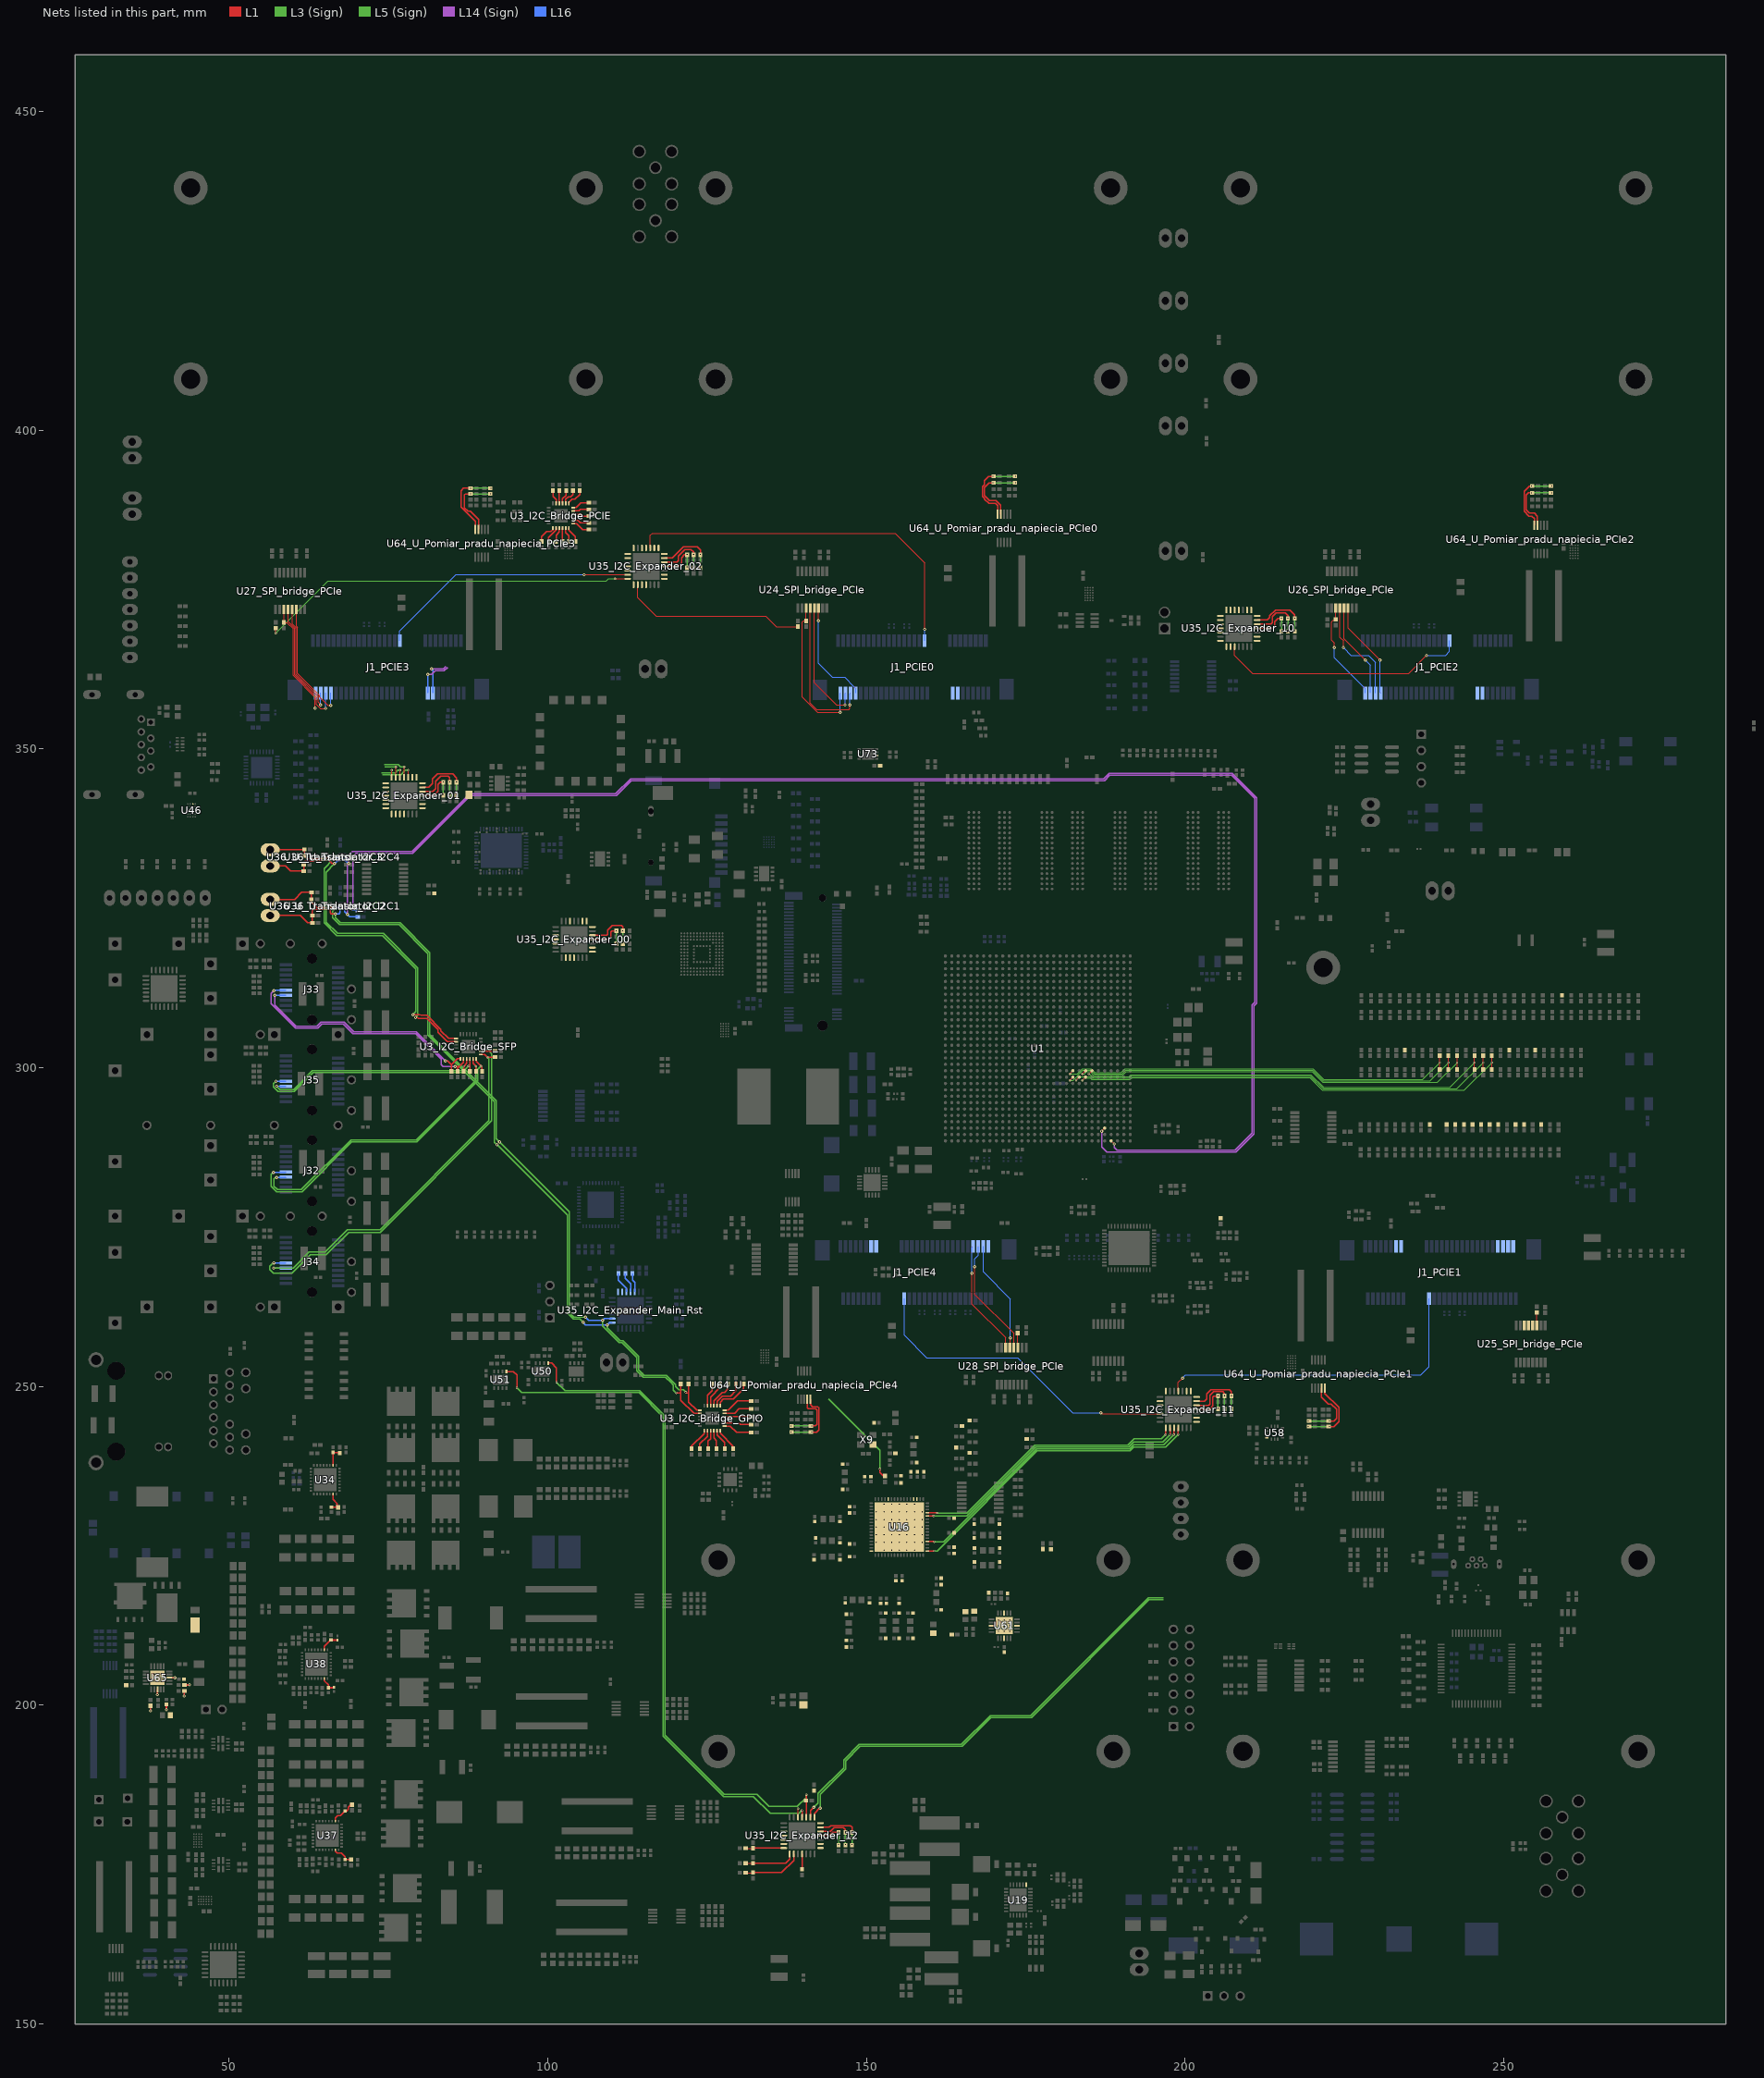
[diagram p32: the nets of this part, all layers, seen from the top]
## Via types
v1: diameter 0.5, hole 0.2, L1 to L16, tented both sides, 1457 vias
v2: diameter 0.35/0/0.35 (per signal layer), hole 0.127, L1 to L3 (Sign), tented both sides, 479 vias
v3: diameter 0.5/0.35/0.35/0.35/0.35/0.35/0.35/0.35/0.35/0.35/0.35/0.35/0.35/0.35/0.35/0.5 (per signal layer), hole 0.15, L1 to L16, tented both sides, 453 vias
v4: diameter 0.5, hole 0.2, L1 to L16, 451 vias
v5: diameter 0.5/0.35/0.35/0.35/0.35/0.35/0.35/0.35/0.35/0.35/0.35/0.35/0.35/0.35/0.35/0.5 (per signal layer), hole 0.2, L1 to L16, tented both sides, 373 vias
v6: diameter 0.8, hole 0.4, L1 to L16, tented both sides, 168 vias
v7: diameter 0.35/0/0.35 (per signal layer), hole 0.127, L1 to L3 (Sign), 138 vias
v8: diameter 2.54, hole 1.02, L1 to L16, 113 vias
v9: diameter 0.5/0/0.5 (per signal layer), hole 0.2, L14 (Sign) to L16, tented both sides, 102 vias
v10: diameter 1.4, hole 0.5, L1 to L16, tented both sides, 80 vias
v11: diameter 0.5, hole 0.2, L3 (Sign) to L6 (PWR/GND), tented both sides, 54 vias
v12: diameter 0.35, hole 0.127, L1 to L2 (GND), tented both sides, 47 vias
v13: diameter 0.4, hole 0.2, L1 to L16, tented both sides, 46 vias
v14: diameter 0.35, hole 0.127, L1 to L16, tented both sides, 16 vias
v15: diameter 0.25, hole 0.2, L1 to L16, 16 vias
v16: diameter 0.5, hole 0.2, L11 (PWR/GND) to L14 (Sign), tented both sides, 16 vias
v17: diameter 0.4, hole 0.2, L1 to L16, 16 vias
v18: diameter 0.3, hole 0.2, L1 to L16, 15 vias
v19: diameter 0.45, hole 0.15, L1 to L16, 12 vias
v20: diameter 0.5/0.35/0.35/0.35/0.35/0.35/0.35/0.35/0.35/0.35/0.35/0.35/0.35/0.35/0.35/0.45 (per signal layer), hole 0.15, L1 to L16, tented both sides, 10 vias
v21: diameter 0.2/0/0.2 (per signal layer), hole 0.1, L1 to L3 (Sign), tented both sides, 9 vias
v22: diameter 0.3, hole 0.127, L14 (Sign) to L16, tented both sides, 8 vias
v23: diameter 0.4, hole 0.1, L1 to L16, 7 vias
v24: diameter 1.15, hole 1.15, L1 to L16, 5 vias
v25: diameter 1.65, hole 1.65, L1 to L16, 5 vias
v26: diameter 0.2, hole 0.1, L1 to L16, 4 vias
v27: diameter 0.4, hole 0.15, L1 to L16, 2 vias
v28: diameter 0.5/0.35/0.35/0.35/0.35/0.35/0.35/0.35/0.35/0.35/0.35/0.35/0.35/0.35/0.35/0.5 (per signal layer), hole 0.15, L1 to L16, 2 vias
v29: diameter 0.35, hole 0.127, L3 (Sign) to L6 (PWR/GND), tented both sides, 2 vias
v30: diameter 0.3, hole 0.127, L15 (GND) to L16, tented both sides, 1 vias
v31: diameter 0.35, hole 0.127, L1 to L2 (GND), 1 vias
v32: diameter 0.5/0.35/0.35/0.35/0.35/0.35/0.35/0.35/0.35/0.35/0.35/0.35/0.35/0.35/0.35/0.5 (per signal layer), hole 0.2, L1 to L16, 1 vias
v33: diameter 0.35/0.35/0.35 (per signal layer), hole 0.127, L1 to L3 (Sign), tented both sides, 1 vias
v34: diameter 0.45/0/0.45 (per signal layer), hole 0.15, L1 to L3 (Sign), tented both sides, 1 vias
v35: diameter 0.45/0/0.45 (per signal layer), hole 0.2, L14 (Sign) to L16, tented both sides, 1 vias

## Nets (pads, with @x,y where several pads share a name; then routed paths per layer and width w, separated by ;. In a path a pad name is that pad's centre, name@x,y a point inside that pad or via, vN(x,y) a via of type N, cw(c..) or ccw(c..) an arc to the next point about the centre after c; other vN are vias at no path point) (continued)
GPIO_Exp10_Adress1: R494.2 R495.1 U35_I2C_Expander_00.12 | length 8.6
  L1 w0.2: U35_I2C_Expander_00.12@107.008,320.796 109.27,320.796 109.387,320.914 109.387,321.588 110.141,322.341 111.586,322.341 111.785,322.142 v7(111.785,321.485) ; R495.1@111.785,319.453 v7(111.785,319.578)
  L3 (Sign) w0.2: v7(111.785,319.578) v7(111.785,321.485)
GPIO_Exp10_Adress2: R496.2 R497.1 U35_I2C_Expander_00.11 | length 6.8
  L1 w0.2: U35_I2C_Expander_00.11@107.008,320.146 109.569,320.146 109.933,320.51 109.933,321.329 110.05,321.446 110.731,321.446 v7(110.769,321.485) ; R497.1@110.769,319.453 v7(110.769,319.578)
  L3 (Sign) w0.2: v7(110.769,319.578) v7(110.769,321.485)
GPIO_Exp10_Int0: R871.2 U35_I2C_Expander_00.16
GPIO_Exp10_Int1: R872.2 U35_I2C_Expander_00.15
GPIO_Exp11_Adress0: R500.2 R501.1 U35_I2C_Expander_01.13 | length 9.7
  L1 w0.2: U35_I2C_Expander_01.13@80.338,343.989 81.318,343.989 81.917,344.588 81.917,345.304 82.695,346.081 85.073,346.081 85.683,345.471 R500.2@85.683,344.784 ; R501.1@85.683,342.752 v7(85.683,342.877)
  L3 (Sign) w0.2: v7(85.683,342.877) v7(85.683,344.834)
GPIO_Exp11_Adress1: R502.2 R503.1 U35_I2C_Expander_01.12 | length 8.9
  L1 w0.2: U35_I2C_Expander_01.12@80.338,343.339 81.984,343.339 82.437,343.792 82.437,344.978 83.198,345.739 84.396,345.739 84.625,345.51 84.625,344.8 R502.2@84.609,344.784 ; R503.1@84.609,342.752 v7(84.609,342.877)
  L3 (Sign) w0.2: v7(84.609,342.877) v7(84.609,344.834)
GPIO_Exp11_Adress2: R504.2 R505.1 U35_I2C_Expander_01.11 | length 6.8
  L1 w0.2: U35_I2C_Expander_01.11@80.338,342.689 82.105,342.689 82.785,343.369 82.785,344.456 83.112,344.784 R504.2@83.593,344.784 ; R505.1@83.593,342.752 v7(83.593,342.877)
  L3 (Sign) w0.2: v7(83.593,342.877) v7(83.593,344.834)
GPIO_Exp11_Int0: R873.2 U35_I2C_Expander_01.16
GPIO_Exp11_Int1: R874.2 U35_I2C_Expander_01.15
GPIO_Exp12_Adress0: R508.2 R509.1 U35_I2C_Expander_02.13 | length 9.4
  L1 w0.2: U35_I2C_Expander_02.13@118.305,379.957 119.527,379.957 121.277,381.707 123.48,381.707 123.963,381.224 R508.2@123.963,380.478 ; R509.1@123.963,378.446 v7(123.963,378.571)
  L3 (Sign) w0.2: v7(123.963,378.571) v7(123.963,380.528)
GPIO_Exp12_Adress1: R510.2 R511.1 U35_I2C_Expander_02.12 | length 8.4
  L1 w0.2: U35_I2C_Expander_02.12@118.305,379.307 120.297,379.307 120.517,379.528 120.517,380.31 121.509,381.302 122.489,381.302 122.889,380.903 v7(122.889,380.528) R510.2@122.889,380.478
  L3 (Sign) w0.2: v7(122.889,378.571) v7(122.889,380.528)
GPIO_Exp12_Adress2: R512.2 R513.1 U35_I2C_Expander_02.11 | length 6.9
  L1 w0.2: U35_I2C_Expander_02.11@118.305,378.657 120.517,378.657 121.018,379.159 121.018,380.023 121.473,380.478 R512.2@121.873,380.478 ; R513.1@121.873,378.446 v7(121.873,378.571)
  L3 (Sign) w0.2: v7(121.873,378.571) v7(121.873,380.528)
GPIO_Exp12_Int0: R875.2 U35_I2C_Expander_02.16
GPIO_Exp12_Int1: R876.2 U35_I2C_Expander_02.15
GPIO_Exp13_Adress0: R516.2 R517.1 U35_I2C_Expander_10.13 | length 9.6
  L1 w0.2: U35_I2C_Expander_10.13@211.305,370.24 212.89,370.24 213.296,370.646 213.296,370.92 214.184,371.807 216.441,371.807 217.215,371.033 v7(217.215,370.495) ; R517.1@217.215,368.463 v7(217.215,368.588)
  L3 (Sign) w0.2: v7(217.215,368.588) v7(217.215,370.495)
GPIO_Exp13_Adress1: R518.2 R519.1 U35_I2C_Expander_10.12 | length 8.8
  L1 w0.2: U35_I2C_Expander_10.12@211.305,369.59 213.466,369.59 213.676,369.8 213.676,370.765 214.259,371.348 215.713,371.348 216.141,370.92 v7(216.141,370.495) ; R519.1@216.141,368.463 v7(216.141,368.588)
  L3 (Sign) w0.2: v7(216.141,368.588) v7(216.141,370.495)
GPIO_Exp13_Adress2: R520.2 R521.1 U35_I2C_Expander_10.11 | length 7
  L1 w0.2: U35_I2C_Expander_10.11@211.305,368.94 213.944,368.94 214.084,369.08 214.084,369.989 214.589,370.495 v7(215.125,370.495) ; R521.1@215.125,368.463 v7(215.125,368.588)
  L3 (Sign) w0.2: v7(215.125,368.588) v7(215.125,370.495)
GPIO_Exp13_Int0: R877.2 U35_I2C_Expander_10.16
GPIO_Exp13_Int1: R878.2 U35_I2C_Expander_10.15
GPIO_Exp14_Adress0: R524.2 R525.1 U35_I2C_Expander_11.13 | length 9.6
  L1 w0.2: U35_I2C_Expander_11.13@201.814,247.71 203.019,247.71 203.369,248.06 203.369,248.826 204.069,249.526 206.954,249.526 207.265,249.215 R524.2@207.265,248.51 ; R525.1@207.265,246.478 v7(207.265,246.603)
  L3 (Sign) w0.2: v7(207.265,246.603) v7(207.265,248.56)
GPIO_Exp14_Adress1: R526.2 R527.1 U35_I2C_Expander_11.12 | length 8.6
  L1 w0.2: U35_I2C_Expander_11.12@201.814,247.06 203.677,247.06 203.901,247.284 203.901,248.639 204.464,249.201 205.925,249.201 206.191,248.935 v7(206.191,248.56) R526.2@206.191,248.51
  L3 (Sign) w0.2: v7(206.191,246.603) v7(206.191,248.56)
GPIO_Exp14_Adress2: R528.2 R529.1 U35_I2C_Expander_11.11 | length 7.1
  L1 w0.2: U35_I2C_Expander_11.11@201.814,246.41 203.793,246.41 204.368,246.985 204.368,248.36 204.518,248.51 R528.2@205.175,248.51 ; R529.1@205.175,246.478 v7(205.175,246.603)
  L3 (Sign) w0.2: v7(205.175,246.603) v7(205.175,248.56)
GPIO_Exp14_Int0: R879.2 U35_I2C_Expander_11.16
GPIO_Exp14_Int1: R880.2 U35_I2C_Expander_11.15
GPIO_Exp15_Adress0: R697.2 R698.1 U35_I2C_Expander_12.13 | length 7.9
  L1 w0.2: U35_I2C_Expander_12.13@142.791,180.865 144.152,180.865 144.423,181.137 147.489,181.137 147.739,180.887 v7(147.739,180.115) R697.2@147.739,180.065
  L3 (Sign) w0.2: v7(147.739,178.19) v7(147.739,180.115)
GPIO_Exp15_Adress1: R699.2 R700.1 U35_I2C_Expander_12.12 | length 6.6
  L1 w0.2: U35_I2C_Expander_12.12@142.791,180.215 144.347,180.215 144.947,180.815 146.373,180.815 146.698,180.49 v7(146.698,180.115) R699.2@146.698,180.065
  L3 (Sign) w0.2: v7(146.698,178.19) v7(146.698,180.115)
GPIO_Exp15_Adress2: R701.2 R702.1 U35_I2C_Expander_12.11 | length 5.1
  L1 w0.2: U35_I2C_Expander_12.11@142.791,179.565 144.197,179.565 144.697,180.065 R701.2@145.653,180.065 ; R702.1@145.653,178.065 v7(145.653,178.19)
  L3 (Sign) w0.2: v7(145.653,178.19) v7(145.653,180.115)
GPIO_Exp15_Int0: R881.2 U35_I2C_Expander_12.16 | length 71.8
  L1 w0.2: U35_I2C_Expander_12.16@141.216,182.44 141.216,183.469 v1(141.719,183.972)
  L5 (Sign) w0.2: v1(141.719,183.972) 142.435,184.688 142.435,186.154 146.44,190.159 146.44,191.41 148.884,193.853 164.913,193.853 169.442,198.382 175.779,198.382 194.245,216.848 196.583,216.848
GPIO_Exp15_Int1: R882.2 U35_I2C_Expander_12.15 | length 71.2
  L1 w0.2: U35_I2C_Expander_12.15@141.866,182.44 141.866,183.082 142.643,183.86 v1(142.735,183.86)
  L5 (Sign) w0.2: v1(142.735,183.86) 142.735,186.03 146.74,190.035 146.74,191.285 149.008,193.553 165.037,193.553 169.566,198.082 175.903,198.082 194.369,216.548 196.583,216.548
GPIO_Exp_Reset0: R746.1 U35_I2C_Expander_00.14 U35_I2C_Expander_01.14 U35_I2C_Expander_02.14 U35_I2C_Expander_Main_Rst.17 | length 3.4
  L16 w0.2: R746.1@111.087,267.731 111.087,266.675 112.348,265.414 U35_I2C_Expander_Main_Rst.17@112.348,264.843
GPIO_Exp_Reset1: R747.1 U35_I2C_Expander_10.14 U35_I2C_Expander_11.14 U35_I2C_Expander_12.14 U35_I2C_Expander_Main_Rst.18 | length 3.2
  L16 w0.2: R747.1@112.185,267.731 112.185,266.948 112.998,266.135 U35_I2C_Expander_Main_Rst.18@112.998,264.843
GPIO_Exp_Reset2: R748.1 U35_I2C_Expander_Main_Rst.19 | length 3
  L16 w0.2: R748.1@113.284,267.731 113.284,266.687 113.648,266.324 U35_I2C_Expander_Main_Rst.19@113.648,264.843
GPIO_I2C0.SCL: R559_I2C_Bridge_GPIO.2 U3_I2C_Bridge_GPIO.2 U35_I2C_Expander_00.8 U35_I2C_Expander_01.8 U35_I2C_Expander_02.8 | length 3.4
  L1 w0.2: R559_I2C_Bridge_GPIO.2@123.867,240.244 123.867,241.012 125.063,242.208 U3_I2C_Bridge_GPIO.2@125.063,243.104
GPIO_I2C0.SDA: R560_I2C_Bridge_GPIO.2 U3_I2C_Bridge_GPIO.1 U35_I2C_Expander_00.9 U35_I2C_Expander_01.9 U35_I2C_Expander_02.9 | length 3.7
  L1 w0.2: R560_I2C_Bridge_GPIO.2@122.562,240.244 122.562,240.634 124.563,242.635 U3_I2C_Bridge_GPIO.1@124.563,243.104
GPIO_I2C1.SCL: R227_I2C_Bridge_GPIO.2 U3_I2C_Bridge_GPIO.4 | length 3
  L1 w0.2: U3_I2C_Bridge_GPIO.4@126.063,243.104 126.063,241.932 126.479,241.517 R227_I2C_Bridge_GPIO.2@126.479,240.244
GPIO_I2C1.SDA: R558_I2C_Bridge_GPIO.2 U3_I2C_Bridge_GPIO.3 | length 3
  L1 w0.2: R558_I2C_Bridge_GPIO.2@125.173,240.244 125.173,241.443 125.563,241.833 U3_I2C_Bridge_GPIO.3@125.563,243.104
GPIO_I2C2.SCL: R225_I2C_Bridge_GPIO.2 U3_I2C_Bridge_GPIO.6 | length 3.7
  L1 w0.2: U3_I2C_Bridge_GPIO.6@127.063,243.104 127.063,242.659 129.09,240.633 R225_I2C_Bridge_GPIO.2@129.09,240.244
GPIO_I2C2.SDA: R226_I2C_Bridge_GPIO.2 U3_I2C_Bridge_GPIO.5 | length 3.4
  L1 w0.2: U3_I2C_Bridge_GPIO.5@126.563,243.104 126.563,242.423 127.784,241.202 R226_I2C_Bridge_GPIO.2@127.784,240.244
GPIO_I2C3.SCL: R223_I2C_Bridge_GPIO.2 U3_I2C_Bridge_GPIO.8 | length 4.3
  L1 w0.2: U3_I2C_Bridge_GPIO.8@127.748,244.289 129.933,244.289 130.196,244.026 R223_I2C_Bridge_GPIO.2@131.904,244.026
GPIO_I2C3.SDA: R224_I2C_Bridge_GPIO.2 U3_I2C_Bridge_GPIO.7 | length 4.6
  L1 w0.2: U3_I2C_Bridge_GPIO.7@127.748,243.789 128.605,243.789 129.603,242.791 R224_I2C_Bridge_GPIO.2@131.904,242.791
GPIO_I2C4.SCL: R9_I2C_Bridge_GPIO.2 U3_I2C_Bridge_GPIO.11 U35_I2C_Expander_10.8 U35_I2C_Expander_11.8 U35_I2C_Expander_12.8 | length 4.4
  L1 w0.2: U3_I2C_Bridge_GPIO.11@127.748,245.789 129.315,245.789 130.022,246.497 R9_I2C_Bridge_GPIO.2@131.904,246.497
GPIO_I2C4.SDA: R10_I2C_Bridge_GPIO.2 U3_I2C_Bridge_GPIO.10 U35_I2C_Expander_10.9 U35_I2C_Expander_11.9 U35_I2C_Expander_12.9 | length 4.2
  L1 w0.2: U3_I2C_Bridge_GPIO.10@127.748,245.289 131.876,245.289 R10_I2C_Bridge_GPIO.2@131.904,245.261
GPIO_I2C5.SCL: R7_I2C_Bridge_GPIO.2 U3_I2C_Bridge_GPIO.13 | length 5.9
  L1 w0.2: U3_I2C_Bridge_GPIO.13@127.063,246.974 127.063,247.554 127.552,248.044 129.146,248.044 130.753,249.651 R7_I2C_Bridge_GPIO.2@130.753,250.419
GPIO_I2C5.SDA: R8_I2C_Bridge_GPIO.2 U3_I2C_Bridge_GPIO.12 | length 4.8
  L1 w0.2: U3_I2C_Bridge_GPIO.12@127.748,246.289 128.361,246.289 129.803,247.732 R8_I2C_Bridge_GPIO.2@131.904,247.732
GPIO_I2C6.SCL: R5_I2C_Bridge_GPIO.2 U3_I2C_Bridge_GPIO.15 | length 4.6
  L1 w0.2: U3_I2C_Bridge_GPIO.15@126.063,246.974 126.063,247.742 127.419,249.098 127.749,249.098 128.28,249.629 R5_I2C_Bridge_GPIO.2@128.28,250.419
GPIO_I2C6.SDA: R6_I2C_Bridge_GPIO.2 U3_I2C_Bridge_GPIO.14 | length 5.4
  L1 w0.2: U3_I2C_Bridge_GPIO.14@126.563,246.974 126.563,247.707 127.369,248.514 128.702,248.514 129.517,249.329 R6_I2C_Bridge_GPIO.2@129.517,250.419
GPIO_I2C7.SCL: R3_I2C_Bridge_GPIO.2 U3_I2C_Bridge_GPIO.17 | length 3.8
  L1 w0.2: U3_I2C_Bridge_GPIO.17@125.063,246.974 125.063,248.596 125.807,249.34 R3_I2C_Bridge_GPIO.2@125.807,250.419
GPIO_I2C7.SDA: R4_I2C_Bridge_GPIO.2 U3_I2C_Bridge_GPIO.16 | length 4.1
  L1 w0.2: U3_I2C_Bridge_GPIO.16@125.563,246.974 125.563,248.359 127.043,249.84 R4_I2C_Bridge_GPIO.2@127.043,250.419
GPIOa_00.GPIO2: R540.2 U35_I2C_Expander_00.19 | length 15.9
  L1 w0.2: v2(152.121,237.089) 152.121,236.501 152.672,235.95 R540.2@152.915,235.95
  L3 (Sign) w0.2: 144.043,248.044 152.121,239.966 v2(152.121,237.089)
GPIOa_00.GPIO7: U35_I2C_Expander_00.24
GPIOa_01.GPIO0: U35_I2C_Expander_01.17 | length 5.4
  L1 w0.12: v7(78.105,346.672) 78.109,346.668 78.109,345.568 U35_I2C_Expander_01.17@78.113,345.564
  L3 (Sign) w0.2: 74.06,345.993 76.969,345.993 77.648,346.672 v7(78.105,346.672)
GPIOa_01.GPIO1: U35_I2C_Expander_01.18 | length 4.9
  L1 w0.12: U35_I2C_Expander_01.18@77.463,345.564 77.467,345.567 77.467,347.215 v7(77.47,347.218)
  L3 (Sign) w0.2: 74.388,347.593 76.549,347.593 76.924,347.218 v7(77.47,347.218)
GPIOa_01.GPIO2: U35_I2C_Expander_01.19 | length 4.1
  L1 w0.12: U35_I2C_Expander_01.19@76.813,345.564 v7(76.813,346.672)
  L3 (Sign) w0.2: 73.936,346.293 76.128,346.293 76.507,346.672 v7(76.813,346.672)
GPIOa_01.GPIO3: U35_I2C_Expander_01.20 | length 3.4
  L1 w0.12: U35_I2C_Expander_01.20@76.163,345.564 v7(76.163,347.218)
  L3 (Sign) w0.2: 74.437,347.218 v7(76.163,347.218)
GPIOa_01.GPIO4: U35_I2C_Expander_01.21 | length 1.1
  L1 w0.12: U35_I2C_Expander_01.21@75.513,345.564 v7(75.513,346.668)
GPIOa_01.GPIO5: U35_I2C_Expander_01.22 U46.A3
GPIOa_01.GPIO6: U35_I2C_Expander_01.23
GPIOa_01.GPIO7: U35_I2C_Expander_01.24
GPIOa_02.GPIO0: J1_PCIE0.18 U35_I2C_Expander_02.17 | length 59.3
  L1 w0.12: U35_I2C_Expander_02.17@116.08,381.532 116.103,381.556 116.103,383.527 116.434,383.857 154.483,383.857 159.162,379.178 v4(159.162,368.785)
  L16 w0.12: J1_PCIE0.18@159.137,366.992 159.162,367.017 v4(159.162,368.785)
GPIOa_02.GPIO1: U35_I2C_Expander_02.18
GPIOa_02.GPIO2: U35_I2C_Expander_02.19
GPIOa_02.GPIO4: U35_I2C_Expander_02.21
GPIOa_02.GPIO5: U35_I2C_Expander_02.22
GPIOa_02.GPIO6: U35_I2C_Expander_02.23
GPIOa_10.GPIO1: U35_I2C_Expander_10.18
GPIOa_10.GPIO2: U35_I2C_Expander_10.19
GPIOa_10.GPIO3: U35_I2C_Expander_10.20
GPIOa_10.GPIO4: U35_I2C_Expander_10.21
GPIOa_10.GPIO5: U35_I2C_Expander_10.22
GPIOa_10.GPIO6: U35_I2C_Expander_10.23
GPIOa_10.GPIO7: U35_I2C_Expander_10.24
GPIOa_11.GPIO1: J1_PCIE1.18 U35_I2C_Expander_11.18 | length 52.4
  L1 w0.12: U35_I2C_Expander_11.18@198.939,249.285 198.939,250.653 v4(199.612,251.326)
  L16 w0.12: v4(199.612,251.326) 200.075,251.789 236.962,251.789 238.29,253.117 J1_PCIE1.18@238.29,263.794
GPIOa_11.GPIO4: U35_I2C_Expander_11.21
GPIOa_11.GPIO6: U35_I2C_Expander_11.23
GPIOa_11.GPIO7: R499.1 U35_I2C_Expander_11.24
GPIOa_12.GPIO0: R826.2 U35_I2C_Expander_12.17 U50.5 | length 104.4
  L1 w0.2: U50.5@100.076,253.671 100.647,253.671 101.381,252.938 v7(101.381,250.685) ; U35_I2C_Expander_12.17@140.566,182.44 v7(140.566,185.979)
  L3 (Sign) w0.2: v7(101.381,250.685) 102.726,249.339 114.432,249.339 118.431,245.341 118.431,195.321 127.703,186.048 132.849,186.048 134.734,184.163 139.108,184.163 139.111,184.165 139.169,184.165 140.566,185.562 v7(140.566,185.979)
GPIOa_12.GPIO1: R827.2 U35_I2C_Expander_12.18 U51.5 | length 106.8
  L1 w0.2: U51.5@93.544,252.363 94.613,252.363 95.148,251.828 v7(95.148,249.784) ; v7(139.891,183.502) 139.903,183.49 139.903,182.453 U35_I2C_Expander_12.18@139.916,182.44
  L3 (Sign) w0.2: v7(95.148,249.784) 95.893,249.039 114.308,249.039 118.131,245.216 118.131,195.196 127.626,185.701 132.258,185.701 134.926,183.032 139.421,183.032 v7(139.891,183.502)
GPIOa_12.GPIO2: R691.2 U35_I2C_Expander_12.19 U73.6 | length 1.4
  L1 w0.12: v7(139.266,183.79) 139.266,182.468 U35_I2C_Expander_12.19@139.28,182.454
  L1 w0.2: U35_I2C_Expander_12.19@139.266,182.44 U35_I2C_Expander_12.19@139.28,182.454 ; R691.2@152.142,347.358 R691.2@152.192,347.308
GPIOa_12.GPIO7: U35_I2C_Expander_12.24
GPIOb_00.GPIO0: U35_I2C_Expander_00.25
GPIOb_00.GPIO1: U35_I2C_Expander_00.26
GPIOb_00.GPIO5: U35_I2C_Expander_00.2
GPIOb_00.GPIO6: U35_I2C_Expander_00.3
GPIOb_00.GPIO7: U35_I2C_Expander_00.4
GPIOb_01.GPIO0: U35_I2C_Expander_01.25
GPIOb_01.GPIO1: U35_I2C_Expander_01.26
GPIOb_01.GPIO2: R235_SPI_bridge_Main.2 U35_I2C_Expander_01.27
GPIOb_01.GPIO3: R237_SPI_bridge_Main.2 U35_I2C_Expander_01.28
GPIOb_01.GPIO4: U35_I2C_Expander_01.1
GPIOb_01.GPIO5: U35_I2C_Expander_01.2
GPIOb_01.GPIO6: U35_I2C_Expander_01.3
GPIOb_01.GPIO7: U35_I2C_Expander_01.4
GPIOb_02.GPIO0: U35_I2C_Expander_02.25
GPIOb_02.GPIO1: U35_I2C_Expander_02.26
GPIOb_02.GPIO2: J1_PCIE3.18 U35_I2C_Expander_02.27 | length 41
  L1 w0.12: v4(105.702,377.342) 105.71,377.35 112.547,377.35 U35_I2C_Expander_02.27@112.555,377.357
  L16 w0.12: J1_PCIE3.18@76.785,366.992 76.785,368.513 85.614,377.342 v4(105.702,377.342)
GPIOb_02.GPIO3: R237_SPI_bridge_PCIe.2 U35_I2C_Expander_02.28 | length 59.6
  L1 w0.12: v7(57.328,368.163) R237_SPI_bridge_PCIe.2@57.328,368.963 ; v7(110.553,376.707) U35_I2C_Expander_02.28@112.555,376.707
  L3 (Sign) w0.12: v7@57.313,368.162 65.508,376.357 109.166,376.357 109.516,376.707 v7(110.553,376.707)
GPIOb_02.GPIO4: U35_I2C_Expander_02.1
GPIOb_02.GPIO5: R232_SPI_bridge_PCIe.1 U35_I2C_Expander_02.2 | length 29
  L1 w0.12: U35_I2C_Expander_02.2@114.13,375.782 114.13,373.741 116.992,370.878 134.175,370.878 135.844,369.21 R232_SPI_bridge_PCIe.1@139.232,369.21
GPIOb_02.GPIO6: U35_I2C_Expander_02.3
GPIOb_02.GPIO7: U35_I2C_Expander_02.4
GPIOb_10.GPIO0: U35_I2C_Expander_10.25
GPIOb_10.GPIO1: U35_I2C_Expander_10.26
GPIOb_10.GPIO3: U35_I2C_Expander_10.28
GPIOb_10.GPIO4: U35_I2C_Expander_10.1
GPIOb_10.GPIO5: U35_I2C_Expander_10.2
GPIOb_10.GPIO6: J1_PCIE2.18 U35_I2C_Expander_10.3 | length 39.4
  L1 w0.12: U35_I2C_Expander_10.3@207.78,366.065 207.78,364.693 210.599,361.874 235.074,361.874 v4(237.89,364.689)
  L16 w0.12: v4(237.89,364.689) 240.875,364.689 241.49,365.304 J1_PCIE2.18@241.49,366.992
GPIOb_11.GPIO1: J1_PCIE4.18 U35_I2C_Expander_11.26 | length 51
  L1 w0.12: v4(186.804,245.897) 186.907,245.897 187.044,245.76 U35_I2C_Expander_11.26@195.844,245.76
  L1 w0.2: U35_I2C_Expander_11.26@195.844,245.76 U35_I2C_Expander_11.26@196.064,245.76
  L16 w0.12: J1_PCIE4.18@155.937,263.794 155.937,258.045 159.448,254.533 173.726,254.533 182.362,245.897 v4(186.804,245.897)
GPIOb_11.GPIO4: U16.29 U35_I2C_Expander_11.1 | length 43.6
  L1 w0.2: U16.29@159.565,230.195 159.573,230.188 161.114,230.188 v7(161.137,230.165) ; v7(196.969,242.468) 196.979,242.478 196.979,243.525 U35_I2C_Expander_11.1@196.989,243.535
  L3 (Sign) w0.2: v7(161.137,230.165) 165.789,230.165 176.435,240.811 191.01,240.811 191.998,241.799 196.3,241.799 v7(196.969,242.468)
GPIOb_11.GPIO5: U16.28 U35_I2C_Expander_11.2 | length 44.4
  L1 w0.2: U16.28@159.565,229.695 v7(160.559,229.695) ; v7(197.639,242.468) U35_I2C_Expander_11.2@197.639,243.535
  L3 (Sign) w0.2: v7(160.559,229.695) 165.743,229.695 176.559,240.511 191.134,240.511 191.93,241.307 196.477,241.307 v7(197.639,242.468)
GPIOb_11.GPIO6: U16.20 U35_I2C_Expander_11.3 | length 46.7
  L1 w0.2: U16.20@159.565,225.695 159.573,225.688 160.62,225.688 v7(160.642,225.665) ; v7(198.258,242.468) 198.273,242.484 198.273,243.52 U35_I2C_Expander_11.3@198.289,243.535
  L3 (Sign) w0.2: v7(160.642,225.665) 162.137,225.665 176.683,240.211 191.258,240.211 191.926,240.879 196.668,240.879 v7(198.258,242.468)
GPIOb_11.GPIO7: U16.17 U35_I2C_Expander_11.4 | length 48
  L1 w0.2: U16.17@159.565,224.195 159.573,224.203 160.627,224.203 v7(160.642,224.218) ; v7(198.939,242.484) U35_I2C_Expander_11.4@198.939,243.535
  L3 (Sign) w0.2: v7(160.642,224.218) 161.115,224.218 176.808,239.911 191.383,239.911 191.949,240.478 196.932,240.478 v7(198.939,242.484)
GPIOb_12.GPIO0: U35_I2C_Expander_12.25
GPIOb_12.GPIO1: U35_I2C_Expander_12.26
GPIOb_12.GPIO2: U35_I2C_Expander_12.27
GPIOb_12.GPIO3: R838.2 R840.1 U35_I2C_Expander_12.28 | length 6.1
  L1 w0.12: R838.2@131.057,177.571 R840.1@132.145,177.571
  L1 w0.2: R840.1@132.195,177.571 132.145,177.571 132.189,177.615 U35_I2C_Expander_12.28@137.041,177.615
GPIOb_12.GPIO4: R836.2 R839.1 U35_I2C_Expander_12.1 | length 8
  L1 w0.12: R836.2@131.057,175.221 R839.1@132.195,175.221
  L1 w0.2: R839.1@132.195,175.221 137.299,175.221 137.966,175.888 U35_I2C_Expander_12.1@137.966,176.69
GPIOb_12.GPIO5: R835.2 R837.1 U35_I2C_Expander_12.2 | length 9.4
  L1 w0.12: R835.2@131.057,173.721 132.145,173.721 R837.1@132.195,173.771
  L1 w0.2: R837.1@132.195,173.771 136.701,173.771 138.616,175.686 U35_I2C_Expander_12.2@138.616,176.69
GPIOb_12.GPIO7: R825.2 U19.23 U35_I2C_Expander_12.4 | length 2.4
  L1 w0.2: R825.2@139.916,174.28 U35_I2C_Expander_12.4@139.916,176.69
Ground: C63.2 C64.2 C67.2 C70.2 C75.2 C76.2 C77.2 C78.1 C79.1 C80.1 C81.2 C82.2 C83.2 C88.2 C89.2 C90.2 C91.2 C92.2 C93.2 C96.2 C99.1 C100.1 C101.1 C102.1 C103.1 C104.1 C105.1 C106.1 C107.1 C108.1 C109.1 C110.1 C124.1 C125.1 C126.1 C127.1 C141.1 C142.1 C143.1 C144.1 C145.1 C146.1 C147.1 C148.1 C162.1 C163.1 C164.1 C165.1 C179.1 C180.1 C572.1 C574.1 C575.1 C576.1 C578.1 C579.1 C590.1 C591.1 C592.1 FB36.2 R437.1 R439.1 R545.1 U16.44 U16.65 U61.3 U61.8 U61.13 U61.18 U61.21 X9.2
  other v4: 170.728,211.598 171.628,211.598 172.528,211.598 170.728,212.498 171.628,212.498 172.528,212.498 170.728,213.398 171.628,213.398 172.528,213.398 152.785,224.345 153.975,224.345 155.165,224.345 156.355,224.345 157.545,224.345 151.565,225.565 152.785,225.565 153.975,225.565 155.165,225.565 156.355,225.565 157.545,225.565 158.765,225.565 151.565,226.755 152.785,226.755 153.975,226.755 155.165,226.755 156.355,226.755 157.545,226.755 158.765,226.755 151.565,227.945 152.785,227.945 153.975,227.945 155.165,227.945 156.355,227.945 157.545,227.945 158.765,227.945 151.565,229.135 152.785,229.135 153.975,229.135 155.165,229.135 156.355,229.135 157.545,229.135 158.765,229.135 151.565,230.325 152.785,230.325 153.975,230.325 155.165,230.325 156.355,230.325 157.545,230.325 158.765,230.325 152.785,231.545 153.975,231.545 155.165,231.545 156.355,231.545 157.545,231.545
Ground_PWR_PoE: C702.1 C703.1 C704.1 D27.2 R159.1 R160.1 R667.1 R670.2 U65.3 U65.8 U65.21 | length 4.9
  L1 w0.254: v1(37.668,199.124) R670.2@37.668,199.938 ; v1(38.76,201.663) U65.3@38.76,202.478 ; v1(40.17,199.307) C702.1@40.17,200.121 ; U65.8@40.6,204.318 v1(41.478,204.318) ; v1(42.978,201.451) R667.1@42.978,202.265 ; R160.1@42.978,203.203 v1(43.793,203.203)
  other v4: 38.21,203.768 39.31,203.768 38.21,204.868 39.31,204.868
HiSpeedModule_I2C0.SCL: R185.2 R189.2 R213.2 R221.2 R559_I2C_Bridge_PCIE.2 U3_I2C_Bridge_PCIE.2 U64_U_Pomiar_pradu_napiecia_PCIe1.5 U64_U_Pomiar_pradu_napiecia_PCIe4.5 | length 24.5
  L1 w0.2: R559_I2C_Bridge_PCIE.2@100.135,382.549 100.135,383.205 101.32,384.39 U3_I2C_Bridge_PCIE.2@101.32,384.678 ; U64_U_Pomiar_pradu_napiecia_PCIe4.5@141.229,248.004 141.229,247.171 141.565,246.835 142.346,246.835 142.529,246.653 142.529,243.218 142.155,242.844 R213.2@141.294,242.844 ; U64_U_Pomiar_pradu_napiecia_PCIe1.5@221.927,249.776 221.927,248.927 224.121,246.733 224.121,244.472 223.362,243.713 v7(222.662,243.713) R185.2@222.537,243.714
  L3 (Sign) w0.2: v7(138.14,242.844) v7(141.419,242.844) ; v7(219.353,243.713) v7(222.662,243.713)
HiSpeedModule_I2C0.SDA: R186.2 R190.2 R215.2 R222.2 R560_I2C_Bridge_PCIE.2 U3_I2C_Bridge_PCIE.1 U64_U_Pomiar_pradu_napiecia_PCIe1.4 U64_U_Pomiar_pradu_napiecia_PCIe4.4 | length 23.7
  L1 w0.2: R560_I2C_Bridge_PCIE.2@99.022,382.549 99.022,383.299 99.822,384.099 100.507,384.099 100.82,384.412 U3_I2C_Bridge_PCIE.1@100.82,384.678 ; U64_U_Pomiar_pradu_napiecia_PCIe4.4@140.729,248.004 140.729,246.653 140.847,246.535 142.029,246.535 142.226,246.339 142.226,244.055 141.999,243.828 R215.2@141.294,243.828 ; v7(219.353,244.602) R190.2@219.478,244.603 ; U64_U_Pomiar_pradu_napiecia_PCIe1.4@221.427,249.776 221.427,248.334 222.477,247.284 222.939,247.284 223.786,246.437 223.786,245.026 223.362,244.603 v7(222.662,244.602) R186.2@222.537,244.603
  L3 (Sign) w0.2: v7(138.14,243.828) v7(141.419,243.828) ; v7(219.353,244.602) v7(222.662,244.602)
HiSpeedModule_I2C1.SCL: J1_PCIE0.15 R227_I2C_Bridge_PCIE.2 U3_I2C_Bridge_PCIE.4 | length 2.1
  L1 w0.2: R227_I2C_Bridge_PCIE.2@102.32,382.549 U3_I2C_Bridge_PCIE.4@102.32,384.678
HiSpeedModule_I2C1.SDA: J1_PCIE0.13 R558_I2C_Bridge_PCIE.2 U3_I2C_Bridge_PCIE.3 | length 2.3
  L1 w0.2: R558_I2C_Bridge_PCIE.2@101.32,382.549 101.32,383.557 101.82,384.057 U3_I2C_Bridge_PCIE.3@101.82,384.678
HiSpeedModule_I2C2.SCL: J1_PCIE1.15 R225_I2C_Bridge_PCIE.2 U3_I2C_Bridge_PCIE.6 | length 2.6
  L1 w0.2: U3_I2C_Bridge_PCIE.6@103.32,384.678 103.32,384.375 104.356,383.339 R225_I2C_Bridge_PCIE.2@104.356,382.549
HiSpeedModule_I2C2.SDA: J1_PCIE1.13 R226_I2C_Bridge_PCIE.2 U3_I2C_Bridge_PCIE.5 | length 2.3
  L1 w0.2: U3_I2C_Bridge_PCIE.5@102.82,384.678 102.82,383.971 103.32,383.471 R226_I2C_Bridge_PCIE.2@103.32,382.549
HiSpeedModule_I2C3.SCL: J1_PCIE2.15 R223_I2C_Bridge_PCIE.2 U3_I2C_Bridge_PCIE.8 | length 2.6
  L1 w0.2: U3_I2C_Bridge_PCIE.8@104.005,385.863 104.763,385.863 105.147,385.48 R223_I2C_Bridge_PCIE.2@106.446,385.48
HiSpeedModule_I2C3.SDA: J1_PCIE2.13 R224_I2C_Bridge_PCIE.2 U3_I2C_Bridge_PCIE.7 | length 2.8
  L1 w0.2: U3_I2C_Bridge_PCIE.7@104.005,385.363 104.552,385.363 105.491,384.424 R224_I2C_Bridge_PCIE.2@106.446,384.424
HiSpeedModule_I2C4.SCL: J1_PCIE3.15 R9_I2C_Bridge_PCIE.2 U3_I2C_Bridge_PCIE.11 | length 9
  L1 w0.2: U3_I2C_Bridge_PCIE.11@104.005,387.363 104.89,387.363 105.117,387.59 R9_I2C_Bridge_PCIE.2@106.446,387.59
  L14 (Sign) w0.2: v9(81.185,361.683) 81.763,361.683 82.339,362.26 83.757,362.26 84.315,362.818
  L16 w0.2: J1_PCIE3.15@81.185,358.792 v9(81.185,361.683)
HiSpeedModule_I2C4.SDA: J1_PCIE3.13 R10_I2C_Bridge_PCIE.2 U3_I2C_Bridge_PCIE.10 | length 8.8
  L1 w0.2: U3_I2C_Bridge_PCIE.10@104.005,386.863 105.097,386.863 105.425,386.535 R10_I2C_Bridge_PCIE.2@106.446,386.535
  L14 (Sign) w0.2: v9(81.775,362.56) 83.629,362.56 83.998,362.928
  L16 w0.2: v9(81.775,362.56) 81.985,362.35 J1_PCIE3.13@81.985,358.792
HiSpeedModule_I2C5.SCL: J1_PCIE4.15 R7_I2C_Bridge_PCIE.2 U3_I2C_Bridge_PCIE.13 | length 3
  L1 w0.2: U3_I2C_Bridge_PCIE.13@103.32,388.548 103.32,388.702 103.797,389.179 104.267,389.179 105.028,389.94 R7_I2C_Bridge_PCIE.2@105.028,390.539
HiSpeedModule_I2C5.SDA: J1_PCIE4.13 R8_I2C_Bridge_PCIE.2 U3_I2C_Bridge_PCIE.12 | length 2.8
  L1 w0.2: U3_I2C_Bridge_PCIE.12@104.005,387.863 104.437,387.863 105.219,388.645 R8_I2C_Bridge_PCIE.2@106.446,388.645
HiSpeedModule_I2C6.SCL: R5_I2C_Bridge_PCIE.2 R176.2 R180.2 R194.2 R198.2 U3_I2C_Bridge_PCIE.15 U64_U_Pomiar_pradu_napiecia_PCIe0.5 U64_U_Pomiar_pradu_napiecia_PCIe2.5 | length 25.7
  L1 w0.2: U3_I2C_Bridge_PCIE.15@102.32,388.548 102.32,389.238 102.895,389.813 R5_I2C_Bridge_PCIE.2@102.895,390.539 ; R176.2@169.977,392.788 169.171,392.788 168.504,392.121 168.504,391.463 168.204,391.163 168.204,389.649 168.504,389.349 168.504,389.223 169.209,388.518 170.256,388.518 170.587,388.187 U64_U_Pomiar_pradu_napiecia_PCIe0.5@170.587,386.83 ; R194.2@254.474,391.25 254.049,391.25 253.199,390.4 253.199,387.315 253.974,386.54 254.424,386.54 254.795,386.169 U64_U_Pomiar_pradu_napiecia_PCIe2.5@254.795,385.108 ; R198.2@257.406,391.25 v7(257.531,391.25)
  L3 (Sign) w0.2: v7(169.852,392.788) v7(173.415,392.788) ; v7(254.349,391.25) v7(257.531,391.25)
HiSpeedModule_I2C6.SDA: R6_I2C_Bridge_PCIE.2 R177.2 R181.2 R195.2 R199.2 U3_I2C_Bridge_PCIE.14 U64_U_Pomiar_pradu_napiecia_PCIe0.4 U64_U_Pomiar_pradu_napiecia_PCIe2.4 | length 24.3
  L1 w0.2: U3_I2C_Bridge_PCIE.14@102.82,388.548 102.82,389.167 103.213,389.56 103.619,389.56 103.955,389.895 R6_I2C_Bridge_PCIE.2@103.955,390.539 ; R177.2@169.977,391.772 169.237,391.772 168.504,391.038 168.504,389.773 169.287,388.99 170.331,388.99 171.087,388.234 U64_U_Pomiar_pradu_napiecia_PCIe0.4@171.087,386.83 ; R181.2@173.29,391.772 v7(173.415,391.772) ; R195.2@254.474,390.192 253.865,390.192 253.499,389.826 253.499,387.547 254.005,387.04 254.795,387.04 255.295,386.54 U64_U_Pomiar_pradu_napiecia_PCIe2.4@255.295,385.108
  L3 (Sign) w0.2: v7(169.852,391.772) v7(173.415,391.772) ; v7(254.349,390.192) v7(257.531,390.192)
HiSpeedModule_I2C7.SCL: R3_I2C_Bridge_PCIE.2 R203.2 R207.2 U3_I2C_Bridge_PCIE.17 U64_U_Pomiar_pradu_napiecia_PCIe3.5 | length 14.2
  L1 w0.2: v7(87.913,390.907) 86.752,390.907 86.385,390.539 86.385,387.94 88.633,385.692 U64_U_Pomiar_pradu_napiecia_PCIe3.5@88.633,384.471 ; R207.2@90.972,390.907 v7(91.097,390.907) ; R3_I2C_Bridge_PCIE.2@100.82,390.539 100.82,389.654 101.32,389.154 U3_I2C_Bridge_PCIE.17@101.32,388.548
  L3 (Sign) w0.2: v7(87.913,390.907) v7(91.097,390.907)
HiSpeedModule_I2C7.SDA: R4_I2C_Bridge_PCIE.2 R204.2 R208.2 U3_I2C_Bridge_PCIE.16 U64_U_Pomiar_pradu_napiecia_PCIe3.4 | length 12.7
  L1 w0.2: v7(87.913,390.018) 87.044,390.018 86.922,389.895 86.922,387.84 87.472,387.29 87.842,387.29 89.133,385.999 U64_U_Pomiar_pradu_napiecia_PCIe3.4@89.133,384.471 ; R208.2@90.972,390.018 v7(91.022,390.018) ; U3_I2C_Bridge_PCIE.16@101.82,388.548 R4_I2C_Bridge_PCIE.2@101.82,390.539
  L3 (Sign) w0.2: v7(87.913,390.018) v7(91.022,390.018)
HiSpeedModule_SPI0.C\S\: J1_PCIE0.51 R231_SPI_bridge_PCIe.1 U24_SPI_bridge_PCIe.11 | length 24.4
  L1 w0.12: U24_SPI_bridge_PCIe.11@140.532,372.107 R231_SPI_bridge_PCIe.1@140.532,370.11 140.132,370.11 139.933,369.91 139.933,358.168 142.336,355.764 v4(145.898,355.764)
  L16 w0.12: v4(145.898,355.764) 145.898,358.752 J1_PCIE0.51@145.937,358.792
HiSpeedModule_SPI0.CLK: J1_PCIE0.45 U24_SPI_bridge_PCIe.14 | length 16.9
  L1 w0.12: U24_SPI_bridge_PCIe.14@142.482,372.107 142.503,372.087 v4(142.503,370.11)
  L16 w0.12: v4(142.503,370.11) 142.503,363.418 144.682,361.239 146.617,361.239 147.997,359.858 147.997,359.832 148.337,359.492 J1_PCIE0.45@148.337,358.792
HiSpeedModule_SPI0.MISO: J1_PCIE0.49 U24_SPI_bridge_PCIe.13 | length 19.9
  L1 w0.12: U24_SPI_bridge_PCIe.13@141.832,372.107 141.832,360.415 145.341,356.906 v4(146.648,356.906)
  L16 w0.12: v4(146.648,356.906) 146.648,358.702 J1_PCIE0.49@146.737,358.792
HiSpeedModule_SPI0.MOSI: J1_PCIE0.47 U24_SPI_bridge_PCIe.12 | length 24.1
  L1 w0.12: U24_SPI_bridge_PCIe.12@141.182,372.107 141.182,357.23 142.189,356.222 147.251,356.222 147.423,356.394 v4(147.423,356.906)
  L16 w0.12: v4(147.423,356.906) 147.423,358.677 J1_PCIE0.47@147.537,358.792
HiSpeedModule_SPI1.C\S\: J1_PCIE1.51 R233_SPI_bridge_PCIe.1 U25_SPI_bridge_PCIe.11 | length 2
  L1 w0.12: U25_SPI_bridge_PCIe.11@255.191,259.567 R233_SPI_bridge_PCIe.1@255.191,261.614
HiSpeedModule_SPI1.CLK: J1_PCIE1.45 U25_SPI_bridge_PCIe.14
HiSpeedModule_SPI1.MISO: J1_PCIE1.49 U25_SPI_bridge_PCIe.13
HiSpeedModule_SPI1.MOSI: J1_PCIE1.47 U25_SPI_bridge_PCIe.12
HiSpeedModule_SPI2.C\S\: J1_PCIE2.51 R236_SPI_bridge_PCIe.1 U26_SPI_bridge_PCIe.11 | length 15.9
  L1 w0.12: v4(223.44,365.89) 223.44,366.648 222.99,367.098 222.99,369.94 223.24,370.19 223.49,370.19 R236_SPI_bridge_PCIe.1@223.64,370.34 U26_SPI_bridge_PCIe.11@223.64,372.107
  L16 w0.12: v4(223.44,365.89) 223.44,364.342 228.29,359.492 J1_PCIE2.51@228.29,358.792
HiSpeedModule_SPI2.CLK: J1_PCIE2.45 U26_SPI_bridge_PCIe.14 | length 15.4
  L1 w0.12: U26_SPI_bridge_PCIe.14@225.59,372.107 225.59,368.937 v4(230.573,363.954)
  L16 w0.12: v4(230.573,363.954) 230.573,358.909 J1_PCIE2.45@230.69,358.792
HiSpeedModule_SPI2.MISO: J1_PCIE2.49 U26_SPI_bridge_PCIe.13 | length 15
  L1 w0.12: U26_SPI_bridge_PCIe.13@224.94,372.107 224.94,367.304 v4(228.29,363.954)
  L16 w0.12: v4(228.29,363.954) 229.09,363.154 J1_PCIE2.49@229.09,358.792
HiSpeedModule_SPI2.MOSI: J1_PCIE2.47 U26_SPI_bridge_PCIe.12 | length 17.3
  L1 w0.12: U26_SPI_bridge_PCIe.12@224.29,372.107 224.29,367.524 224.84,366.974 v4(224.84,365.89)
  L16 w0.12: v4(224.84,365.89) 226.037,364.693 228.816,364.693 229.89,363.619 J1_PCIE2.47@229.89,358.792
HiSpeedModule_SPI3.C\S\: J1_PCIE3.51 R238_SPI_bridge_PCIe.1 U27_SPI_bridge_PCIe.11 | length 20.4
  L1 w0.12: U27_SPI_bridge_PCIe.11@58.613,372.107 U27_SPI_bridge_PCIe.11@58.613,371.89 R238_SPI_bridge_PCIe.1@58.613,369.863 59.041,369.863 60.046,368.859 60.046,361.546 63.519,358.073 v4(63.519,356.425)
  L16 w0.12: v4(63.519,356.425) 63.519,358.726 J1_PCIE3.51@63.585,358.792
HiSpeedModule_SPI3.CLK: J1_PCIE3.45 U27_SPI_bridge_PCIe.14 | length 19.7
  L1 w0.12: U27_SPI_bridge_PCIe.14@60.563,372.107 U27_SPI_bridge_PCIe.14@60.563,371.89 60.563,369.274 60.706,369.132 60.706,361.819 64.179,358.346 64.179,358.172 65.494,356.857 v4(65.977,356.857)
  L16 w0.12: v4(65.977,356.857) 65.977,358.784 J1_PCIE3.45@65.985,358.792
HiSpeedModule_SPI3.MISO: J1_PCIE3.49 U27_SPI_bridge_PCIe.13 | length 18.9
  L1 w0.12: U27_SPI_bridge_PCIe.13@59.913,372.107 59.913,369.613 60.486,369.041 60.486,361.728 63.959,358.255 63.959,357.325 v4(64.376,356.908)
  L16 w0.12: v4(64.376,356.908) 64.376,358.784 J1_PCIE3.49@64.385,358.792
HiSpeedModule_SPI3.MOSI: J1_PCIE3.47 U27_SPI_bridge_PCIe.12 | length 21.1
  L1 w0.12: U27_SPI_bridge_PCIe.12@59.263,372.107 59.263,369.952 60.266,368.95 60.266,361.637 63.739,358.164 63.739,356.966 64.33,356.375 v4(65.164,356.375)
  L16 w0.12: v4(65.164,356.375) 65.164,358.771 J1_PCIE3.47@65.185,358.792
HiSpeedModule_SPI4.C\S\: J1_PCIE4.51 R240_SPI_bridge_PCIe.1 U28_SPI_bridge_PCIe.11 | length 2.3
  L1 w0.12: R240_SPI_bridge_PCIe.1@173.746,258.399 173.746,256.13 U28_SPI_bridge_PCIe.11@173.798,256.078
HiSpeedModule_SPI4.CLK: J1_PCIE4.45 U28_SPI_bridge_PCIe.14 | length 18.2
  L1 w0.12: v4(166.581,267.794) 166.581,262.942 171.848,257.675 U28_SPI_bridge_PCIe.14@171.848,256.078
  L16 w0.12: v4(166.581,267.794) 166.581,271.837 J1_PCIE4.45@166.737,271.994
HiSpeedModule_SPI4.MISO: J1_PCIE4.49 U28_SPI_bridge_PCIe.13 | length 17.7
  L1 w0.12: U28_SPI_bridge_PCIe.13@172.498,256.078 172.587,256.168 v4(172.587,257.645)
  L16 w0.12: J1_PCIE4.49@168.337,271.994 168.337,267.998 172.587,263.748 v4(172.587,257.645)
HiSpeedModule_SPI4.MOSI: J1_PCIE4.47 U28_SPI_bridge_PCIe.12 | length 18.7
  L1 w0.12: v4(166.991,268.808) 167.005,268.794 167.005,264.465 173.148,258.322 U28_SPI_bridge_PCIe.12@173.148,256.078
  L16 w0.12: v4(166.991,268.808) 166.967,268.832 166.967,270.004 167.537,270.574 J1_PCIE4.47@167.537,271.994
HW_Conf_05028: R127.1 R139.2 U16.64
I2C0_PS.SCL: J12.1 R85.1 R774.1 U36_U_Translator_I2C3.3 | length 9.6
  L1 w0.2: J12.1@56.439,334.2 61.753,334.2 R85.1@61.805,334.253 ; R85.1@61.811,334.259 R85.1@61.805,334.253 ; U36_U_Translator_I2C3.3@64.727,332.87 63.273,332.87 63.138,332.735 62.273,332.735 62.055,332.952 62.055,333.035 61.855,333.235 R774.1@61.805,333.235 R85.1@61.805,334.253
I2C0_PS.SDA: J12.2 R86.1 R775.1 U36_U_Translator_I2C3.4 | length 10.1
  L1 w0.2: J12.2@56.439,331.661 58.814,331.661 59.627,330.848 R86.1@61.717,330.848 61.729,330.86 R775.1@61.729,331.864 61.729,332.232 61.932,332.435 63.263,332.435 63.347,332.52 U36_U_Translator_I2C3.4@64.727,332.52
I2C0_Rail.SCL: U3_I2C_Bridge_SFP.19 U36_U_Translator_I2C3.6 U36_U_Translator_I2C4.6 | length 46
  L1 w0.2: U36_U_Translator_I2C3.6@65.397,332.87 65.775,332.87 65.981,332.664 66.345,332.664 v1(66.345,332.676) ; v1(78.842,308.331) 78.867,308.356 79.933,308.356 80.069,308.221 81.009,308.221 83.248,305.981 83.248,305.765 84.418,304.596 U3_I2C_Bridge_SFP.19@85.6,304.596
  L5 (Sign) w0.2: v1(66.345,332.676) 64.922,331.254 64.922,322.733 66.892,320.764 74.079,320.764 79.311,315.531 79.311,308.8 v1(78.842,308.331)
  L16 w0.2: v1(66.345,332.676) 66.769,332.676 66.952,332.86 U36_U_Translator_I2C4.6@67.43,332.86
I2C0_Rail.SDA: U3_I2C_Bridge_SFP.20 U36_U_Translator_I2C3.5 U36_U_Translator_I2C4.5 | length 45.6
  L1 w0.2: U36_U_Translator_I2C3.5@65.397,332.52 65.676,332.52 66.18,332.016 v1(66.561,332.016) ; v1(79.266,307.906) 79.535,307.906 79.72,307.721 81.009,307.721 82.748,305.981 82.748,305.558 84.211,304.096 U3_I2C_Bridge_SFP.20@85.6,304.096
  L5 (Sign) w0.2: v1(66.561,332.016) 65.227,330.683 65.227,322.859 67.018,321.069 74.205,321.069 79.616,315.658 79.616,308.257 v1(79.266,307.906)
  L16 w0.2: v1(66.561,332.016) 67.055,332.51 U36_U_Translator_I2C4.5@67.43,332.51
I2C1_PS.SCL: J13.1 R83.1 R772.1 U36_U_Translator_I2C2.3 | length 11.1
  L1 w0.2: J13.1@56.446,326.428 56.459,326.416 60.302,326.416 61.401,327.515 R83.1@62.959,327.515 62.916,327.472 R772.1@62.916,326.428 62.916,326.022 63.751,325.186 U36_U_Translator_I2C2.3@65.197,325.186
I2C1_PS.SDA: J13.2 R84.1 R773.1 U36_U_Translator_I2C2.4 | length 11.2
  L1 w0.2: J13.2@56.446,323.888 61.177,323.888 62.34,322.724 R84.1@63.075,322.724 63.081,322.73 R773.1@63.081,323.863 63.066,323.878 63.066,324.636 63.266,324.836 U36_U_Translator_I2C2.4@65.197,324.836
I2C1_Rail.SCL: R599.1 U3_I2C_Bridge_GPIO.19 U35_I2C_Expander_Main_Rst.8 U36_U_Translator_I2C1.6 U36_U_Translator_I2C2.6 | length 118.1
  L1 w0.2: U36_U_Translator_I2C2.6@65.867,325.186 66.165,325.186 66.332,325.019 v1(66.674,325.019) ; v2(121.653,249.123) 121.78,248.996 122.097,248.996 ; R599.1@122.097,250.419 122.097,248.996 ; U3_I2C_Bridge_GPIO.19@123.878,246.289 123.382,246.289 122.097,247.575 122.097,248.996
  L5 (Sign) w0.2: v1(66.674,325.019) 66.227,324.572 66.227,323.575 67.362,322.44 76.656,322.44 81.207,317.889 81.207,305.103 91.63,294.679 91.63,288.332 v11(92.032,287.93)
  L3 (Sign) w0.2: v11(92.032,287.93) 103.065,276.897 103.065,261.526 104.008,260.583 105.037,260.583 v1(105.537,260.083) ; v1(109.348,259.678) 109.348,259.219 111.371,257.196 111.785,257.196 114.262,254.718 114.262,252.629 115.137,251.755 118.61,251.755 118.698,251.667 120.035,250.33 120.035,250.025 120.568,249.492 121.285,249.492 v2(121.653,249.123)
  L16 w0.2: v1(66.674,325.019) 66.904,325.019 67.071,325.186 U36_U_Translator_I2C1.6@67.43,325.186 ; v1(105.537,260.083) 105.943,259.678 v1(109.348,259.678) 109.348,259.69 109.676,260.018 U35_I2C_Expander_Main_Rst.8@110.123,260.018
I2C1_Rail.SDA: R428.1 U3_I2C_Bridge_GPIO.20 U35_I2C_Expander_Main_Rst.9 U36_U_Translator_I2C1.5 U36_U_Translator_I2C2.5 | length 118.9
  L1 w0.2: U36_U_Translator_I2C2.5@65.867,324.836 65.867,324.332 66.057,324.142 v1(66.677,324.142) ; v2(120.169,249.022) 120.86,249.022 ; R428.1@120.86,250.419 120.86,249.022 ; U3_I2C_Bridge_GPIO.20@123.878,245.789 122.93,245.789 120.86,247.859 120.86,249.022
  L5 (Sign) w0.2: v1(66.677,324.142) 66.677,323.549 67.487,322.74 76.82,322.74 81.507,318.053 81.507,305.227 91.93,294.804 91.93,288.88 v11(92.457,288.354)
  L3 (Sign) w0.2: v11(92.457,288.354) 103.365,277.446 103.365,261.651 104.132,260.883 v1(105.905,260.883) ; v1(108.598,260.363) 108.598,259.499 111.201,256.896 111.66,256.896 113.962,254.594 113.962,252.505 115.013,251.455 118.486,251.455 119.306,250.635 119.735,250.205 119.735,249.456 v2(120.169,249.022)
  L16 w0.2: v1(66.677,324.142) 67.234,324.142 67.43,324.338 U36_U_Translator_I2C1.5@67.43,324.836 ; v1(105.905,260.883) 106.426,260.363 v1(108.598,260.363) 108.903,260.668 U35_I2C_Expander_Main_Rst.9@110.123,260.668
I2C_05028_SCL: R130.1 R132.2 U16.36
I2C_05028_SDA: R131.1 R134.2 U16.35
I2C_LS.SCL: R363.2 U1.AG1 U36_U_Translator_I2C1.3 U36_U_Translator_I2C4.3 | length 237.1
  L1 w0.116: U1.AG1@188.397,288.539 v5(188.884,288.052)
  L14 (Sign) w0.2: v9(69.228,324.917) 69.417,325.106 v9(69.417,332.614) 69.417,333.056 69.969,333.608 78.808,333.608 87.889,342.689 110.788,342.689 113.125,345.026 187.349,345.026 188.198,345.875 207.299,345.875 210.934,342.24 210.934,310.284 210.502,309.852 210.502,289.738 207.831,287.066 189.311,287.066 188.884,287.493 v5(188.884,288.052)
  L16 w0.2: U36_U_Translator_I2C1.3@68.1,325.186 68.744,325.186 69.013,324.917 v9(69.228,324.917) 69.431,324.714 R363.2@70.18,324.714 ; U36_U_Translator_I2C4.3@68.1,332.86 69.171,332.86 v9(69.417,332.614)
I2C_LS.SDA: R364.2 U1.AF3 U36_U_Translator_I2C1.4 U36_U_Translator_I2C4.4 | length 243.9
  L1 w0.116: v5(186.909,290.052) U1.AF3@187.397,290.539
  L14 (Sign) w0.2: v9(68.542,324.041) 68.542,331.697 68.785,331.94 v9(68.785,332.021) 68.785,333.348 69.345,333.908 78.684,333.908 87.765,342.989 110.664,342.989 113.001,345.326 187.224,345.326 188.074,346.175 207.423,346.175 211.234,342.364 211.234,310.16 210.802,309.728 210.802,289.614 207.955,286.766 187.757,286.766 186.909,287.613 v5(186.909,290.052)
  L16 w0.2: U36_U_Translator_I2C1.4@68.1,324.836 68.1,324.483 v9(68.542,324.041) 68.897,323.685 R364.2@70.18,323.685 ; U36_U_Translator_I2C4.4@68.1,332.51 68.295,332.51 v9(68.785,332.021)
I2C_SCL_SFP0: J32.5 R225_I2C_Bridge_SFP.2 U3_I2C_Bridge_SFP.6 | length 49.1
  L1 w0.2: U3_I2C_Bridge_SFP.6@88.785,301.411 88.785,300.978 v2(89.51,300.253) 89.707,300.056 R225_I2C_Bridge_SFP.2@89.707,299.448
  L3 (Sign) w0.2: v1(56.947,283.604) 56.629,283.286 56.629,281.401 57.458,280.573 61.454,280.573 69.235,288.353 79.466,288.353 89.042,297.93 89.042,299.786 v2(89.51,300.253)
  L16 w0.2: v1(56.947,283.604) 58.861,283.604 J32.5@58.904,283.647
I2C_SCL_SFP1: J33.5 R559_I2C_Bridge_SFP.2 U3_I2C_Bridge_SFP.2 | length 41.1
  L1 w0.2: v1(85.458,300.215) 86.123,300.215 ; R559_I2C_Bridge_SFP.2@85.846,299.448 85.846,299.938 86.123,300.215 ; U3_I2C_Bridge_SFP.2@86.785,301.411 86.785,300.877 86.123,300.215
  L14 (Sign) w0.2: v1(57.023,312.115) 56.578,311.671 56.578,310.045 60.414,306.21 63.923,306.21 64.584,306.87 67.945,306.87 69.469,305.346 79.274,305.346 83.287,301.333 83.287,300.52 83.591,300.215 v1(85.458,300.215)
  L16 w0.2: v1(57.023,312.115) 57.054,312.147 J33.5@58.904,312.147
I2C_SCL_SFP2: J34.5 R223_I2C_Bridge_SFP.2 U3_I2C_Bridge_SFP.8 | length 62.3
  L1 w0.2: U3_I2C_Bridge_SFP.8@89.47,302.596 89.488,302.577 90.564,302.577 ; v2(90.564,302.882) 90.564,302.577 ; R223_I2C_Bridge_SFP.2@91.738,302.638 91.677,302.577 90.564,302.577
  L3 (Sign) w0.2: v1(57.036,269.405) 56.871,269.405 56.363,268.897 56.363,268.352 56.938,267.776 59.864,267.776 62.751,270.662 65.243,270.662 68.773,274.193 73.711,274.193 91.2,291.682 91.2,302.246 v2(90.564,302.882)
  L16 w0.2: v1(57.036,269.405) 57.044,269.397 J34.5@58.904,269.397
I2C_SCL_SFP3: J35.5 R227_I2C_Bridge_SFP.2 U3_I2C_Bridge_SFP.4 | length 37.4
  L1 w0.2: v2(87.592,300.279) 87.747,300.279 87.785,300.241 ; R227_I2C_Bridge_SFP.2@87.777,299.448 87.785,299.456 87.785,300.241 ; U3_I2C_Bridge_SFP.4@87.785,301.411 87.785,300.241
  L3 (Sign) w0.2: v1(57.359,297.897) 56.947,297.485 56.947,296.989 57.658,296.278 60.249,296.278 63.21,299.239 86.553,299.239 v2(87.592,300.279)
  L16 w0.2: v1(57.359,297.897) J35.5@58.904,297.897
I2C_SDA_SFP0: J32.4 R226_I2C_Bridge_SFP.2 U3_I2C_Bridge_SFP.5 | length 46.6
  L1 w0.2: U3_I2C_Bridge_SFP.5@88.285,301.411 88.285,300.697 v2(88.742,300.241) R226_I2C_Bridge_SFP.2@88.742,299.448
  L3 (Sign) w0.2: v1(57.455,282.804) 57.366,282.892 57.033,282.56 57.033,281.422 57.582,280.873 61.33,280.873 69.11,288.653 79.342,288.653 88.742,298.054 v2(88.742,300.241)
  L16 w0.2: v1(57.455,282.804) 58.861,282.804 J32.4@58.904,282.847
I2C_SDA_SFP1: J33.4 R560_I2C_Bridge_SFP.2 U3_I2C_Bridge_SFP.1 | length 38.2
  L1 w0.2: v1(83.972,301.066) 84.277,301.066 84.88,300.463 ; R560_I2C_Bridge_SFP.2@84.88,299.448 84.88,300.463 ; U3_I2C_Bridge_SFP.1@86.285,301.411 85.828,301.411 84.88,300.463
  L14 (Sign) w0.2: v9(57.182,311.347) 57.182,309.866 60.538,306.51 63.799,306.51 64.459,307.17 68.069,307.17 69.594,305.646 79.398,305.646 83.972,301.071 v1(83.972,301.066)
  L16 w0.2: v9(57.182,311.347) J33.4@58.904,311.347
I2C_SDA_SFP2: J34.4 R224_I2C_Bridge_SFP.2 U3_I2C_Bridge_SFP.7 | length 57.8
  L1 w0.2: U3_I2C_Bridge_SFP.7@89.47,302.096 90.086,302.096 v2(90.517,301.665) R224_I2C_Bridge_SFP.2@91.738,301.665
  L3 (Sign) w0.2: v1(56.998,268.592) 60.068,268.592 62.571,271.096 65.063,271.096 68.594,274.626 73.711,274.626 90.767,291.682 90.767,301.415 v2(90.517,301.665)
  L16 w0.2: v1(56.998,268.592) 57.002,268.597 J34.4@58.904,268.597
I2C_SDA_SFP3: J35.4 R558_I2C_Bridge_SFP.2 U3_I2C_Bridge_SFP.3 | length 34.8
  L1 w0.2: R558_I2C_Bridge_SFP.2@86.811,299.448 v2(86.811,300.232) 87.285,300.706 U3_I2C_Bridge_SFP.3@87.285,301.411
  L3 (Sign) w0.2: v1(57.493,297.116) 58.001,296.608 60.155,296.608 63.086,299.539 86.428,299.539 86.782,299.894 86.782,300.203 v2(86.811,300.232)
  L16 w0.2: v1(57.493,297.116) 58.851,297.116 58.888,297.08 J35.4@58.904,297.097
ILIM1: C345.2 R610.1 U34.26 | length 3.2
  L1 w0.254: U34.26@66.321,237.64 C345.2@66.32,239.69 66.38,239.63 67.318,239.63 R610.1@67.378,239.57
ILIM1_1: C389.2 R619.1 U37.26 | length 4.2
  L1 w0.2: C389.2@68.211,183.433 68.491,183.433 68.745,183.687 68.745,184.029 69.125,184.409 R619.1@69.291,184.409
  L1 w0.254: U37.26@66.675,181.817 66.675,182.331 67.04,182.696 67.474,182.696 C389.2@68.211,183.433
ILIM1_2: C430.2 R625.2 U38.26 | length 3
  L1 w0.254: U38.26@64.953,208.714 64.953,209.219 65.973,210.239 66.991,210.239 R625.2@67.001,210.229
ILIM2: C349.2 R611.1 U34.15 | length 3.5
  L1 w0.254: C349.2@66.055,231.087 66.075,231.067 R611.1@67.093,231.067 ; U34.15@66.322,233.139 66.322,232.29 66.315,232.283 66.94,231.658 66.94,231.22 R611.1@67.093,231.067 ; R611.1@67.113,231.047 R611.1@67.093,231.067
ILIM2_1: C393.2 R620.1 U37.15 | length 3.5
  L1 w0.2: C393.2@68.185,175.817 R620.1@69.151,175.817
  L1 w0.254: U37.15@66.675,177.317 66.675,177.093 66.946,176.822 67.623,176.822 68.185,176.26 C393.2@68.185,175.817
ILIM2_2: C434.2 R302.2 U38.15 | length 2.6
  L1 w0.254: U38.15@64.953,204.214 64.955,204.212 64.955,203.839 65.578,203.216 C434.2@65.578,202.764 66.405,202.764 66.453,202.812 R302.2@66.453,202.813
IMU_INT1: R822.2 U58.4
IMU_INT2: R851.2 U58.9
INTA_EXP_MAIN: R972.2 U35_I2C_Expander_Main_Rst.16
INTB_EXP_MAIN: R973.2 U35_I2C_Expander_Main_Rst.15
Interrupt0: R515.2 R530.1 U1.AC12 | length 64.2
  L1 w0.116: v2(183.909,299.052) U1.AC12@184.397,299.539
  L1 w0.12: R515.2@242.686,299.747 v2(242.686,300.816) R530.1@242.686,301.885
  L3 (Sign) w0.12: v2(183.909,299.052) 184.231,299.052 184.566,299.387 185.092,299.387 185.665,298.814 190.198,298.814 190.771,299.387 191.048,299.387 191.063,299.372 219.918,299.372 221.576,297.714 239.584,297.714 v2(242.686,300.816)
Interrupt1: R522.2 R547.1 U1.AD12 | length 66.1
  L1 w0.116: v2(184.909,299.052) U1.AD12@185.397,299.539
  L1 w0.12: R522.2@245.413,299.747 v2(245.413,300.816) R547.1@245.413,301.885
  L3 (Sign) w0.12: v2(184.909,299.052) 184.962,299.052 185.187,298.827 185.304,298.827 185.544,298.587 191.193,298.587 191.526,298.92 219.748,298.92 221.739,296.929 241.526,296.929 v2(245.413,300.816)
Interrupt2: R531.2 R550.1 U1.AA12 | length 63.5
  L1 w0.116: v2(181.909,299.052) U1.AA12@182.397,299.539
  L1 w0.12: R531.2@239.96,299.747 v2(239.96,300.816) R550.1@239.96,301.885
  L3 (Sign) w0.12: v2(181.909,299.052) 183.125,299.052 183.9,299.827 185.275,299.827 185.278,299.823 185.291,299.823 185.86,299.255 190.016,299.255 190.588,299.827 191.23,299.827 191.246,299.812 220.1,299.812 221.759,298.154 237.298,298.154 v2(239.96,300.816)
Interrupt3: R548.2 R553.1 U1.AA11 | length 65.2
  L1 w0.116: v2(181.909,298.052) U1.AA11@182.397,298.539
  L1 w0.12: R548.2@241.323,299.747 v2(241.323,300.816) R553.1@241.323,301.885
  L3 (Sign) w0.12: v2(181.909,298.052) 182.436,298.052 183.991,299.607 185.183,299.607 185.187,299.603 185.2,299.603 185.769,299.034 190.107,299.034 190.68,299.607 191.139,299.607 191.155,299.592 220.009,299.592 221.667,297.934 238.441,297.934 v2(241.323,300.816)
Interrupt4: R551.2 R556.1 U1.AB11 | length 69.7
  L1 w0.116: v2(182.909,298.052) U1.AB11@183.397,298.539
  L1 w0.12: R551.2@246.776,299.747 v2(246.776,300.816) R556.1@246.776,301.885
  L3 (Sign) w0.12: v2(182.909,298.052) 183.464,298.607 185.213,298.607 185.453,298.367 191.284,298.367 191.609,298.691 219.665,298.691 221.648,296.709 242.669,296.709 v2(246.776,300.816)
Interrupt5: R554.2 R618.1 U1.AC11 | length 70
  L1 w0.116: v2(183.909,298.052) U1.AC11@184.397,298.539
  L1 w0.12: R554.2@248.14,299.747 v2(248.14,300.816) R618.1@248.14,301.885
  L3 (Sign) w0.12: v2(183.909,298.052) 184.244,298.387 185.122,298.387 185.362,298.147 191.376,298.147 191.691,298.463 219.583,298.463 221.557,296.489 243.813,296.489 v2(248.14,300.816)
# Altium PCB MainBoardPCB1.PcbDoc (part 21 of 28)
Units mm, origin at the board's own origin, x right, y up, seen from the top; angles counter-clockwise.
Board outline 258.95 x 308.86 mm, 16 copper layers (L1, L2 (GND), L3 (Sign), L4 (GND), L5 (Sign), L6 (PWR/GND), L7(PWR/GND), L8 (Plane_GND), L9 (PWR/GND), L10 (PWR/GND), L11 (PWR/GND), L12 (Sign), L13 (GND), L14 (Sign), L15 (GND), L16), stack 2.502 mm thick; 2397 components, 1744 nets, 8397 pads, 4112 vias.
Unrouted connection lines stored in the file: 3547.

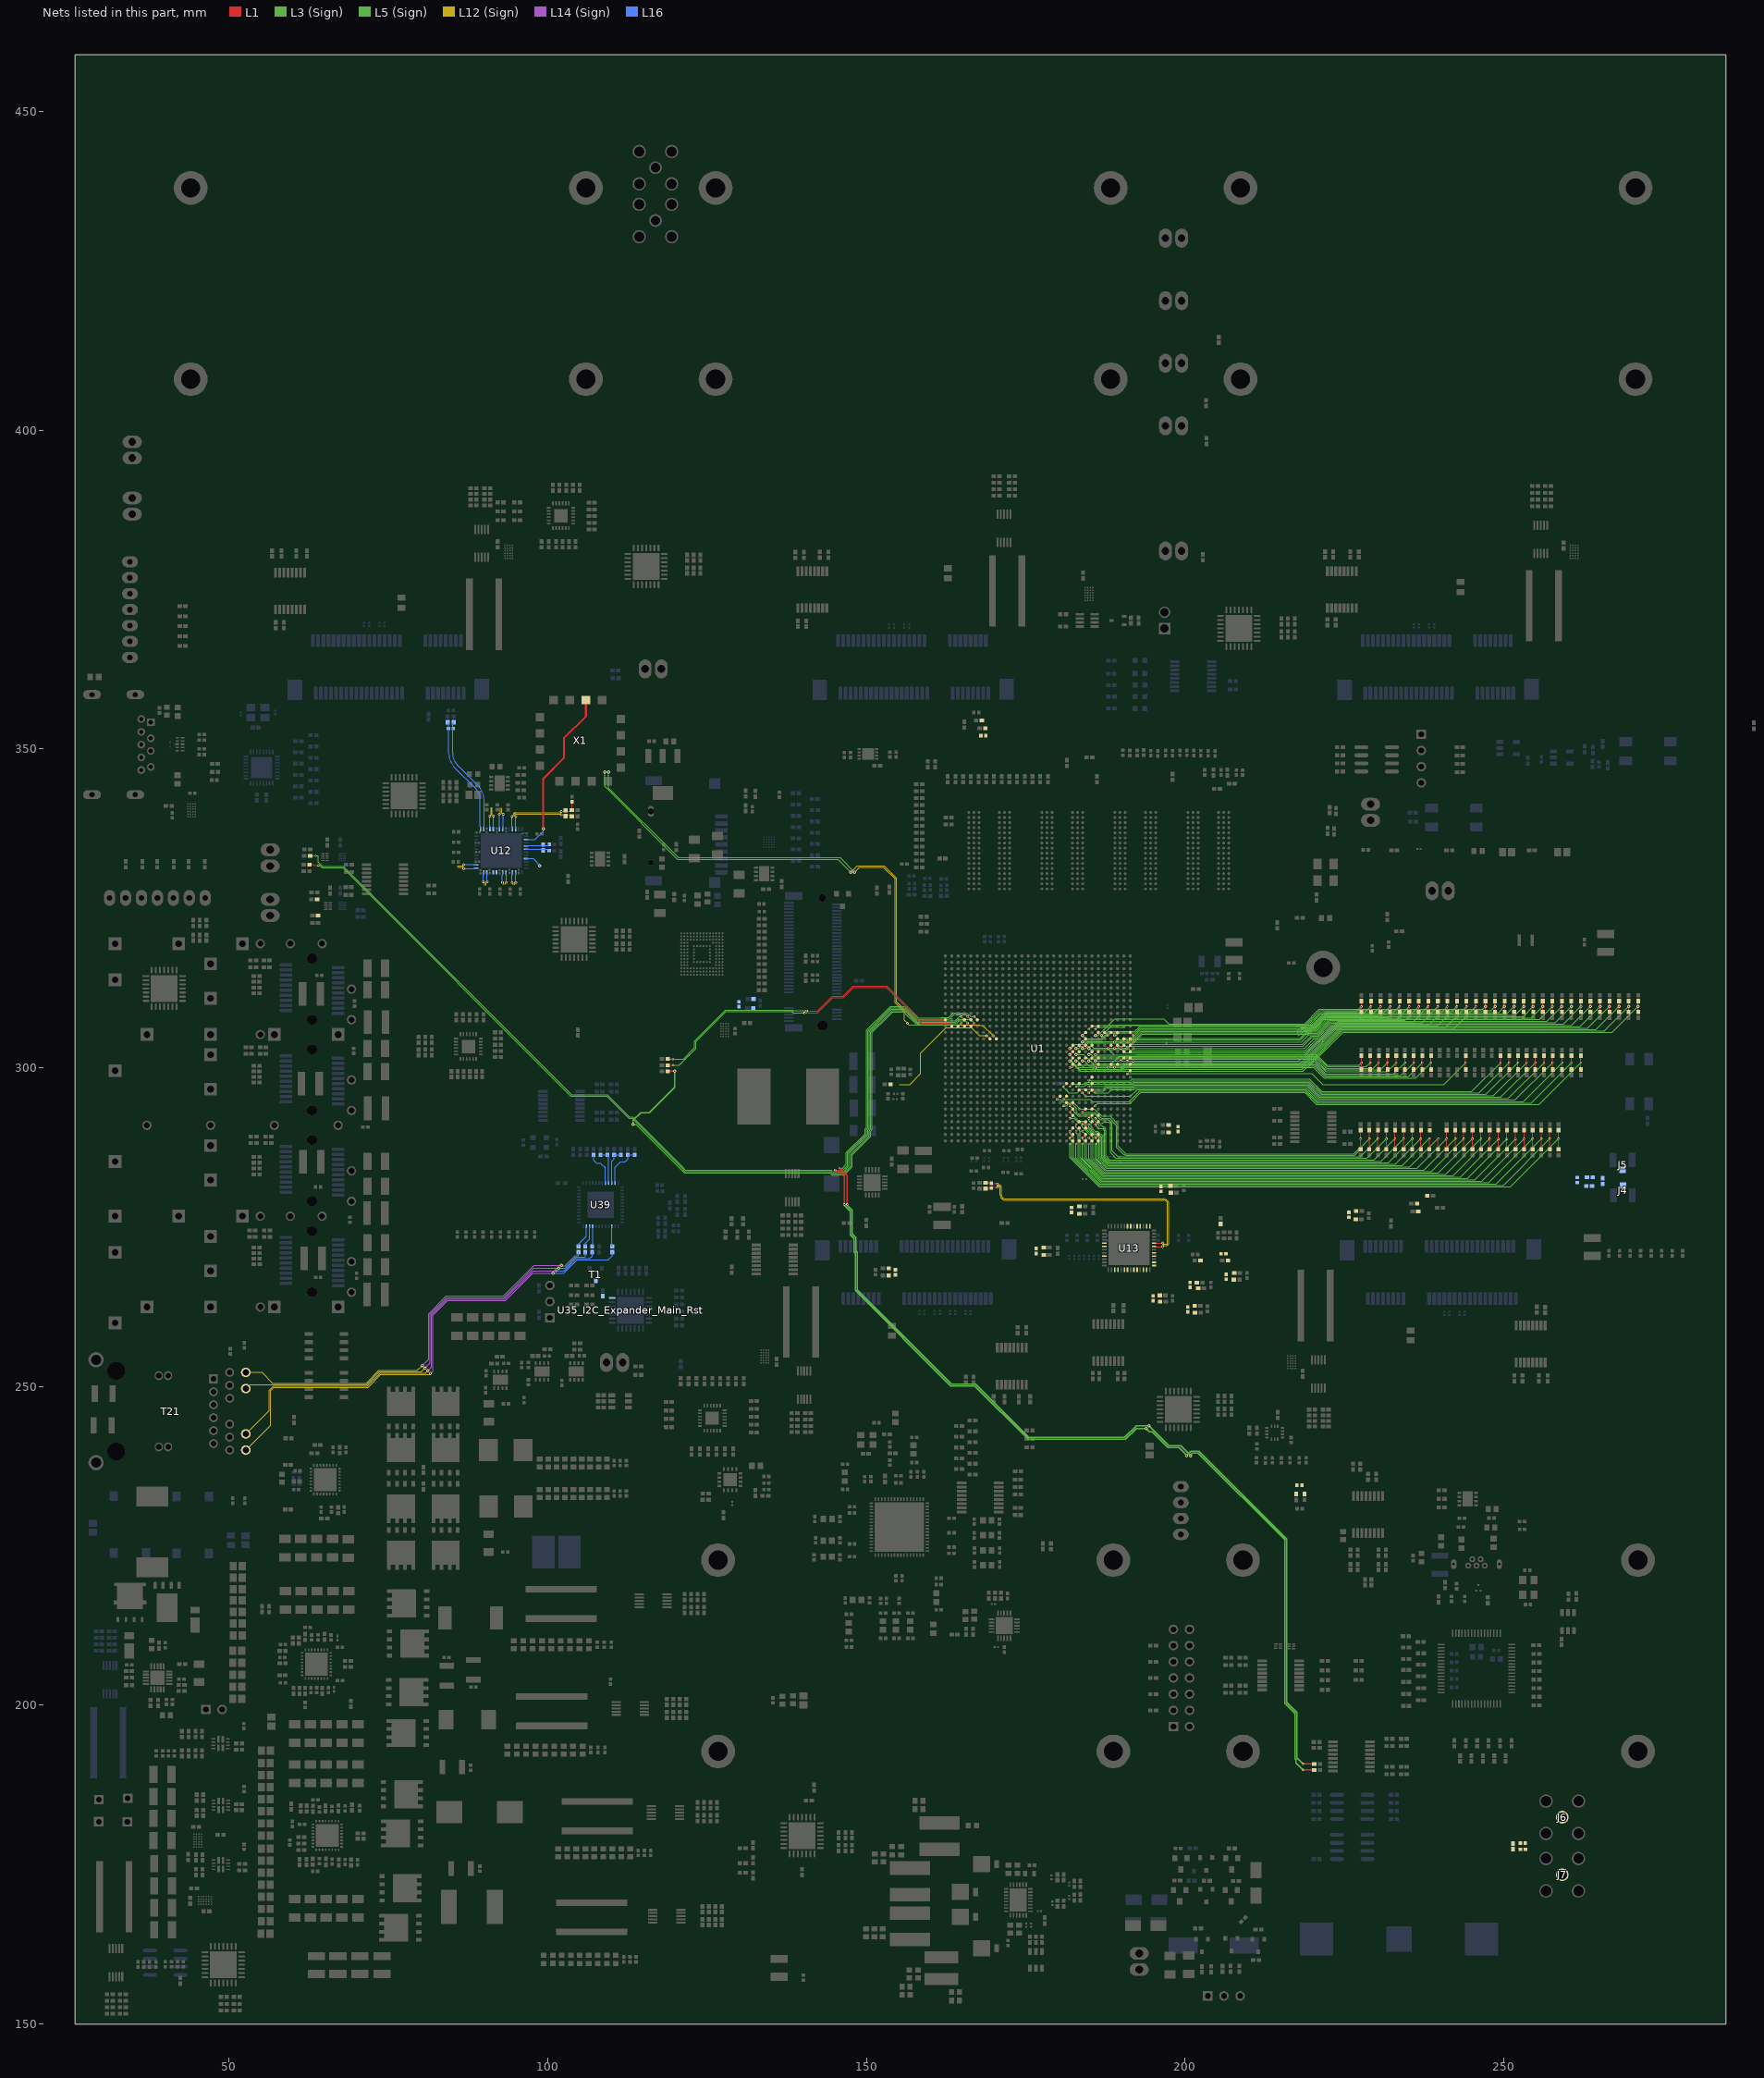
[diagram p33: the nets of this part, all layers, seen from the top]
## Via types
v1: diameter 0.5, hole 0.2, L1 to L16, tented both sides, 1457 vias
v2: diameter 0.35/0/0.35 (per signal layer), hole 0.127, L1 to L3 (Sign), tented both sides, 479 vias
v3: diameter 0.5/0.35/0.35/0.35/0.35/0.35/0.35/0.35/0.35/0.35/0.35/0.35/0.35/0.35/0.35/0.5 (per signal layer), hole 0.15, L1 to L16, tented both sides, 453 vias
v4: diameter 0.5, hole 0.2, L1 to L16, 451 vias
v5: diameter 0.5/0.35/0.35/0.35/0.35/0.35/0.35/0.35/0.35/0.35/0.35/0.35/0.35/0.35/0.35/0.5 (per signal layer), hole 0.2, L1 to L16, tented both sides, 373 vias
v6: diameter 0.8, hole 0.4, L1 to L16, tented both sides, 168 vias
v7: diameter 0.35/0/0.35 (per signal layer), hole 0.127, L1 to L3 (Sign), 138 vias
v8: diameter 2.54, hole 1.02, L1 to L16, 113 vias
v9: diameter 0.5/0/0.5 (per signal layer), hole 0.2, L14 (Sign) to L16, tented both sides, 102 vias
v10: diameter 1.4, hole 0.5, L1 to L16, tented both sides, 80 vias
v11: diameter 0.5, hole 0.2, L3 (Sign) to L6 (PWR/GND), tented both sides, 54 vias
v12: diameter 0.35, hole 0.127, L1 to L2 (GND), tented both sides, 47 vias
v13: diameter 0.4, hole 0.2, L1 to L16, tented both sides, 46 vias
v14: diameter 0.35, hole 0.127, L1 to L16, tented both sides, 16 vias
v15: diameter 0.25, hole 0.2, L1 to L16, 16 vias
v16: diameter 0.5, hole 0.2, L11 (PWR/GND) to L14 (Sign), tented both sides, 16 vias
v17: diameter 0.4, hole 0.2, L1 to L16, 16 vias
v18: diameter 0.3, hole 0.2, L1 to L16, 15 vias
v19: diameter 0.45, hole 0.15, L1 to L16, 12 vias
v20: diameter 0.5/0.35/0.35/0.35/0.35/0.35/0.35/0.35/0.35/0.35/0.35/0.35/0.35/0.35/0.35/0.45 (per signal layer), hole 0.15, L1 to L16, tented both sides, 10 vias
v21: diameter 0.2/0/0.2 (per signal layer), hole 0.1, L1 to L3 (Sign), tented both sides, 9 vias
v22: diameter 0.3, hole 0.127, L14 (Sign) to L16, tented both sides, 8 vias
v23: diameter 0.4, hole 0.1, L1 to L16, 7 vias
v24: diameter 1.15, hole 1.15, L1 to L16, 5 vias
v25: diameter 1.65, hole 1.65, L1 to L16, 5 vias
v26: diameter 0.2, hole 0.1, L1 to L16, 4 vias
v27: diameter 0.4, hole 0.15, L1 to L16, 2 vias
v28: diameter 0.5/0.35/0.35/0.35/0.35/0.35/0.35/0.35/0.35/0.35/0.35/0.35/0.35/0.35/0.35/0.5 (per signal layer), hole 0.15, L1 to L16, 2 vias
v29: diameter 0.35, hole 0.127, L3 (Sign) to L6 (PWR/GND), tented both sides, 2 vias
v30: diameter 0.3, hole 0.127, L15 (GND) to L16, tented both sides, 1 vias
v31: diameter 0.35, hole 0.127, L1 to L2 (GND), 1 vias
v32: diameter 0.5/0.35/0.35/0.35/0.35/0.35/0.35/0.35/0.35/0.35/0.35/0.35/0.35/0.35/0.35/0.5 (per signal layer), hole 0.2, L1 to L16, 1 vias
v33: diameter 0.35/0.35/0.35 (per signal layer), hole 0.127, L1 to L3 (Sign), tented both sides, 1 vias
v34: diameter 0.45/0/0.45 (per signal layer), hole 0.15, L1 to L3 (Sign), tented both sides, 1 vias
v35: diameter 0.45/0/0.45 (per signal layer), hole 0.2, L14 (Sign) to L16, tented both sides, 1 vias

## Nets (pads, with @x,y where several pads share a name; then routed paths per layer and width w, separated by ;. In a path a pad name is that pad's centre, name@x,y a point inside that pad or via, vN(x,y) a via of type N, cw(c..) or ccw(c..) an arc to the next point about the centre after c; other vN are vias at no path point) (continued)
Interrupt6: R557.2 R688.1 U1.AD11 | length 70.3
  L1 w0.116: v2(184.909,298.052) U1.AD11@185.397,298.539
  L1 w0.12: R557.2@249.503,299.747 v2(249.503,300.816) R688.1@249.503,301.885
  L3 (Sign) w0.12: v2(184.909,298.052) 184.953,298.008 185.19,298.008 185.271,297.927 191.467,297.927 191.761,298.221 219.513,298.221 221.465,296.269 244.956,296.269 v2(249.503,300.816)
Interrupt7: R659.2 R744.1 U1.AD10 | length 74.6
  L1 w0.116: v2(184.909,297.052) U1.AD10@185.397,297.539
  L1 w0.12: R659.2@253.593,299.747 v2(253.593,300.816) R744.1@253.593,301.885
  L3 (Sign) w0.12: v2(184.909,297.052) 187.203,297.052 187.412,297.26 191.78,297.26 192.007,297.487 192.397,297.487 219.314,297.487 221.192,295.609 248.386,295.609 v2(253.593,300.816)
Interrupt8: R661.2 R767.1 U1.AB10 | length 75.3
  L1 w0.116: v2(182.909,297.052) U1.AB10@183.397,297.539
  L1 w0.12: R661.2@252.23,299.747 v2(252.23,300.816) R767.1@252.23,301.885
  L3 (Sign) w0.12: v2(182.909,297.052) 184.2,297.052 184.628,297.48 191.671,297.48 191.917,297.726 219.386,297.726 221.283,295.829 247.243,295.829 v2(252.23,300.816)
Interrupt9: R663.2 R819.1 U1.AB9 | length 82.1
  L1 w0.116: U1.AB9@183.397,296.539 v2(183.884,296.052)
  L1 w0.12: R663.2@259.161,299.747 v2(259.161,300.816) R819.1@259.161,301.885
  L3 (Sign) w0.12: v2(183.884,296.052) 184.397,295.539 191.443,295.539 192.5,296.596 192.875,296.596 218.935,296.596 220.815,294.716 253.061,294.716 v2(259.161,300.816)
Interrupt10: R735.2 R822.1 U1.Y10 | length 80.9
  L1 w0.116: v2(180.909,297.052) U1.Y10@181.397,297.539
  L1 w0.12: R735.2@254.956,299.747 v2(254.956,300.816) R822.1@254.956,301.885
  L3 (Sign) w0.12: v2(180.909,297.052) 180.909,296.915 181.775,296.05 183.083,296.05 183.693,296.659 187.122,296.659 187.503,297.04 191.872,297.04 192.098,297.267 219.223,297.267 221.101,295.389 249.529,295.389 v2(254.956,300.816)
Interrupt11: R765.2 R851.1 U1.AA10 | length 74.9
  L1 w0.116: v2(181.909,297.052) U1.AA10@182.397,297.539
  L1 w0.12: R765.2@250.866,299.747 v2(250.866,300.816) R851.1@250.866,301.885
  L3 (Sign) w0.12: v2(181.909,297.052) 182.279,297.421 184.197,297.421 184.476,297.7 191.558,297.7 191.838,297.98 219.443,297.98 221.374,296.049 246.099,296.049 v2(250.866,300.816)
Interrupt12: R817.2 R854.1 U1.AC9 | length 77.8
  L1 w0.116: U1.AC9@184.397,296.539 v2(184.884,296.052)
  L1 w0.12: R817.2@256.32,299.747 v2(256.32,300.816) R854.1@256.32,301.885
  L3 (Sign) w0.12: v2(184.884,296.052) 185.219,296.387 186.023,296.387 186.052,296.358 186.082,296.389 187.217,296.389 187.628,296.799 191.961,296.799 192.209,297.047 192.519,297.047 219.132,297.047 221.01,295.169 250.673,295.169 v2(256.32,300.816)
Interrupt13: R820.2 R857.1 U1.AD9 | length 78.2
  L1 w0.116: U1.AD9@185.397,296.539 v2(185.884,296.052)
  L1 w0.12: R820.2@257.683,299.747 v2(257.683,300.816) R857.1@257.683,301.885
  L3 (Sign) w0.12: v2(185.884,296.052) 187.954,296.052 188.442,296.539 192.044,296.539 192.331,296.827 192.621,296.827 219.041,296.827 220.919,294.949 251.816,294.949 v2(257.683,300.816)
Interrupt14: R823.2 R860.1 U1.AC6 | length 54.7
  L1 w0.116: v2(183.909,293.052) U1.AC6@184.397,293.539
  L1 w0.12: R823.2@228.908,287.208 v2(228.908,288.874) R860.1@228.908,290.21
  L3 (Sign) w0.12: v2(183.909,293.052) 185.865,293.052 186.855,292.062 188.138,292.062 189.281,290.919 189.281,287.515 190.348,286.448 190.468,286.448 190.625,286.292 226.596,286.292 227.779,287.475 227.779,287.745 v2(228.908,288.874)
Interrupt15: R847.2 R862.1 U1.AD6 | length 83.4
  L1 w0.116: U1.AD6@185.397,293.539 v2(185.884,294.027)
  L1 w0.12: R847.2@262.116,299.747 v2(262.116,300.816) R862.1@262.116,301.885
  L3 (Sign) w0.12: v2(185.884,294.027) 186.256,294.399 191.338,294.399 193.053,296.113 218.771,296.113 220.626,294.259 255.559,294.259 v2(262.116,300.816)
Interrupt16: R849.2 R863.1 U1.W8 | length 58.6
  L1 w0.116: v2(179.909,295.052) U1.W8@180.397,295.539
  L1 w0.12: R849.2@227.559,287.208 v2(227.559,288.874) R863.1@227.559,290.21
  L3 (Sign) w0.12: v2(179.909,295.052) 180.436,295.052 180.873,294.615 182.423,294.615 183.515,293.522 185.814,293.522 186.931,292.405 188.227,292.405 189.509,291.122 189.509,287.719 190.716,286.512 226.504,286.512 227.559,287.566 v2(227.559,288.874)
Interrupt17: R852.2 R864.1 U1.Y8 | length 86.8
  L1 w0.116: v2(180.909,295.052) U1.Y8@181.397,295.539
  L1 w0.12: R852.2@260.639,299.747 v2(260.639,300.816) R864.1@260.639,301.885
  L3 (Sign) w0.12: v2(180.909,295.052) 185.123,295.052 185.486,294.689 191.227,294.689 192.877,296.367 218.841,296.367 220.72,294.488 254.31,294.488 v2(260.639,300.816)
Interrupt18: R855.2 R865.1 U1.Y7 | length 60.7
  L1 w0.116: v2(180.909,294.052) U1.Y7@181.397,294.539
  L1 w0.12: R855.2@230.258,287.208 v2(230.258,288.874) R865.1@230.258,290.21
  L3 (Sign) w0.12: v2(180.909,294.052) 181.39,294.052 181.733,294.395 182.224,294.395 182.956,293.662 182.956,293.04 183.286,292.71 185.851,292.71 186.727,291.833 187.96,291.833 188.506,291.287 188.506,287.007 189.442,286.072 227.455,286.072 v2(230.258,288.874)
Interrupt19: R858.2 R866.1 U1.AA7 | length 62.2
  L1 w0.116: v2(181.909,294.052) U1.AA7@182.397,294.539
  L1 w0.12: R858.2@232.957,287.208 v2(232.957,288.874) R866.1@232.957,290.21
  L3 (Sign) w0.12: v2(181.909,294.052) 182.587,293.374 182.587,293.098 183.221,292.464 184.997,292.464 186.504,290.957 186.875,290.957 187.541,290.291 187.541,290.265 187.574,290.231 187.574,289.913 187.579,289.909 187.579,286.169 188.201,285.547 229.629,285.547 v2(232.957,288.874)
Interrupt20: R861.1 R867.1 U1.AD5 | length 61.4
  L1 w0.116: v2(184.909,292.052) U1.AD5@185.397,292.539
  L1 w0.12: R861.1@235.656,287.208 v2(235.656,288.874) R867.1@235.656,290.21
  L3 (Sign) w0.12: v2(184.909,292.052) 184.909,291.722 185.28,291.351 185.28,290.589 185.822,290.047 186.322,290.047 187.139,289.23 187.139,285.987 188.032,285.094 231.875,285.094 v2(235.656,288.874)
Interrupt21: R523.1 R868.1 U1.AE5 | length 56
  L1 w0.116: v2(185.909,292.052) U1.AE5@186.397,292.539
  L1 w0.12: R523.1@231.607,287.208 v2(231.607,288.874) R868.1@231.607,290.21
  L3 (Sign) w0.12: v2(185.909,292.052) 185.976,292.052 186.715,291.313 186.995,291.313 187.198,291.516 187.966,291.516 188.286,291.196 188.286,286.694 189.15,285.83 228.563,285.83 v2(231.607,288.874)
Interrupt22: R546.1 R869.1 U1.AD4 | length 62.1
  L1 w0.116: v2(184.909,291.052) U1.AD4@185.397,291.539
  L1 w0.12: R546.1@237.005,287.208 v2(237.005,288.874) R869.1@237.005,290.21
  L3 (Sign) w0.12: v2(184.909,291.052) 184.909,290.648 185.731,289.827 186.23,289.827 186.919,289.138 186.919,285.896 187.941,284.874 233.005,284.874 v2(237.005,288.874)
Interrupt23: R549.1 R870.1 U1.AE4 | length 58.3
  L1 w0.116: v2(185.909,291.052) U1.AE4@186.397,291.539
  L1 w0.12: R549.1@234.306,287.208 v2(234.306,288.874) R870.1@234.306,290.21
  L3 (Sign) w0.12: v2(185.909,291.052) 186.462,290.5 186.995,290.5 187.354,290.14 187.354,289.822 187.359,289.818 187.359,286.078 188.123,285.314 230.746,285.314 v2(234.306,288.874)
Interrupt24: R552.1 R871.1 U1.AB4 | length 81.5
  L1 w0.116: v2(182.909,291.052) U1.AB4@183.397,291.539
  L1 w0.12: R552.1@251.85,287.158 v2(251.85,288.824) R871.1@251.85,290.16
  L3 (Sign) w0.12: v2(182.909,291.052) 182.909,290.674 183.515,290.068 183.515,285.877 186.952,282.441 245.466,282.441 v2(251.85,288.824)
Interrupt25: R555.1 R872.1 U1.AC4 | length 70.8
  L1 w0.116: v2(183.909,291.052) U1.AC4@184.397,291.539
  L1 w0.12: R555.1@243.753,287.208 v2(243.753,288.874) R872.1@243.753,290.21
  L3 (Sign) w0.12: v2(183.909,291.052) 183.928,291.034 183.928,290.697 185.574,289.05 185.574,285.684 187.49,283.769 238.647,283.769 v2(243.753,288.874)
Interrupt26: R607.1 R873.1 U1.AA6 | length 66.2
  L1 w0.116: v2(181.909,293.052) U1.AA6@182.397,293.539
  L1 w0.12: R607.1@238.355,287.258 v2(238.355,288.924)
  L3 (Sign) w0.12: v2(181.909,293.052) 183.331,291.63 184.116,291.63 184.574,291.172 184.574,290.672 185.64,289.607 186.139,289.607 186.699,289.047 186.699,285.804 187.855,284.649 234.079,284.649 v2(238.355,288.924)
Interrupt27: R660.1 R874.1 U1.AA5 | length 67.3
  L1 w0.116: v2(181.909,292.052) U1.AA5@182.397,292.539
  L1 w0.12: R660.1@239.704,287.208 v2(239.704,288.874)
  L3 (Sign) w0.12: v2(181.909,292.052) 182.598,292.052 183.24,291.41 184.025,291.41 184.354,291.081 184.354,290.581 185.549,289.387 186.048,289.387 186.479,288.956 186.479,285.713 187.764,284.429 235.259,284.429 v2(239.704,288.874)
Interrupt28: R662.1 R875.1 U1.AD2 | length 70.1
  L1 w0.116: v2(184.909,289.052) U1.AD2@185.397,289.539
  L1 w0.12: R662.1@245.102,287.208 v2(245.102,288.874) R875.1@245.102,290.21
  L3 (Sign) w0.12: v2(184.909,289.052) 185.293,288.668 185.293,285.655 187.399,283.549 239.777,283.549 v2(245.102,288.874)
Interrupt29: R664.1 R876.1 U1.AE2 | length 64.6
  L1 w0.116: v2(185.909,289.052) U1.AE2@186.397,289.539
  L1 w0.12: R664.1@241.054,287.208 v2(241.054,288.874) R876.1@241.054,290.21
  L3 (Sign) w0.12: v2(185.909,289.052) 186.244,288.717 186.244,285.637 187.672,284.209 236.388,284.209 v2(241.054,288.874)
Interrupt30: R736.1 R877.1 U1.AD1 | length 70.8
  L1 w0.116: v2(184.909,288.052) U1.AD1@185.397,288.539
  L1 w0.12: R736.1@246.452,287.208 v2(246.452,288.874) R877.1@246.452,290.21
  L3 (Sign) w0.12: v2(184.909,288.052) 184.909,285.727 187.308,283.329 240.906,283.329 v2(246.452,288.874)
Interrupt31: R766.1 R878.1 U1.AE1 | length 65.3
  L1 w0.116: v2(185.909,288.052) U1.AE1@186.397,288.539
  L1 w0.12: R766.1@242.403,287.208 v2(242.403,288.874) R878.1@242.403,290.21
  L3 (Sign) w0.12: v2(185.909,288.052) 185.909,285.661 187.581,283.989 237.518,283.989 v2(242.403,288.874)
Interrupt32: R818.1 R879.1 U1.AC3 | length 75
  L1 w0.116: v2(183.909,290.052) U1.AC3@184.397,290.539
  L1 w0.12: R818.1@247.801,287.208 v2(247.801,288.874) R879.1@247.801,290.21
  L3 (Sign) w0.12: v2(183.909,290.052) 184.389,289.573 184.389,288.851 184.569,288.671 184.569,285.756 187.217,283.109 242.036,283.109 v2(247.801,288.874)
Interrupt33: R821.1 R880.1 U1.AC2 | length 75.7
  L1 w0.116: v2(183.909,289.052) U1.AC2@184.397,289.539
  L1 w0.12: R821.1@249.151,287.158 R821.1@249.151,287.208 v2(249.151,288.824) R880.1@249.151,290.16
  L3 (Sign) w0.12: v2(183.909,289.052) 183.909,288.785 184.266,288.428 184.266,285.749 187.126,282.889 243.215,282.889 v2(249.151,288.824)
Interrupt34: R824.1 R881.1 U1.AA3 | length 86.1
  L1 w0.116: v2(181.909,290.052) U1.AA3@182.397,290.539
  L1 w0.12: R824.1@255.898,287.208 v2(255.898,288.874) R881.1@255.898,290.21
  L3 (Sign) w0.12: v2(181.909,290.052) 181.909,289.692 182.55,289.052 182.55,285.909 186.678,281.781 248.805,281.781 v2(255.898,288.874)
Interrupt35: R848.1 R882.1 U1.AB3 | length 82.3
  L1 w0.116: v2(182.909,290.052) U1.AB3@183.397,290.539
  L1 w0.12: R848.1@253.199,287.208 v2(253.199,288.874) R882.1@253.199,290.21
  L3 (Sign) w0.12: v2(182.909,290.052) 182.909,289.797 183.248,289.458 183.248,285.833 186.86,282.221 246.546,282.221 v2(253.199,288.874)
Interrupt36: R850.1 R883.1 U1.AB1 | length 82
  L1 w0.116: v2(182.909,288.052) U1.AB1@183.397,288.539
  L1 w0.12: R850.1@254.549,287.208 v2(254.549,288.874) R883.1@254.549,290.21
  L3 (Sign) w0.12: v2(182.909,288.052) 182.909,285.86 186.769,282.001 247.675,282.001 v2(254.549,288.874)
Interrupt37: R853.1 R884.1 U1.AC1 | length 76.4
  L1 w0.116: v2(183.909,288.052) U1.AC1@184.397,288.539
  L1 w0.12: R853.1@250.5,287.158 R853.1@250.5,287.208 v2(250.5,288.824) R884.1@250.5,290.16
  L3 (Sign) w0.12: v2(183.909,288.052) 183.909,285.794 187.035,282.669 244.345,282.669 v2(250.5,288.824)
Interrupt38: R856.1 R885.1 U1.AA2 | length 86.8
  L1 w0.116: v2(181.909,289.052) U1.AA2@182.397,289.539
  L1 w0.12: R856.1@257.248,287.208 v2(257.248,288.874) R885.1@257.248,290.21
  L3 (Sign) w0.12: v2(181.909,289.052) 181.909,288.816 182.244,288.481 182.244,285.903 186.587,281.561 249.934,281.561 v2(257.248,288.874)
Interrupt39: R859.1 R886.1 U1.AA1 | length 87.5
  L1 w0.116: v2(181.909,288.052) U1.AA1@182.397,288.539
  L1 w0.12: R859.1@258.597,287.208 v2(258.597,288.874) R886.1@258.597,290.21
  L3 (Sign) w0.12: v2(181.909,288.052) 181.909,285.927 186.496,281.341 251.064,281.341 v2(258.597,288.874)
Interrupt40: R921.2 R961.1 U1.AA13 | length 51.7
  L1 w0.116: v2(181.909,300.052) U1.AA13@182.397,300.539
  L1 w0.12: R921.2@229.053,299.747 v2(229.053,300.816) R961.1@229.053,301.885
  L3 (Sign) w0.12: v2(181.909,300.052) 182.285,300.052 182.639,300.406 188.26,300.406 189.682,301.828 220.573,301.828 222.231,300.17 228.407,300.17 v2(229.053,300.816)
Interrupt41: R923.2 R962.1 U1.AB13 | length 60.7
  L1 w0.116: v2(182.909,300.052) U1.AB13@183.397,300.539
  L1 w0.12: R923.2@238.596,299.747 v2(238.596,300.816) R962.1@238.596,301.885
  L3 (Sign) w0.12: v2(182.909,300.052) 185.384,300.052 185.961,299.475 189.925,299.475 190.497,300.047 191.322,300.047 191.337,300.032 220.192,300.032 221.85,298.374 236.154,298.374 v2(238.596,300.816)
Interrupt42: R925.2 R963.1 U1.AE14 | length 83.7
  L1 w0.116: v5@185.909,301.052 U1.AE14@186.397,301.539
  L1 w0.12: R925.2@263.613,308.751 v1(263.613,309.607) R963.1@263.613,310.463
  L5 (Sign) w0.12: v5(185.904,301.057) 217.843,301.057 218.172,301.387 219.059,301.387 224.317,306.644 260.65,306.644 v1(263.613,309.607)
Interrupt43: R927.2 R964.1 U1.AE13 | length 56.2
  L1 w0.116: v2(185.909,300.052) U1.AE13@186.397,300.539
  L1 w0.12: R927.2@237.233,299.747 v2(237.233,300.816) R964.1@237.233,301.885
  L3 (Sign) w0.12: v2(185.909,300.052) 186.267,299.695 189.834,299.695 190.406,300.267 191.413,300.267 191.428,300.252 220.283,300.252 221.941,298.594 235.011,298.594 v2(237.233,300.816)
Interrupt44: R929.2 R965.1 U1.AC14 | length 100.5
  L1 w0.116: v5@183.909,301.052 U1.AC14@184.397,301.539
  L1 w0.12: R929.2@266.607,308.751 v1(266.607,309.607) R965.1@266.607,310.463
  L5 (Sign) w0.12: v5(183.904,301.057) 184.26,301.057 185.014,300.304 ; 196.291,300.304 185.014,300.304 ; v1(266.607,309.607) 263.204,306.204 224.499,306.204 219.241,300.947 218.797,300.947 218.155,300.304 185.014,300.304
Interrupt45: R931.2 R966.1 U1.AD14 | length 97.2
  L1 w0.116: v5@184.909,301.052 U1.AD14@185.397,301.539
  L1 w0.12: R931.2@265.11,308.751 v1(265.11,309.607) R966.1@265.11,310.463
  L5 (Sign) w0.12: v5(184.904,301.057) 185.213,301.057 185.649,300.622 ; 196.291,300.622 185.649,300.622 ; v1(265.11,309.607) 261.927,306.424 224.408,306.424 219.15,301.167 218.568,301.167 218.023,300.622 185.649,300.622
Interrupt46: R933.2 R967.1 U1.AA14 | length 109.3
  L1 w0.116: v5@181.909,301.052 U1.AA14@182.397,301.539
  L1 w0.12: R933.2@271.098,308.751 v1(271.098,309.607) R967.1@271.098,310.463
  L5 (Sign) w0.12: v5(181.904,301.057) 183.508,299.453 ; 196.317,299.453 183.508,299.453 ; v1(271.098,309.607) 267.035,305.544 224.772,305.544 219.514,300.287 219.341,300.287 218.507,299.453 183.508,299.453
Interrupt47: R935.2 R968.1 U1.AB14 | length 104.1
  L1 w0.116: v5@182.909,301.052 U1.AB14@183.397,301.539
  L1 w0.12: R935.2@268.104,308.751 v1(268.104,309.607) R968.1@268.104,310.463
  L5 (Sign) w0.12: v5(182.904,301.057) 183.143,301.057 184.137,300.063 ; 196.304,300.063 184.137,300.063 ; v1(268.104,309.607) 264.481,305.984 224.59,305.984 219.332,300.727 218.918,300.727 218.255,300.063 184.137,300.063
Interrupt48: R937.2 R969.1 U1.AA15 | length 108.3
  L1 w0.116: v5@181.909,302.052 U1.AA15@182.397,302.539
  L1 w0.12: R937.2@269.601,308.751 v1(269.601,309.607) R969.1@269.601,310.463
  L5 (Sign) w0.12: v5(181.904,302.057) 182.296,301.666 182.296,300.977 183.489,299.784 ; 196.266,299.784 183.489,299.784 ; v1(269.601,309.607) 265.758,305.764 224.681,305.764 219.423,300.507 219.094,300.507 218.37,299.784 183.489,299.784
Interrupt49: R939.2 R970.1 U1.AB15 | length 85.3
  L1 w0.116: v5@182.909,302.052 U1.AB15@183.397,302.539
  L1 w0.12: R939.2@262.116,308.751 v1(262.116,309.607) R970.1@262.116,310.463
  L5 (Sign) w0.12: v5(182.904,302.057) 184.124,302.057 184.76,301.422 217.692,301.422 217.877,301.607 218.968,301.607 224.225,306.864 259.373,306.864 v1(262.116,309.607)
Interrupt50: R941.2 R971.1 U1.AD15 | length 81.5
  L1 w0.116: v5@184.909,302.052 U1.AD15@185.397,302.539
  L1 w0.12: R941.2@260.619,308.751 v1(260.619,309.607) R971.1@260.619,310.463
  L5 (Sign) w0.12: v5(184.904,302.057) 185.267,302.057 185.623,301.701 217.576,301.701 217.702,301.827 218.877,301.827 224.134,307.084 258.096,307.084 v1(260.619,309.607)
Interrupt51: R943.2 R972.1 U1.AE15 | length 89.1
  L1 w0.116: v5(185.909,302.052) U1.AE15@186.397,302.539
  L1 w0.12: R943.2@259.122,308.751 v1(259.122,309.607) R972.1@259.122,310.463
  L5 (Sign) w0.12: v5(185.909,302.052) v5@185.915,302.047 ; 196.291,302.047 v5@185.915,302.047 ; v1(259.122,309.607) 256.819,307.304 224.043,307.304 218.785,302.047 v5@185.915,302.047
Interrupt52: R945.2 R973.1 U1.AG13 | length 51.1
  L1 w0.116: v2(187.909,300.052) U1.AG13@188.397,300.539
  L1 w0.12: R945.2@234.506,299.747 v2(234.506,300.816) R973.1@234.506,301.885
  L3 (Sign) w0.12: v2(187.909,300.052) 188.265,300.052 188.631,300.418 189.935,300.418 190.224,300.707 191.595,300.707 191.61,300.692 220.465,300.692 222.123,299.034 232.724,299.034 v2(234.506,300.816)
Interrupt53: R947.2 R974.1 U1.AH13 | length 51.5
  L1 w0.116: v2(188.909,300.052) U1.AH13@189.397,300.539
  L1 w0.12: R947.2@235.87,299.747 v2(235.87,300.816) R974.1@235.87,301.885
  L3 (Sign) w0.12: v2(188.909,300.052) 189.88,300.052 190.315,300.487 191.504,300.487 191.519,300.472 220.374,300.472 222.032,298.814 233.868,298.814 v2(235.87,300.816)
Interrupt54: R949.2 R975.1 U1.AK13 | length 45.4
  L1 w0.116: U1.AK13@191.397,300.539 v2@191.884,301.027
  L1 w0.12: R949.2@233.143,299.747 v2(233.143,300.816) R975.1@233.143,301.885
  L3 (Sign) w0.12: v2(191.878,301.027) 220.441,301.027 222.099,299.369 231.696,299.369 v2(233.143,300.816)
Interrupt55: R951.2 R976.1 U1.AK12 | length 58.1
  L1 w0.116: v2(190.909,299.052) U1.AK12@191.397,299.539
  L1 w0.12: R951.2@244.05,299.747 v2(244.05,300.816) R976.1@244.05,301.885
  L3 (Sign) w0.12: v2(190.909,299.052) 191.254,299.052 191.342,299.14 219.839,299.14 221.585,297.394 240.628,297.394 v2(244.05,300.816)
Interrupt56: R953.2 R977.1 U1.AJ14 | length 44.6
  L1 w0.116: v2(189.909,301.052) U1.AJ14@190.397,301.539
  L1 w0.12: R953.2@230.416,299.747 v2(230.416,300.816) R977.1@230.416,301.885
  L3 (Sign) w0.12: v2(189.909,301.052) 190.444,301.587 220.503,301.587 222.161,299.929 229.529,299.929 v2(230.416,300.816)
Interrupt57: R955.2 R978.1 U1.AK14 | length 45
  L1 w0.116: v2(190.909,301.052) U1.AK14@191.397,301.539
  L1 w0.12: R955.2@231.78,299.747 v2(231.78,300.816) R978.1@231.78,301.885
  L3 (Sign) w0.12: v2(190.909,301.052) 191.224,301.367 220.412,301.367 222.07,299.709 230.673,299.709 v2(231.78,300.816)
Interrupt58: R957.2 R979.1 U1.AJ15 | length 58.8
  L1 w0.116: U1.AJ15@190.397,302.539 v2(190.884,303.027)
  L1 w0.12: R957.2@244.153,308.751 v2(244.152,309.607) R979.1@244.152,310.463
  L3 (Sign) w0.12: v2(190.884,303.027) 191.169,303.027 191.529,302.666 ; 191.465,302.654 218.844,302.654 220.526,304.336 221.093,304.336 223.107,306.35 240.895,306.35 v2(244.152,309.607)
Interrupt59: R959.2 R980.1 U1.AK15 | length 55.9
  L1 w0.116: U1.AK15@191.397,302.539 v2@191.884,303.027
  L1 w0.12: R959.2@242.656,308.751 v2(242.655,309.607) R980.1@242.655,310.463
  L3 (Sign) w0.12: v2(191.878,303.027) 218.689,303.027 220.218,304.556 221.002,304.556 223.025,306.578 239.626,306.578 v2(242.655,309.607)
Interrupt60: R922.1 R981.1 U1.AC16 | length 77.6
  L1 w0.116: v5@183.909,303.052 U1.AC16@184.397,303.539
  L1 w0.12: R922.1@256.128,308.751 v1(256.128,309.607) R981.1@256.128,310.463
  L5 (Sign) w0.12: v5(183.904,303.057) 184.43,303.057 184.765,303.392 185.342,303.392 185.611,303.124 190.843,303.124 193.228,305.509 219.309,305.509 221.614,307.814 254.335,307.814 v1(256.128,309.607)
Interrupt61: R924.1 R982.1 U1.AD16 | length 78
  L1 w0.116: v5@184.909,303.052 U1.AD16@185.397,303.539
  L1 w0.12: R924.1@257.625,308.751 v1(257.625,309.607) R982.1@257.625,310.463
  L5 (Sign) w0.12: v5(184.904,303.057) 185.058,302.904 190.953,302.904 193.338,305.289 219.4,305.289 221.705,307.594 255.612,307.594 v1(257.625,309.607)
Interrupt62: R926.1 R983.1 U1.AA16 | length 76.3
  L1 w0.116: v5@181.909,303.052 U1.AA16@182.397,303.539
  L1 w0.12: R926.1@253.134,308.751 v1(253.134,309.607) R983.1@253.134,310.463
  L5 (Sign) w0.12: v5(181.904,303.057) 182.141,303.057 182.791,303.708 184.277,303.708 184.65,304.081 184.72,304.081 184.733,304.094 191.134,304.094 192.989,305.949 194.214,305.949 194.218,305.953 219.125,305.953 221.43,308.258 249.079,308.258 ; 249.079,308.254 251.781,308.254 v1(253.134,309.607)
Interrupt63: R928.1 R984.1 U1.AB16 | length 76.8
  L1 w0.116: v5@182.909,303.052 U1.AB16@183.397,303.539
  L1 w0.12: R928.1@254.631,308.751 v1(254.631,309.607) R984.1@254.631,310.463
  L5 (Sign) w0.12: v5(182.904,303.057) 183.345,303.057 183.68,303.392 184.343,303.392 184.825,303.874 191.225,303.874 193.08,305.729 219.218,305.729 221.523,308.034 253.058,308.034 v1(254.631,309.607)
Interrupt64: R930.1 R985.1 U1.AC17 | length 75.7
  L1 w0.116: v5@183.909,304.052 U1.AC17@184.397,304.539
  L1 w0.12: R930.1@251.637,308.751 v1(251.637,309.607) R985.1@251.637,310.463
  L5 (Sign) w0.12: v5(183.904,304.057) 183.92,304.057 184.163,304.301 184.629,304.301 184.642,304.314 186.947,304.314 188.118,305.486 192.215,305.486 192.898,306.169 192.948,306.169 192.964,306.184 219.029,306.184 221.334,308.49 250.508,308.49 ; 250.508,308.478 v1(251.637,309.607)
  L3 (Sign) w0.12: v5@183.909,304.052 187.18,304.052
Interrupt65: R932.1 R986.1 U1.AC18 | length 71
  L1 w0.116: v5@183.909,305.052 U1.AC18@184.397,305.539
  L1 w0.12: R932.1@250.14,308.751 v1(250.14,309.607) R986.1@250.14,310.463
  L5 (Sign) w0.12: v5(183.904,305.057) 184.441,304.521 184.537,304.521 184.551,304.534 186.856,304.534 188.027,305.706 192.123,305.706 192.806,306.389 192.825,306.389 192.85,306.413 218.934,306.413 221.239,308.718 249.251,308.718 v1(250.14,309.607)
Interrupt66: R934.1 R987.1 U1.AD19 | length 46.7
  L1 w0.116: v2(184.909,306.052) U1.AD19@185.397,306.539
  L1 w0.12: R934.1@227.686,308.751 v2(227.686,309.607) R987.1@227.686,310.463
  L3 (Sign) w0.12: v2(184.909,306.052) 184.983,306.052 185.522,306.591 186.563,306.591 186.639,306.667 189.586,306.667 189.674,306.756 220.091,306.756 222.141,308.805 226.884,308.805 v2(227.686,309.607)
Interrupt67: R936.1 R988.1 U1.AE19 | length 20.5
  L1 w0.116: v2(185.909,306.052) U1.AE19@186.397,306.539
  L1 w0.12: R936.1@229.183,308.751 v2(229.183,309.607) R988.1@229.183,310.463
  L3 (Sign) w0.12: v2(185.909,306.052) 186.156,306.299 186.682,306.299 186.771,306.387 187.048,306.387 190.578,306.387 190.662,306.471 ; 217.328,306.536 220.182,306.536 222.232,308.585 228.161,308.585 v2(229.183,309.607)
Interrupt68: R938.1 R989.1 U1.AG16 | length 40.3
  L1 w0.116: v2(187.909,303.052) U1.AG16@188.397,303.539
  L1 w0.12: R938.1@227.69,299.747 v2(227.69,300.816) R989.1@227.69,301.885
  L3 (Sign) w0.12: v2(187.909,303.052) 188.854,302.108 ; 192.397,302.108 220.605,302.108 222.263,300.45 227.323,300.45 v2(227.69,300.816)
Interrupt69: R940.1 R990.1 U1.AH16 | length 57.4
  L1 w0.116: v2(188.909,303.052) U1.AH16@189.397,303.539
  L1 w0.12: R940.1@241.159,308.751 v2(241.158,309.607) R990.1@241.158,310.463
  L3 (Sign) w0.12: v2(188.909,303.052) 189.319,303.052 189.695,303.428 218.523,303.428 219.87,304.776 220.911,304.776 222.955,306.82 238.371,306.82 v2(241.158,309.607)
Interrupt70: R942.1 R991.1 U1.AJ16 | length 61.4
  L1 w0.116: v2(189.909,303.052) U1.AJ16@190.397,303.539
  L1 w0.12: R942.1@245.649,308.751 v2(245.649,309.607) R991.1@245.649,310.463
  L3 (Sign) w0.12: v2(189.909,303.052) 190.562,302.4 218.949,302.4 220.665,304.116 221.185,304.116 223.164,306.096 242.138,306.096 v2(245.649,309.607)
Interrupt71: R944.1 R992.1 U1.AK16 | length 51
  L1 w0.116: U1.AK16@191.397,303.539 v2@191.884,304.027
  L1 w0.12: R944.1@238.165,308.751 v2(238.164,309.607) R992.1@238.164,310.463
  L3 (Sign) w0.12: v2(191.878,304.027) 218.275,304.027 219.464,305.216 220.729,305.216 222.778,307.265 235.822,307.265 v2(238.164,309.607)
Interrupt72: R946.1 R993.1 U1.AH17 | length 51
  L1 w0.116: v2(188.909,304.052) U1.AH17@189.397,304.539
  L1 w0.12: R946.1@235.171,308.751 v2(235.17,309.607) R993.1@235.17,310.463
  L3 (Sign) w0.12: v2(188.909,304.052) 189.276,304.419 190.06,304.419 190.263,304.622 218.028,304.622 219.062,305.656 220.547,305.656 222.596,307.705 233.268,307.705 v2(235.17,309.607)
Interrupt73: R948.1 R994.1 U1.AJ17 | length 51.5
  L1 w0.116: v2(189.909,304.052) U1.AJ17@190.397,304.539
  L1 w0.12: R948.1@236.668,308.751 v2(236.667,309.607) R994.1@236.667,310.463
  L3 (Sign) w0.12: v2(189.909,304.052) 190.235,304.052 190.564,304.381 190.765,304.381 190.771,304.387 218.126,304.387 219.175,305.436 220.638,305.436 222.687,307.485 234.545,307.485 v2(236.667,309.607)
Interrupt74: R950.1 R995.1 U1.AK17 | length 53.8
  L1 w0.116: v2(190.909,304.052) U1.AK17@191.397,304.539
  L1 w0.12: R950.1@239.662,308.751 v2(239.661,309.607) R995.1@239.661,310.463
  L3 (Sign) w0.12: v2(190.909,304.052) 191.209,304.052 191.604,303.657 218.428,303.657 219.767,304.996 220.82,304.996 222.87,307.045 237.099,307.045 v2(239.661,309.607)
Interrupt75: R952.1 R996.1 U1.AK18 | length 20.1
  L1 w0.116: U1.AK18@191.397,305.539 v2(191.884,305.052)
  L1 w0.12: R952.1@233.674,308.751 v2(233.674,309.607) R996.1@233.674,310.463
  L3 (Sign) w0.12: 217.85,305.052 218.674,305.876 220.456,305.876 222.505,307.925 231.991,307.925 v2(233.674,309.607)
Interrupt76: R954.1 R997.1 U1.AG18 | length 18.9
  L1 w0.116: v2(187.909,305.052) U1.AG18@188.397,305.539
  L1 w0.12: R954.1@230.68,308.751 v2(230.68,309.607) R997.1@230.68,310.463
  L3 (Sign) w0.12: v2(187.909,305.052) 188.292,305.435 189.126,305.435 189.393,305.702 ; 217.581,305.702 218.195,306.316 220.273,306.316 222.323,308.365 229.438,308.365 v2(230.68,309.607)
Interrupt77: R956.1 R998.1 U1.AH18 | length 19.4
  L1 w0.116: v2(188.909,305.052) U1.AH18@189.397,305.539
  L1 w0.12: R956.1@232.177,308.751 v2(232.177,309.607) R998.1@232.177,310.463
  L3 (Sign) w0.12: v2(188.909,305.052) 189.177,305.052 189.535,305.41 ; 217.702,305.41 218.388,306.096 220.364,306.096 222.414,308.145 230.714,308.145 v2(232.177,309.607)
Interrupt78: R958.1 R999.1 U1.AE18 | length 66.2
  L1 w0.116: v5@185.909,305.052 U1.AE18@186.397,305.539
  L1 w0.12: R958.1@247.146,308.751 v1(247.146,309.607) R999.1@247.146,310.463
  L5 (Sign) w0.12: v5(185.904,305.057) 186.389,305.057 187.244,305.913 188.989,307.657 196.672,307.657 197.46,306.87 218.745,306.87 221.05,309.175 246.714,309.175 v1(247.146,309.607)
Interrupt79: R960.1 R1000.1 U1.AF18 | length 66
  L1 w0.116: v5@186.909,305.052 U1.AF18@187.397,305.539
  L1 w0.12: R960.1@248.643,308.751 v1(248.643,309.607) R1000.1@248.643,310.463
  L5 (Sign) w0.12: v5(186.906,305.092) 186.941,305.057 188.525,306.642 218.839,306.642 221.145,308.947 247.983,308.947 v1(248.643,309.607)
JTAG_CLK: R1042.1 U39.20 | length 5.5
  L16 w0.12: R1042.1@107.214,286.337 107.214,285.495 107.632,285.077 108.269,285.077 109.049,284.297 U39.20@109.049,281.925
JTAG_TDI: R336.2 R1040.1 U39.23 | length 6.7
  L16 w0.12: U39.23@110.549,281.925 110.549,284.412 111.43,285.293 112.141,285.293 112.563,285.715 R1040.1@112.563,286.337 R336.2@113.633,286.337
JTAG_TDO: R337.2 R1043.1 U39.21 | length 5.6
  L16 w0.12: R1043.1@108.284,286.337 R337.2@109.354,286.337 109.549,286.141 U39.21@109.549,281.925
JTAG_TMS: R338.2 R1041.1 U39.22 | length 5.6
  L16 w0.12: U39.22@110.049,281.925 110.049,285.322 110.424,285.696 R1041.1@110.424,286.337 R338.2@111.494,286.337
LED_0: R329.1 U39.47 | length 3.6
  L16 w0.12: R329.1@104.826,271.994 104.826,272.339 106.049,273.562 U39.47@106.049,275.125
LED_0_RJ: R329.2 T21.17 | length 66
  L12 (Sign) w0.12: T21.17@52.632,252.221 55.119,252.221 56.794,250.546 71.52,250.546 73.514,252.54 79.553,252.54 v16(80.315,253.301)
  L14 (Sign) w0.12: v16(80.315,253.301) 81.325,254.311 81.325,261.416 84.107,264.198 93.063,264.198 97.889,269.024 v9(102.129,269.024)
  L16 w0.12: v9(102.129,269.024) 102.235,268.917 102.719,268.917 104.311,270.51 104.787,270.51 104.826,270.548 R329.2@104.826,271.094
LED_1: R330.1 U39.46 | length 3.4
  L16 w0.12: R330.1@105.908,271.994 105.908,272.507 106.549,273.148 U39.46@106.549,275.125
LED_1_RJ: R330.2 T21.18 | length 67
  L12 (Sign) w0.12: T21.18@52.632,249.681 52.672,249.681 53.317,250.326 71.612,250.326 73.605,252.32 80.181,252.32 v16(80.739,252.877)
  L14 (Sign) w0.12: v16(80.739,252.877) 81.545,253.683 81.545,261.325 84.177,263.957 93.163,263.957 97.806,268.6 v9(101.704,268.6)
  L16 w0.12: v9(101.704,268.6) 102.712,268.6 104.402,270.29 105.774,270.29 105.908,270.424 R330.2@105.908,271.094
LED_2: R331.1 U39.45 | length 3.2
  L16 w0.12: R331.1@106.991,271.994 107.049,272.052 U39.45@107.049,275.125
LED_2_RJ: R331.2 T21.19 | length 73.2
  L12 (Sign) w0.12: T21.19@52.632,242.571 56.295,246.234 56.295,249.446 56.955,250.106 71.703,250.106 73.697,252.1 80.81,252.1 v16(81.163,252.453)
  L14 (Sign) w0.12: v16(81.163,252.453) 81.765,253.054 81.765,261.233 84.259,263.728 93.258,263.728 97.705,268.176 v9(101.28,268.176)
  L16 w0.12: v9(101.28,268.176) 102.599,268.176 104.493,270.07 106.595,270.07 106.991,270.466 R331.2@106.991,271.094
LED_3: R332.2 U39.39 | length 3.2
  L16 w0.12: U39.39@110.049,275.125 110.049,272.066 R332.2@110.122,271.994
LED_3_RJ: R332.1 T21.20 | length 79
  L12 (Sign) w0.12: T21.20@52.632,240.031 56.515,243.914 56.515,249.354 57.046,249.886 71.794,249.886 73.788,251.88 81.438,251.88 v16(81.588,252.029)
  L14 (Sign) w0.12: v16(81.588,252.029) 81.985,252.426 81.985,261.142 84.329,263.487 93.358,263.487 97.622,267.751 v9(100.856,267.751)
  L16 w0.12: v9(100.856,267.751) 102.486,267.751 104.584,269.85 109.497,269.85 110.122,270.475 R332.1@110.122,271.094
LTC6952_0_Out0_N: C54.2 R1054.2 U12.33 | length 3.4
  L12 (Sign) w0.073: v13(92.395,339.763) ccw(c92.395,339.965) 92.597,339.965 92.597,340.741
  L16 w0.1: v13(92.395,339.763) 92.395,338.949 92.411,338.932 92.411,338.171 92.395,338.155 92.395,337.861 cw(c92.395,337.809) 92.447,337.809 U12.33@92.447,337.461
LTC6952_0_Out0_P: C54.1 R539.2 U12.34 | length 3.4
  L12 (Sign) w0.073: 92.797,340.741 92.797,339.965 ccw(c92.999,339.965) v13(92.999,339.763)
  L16 w0.1: U12.34@92.947,337.461 92.947,337.809 cw(c92.999,337.809) 92.999,337.861 92.999,337.905 93.016,337.921 93.016,339.183 92.999,339.199 v13(92.999,339.763)
LTC6952_0_Out1_N: C316.2 R1056.2 U12.30 | length 3.5
  L12 (Sign) w0.073: v13(90.895,339.496) ccw(c90.895,339.699) 91.097,339.699 91.097,340.792
  L16 w0.1: v13(90.895,339.496) 90.895,337.861 cw(c90.895,337.809) 90.947,337.809 U12.30@90.947,337.461
LTC6952_0_Out1_P: C316.1 R1055.2 U12.31 | length 3.5
  L12 (Sign) w0.073: 91.297,340.792 91.297,339.699 ccw(c91.499,339.699) v13(91.499,339.496)
  L16 w0.1: U12.31@91.447,337.461 91.447,337.809 cw(c91.499,337.809) 91.499,337.861 v13(91.499,339.496)
LTC6952_0_Out2_N: C318.2 R1058.2 U12.27 | length 18.7
  L16 w0.1: R1058.2@84.303,354.205 84.47,354.037 84.47,353.3 C318.2@84.395,353.225 84.483,353.137 84.483,349.3 ccw(c87.623,349.3) 85.403,347.079 88.651,343.831 cw(c86.855,342.035) 89.395,342.035 89.395,337.861 cw(c89.395,337.809) 89.447,337.809 U12.27@89.447,337.461
LTC6952_0_Out2_P: C318.1 R1057.2 U12.28 | length 18.7
  L16 w0.1: R1057.2@85.242,354.205 85.075,354.037 85.075,353.326 C318.1@85.175,353.225 85.087,353.137 85.087,349.302 ccw(c87.627,349.302) 85.831,347.505 89.081,344.255 cw(c86.865,342.039) 89.999,342.039 89.999,337.861 ccw(c89.999,337.809) 89.947,337.809 U12.28@89.947,337.461
LTC6952_0_Out6_N: C601.2 R1068.2 U12.15 | length 3.1
  L12 (Sign) w0.073: 85.839,331.461 86.602,331.461 cw(c86.602,331.259) v13(86.804,331.259)
  L16 w0.1: v13(86.804,331.259) 88.397,331.259 cw(c88.449,331.259) 88.449,331.311 U12.15@88.797,331.311
LTC6952_0_Out6_P: C601.1 R1067.2 U12.16 | length 3.1
  L12 (Sign) w0.073: 85.839,331.661 86.602,331.661 ccw(c86.602,331.863) v13(86.804,331.863)
  L16 w0.1: v13(86.804,331.863) 88.397,331.863 ccw(c88.449,331.863) 88.449,331.811 U12.16@88.797,331.811
LTC6952_0_Out7_N: C608.2 R1070.2 U12.12 | length 2.2
  L12 (Sign) w0.073: 90.298,328.613 90.298,328.994 cw(c90.5,328.994) v13(90.5,329.197)
  L16 w0.1: U12.12@90.447,330.661 90.447,330.313 ccw(c90.499,330.313) 90.499,330.261 v13(90.5,329.197)
LTC6952_0_Out7_P: C608.1 R1069.2 U12.13 | length 2.2
  L12 (Sign) w0.073: v13(89.896,329.197) cw(c89.896,328.994) 90.098,328.994 90.098,328.613
  L16 w0.1: v13(89.896,329.197) 89.896,329.375 89.895,330.261 ccw(c89.895,330.313) 89.947,330.313 U12.13@89.947,330.661
LTC6952_0_Out8_N: C682.1 R1071.2 U12.9
LTC6952_0_Out8_P: C682.2 R1072.2 U12.10
LTC6952_0_Out9_N: C684.1 R1073.2 U12.6 | length 2
  L12 (Sign) w0.073: 93.297,328.765 93.297,328.88 cw(c93.499,328.88) v13(93.499,329.082)
  L16 w0.1: U12.6@93.447,330.661 93.447,330.313 ccw(c93.499,330.313) 93.499,330.261 v13(93.499,329.082)
LTC6952_0_Out9_P: C684.2 R1074.2 U12.7 | length 2
  L12 (Sign) w0.073: v13(92.895,329.082) cw(c92.895,328.88) 93.097,328.88 93.097,328.765
  L16 w0.1: v13(92.895,329.082) 92.895,330.261 ccw(c92.895,330.313) 92.947,330.313 U12.7@92.947,330.661
LTC6952_0_Out10_N: C48.1 R82.1 U12.3 | length 2.1
  L12 (Sign) w0.073: 94.797,328.727 94.797,328.88 cw(c94.999,328.88) v13(94.999,329.082)
  L16 w0.1: U12.3@94.947,330.661 94.947,330.313 ccw(c94.999,330.313) 94.999,330.261 v13(94.999,329.082)
LTC6952_0_Out10_P: C47.1 R82.2 U12.4 | length 2.1
  L12 (Sign) w0.073: v13(94.395,329.082) cw(c94.395,328.88) 94.598,328.88 94.598,328.727
  L16 w0.1: v13(94.395,329.082) 94.395,330.261 ccw(c94.395,330.313) 94.447,330.313 U12.4@94.447,330.661
LTC6952_0_REF_N: C43.1 R78.2 U12.45 | length 3.9
  L16 w0.1: U12.45@96.597,334.811 96.649,334.863 99.131,334.863 R78.2@99.293,335.025 99.453,334.865 100.061,334.865 C43.1@100.261,335.064
LTC6952_0_REF_P: C44.1 R78.1 U12.46 | length 3.9
  L16 w0.1: U12.46@96.597,334.311 96.649,334.259 99.159,334.259 R78.1@99.293,334.125 99.428,334.26 100.041,334.26 C44.1@100.241,334.061
LTC6952_1_C_N: J5.2 R270.1 R1080.2
LTC6952_1_C_Out10_N: C52.2 J6.1
LTC6952_1_C_Out10_P: C51.2 J7.1
LTC6952_1_C_P: J4.2 R270.2 R1077.2
LTC6952_1_CP_Out: C46.2 R77.2 U12.43 X1.2 | length 26.6
  L1 w0.3: v1(99.289,337.49) 99.289,345.338 102.538,348.588 102.538,351.674 105.994,355.13 X1.2@105.994,357.657
  L16 w0.12: U12.43@96.597,335.811 97.989,335.811 99.289,337.11 v1(99.289,337.49)
LTC6952_1_Out0_N: C796.2 R1090.2 U13.33
LTC6952_1_Out0_P: C796.1 R1089.2 U13.34
LTC6952_1_Out1_N: C798.2 R1092.2 U13.30
LTC6952_1_Out1_P: C798.1 R1091.2 U13.31
LTC6952_1_Out2_N: C801.2 R1094.2 U13.27
LTC6952_1_Out2_P: C801.1 R1093.2 U13.28
LTC6952_1_Out4_N: C805.2 R1098.2 U13.21 | length 39.8
  L1 w0.073: v13@170.505,281.837 cw(c170.505,281.794) v13(170.548,281.794)
  L1 w0.081: R1098.2@168.674,281.978 169.065,281.978 ccw(c169.138,281.978) 169.138,281.905 C805.2@169.608,281.905 ; C805.2@169.709,281.837 v13@170.505,281.837 ; U13.21@195.123,271.981 195.471,271.981 cw(c195.471,271.939) 195.513,271.939 v13(196.469,271.939)
  L12 (Sign) w0.073: v13(170.548,281.794) ccw(c170.698,281.794) 170.698,281.644 170.751,281.644 cw(c170.751,281.205) 171.191,281.205 171.191,280.06 ccw(c171.817,280.06) 171.817,279.434 196.634,279.434 cw(c196.634,278.597) 197.472,278.597 197.472,272.567 cw(c197.036,272.567) 197.036,272.131 196.662,272.131 ccw(c196.662,271.939) v13(196.469,271.939)
LTC6952_1_Out4_P: C805.1 R1097.2 U13.22 | length 39.2
  L1 w0.073: v13@170.505,281.252 ccw(c170.505,281.294) v13(170.548,281.294)
  L1 w0.081: R1097.2@168.674,281.053 168.992,281.053 ccw(c168.992,281.125) 169.065,281.125 C805.1@169.608,281.125 ; C805.1@169.709,281.252 v13@170.505,281.252 ; U13.22@195.123,272.481 195.471,272.481 ccw(c195.471,272.524) 195.513,272.524 v13(196.469,272.524)
  L12 (Sign) w0.073: v13(170.548,281.294) cw(c170.698,281.294) 170.698,281.445 170.751,281.445 cw(c170.751,281.205) 170.992,281.205 170.992,280.06 ccw(c171.817,280.06) 171.817,279.235 196.634,279.235 cw(c196.634,278.597) 197.272,278.597 197.272,272.567 cw(c197.036,272.567) 197.036,272.331 196.662,272.331 cw(c196.662,272.524) v13(196.469,272.524)
LTC6952_1_Out5_N: C807.2 R1101.2 U13.18
LTC6952_1_Out5_P: C807.1 R1100.2 U13.19
LTC6952_1_Out6_N: C811.2 R1104.2 U13.15
LTC6952_1_Out6_P: C811.1 R1103.2 U13.16
LTC6952_1_Out7_N: C813.2 R1106.2 U13.12
LTC6952_1_Out7_P: C813.1 R1105.2 U13.13
LTC6952_1_Out8_N: C815.2 R1108.2 U13.9
LTC6952_1_Out8_P: C815.1 R1107.2 U13.10
LTC6952_1_Out9_N: C817.2 R1110.2 U13.6
LTC6952_1_Out9_P: C817.1 R1109.2 U13.7
LTC6952_1_Out10_N: C52.1 R536.1 U13.3
LTC6952_1_Out10_P: C51.1 R536.2 U13.4
LTC6952_1_REF_MATCH_N: C800.2 R1080.1 U13.46
LTC6952_1_REF_MATCH_P: C800.1 R1077.1 U13.45
LTC6952_1_Temp: R395.2 U12.49 | length 2.7
  L16 w0.12: U12.49@96.597,332.811 97.707,332.811 98.742,331.775 v1(98.743,331.686)
LTC6952_1_VCO_N: C334.2 R80.2 R532.2 U12.37 | length 13.4
  L1 w0.081: v13@102.159,340.234 103.77,340.234 R532.2@103.947,340.411 ; R532.2@103.797,340.411 C334.2@103.797,341.739
  L12 (Sign) w0.073: v13(94.395,339.42) ccw(c94.395,339.622) 94.598,339.622 94.598,339.691 cw(c94.945,339.691) 94.945,340.039 101.965,340.039 ccw(c101.965,340.195) v13(102.121,340.195)
  L16 w0.1: v13(94.395,339.42) 94.395,337.861 cw(c94.395,337.809) 94.447,337.809 U12.37@94.447,337.461
LTC6952_1_VCO_P: R80.1 R533.1 U12.38 | length 11.7
  L1 w0.081: v13@102.159,339.648 103.731,339.648 R533.1@103.947,339.432
  L12 (Sign) w0.073: v13(94.999,339.42) cw(c94.999,339.622) 94.797,339.622 94.797,339.691 cw(c94.945,339.691) 94.945,339.839 101.968,339.839 cw(c101.968,339.687) v13(102.121,339.687)
  L16 w0.1: U12.38@94.947,337.461 94.947,337.809 cw(c94.999,337.809) 94.999,337.861 v13(94.999,339.42)
LTC6952_2_Temp: R398.2 U13.49
LTC6952_3_Temp: R506.2
MainExpReset: R1002.1 T1.3 U35_I2C_Expander_Main_Rst.14
MIO_0: R768.2 U1.H17 | length 20.5
  L1 w0.116: v5(168.909,305.027) U1.H17@169.397,304.539
  L12 (Sign) w0.12: 155.148,297.394 156.832,297.394 158.534,299.095 158.534,302.273 162.522,306.26 166.476,306.26 167.709,305.027 v5(168.909,305.027)
MIO_1: R769.2 U1.A20 | length 51.2
  L1 w0.12: R769.2@118.827,301.384 v2(119.634,301.384) ; v2(140.637,308.925) 140.654,308.908 142.32,308.908 144.635,311.223 146.298,311.223 147.883,312.807 153.221,312.807 158.489,307.539 U1.A20@162.397,307.539
  L3 (Sign) w0.12: v2(119.634,301.384) 121.285,301.384 123.046,303.145 123.046,304.204 127.901,309.059 138.374,309.059 138.505,308.928 138.518,308.942 140.62,308.942 v2(140.637,308.925)
MIO_2: R770.2 U1.B19 | length 52.9
  L1 w0.116: 162.909,307.027 U1.B19@163.397,306.539
  L1 w0.12: R770.2@118.827,300.406 v2(119.659,300.406) ; v2(140.319,308.607) 140.336,308.59 142.334,308.59 144.747,311.003 146.411,311.003 147.98,312.572 153.124,312.572 158.669,307.027 162.909,307.027
  L3 (Sign) w0.12: v2(119.659,300.406) 120.618,300.406 123.266,303.054 123.266,304.112 127.992,308.839 138.283,308.839 138.515,308.607 v2(140.319,308.607)
MIO_3: R771.2 U1.D19 | length 91.6
  L1 w0.116: U1.D19@165.397,306.539 v2(165.884,307.027)
  L1 w0.2: R771.2@118.827,299.453 v1(119.925,299.453)
  L5 (Sign) w0.2: v1(113.411,291.147) 113.411,291.757 114.63,292.976 115.951,292.976 119.925,296.95 v1(119.925,299.453)
  L3 (Sign) w0.12: v1(113.411,291.147) 113.824,291.147 120.738,284.233 120.742,284.233 121.429,283.547 144.255,283.547 144.668,283.134 145.589,283.134 145.691,283.236 146.548,283.236 147.739,284.427 147.739,286.353 150.646,289.261 150.646,290.06 150.888,290.302 150.888,290.451 150.896,290.46 150.896,290.551 150.905,290.56 150.905,290.651 150.913,290.659 150.913,305.542 153.324,307.952 153.324,307.954 153.564,308.194 153.566,308.194 154.143,308.772 155.853,308.772 157.676,306.949 159.844,306.949 159.849,306.944 162.056,306.944 162.088,306.976 164.139,306.976 164.546,307.383 165.529,307.383 v2(165.884,307.027)
MIO_4: R772.2 U1.J17 | length 92.3
  L1 w0.116: v5(169.909,305.027) U1.J17@170.397,304.539
  L12 (Sign) w0.12: v1(147.565,330.683) 148.572,331.69 152.745,331.69 154.708,329.727 154.708,310.322 158.312,306.718 167.745,306.718 167.771,306.692 168.244,306.692 v5(169.909,305.027)
  L3 (Sign) w0.12: v1(108.969,346.418) 108.969,344.135 120.373,332.731 145.516,332.731 v1(147.565,330.683)
MIO_5: R773.2 U1.C19 | length 86.9
  L1 w0.116: U1.C19@164.397,306.539 v2(164.884,307.027)
  L12 (Sign) w0.12: v1(148.165,330.683) 148.952,331.47 152.654,331.47 154.488,329.636 154.488,310.231 155.99,308.729 155.99,307.433 v1(156.439,306.984)
  L3 (Sign) w0.12: v1(109.569,346.418) 109.569,343.846 120.464,332.951 145.896,332.951 v1(148.165,330.683) ; v1(156.439,306.984) 156.694,306.729 159.753,306.729 159.758,306.724 162.147,306.724 162.163,306.74 164.598,306.74 v2(164.884,307.027)
MIO_6: R774.2 U1.D20 | length 146.1
  L1 w0.116: v2(164.909,308.027) U1.D20@165.397,307.539
  L1 w0.12: R774.2@62.705,333.235 62.715,333.245 v2(63.602,333.245)
  L3 (Sign) w0.12: v2(63.602,333.245) 63.833,333.245 63.995,333.083 63.995,332.27 64.668,331.597 67.898,331.597 103.716,295.779 109.357,295.779 112.846,292.291 113.303,292.291 120.92,284.673 120.925,284.673 121.611,283.987 144.438,283.987 144.85,283.574 145.407,283.574 145.509,283.676 146.365,283.676 147.299,284.61 147.299,286.536 150.206,289.443 150.206,290.243 150.448,290.484 150.448,290.656 150.456,290.664 150.456,290.756 150.465,290.764 150.465,290.855 150.473,290.863 150.473,305.724 152.884,308.135 152.884,308.137 153.381,308.634 153.383,308.634 153.961,309.212 156.036,309.212 157.858,307.389 160.026,307.389 160.032,307.384 161.873,307.384 161.906,307.416 163.957,307.416 164.568,308.027 v2(164.909,308.027)
MIO_7: R775.2 U1.E19 | length 147.3
  L1 w0.116: U1.E19@166.397,306.539 v2(166.884,307.027)
  L1 w0.12: R775.2@62.629,331.864 63.223,331.864 63.316,331.771 v2(63.995,331.771)
  L3 (Sign) w0.12: v2(63.995,331.771) 64.177,331.771 64.579,331.368 67.809,331.368 103.623,295.554 109.271,295.554 112.755,292.071 113.212,292.071 120.829,284.453 120.834,284.453 121.52,283.767 144.346,283.767 144.759,283.354 145.498,283.354 145.6,283.456 146.456,283.456 147.519,284.518 147.519,286.445 150.426,289.352 150.426,290.151 150.668,290.393 150.668,290.565 150.676,290.573 150.676,290.664 150.685,290.673 150.685,290.764 150.693,290.772 150.693,305.633 153.104,308.044 153.104,308.045 153.473,308.414 153.474,308.414 154.052,308.992 155.945,308.992 157.767,307.169 159.935,307.169 159.94,307.164 161.964,307.164 161.997,307.196 164.048,307.196 164.455,307.603 166.309,307.603 v2(166.884,307.027)
MIO_8: R776.2 U1.E20 | length 188.4
  L1 w0.116: v2(165.909,308.027) U1.E20@166.397,307.539
  L1 w0.2: v2(145.098,283.972) 145.34,283.731 145.78,283.731 146.54,282.971 v2(146.54,278.575) ; v2(218.465,190.809) R776.2@220.267,190.809
  L5 (Sign) w0.2: v11(193.901,243.403) 194.439,242.865 194.863,242.865 197.305,240.424 199.017,240.424 200.251,239.19 v11(200.251,239.154)
  L3 (Sign) w0.12: v2(145.098,283.972) 145.276,283.794 145.316,283.794 145.418,283.896 146.274,283.896 147.079,284.701 147.079,286.627 149.986,289.534 149.986,290.334 150.228,290.575 150.228,290.747 150.236,290.756 150.236,290.847 150.245,290.855 150.245,290.946 150.253,290.954 150.253,305.817 153.29,308.854 153.292,308.854 153.87,309.432 156.127,309.432 157.95,307.609 160.117,307.609 160.123,307.604 161.782,307.604 161.819,307.641 163.05,307.641 163.771,308.362 164.048,308.362 164.058,308.352 164.761,308.352 164.771,308.362 165.048,308.362 165.058,308.352 165.584,308.352 v2(165.909,308.027)
  L3 (Sign) w0.2: v2(146.54,278.575) 146.54,278.463 147.48,277.523 147.48,273.813 148.049,273.244 148.049,271.146 148.271,270.924 148.271,269.714 148.271,265.061 163.227,250.104 166.987,250.104 175.38,241.711 190.637,241.711 192.354,243.428 193.875,243.428 v11(193.901,243.403) ; v11(200.251,239.154) 200.251,239.19 200.946,239.885 202.156,239.885 215.938,226.103 215.938,200.437 217.538,198.836 217.538,191.736 v2(218.465,190.809)
MIO_9: R777.2 U1.F20 | length 188.7
  L1 w0.116: v2(166.909,308.027) U1.F20@167.397,307.539
  L1 w0.2: v2(145.78,284.277) 146.99,283.067 v2(146.99,278.575) ; v2(218.465,189.856) R777.2@220.268,189.856
  L5 (Sign) w0.2: v11(194.325,243.827) 197.429,240.724 199.317,240.724 200.85,239.19 v11(200.85,239.154)
  L3 (Sign) w0.12: v2(145.78,284.277) 146.247,284.277 146.859,284.889 146.859,286.718 149.766,289.625 149.766,290.425 150.008,290.667 150.008,290.838 150.016,290.847 150.016,290.938 150.025,290.946 150.025,305.9 153.199,309.074 153.201,309.074 153.779,309.652 156.218,309.652 158.041,307.829 160.208,307.829 160.214,307.824 161.691,307.824 161.728,307.861 162.958,307.861 163.68,308.582 164.139,308.582 164.149,308.572 164.67,308.572 164.68,308.582 165.139,308.582 165.149,308.572 165.862,308.572 166.407,308.027 v2(166.909,308.027)
  L3 (Sign) w0.2: v2(146.99,278.575) 146.99,278.438 147.78,277.647 147.78,273.937 148.349,273.369 148.349,271.27 148.571,271.048 148.571,269.839 148.571,265.185 163.352,250.404 167.111,250.404 175.504,242.011 190.513,242.011 192.354,243.853 194.3,243.853 v11(194.325,243.827) ; v11(200.85,239.154) 200.85,239.268 201.168,239.585 202.032,239.585 215.638,225.979 215.638,200.312 217.238,198.712 217.238,191.612 217.386,191.464 217.386,190.936 v2(218.465,189.856)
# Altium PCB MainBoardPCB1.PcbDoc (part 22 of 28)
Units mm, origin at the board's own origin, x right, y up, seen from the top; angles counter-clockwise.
Board outline 258.95 x 308.86 mm, 16 copper layers (L1, L2 (GND), L3 (Sign), L4 (GND), L5 (Sign), L6 (PWR/GND), L7(PWR/GND), L8 (Plane_GND), L9 (PWR/GND), L10 (PWR/GND), L11 (PWR/GND), L12 (Sign), L13 (GND), L14 (Sign), L15 (GND), L16), stack 2.502 mm thick; 2397 components, 1744 nets, 8397 pads, 4112 vias.
Unrouted connection lines stored in the file: 3547.

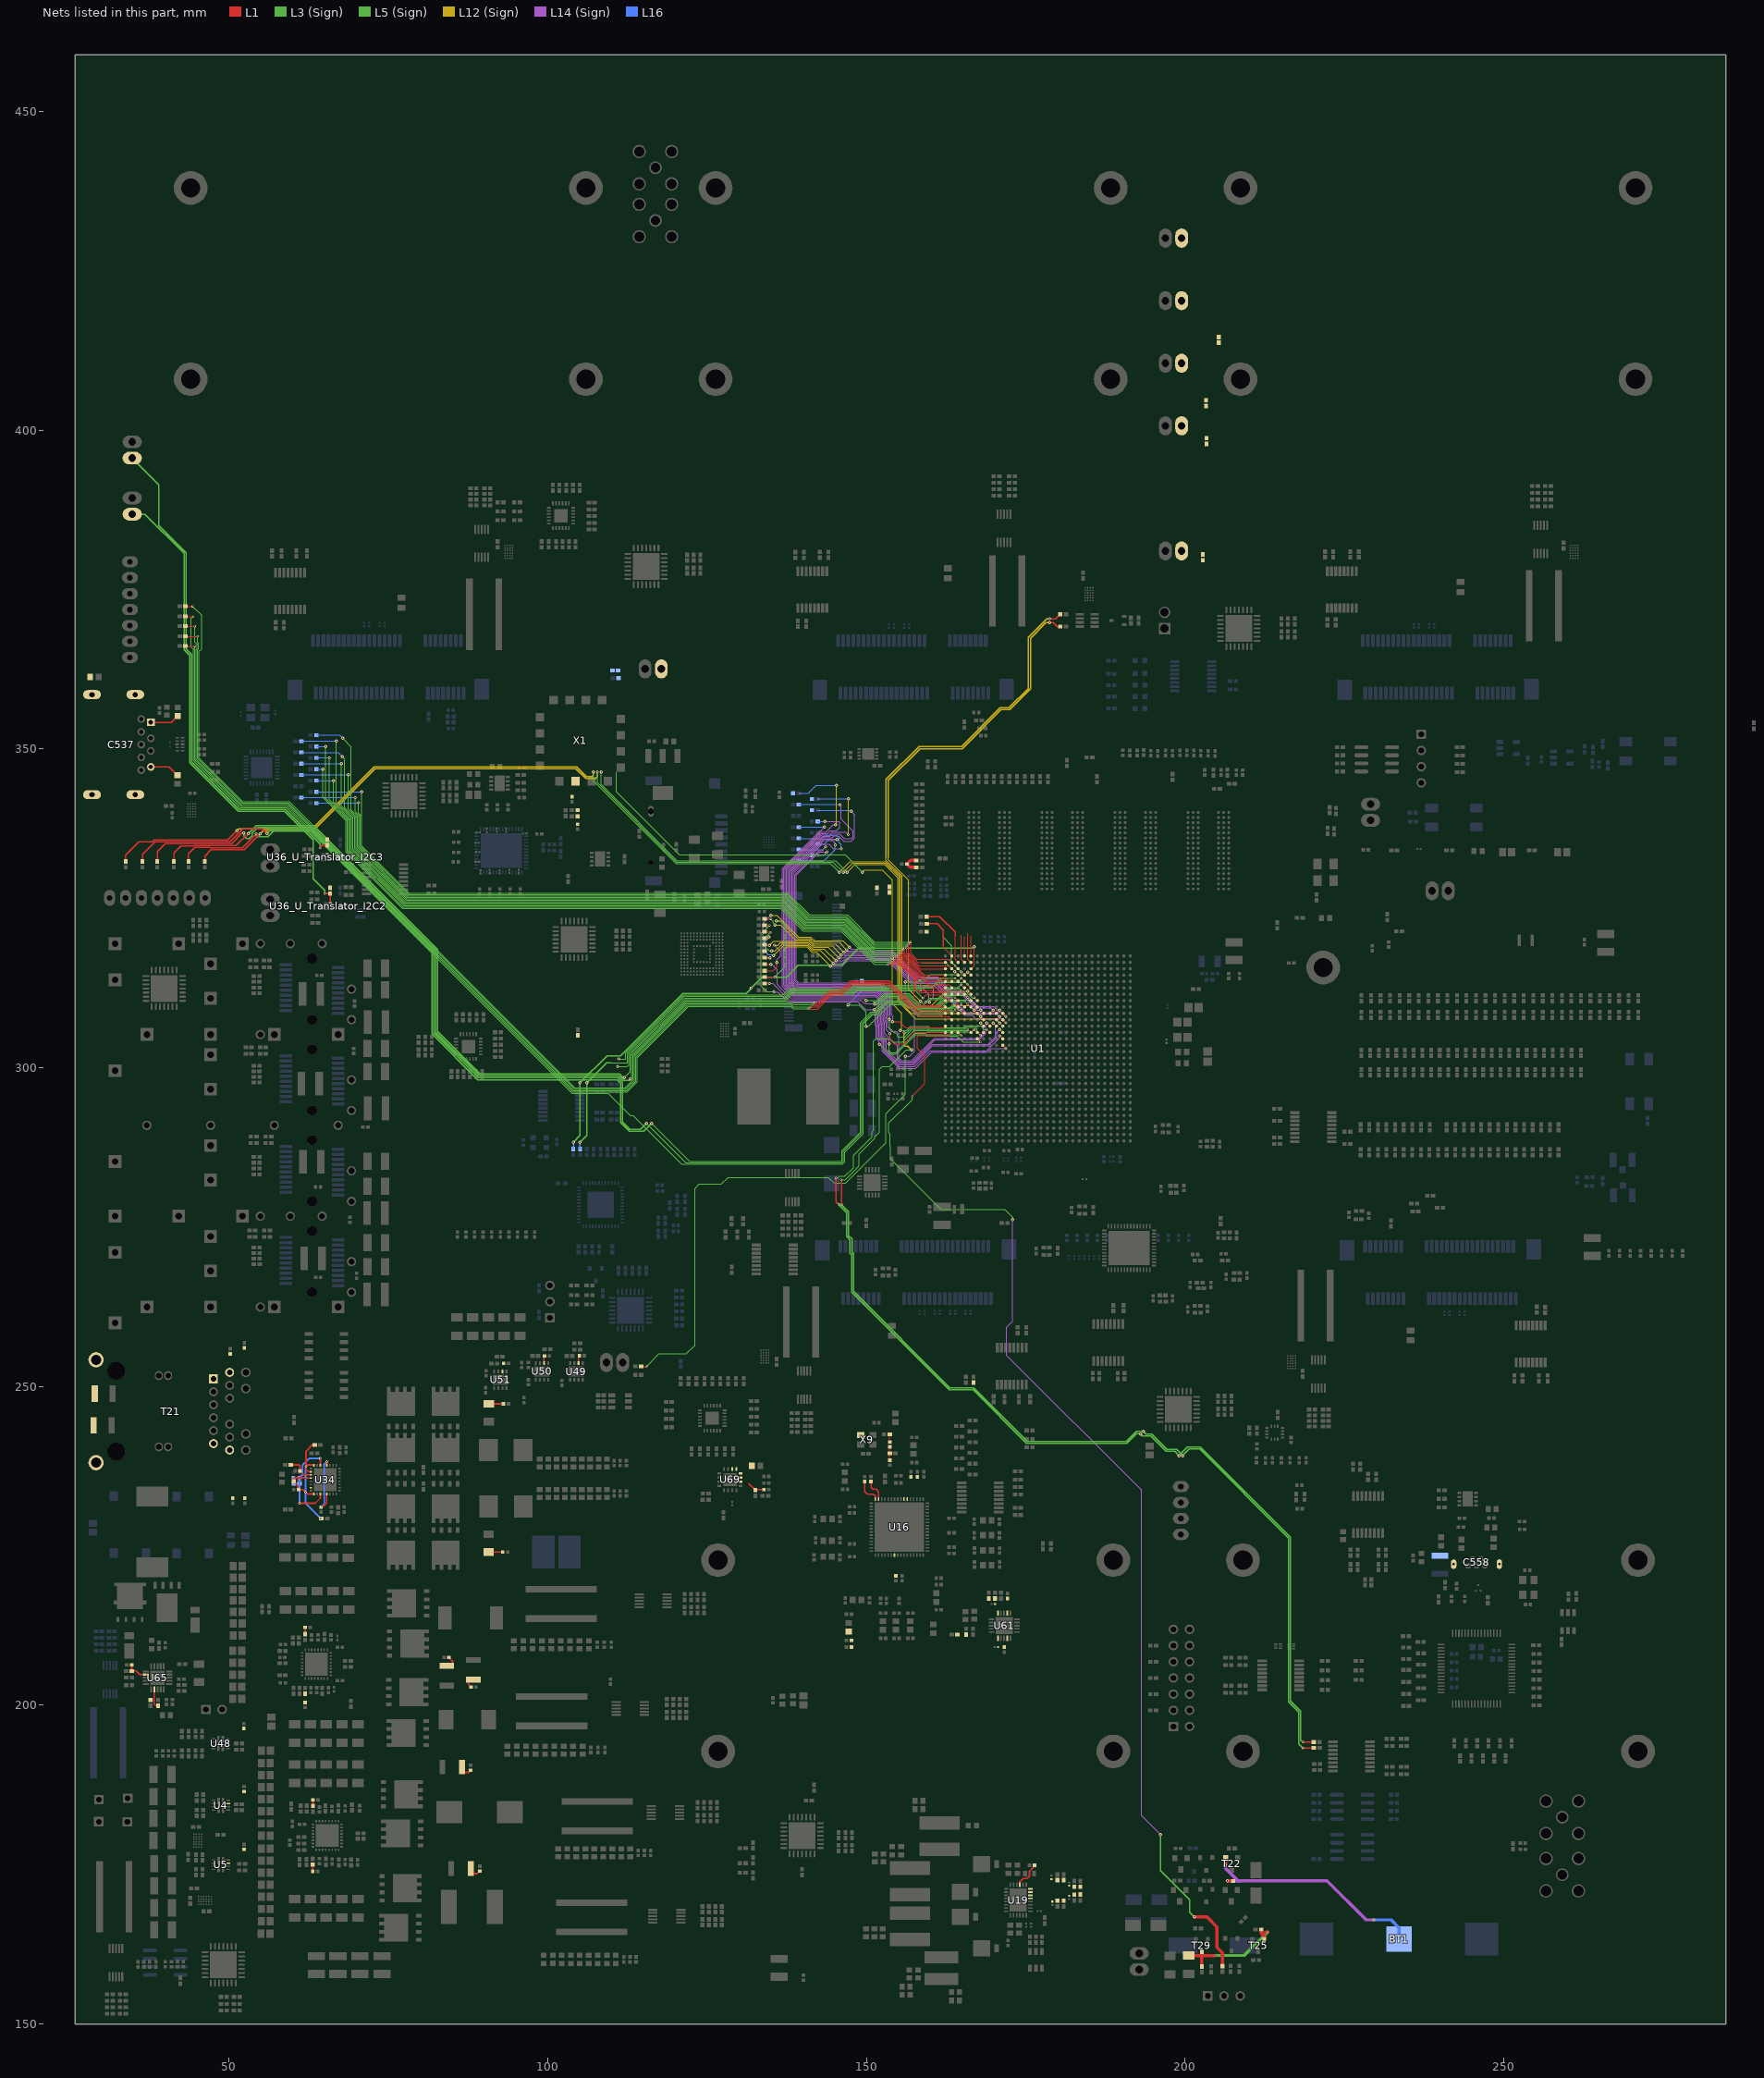
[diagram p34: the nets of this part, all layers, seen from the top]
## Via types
v1: diameter 0.5, hole 0.2, L1 to L16, tented both sides, 1457 vias
v2: diameter 0.35/0/0.35 (per signal layer), hole 0.127, L1 to L3 (Sign), tented both sides, 479 vias
v3: diameter 0.5/0.35/0.35/0.35/0.35/0.35/0.35/0.35/0.35/0.35/0.35/0.35/0.35/0.35/0.35/0.5 (per signal layer), hole 0.15, L1 to L16, tented both sides, 453 vias
v4: diameter 0.5, hole 0.2, L1 to L16, 451 vias
v5: diameter 0.5/0.35/0.35/0.35/0.35/0.35/0.35/0.35/0.35/0.35/0.35/0.35/0.35/0.35/0.35/0.5 (per signal layer), hole 0.2, L1 to L16, tented both sides, 373 vias
v6: diameter 0.8, hole 0.4, L1 to L16, tented both sides, 168 vias
v7: diameter 0.35/0/0.35 (per signal layer), hole 0.127, L1 to L3 (Sign), 138 vias
v8: diameter 2.54, hole 1.02, L1 to L16, 113 vias
v9: diameter 0.5/0/0.5 (per signal layer), hole 0.2, L14 (Sign) to L16, tented both sides, 102 vias
v10: diameter 1.4, hole 0.5, L1 to L16, tented both sides, 80 vias
v11: diameter 0.5, hole 0.2, L3 (Sign) to L6 (PWR/GND), tented both sides, 54 vias
v12: diameter 0.35, hole 0.127, L1 to L2 (GND), tented both sides, 47 vias
v13: diameter 0.4, hole 0.2, L1 to L16, tented both sides, 46 vias
v14: diameter 0.35, hole 0.127, L1 to L16, tented both sides, 16 vias
v15: diameter 0.25, hole 0.2, L1 to L16, 16 vias
v16: diameter 0.5, hole 0.2, L11 (PWR/GND) to L14 (Sign), tented both sides, 16 vias
v17: diameter 0.4, hole 0.2, L1 to L16, 16 vias
v18: diameter 0.3, hole 0.2, L1 to L16, 15 vias
v19: diameter 0.45, hole 0.15, L1 to L16, 12 vias
v20: diameter 0.5/0.35/0.35/0.35/0.35/0.35/0.35/0.35/0.35/0.35/0.35/0.35/0.35/0.35/0.35/0.45 (per signal layer), hole 0.15, L1 to L16, tented both sides, 10 vias
v21: diameter 0.2/0/0.2 (per signal layer), hole 0.1, L1 to L3 (Sign), tented both sides, 9 vias
v22: diameter 0.3, hole 0.127, L14 (Sign) to L16, tented both sides, 8 vias
v23: diameter 0.4, hole 0.1, L1 to L16, 7 vias
v24: diameter 1.15, hole 1.15, L1 to L16, 5 vias
v25: diameter 1.65, hole 1.65, L1 to L16, 5 vias
v26: diameter 0.2, hole 0.1, L1 to L16, 4 vias
v27: diameter 0.4, hole 0.15, L1 to L16, 2 vias
v28: diameter 0.5/0.35/0.35/0.35/0.35/0.35/0.35/0.35/0.35/0.35/0.35/0.35/0.35/0.35/0.35/0.5 (per signal layer), hole 0.15, L1 to L16, 2 vias
v29: diameter 0.35, hole 0.127, L3 (Sign) to L6 (PWR/GND), tented both sides, 2 vias
v30: diameter 0.3, hole 0.127, L15 (GND) to L16, tented both sides, 1 vias
v31: diameter 0.35, hole 0.127, L1 to L2 (GND), 1 vias
v32: diameter 0.5/0.35/0.35/0.35/0.35/0.35/0.35/0.35/0.35/0.35/0.35/0.35/0.35/0.35/0.35/0.5 (per signal layer), hole 0.2, L1 to L16, 1 vias
v33: diameter 0.35/0.35/0.35 (per signal layer), hole 0.127, L1 to L3 (Sign), tented both sides, 1 vias
v34: diameter 0.45/0/0.45 (per signal layer), hole 0.15, L1 to L3 (Sign), tented both sides, 1 vias
v35: diameter 0.45/0/0.45 (per signal layer), hole 0.2, L14 (Sign) to L16, tented both sides, 1 vias

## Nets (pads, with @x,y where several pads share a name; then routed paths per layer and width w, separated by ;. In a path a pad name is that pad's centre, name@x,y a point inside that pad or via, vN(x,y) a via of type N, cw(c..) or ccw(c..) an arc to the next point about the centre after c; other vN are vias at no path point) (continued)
MIO_10: R778.2 U1.F18 | length 183.2
  L1 w0.116: v2(166.909,306.027) U1.F18@167.397,305.539
  L1 w0.2: v2(145.237,282.727) 145.237,278.977 v2(145.64,278.575) ; v2(218.465,194.229) R778.2@220.214,194.229
  L5 (Sign) w0.2: v11(193.053,242.554) 193.342,242.265 194.614,242.265 197.056,239.824 198.381,239.824 v11(199.051,239.154)
  L3 (Sign) w0.12: v2(145.237,282.727) 145.494,282.727 145.782,283.016 146.639,283.016 147.959,284.336 147.959,286.262 150.866,289.169 150.866,289.969 151.108,290.211 151.108,290.36 151.116,290.369 151.116,290.46 151.125,290.469 151.125,290.56 151.133,290.567 151.133,304.206 151.511,304.584 153.67,304.584 154.197,304.057 155.669,304.057 157.461,305.849 159.388,305.849 159.394,305.844 159.441,305.844 159.639,305.646 166.529,305.646 v2(166.909,306.027)
  L3 (Sign) w0.2: v2(145.64,278.575) 145.64,278.534 145.715,278.459 145.715,278.419 146.512,277.622 146.533,277.622 146.88,277.274 146.88,273.551 147.439,272.992 147.439,270.907 147.671,270.675 147.671,269.466 147.671,264.812 162.979,249.504 166.738,249.504 175.131,241.111 190.885,241.111 192.381,242.607 193,242.607 v11(193.053,242.554) ; v11(199.051,239.154) 199.051,239.19 200.356,240.495 202.408,240.495 216.548,226.356 216.548,200.689 218.148,199.089 218.148,194.546 v2(218.465,194.229)
MIO_11: R779.2 U1.G18 | length 184.8
  L1 w0.116: v2(167.909,305.052) U1.G18@168.397,305.539
  L1 w0.2: v2(146.012,282.461) 146.102,282.37 v2(146.102,278.6) ; v2(218.465,193.302) R779.2@220.218,193.302
  L5 (Sign) w0.2: v11(193.477,242.978) 193.89,242.565 194.739,242.565 197.18,240.124 198.717,240.124 199.651,239.19 v11(199.651,239.154)
  L12 (Sign) w0.2: v1(155.931,305.473) 155.931,303.39 156.469,303.39 157.074,302.785 v1(157.154,302.785)
  L3 (Sign) w0.12: v2(146.012,282.461) 146.706,282.461 148.839,284.594 148.839,286.52 151.306,288.987 151.306,289.161 152.019,289.874 152.019,299.745 152.451,300.177 153.657,300.177 156.265,302.785 v1(157.154,302.785) v1@156.997,302.628 ; v1(155.931,305.473) 156.235,305.473 157.052,306.289 159.57,306.289 159.576,306.284 159.624,306.284 159.821,306.086 164.912,306.086 165.496,306.087 165.771,306.362 167.048,306.362 167.348,306.062 167.348,305.614 v2(167.909,305.052)
  L3 (Sign) w0.2: v2(146.102,278.6) 146.09,278.489 147.18,277.399 147.18,273.682 147.744,273.118 147.744,271.026 147.971,270.799 147.971,269.59 147.971,264.937 163.103,249.804 166.863,249.804 175.256,241.411 190.761,241.411 192.354,243.004 193.451,243.004 v11(193.477,242.978) ; v11(199.651,239.154) 199.651,239.19 200.651,240.19 202.282,240.19 216.243,226.23 216.243,200.563 217.843,198.963 217.843,193.924 v2(218.465,193.302)
MIO_12: R780.2 U1.H18 | length 91.8
  L1 w0.116: v2(168.909,306.027) U1.H18@169.397,305.539
  L12 (Sign) w0.12: v1(149.365,330.683) 149.365,330.733 149.661,331.03 152.472,331.03 154.048,329.454 154.048,310.049 155.55,308.547 155.55,306.108 v1(155.308,305.866)
  L3 (Sign) w0.12: 110.769,346.418 110.769,343.268 120.647,333.391 146.656,333.391 v1(149.365,330.683) ; v1(155.308,305.866) 155.325,305.883 156.303,305.883 156.929,306.509 159.662,306.509 159.667,306.504 159.715,306.504 159.907,306.311 165.409,306.311 165.68,306.582 167.139,306.582 167.156,306.565 167.93,306.565 168.469,306.027 v2(168.909,306.027)
MIO_13: R87.1 U1.G19 | length 80.1
  L1 w0.116: v5(167.909,307.027) U1.G19@168.397,306.539
  L14 (Sign) w0.12: v9(146.063,334.366) 144.801,334.366 144.112,335.055 143.081,335.055 138.577,330.551 138.577,313.505 139.195,312.887 152.201,312.887 153.485,311.603 153.485,308.304 153.324,308.143 153.324,307.929 153.133,307.738 153.133,307.399 153.324,307.208 153.324,306.34 153.937,305.727 154.724,305.727 155.118,305.333 155.118,301.498 155.461,301.155 157.157,301.155 160.65,304.648 167.64,304.648 168.351,305.359 168.351,306.585 v5(167.909,307.027)
  L16 w0.12: R87.1@139.395,335.989 143.088,335.989 143.548,336.448 145.339,336.448 145.774,336.013 145.774,335.34 146.063,335.051 v9(146.063,334.366)
MIO_14: R88.1 U1.E18 | length 63.4
  L1 w0.116: v2(165.909,306.027) U1.E18@166.397,305.539
  L3 (Sign) w0.12: v1(153.543,307.569) 153.64,307.569 153.733,307.475 153.654,307.396 153.654,306.213 154.372,305.495 154.615,305.495 154.855,305.255 154.855,305.012 155.004,304.863 156.007,304.863 157.213,306.069 159.479,306.069 159.485,306.064 159.533,306.064 159.73,305.866 165.003,305.866 165.749,305.867 v2(165.909,306.027)
  L14 (Sign) w0.12: v9(143.599,334.645) 143.027,334.073 142.551,334.073 138.797,330.319 138.797,313.596 139.286,313.107 152.293,313.107 153.705,311.694 153.705,307.813 153.543,307.651 v1(153.543,307.569)
  L16 w0.12: R88.1@139.395,334.231 143.185,334.231 v9(143.599,334.645)
MIO_15: R89.1 U1.J19 | length 90.6
  L1 w0.116: v5(169.909,307.027) U1.J19@170.397,306.539
  L14 (Sign) w0.12: v9(145.847,341.224) 146.012,341.058 146.012,338.988 147.913,337.087 147.913,336.165 147.676,335.928 146.558,335.928 145.783,336.702 144.678,336.702 144.301,336.325 143.106,336.325 137.697,330.916 137.697,313.14 138.83,312.007 151.837,312.007 152.605,311.239 152.605,308.669 152.444,308.507 152.444,308.293 152.253,308.103 152.253,307.034 152.444,306.844 152.444,304.991 153.14,304.295 153.14,302.854 155.278,300.715 157.339,300.715 160.311,303.686 169.111,303.686 170.282,304.857 170.282,306.655 v5(169.909,307.027)
  L16 w0.12: R89.1@139.375,341.312 145.758,341.312 v9(145.847,341.224)
MIO_16: R90.1 U1.K17 | length 80.5
  L1 w0.116: v5(170.909,305.027) U1.K17@171.397,304.539
  L14 (Sign) w0.12: v9(143.51,338.658) 145.669,338.658 145.809,338.518 145.809,337.693 145.283,337.168 144.305,337.168 143.902,336.765 142.924,336.765 137.257,331.098 137.257,312.958 138.648,311.567 151.655,311.567 152.165,311.057 152.165,308.851 152.004,308.69 152.004,308.476 151.813,308.285 151.813,306.852 152.004,306.662 152.004,304.809 152.7,304.113 152.7,302.659 155.171,300.188 157.558,300.188 160.037,302.666 168.872,302.666 170.909,304.704 v5(170.909,305.027)
  L16 w0.12: R90.1@142.361,338.645 143.497,338.645 v9(143.51,338.658)
MIO_17: R91.2 U1.C18 | length 78.9
  L1 w0.116: U1.C18@164.397,305.539 v2(164.884,305.052)
  L3 (Sign) w0.12: v1(153.568,303.746) 153.568,302.698 153.892,302.374 154.246,302.374 154.608,302.374 157.644,305.409 159.206,305.409 159.409,305.206 164.73,305.206 v2(164.884,305.052)
  L14 (Sign) w0.12: v9(147.625,340.246) 148.133,339.738 148.133,336.017 147.612,335.496 146.444,335.496 145.567,336.372 144.932,336.372 144.665,336.105 143.197,336.105 137.917,330.825 137.917,313.231 138.922,312.227 151.928,312.227 152.825,311.33 152.825,308.578 152.664,308.416 152.664,308.202 152.473,308.012 152.473,307.125 152.664,306.935 152.664,305.315 152.664,305.133 153.568,304.228 v1(153.568,303.746)
  L16 w0.12: 142.361,340.411 147.46,340.411 v9(147.625,340.246)
MIO_18: R92.2 U1.K18 | length 87.8
  L1 w0.116: v5(170.909,306.027) U1.K18@171.397,305.539
  L12 (Sign) w0.12: v16(147.158,336.575) 147.18,336.553 v1(147.18,342.189)
  L14 (Sign) w0.12: v16(147.158,336.575) 146.785,336.948 144.613,336.948 144.21,336.545 143.015,336.545 137.477,331.007 137.477,313.049 138.739,311.787 151.746,311.787 152.385,311.148 152.385,308.76 152.224,308.599 152.224,308.385 152.033,308.194 152.033,306.943 152.224,306.753 152.224,304.9 152.92,304.204 152.92,302.75 155.185,300.485 157.435,300.485 160.417,303.466 169.202,303.466 170.502,304.766 170.502,305.619 v5(170.909,306.027)
  L16 w0.12: 142.361,342.176 147.168,342.176 v1(147.18,342.189)
MIO_19: R93.2 U1.K16 | length 89.1
  L1 w0.116: U1.K16@171.397,303.539 v5(171.884,303.052)
  L12 (Sign) w0.12: v16(145.174,338.15) 145.326,338.303 v1(145.326,344.297)
  L14 (Sign) w0.12: v16(145.174,338.15) 144.802,338.15 143.637,336.985 142.833,336.985 137.037,331.189 137.037,312.867 138.557,311.347 151.564,311.347 151.945,310.965 151.945,308.942 151.784,308.781 151.784,308.567 151.593,308.376 151.593,306.761 151.784,306.57 151.784,304.718 152.48,304.022 152.48,302.568 155.144,299.903 157.676,299.903 160.219,302.446 168.995,302.446 169.6,303.052 v5(171.884,303.052)
  L16 w0.12: 139.395,343.065 140.894,343.065 142.126,344.297 v1(145.326,344.297)
MIO_20: R94.2 U1.A19 | length 53.8
  L1 w0.12: v1(154.064,307.226) 155.158,307.226 156.124,306.26 162.118,306.26 U1.A19@162.397,306.539
  L14 (Sign) w0.12: v9(143.815,333.832) 142.621,333.832 139.017,330.228 139.017,313.687 139.377,313.327 152.384,313.327 153.925,311.786 153.925,308.304 154.178,308.051 154.178,307.492 154.064,307.378 v1(154.064,307.226)
  L16 w0.12: 142.361,333.35 143.332,333.35 v9(143.815,333.832) ; v1@154.064,307.175 v1(154.064,307.226)
MIO_21: R95.1 U1.H19 | length 75.1
  L1 w0.116: v5(168.909,307.027) U1.H19@169.397,306.539
  L14 (Sign) w0.12: v9(145.364,335.804) 145.084,335.804 145.004,335.885 143.288,335.885 138.137,330.733 138.137,313.322 139.013,312.447 152.019,312.447 153.045,311.421 153.045,308.487 152.884,308.325 152.884,308.111 152.693,307.921 152.693,307.217 152.884,307.026 152.884,305.847 152.884,305.406 154.898,303.391 154.898,301.407 155.37,300.935 157.248,300.935 160.741,304.428 167.731,304.428 168.571,305.268 168.571,305.274 168.747,305.45 168.747,306.694 168.909,306.857 v5(168.909,307.027)
  L16 w0.12: R95.1@142.361,335.115 143.383,335.115 144.073,335.804 v9(145.364,335.804)
MIO_22: R96.1 U1.F17 | length 74.1
  L1 w0.116: U1.F17@167.397,304.539 v2(167.884,304.052)
  L3 (Sign) w0.12: v1(152.07,303.682) 153.606,302.146 154.691,302.146 157.735,305.189 159.115,305.189 159.321,304.983 164.256,304.983 165.188,304.052 v2(167.884,304.052)
  L14 (Sign) w0.12: v9(143.45,337.753) 142.902,337.205 142.742,337.205 136.817,331.28 136.817,312.776 138.466,311.127 151.472,311.127 151.725,310.874 151.725,309.033 151.564,308.872 151.564,308.658 151.373,308.467 151.373,306.67 151.564,306.479 151.564,304.627 152.004,304.187 152.004,303.749 v1(152.07,303.682)
  L16 w0.12: R96.1@139.395,337.753 v9(143.45,337.753)
MIO_23: R781.2 U1.K19 | length 93.1
  L1 w0.116: v5(170.909,307.027) U1.K19@171.397,306.539
  L12 (Sign) w0.12: v1(146.965,330.683) 148.192,331.91 152.836,331.91 154.928,329.818 154.928,310.413 157.685,307.656 170.28,307.656 v5(170.909,307.027)
  L3 (Sign) w0.12: v1(108.369,346.418) 108.369,344.424 120.282,332.511 145.136,332.511 v1(146.965,330.683)
MIO_24: R782.2 U1.A18 | length 66.7
  L1 w0.12: v1(153.683,305.359) 153.683,304.419 154.343,303.759 155.867,303.759 157.648,305.539 U1.A18@162.397,305.539
  L14 (Sign) w0.12: v9(145.123,334.95) 145.123,335.204 144.662,335.665 143.38,335.665 138.357,330.642 138.357,313.413 139.104,312.667 152.11,312.667 153.265,311.512 153.265,308.395 153.104,308.234 153.104,308.02 152.913,307.83 152.913,307.308 153.104,307.117 153.104,306.249 153.104,305.938 v1(153.683,305.359)
  L16 w0.12: R782.2@139.395,332.473 143.345,332.473 145.123,334.251 v9(145.123,334.95)
MIO_25: R783.2 U1.B18 | length 183.8
  L1 w0.12: v2(157.201,295.529) 159.165,297.494 159.165,301.895 158.019,303.042 158.019,304.882 158.182,305.045 162.902,305.045 U1.B18@163.397,305.539
  L1 w0.5: v1(201.471,166.789) 203.441,166.789 204.995,165.235 204.995,162.051 205.867,161.18 R783.2@205.867,159.099
  L5 (Sign) w0.2: v1(196.162,179.692) 196.162,174.066 197.184,173.045 200.753,169.475 200.753,167.507 v1(201.471,166.789)
  L3 (Sign) w0.12: v2(157.201,295.529) 157.201,295.001 153.526,291.327 153.526,289.862 153.748,289.641 153.748,287.73 153.756,287.721 153.756,285.721 161.667,277.81 171.732,277.81 172.961,276.581 v1(172.961,276.161)
  L14 (Sign) w0.12: v1(172.961,276.161) 172.961,260.23 172.009,259.278 172.009,254.889 193.154,233.743 193.154,182.7 195.578,180.276 v1(196.162,179.692)
MIO_26: R784.2 U1.B20 | length 171.5
  L1 w0.116: 162.909,308.027 U1.B20@163.397,307.539
  L1 w0.12: R784.2@43.16,366.145 v2(44.628,366.145) ; v2(140.955,309.243) 140.972,309.226 142.323,309.226 144.539,311.443 146.184,311.443 146.21,311.469 146.22,311.469 146.274,311.522 146.283,311.522 147.791,313.03 153.314,313.03 158.317,308.027 162.909,308.027
  L3 (Sign) w0.12: v2(44.628,366.145) 44.628,365.758 44.611,365.741 44.611,348.41 44.615,348.405 44.615,348.292 51.822,341.086 51.859,341.086 51.866,341.078 51.943,341.078 51.949,341.072 59.13,341.072 103.975,296.227 112.43,296.227 113.379,297.177 113.399,297.177 114.025,297.804 114.025,301.593 122.084,309.651 138.093,309.651 138.503,309.241 138.521,309.26 140.938,309.26 v2(140.955,309.243)
MIO_27: R785.2 U1.B21 | length 172.5
  L1 w0.116: 162.909,309.027 U1.B21@163.397,308.539
  L1 w0.12: R785.2@43.176,367.69 v2(45.034,367.69) ; v2(141.592,309.879) 141.636,309.835 141.938,309.835 142.012,309.762 142.228,309.762 144.348,311.883 146.001,311.883 146.027,311.909 146.038,311.909 147.606,313.476 153.498,313.476 157.948,309.027 162.909,309.027
  L3 (Sign) w0.12: v2(45.034,367.69) 45.034,366.688 45.183,366.54 45.183,365.69 45.055,365.563 45.055,348.474 52.004,341.526 52.041,341.526 52.049,341.518 59.315,341.518 104.16,296.673 112.253,296.673 113.197,297.617 113.216,297.617 113.585,297.986 113.585,301.775 121.902,310.091 138.275,310.091 138.498,309.868 138.527,309.896 141.575,309.896 v2(141.592,309.879)
MIO_28: R786.2 U1.A21 | length 173
  L1 w0.12: R786.2@43.175,369.252 v2(44.602,369.252) ; v2(141.273,309.561) 141.293,309.542 142.321,309.542 144.442,311.663 146.093,311.663 146.119,311.689 146.129,311.689 146.183,311.742 146.185,311.742 147.698,313.255 153.407,313.255 158.122,308.539 U1.A21@162.397,308.539
  L3 (Sign) w0.12: v2(44.602,369.252) 44.602,366.809 44.963,366.448 44.963,365.781 44.831,365.65 44.831,348.501 44.835,348.496 44.835,348.383 51.913,341.306 51.95,341.306 51.958,341.298 52.034,341.298 52.035,341.297 59.223,341.297 104.068,296.452 112.343,296.452 113.288,297.397 113.308,297.397 113.805,297.895 113.805,301.684 121.993,309.871 138.184,309.871 138.499,309.556 138.522,309.578 141.257,309.578 v2(141.273,309.561)
MIO_29: R787.2 U1.D21 | length 194.4
  L1 w0.116: v2(164.909,309.027) U1.D21@165.397,308.539
  L1 w0.12: R787.2@43.16,370.828 43.186,370.802 v2(44.374,370.802)
  L3 (Sign) w0.12: v2(44.374,370.802) 44.069,370.497 44.069,365.999 44.391,365.677 44.391,348.318 44.395,348.314 44.395,348.201 44.552,348.045 44.552,348.005 51.719,340.838 58.971,340.838 64.393,335.416 64.397,335.416 103.809,296.003 109.457,296.003 112.928,292.532 113.373,292.532 121.011,284.893 146.241,284.893 146.639,285.291 146.639,286.809 149.546,289.716 149.546,306.877 150.962,308.293 151.607,308.293 152.105,308.791 152.105,308.895 153.319,310.109 156.384,310.109 158.223,308.269 160.391,308.269 160.396,308.264 161.509,308.264 162.322,309.077 163.344,309.077 163.686,309.419 164.096,309.419 164.488,309.027 v2(164.909,309.027)
MIO_30: R788.2 U1.C21 | length 27.5
  L1 w0.116: v2(163.909,309.027) U1.C21@164.397,308.539
  L5 (Sign) w0.12: v1(147.104,309.88) 148.858,309.88 149.956,308.782 v11(149.956,306.527)
  L3 (Sign) w0.12: v11(149.956,306.527) 150.34,306.527 153.702,309.889 156.293,309.889 158.132,308.049 160.299,308.049 160.305,308.044 161.6,308.044 162.413,308.857 163.677,308.857 163.847,309.027 v2(163.909,309.027)
  L16 w0.12: v1(147.104,309.88) 147.113,309.88 149.299,312.067 R788.2@149.299,313.665
MIO_31: R789.2 U1.A22 | length 175.4
  L1 w0.12: R789.2@43.16,372.389 v2(44.285,372.389) ; v2(141.91,310.197) 142.126,309.982 144.247,312.103 145.91,312.103 147.512,313.704 153.593,313.704 157.757,309.539 U1.A22@162.397,309.539
  L3 (Sign) w0.12: v2(44.285,372.389) 45.682,370.992 45.682,365.716 45.275,365.309 45.275,348.566 52.095,341.746 59.409,341.746 104.254,296.901 112.17,296.901 113.106,297.837 113.125,297.837 113.365,298.077 113.365,298.346 113.365,301.866 121.811,310.311 138.366,310.311 138.493,310.184 138.523,310.214 141.893,310.214 v2(141.91,310.197)
MIO_32: R790.2 U1.G20 | length 160
  L1 w0.116: v5(167.909,308.027) U1.G20@168.397,307.539
  L1 w0.2: R790.2@46.199,332.365 46.199,333.225 47.2,334.226 52.414,334.226 54.841,336.653 v1(54.841,336.69)
  L12 (Sign) w0.12: v1(146.365,330.683) 147.812,332.13 152.927,332.13 155.148,329.91 155.148,310.504 157.08,308.572 167.364,308.572 v5(167.909,308.027)
  L12 (Sign) w0.2: v1(54.841,336.69) 55.36,337.208 63.167,337.208 72.89,346.931 104.388,346.931 105.959,345.36 107.086,345.36 107.09,345.364 107.48,345.364 107.769,345.653 v1(107.769,346.418)
  L3 (Sign) w0.12: v1(107.769,346.418) 107.769,344.713 120.191,332.291 144.756,332.291 v1(146.365,330.683)
MIO_33: R791.2 U1.C22 | length 180.6
  L1 w0.116: v2(163.909,310.027) U1.C22@164.397,309.539
  L1 w0.2: R791.2@43.646,332.365 43.646,333.575 44.622,334.55 47.033,334.55 47.038,334.545 52.133,334.545 54.241,336.653 v1(54.241,336.69)
  L5 (Sign) w0.2: v1(54.241,336.69) 54.241,336.419 54.42,336.24 56.059,336.24 56.925,337.106 62.879,337.106 81.807,318.177 81.807,305.351 89.029,298.129 110.888,298.129 111.416,297.601 111.416,291.405 112.786,290.035 115.054,290.035 v1(116.294,291.274)
  L3 (Sign) w0.12: v1(116.294,291.274) 122.235,285.333 146.059,285.333 146.199,285.473 146.199,286.991 149.106,289.898 149.106,307.06 150.78,308.733 151.425,308.733 151.665,308.974 151.665,309.077 153.137,310.549 153.145,310.549 153.162,310.566 156.549,310.566 158.405,308.709 160.573,308.709 160.578,308.704 161.327,308.704 162.14,309.517 163.162,309.517 163.672,310.027 v2(163.909,310.027)
MIO_34: R792.2 U1.B24 | length 156.7
  L1 w0.116: 162.909,312.027 U1.B24@163.397,311.539
  L1 w0.12: v2(158.505,312.166) 160.146,312.166 160.286,312.027 162.909,312.027
  L1 w0.2: R792.2@41.335,332.365 41.335,333.689 42.469,334.823 44.47,334.823 44.497,334.85 47.158,334.85 47.162,334.845 51.102,334.845 v1(53.035,336.779)
  L5 (Sign) w0.2: v1(53.035,336.779) 54.262,338.006 63.252,338.006 82.707,318.55 82.707,305.724 89.402,299.029 111.261,299.029 111.815,298.475 v1(112.027,298.475)
  L3 (Sign) w0.12: v1(112.027,298.475) 112.925,299.374 112.925,302.048 113.48,302.603 121.629,310.751 137.2,310.751 138.272,311.824 147.898,311.824 148.414,312.339 158.332,312.339 v2(158.505,312.166)
MIO_35: R793.2 U1.B23 | length 161.9
  L1 w0.116: 162.691,310.959 163.111,310.539 U1.B23@163.397,310.539
  L1 w0.12: v2(158.877,310.965) 159.366,311.455 161.742,311.455 162.237,310.959 162.691,310.959
  L1 w0.2: R793.2@38.731,332.365 38.731,333.894 39.978,335.14 44.363,335.14 44.373,335.15 47.282,335.15 47.287,335.145 50.401,335.145 52.06,336.804 v1(52.324,336.804)
  L5 (Sign) w0.2: v1(52.324,336.804) 52.324,336.36 52.718,335.966 53.149,335.966 53.594,336.41 53.594,336.813 54.486,337.706 63.127,337.706 82.407,318.426 82.407,305.6 89.278,298.729 111.136,298.729 111.84,298.025 112.734,298.025 v11(112.955,298.247)
  L3 (Sign) w0.12: v11(112.955,298.247) 113.145,298.437 113.145,301.957 121.72,310.531 137.291,310.531 138.363,311.604 147.989,311.604 148.505,312.119 157.723,312.119 v2(158.877,310.965)
MIO_36: R794.2 U1.D22 | length 189
  L1 w0.116: v2(164.909,310.027) U1.D22@165.397,309.539
  L1 w0.2: R794.2@36.407,332.365 36.407,333.486 38.367,335.445 44.244,335.445 44.249,335.45 47.406,335.45 47.411,335.445 50.152,335.445 52.172,337.464 55.189,337.464 v1(55.918,336.735)
  L5 (Sign) w0.2: v1(55.918,336.735) 56.589,337.406 63.003,337.406 82.107,318.301 82.107,305.475 89.153,298.429 111.012,298.429 111.716,297.725 111.716,291.529 112.911,290.335 114.567,290.335 v1(115.506,291.274)
  L3 (Sign) w0.12: v1(115.506,291.274) 121.668,285.113 146.15,285.113 146.419,285.382 146.419,286.9 149.326,289.807 149.326,306.968 150.871,308.513 151.516,308.513 151.885,308.882 151.885,308.986 153.228,310.329 153.254,310.329 153.262,310.337 156.466,310.337 158.314,308.489 160.482,308.489 160.487,308.484 161.418,308.484 162.231,309.297 163.253,309.297 163.595,309.639 164.521,309.639 v2(164.909,310.027)
MIO_37: R795.2 U1.F21 | length 171.3
  L1 w0.116: v5(166.909,309.027) U1.F21@167.397,308.539
  L1 w0.2: R795.2@33.766,332.365 33.766,333.384 35.852,335.47 37.968,335.47 38.242,335.745 44.12,335.745 44.125,335.75 47.53,335.75 47.535,335.745 49.792,335.745 v1(51.244,337.198)
  L12 (Sign) w0.12: v1(145.765,330.683) 147.432,332.35 153.019,332.35 155.368,330.001 155.368,310.595 156.599,309.364 160.094,309.364 160.1,309.369 163.326,309.369 163.697,309.74 166.196,309.74 v5(166.909,309.027)
  L12 (Sign) w0.2: v1(51.244,337.198) 51.555,337.508 63.043,337.508 72.766,347.231 104.513,347.231 106.083,345.66 106.961,345.66 107.169,345.868 v1(107.169,346.418)
  L3 (Sign) w0.12: v1(107.169,346.418) 107.169,345.002 120.1,332.071 144.376,332.071 v1(145.765,330.683)
MIO_38: R796.2 U1.C23 | length 15.7
  L1 w0.116: v2(163.909,311.027) U1.C23@164.397,310.539
  L3 (Sign) w0.12: 151.045,310.379 151.868,310.379 152.949,311.459 156.589,311.459 158.679,309.369 160.846,309.369 160.852,309.364 161.053,309.364 162.857,311.167 163.707,311.167 163.847,311.027 v2(163.909,311.027)
MIO_39: R101.1 U1.E22 | length 47.9
  L1 w0.116: v2(165.909,310.027) U1.E22@166.397,309.539
  L1 w0.12: R101.1@134.016,322.351 134.026,322.341 v2(134.788,322.341)
  L3 (Sign) w0.12: v2(134.788,322.341) 133.502,321.056 133.502,312.839 134.383,311.959 v1(135.475,311.959) ; v1(151.255,309.143) 153.131,311.019 156.407,311.019 158.496,308.929 160.664,308.929 160.669,308.924 161.235,308.924 162.767,310.456 165.481,310.456 v2(165.909,310.027)
  L14 (Sign) w0.12: v1(135.475,311.959) 135.475,311.912 136.119,311.912 137.681,310.35 148.673,310.35 149.88,309.143 v1(151.255,309.143)
MIO_40: R102.1 U1.C24 | length 42.1
  L1 w0.116: v2(163.909,312.027) U1.C24@164.397,311.539
  L1 w0.12: R102.1@134.016,320.319 134.556,320.319 v1(134.722,320.484) v1@134.734,320.497
  L12 (Sign) w0.12: v1(135.445,317.627) 135.445,317.589 137.055,319.198 140.722,319.198 141.54,318.38 142.797,318.38 v16(144.787,316.39)
  L3 (Sign) w0.12: v1(159.88,310.261) 159.88,310.515 160.109,310.744 161.484,310.744 162.585,311.844 163.504,311.844 163.687,312.027 v2(163.909,312.027)
  L14 (Sign) w0.12: v16(144.787,316.39) 146.3,316.39 146.982,317.072 149.829,317.072 149.841,317.06 153.468,317.06 157.748,312.779 160.254,312.779 160.541,312.493 160.541,311.175 159.88,310.515 v1(159.88,310.261)
  L16 w0.12: v1(134.722,320.484) 134.722,320.434 134.141,319.853 134.141,318.208 134.561,317.787 135.113,317.787 135.274,317.627 v1(135.445,317.627)
MIO_41: R103.1 U1.D24 | length 35.6
  L1 w0.116: v2(164.909,312.027) U1.D24@165.397,311.539
  L12 (Sign) w0.12: 137.02,318.503 137.483,318.966 140.643,318.966 141.461,318.148 142.18,318.148 v16(144.363,315.965)
  L3 (Sign) w0.12: v1(159.271,310.261) 159.982,310.972 161.392,310.972 162.781,312.362 164.574,312.362 v2(164.909,312.027)
  L14 (Sign) w0.12: v16(144.363,315.965) 146.187,315.965 147.062,316.84 153.377,316.84 157.669,312.547 158.744,312.547 159.832,311.459 159.832,310.822 v1(159.271,310.261)
MIO_42: R104.1 U1.E23 | length 38.5
  L1 w0.116: v2(165.909,311.027) U1.E23@166.397,310.539
  L1 w0.12: R104.1@134.016,316.255 v1(134.996,316.255)
  L12 (Sign) w0.12: v1@149.914,310.591 v1(149.927,310.604)
  L3 (Sign) w0.12: v1(149.927,310.604) 151.782,310.604 152.857,311.679 156.68,311.679 158.77,309.589 160.937,309.589 160.943,309.584 160.962,309.584 162.765,311.387 165.549,311.387 v2(165.909,311.027)
  L14 (Sign) w0.12: v1(134.996,316.255) 135.115,316.255 136.017,315.353 136.017,313.017 138.176,310.858 149.673,310.858 v1(149.927,310.604)
MIO_43: R797.2 U1.F22 | length 37.2
  L1 w0.116: v2(166.909,310.027) U1.F22@167.397,309.539
  L1 w0.12: R797.2@134.016,313.233 134.025,313.224 v1(134.81,313.224)
  L3 (Sign) w0.12: v1(151.315,309.969) 151.77,309.969 153.04,311.239 156.498,311.239 158.587,309.149 160.755,309.149 160.761,309.144 161.144,309.144 162.676,310.676 166.261,310.676 v2(166.909,310.027)
  L14 (Sign) w0.12: v1(134.81,313.224) 135.29,313.224 137.922,310.591 149.182,310.591 149.623,310.15 149.826,310.15 149.88,310.096 151.188,310.096 v1(151.315,309.969)
MIO_44: R798.2 U1.E24 | length 90.8
  L1 w0.116: v5(165.909,312.027) U1.E24@166.397,311.539
  L1 w0.2: v1(178.765,370.449) 179.713,370.449 R798.2@180.405,371.142
  L12 (Sign) w0.12: 153.097,333 153.097,332.582 155.588,330.092 155.588,310.693 156.697,309.584 160.003,309.584 162.446,312.027 v5(165.909,312.027)
  L12 (Sign) w0.2: 153.097,333 153.097,345.232 158.281,350.416 164.948,350.416 170.995,356.464 172.352,356.464 175.374,359.486 175.374,367.548 178.276,370.449 v1(178.765,370.449)
MIO_45: R799.2 U1.F23 | length 89.2
  L1 w0.116: v2(166.909,311.027) U1.F23@167.397,310.539
  L1 w0.2: v1(178.765,369.849) 179.298,369.849 179.955,369.192 R799.2@180.405,369.192
  L12 (Sign) w0.12: 153.463,332.976 153.463,332.599 156.637,329.425 156.637,312.302 v1(158.483,310.456)
  L12 (Sign) w0.2: 153.463,332.976 153.463,345.081 158.433,350.05 165.006,350.05 171.119,356.164 172.476,356.164 175.74,359.428 175.74,367.396 178.194,369.849 v1(178.765,369.849)
  L3 (Sign) w0.12: v1(158.483,310.456) 159.13,309.809 160.876,309.809 162.674,311.607 165.947,311.607 166.527,311.027 v2(166.909,311.027)
MIO_46: R105.1 U1.K20 | length 48.4
  L1 w0.116: U1.K20@171.397,307.539 v5(171.884,307.052)
  L1 w0.12: R105.1@134.016,321.335 134.818,321.335 v2(134.912,321.242)
  L12 (Sign) w0.12: v1(135.166,318.313) 135.687,318.313 136.792,319.418 140.813,319.418 141.572,318.659 143.366,318.659 v16(145.211,316.814)
  L3 (Sign) w0.12: v2(134.912,321.242) 134.899,321.242 134.016,320.359 134.016,319.095 134.798,318.313 v1(135.166,318.313)
  L14 (Sign) w0.12: v16(145.211,316.814) 146.413,316.814 146.95,317.351 149.945,317.351 150.016,317.28 153.559,317.28 157.837,313.002 160.625,313.002 162.832,310.794 162.856,310.794 165.417,308.234 166.594,308.234 167.137,307.691 171.245,307.691 v5(171.884,307.052)
MIO_47: R107.1 U1.K21 | length 43.9
  L1 w0.116: U1.K21@171.397,308.539 v5(171.884,308.052)
  L1 w0.12: R107.1@134.016,319.303 134.143,319.176 v1(134.785,319.176)
  L12 (Sign) w0.12: v1(134.785,319.176) 135.467,319.858 140.995,319.858 141.748,319.106 144.616,319.106 v16(146.06,317.662)
  L14 (Sign) w0.12: v16(146.06,317.662) 146.074,317.677 146.654,317.677 146.775,317.798 150.13,317.798 150.208,317.72 153.741,317.72 158.012,313.449 160.824,313.449 165.599,308.673 171.263,308.673 v5(171.884,308.052)
MIO_48: R108.1 U1.J21 | length 51.6
  L1 w0.116: U1.J21@170.397,308.539 v5(170.884,309.027)
  L1 w0.12: R108.1@134.016,317.271 v1(134.836,317.271)
  L12 (Sign) w0.12: v16(135.026,323.901) 135.979,323.901 139.362,320.518 141.269,320.518 141.867,319.92 146.348,319.92 v16(147.333,318.935)
  L14 (Sign) w0.12: v1(134.836,317.271) 134.016,317.271 133.8,317.487 133.8,322.675 v16(135.026,323.901) ; v16(147.333,318.935) 147.656,318.612 150.467,318.612 150.7,318.38 154.014,318.38 158.131,314.263 161.162,314.263 163.373,312.052 165.113,312.052 167.513,309.651 169.951,309.651 170.576,309.027 v5(170.884,309.027)
MIO_49: R110.1 U1.G21 | length 40.7
  L1 w0.116: v5(167.909,309.027) U1.G21@168.397,308.539
  L1 w0.12: R110.1@134.016,323.367 v2(135.026,323.367)
  L12 (Sign) w0.12: v1(135.674,322.428) 136.512,322.428 138.862,320.078 141.087,320.078 141.729,319.436 145.135,319.436 v16(146.484,318.087)
  L3 (Sign) w0.12: v2(135.026,323.367) 135.357,323.037 135.357,322.745 v1(135.674,322.428)
  L14 (Sign) w0.12: v16(146.484,318.087) 148.041,318.087 148.082,318.128 150.267,318.128 150.455,317.94 153.832,317.94 157.993,313.779 160.961,313.779 163.158,311.582 164.878,311.582 167.433,309.027 v5(167.909,309.027)
MIO_50: R111.1 U1.J20 | length 47.5
  L1 w0.116: U1.J20@170.397,307.539 v5(170.884,308.027)
  L1 w0.12: R111.1@134.016,315.214 135.393,315.214 135.966,315.787 v1(135.966,316.548)
  L12 (Sign) w0.12: v16(135.56,319.24) 136.119,319.24 136.517,319.638 140.904,319.638 141.661,318.881 143.993,318.881 v16(145.636,317.238)
  L14 (Sign) w0.12: v16(135.56,319.24) 135.56,319.223 136.512,318.271 136.512,317.533 135.966,316.987 v1(135.966,316.548) ; v16(145.636,317.238) 146.527,317.238 146.862,317.573 150.037,317.573 150.11,317.5 153.65,317.5 157.926,313.224 160.731,313.224 162.928,311.027 162.935,311.027 165.508,308.454 170.458,308.454 v5(170.884,308.027)
MIO_51: R112.1 U1.H21 | length 52.6
  L1 w0.116: U1.H21@169.397,308.539 v5(169.884,309.027)
  L1 w0.12: R112.1@134.016,314.223 134.041,314.249 v2(135.636,314.249)
  L12 (Sign) w0.12: v1(135.859,323.063) 136.478,323.063 139.243,320.298 141.178,320.298 141.797,319.678 145.741,319.678 v16(146.908,318.511)
  L3 (Sign) w0.12: v2(135.636,314.249) 137.249,315.862 137.249,322.292 136.478,323.063 v1(135.859,323.063)
  L14 (Sign) w0.12: v16(146.908,318.511) 147.049,318.37 150.367,318.37 150.578,318.16 153.923,318.16 158.062,314.021 161.061,314.021 163.258,311.824 164.947,311.824 167.339,309.431 169.48,309.431 v5(169.884,309.027)
MIO_52: R362.1 U1.A24 | length 123.4
  L1 w0.12: v2(153.756,316.545) 153.773,316.528 155.201,316.528 157.675,314.054 157.675,312.492 158.36,311.807 162.129,311.807 U1.A24@162.397,311.539
  L3 (Sign) w0.12: v1(65.177,350.398) 65.177,342.258 68.59,338.845 68.59,333.924 77.298,325.216 136.65,325.216 140.158,321.708 146.09,321.708 151.237,316.562 153.739,316.562 v2(153.756,316.545)
  L16 w0.12: R362.1@63.701,350.397 v1(65.177,350.398)
MIO_53: R800.2 U1.B25 | length 126.7
  L1 w0.116: 162.909,313.027 U1.B25@163.397,312.539
  L1 w0.12: v2(154.711,317.499) 154.728,317.482 155.199,317.482 159.654,313.027 162.909,313.027
  L3 (Sign) w0.12: v1(66.835,351.248) 66.835,341.533 69.25,339.119 69.25,334.198 77.571,325.876 136.942,325.876 140.437,322.381 146.369,322.381 151.234,317.516 154.694,317.516 v2(154.711,317.499)
  L16 w0.12: R800.2@61.327,351.248 v1(66.835,351.248)
MIO_54: R115.1 U1.A23 | length 121.8
  L1 w0.12: v2(153.438,316.227) 153.455,316.21 155.208,316.21 157.455,313.963 157.455,310.653 158.349,309.759 161.617,309.759 U1.A23@162.397,310.539
  L3 (Sign) w0.12: v1(64.706,346.837) 64.706,342.417 68.37,338.754 68.37,333.833 77.207,324.996 136.559,324.996 140.067,321.488 145.999,321.488 151.26,316.227 v2(153.438,316.227)
  L16 w0.12: R115.1@63.701,346.841 63.705,346.837 v1(64.706,346.837)
MIO_55: R801.2 U1.B26 | length 124.4
  L1 w0.116: 162.503,314.027 162.99,313.539 U1.B26@163.397,313.539
  L1 w0.12: v2(155.347,318.136) 155.347,317.973 156.153,317.167 156.153,317.163 159.289,314.027 162.503,314.027
  L3 (Sign) w0.12: v1(67.788,348.822) 68.148,348.463 68.148,340.842 69.69,339.301 69.69,334.38 77.754,326.316 137.137,326.316 140.623,322.83 146.555,322.83 151.233,318.153 155.33,318.153 v2(155.347,318.136)
  L16 w0.12: R801.2@61.327,349.475 67.136,349.475 v1(67.788,348.822)
MIO_56: R116.1 U1.A25 | length 120.6
  L1 w0.12: v2(154.074,316.863) 154.091,316.846 155.194,316.846 157.895,314.145 157.895,313.707 158.877,312.725 160.309,312.725 160.494,312.539 U1.A25@162.397,312.539
  L3 (Sign) w0.12: v1(65.719,348.619) 65.719,342.027 68.81,338.936 68.81,334.015 77.389,325.436 136.741,325.436 140.249,321.928 146.181,321.928 151.23,316.88 154.058,316.88 v2(154.074,316.863)
  L16 w0.12: R116.1@63.701,348.619 v1(65.719,348.619)
MIO_57: R117.1 U1.A26 | length 122
  L1 w0.12: v2(155.029,317.817) 155.181,317.817 159.459,313.539 U1.A26@162.397,313.539
  L3 (Sign) w0.12: v1(67.627,347.726) 67.632,347.721 67.632,341.047 69.47,339.21 69.47,334.289 77.662,326.096 137.04,326.096 140.53,322.606 146.462,322.606 151.234,317.834 155.012,317.834 v2(155.029,317.817)
  L16 w0.12: R117.1@61.327,347.702 61.351,347.726 v1(67.627,347.726)
MIO_58: R118.1 U1.A28 | length 123
  L1 w0.12: v2(155.983,318.772) 156,318.755 156,317.951 158.412,315.539 U1.A28@162.397,315.539
  L3 (Sign) w0.12: v1(67.818,351.676) 67.805,351.676 69.164,350.317 69.164,340.449 70.13,339.483 70.13,334.562 77.936,326.756 137.332,326.756 140.809,323.279 146.741,323.279 151.232,318.789 155.967,318.789 v2(155.983,318.772)
  L16 w0.12: R118.1@63.701,352.175 67.319,352.175 v1(67.818,351.676)
MIO_59: R119.1 U1.A27 | length 120.4
  L1 w0.12: v2(155.665,318.454) 155.682,318.437 155.682,317.952 159.094,314.539 U1.A27@162.397,314.539
  L3 (Sign) w0.12: v1(68.732,345.948) 68.732,340.569 69.91,339.392 69.91,334.471 77.845,326.536 137.235,326.536 140.716,323.055 146.648,323.055 151.232,318.471 155.648,318.471 v2(155.665,318.454)
  L16 w0.12: R119.1@61.327,345.929 61.345,345.948 v1(68.732,345.948)
MIO_60: R120.1 U1.C26 | length 119
  L1 w0.116: v2(163.909,314.027) U1.C26@164.397,313.539
  L1 w0.12: v2(154.393,317.181) 154.409,317.164 155.187,317.164 158.14,314.211 158.14,313.977 v2(158.389,313.728)
  L3 (Sign) w0.12: v1(66.396,345.046) 66.396,341.662 69.03,339.027 69.03,334.106 77.48,325.656 136.832,325.656 140.34,322.148 146.273,322.148 151.222,317.198 154.376,317.198 v2(154.393,317.181) ; v2(158.389,313.728) 158.509,313.728 158.807,314.027 v2(163.909,314.027)
  L16 w0.12: R120.1@63.701,345.063 63.718,345.046 v1(66.396,345.046)
MIO_61: R121.1 U1.B29 | length 116.8
  L1 w0.116: 162.909,317.027 U1.B29@163.397,316.539
  L1 w0.12: v2(156.938,319.727) 156.955,319.71 156.955,317.957 157.885,317.027 162.909,317.027
  L3 (Sign) w0.12: v1(70.79,343.285) 70.79,334.835 78.209,327.416 137.632,327.416 141.09,323.958 147.022,323.958 151.237,319.743 156.921,319.743 v2(156.938,319.727)
  L16 w0.12: R121.1@63.701,343.285 v1(70.79,343.285)
MIO_62: R122.1 U1.B28 | length 118
  L1 w0.116: 162.909,316.027 U1.B28@163.397,315.539
  L1 w0.12: v2(156.302,319.09) 156.318,319.073 156.318,317.95 158.242,316.027 162.909,316.027
  L3 (Sign) w0.12: v1(69.774,342.379) 69.774,340.151 70.35,339.574 70.35,334.653 78.027,326.976 137.43,326.976 140.902,323.504 146.834,323.504 151.231,319.107 156.285,319.107 v2(156.302,319.09)
  L16 w0.12: R122.1@61.327,342.379 v1(69.774,342.379)
MIO_63: R802.2 U1.A29 | length 113.8
  L1 w0.12: v2(156.62,319.408) 156.637,319.392 156.637,317.956 158.054,316.539 U1.A29@162.397,316.539
  L3 (Sign) w0.12: v1(70.307,341.579) 70.307,339.928 70.57,339.665 70.57,334.744 78.118,327.196 137.534,327.196 140.997,323.733 146.929,323.733 151.237,319.425 156.603,319.425 v2(156.62,319.408)
  L16 w0.12: R802.2@63.701,341.507 63.774,341.579 v1(70.307,341.579)
MIO_64: R803.2 U1.B30 | length 7.6
  L1 w0.116: 162.909,318.027 U1.B30@163.397,317.539
  L1 w0.12: 162.077,319.11 162.077,318.859 162.909,318.027
  L1 w0.2: R803.2@159.492,322.58 161.131,322.58 162.077,321.634 162.077,319.11
MIO_65: R804.2 U1.D25 | length 61
  L1 w0.116: v2(164.909,313.027) U1.D25@165.397,312.539
  L3 (Sign) w0.12: v1(110.96,300.177) 112.452,300.177 112.705,300.431 112.705,302.139 113.26,302.694 121.537,310.971 137.108,310.971 138.181,312.044 147.807,312.044 147.845,312.081 148.323,312.559 160.493,312.559 160.496,312.562 162.67,312.562 162.69,312.582 164.464,312.582 v2(164.909,313.027)
MIO_66: R805.2 U1.C27 | length 6.5
  L1 w0.116: v5@163.884,315.074 v5(163.884,315.052) U1.C27@164.397,314.539
  L5 (Sign) w0.12: 158.725,316.446 162.49,316.446 v5(163.884,315.052)
MIO_67: R806.2 U1.C28 | length 6.1
  L1 w0.116: v2(163.909,316.027) U1.C28@164.397,315.539
  L3 (Sign) w0.12: 161.9,320.633 163.397,319.136 163.397,316.539 v2(163.909,316.027)
MIO_68: R807.2 U1.C29 | length 10.4
  L1 w0.116: 163.909,317.027 U1.C29@164.397,316.539
  L1 w0.12: 163.909,317.027 163.909,320.636
  L1 w0.2: R807.2@159.439,323.693 161.498,323.693 163.909,321.281 163.909,320.636
MIO_69: R808.2 U1.D27 | length 6.4
  L1 w0.12: v5(164.871,315.036) 164.9,315.036 U1.D27@165.397,314.539
  L5 (Sign) w0.12: 160.007,317 162.908,317 v5(164.871,315.036)
MIO_70: R809.2 U1.D26 | length 60.2
  L1 w0.116: v2(164.909,314.027) U1.D26@165.397,313.539
  L3 (Sign) w0.12: v1(111.15,301.396) 112.265,301.396 112.265,302.322 112.82,302.876 121.355,311.411 136.926,311.411 137.998,312.483 147.625,312.483 148.143,313.002 160.509,313.002 161.146,313.639 164.522,313.639 v2(164.909,314.027)
MIO_71: R810.2 U1.D30 | length 3.1
  L1 w0.12: U1.D30@165.397,317.539 165.397,320.59
MIO_72: R811.2 U1.E27 | length 107.3
  L1 w0.116: v5(165.909,315.027) U1.E27@166.397,314.539
  L1 w0.12: R811.2@114.655,253.149 115.458,253.149 v2(115.468,253.159)
  L5 (Sign) w0.12: v1(156.124,313.449) 158.89,313.449 160.045,314.604 165.487,314.604 v5(165.909,315.027)
  L3 (Sign) w0.12: v2(115.468,253.159) 117.439,255.13 121.736,255.13 123.083,256.478 123.083,281.059 123.784,281.759 127.235,281.759 128.305,282.829 143.98,282.829 144.907,281.901 146.769,281.901 153.086,288.219 153.086,292.78 156.134,295.828 v1(156.134,301.777)
  L14 (Sign) w0.12: v1(156.124,313.449) 156.124,311.09 157.582,309.632 157.582,302.616 156.743,301.777 v1(156.134,301.777)
MIO_73: R812.2 U1.E30 | length 3.1
  L1 w0.12: U1.E30@166.397,317.539 166.397,320.628
MIO_74: R813.2 U1.E29 | length 4.7
  L1 w0.116: 165.909,317.027 U1.E29@166.397,316.539
  L1 w0.12: 165.909,317.027 165.909,321.064
MIO_75: R814.2 U1.D29 | length 4.5
  L1 w0.116: 164.909,317.027 U1.D29@165.397,316.539
  L1 w0.12: 164.909,317.027 164.909,320.827
MIO_76: R815.2 U1.E28 | length 85.2
  L1 w0.12: U1.E28@166.397,315.539 166.891,316.033 v1(166.891,318.973)
  L5 (Sign) w0.2: v1(104.005,288.332) 105.064,289.391 v11(105.064,297.637) ; v11(131.915,312.492) 133.659,314.236 137.489,314.236 139.318,316.065 146.089,316.065 148.768,318.745 166.662,318.745 v1(166.891,318.973)
  L3 (Sign) w0.2: v11(105.064,297.637) 109.302,301.876 111.447,301.876 121.259,311.689 131.196,311.689 131.915,312.407 v11(131.915,312.492)
  L16 w0.2: R815.2@104.005,287.237 v1(104.005,288.332)
MIO_77: R816.2 U1.E25 | length 78.8
  L1 w0.116: v2(165.909,313.027) U1.E25@166.397,312.539
  L5 (Sign) w0.2: v1(105.075,288.332) 106.134,289.391 v11(106.134,297.637)
  L3 (Sign) w0.12: 109.944,300.787 112.485,300.787 112.485,302.23 113.04,302.785 ; 113.04,302.785 121.446,311.191 137.017,311.191 138.089,312.264 147.716,312.264 147.754,312.301 ; 147.754,312.301 148.231,312.779 160.402,312.779 160.405,312.782 160.6,312.782 161.23,313.412 162.099,313.412 162.098,313.411 165.526,313.411 v2(165.909,313.027)
  L3 (Sign) w0.2: v11(106.134,297.637) 109.283,300.787 109.944,300.787
  L16 w0.2: R816.2@105.075,287.237 v1(105.075,288.332)
MIO_GPIO_0_12: J15.2 R780.1
MIO_GPIO_0_23: J16.2 R98.1 R781.1
MIO_GPIO_1_38: J17.2 R796.1
MIO_GPIO_2_66: J19.2 R805.1
MIO_GPIO_2_70: J20.2 R809.1
MIO_GPIO_2_73: J22.2 R812.1
MIO_GPIO_2_74: J23.2 R813.1 U36_U_Translator_I2C2.8 | length 79.7
  L1 w0.2: v2(65.007,327.331) 65.853,327.331 R813.1@65.867,327.317 U36_U_Translator_I2C2.8@65.867,325.886
  L3 (Sign) w0.2: J23.2@34.799,386.842 36.805,386.842 42.951,380.695 42.951,365.544 43.802,364.693 43.802,347.868 51.438,340.233 58.687,340.233 63.167,335.752 63.167,329.685 65.007,327.846 v2(65.007,327.331)
MIO_GPIO_2_75: J24.2 R814.1 U36_U_Translator_I2C3.8 | length 78.9
  L1 w0.2: v2(64.284,334.515) 64.284,334.553 64.643,334.912 R814.1@65.39,334.912
  L3 (Sign) w0.2: J24.2@34.799,395.643 38.989,391.453 38.989,385.082 43.251,380.819 43.251,365.668 44.102,364.817 44.102,347.993 51.562,340.533 58.811,340.533 64.284,335.06 v2(64.284,334.515)
MODE: R669.2 R670.1 U65.2 | length 3.6
  L1 w0.254: R670.1@37.668,200.838 38.26,200.838 ; U65.2@38.26,202.478 38.26,200.838 ; R669.2@38.887,199.931 38.537,199.931 38.26,200.208 38.26,200.838
NetBT1_2: BT1.2 R650.1 T22.2 | length 37.1
  L1 w0.5: v1(206.308,174.955) 206.377,175.024 T22.2@206.377,176.006 ; v1(206.629,172.479) R650.1@207.551,172.479
  L14 (Sign) w0.5: v1(206.308,174.955) 206.308,174.471 208.301,172.479 ; v1(206.629,172.479) 208.301,172.479 ; v9(229.616,166.345) 228.419,166.345 222.285,172.479 208.301,172.479
  L16 w0.5: v9(229.616,166.345) 232.321,166.345 233.566,165.1 BT1.2@233.566,163.335
NetC36_1: C36.1 R52.2 R54.2 | length 3.4
  L1 w0.5: R52.2@157.837,331.433 156.878,331.433 C36.1@156.346,331.965 156.903,332.522 R54.2@157.837,332.522
NetC45_2: C45.2 R77.1
NetC78_2: C78.2 U16.7
NetC79_2: C79.2 U16.38
NetC80_2: C80.2 U16.48 | length 4
  L1 w0.2: C80.2@149.717,235.087 149.717,233.574 150.195,233.095 151.118,233.095 151.415,232.798 U16.48@151.415,232.345
NetC91_1: C91.1 U16.39
NetC96_1: C96.1 U16.47 | length 3.5
  L1 w0.2: C96.1@150.717,235.087 150.717,234.182 151.016,233.883 151.522,233.883 151.915,233.49 U16.47@151.915,232.345
NetC312_2: C312.2 U4.11
NetC313_2: C313.2 U5.11
NetC314_1: C314.1 U48.11
NetC320_1: C320.1 U30.9 | length 3
  L1 w0.2: U30.9@62.932,492.711 62.932,493.818 63.259,494.144 63.941,494.144 C320.1@64.453,494.656
NetC321_1: C321.1 U30.10 | length 3.1
  L1 w0.2: U30.10@62.297,492.711 62.297,493.97 63.185,494.858 C321.1@63.185,495.465
NetC322_2: C322.2 U30.3 X3.1 | length 7
  L1 w0.2: U30.3@59.757,487.377 59.757,486.194 60.182,485.769 C322.2@60.182,485.091 60.182,483.145 X3.1@62.046,481.281
NetC323_2: C323.2 U30.2 X3.2 | length 6.9
  L1 w0.2: X3.2@57.166,481.281 58.982,483.097 C323.2@58.982,485.091 58.982,485.842 59.122,485.982 U30.2@59.122,487.377
NetC333_1: C333.1 R537.2
NetC334_1: C334.1 X1.10 | length 0
NetC335_2: C335.2 R532.1 R533.2
NetC341_1: C341.1 J26.1
NetC351_2: C351.2 R268.2 U34.3 | length 4.2
  L1 w0.254: R268.2@59.692,237.714 60.97,237.714 61.118,237.565 61.118,236.791 C351.2@61.146,236.764 61.151,236.764 61.776,236.139 U34.3@62.822,236.139
NetC356_2: C356.2 R272.2 R277.1 R278.1 U34.2 U34.4 U34.7 U34.9 U34.32 | length 23.6
  L1 w0.254: U34.4@62.822,235.639 61.694,235.639 61.667,235.666 60.285,235.666 60.109,235.49 60.109,235.185 R272.2@60.156,235.139 60.206,235.139 60.479,234.866 60.479,234.745 60.783,234.441 60.783,233.982 60.926,233.839 C356.2@60.931,233.839 61.589,233.839 61.99,233.437 v23(62.009,233.437) 62.049,233.437 62.347,233.139 U34.9@63.322,233.139 ; U34.2@62.822,236.639 62.481,236.639 62.057,237.063 62.057,237.421 v23@62.125,237.489 ; U34.32@63.322,237.639 63.322,237.703 63.32,237.705 62.341,237.705 v23@62.125,237.489 ; R278.1@63.439,240.856 63.077,240.856 62.085,239.863 62.085,237.528 v23@62.125,237.489
  L16 w0.254: v23(62.085,237.489) 62.085,237.449 62.009,237.373 v23(62.009,233.437) 62.009,231.673 v26(64.365,229.317)
NetC357_2: C357.2 U34.13 U34.28 | length 10.4
  L1 w0.254: v26(64.511,231.163) 64.583,231.235 64.816,231.235 65.315,231.734 65.315,232.984 65.32,232.989 65.32,233.137 U34.13@65.322,233.139 ; U34.28@65.322,237.639 v23(65.322,238.22)
  L16 w0.254: v26(64.511,231.163) 64.949,231.601 64.949,237.847 v23(65.322,238.22)
NetC471_2: C471.2 T21.12
NetC472_2: C472.2 T21.6
NetC473_2: C473.2 T21.1
NetC474_2: C474.2 T21.7
NetC475_2: C475.2 T21.S1
NetC476_2: C476.2 T21.S2
NetC532_1: C532.1 U44.14
NetC533_1: C533.1 U44.15
NetC534_1: C534.1 U44.16
NetC537_1: C537.1 FB26.2 | length 4.6
  L1 w0.2: C537.1@37.721,354.198 40.907,354.198 41.898,355.189 FB26.2@41.948,355.189
NetC537_4: C537.4 FB27.2 | length 4.7
  L1 w0.2: C537.4@37.721,347.198 40.594,347.198 41.88,345.912 FB27.2@41.93,345.912
NetC537_Z1: C537.Z1 FB28.1
NetC549_2: C549.2 R687.1 | length 1.1
  L1 w0.254: C549.2@61.948,212.229 61.951,212.227 61.951,211.171 R687.1@61.953,211.169
NetC558_Z1: C558.Z1 C558.Z2 C672.2
NetC568_2: C568.2 FB33.1 R433.2 U60.10 U60.11 U60.12 U60.13 U60.14
NetC571_1: C571.1 U60.7
NetC573_1: C573.1 R436.1 R437.2 U61.16
NetC577_1: C577.1 R438.1 R439.2 U61.10
NetC578_2: C578.2 U61.7
NetC579_2: C579.2 U61.19
NetC581_2: C581.2 C582.2 C583.2 FB34.2 R442.2 U62.1 U62.2 U62.3
NetC584_2: C584.2 R445.2 U62.7
NetC588_1: C588.1 R543.2 | length 1.2
  L1 w0.086: C588.1@153.67,241.307 R543.2@153.67,242.481
NetC588_2: C588.2 C589.1 R545.2 | length 2.1
  L1 w0.086: C589.1@153.67,238.444 R545.2@153.67,239.511 C588.2@153.67,240.527
NetC591_2: C591.2 C592.2 FB37.2 X9.4
NetC597_2: C597.2 R140.1 U65.17 | length 3.4
  L1 w0.254: C597.2@34.722,206.35 34.722,205.41 R140.1@34.747,205.384 35.433,205.384 36,204.818 U65.17@36.92,204.818
NetC603_1: C603.1 R113.1 R114.2 U19.20
NetC604_1: C604.1 U19.25 | length 4.4
  L1 w0.254: U19.25@174.078,171.85 174.08,171.852 174.08,172.319 174.58,172.819 175.206,172.819 175.603,173.217 175.603,173.963 176.22,174.58 176.22,174.765 176.363,174.908 C604.1@176.368,174.908
NetC605_1: C605.1 R212.1 R214.2 U19.21
NetC612_1: C612.1 R216.2 R218.2 U19.22
NetC616_1: C616.1 R220.1 R274.2 U19.19
NetC633_2: C633.2 R613.1 | length 2.3
  L1 w0.254: R613.1@90.765,247.284 C633.2@93.052,247.284
NetC634_2: C634.2 R615.2 U34.11 U34.30 | length 14.8
  L1 w0.254: v23(61.056,231.693) 63.519,231.693 64.315,232.489 64.315,232.984 64.32,232.989 64.32,233.137 U34.11@64.322,233.139 ; v23(64.297,238.715) 64.32,238.692 U34.30@64.322,237.639 U34.30@64.322,237.639
  L16 w0.254: v23(61.056,231.693) R615.2@61.056,234.739 61.042,234.753 61.042,235.71 C634.2@61.028,235.724 61.028,235.729 61.301,236.002 61.392,236.002 61.525,236.135 61.525,237.705 62.535,238.715 v23(64.297,238.715)
NetC635_2: C635.2 R615.1 | length 1
  L16 w0.254: C635.2@60.062,235.724 60.109,235.677 60.109,234.785 R615.1@60.156,234.739
NetC636_2: C636.2 R616.1 | length 2.2
  L1 w0.254: R616.1@90.717,224.031 C636.2@92.942,224.031
NetC637_2: C637.2 R288.1 | length 1
  L1 w0.254: 87.033,189.468 87.568,189.468 C637.2@87.909,189.81
NetC638_2: C638.2 R298.1 | length 1.1
  L1 w0.254: 88.405,173.59 88.411,173.596 88.938,173.596 C638.2@89.332,173.99
NetC643_2: C643.2 R623.1 | length 1.1
  L1 w0.254: C643.2@63.12,173.949 R623.1@63.12,175.007
NetC644_2: C644.2 R624.1 | length 1
  L1 w0.254: R624.1@63.175,184.21 C644.2@63.175,185.176
NetC645_2: C645.2 R306.1 | length 0.9
  L1 w0.254: 87.566,203.543 87.564,203.54 87.564,203.257 C645.2@87.964,202.857
NetC646_2: C646.2 R316.1 | length 1.1
  L1 w0.254: C646.2@84.502,207.488 85.052,206.938 85.052,206.654
NetC652_2: C652.2 R631.1
NetC655_1: C655.1 U49.6 | length 1.2
  L1 w0.2: U49.6@104.82,253.648 104.82,254.678 C655.1@104.972,254.83
NetC656_1: C656.1 U50.6 | length 1.2
  L1 w0.2: U50.6@99.426,253.671 99.426,254.732 C656.1@99.49,254.796
NetC657_1: C657.1 U51.6
NetC674_2: C674.2 FB45.1 R644.2 U69.10 U69.11 U69.12 U69.13 U69.14 | length 2.8
  L1 w0.2: 131.54,234.808 R644.2@132.588,233.759 132.666,233.837 C674.2@133.907,233.837
NetC678_2: C678.2 R652.2 R654.2 T25.1 T29.3 | length 18.9
  L1 w0.5: C678.2@200.596,160.734 202.629,160.734 ; T29.3@202.629,161.361 202.629,160.734 ; R654.2@202.667,159.023 202.629,159.061 202.629,160.734 ; v2(204.673,160.757) 204.651,160.734 202.629,160.734 ; R652.2@211.956,164.834 211.956,164.178 212.178,163.956 ; T25.1@212.443,163.329 212.443,163.691 212.178,163.956 ; v2(212.946,164.434) 212.656,164.434 212.178,163.956
  L3 (Sign) w0.5: v2(204.673,160.757) 209.276,160.757 212.954,164.434 v2(212.946,164.434)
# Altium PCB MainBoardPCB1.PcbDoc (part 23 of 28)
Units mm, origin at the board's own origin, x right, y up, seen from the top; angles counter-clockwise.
Board outline 258.95 x 308.86 mm, 16 copper layers (L1, L2 (GND), L3 (Sign), L4 (GND), L5 (Sign), L6 (PWR/GND), L7(PWR/GND), L8 (Plane_GND), L9 (PWR/GND), L10 (PWR/GND), L11 (PWR/GND), L12 (Sign), L13 (GND), L14 (Sign), L15 (GND), L16), stack 2.502 mm thick; 2397 components, 1744 nets, 8397 pads, 4112 vias.
Unrouted connection lines stored in the file: 3547.

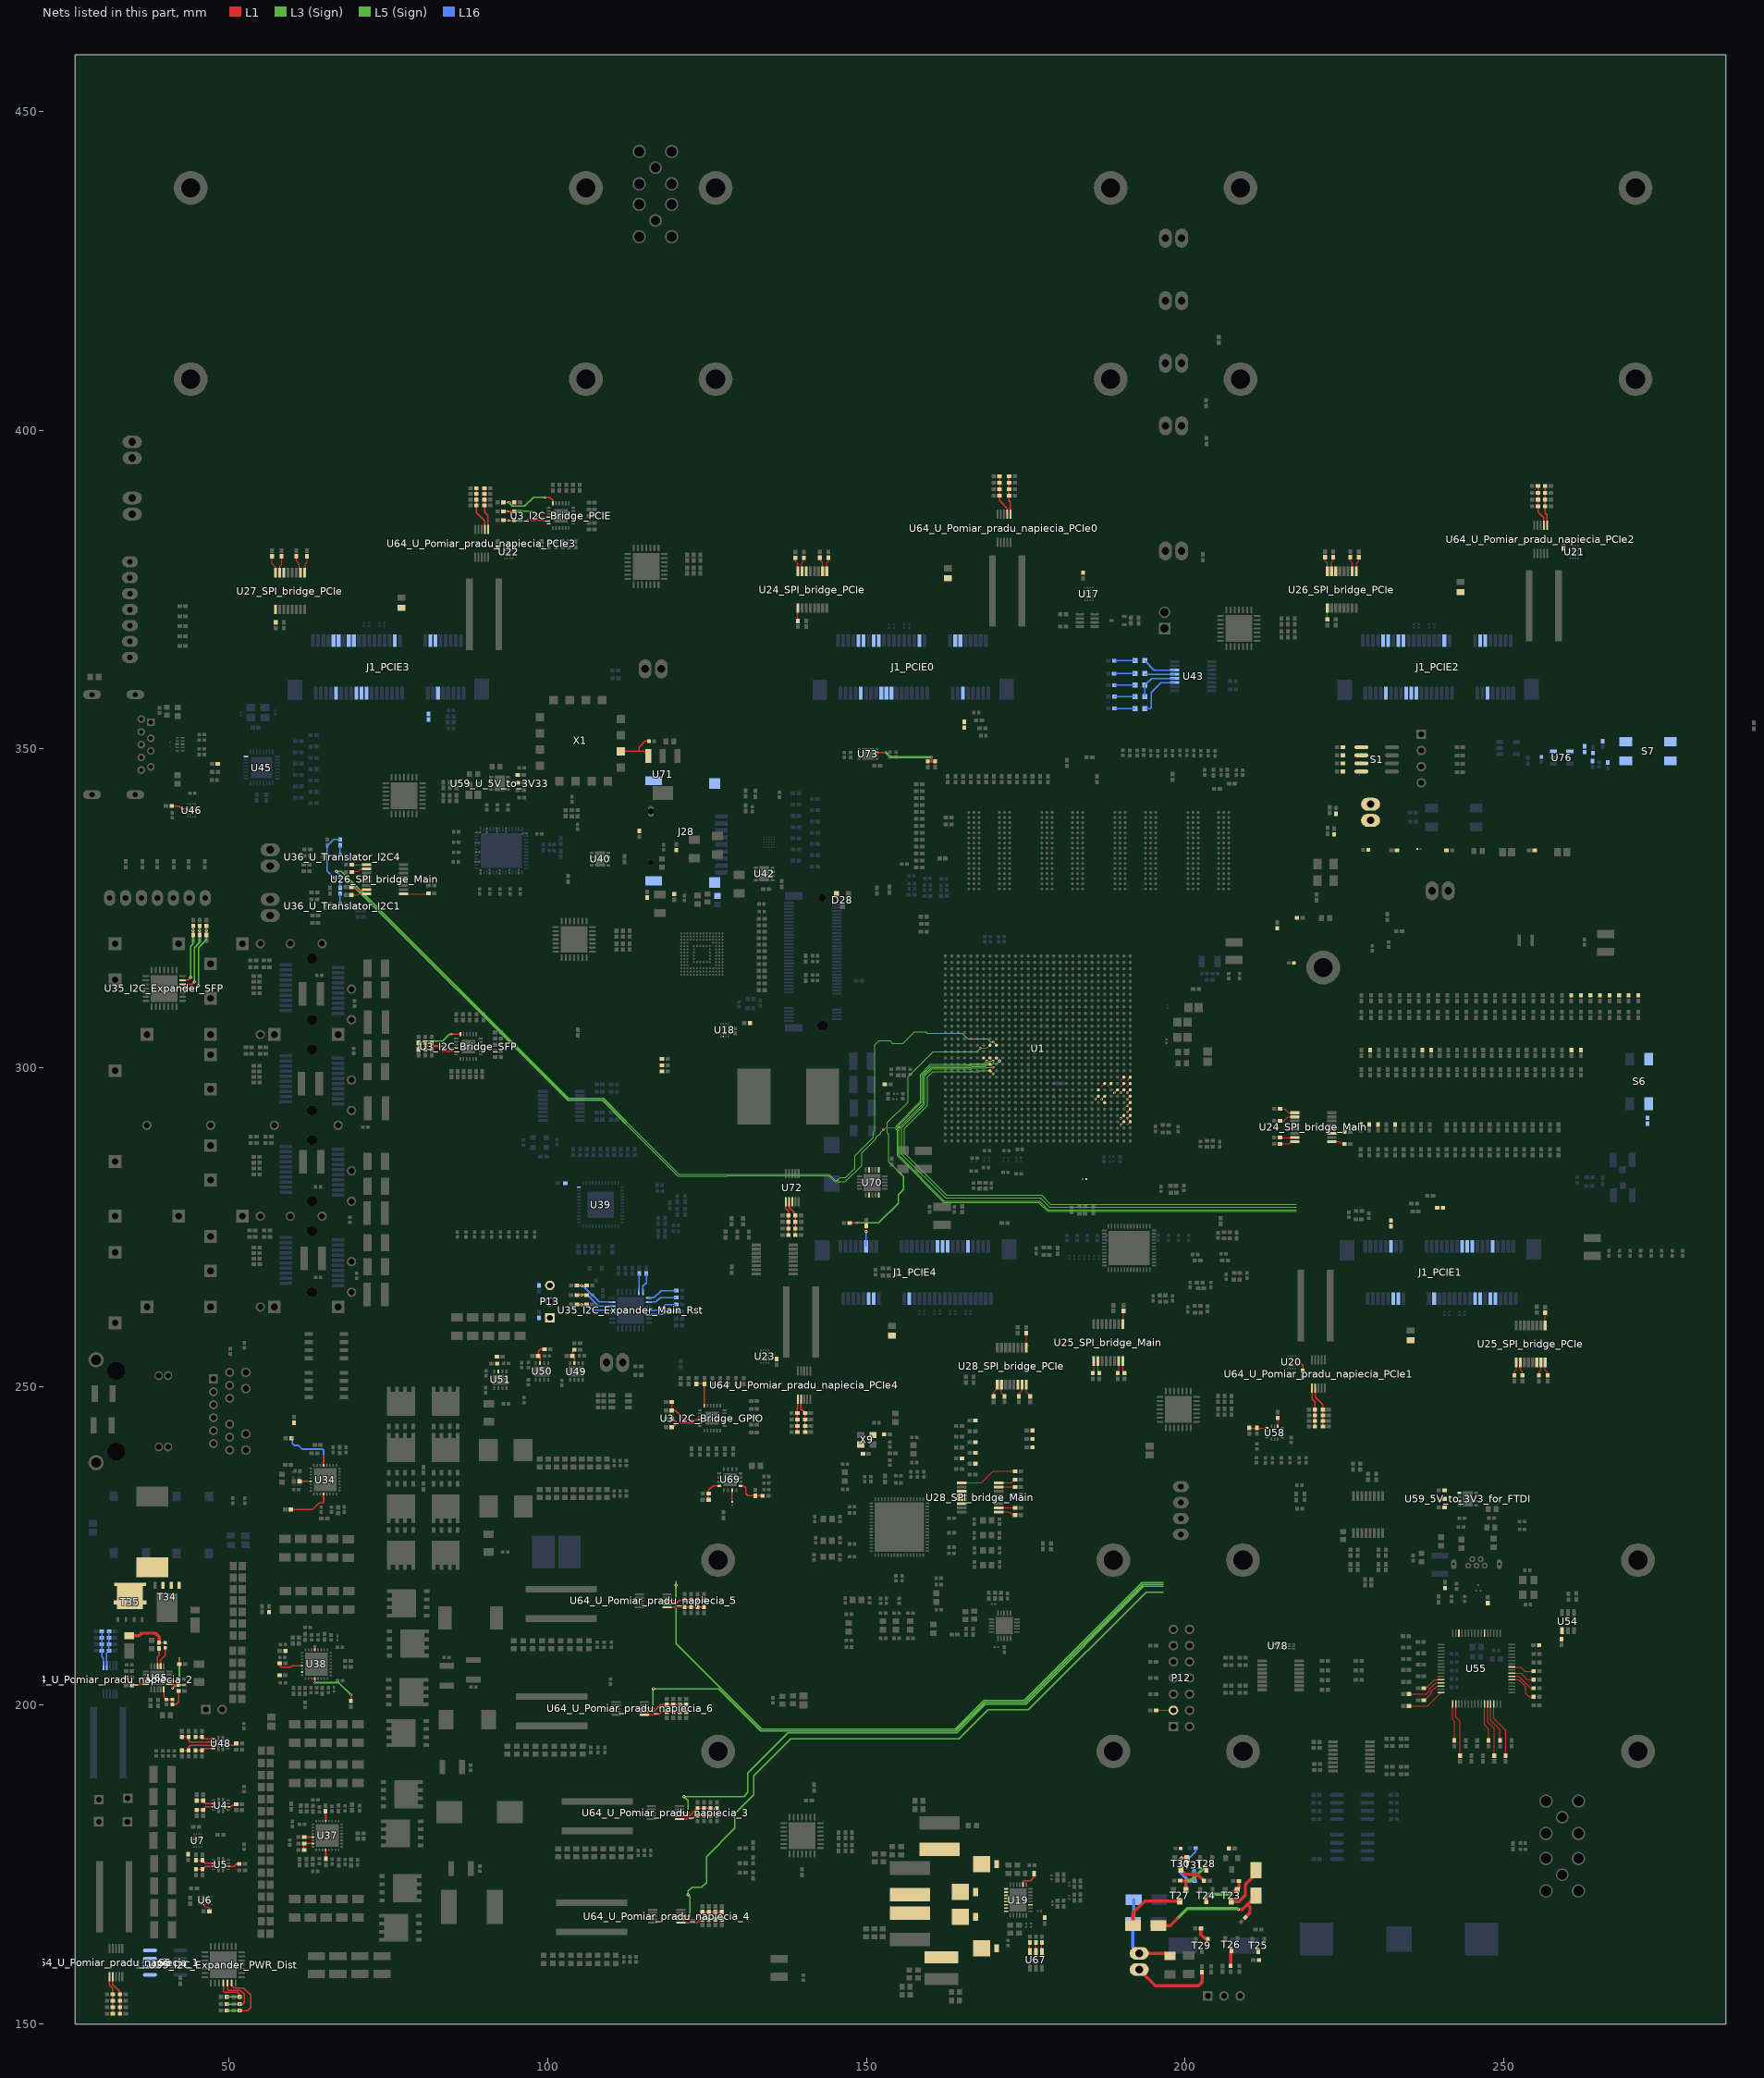
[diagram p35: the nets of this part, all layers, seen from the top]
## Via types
v1: diameter 0.5, hole 0.2, L1 to L16, tented both sides, 1457 vias
v2: diameter 0.35/0/0.35 (per signal layer), hole 0.127, L1 to L3 (Sign), tented both sides, 479 vias
v3: diameter 0.5/0.35/0.35/0.35/0.35/0.35/0.35/0.35/0.35/0.35/0.35/0.35/0.35/0.35/0.35/0.5 (per signal layer), hole 0.15, L1 to L16, tented both sides, 453 vias
v4: diameter 0.5, hole 0.2, L1 to L16, 451 vias
v5: diameter 0.5/0.35/0.35/0.35/0.35/0.35/0.35/0.35/0.35/0.35/0.35/0.35/0.35/0.35/0.35/0.5 (per signal layer), hole 0.2, L1 to L16, tented both sides, 373 vias
v6: diameter 0.8, hole 0.4, L1 to L16, tented both sides, 168 vias
v7: diameter 0.35/0/0.35 (per signal layer), hole 0.127, L1 to L3 (Sign), 138 vias
v8: diameter 2.54, hole 1.02, L1 to L16, 113 vias
v9: diameter 0.5/0/0.5 (per signal layer), hole 0.2, L14 (Sign) to L16, tented both sides, 102 vias
v10: diameter 1.4, hole 0.5, L1 to L16, tented both sides, 80 vias
v11: diameter 0.5, hole 0.2, L3 (Sign) to L6 (PWR/GND), tented both sides, 54 vias
v12: diameter 0.35, hole 0.127, L1 to L2 (GND), tented both sides, 47 vias
v13: diameter 0.4, hole 0.2, L1 to L16, tented both sides, 46 vias
v14: diameter 0.35, hole 0.127, L1 to L16, tented both sides, 16 vias
v15: diameter 0.25, hole 0.2, L1 to L16, 16 vias
v16: diameter 0.5, hole 0.2, L11 (PWR/GND) to L14 (Sign), tented both sides, 16 vias
v17: diameter 0.4, hole 0.2, L1 to L16, 16 vias
v18: diameter 0.3, hole 0.2, L1 to L16, 15 vias
v19: diameter 0.45, hole 0.15, L1 to L16, 12 vias
v20: diameter 0.5/0.35/0.35/0.35/0.35/0.35/0.35/0.35/0.35/0.35/0.35/0.35/0.35/0.35/0.35/0.45 (per signal layer), hole 0.15, L1 to L16, tented both sides, 10 vias
v21: diameter 0.2/0/0.2 (per signal layer), hole 0.1, L1 to L3 (Sign), tented both sides, 9 vias
v22: diameter 0.3, hole 0.127, L14 (Sign) to L16, tented both sides, 8 vias
v23: diameter 0.4, hole 0.1, L1 to L16, 7 vias
v24: diameter 1.15, hole 1.15, L1 to L16, 5 vias
v25: diameter 1.65, hole 1.65, L1 to L16, 5 vias
v26: diameter 0.2, hole 0.1, L1 to L16, 4 vias
v27: diameter 0.4, hole 0.15, L1 to L16, 2 vias
v28: diameter 0.5/0.35/0.35/0.35/0.35/0.35/0.35/0.35/0.35/0.35/0.35/0.35/0.35/0.35/0.35/0.5 (per signal layer), hole 0.15, L1 to L16, 2 vias
v29: diameter 0.35, hole 0.127, L3 (Sign) to L6 (PWR/GND), tented both sides, 2 vias
v30: diameter 0.3, hole 0.127, L15 (GND) to L16, tented both sides, 1 vias
v31: diameter 0.35, hole 0.127, L1 to L2 (GND), 1 vias
v32: diameter 0.5/0.35/0.35/0.35/0.35/0.35/0.35/0.35/0.35/0.35/0.35/0.35/0.35/0.35/0.35/0.5 (per signal layer), hole 0.2, L1 to L16, 1 vias
v33: diameter 0.35/0.35/0.35 (per signal layer), hole 0.127, L1 to L3 (Sign), tented both sides, 1 vias
v34: diameter 0.45/0/0.45 (per signal layer), hole 0.15, L1 to L3 (Sign), tented both sides, 1 vias
v35: diameter 0.45/0/0.45 (per signal layer), hole 0.2, L14 (Sign) to L16, tented both sides, 1 vias

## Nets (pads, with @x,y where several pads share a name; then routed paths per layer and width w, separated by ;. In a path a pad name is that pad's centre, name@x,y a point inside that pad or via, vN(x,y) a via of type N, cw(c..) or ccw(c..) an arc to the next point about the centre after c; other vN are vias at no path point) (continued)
NetC679_2: C679.2 D23.1 D24.1 J36.1 | length 13.9
  L1 w0.5: J36.1@192.799,161.087 197.209,161.087 C679.2@197.637,160.658
  L16 w0.5: D24.1@191.954,169.495 191.954,166.08 D23.1@191.826,165.952 191.826,162.059 J36.1@192.799,161.087
NetC680_2: C680.2 R656.1 R657.1 T30.1 | length 4.9
  L1 w0.5: v1(199.425,176.006) T30.1@200.289,176.006
  L16 w0.5: v1(199.425,176.006) 199.352,175.933 199.352,173.693 R657.1@200.578,172.467
NetC693_1: C693.1 L22.1 T34.1 T34.2 T34.3 T35.5 U65.12 | length 3.2
  L1 w0.254: U65.12@39.26,206.158 39.26,207.104 39.98,207.823 C693.1@39.98,209.037
NetC693_2: C693.2 D26.1 R665.1 | length 6.9
  L1 w0.254: R665.1@39.014,209.828 39.025,209.817 C693.2@39.98,209.817
  L1 w0.5: D26.1@34.353,210.921 35.856,210.921 36.25,211.315 38.427,211.315 39.014,210.728 R665.1@39.014,209.828
NetC701_1: C701.1 R667.2 | length 2.9
  L1 w0.254: C701.1@41.097,200.121 41.676,200.121 42.078,200.524 R667.2@42.078,202.265
NetC701_2: C701.2 C702.2 U65.5 | length 2.7
  L1 w0.254: U65.5@39.76,202.478 39.76,201.311 C702.2@40.17,200.901 C701.2@41.097,200.901
NetC703_2: C703.2 U65.7 | length 1.7
  L1 w0.254: U65.7@40.6,203.818 41.292,203.818 41.38,203.73 41.759,203.73 C703.2@42.127,204.097
NetC706_1: C706.1 R671.1 R672.2 U70.16
NetC710_1: C710.1 R673.1 R674.2 U70.10
NetC711_2: C711.2 U70.7
NetC712_2: C712.2 U70.19
NetC713_2: C713.2 U71.3 X1.14 | length 7.2
  L1 w0.2: X1.14@111.455,349.656 114.3,349.656 ; U71.3@115.764,348.924 115.032,349.656 114.3,349.656 ; C713.2@115.897,351.231 115.252,351.231 114.3,350.279 114.3,349.656
NetC719_2: C719.2 U69.7 | length 1.8
  L1 w0.2: C719.2@128.93,231.915 U69.7@128.93,233.718
NetC724_1: C724.1 R384.1
NetC725_1: C725.1 R385.1
NetC726_1: C726.1 R484.1
NetC727_1: C727.1 R485.1
NetC790_1: C790.1 U76.3
NetD5_1: D5.1 R716.1 | length 3.3
  L16 w0.2: R716.1@188.902,363.868 D5.1@192.166,363.868
NetD5_2: D5.2 U43.14 | length 5.3
  L16 w0.2: D5.2@193.666,363.868 195.155,362.379 U43.14@198.37,362.379
NetD6_1: D6.1 R717.1 | length 3.3
  L16 w0.2: R717.1@188.862,361.831 D6.1@192.166,361.831
NetD6_2: D6.2 U43.13 | length 4.7
  L16 w0.2: D6.2@193.666,361.831 193.768,361.729 U43.13@198.37,361.729
NetD7_1: D7.1 R718.1 | length 3.3
  L16 w0.2: R718.1@188.905,360.007 D7.1@192.166,360.007
NetD7_2: D7.2 D9.1 U43.12 | length 6.9
  L16 w0.2: D9.1@193.666,358.229 D7.2@193.666,360.007 194.738,361.079 U43.12@198.37,361.079
NetD8_1: D8.1 R719.1 | length 3.3
  L16 w0.2: R719.1@188.912,356.362 D8.1@192.166,356.362
NetD8_2: D8.2 U43.11 | length 7.8
  L16 w0.2: D8.2@193.666,356.362 194.552,356.362 194.669,356.479 194.669,358.902 196.196,360.429 U43.11@198.37,360.429
NetD9_2: D9.2 R720.1 | length 3.3
  L16 w0.2: R720.1@188.912,358.229 D9.2@192.166,358.229
NetD10_1: D10.1 R368.1
NetD10_2: D10.2 U44.12
NetD11_2: D11.2 R370.1 S4.1 S4.2 U44.7
NetD12_2: D12.2 R369.1 S3.1 S3.2 U44.6
NetD16_1: D16.1 L13.1 U19.5
NetD16_2: D16.2 U19.6
NetD17_1: D17.1 L16.1 U19.4
NetD17_2: D17.2 U19.3
NetD18_1: D18.1 L17.1 U19.2
NetD18_2: D18.2 U19.1
NetD19_1: D19.1 L18.1 U19.7
NetD19_2: D19.2 U19.8
NetD20_1: D20.1 D21.1 R647.1 | length 19.9
  L1 w0.5: D21.1@195.826,165.452 197.684,165.452 v2(198.895,166.662) ; v2(208.389,167.983) 208.988,167.983 209.758,168.753 ; R647.1@209.461,166.713 210.185,167.437 210.185,168.326 209.758,168.753 ; D20.1@211.142,170.137 209.758,168.753
  L3 (Sign) w0.5: v2(198.895,166.662) 200.36,168.127 208.219,168.127 208.376,167.97 v2(208.389,167.983)
NetD20_2: D20.2 T23.3 | length 7.3
  L1 w0.5: T23.3@207.239,169.232 208.501,169.232 209.461,170.193 209.461,171.883 211.142,173.564 D20.2@211.142,174.137
NetD21_2: D21.2 T27.3 | length 10.1
  L1 w0.5: D21.2@191.826,165.452 191.826,167.41 193.674,169.258 T27.3@199.161,169.258
NetD28_2: D28.2 R276.2
NetF1_PCIE0_1: F1_PCIE0.1 J1_PCIE0.20
NetF1_PCIE1_1: F1_PCIE1.1 J1_PCIE1.20
NetF1_PCIE2_1: F1_PCIE2.1 J1_PCIE2.20
NetF1_PCIE3_1: F1_PCIE3.1 J1_PCIE3.20
NetF1_PCIE4_1: F1_PCIE4.1 J1_PCIE4.20
NetFB29_2: FB29.2 J28.10 J28.11 J28.12 J28.13
NetJ1_PCIE0_11: J1_PCIE0.11 R507.2
NetJ1_PCIE0_12: J1_PCIE0.12 U1.AK10 | length 0.7
  L1 w0.116: 190.909,297.052 U1.AK10@191.397,297.539
NetJ1_PCIE0_14: J1_PCIE0.14 U1.AJ10 | length 0.7
  L1 w0.116: 189.909,297.052 U1.AJ10@190.397,297.539
NetJ1_PCIE0_31: J1_PCIE0.31 U1.AJ11 | length 0.7
  L1 w0.116: 189.909,298.052 U1.AJ11@190.397,298.539
NetJ1_PCIE0_33: J1_PCIE0.33 U1.AK11 | length 0.7
  L1 w0.116: 190.909,298.052 U1.AK11@191.397,298.539
NetJ1_PCIE0_36: J1_PCIE0.36
NetJ1_PCIE0_38: J1_PCIE0.38
NetJ1_PCIE0_42: J1_PCIE0.42
NetJ1_PCIE0_43: J1_PCIE0.43 R967.2
NetJ1_PCIE0_44: J1_PCIE0.44
NetJ1_PCIE1_11: J1_PCIE1.11 R514.2
NetJ1_PCIE1_12: J1_PCIE1.12 U1.AK8 | length 0.7
  L1 w0.116: v2(190.909,295.052) U1.AK8@191.397,295.539
NetJ1_PCIE1_14: J1_PCIE1.14 U1.AK9 | length 0.7
  L1 w0.116: v2(190.909,296.052) U1.AK9@191.397,296.539
NetJ1_PCIE1_31: J1_PCIE1.31 U1.AF10 | length 0.7
  L1 w0.116: 186.909,297.052 U1.AF10@187.397,297.539
NetJ1_PCIE1_33: J1_PCIE1.33 U1.AG10 | length 0.7
  L1 w0.116: 187.909,297.052 U1.AG10@188.397,297.539
NetJ1_PCIE1_36: J1_PCIE1.36
NetJ1_PCIE1_38: J1_PCIE1.38
NetJ1_PCIE1_42: J1_PCIE1.42
NetJ1_PCIE1_43: J1_PCIE1.43 R968.2
NetJ1_PCIE1_44: J1_PCIE1.44
NetJ1_PCIE2_11: J1_PCIE2.11 R901.2
NetJ1_PCIE2_12: J1_PCIE2.12 U1.AF7
NetJ1_PCIE2_14: J1_PCIE2.14 U1.AF8 | length 0.7
  L1 w0.116: v2(186.909,295.052) U1.AF8@187.397,295.539
NetJ1_PCIE2_31: J1_PCIE2.31 U1.AH9 | length 0.7
  L1 w0.116: v2(188.909,296.052) U1.AH9@189.397,296.539
NetJ1_PCIE2_33: J1_PCIE2.33 U1.AJ9 | length 0.7
  L1 w0.116: v2(189.909,296.052) U1.AJ9@190.397,296.539
NetJ1_PCIE2_36: J1_PCIE2.36
NetJ1_PCIE2_38: J1_PCIE2.38
NetJ1_PCIE2_42: J1_PCIE2.42
NetJ1_PCIE2_43: J1_PCIE2.43 R969.2
NetJ1_PCIE2_44: J1_PCIE2.44
NetJ1_PCIE3_11: J1_PCIE3.11 R902.2
NetJ1_PCIE3_12: J1_PCIE3.12 U1.AK6 | length 0.7
  L1 w0.116: v2(190.909,293.052) U1.AK6@191.397,293.539
NetJ1_PCIE3_14: J1_PCIE3.14 U1.AK7 | length 0.7
  L1 w0.116: v2(190.909,294.052) U1.AK7@191.397,294.539
NetJ1_PCIE3_31: J1_PCIE3.31 U1.AE9
NetJ1_PCIE3_33: J1_PCIE3.33 U1.AE8 | length 0.7
  L1 w0.116: v2(185.909,295.052) U1.AE8@186.397,295.539
NetJ1_PCIE3_36: J1_PCIE3.36
NetJ1_PCIE3_38: J1_PCIE3.38
NetJ1_PCIE3_42: J1_PCIE3.42
NetJ1_PCIE3_43: J1_PCIE3.43 R970.2
NetJ1_PCIE3_44: J1_PCIE3.44
NetJ1_PCIE4_11: J1_PCIE4.11 R903.2 | length 3.2
  L1 w0.2: v1(149.972,274.282) 149.974,274.284 R903.2@149.974,275.222
  L16 w0.2: J1_PCIE4.11@149.937,271.994 149.937,274.247 v1(149.972,274.282)
NetJ1_PCIE4_12: J1_PCIE4.12 U1.AK4 | length 0.7
  L1 w0.116: 190.909,291.052 U1.AK4@191.397,291.539
NetJ1_PCIE4_14: J1_PCIE4.14 U1.AJ4 | length 0.7
  L1 w0.116: v2(189.909,291.052) U1.AJ4@190.397,291.539
NetJ1_PCIE4_31: J1_PCIE4.31 U1.AJ5 | length 0.7
  L1 w0.116: v2(189.909,292.052) U1.AJ5@190.397,292.539
NetJ1_PCIE4_33: J1_PCIE4.33 U1.AK5 | length 0.7
  L1 w0.116: v2(190.909,292.052) U1.AK5@191.397,292.539
NetJ1_PCIE4_43: J1_PCIE4.43 R971.2
NetJ30_1: J30.1 R283.2
NetJ30_2: J30.2 R286.2
NetJ36_2: J36.2 R654.1 | length 12.7
  L1 w0.5: J36.2@192.799,158.547 195.351,155.994 202.108,155.994 202.667,156.553 R654.1@202.667,158.123
NetL15_2: L15.2 U19.24 | length 3.1
  L1 w0.254: U19.24@174.578,171.85 174.578,172.317 174.727,172.465 175.755,172.465 176.303,173.013 L15.2@176.303,173.617
NetP3_1: P3.1 U44.11
NetP4_2: P4.2 U44.10
NetP12_3: P12.3 R731.1 U78.1 | length 2.7
  L1 w0.12: R731.1@195.466,199.209 P12.3@198.171,199.209
NetP13_1: P13.1 R675.2
NetP13_3: P13.3 R737.1
NetR12_1: R12.1 R19.2 U5.5 | length 4.2
  L1 w0.2: R19.2@44.801,174.289 R12.1@45.844,174.289 45.844,174.314 46.28,174.75 U5.5@47.56,174.75 46.345,174.75
NetR14_1: R14.1 R16.1 R22.1 R24.1 U72.2 | length 5.6
  L1 w0.2: U72.2@137.853,279.003 137.853,278.122 138.729,277.246 138.729,276.971 R16.1@138.854,276.846 R24.1@138.854,274.797 R22.1@138.854,273.772
NetR15_1: R15.1 R23.2 U4.5 | length 2.9
  L1 w0.2: R23.2@44.92,183.563 R15.1@45.94,183.563 45.94,183.667 46.345,184.071 U4.5@47.56,184.071
NetR17_1: R17.1 R25.2 U4.4 | length 2.9
  L1 w0.2: R25.2@44.92,185.074 R17.1@45.94,185.074 45.94,184.98 46.349,184.571 U4.4@47.56,184.571
NetR18_2: R18.2 U4.10 | length 1.4
  L1 w0.2: U4.10@49.86,184.071 50.307,184.071 50.707,184.471 R18.2@51.11,184.471
NetR20_1: R20.1 R26.2 U5.4 | length 4.2
  L1 w0.2: R26.2@44.801,175.686 R20.1@45.822,175.686 46.258,175.25 U5.4@47.56,175.25 46.349,175.25
NetR21_2: R21.2 U5.10 | length 1.9
  L1 w0.2: U5.10@49.86,174.75 50.762,174.75 51.138,175.125 R21.2@51.6,175.125
NetR27_2: R27.2 U6.C1 | length 1.8
  L1 w0.12: U6.C1@46.01,168.789 46.01,168.554 46.246,168.319 46.704,168.319 46.939,168.084 46.939,167.985 46.94,167.984 46.94,167.714 R27.2@46.91,167.684
NetR28_1: R28.1 U7.C1
NetR75_1: R75.1 U1.H16 | length 46.4
  L1 w0.12: v2(167.852,303.098) 168.956,303.098 U1.H16@169.397,303.539
  L1 w0.2: R75.1@147.358,275.653 148.476,275.653 v2(148.501,275.679)
  L3 (Sign) w0.12: 155.27,283.494 153.528,285.237 153.528,289.55 153.306,289.771 153.306,291.418 156.528,294.639 156.528,298.572 160.487,302.531 167.365,302.531 167.852,303.018 v2(167.852,303.098)
  L3 (Sign) w0.2: v2(148.501,275.679) 151.917,275.679 155.004,278.765 155.004,280.092 155.816,280.905 155.816,282.948 155.27,283.494
NetR132_1: R132.1 U28_SPI_bridge_Main.14
NetR133_1: R133.1 U28_SPI_bridge_Main.13
NetR134_1: R134.1 U28_SPI_bridge_Main.12
NetR149_1: R149.1 R159.2 U65.20 | length 3.9
  L1 w0.2: R149.1@33.873,204.343 33.947,204.269 33.947,204.06 34.27,203.737 34.548,203.737 34.773,203.513 R159.2@34.773,203.149
  L1 w0.254: R159.2@34.773,203.149 35.891,203.149 36.059,203.318 U65.20@36.92,203.318
NetR150_1: R150.1 R160.2 U65.6 | length 8.3
  L1 w0.254: U65.6@40.6,203.318 41.282,203.318 ; v2(41.123,202.654) 41.282,202.814 41.282,203.318 ; R160.2@42.078,203.203 41.397,203.203 41.282,203.318 ; R150.1@42.202,206.468 v2(42.202,207.35)
  L3 (Sign) w0.254: v2(41.123,202.654) 42.202,203.733 v2(42.202,207.35)
NetR174_1: R174.1 R175.1 R176.1 R177.1 U64_U_Pomiar_pradu_napiecia_PCIe0.2 | length 6.5
  L1 w0.2: R176.1@170.877,392.788 R177.1@170.877,391.772 R174.1@170.877,390.756 R175.1@170.877,389.74 170.877,388.99 172.087,387.78 U64_U_Pomiar_pradu_napiecia_PCIe0.2@172.087,386.83
NetR178_1: R178.1 R179.1 R180.1 R181.1 U64_U_Pomiar_pradu_napiecia_PCIe0.1 | length 6
  L1 w0.2: R180.1@172.39,392.788 R181.1@172.39,391.772 R178.1@172.39,390.756 R179.1@172.39,389.74 172.39,388.99 172.587,388.793 U64_U_Pomiar_pradu_napiecia_PCIe0.1@172.587,386.83
NetR182_2: R182.2 U17.C1
NetR183_1: R183.1 R184.1 R185.1 R186.1 U64_U_Pomiar_pradu_napiecia_PCIe1.2 | length 6.6
  L1 w0.2: U64_U_Pomiar_pradu_napiecia_PCIe1.2@220.427,249.776 220.427,248.361 221.637,247.151 R184.1@221.637,246.381 R183.1@221.637,245.492 R186.1@221.637,244.603 R185.1@221.637,243.714
NetR187_1: R187.1 R188.1 R189.1 R190.1 U64_U_Pomiar_pradu_napiecia_PCIe1.1 | length 6.2
  L1 w0.2: U64_U_Pomiar_pradu_napiecia_PCIe1.1@219.927,249.776 219.927,248.042 220.378,247.591 R188.1@220.378,246.381 R187.1@220.378,245.492 R190.1@220.378,244.603 R189.1@220.378,243.714
NetR191_2: R191.2 U20.C1 | length 2.1
  L1 w0.2: U20.C1@217.313,253.622 218.149,253.622 218.456,253.315 R191.2@218.456,252.476
NetR192_1: R192.1 R193.1 R194.1 R195.1 U64_U_Pomiar_pradu_napiecia_PCIe2.2 | length 6.5
  L1 w0.2: R194.1@255.374,391.25 255.424,391.2 255.424,387.19 256.295,386.319 U64_U_Pomiar_pradu_napiecia_PCIe2.2@256.295,385.108
NetR196_1: R196.1 R197.1 R198.1 R199.1 U64_U_Pomiar_pradu_napiecia_PCIe2.1 | length 6.3
  L1 w0.2: R198.1@256.506,391.25 R199.1@256.506,390.192 R197.1@256.506,388.075 256.506,387.017 256.799,386.724 256.799,385.111 U64_U_Pomiar_pradu_napiecia_PCIe2.1@256.795,385.108
NetR200_2: R200.2 U21.C1
NetR201_1: R201.1 R202.1 R203.1 R204.1 U64_U_Pomiar_pradu_napiecia_PCIe3.2 | length 7
  L1 w0.2: R203.1@88.813,390.907 R204.1@88.813,390.018 R201.1@88.813,389.129 R202.1@88.813,388.24 88.813,387.1 90.133,385.78 U64_U_Pomiar_pradu_napiecia_PCIe3.2@90.133,384.471
NetR205_1: R205.1 R206.1 R207.1 R208.1 U64_U_Pomiar_pradu_napiecia_PCIe3.1 | length 6.7
  L1 w0.2: R207.1@90.072,390.907 R208.1@90.072,390.018 R206.1@90.072,388.24 90.072,387.19 90.633,386.629 U64_U_Pomiar_pradu_napiecia_PCIe3.1@90.633,384.471
NetR209_2: R209.2 U22.C1
NetR210_1: R210.1 R211.1 R213.1 R215.1 U64_U_Pomiar_pradu_napiecia_PCIe4.2 | length 5.5
  L1 w0.2: U64_U_Pomiar_pradu_napiecia_PCIe4.2@139.729,248.004 139.729,246.48 140.141,246.068 140.141,246.018 140.341,245.818 R211.1@140.391,245.818 140.394,245.815 R213.1@140.394,242.844
NetR217_1: R217.1 R219.1 R221.1 R222.1 U64_U_Pomiar_pradu_napiecia_PCIe4.1 | length 5.2
  L1 w0.2: R221.1@139.165,242.844 R219.1@139.164,245.818 139.164,246.621 139.229,246.685 U64_U_Pomiar_pradu_napiecia_PCIe4.1@139.229,248.004
NetR228_2: R228.2 U23.C1
NetR229_1: R229.1 R230.1 R457.1 R459.1 U64_U_Pomiar_pradu_napiecia_1.2 | length 6.3
  L1 w0.2: U64_U_Pomiar_pradu_napiecia_1.2@31.745,157.414 31.738,157.407 31.738,156.219 32.87,155.087 R230.1@32.87,154.669 R457.1@32.87,151.621
NetR231_SPI_bridge_Main_1: R231_SPI_bridge_Main.1 U24_SPI_bridge_Main.11 U24_SPI_bridge_PCIe.6 U25_SPI_bridge_PCIe.6 U26_SPI_bridge_PCIe.6 U27_SPI_bridge_PCIe.6 U28_SPI_bridge_PCIe.6 | length 2.1
  L1 w0.12: U24_SPI_bridge_Main.11@223.032,289.702 223.972,289.702 224.253,289.983 R231_SPI_bridge_Main.1@225.007,289.983
NetR232_SPI_bridge_Main_2: R232_SPI_bridge_Main.2 U24_SPI_bridge_Main.9 | length 2.2
  L1 w0.12: U24_SPI_bridge_Main.9@223.032,288.402 223.078,288.448 224.134,288.448 224.514,288.068 R232_SPI_bridge_Main.2@225.007,288.068
NetR232_SPI_bridge_PCIe_2: R232_SPI_bridge_PCIe.2 U24_SPI_bridge_PCIe.9 | length 2
  L1 w0.12: R232_SPI_bridge_PCIe.2@139.232,370.11 U24_SPI_bridge_PCIe.9@139.232,372.107
NetR234_SPI_bridge_Main_2: R234_SPI_bridge_Main.2 U25_SPI_bridge_Main.9 | length 2.1
  L1 w0.12: U25_SPI_bridge_Main.9@190.248,259.821 190.348,259.921 R234_SPI_bridge_Main.2@190.348,261.861
NetR234_SPI_bridge_PCIe_2: R234_SPI_bridge_PCIe.2 U25_SPI_bridge_PCIe.9 | length 2
  L1 w0.12: U25_SPI_bridge_PCIe.9@256.491,259.567 R234_SPI_bridge_PCIe.2@256.491,261.564
NetR235_SPI_bridge_Main_1: R235_SPI_bridge_Main.1 U26_SPI_bridge_Main.9 | length 3.9
  L1 w0.12: U26_SPI_bridge_Main.9@77.371,327.29 U26_SPI_bridge_Main.9@77.373,327.29 R235_SPI_bridge_Main.1@81.305,327.29
NetR235_SPI_bridge_PCIe_1: R235_SPI_bridge_PCIe.1 U26_SPI_bridge_PCIe.9 | length 1.8
  L1 w0.12: R235_SPI_bridge_PCIe.1@222.34,370.34 U26_SPI_bridge_PCIe.9@222.34,372.107
NetR237_SPI_bridge_Main_1: R237_SPI_bridge_Main.1 U27_SPI_bridge_Main.9 | length 2.4
  L1 w0.2: U27_SPI_bridge_Main.9@53.184,492.853 53.184,494.274 R237_SPI_bridge_Main.1@53.893,494.982
NetR237_SPI_bridge_PCIe_1: R237_SPI_bridge_PCIe.1 U27_SPI_bridge_PCIe.9
NetR238_SPI_bridge_Main_2: R238_SPI_bridge_Main.2 U27_SPI_bridge_Main.15 | length 2.8
  L1 w0.2: U27_SPI_bridge_Main.15@49.284,492.853 49.284,495.369 R238_SPI_bridge_Main.2@49.495,495.579
NetR239_SPI_bridge_Main_2: R239_SPI_bridge_Main.2 U28_SPI_bridge_Main.9 | length 9.1
  L1 w0.12: U28_SPI_bridge_Main.9@164.969,234.888 168.101,234.888 169.916,236.703 R239_SPI_bridge_Main.2@173.353,236.703
NetR239_SPI_bridge_PCIe_2: R239_SPI_bridge_PCIe.2 U28_SPI_bridge_PCIe.9 | length 2.1
  L1 w0.12: R239_SPI_bridge_PCIe.2@175.098,258.399 175.098,256.653 175.373,256.378
NetR240_SPI_bridge_Main_1: R240_SPI_bridge_Main.1 R912.1 U28_SPI_bridge_Main.11
NetR241_2: R241.2 R242.1 U3_I2C_Bridge_GPIO.22 | length 6.3
  L1 w0.2: R241.2@119.456,247.554 R242.1@119.456,246.246 120.035,246.246 121.491,244.789 U3_I2C_Bridge_GPIO.22@123.878,244.789
NetR243_2: R243.2 R244.1 U3_I2C_Bridge_GPIO.23 | length 5.8
  L1 w0.2: R244.1@119.456,243.63 119.643,243.63 120.302,244.289 ; R243.2@119.456,244.938 119.654,244.938 120.302,244.289 ; U3_I2C_Bridge_GPIO.23@123.878,244.289 120.302,244.289
NetR263_2: R263.2 U33.16
NetR264_2: R264.2 U33.13
NetR265_2: R265.2 U33.15
NetR266_1: R266.1 R267.2 S5.1 S5.2 S5.3 S5.4
NetR269_2: R269.2 U18.C1
NetR272_1: R272.1 U34.5 | length 1.8
  L1 w0.254: R272.1@61.056,235.139 U34.5@62.822,235.139
NetR281_2: R281.2 R400.1 U3_I2C_Bridge_GPIO.18 | length 4.7
  L1 w0.2: R400.1@123.333,250.419 R281.2@124.57,250.419 124.57,246.981 U3_I2C_Bridge_GPIO.18@124.563,246.974
NetR284_2: R284.2 U19.17
NetR289_1: R289.1 U37.5 | length 1.4
  L1 w0.254: R289.1@61.781,179.317 U37.5@63.175,179.317
NetR293_1: R293.1 R294.1 U37.7 | length 2.4
  L1 w0.2: R294.1@61.781,177.317 R293.1@61.781,178.317 U37.7@63.175,178.317
NetR304_1: R304.1 R388.1 R389.1 R390.1 U72.1 | length 5.4
  L1 w0.2: U72.1@137.353,279.003 137.353,277.965 137.766,277.552 R388.1@137.766,276.846 R389.1@137.766,273.772
NetR305_2: R305.2 U67.6 | length 1.4
  L1 w0.12: U67.6@175.639,161.385 R305.2@175.639,162.805
NetR307_1: R307.1 U38.5 | length 4.1
  L1 w0.254: R307.1@57.945,206.596 57.945,206.233 58.189,205.989 59.673,205.989 59.898,206.214 U38.5@61.453,206.214
NetR308_2: R308.2 U67.5 | length 1.4
  L1 w0.12: U67.5@176.589,161.385 R308.2@176.589,162.805
NetR309_2: R309.2 U67.4 | length 1.4
  L1 w0.12: U67.4@177.539,161.385 R309.2@177.539,162.805
NetR310_1: R310.1 R312.1 U38.7
NetR334_1: R334.1 U39.12
NetR339_1: R339.1 R341.2 U40.7
NetR342_1: R342.1 R344.2 U42.7
NetR358_1: R358.1 S1.8
NetR359_1: R359.1 S1.7
NetR360_1: R360.1 S1.6
NetR361_1: R361.1 S1.5
NetR366_2: R366.2 R498.2 R499.2 R692.1
NetR372_1: R372.1 R373.2 U44.2 U44.3
NetR379_2: R379.2 U45.24
NetR380_2: R380.2 U46.C1 | length 2.7
  L1 w0.2: R380.2@40.998,341.072 42.133,341.072 42.623,340.582 U46.C1@43.517,340.582
NetR391_1: R391.1 R393.2 U49.7 | length 2.4
  L1 w0.2: U49.7@104.17,253.648 104.17,254.496 R391.1@103.87,254.796 103.87,255.47 R393.2@104.17,255.77
NetR394_1: R394.1 R396.2 U50.7 | length 3.1
  L1 w0.2: U50.7@98.776,253.671 98.776,254.521 R394.1@98.501,254.796 98.501,255.511 98.857,255.867 R396.2@99.494,255.867
NetR397_1: R397.1 R399.2 U51.7
NetR419_2: R419.2 R422.1 U54.1
NetR423_2: R423.2 U55.6
NetR424_2: R424.2 U55.14
NetR425_SPI_bridge_Main_1: R425_SPI_bridge_Main.1 U24_SPI_bridge_Main.1 | length 2.6
  L1 w0.12: R425_SPI_bridge_Main.1@214.902,293.539 215.68,293.539 216.267,292.952 U24_SPI_bridge_Main.1@217.232,292.952
NetR425_SPI_bridge_PCIe_1: R425_SPI_bridge_PCIe.1 U24_SPI_bridge_PCIe.1 | length 2.3
  L1 w0.12: U24_SPI_bridge_PCIe.1@143.782,377.907 143.757,377.932 143.757,379.157 144.057,379.457 R425_SPI_bridge_PCIe.1@144.057,380.027
NetR426_SPI_bridge_Main_2: R426_SPI_bridge_Main.2 U24_SPI_bridge_Main.7 | length 2.3
  L1 w0.12: R426_SPI_bridge_Main.2@214.902,289.052 U24_SPI_bridge_Main.7@217.232,289.052
NetR426_SPI_bridge_PCIe_2: R426_SPI_bridge_PCIe.2 U24_SPI_bridge_PCIe.7 | length 2.2
  L1 w0.12: U24_SPI_bridge_PCIe.7@139.882,377.907 139.882,379.157 140.183,379.458 R426_SPI_bridge_PCIe.2@140.183,379.977
NetR429_1: R429.1 U58.12 | length 1.3
  L1 w0.12: U58.12@214.553,243.754 R429.1@214.553,245.065
NetR430_5V_to_3V3_for_FTDI_1: R430_5V_to_3V3_for_FTDI.1 R432_5V_to_3V3_for_FTDI.2 U59_5V_to_3V3_for_FTDI.7
NetR430_U_5V_to_3V31_1: R430_U_5V_to_3V31.1 R432_U_5V_to_3V31.2 U59_U_5V_to_3V31.7
NetR430_U_5V_to_3V32_1: R430_U_5V_to_3V32.1 R432_U_5V_to_3V32.2 U59_U_5V_to_3V32.7
NetR430_U_5V_to_3V33_1: R430_U_5V_to_3V33.1 R432_U_5V_to_3V33.2 U59_U_5V_to_3V33.7
NetR431_5V_to_3V3_for_FTDI_1: R431_5V_to_3V3_for_FTDI.1 U59_5V_to_3V3_for_FTDI.5
NetR433_1: R433.1 R434.2 U60.9
NetR435_1: R435.1 R668.2 U69.4 | length 3.5
  L1 w0.2: R668.2@125.227,232.245 125.227,233.736 125.909,234.418 U69.4@126.93,234.418
NetR443_1: R443.1 R444.2 U62.6
NetR449_2: R449.2 R450.1 U3_I2C_Bridge_PCIE.22 | length 8.4
  L1 w0.2: R450.1@93.032,387.28 v2(93.815,387.28) R449.2@94.744,387.28 ; v2(98.412,386.372) 98.421,386.363 U3_I2C_Bridge_PCIE.22@100.135,386.363
  L3 (Sign) w0.2: v2(93.815,387.28) 97.504,387.28 v2(98.412,386.372)
NetR451_2: R451.2 R452.1 U3_I2C_Bridge_PCIE.23 | length 8
  L1 w0.2: R452.1@93.032,385.877 v2(93.866,385.877) R451.2@94.745,385.877 ; v2(96.851,385.863) U3_I2C_Bridge_PCIE.23@100.135,385.863
  L3 (Sign) w0.2: v2(93.866,385.877) 96.837,385.877 v2(96.851,385.863)
NetR453_2: R453.2 R454.1 U3_I2C_Bridge_PCIE.18 | length 10.1
  L1 w0.2: R454.1@93.032,388.683 v2(93.889,388.683) R453.2@94.745,388.683 ; v2(99.619,389.509) 100.292,389.509 100.82,388.981 U3_I2C_Bridge_PCIE.18@100.82,388.548
  L3 (Sign) w0.2: v2(93.889,388.683) 94.473,388.099 96.355,388.099 97.765,389.509 v2(99.619,389.509)
NetR455_2: R455.2 R456.1 U35_I2C_Expander_PWR_Dist.13 | length 9.9
  L1 w0.2: R456.1@49.635,152.11 v7(49.76,152.11) ; U35_I2C_Expander_PWR_Dist.13@50.393,156.428 50.393,156.053 50.793,155.653 52.271,155.653 53.404,154.521 53.404,152.589 52.925,152.11 v7(51.667,152.11)
  L3 (Sign) w0.2: v7(49.76,152.11) v7(51.667,152.11)
NetR458_2: R458.2 R460.1 U35_I2C_Expander_PWR_Dist.12 | length 8.1
  L1 w0.2: R460.1@49.635,153.126 v7(49.76,153.126) ; U35_I2C_Expander_PWR_Dist.12@49.743,156.428 49.743,155.392 49.861,155.275 51.77,155.275 52.362,154.682 52.362,153.397 52.092,153.126 v7(51.667,153.126)
  L3 (Sign) w0.2: v7(49.76,153.126) v7(51.667,153.126)
NetR461_1: R461.1 R463.1 R465.1 R466.1 U64_U_Pomiar_pradu_napiecia_1.1 | length 6
  L1 w0.2: U64_U_Pomiar_pradu_napiecia_1.1@31.245,157.414 31.245,156.153 31.745,155.653 31.745,151.628 R465.1@31.738,151.621
NetR462_2: R462.2 R464.1 U35_I2C_Expander_PWR_Dist.11 | length 6.5
  L1 w0.2: U35_I2C_Expander_PWR_Dist.11@49.093,156.428 49.093,155.11 49.234,154.969 51.3,154.969 51.667,154.603 v7(51.667,154.269) ; R464.1@49.635,154.269 v7(49.76,154.269)
  L3 (Sign) w0.2: v7(49.76,154.269) v7(51.667,154.269)
NetR467_1: R467.1 R468.1 R593.1 R594.1 U64_U_Pomiar_pradu_napiecia_2.2 | length 5.5
  L16 w0.2: U64_U_Pomiar_pradu_napiecia_2.2@30.798,206.235 30.798,208.179 30.908,208.289 30.908,208.339 31.108,208.539 R468.1@31.158,208.539 R593.1@31.158,211.587
NetR469_2: R469.2 R470.1 U3_I2C_Bridge_SFP.22 | length 6
  L1 w0.2: R470.1@80.807,302.877 v2(80.807,303.414) R469.2@80.807,303.951 ; v2(83.795,303.124) 83.823,303.096 U3_I2C_Bridge_SFP.22@85.6,303.096
  L3 (Sign) w0.2: v2(80.807,303.414) 83.505,303.414 v2(83.795,303.124)
NetR471_2: R471.2 R472.1 U3_I2C_Bridge_SFP.23 | length 5.2
  L1 w0.2: R472.1@81.823,302.877 81.823,303.416 ; R471.2@81.823,303.951 81.823,303.416 ; U3_I2C_Bridge_SFP.23@85.6,302.596 83.494,302.596 82.674,303.416 81.823,303.416
NetR473_2: R473.2 R474.1 U3_I2C_Bridge_SFP.18 | length 8.4
  L1 w0.2: R474.1@79.743,302.865 v2(79.743,303.417) R473.2@79.743,303.939 ; v2(84.874,305.283) 86.287,305.283 U3_I2C_Bridge_SFP.18@86.285,305.281
  L3 (Sign) w0.2: v2(79.743,303.417) 80.492,304.165 83.502,304.165 84.62,305.283 v2(84.874,305.283)
NetR475_2: R475.2 R476.1 U35_I2C_Expander_SFP.13 | length 10.4
  L1 w0.2: U35_I2C_Expander_SFP.13@42.702,313.753 43.523,313.753 v1(43.955,314.185) ; R476.1@44.356,320.853 v1(44.356,321.558) R475.2@44.356,322.262
  L5 (Sign) w0.2: v1(43.955,314.185) 43.98,314.211 43.98,319.037 44.356,319.413 v1(44.356,321.558)
NetR477_2: R477.2 R478.1 U35_I2C_Expander_SFP.12 | length 11.8
  L1 w0.2: U35_I2C_Expander_SFP.12@42.702,313.103 44.194,313.103 v1(44.577,313.487) ; R478.1@45.372,320.853 v1(45.372,321.558) R477.2@45.372,322.262
  L5 (Sign) w0.2: v1(44.577,313.487) 44.577,318.874 45.372,319.67 v1(45.372,321.558)
NetR479_2: R479.2 R480.1 U35_I2C_Expander_SFP.11 | length 13.3
  L1 w0.2: U35_I2C_Expander_SFP.11@42.702,312.453 44.788,312.453 v1(45.212,312.877) ; R480.1@46.434,320.853 v1(46.434,321.558) R479.2@46.434,322.262
  L5 (Sign) w0.2: v1(45.212,312.877) 45.212,318.821 46.434,320.043 v1(46.434,321.558)
NetR481_2: R481.2 U27_SPI_bridge_Main.13 | length 9.2
  L1 w0.2: v2(50.559,491.626) 50.584,491.652 U27_SPI_bridge_Main.13@50.584,492.853 ; v2(51.435,496.506) 51.448,496.519 R481.2@52.357,496.519
  L3 (Sign) w0.2: v2(50.559,491.626) 50.559,491.617 49.045,493.131 49.045,494.929 50.622,496.506 v2(51.435,496.506)
NetR488_1: R488.1 T36.3 U32.2
NetR507_1: R507.1 U1.H13 | length 91.2
  L1 w0.116: U1.H13@169.397,300.539 v2(169.884,300.052)
  L3 (Sign) w0.12: v2(169.884,300.052) 168.818,300.052 168.745,299.979 166.555,299.979 166.388,299.812 165.381,299.812 165.325,299.868 160.312,299.868 159.165,298.721 159.165,294.283 155.516,290.633 155.516,289.181 155.516,286.45 162.396,279.57 177.306,279.57 178.741,278.135 217.475,278.135
NetR514_1: R514.1 U1.H12 | length 89.9
  L1 w0.116: U1.H12@169.397,299.539 v2(169.884,299.052)
  L3 (Sign) w0.12: v2(169.884,299.052) 169.397,299.539 167.895,299.539 167.783,299.428 166.626,299.428 166.57,299.372 165.199,299.372 165.143,299.428 160.495,299.428 159.605,298.539 159.605,294.1 155.956,290.451 155.956,289.363 155.956,286.632 162.579,280.01 177.488,280.01 178.923,278.575 217.475,278.575
NetR543_1: R543.1 X9.3
NetR544_1: R544.1 X9.1
NetR561_1: R561.1 R562.1 R563.1 R564.1 U64_U_Pomiar_pradu_napiecia_3.2 | length 6.3
  L1 w0.2: U64_U_Pomiar_pradu_napiecia_3.2@120.678,182.659 122.233,182.659 123.433,183.86 R562.1@123.482,183.86 R561.1@124.498,183.86 R564.1@125.514,183.86 R563.1@126.53,183.86
NetR565_1: R565.1 R566.1 R567.1 R568.1 U64_U_Pomiar_pradu_napiecia_3.1 | length 6.1
  L1 w0.2: U64_U_Pomiar_pradu_napiecia_3.1@120.678,182.159 122.584,182.159 123.152,182.728 R566.1@123.482,182.728 R565.1@124.498,182.728 R568.1@125.514,182.728 R567.1@126.53,182.728
NetR569_1: R569.1 R570.1 R571.1 R572.1 U64_U_Pomiar_pradu_napiecia_4.2 | length 6.9
  L1 w0.2: U64_U_Pomiar_pradu_napiecia_4.2@120.907,166.403 123.158,166.403 124.265,167.511 R570.1@124.265,167.561 R572.1@126.297,167.561 R571.1@127.313,167.561
NetR573_1: R573.1 R574.1 R575.1 R576.1 U64_U_Pomiar_pradu_napiecia_4.1 | length 6.6
  L1 w0.2: U64_U_Pomiar_pradu_napiecia_4.1@120.907,165.903 123.365,165.903 123.89,166.429 R575.1@127.313,166.429
NetR577_1: R577.1 R578.1 R579.1 R580.1 U64_U_Pomiar_pradu_napiecia_5.2 | length 6.1
  L1 w0.2: U64_U_Pomiar_pradu_napiecia_5.2@118.748,215.893 120.121,215.893 120.714,216.487 124.486,216.487 R579.1@124.536,216.537
NetR581_1: R581.1 R582.1 R583.1 R584.1 U64_U_Pomiar_pradu_napiecia_5.1 | length 5.8
  L1 w0.2: U64_U_Pomiar_pradu_napiecia_5.1@118.748,215.393 121.477,215.393 R582.1@121.488,215.405 R581.1@122.504,215.405 R584.1@123.52,215.405 R583.1@124.536,215.405
NetR585_1: R585.1 R586.1 R587.1 R588.1 U64_U_Pomiar_pradu_napiecia_6.2 | length 7
  L1 w0.2: U64_U_Pomiar_pradu_napiecia_6.2@115.141,199.008 116.635,199.008 117.698,200.071 R586.1@118.682,200.071 R588.1@120.714,200.071 R587.1@121.73,200.071
NetR589_1: R589.1 R590.1 R591.1 R592.1 U64_U_Pomiar_pradu_napiecia_6.1 | length 6.8
  L1 w0.2: U64_U_Pomiar_pradu_napiecia_6.1@115.141,198.508 115.161,198.489 117.398,198.489 117.848,198.939 R590.1@118.682,198.939 R589.1@119.698,198.939 R592.1@120.714,198.939 R591.1@121.73,198.939
NetR595_1: R595.1 R596.1 R597.1 R598.1 U64_U_Pomiar_pradu_napiecia_2.1 | length 5.5
  L16 w0.2: R597.1@30.026,211.587 R596.1@30.026,208.539 30.026,207.655 30.298,207.383 U64_U_Pomiar_pradu_napiecia_2.1@30.298,206.235
NetR600_1: R600.1 R601.2 U58.1 | length 2.7
  L1 w0.12: R600.1@210.075,243.504 R601.2@211.261,243.504 U58.1@212.803,243.504
NetR602_SPI_bridge_Main_1: R602_SPI_bridge_Main.1 U24_SPI_bridge_Main.2 | length 2.6
  L1 w0.12: R602_SPI_bridge_Main.1@214.902,291.652 215.491,291.652 216.141,292.302 U24_SPI_bridge_Main.2@217.232,292.302
NetR602_SPI_bridge_PCIe_1: R602_SPI_bridge_PCIe.1 U24_SPI_bridge_PCIe.2 | length 2.3
  L1 w0.12: R602_SPI_bridge_PCIe.1@142.687,380.027 142.687,379.602 143.132,379.157 U24_SPI_bridge_PCIe.2@143.132,377.907
NetR603_SPI_bridge_Main_2: R603_SPI_bridge_Main.2 U24_SPI_bridge_Main.8 | length 2.5
  L1 w0.12: R603_SPI_bridge_Main.2@214.902,288.068 216.373,288.068 216.707,288.402 U24_SPI_bridge_Main.8@217.232,288.402
NetR603_SPI_bridge_PCIe_2: R603_SPI_bridge_PCIe.2 U24_SPI_bridge_PCIe.8 | length 2.2
  L1 w0.12: R603_SPI_bridge_PCIe.2@138.857,379.977 138.857,379.457 139.232,379.082 U24_SPI_bridge_PCIe.8@139.232,377.907
NetR604_SPI_bridge_Main_1: R604_SPI_bridge_Main.1 U25_SPI_bridge_Main.1 | length 2
  L1 w0.12: R604_SPI_bridge_Main.1@185.538,252.123 185.698,252.284 U25_SPI_bridge_Main.1@185.698,254.021
NetR604_SPI_bridge_PCIe_1: R604_SPI_bridge_PCIe.1 U25_SPI_bridge_PCIe.1 | length 2.2
  L1 w0.12: R604_SPI_bridge_PCIe.1@251.666,251.739 251.666,252.314 251.993,252.641 251.993,253.715 U25_SPI_bridge_PCIe.1@251.941,253.767
NetR605_SPI_bridge_Main_2: R605_SPI_bridge_Main.2 U25_SPI_bridge_Main.7 | length 2
  L1 w0.12: R605_SPI_bridge_Main.2@189.416,252.123 189.598,252.306 U25_SPI_bridge_Main.7@189.598,254.021
NetR605_SPI_bridge_PCIe_2: R605_SPI_bridge_PCIe.2 U25_SPI_bridge_PCIe.7 | length 2.2
  L1 w0.12: R605_SPI_bridge_PCIe.2@255.537,251.739 255.537,252.337 255.841,252.641 U25_SPI_bridge_PCIe.7@255.841,253.767
NetR606_SPI_bridge_Main_1: R606_SPI_bridge_Main.1 U25_SPI_bridge_Main.2 | length 2
  L1 w0.12: U25_SPI_bridge_Main.2@186.348,254.021 186.348,252.323 R606_SPI_bridge_Main.1@186.548,252.123
NetR606_SPI_bridge_PCIe_1: R606_SPI_bridge_PCIe.1 U25_SPI_bridge_PCIe.2 | length 2.2
  L1 w0.12: U25_SPI_bridge_PCIe.2@252.591,253.767 252.591,252.69 252.94,252.341 R606_SPI_bridge_PCIe.1@252.94,251.739
NetR612_1: R612.1 U34.29 | length 8.5
  L1 w0.254: U34.29@64.822,237.639 64.822,237.71 64.831,237.72 v26(64.831,239.097)
  L16 w0.254: v26(59.917,241.89) 59.917,241.114 60.285,240.746 60.915,240.746 61.483,240.178 64.683,240.178 64.831,240.029 v26(64.831,239.097)
NetR614_1: R614.1 U34.12 | length 6.9
  L1 w0.254: R614.1@59.692,230.712 63.088,230.712 64.11,231.734 64.666,231.734 64.815,231.882 64.815,232.984 64.82,232.989 64.82,233.137 U34.12@64.822,233.139
NetR621_1: R621.1 U37.29 | length 1.6
  L1 w0.254: R621.1@65.137,183.369 65.116,183.348 65.116,182.714 65.175,182.655 U37.29@65.175,181.817
NetR622_1: R622.1 U37.12 | length 1.4
  L1 w0.254: R622.1@65.175,175.893 U37.12@65.175,177.317
NetR628_1: R628.1 U38.12 | length 8.1
  L1 w0.254: v2(63.453,203.556) U38.12@63.453,204.214 ; R628.1@69.132,200.683 v2(69.132,201.631)
  L3 (Sign) w0.254: v2(63.453,203.556) 67.207,203.556 v2@69.138,201.625
NetR644_1: R644.1 R645.2 U69.9 | length 4.6
  L1 w0.2: U69.9@130.28,234.418 130.732,234.418 131.053,234.097 131.053,233.213 131.407,232.859 R644.1@132.588,232.859 R645.2@133.706,232.859
NetR648_1: R648.1 T25.3
NetR649_2: R649.2 T26.3 | length 2.4
  L1 w0.5: R649.2@207.162,159.136 207.162,161.348 T26.3@207.264,161.45
NetR650_2: R650.2 T23.1 T24.3 | length 7.7
  L1 w0.5: T24.3@203.34,169.146 203.41,169.217 v2(203.41,170.155) ; v1(207.261,170.383) 207.88,171.002 T23.1@208.189,171.002 208.501,171.314 R650.2@208.501,172.453
  L3 (Sign) w0.5: v2(203.41,170.155) 203.639,170.383 v1(207.261,170.383)
NetR651_1: R651.1 T27.1 T28.3 | length 7.3
  L1 w0.5: R651.1@199.238,172.492 199.289,172.441 v2(200.215,172.441) 200.111,172.337 T27.1@200.111,171.028 ; T28.3@203.327,174.137 v2(203.327,174.866)
  L3 (Sign) w0.5: v2(200.215,172.441) 200.901,172.441 v2(203.327,174.866)
NetR653_2: R653.2 T30.3 | length 4.4
  L1 w0.5: T30.3@199.339,174.236 200.06,173.515 201.917,173.515 R653.2@202.966,172.467
NetR655_1: R655.1 T29.1 | length 2.3
  L1 w0.5: R655.1@202.489,164.999 202.489,164.943 202.489,164.06 203.22,163.329 T29.1@203.579,163.329
NetR657_2: R657.2 T31.3 | length 1.5
  L16 w0.5: T31.3@201.435,173.934 201.478,173.89 R657.2@201.478,172.467
NetR658_1: R658.1 T31.1 | length 2.2
  L16 w0.2: T31.1@200.485,175.902 200.527,175.902 201.656,177.031 R658.1@201.656,177.56
NetR665_2: R665.2 U65.13 | length 2.9
  L1 w0.254: U65.13@38.76,206.158 38.76,207.602 39.014,207.856 R665.2@39.014,208.928
NetR677_1: R677.1 R682.2 U48.6 | length 2.9
  L1 w0.2: R677.1@44.716,192.933 R682.2@45.775,192.933 45.914,192.933 46.214,193.233 U48.6@47.527,193.233
NetR678_1: R678.1 R683.2 U48.5 | length 5.6
  L1 w0.2: R683.2@42.6,192.933 R678.1@43.658,192.933 43.658,193.501 43.89,193.733 U48.5@47.527,193.733
NetR679_1: R679.1 R684.2 U48.3 | length 2.9
  L1 w0.2: R684.2@44.716,195.033 R679.1@45.775,195.033 46.075,194.733 U48.3@47.527,194.733
NetR680_1: R680.1 R685.2 U48.4 | length 5.6
  L1 w0.2: R685.2@42.6,195.033 R680.1@43.658,195.033 43.658,194.466 43.89,194.233 U48.4@47.527,194.233
NetR681_2: R681.2 U48.10 | length 1.4
  L1 w0.2: U48.10@49.827,193.733 50.729,193.733 R681.2@51.105,194.109
NetR686_1: R686.1 U38.29 | length 0.6
  L1 w0.254: U38.29@63.453,208.714 v2@63.453,209.276
  other v2: 63.449,209.276
NetR689_2: R689.2 R690.2 U73.7 | length 10.7
  L1 w0.2: U73.7@151.644,349.484 153.033,349.484 v2(153.035,349.482)
  L1 w0.3: R690.2@159.652,348.062 160.213,348.062 ; v2(160.213,348.729) 160.213,348.062 ; R689.2@160.795,348.062 160.213,348.062
  L3 (Sign) w0.2: v2(153.035,349.482) v2@153.035,349.491
  L3 (Sign) w0.3: v2@153.035,349.491 153.797,348.729 v2(160.213,348.729)
NetR692_2: R692.2 S6.3 S6.4
NetR710_1: R710.1 R711.1 R712.2
NetR711_2: R711.2 U76.4
NetR713_1: R713.1 S7.1 S7.2
NetR714_2: R714.2 S7.3 S7.4
NetR738_2: R738.2 R739.2 U35_I2C_Expander_PWR_CLK.13
NetR740_2: R740.2 R741.2 U35_I2C_Expander_PWR_CLK.12
NetR742_2: R742.2 R743.2 U35_I2C_Expander_PWR_CLK.11
NetR749_1: R749.1 U35_I2C_Expander_Main_Rst.20 | length 2.9
  L16 w0.2: U35_I2C_Expander_Main_Rst.20@114.298,264.843 114.298,267.646 R749.1@114.383,267.731
NetR750_1: R750.1 U35_I2C_Expander_Main_Rst.21 | length 3.1
  L16 w0.2: U35_I2C_Expander_Main_Rst.21@114.948,264.843 114.948,265.722 115.481,266.255 R750.1@115.481,267.731
NetR751_1: R751.1 U35_I2C_Expander_Main_Rst.22 | length 4.8
  L16 w0.2: U35_I2C_Expander_Main_Rst.22@115.873,263.918 116.648,263.918 117.78,265.049 R751.1@120.169,265.049
NetR752_1: R752.1 U35_I2C_Expander_Main_Rst.23 | length 4.6
  L16 w0.2: U35_I2C_Expander_Main_Rst.23@115.873,263.268 116.958,263.268 117.647,263.957 R752.1@120.169,263.957
NetR753_1: R753.1 U3_I2C_Bridge_PCIE.24 U35_I2C_Expander_Main_Rst.25 | length 4.7
  L16 w0.2: U35_I2C_Expander_Main_Rst.25@115.873,261.968 117.544,261.968 118.441,262.865 R753.1@120.169,262.865
NetR754_1: R754.1 U35_I2C_Expander_Main_Rst.26 U35_I2C_Expander_PWR_CLK.14 | length 4.5
  L16 w0.2: U35_I2C_Expander_Main_Rst.26@115.873,261.318 117.935,261.318 118.389,261.772 R754.1@120.169,261.772
NetR758_2: R758.2 R759.1 U35_I2C_Expander_Main_Rst.13 | length 7.4
  L1 w0.2: R759.1@104.583,265.852 105.346,265.852 R758.2@106.108,265.852
  L16 w0.2: v1(105.34,265.849) 105.488,265.849 108.069,263.268 U35_I2C_Expander_Main_Rst.13@110.123,263.268
NetR760_2: R760.2 R761.1 U35_I2C_Expander_Main_Rst.12 | length 7.1
  L1 w0.2: R761.1@104.583,264.358 105.314,264.358 R760.2@106.108,264.358
  L16 w0.2: v1(105.308,264.355) 106.231,264.355 107.968,262.618 U35_I2C_Expander_Main_Rst.12@110.123,262.618
NetR762_2: R762.2 R763.1 U35_I2C_Expander_Main_Rst.11 | length 6.7
  L1 w0.2: R763.1@104.583,262.865 105.314,262.865 R762.2@106.108,262.865
  L16 w0.2: v1(105.308,262.861) 106.253,262.861 107.146,261.968 U35_I2C_Expander_Main_Rst.11@110.123,261.968
NetR768_1: R768.1
NetR769_1: R769.1
NetR770_1: R770.1
NetR771_1: R771.1
NetR860_2: R860.2 U64_U_Pomiar_pradu_napiecia_3.3 | length 95
  L1 w0.2: U64_U_Pomiar_pradu_napiecia_3.3@120.678,183.159 v2(122.047,183.159)
  L5 (Sign) w0.2: v11(121.349,185.684) 130.773,185.684 131.38,186.291 131.38,189.335 137.699,195.653 164.167,195.653 168.696,200.182 175.034,200.182 193.499,218.648 196.583,218.648
  L3 (Sign) w0.2: v11(121.349,185.684) 121.848,185.185 122.047,185.185 v2(122.047,183.159)
NetR862_2: R862.2 U64_U_Pomiar_pradu_napiecia_4.3 | length 104.8
  L1 w0.2: U64_U_Pomiar_pradu_napiecia_4.3@120.907,166.903 v2(122.276,166.903)
  L5 (Sign) w0.2: v11(122.034,170.307) 122.047,170.319 122.047,170.84 122.644,171.437 124.155,171.437 124.895,172.177 124.895,176.241 129.381,180.727 129.381,183.02 132.309,185.947 132.309,188.95 138.112,194.753 164.54,194.753 169.069,199.282 175.406,199.282 193.872,217.748 196.583,217.748
  L3 (Sign) w0.2: v11(122.034,170.307) 122.276,169.997 v2(122.276,166.903)
NetR863_2: R863.2 U64_U_Pomiar_pradu_napiecia_5.3 | length 105.1
  L1 w0.2: U64_U_Pomiar_pradu_napiecia_5.3@118.748,216.393 v2(120.117,216.393)
  L5 (Sign) w0.2: v11(120.117,218.796) 120.117,209.702 133.566,196.253 163.919,196.253 168.448,200.782 174.785,200.782 193.251,219.248 196.583,219.248
  L3 (Sign) w0.2: v2(120.117,216.393) v11(120.117,218.796) 120.117,219.487
NetR864_2: R864.2 U64_U_Pomiar_pradu_napiecia_6.3 | length 96.8
  L1 w0.2: U64_U_Pomiar_pradu_napiecia_6.3@115.141,199.508 v2(116.51,199.508)
  L5 (Sign) w0.2: v11(116.584,202.602) 126.793,202.602 133.442,195.953 164.043,195.953 168.572,200.482 174.909,200.482 193.375,218.948 196.583,218.948
  L3 (Sign) w0.2: v2(116.51,199.508) 116.51,202.602 v11(116.584,202.602)
NetR865_2: R865.2 U18.A3
NetR866_2: R866.2 U72.3
NetR887_SPI_bridge_Main_2: R887_SPI_bridge_Main.2 U25_SPI_bridge_Main.8 | length 2
  L1 w0.12: 190.248,252.872 U25_SPI_bridge_Main.8@190.248,254.021 ; 190.248,252.872 190.248,252.363 R887_SPI_bridge_Main.2@190.488,252.123
NetR887_SPI_bridge_PCIe_2: R887_SPI_bridge_PCIe.2 U25_SPI_bridge_PCIe.8 | length 2.2
  L1 w0.12: U25_SPI_bridge_PCIe.8@256.491,253.767 256.491,252.564 256.891,252.164 R887_SPI_bridge_PCIe.2@256.891,251.739
NetR888_SPI_bridge_Main_1: R888_SPI_bridge_Main.1 U26_SPI_bridge_Main.1 | length 2.5
  L1 w0.12: R888_SPI_bridge_Main.1@69.068,331.84 U26_SPI_bridge_Main.1@71.57,331.84
NetR888_SPI_bridge_PCIe_1: R888_SPI_bridge_PCIe.1 U26_SPI_bridge_PCIe.1 | length 2.3
  L1 w0.12: U26_SPI_bridge_PCIe.1@226.89,377.907 226.89,379.096 227.265,379.471 R888_SPI_bridge_PCIe.1@227.265,380.08
NetR889_SPI_bridge_Main_2: R889_SPI_bridge_Main.2 U26_SPI_bridge_Main.7 | length 2.5
  L1 w0.12: R889_SPI_bridge_Main.2@69.204,328.34 69.444,328.1 70.107,328.1 70.267,327.94 U26_SPI_bridge_Main.7@71.57,327.94
NetR889_SPI_bridge_PCIe_2: R889_SPI_bridge_PCIe.2 U26_SPI_bridge_PCIe.7 | length 2.3
  L1 w0.12: U26_SPI_bridge_PCIe.7@222.99,377.907 222.99,379.296 223.24,379.546 R889_SPI_bridge_PCIe.2@223.24,380.08
NetR890_SPI_bridge_Main_1: R890_SPI_bridge_Main.1 U26_SPI_bridge_Main.2 | length 2.5
  L1 w0.12: R890_SPI_bridge_Main.1@69.254,330.703 69.354,330.803 70.267,330.803 70.667,331.203 71.558,331.203 U26_SPI_bridge_Main.2@71.57,331.19
NetR890_SPI_bridge_PCIe_1: R890_SPI_bridge_PCIe.1 U26_SPI_bridge_PCIe.2 | length 2.3
  L1 w0.12: R890_SPI_bridge_PCIe.1@225.92,380.08 225.92,379.546 226.24,379.226 U26_SPI_bridge_PCIe.2@226.24,377.907
NetR891_SPI_bridge_Main_2: R891_SPI_bridge_Main.2 U26_SPI_bridge_Main.8 | length 2.4
  L1 w0.12: R891_SPI_bridge_Main.2@69.204,327.115 70.143,327.115 70.317,327.29 U26_SPI_bridge_Main.8@71.57,327.29
NetR891_SPI_bridge_PCIe_2: R891_SPI_bridge_PCIe.2 U26_SPI_bridge_PCIe.8 | length 2.3
  L1 w0.12: R891_SPI_bridge_PCIe.2@221.965,380.08 221.965,379.546 222.34,379.171 U26_SPI_bridge_PCIe.8@222.34,377.907
NetR892_SPI_bridge_Main_1: R892_SPI_bridge_Main.1 U27_SPI_bridge_Main.1
NetR892_SPI_bridge_PCIe_1: R892_SPI_bridge_PCIe.1 U27_SPI_bridge_PCIe.1 | length 2.5
  L1 w0.12: U27_SPI_bridge_PCIe.1@61.863,377.907 61.938,377.982 61.938,379.027 62.238,379.327 R892_SPI_bridge_PCIe.1@62.238,380.232
NetR893_SPI_bridge_Main_2: R893_SPI_bridge_Main.2 U27_SPI_bridge_Main.7
NetR893_SPI_bridge_PCIe_2: R893_SPI_bridge_PCIe.2 U27_SPI_bridge_PCIe.7 | length 2.4
  L1 w0.12: U27_SPI_bridge_PCIe.7@57.963,377.907 57.963,378.717 58.229,378.983 R893_SPI_bridge_PCIe.2@58.229,380.232
NetR894_SPI_bridge_Main_1: R894_SPI_bridge_Main.1 U27_SPI_bridge_Main.2
NetR894_SPI_bridge_PCIe_1: R894_SPI_bridge_PCIe.1 U27_SPI_bridge_PCIe.2 | length 2.6
  L1 w0.12: R894_SPI_bridge_PCIe.1@60.563,380.233 60.563,379.512 61.048,379.027 61.048,378.072 U27_SPI_bridge_PCIe.2@61.213,377.907
NetR895_SPI_bridge_Main_2: R895_SPI_bridge_Main.2 U27_SPI_bridge_Main.8
NetR895_SPI_bridge_PCIe_2: R895_SPI_bridge_PCIe.2 U27_SPI_bridge_PCIe.8 | length 2.6
  L1 w0.12: R895_SPI_bridge_PCIe.2@56.733,380.232 56.733,379.012 57.313,378.432 U27_SPI_bridge_PCIe.8@57.313,377.907
NetR896_SPI_bridge_Main_1: R896_SPI_bridge_Main.1 U28_SPI_bridge_Main.1 | length 2.8
  L1 w0.12: U28_SPI_bridge_Main.1@170.769,230.338 172.416,230.338 172.905,229.85 R896_SPI_bridge_Main.1@173.33,229.85
NetR896_SPI_bridge_PCIe_1: R896_SPI_bridge_PCIe.1 U28_SPI_bridge_PCIe.1 | length 2.1
  L1 w0.12: R896_SPI_bridge_PCIe.1@169.964,248.456 169.964,249.17 170.548,249.753 U28_SPI_bridge_PCIe.1@170.548,250.278
NetR897_SPI_bridge_Main_2: R897_SPI_bridge_Main.2 U28_SPI_bridge_Main.7 | length 2.6
  L1 w0.12: U28_SPI_bridge_Main.7@170.769,234.238 R897_SPI_bridge_Main.2@173.33,234.238
NetR897_SPI_bridge_PCIe_2: R897_SPI_bridge_PCIe.2 U28_SPI_bridge_PCIe.7 | length 2
  L1 w0.12: R897_SPI_bridge_PCIe.2@173.938,248.456 173.938,248.911 174.448,249.421 U28_SPI_bridge_PCIe.7@174.448,250.278
NetR898_SPI_bridge_Main_1: R898_SPI_bridge_Main.1 U28_SPI_bridge_Main.2 | length 2.6
  L1 w0.12: U28_SPI_bridge_Main.2@170.769,230.988 R898_SPI_bridge_Main.1@173.33,230.988
NetR898_SPI_bridge_PCIe_1: R898_SPI_bridge_PCIe.1 U28_SPI_bridge_PCIe.2 | length 2
  L1 w0.12: U28_SPI_bridge_PCIe.2@171.198,250.278 171.198,248.981 171.673,248.506 R898_SPI_bridge_PCIe.1@171.673,248.456
NetR899_SPI_bridge_Main_2: R899_SPI_bridge_Main.2 U28_SPI_bridge_Main.8 | length 2.8
  L1 w0.12: U28_SPI_bridge_Main.8@170.769,234.888 172.791,234.888 173.28,235.377 R899_SPI_bridge_Main.2@173.33,235.377
NetR899_SPI_bridge_PCIe_2: R899_SPI_bridge_PCIe.2 U28_SPI_bridge_PCIe.8 | length 2.1
  L1 w0.12: U28_SPI_bridge_PCIe.8@175.098,250.278 175.098,249.114 175.706,248.506 R899_SPI_bridge_PCIe.2@175.706,248.456
NetR901_1: R901.1 U1.H14 | length 93.1
  L1 w0.116: U1.H14@169.397,301.539 v2(169.884,301.052)
  L3 (Sign) w0.12: v2(169.884,301.052) 169.358,301.052 169.023,300.717 168.86,300.717 168.563,300.419 166.373,300.419 166.205,300.252 165.563,300.252 165.507,300.308 160.13,300.308 158.725,298.903 158.725,294.659 154.846,290.78 154.846,290.409 155.068,290.188 155.068,288.284 155.076,288.275 155.076,286.268 162.214,279.13 177.124,279.13 178.559,277.695 217.475,277.695
NetR902_1: R902.1 U1.G14 | length 92.7
  L1 w0.116: U1.G14@168.397,301.539 v2(168.884,301.052)
  L3 (Sign) w0.12: v2(168.884,301.052) 168.472,300.639 166.282,300.639 166.114,300.472 165.654,300.472 165.598,300.528 160.039,300.528 158.505,298.994 158.505,294.75 154.626,290.871 154.626,290.318 154.848,290.097 154.848,288.192 154.856,288.184 154.856,286.177 162.123,278.91 177.033,278.91 178.468,277.475 217.475,277.475
NetR918_1: R918.1 U1.J14 | length 144.5
  L1 w0.116: U1.J14@170.397,301.539 v5(170.884,301.052)
  L1 w0.12: v2(152.705,290.347) 152.825,290.347 153.087,290.61 v2(155.181,290.61)
  L3 (Sign) w0.12: 112.237,291.236 120.454,283.019 128.184,283.019 128.213,283.049 144.071,283.049 144.101,283.019 144.112,283.019 145.011,282.121 146.678,282.121 149.263,284.707 149.263,286.633 151.526,288.896 151.526,289.07 152.239,289.783 152.239,289.882 v2(152.705,290.347) ; v2(155.181,290.61) 158.945,294.374 158.945,298.812 160.221,300.088 165.416,300.088 165.472,300.032 166.296,300.032 166.464,300.199 168.654,300.199 168.952,300.497 169.114,300.497 169.175,300.558 169.786,300.558 169.945,300.717 170.023,300.717 170.029,300.723 170.556,300.723 v5(170.884,301.052)
  L3 (Sign) w0.2: v1(66.561,329.819) 68.199,329.819 103.137,294.881 108.593,294.881 112.237,291.236
  L16 w0.2: v1(66.561,329.819) 66.472,329.819 65.397,330.894 65.397,334.816 66.393,335.812 R918.1@67.43,335.812
NetR918_2: R918.2 U36_U_Translator_I2C4.8 | length 1.4
  L16 w0.2: U36_U_Translator_I2C4.8@67.43,333.56 R918.2@67.43,334.912
NetR919_1: R919.1 U1.J16 | length 146.7
  L1 w0.116: v2(169.909,304.027) U1.J16@170.397,303.539
  L3 (Sign) w0.12: 112.295,291.603 120.572,283.327 144.164,283.327 145.098,282.392 145.499,282.392 145.677,282.57 145.677,282.599 145.873,282.796 146.73,282.796 148.179,284.245 148.179,286.171 151.086,289.078 151.086,289.878 151.328,290.12 151.328,290.269 151.336,290.278 151.336,290.369 151.345,290.378 151.345,290.469 151.353,290.476 151.353,303.588 151.994,304.228 153.708,304.228 154.099,303.837 155.76,303.837 157.552,305.629 159.297,305.629 159.303,305.624 159.35,305.624 159.548,305.426 165.007,305.426 165.913,304.521 168.999,304.521 169.493,304.027 v2(169.909,304.027)
  L3 (Sign) w0.2: v1(66.84,330.797) 67.645,330.797 103.256,295.186 108.712,295.186 112.295,291.603
  L16 w0.2: v1(66.84,330.797) 67.43,330.207 R919.1@67.43,328.267
NetR919_2: R919.2 U36_U_Translator_I2C1.8 | length 1.4
  L16 w0.2: U36_U_Translator_I2C1.8@67.43,325.886 R919.2@67.43,327.317
NetR961_2: R961.2
NetR962_2: R962.2
NetR963_2: R963.2
NetR964_2: R964.2
NetR965_2: R965.2
NetR966_2: R966.2
NetR1004_1: R1004.1 U55.28 | length 3.3
  L1 w0.12: R1004.1@237.471,202.666 237.807,202.666 239.157,204.016 U55.28@240.17,204.016
NetR1005_1: R1005.1 U55.29 | length 5.9
  L1 w0.12: R1005.1@235.16,201.769 237.824,201.769 238.341,202.286 238.341,202.578 239.279,203.516 U55.29@240.17,203.516
NetR1006_1: R1006.1 U55.30 | length 3.8
  L1 w0.12: R1006.1@237.471,200.787 237.592,200.787 238.684,201.879 238.684,202.194 239.505,203.016 U55.30@240.17,203.016
NetR1007_1: R1007.1 U55.32 | length 5.9
  L1 w0.12: R1007.1@235.16,199.885 238.039,199.885 U55.32@240.17,202.016
NetR1008_1: R1008.1 U55.33 | length 5.8
  L1 w0.12: U55.33@241.97,200.216 241.97,197.714 242.252,197.431 R1008.1@242.252,194.487
NetR1009_1: R1009.1 U55.34 | length 8.4
  L1 w0.12: U55.34@242.47,200.216 242.47,198.151 243.154,197.466 R1009.1@243.154,192.101
NetR1012_1: R1012.1 U55.43 | length 6
  L1 w0.12: U55.43@246.97,200.216 246.97,196.946 247.632,196.284 R1012.1@247.632,194.487
NetR1013_1: R1013.1 U55.44 | length 8.5
  L1 w0.12: U55.44@247.47,200.216 247.47,197.348 248.517,196.301 R1013.1@248.517,192.101
NetR1014_1: R1014.1 U55.45 | length 6.3
  L1 w0.12: U55.45@247.97,200.216 247.97,197.667 249.425,196.211 R1014.1@249.425,194.487
NetR1015_1: R1015.1 U55.46 | length 8.9
  L1 w0.12: U55.46@248.47,200.216 248.47,197.897 250.304,196.063 R1015.1@250.304,192.101
NetR1016_1: R1016.1 U55.53 | length 5.2
  L1 w0.12: U55.53@251.27,204.016 252.384,204.016 253.454,202.946 253.454,201.867 253.991,201.329 R1016.1@254.693,201.329
NetR1017_1: R1017.1 U55.54 | length 4.2
  L1 w0.12: U55.54@251.27,204.516 252.394,204.516 254.239,202.671 R1017.1@254.693,202.671
NetR1018_1: R1018.1 U55.55 | length 3.8
  L1 w0.12: U55.55@251.27,205.016 252.691,205.016 253.693,204.013 R1018.1@254.693,204.013
NetR1019_1: R1019.1 U55.57 | length 3.7
  L1 w0.12: U55.57@251.27,206.016 252.657,206.016 253.318,205.355 R1019.1@254.693,205.355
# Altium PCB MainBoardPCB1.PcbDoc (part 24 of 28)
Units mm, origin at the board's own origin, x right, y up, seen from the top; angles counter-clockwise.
Board outline 258.95 x 308.86 mm, 16 copper layers (L1, L2 (GND), L3 (Sign), L4 (GND), L5 (Sign), L6 (PWR/GND), L7(PWR/GND), L8 (Plane_GND), L9 (PWR/GND), L10 (PWR/GND), L11 (PWR/GND), L12 (Sign), L13 (GND), L14 (Sign), L15 (GND), L16), stack 2.502 mm thick; 2397 components, 1744 nets, 8397 pads, 4112 vias.
Unrouted connection lines stored in the file: 3547.

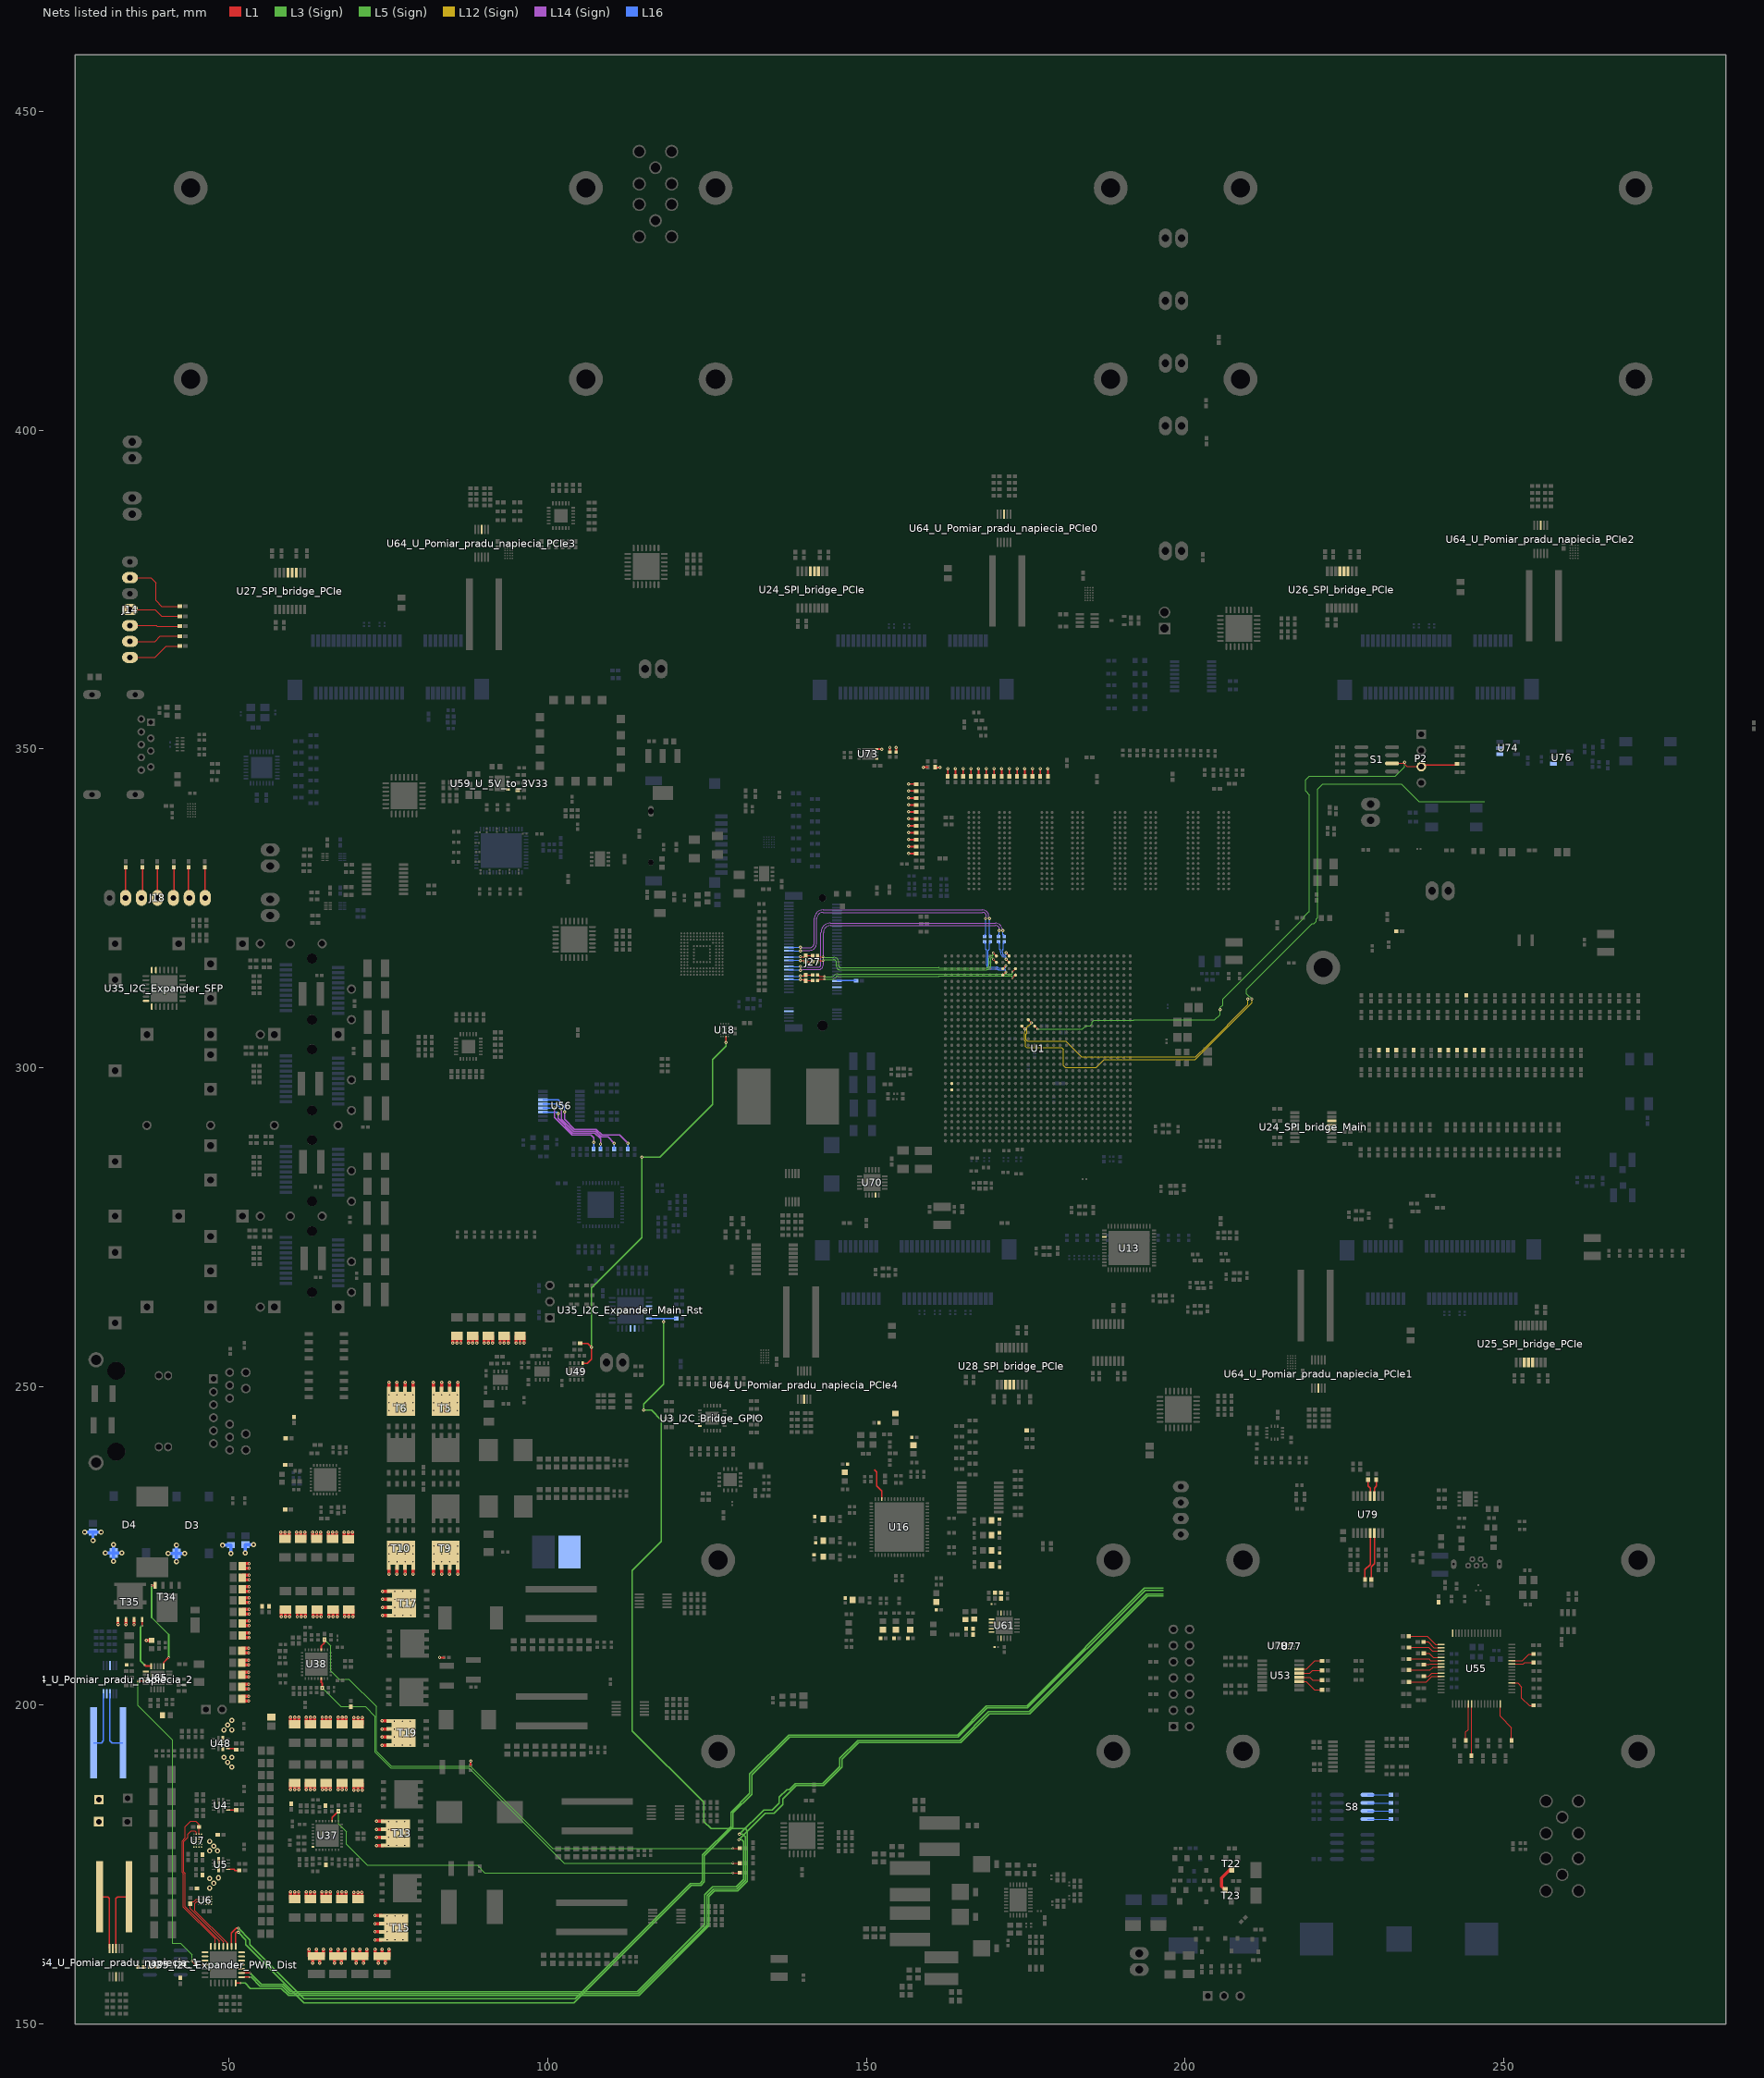
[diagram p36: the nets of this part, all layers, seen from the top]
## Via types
v1: diameter 0.5, hole 0.2, L1 to L16, tented both sides, 1457 vias
v2: diameter 0.35/0/0.35 (per signal layer), hole 0.127, L1 to L3 (Sign), tented both sides, 479 vias
v3: diameter 0.5/0.35/0.35/0.35/0.35/0.35/0.35/0.35/0.35/0.35/0.35/0.35/0.35/0.35/0.35/0.5 (per signal layer), hole 0.15, L1 to L16, tented both sides, 453 vias
v4: diameter 0.5, hole 0.2, L1 to L16, 451 vias
v5: diameter 0.5/0.35/0.35/0.35/0.35/0.35/0.35/0.35/0.35/0.35/0.35/0.35/0.35/0.35/0.35/0.5 (per signal layer), hole 0.2, L1 to L16, tented both sides, 373 vias
v6: diameter 0.8, hole 0.4, L1 to L16, tented both sides, 168 vias
v7: diameter 0.35/0/0.35 (per signal layer), hole 0.127, L1 to L3 (Sign), 138 vias
v8: diameter 2.54, hole 1.02, L1 to L16, 113 vias
v9: diameter 0.5/0/0.5 (per signal layer), hole 0.2, L14 (Sign) to L16, tented both sides, 102 vias
v10: diameter 1.4, hole 0.5, L1 to L16, tented both sides, 80 vias
v11: diameter 0.5, hole 0.2, L3 (Sign) to L6 (PWR/GND), tented both sides, 54 vias
v12: diameter 0.35, hole 0.127, L1 to L2 (GND), tented both sides, 47 vias
v13: diameter 0.4, hole 0.2, L1 to L16, tented both sides, 46 vias
v14: diameter 0.35, hole 0.127, L1 to L16, tented both sides, 16 vias
v15: diameter 0.25, hole 0.2, L1 to L16, 16 vias
v16: diameter 0.5, hole 0.2, L11 (PWR/GND) to L14 (Sign), tented both sides, 16 vias
v17: diameter 0.4, hole 0.2, L1 to L16, 16 vias
v18: diameter 0.3, hole 0.2, L1 to L16, 15 vias
v19: diameter 0.45, hole 0.15, L1 to L16, 12 vias
v20: diameter 0.5/0.35/0.35/0.35/0.35/0.35/0.35/0.35/0.35/0.35/0.35/0.35/0.35/0.35/0.35/0.45 (per signal layer), hole 0.15, L1 to L16, tented both sides, 10 vias
v21: diameter 0.2/0/0.2 (per signal layer), hole 0.1, L1 to L3 (Sign), tented both sides, 9 vias
v22: diameter 0.3, hole 0.127, L14 (Sign) to L16, tented both sides, 8 vias
v23: diameter 0.4, hole 0.1, L1 to L16, 7 vias
v24: diameter 1.15, hole 1.15, L1 to L16, 5 vias
v25: diameter 1.65, hole 1.65, L1 to L16, 5 vias
v26: diameter 0.2, hole 0.1, L1 to L16, 4 vias
v27: diameter 0.4, hole 0.15, L1 to L16, 2 vias
v28: diameter 0.5/0.35/0.35/0.35/0.35/0.35/0.35/0.35/0.35/0.35/0.35/0.35/0.35/0.35/0.35/0.5 (per signal layer), hole 0.15, L1 to L16, 2 vias
v29: diameter 0.35, hole 0.127, L3 (Sign) to L6 (PWR/GND), tented both sides, 2 vias
v30: diameter 0.3, hole 0.127, L15 (GND) to L16, tented both sides, 1 vias
v31: diameter 0.35, hole 0.127, L1 to L2 (GND), 1 vias
v32: diameter 0.5/0.35/0.35/0.35/0.35/0.35/0.35/0.35/0.35/0.35/0.35/0.35/0.35/0.35/0.35/0.5 (per signal layer), hole 0.2, L1 to L16, 1 vias
v33: diameter 0.35/0.35/0.35 (per signal layer), hole 0.127, L1 to L3 (Sign), tented both sides, 1 vias
v34: diameter 0.45/0/0.45 (per signal layer), hole 0.15, L1 to L3 (Sign), tented both sides, 1 vias
v35: diameter 0.45/0/0.45 (per signal layer), hole 0.2, L14 (Sign) to L16, tented both sides, 1 vias

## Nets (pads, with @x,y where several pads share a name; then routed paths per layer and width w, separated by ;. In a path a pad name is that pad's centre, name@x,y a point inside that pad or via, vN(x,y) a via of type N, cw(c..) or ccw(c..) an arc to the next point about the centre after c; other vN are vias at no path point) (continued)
NetR1020_1: R1020.1 U55.58 | length 3.5
  L1 w0.12: U55.58@251.27,206.516 253.123,206.516 253.304,206.697 R1020.1@254.693,206.697
NetR1021_1: R1021.1 U55.59 | length 3.8
  L1 w0.12: U55.59@251.27,207.016 252.938,207.016 253.961,208.039 R1021.1@254.693,208.039
NetR1022_2: R1022.2 U79.5 | length 7.6
  L1 w0.2: R1022.2@228.223,219.74 228.223,221.267 229.048,222.092 U79.5@229.048,227.025
NetR1023_1: R1023.1 U79.12 | length 2.7
  L1 w0.2: R1023.1@228.723,235.397 228.723,234.411 229.048,234.086 U79.12@229.048,232.825
NetR1024_2: R1024.2 U79.6 | length 7.5
  L1 w0.2: R1024.2@229.223,219.74 229.223,221.756 229.71,222.243 229.71,227.013 U79.6@229.698,227.025
NetR1025_1: R1025.1 U79.11 | length 2.7
  L1 w0.2: U79.11@229.698,232.825 229.698,234.086 230.01,234.398 R1025.1@230.01,235.401
NetR1026_1: R1026.1 U53.14 | length 4.1
  L1 w0.12: U53.14@217.924,205.683 219.072,205.683 220.372,206.983 R1026.1@221.513,206.983
NetR1027_1: R1027.1 U53.13 | length 3.8
  L1 w0.12: U53.13@217.924,205.033 219.594,205.033 220.028,205.466 R1027.1@221.513,205.466
NetR1028_1: R1028.1 U53.12 | length 3.8
  L1 w0.12: U53.12@217.924,204.383 219.591,204.383 220.024,203.95 R1028.1@221.513,203.95
NetR1029_1: R1029.1 U53.11 | length 4.1
  L1 w0.12: U53.11@217.924,203.733 219.034,203.733 220.334,202.433 R1029.1@221.513,202.433
NetR1030_1: R1030.1 U55.16
NetR1031_1: R1031.1 U55.17 | length 5.6
  L1 w0.12: R1031.1@235.097,210.844 237.999,210.844 239.328,209.516 U55.17@240.17,209.516
NetR1032_1: R1032.1 U55.18 | length 3.1
  L1 w0.12: R1032.1@237.433,209.955 238.113,209.955 239.053,209.016 U55.18@240.17,209.016
NetR1033_1: R1033.1 U55.19 | length 5.3
  L1 w0.12: R1033.1@235.122,209.066 238.24,209.066 238.791,208.516 U55.19@240.17,208.516
NetR1034_1: R1034.1 U55.21 | length 3
  L1 w0.12: R1034.1@237.459,208.152 238.275,208.152 238.911,207.516 U55.21@240.17,207.516
NetR1035_1: R1035.1 U55.22 | length 5.1
  L1 w0.12: R1035.1@235.135,207.263 238.266,207.263 238.513,207.016 U55.22@240.17,207.016
NetR1036_1: R1036.1 U55.23 | length 2.8
  L1 w0.12: R1036.1@237.471,206.387 238.289,206.387 238.418,206.516 U55.23@240.17,206.516
NetR1037_1: R1037.1 U55.24 | length 5.2
  L1 w0.12: R1037.1@235.16,205.536 238.454,205.536 238.934,206.016 U55.24@240.17,206.016
NetR1038_1: R1038.1 U55.26 | length 2.9
  L1 w0.12: R1038.1@237.471,204.545 238.226,204.545 238.696,205.016 U55.26@240.17,205.016
NetR1039_1: R1039.1 U55.27 | length 5.4
  L1 w0.12: R1039.1@235.16,203.652 237.828,203.652 238.692,204.516 U55.27@240.17,204.516
NetR1040_2: R1040.2 U56.14 | length 18.3
  L14 (Sign) w0.2: v9(102.629,293.116) 102.629,291.909 104.167,290.371 107.619,290.371 108.545,289.446 111.29,289.446 v9(112.56,288.176)
  L16 w0.2: U56.14@99.259,294.98 101.624,294.98 102.629,293.975 v9(102.629,293.116) ; v9(112.56,288.176) 112.563,288.172 R1040.2@112.563,287.237
NetR1041_2: R1041.2 U56.13 | length 15.6
  L14 (Sign) w0.2: v9(102.159,293.505) 102.159,291.955 104.042,290.071 107.495,290.071 108.42,289.146 109.439,289.146 110.422,288.163 v9(110.401,288.163)
  L16 w0.2: U56.13@99.259,294.33 101.334,294.33 v9(102.159,293.505) ; v9(110.401,288.163) 110.401,287.259 R1041.2@110.424,287.237
NetR1042_2: R1042.2 U56.12 | length 12.6
  L14 (Sign) w0.2: v9(101.041,293.7) 101.041,292.224 103.794,289.471 106.782,289.471 107.214,289.038 v9(107.214,288.28)
  L16 w0.2: U56.12@99.259,293.68 101.063,293.68 101.083,293.7 v9(101.041,293.7) ; R1042.2@107.214,287.237 v9(107.214,288.28)
NetR1043_2: R1043.2 U56.11 | length 12.8
  L14 (Sign) w0.2: v9(101.638,292.811) 101.638,292.051 103.918,289.771 107.371,289.771 108.28,288.861 v9(108.28,287.998)
  L16 w0.2: U56.11@99.259,293.03 101.419,293.03 v9(101.638,292.811) v9@101.638,292.798 ; v9(108.28,287.998) 108.284,287.994 R1043.2@108.284,287.237
NetR1044_1: R1044.1 U55.38 | length 5.9
  L1 w0.12: R1044.1@244.046,194.487 244.046,195.793 244.47,196.217 U55.38@244.47,200.216
NetR1045_1: R1045.1 U55.39 | length 8.1
  L1 w0.12: R1045.1@244.942,192.101 244.97,192.129 U55.39@244.97,200.216
NetR1046_1: R1046.1 U55.48 | length 6.5
  L1 w0.12: U55.48@249.47,200.216 249.47,198.264 251.219,196.515 R1046.1@251.219,194.487
NetR1047_1: R1047.1 U55.52 | length 5.9
  L1 w0.12: U55.52@251.27,203.516 252.198,203.516 252.832,202.882 252.832,201.153 253.997,199.987 R1047.1@254.693,199.987
NetR1048_2: R1048.2 S8.8 | length 3.7
  L16 w0.12: S8.8@228.629,182.148 R1048.2@232.307,182.148
NetR1049_2: R1049.2 S8.7 | length 3.7
  L16 w0.12: S8.7@228.629,183.418 R1049.2@232.307,183.418
NetR1050_2: R1050.2 S8.6 | length 3.7
  L16 w0.12: S8.6@228.629,184.688 R1050.2@232.307,184.688
NetR1051_2: R1051.2 S8.5 | length 3.7
  L16 w0.12: S8.5@228.629,185.958 232.257,185.958 R1051.2@232.307,185.958
NetR1052_1: R1052.1 U6.A4
NetR1053_1: R1053.1 U7.A4
NetT22_3: T22.3 T23.2 | length 4.3
  L1 w0.5: T23.2@206.289,171.002 205.715,171.576 205.715,172.923 207.028,174.236 T22.3@207.327,174.236
NetT34_4: T34.4 U65.11 | length 14.6
  L1 w0.254: v2(37.846,218.796) 37.85,218.791 T34.4@38.377,218.791 ; U65.11@39.76,206.158 39.76,206.746 v2@40.514,207.5
  L3 (Sign) w0.254: v2(37.846,218.796) 37.846,213.779 40.526,211.099 v2(40.526,207.488)
NetT35_4: T35.4 U65.15 | length 8.6
  L1 w0.254: v2(36.36,212.471) T35.4@36.36,213.464 ; v2(36.71,206.368) 36.92,206.158 U65.15@37.76,206.158
  L3 (Sign) w0.254: v2(36.36,212.471) 36.093,212.204 36.093,206.985 v2(36.71,206.368)
NetTP7_I2C_Bridge_GPIO_1: U3_I2C_Bridge_GPIO.24 U35_I2C_Expander_Main_Rst.3
NetU1_B9: U1.B9
NetU1_B10: U1.B10
NetU13_43: U13.43
NetU24_SPI_bridge_Main_12: U24_SPI_bridge_Main.12 U24_SPI_bridge_PCIe.5 U25_SPI_bridge_PCIe.5 U26_SPI_bridge_PCIe.5 U27_SPI_bridge_PCIe.5 U28_SPI_bridge_PCIe.5
NetU24_SPI_bridge_Main_13: U24_SPI_bridge_Main.13 U24_SPI_bridge_PCIe.4 U25_SPI_bridge_PCIe.4 U26_SPI_bridge_PCIe.4 U27_SPI_bridge_PCIe.4 U28_SPI_bridge_PCIe.4
NetU24_SPI_bridge_Main_14: U24_SPI_bridge_Main.14 U24_SPI_bridge_PCIe.3 U25_SPI_bridge_PCIe.3 U26_SPI_bridge_PCIe.3 U27_SPI_bridge_PCIe.3 U28_SPI_bridge_PCIe.3
NetU35_I2C_Expander_Main_Rst_4: U35_I2C_Expander_Main_Rst.4
NetU35_I2C_Expander_Main_Rst_24: U35_I2C_Expander_Main_Rst.24
NetU35_I2C_Expander_PWR_CLK_2: U35_I2C_Expander_PWR_CLK.2
NetU35_I2C_Expander_PWR_CLK_3: U35_I2C_Expander_PWR_CLK.3
NetU35_I2C_Expander_PWR_CLK_4: U35_I2C_Expander_PWR_CLK.4
NetU35_I2C_Expander_PWR_Dist_1: U35_I2C_Expander_PWR_Dist.1
NetU35_I2C_Expander_PWR_Dist_2: U35_I2C_Expander_PWR_Dist.2
NetU35_I2C_Expander_PWR_Dist_3: U35_I2C_Expander_PWR_Dist.3
NetU35_I2C_Expander_PWR_Dist_17: U35_I2C_Expander_PWR_Dist.17
NetU35_I2C_Expander_PWR_Dist_18: U35_I2C_Expander_PWR_Dist.18
NetU35_I2C_Expander_PWR_Dist_28: U35_I2C_Expander_PWR_Dist.28
NetU35_I2C_Expander_SFP_1: U35_I2C_Expander_SFP.1
NetU35_I2C_Expander_SFP_20: U35_I2C_Expander_SFP.20
NetU35_I2C_Expander_SFP_21: U35_I2C_Expander_SFP.21
NetU35_I2C_Expander_SFP_28: U35_I2C_Expander_SFP.28
NVME_C_RX_1_N: C718.1 U1.K28 | length 7.8
  L1 w0.116: U1.K28@171.397,315.539 v5(171.884,316.027)
  L16 w0.063: 169.287,318.539 ccw(c169.287,318.381) 169.128,318.381 169.128,316.088 ccw(c169.418,316.088) 169.418,315.798 170.389,315.798 cw(c170.389,315.322) 170.726,315.659 171.679,315.659 ccw(c171.679,315.864) 171.884,315.864 v5(171.884,316.027)
  L16 w0.081: 169.287,318.539 169.287,319.483 ccw(c169.287,319.647) 169.451,319.647 C718.1@169.451,319.799
NVME_C_RX_1_P: C717.1 U1.K27 | length 8.2
  L1 w0.116: U1.K27@171.397,314.539 v5(171.884,315.027)
  L16 w0.063: 168.706,318.539 cw(c168.706,318.381) 168.865,318.381 168.865,316.088 ccw(c169.418,316.088) 169.418,315.535 170.379,315.535 cw(c170.379,315.296) 170.547,315.465 ccw(c170.716,315.633) 170.716,315.395 171.679,315.395 cw(c171.679,315.189) 171.884,315.189 v5(171.884,315.027)
  L16 w0.081: C717.1@168.542,319.799 168.542,319.647 ccw(c168.706,319.647) 168.706,319.483 168.706,318.539
NVME_C_RX_O_N: C677.1 U1.M28 | length 31.9
  L1 w0.081: C677.1@142.334,314.574 142.41,314.574 cw(c142.41,314.334) 142.65,314.334 v2(143.446,314.334)
  L1 w0.116: v2(172.909,315.052) U1.M28@173.397,315.539
  L3 (Sign) w0.076: 161.397,314.742 161.397,314.69 172.733,314.69 ccw(c172.733,314.867) 172.909,314.867 v2(172.909,315.052)
  L3 (Sign) w0.08: v2(143.446,314.334) ccw(c143.482,314.334) 143.482,314.298 144.463,314.298 ccw(c144.463,314.959) 144.931,314.492 144.932,314.493 cw(c145.532,313.892) 145.532,314.742 161.397,314.742
NVME_C_RX_O_P: C653.1 U1.M27 | length 31.9
  L1 w0.081: C653.1@142.334,313.674 142.44,313.674 ccw(c142.44,313.884) 142.65,313.884 v2(143.446,313.884)
  L1 w0.116: v2(172.909,314.052) U1.M27@173.397,314.539
  L3 (Sign) w0.076: 161.397,314.362 161.397,314.414 172.733,314.414 cw(c172.733,314.237) 172.909,314.237 v2(172.909,314.052)
  L3 (Sign) w0.08: v2(143.446,313.884) cw(c143.482,313.884) 143.482,313.919 144.464,313.919 ccw(c144.464,314.957) 145.198,314.223 ; 145.199,314.223 cw(c145.534,313.889) 145.534,314.362 161.397,314.362
NVME_C_TX_1_N: C716.1 U1.J30 | length 31.6
  L1 w0.081: C716.1@142.334,317.575 142.494,317.415 v2(143.18,317.415)
  L1 w0.116: v2(169.909,318.027) U1.J30@170.397,317.539
  L3 (Sign) w0.076: 161.345,315.723 cw(c161.345,315.671) 161.397,315.671 168.859,315.671 ccw(c168.859,316.056) 169.244,316.056 169.244,317.14 cw(c169.718,317.14) 169.718,317.614 169.727,317.614 ccw(c169.727,317.797) 169.909,317.797 v2(169.909,318.027)
  L3 (Sign) w0.08: 161.345,315.723 145.922,315.723 cw(c145.922,315.963) 145.682,315.963 145.682,316.521 ccw(c144.888,316.521) 144.888,317.314 v2@143.28,317.314 ; v2@143.28,317.314 cw(c143.28,317.415) v2(143.18,317.415) ccw(c143.28,317.415) v2@143.28,317.314
NVME_C_TX_1_P: C715.1 U1.J29 | length 31.5
  L1 w0.081: C715.1@142.334,316.674 142.494,316.834 v2(143.18,316.834)
  L1 w0.116: v2(169.909,317.027) U1.J29@170.397,316.539
  L3 (Sign) w0.076: 161.345,315.343 ccw(c161.345,315.396) 161.397,315.396 168.859,315.396 ccw(c168.859,316.056) 169.52,316.056 169.52,317.14 cw(c169.718,317.14) 169.718,317.339 169.727,317.339 cw(c169.727,317.156) 169.909,317.156 v2(169.909,317.027)
  L3 (Sign) w0.08: 161.345,315.343 145.922,315.343 cw(c145.922,315.963) 145.302,315.963 145.302,316.521 ccw(c144.888,316.521) 144.888,316.935 v2@143.28,316.935 ; v2@143.28,316.935 ccw(c143.28,316.834) v2(143.18,316.834) cw(c143.28,316.834) v2@143.28,316.935
NVME_C_TX_O_N: C651.1 U1.L30 | length 3.8
  L1 w0.116: v1(171.909,318.027) U1.L30@172.397,317.539
  L16 w0.063: 171.471,318.539 171.425,318.539 ccw(c171.425,318.427) 171.312,318.427 171.312,318.12 ccw(c171.78,318.12) 171.78,317.652 ccw(c171.78,317.782) 171.909,317.782 v1(171.909,318.027)
  L16 w0.081: 171.471,318.539 171.471,319.483 ccw(c171.471,319.647) 171.635,319.647 C651.1@171.635,319.799
NVME_C_TX_O_P: C649.1 U1.L29 | length 4.2
  L1 w0.116: v1(171.909,317.027) U1.L29@172.397,316.539
  L16 w0.063: 170.89,318.539 170.937,318.539 cw(c170.937,318.427) 171.049,318.427 171.049,318.12 ccw(c171.78,318.12) 171.78,317.389 cw(c171.78,317.26) 171.909,317.26 v1(171.909,317.027)
  L16 w0.081: C649.1@170.726,319.799 170.726,319.647 ccw(c170.89,319.647) 170.89,319.483 170.89,318.539
NVMe_Rx_0_N: C677.2 J27.47 R541.2 | length 3.8
  L1 w0.081: v1(139.624,314.424) 140.121,314.424 cw(c140.271,314.424) 140.271,314.574 R541.2@140.462,314.574 C677.2@141.554,314.574
  L16 w0.081: J27.47@137.843,314.374 139.574,314.374 ccw(c139.574,314.424) v1(139.624,314.424)
NVMe_Rx_0_P: C653.2 J27.49 R541.1 | length 3.8
  L1 w0.081: v1(139.624,313.824) 140.121,313.824 ccw(c140.271,313.824) 140.271,313.674 R541.1@140.462,313.674 C653.2@141.554,313.674
  L16 w0.081: J27.49@137.843,313.874 139.574,313.874 cw(c139.574,313.824) v1(139.624,313.824)
NVMe_Rx_1_N: C716.2 J27.35 R542.2 | length 3.8
  L1 w0.081: v1(139.636,317.425) 140.312,317.425 R542.2@140.462,317.575 C716.2@141.554,317.575
  L16 w0.081: J27.35@137.843,317.374 139.586,317.374 v1(139.636,317.425)
NVMe_Rx_1_P: C715.2 J27.37 R542.1 | length 3.8
  L1 w0.081: v1(139.636,316.825) 140.312,316.825 R542.1@140.462,316.674 C715.2@141.554,316.674
  L16 w0.081: J27.37@137.843,316.874 139.587,316.874 v1(139.636,316.825)
NVMe_Tx_0_N: C651.2 J27.41 | length 41.5
  L14 (Sign) w0.08: v9(139.636,315.908) ccw(c139.747,315.908) 139.747,315.798 140.233,315.798 142.507,315.798 ccw(c142.507,316.154) 142.862,316.154 142.862,321.196 cw(c144.346,321.196) 144.346,322.68 159.46,322.68 170.243,322.68 cw(c170.243,321.601) 171.322,321.601 ccw(c171.371,321.601) 171.371,321.551 v9(171.432,321.551)
  L16 w0.08: v9@139.602,315.874 ccw(c139.602,315.908) v9(139.636,315.908) ; 171.432,320.894 v9(171.432,321.551)
  L16 w0.081: J27.41@137.843,315.874 v9@139.602,315.874 ; 171.432,320.894 cw(c171.432,320.691) 171.635,320.691 C651.2@171.635,320.579
NVMe_Tx_0_P: C649.2 J27.43 | length 40.9
  L14 (Sign) w0.08: v9(139.636,315.308) cw(c139.747,315.308) 139.747,315.418 140.233,315.418 142.507,315.418 ccw(c142.507,316.154) 143.242,316.154 143.242,321.196 cw(c144.346,321.196) 144.346,322.3 159.46,322.3 170.243,322.3 cw(c170.243,321.601) 170.942,321.601 cw(c170.892,321.601) 170.892,321.551 v9(170.832,321.551)
  L16 w0.08: v9@139.571,315.374 cw(c139.571,315.308) v9(139.636,315.308) ; 170.726,320.894 ccw(c170.726,321) 170.832,321 v9(170.832,321.551)
  L16 w0.081: J27.43@137.843,315.374 v9@139.571,315.374 ; C649.2@170.726,320.579 170.726,320.894
NVMe_Tx_1_N: C718.2 J27.29 | length 40.4
  L14 (Sign) w0.08: v9(139.636,318.924) ccw(c139.747,318.924) 139.747,318.814 140.195,318.814 141.09,318.814 ccw(c141.09,319.545) 141.821,319.545 141.821,323.393 cw(c143.191,323.393) 143.191,324.763 157.416,324.763 168.237,324.763 cw(c168.237,323.814) 169.186,323.814 169.186,323.541 ccw(c169.296,323.541) v9(169.296,323.431)
  L16 w0.081: J27.29@137.843,318.874 138.618,318.874 ccw(c138.618,318.914) 138.659,318.914 139.636,318.914 v9(139.636,318.924) ; v9(169.296,323.431) 169.287,323.431 169.287,320.894 cw(c169.287,320.73) 169.451,320.73 C718.2@169.451,320.579
NVMe_Tx_1_P: C717.2 J27.31 | length 39.8
  L14 (Sign) w0.08: v9(139.636,318.324) cw(c139.747,318.324) 139.747,318.434 140.195,318.434 141.09,318.434 ccw(c141.09,319.545) 142.201,319.545 142.201,323.393 cw(c143.191,323.393) 143.191,324.383 157.416,324.383 168.237,324.383 cw(c168.237,323.814) 168.806,323.814 168.806,323.541 cw(c168.696,323.541) v9(168.696,323.431)
  L16 w0.081: J27.31@137.843,318.374 138.618,318.374 cw(c138.618,318.333) 138.659,318.333 139.636,318.333 v9(139.636,318.324) ; C717.2@168.542,320.579 168.542,320.73 cw(c168.706,320.73) 168.706,320.894 168.706,323.431 v9(168.696,323.431)
OSC_500Out: C333.2 X2.10
Osc_in_Si53323_2_N: C343.2 R259.2 R261.2 R489.1 U32.6 | length 5
  L1 w0.081: C343.2@55.918,527.503 56.136,527.721 56.136,529.301 R259.2@55.91,529.526 56.133,529.75 56.133,530.538 R489.1@55.976,530.695 ; R489.1@56.111,530.72 56.111,531.751 ccw(c56.111,531.794) 56.154,531.794 U32.6@56.154,532.192
Osc_in_Si53323_2_P: C342.2 R260.2 R262.2 R489.2 U32.7 | length 5
  L1 w0.081: U32.7@56.654,532.192 56.654,531.794 ccw(c56.697,531.794) 56.697,531.751 R489.2@56.697,530.72 ; R489.2@56.876,530.695 56.719,530.538 56.719,529.755 R260.2@56.947,529.526 56.721,529.301 56.721,527.7 C342.2@56.918,527.503
OSC_Out_DIV_N: C343.1 R258.1 U33.11 | length 2.5
  L1 w0.081: C343.1@55.918,526.724 56.125,526.516 U33.11@56.125,524.319
OSC_Out_DIV_P: C342.1 R256.2 U33.10 | length 2.5
  L1 w0.081: U33.10@56.71,524.319 56.71,525.716 56.71,526.516 C342.1@56.918,526.724
P4HS_PowerAlert_Pcie0: R530.2 U64_U_Pomiar_pradu_napiecia_PCIe0.3
P4HS_PowerAlert_Pcie1: R547.2 U64_U_Pomiar_pradu_napiecia_PCIe1.3
P4HS_PowerAlert_Pcie2: R550.2 U64_U_Pomiar_pradu_napiecia_PCIe2.3
P4HS_PowerAlert_Pcie3: R553.2 U64_U_Pomiar_pradu_napiecia_PCIe3.3
P4HS_PowerAlert_Pcie4: R556.2 U64_U_Pomiar_pradu_napiecia_PCIe4.3
PCIe_Reset: J27.50 R788.1 | length 3
  L16 w0.2: J27.50@145.393,313.624 145.434,313.665 R788.1@148.399,313.665
PDN: R498.1 U16.46 | length 5.1
  L1 w0.2: 151.244,236.931 151.587,236.588 151.587,234.417 152.415,233.589 U16.46@152.415,232.345
PEDET: J27.61
PEwake: J27.54
PG1_1: R295.2 R835.1 U37.27 | length 71.3
  L1 w0.12: v7(129.057,173.721) R835.1@130.157,173.721
  L1 w0.254: U37.27@66.175,181.817 66.175,182.406 v7(67.169,183.4)
  L3 (Sign) w0.12: v7(67.169,183.4) 67.169,181.39 68.437,180.123 68.437,178.175 71.7,174.912 88.932,174.912 90.123,173.721 v7(129.057,173.721)
PG1_2: R313.2 R838.1 U38.27 | length 87
  L1 w0.12: v7(129.057,177.521) 130.107,177.521 R838.1@130.157,177.571
  L1 w0.254: U38.27@64.453,208.714 64.453,209.276 64.953,209.776 v7(64.953,210.304)
  L3 (Sign) w0.12: v7(64.953,210.304) 65.953,209.304 65.953,205.434 67.264,204.124 68.786,204.124 73.127,199.782 73.127,192.758 75.426,190.46 87.857,190.46 100.796,177.521 v7(129.057,177.521)
PG1_TPS7A8801: R440.1 U35_I2C_Expander_PWR_CLK.28 U61.17
PG2_2: R314.2 R836.1 U38.14 | length 81.8
  L1 w0.12: v7(129.057,175.235) 130.143,175.235 R836.1@130.157,175.221
  L1 w0.254: U38.14@64.453,204.214 64.455,204.212 64.455,203.6 64.623,203.432 v7(64.623,202.723)
  L3 (Sign) w0.12: v7(64.623,202.723) 67.565,199.782 71.377,199.782 72.907,198.252 72.907,192.667 75.375,190.2 87.649,190.2 102.614,175.235 v7(129.057,175.235)
PG2_TPS7A8801: R441.1 U35_I2C_Expander_PWR_CLK.1 U61.9
PG2_TPS7A8801_0V9: R676.1 U37.8 U70.9 U73.5
PG_2V5@1.5A: R392.1 U18.A2 U49.5 | length 64.7
  L1 w0.2: R392.1@105.069,256.769 106.261,256.769 v4(106.845,256.184) 106.845,254.308 106.185,253.648 U49.5@105.47,253.648 ; v1(127.953,303.987) U18.A2@127.953,304.908
  L5 (Sign) w0.2: v11(114.757,285.966) 117.594,285.966 125.87,294.241 125.87,301.308 127.953,303.39 v1(127.953,303.987)
  L3 (Sign) w0.2: v4(106.845,256.184) 106.845,265.474 114.757,273.386 v11(114.757,285.966)
PG_48_20V: R828.2 U35_I2C_Expander_PWR_Dist.4 U65.19 | length 51.8
  L1 w0.12: v7(44.183,159.841) 44.195,159.841 44.733,159.303 U35_I2C_Expander_PWR_Dist.4@46.218,159.303
  L1 w0.254: v2(35.671,203.818) U65.19@36.92,203.818
  L3 (Sign) w0.12: v2(35.671,203.818) 35.671,199.936 41.048,194.559 41.048,162.712 42.367,162.712 44.183,160.896 v7(44.183,159.841)
PG_LT3042: R442.1 U35_I2C_Expander_PWR_CLK.25 U62.4
PG_PS_LTC6952_1: R431_U_5V_to_3V33.1 U35_I2C_Expander_PWR_CLK.17 U59_U_5V_to_3V33.5
PG_PS_LTC6952_2: R431_U_5V_to_3V32.1 U35_I2C_Expander_PWR_CLK.21 U59_U_5V_to_3V32.5
PG_PS_LTC6952_3: R431_U_5V_to_3V31.1 U35_I2C_Expander_PWR_CLK.23 U59_U_5V_to_3V31.5
PGND: C595.1 C596.1 C597.1 C598.1 C694.1 C695.1 C696.1 C697.1 C698.1 C699.1 C700.1 C704.2 D3.2 D4.2 R324.1 R764.2 T35.1 T35.2 T35.3 U65.16 | length 33.4
  L1 w0.5: T35.1@32.55,213.3 32.55,212.719 v1(32.584,212.684) ; v1(33.82,212.65) T35.2@33.82,213.464 ; v1(35.09,212.65) T35.3@35.09,213.464 ; v1(37.032,210.162) C598.1@37.846,210.162 ; C699.1@51.994,200.664 v1(53.081,200.664) ; C699.1@51.994,201.387 v1(53.081,201.387) ; C696.1@51.994,202.554 v1(53.081,202.554) ; C696.1@51.994,203.278 v1(53.081,203.278) ; C697.1@51.994,204.444 v1(53.081,204.444) ; C697.1@51.994,205.168 v1(53.081,205.168) ; C695.1@51.994,206.335 v1(53.081,206.335) ; C695.1@51.994,207.059 v1(53.081,207.059) ; C698.1@51.994,208.225 v1(53.081,208.225) ; C698.1@51.994,208.949 v1(53.081,208.949)
  L16 w0.5: v6(27.345,227.151) C595.1@28.639,227.151 ; v6(28.639,225.857) C595.1@28.639,227.151 ; v6(29.932,227.151) C595.1@28.639,227.151 ; v6(30.586,223.896) D4.2@31.88,223.896 ; v6(31.88,222.602) D4.2@31.88,223.896 ; v6(31.88,225.19) D4.2@31.88,223.896 ; v6(33.174,223.896) D4.2@31.88,223.896 ; v6(40.454,223.832) D3.2@41.748,223.832 ; v6(41.748,222.539) D3.2@41.748,223.832 ; v6(41.748,225.126) D3.2@41.748,223.832 ; v6(43.041,223.832) D3.2@41.748,223.832 ; v6(48.998,225.107) R324.1@50.292,225.107 v6(50.292,223.813) ; v6(52.54,223.901) C596.1@52.54,225.195 v6(53.834,225.195)
PMU_GPI: J14.7 R784.1 | length 8.5
  L1 w0.12: J14.7@34.455,364.376 38.379,364.376 40.149,366.145 R784.1@42.26,366.145
PMU_GPI_1: J14.6 R785.1 | length 8.1
  L1 w0.12: J14.6@34.455,366.876 38.365,366.876 39.195,367.706 R785.1@42.26,367.706
PMU_GPI_2: J14.5 R786.1 | length 7.8
  L1 w0.12: J14.5@34.455,369.376 38.574,369.376 38.682,369.267 R786.1@42.26,369.267
PMU_GPI_3: J14.4 R787.1 | length 8.2
  L1 w0.12: J14.4@34.455,371.876 38.372,371.876 39.42,370.828 R787.1@42.26,370.828
PMU_GPI_5: J14.2 R789.1 | length 11.3
  L1 w0.12: J14.2@34.455,376.876 37.728,376.876 38.527,376.077 38.527,373.296 39.434,372.389 R789.1@42.26,372.389
PMU_GPO_0: J18.7 R790.1 | length 4.8
  L1 w0.2: R790.1@46.199,331.465 46.199,326.714 J18.7@46.257,326.657
PMU_GPO_1: J18.6 R791.1 | length 4.9
  L1 w0.2: R791.1@43.646,331.465 43.646,326.767 J18.6@43.757,326.657
PMU_GPO_2: J18.5 R792.1 | length 4.8
  L1 w0.2: J18.5@41.257,326.657 41.335,326.735 R792.1@41.335,331.465
PMU_GPO_3: J18.4 R793.1 | length 4.8
  L1 w0.2: R793.1@38.731,331.465 38.731,326.682 J18.4@38.757,326.657
PMU_GPO_4: J18.3 R794.1 | length 4.9
  L1 w0.2: J18.3@36.257,326.657 36.407,326.807 R794.1@36.407,331.465
PMU_GPO_5: J18.2 R795.1 | length 4.8
  L1 w0.2: J18.2@33.757,326.657 33.766,326.666 R795.1@33.766,331.465
Power1_In: P8.1 R448_U_Pomiar_pradu_napiecia_1.1 U64_U_Pomiar_pradu_napiecia_1.10 | length 9.6
  L1 w0.2: R448_U_Pomiar_pradu_napiecia_1.1@29.679,169.964 30.988,169.964 31.245,169.707 U64_U_Pomiar_pradu_napiecia_1.10@31.245,161.814
Power1_In_CM: R12.2 R448_U_Pomiar_pradu_napiecia_1.2 U5.7 U6.C3 U6.D3 U6.D4 U6.E3 U6.E4 U6.F3 U6.F4 U64_U_Pomiar_pradu_napiecia_1.8 U64_U_Pomiar_pradu_napiecia_1.9 | length 10
  L1 w0.2: U64_U_Pomiar_pradu_napiecia_1.8@32.245,161.814 32.245,169.707 32.502,169.964 R448_U_Pomiar_pradu_napiecia_1.2@34.279,169.964
  other v6: 46.94,171.336 47.599,172.073 46.939,172.838 48.314,172.942
  other v17: 48.36,174.6
Power2_In: P10.1 R448_U_Pomiar_pradu_napiecia_2.1 U64_U_Pomiar_pradu_napiecia_2.10 | length 9.1
  L16 w0.2: R448_U_Pomiar_pradu_napiecia_2.1@28.733,194.11 29.975,194.11 30.298,194.433 U64_U_Pomiar_pradu_napiecia_2.10@30.298,201.835
Power2_In_CM: R20.2 R448_U_Pomiar_pradu_napiecia_2.2 U5.2 U7.C3 U7.D3 U7.D4 U7.E3 U7.E4 U7.F3 U7.F4 U64_U_Pomiar_pradu_napiecia_2.8 U64_U_Pomiar_pradu_napiecia_2.9 | length 9.6
  L16 w0.2: U64_U_Pomiar_pradu_napiecia_2.8@31.298,201.835 31.308,201.825 31.308,194.466 31.674,194.099 31.84,194.099 31.85,194.11 R448_U_Pomiar_pradu_napiecia_2.2@33.333,194.11
  other v6: 46.939,177.161 48.188,177.161 47.599,177.926 46.94,178.663
  other v17: 48.36,175.4
Power4Charging: U6.C2 U6.D1 U6.D2 U6.E1 U6.E2 U6.F1 U6.F2 U7.C2 U7.D1 U7.D2 U7.E1 U7.E2 U7.F1 U7.F2
Power_3.3_1: C99.2 C100.2 C103.2 C104.2 C107.2 C124.2 C141.2 C145.2 C162.2 C179.2 C572.2 C573.2 FB8.1 FB9.1 FB10.1 FB11.1 FB12.1 FB14.1 FB16.1 FB18.1 FB20.1 FB22.1 R436.2 R440.2 U61.14 U61.15
Power_3.3_2: C108.2 C125.2 C142.2 C146.2 C163.2 C576.2 C577.2 FB13.1 FB15.1 FB17.1 FB19.1 FB21.1 R438.2 R441.2 U61.11 U61.12
Power_MUX_Status0: R630.2 U5.9 U35_I2C_Expander_PWR_Dist.19 | length 1.8
  L1 w0.2: U5.9@49.86,174.25 50.769,174.25 50.927,174.091 R630.2@51.6,174.091
Power_MUX_Status1: R11.1 U4.9 U35_I2C_Expander_PWR_Dist.20 | length 1.3
  L1 w0.2: U4.9@49.86,183.571 51.101,183.571 R11.1@51.11,183.563
Power_MUX_Status2: R13.2 U35_I2C_Expander_PWR_Dist.21 U48.9 | length 1.1
  L1 w0.2: U48.9@49.827,193.233 50.736,193.233 R13.2@50.895,193.075
PS_MODE1: P2.3 R350.1 S1.2 U1.R19 U74.2 | length 101.1
  L1 w0.116: U1.R19@176.397,306.539 v2(176.884,306.052)
  L1 w0.12: S1.2@232.473,347.751 234.29,347.751 234.798,347.243 P2.3@237.071,347.243
  L1 w0.2: P2.3@237.071,347.243 237.294,347.467 242.459,347.467 R350.1@242.659,347.667
  L5 (Sign) w0.12: v11(205.489,309.131) 205.537,309.178 205.537,309.467 205.922,309.852 205.922,310.804 218.687,323.569 218.687,323.775 219.442,324.53 219.508,324.53 219.508,342.805 218.907,343.406 218.907,345.202 219.475,345.77 233.02,345.77 234.48,347.231 v1(234.48,347.942)
  L3 (Sign) w0.12: v2(176.884,306.052) 183.909,306.052 184.461,306.603 185.128,306.603 185.397,306.872 185.397,307.177 185.686,307.467 190.658,307.467 190.662,307.471 190.939,307.471 190.943,307.467 191.658,307.467 191.662,307.471 191.939,307.471 191.965,307.497 204.646,307.497 205.489,308.34 v11(205.489,309.131)
PS_POR: P3.2 R355.2 U1.N19 U74.1 U76.1 U77.6 | length 112.3
  L1 w0.116: U1.N19@174.397,306.539 v5(174.884,306.052)
  L5 (Sign) w0.12: v1(210.477,310.803) 209.664,311.616 209.664,312.306 219.969,322.61 220.238,322.61 220.607,322.979 220.607,323.319 220.828,323.54 220.828,343.738 221.611,344.522 233.925,344.522 236.703,341.744 246.99,341.744
  L12 (Sign) w0.12: v5(174.884,306.052) 174.884,305.605 174.79,305.51 174.79,304.254 174.994,304.05 174.994,303.35 175.195,303.149 180.619,303.149 180.891,302.878 180.891,300.375 181.214,300.052 186.042,300.052 187.31,301.32 201.596,301.32 203.535,303.26 203.539,303.26 210.477,310.197 v1(210.477,310.803)
PS_Reset: P4.1 R354.1 U1.P20 U77.4 U78.6 | length 43.9
  L1 w0.116: U1.P20@175.397,307.539 v5(175.884,307.052)
  L12 (Sign) w0.12: v5(175.884,307.052) 175.219,306.387 175.219,305.441 175.062,305.284 175.062,304.401 175.259,304.204 181.284,304.204 183.771,301.717 201.682,301.717 203.444,303.48 203.448,303.48 209.877,309.908 v1(209.877,310.803)
PWR_ExtIO_INT0: R977.2 U35_I2C_Expander_PWR_Dist.16 | length 180.4
  L1 w0.2: U35_I2C_Expander_PWR_Dist.16@51.968,158.003 v2(53.291,158.003)
  L5 (Sign) w0.2: v11(129.991,178.892) 134.131,183.032 135.488,183.032 136.892,184.436 136.892,185.33 138.976,187.414 143.271,187.414 146.14,190.283 146.14,191.534 148.76,194.153 164.789,194.153 169.318,198.682 175.655,198.682 194.121,217.148 196.583,217.148
  L3 (Sign) w0.2: v2(53.291,158.003) 55.089,156.205 58.476,156.205 59.627,155.054 114.06,155.054 124.665,165.66 124.665,170.268 125.888,171.491 129.543,171.491 130.708,172.656 130.708,178.613 130.429,178.892 v11(129.991,178.892)
PWR_ExtIO_INT1: R976.2 U35_I2C_Expander_PWR_Dist.15 | length 181.5
  L1 w0.2: U35_I2C_Expander_PWR_Dist.15@51.968,157.353 v2(53.276,157.353)
  L5 (Sign) w0.2: v11(130.061,179.768) 133.895,183.603 135.252,183.603 136.322,184.673 136.322,185.566 137.54,186.784 137.922,186.784 138.852,187.714 143.147,187.714 145.84,190.408 145.84,191.665 148.629,194.453 164.664,194.453 169.193,198.982 175.531,198.982 193.996,217.448 196.583,217.448
  L3 (Sign) w0.2: v2(53.276,157.353) 53.442,157.353 54.889,155.905 58.351,155.905 59.502,154.754 114.184,154.754 124.965,165.535 124.965,170.144 126.012,171.191 129.667,171.191 131.008,172.532 131.008,179.329 130.569,179.768 v11(130.061,179.768)
PWR_ExtIO_INT2: R978.2 U35_I2C_Expander_PWR_CLK.15
PWR_ExtIO_INT3: R979.2 U35_I2C_Expander_PWR_CLK.16
PWR_ExtIO_nReset: R755.1 U35_I2C_Expander_Main_Rst.27 U35_I2C_Expander_PWR_Dist.14 | length 199.5
  L1 w0.2: U35_I2C_Expander_PWR_Dist.14@51.043,156.428 51.742,156.428 v2(51.778,156.464)
  L5 (Sign) w0.2: v11(115.069,246.304) 115.069,247.276 118.186,250.393 v1(118.186,260.147)
  L3 (Sign) w0.2: v2(51.778,156.464) 52.502,156.464 53.361,155.605 58.227,155.605 59.378,154.454 114.308,154.454 125.265,165.411 125.265,170.02 126.136,170.891 129.792,170.891 131.308,172.408 131.308,180.34 130.991,180.657 125.618,180.657 124.498,181.778 124.498,184.772 113.271,195.999 113.271,221.145 117.831,225.704 117.831,244.739 116.266,246.304 v11(115.069,246.304)
  L16 w0.2: U35_I2C_Expander_Main_Rst.27@115.873,260.668 118.121,260.668 ; v1(118.186,260.147) 118.186,260.602 118.121,260.668 ; R755.1@120.169,260.68 120.157,260.668 118.121,260.668
PWR_OUT_20V: C347.2 C348.2 C352.2 C353.2 C371.2 C372.2 C373.2 C374.2 C375.2 C376.2 C391.1 C392.2 C396.2 C397.1 C400.2 C401.2 C402.2 C403.2 C404.2 C405.2 C432.1 C433.2 C437.2 C438.1 C441.2 C442.2 C443.2 C444.2 C445.2 C446.2 C766.1 C767.1 C768.1 C769.1 C770.2 C771.2 C772.2 C773.2 C774.2 C775.2 C776.2 C777.2 C778.2 C779.2 C780.2 C781.2 R266.2 R268.1 R285.1 R303.1 R612.2 R614.2 R621.2 R622.2 R628.2 R686.2 T5.5 T5.6 T5.7 T5.8 T6.5 T6.6 T6.7 T6.8 T9.5 T9.6 T9.7 T9.8 T10.5 T10.6 T10.7 T10.8 T13.5 T13.6 T13.7 T13.8 T15.5 T15.6 T15.7 T15.8 T17.5 T17.6 T17.7 T17.8 T19.5 T19.6 T19.7 T19.8 U48.1 U48.8 | length 170.9
  L1 w0.3: v5(83.033,207.488) 83.722,207.488 ; 87.909,190.59 v5(87.909,191.279)
  L1 w0.5: C780.2@52.066,210.593 v1(53.153,210.593) ; C780.2@52.066,211.317 v1(53.153,211.317) ; C779.2@52.066,212.488 v1(53.153,212.488) ; C779.2@52.066,213.212 v1(53.153,213.212) ; C778.2@52.066,214.297 v1(53.153,214.297) ; C778.2@52.066,215.021 v1(53.153,215.021) ; C777.2@52.067,216.111 v1(53.154,216.111) ; C777.2@52.066,216.835 v1(53.153,216.835) ; C776.2@52.066,217.856 v1(53.153,217.856) ; C776.2@52.066,218.58 v1(53.153,218.58) ; C775.2@52.066,219.678 v1(53.153,219.678) ; C775.2@52.066,220.402 v1(53.153,220.402) ; C774.2@52.066,221.492 v1(53.153,221.492) ; C774.2@52.066,222.216 v1(53.153,222.216) ; C392.2@58.13,226.088 v1(58.13,227.175) ; v1(58.214,213.896) C397.1@58.214,214.983 ; C392.2@58.776,226.088 v1(58.776,227.175) ; v1(58.852,213.896) C397.1@58.852,214.983 ; C392.2@59.413,226.088 v1(59.413,227.175) ; v1(59.497,213.896) C397.1@59.497,214.983 ; C433.2@59.63,169.623 v1(59.63,170.71) ; C353.2@59.645,197.03 v1(59.645,198.117) ; v1(59.653,186.744) C438.1@59.653,187.831 ; C433.2@60.276,169.623 v1(60.276,170.71) ; v1(60.29,186.744) C438.1@60.29,187.831 ; C353.2@60.29,197.03 v1(60.29,198.117) ; C391.1@60.612,226.088 v1(60.612,227.175) ; v1(60.696,213.896) C396.2@60.696,214.983 ; C433.2@60.913,169.623 v1(60.913,170.71) ; C353.2@60.928,197.03 v1(60.928,198.117) ; v1(60.935,186.744) C438.1@60.935,187.831 ; C391.1@61.258,226.088 v1(61.258,227.175) ; v1(61.334,213.896) C396.2@61.334,214.983 ; C391.1@61.895,226.088 v1(61.895,227.175) ; v1(61.979,213.896) C396.2@61.979,214.983 ; C432.1@62.112,169.623 v1(62.112,170.71) ; C352.2@62.127,197.03 v1(62.127,198.117) ; v1(62.135,186.744) C437.2@62.135,187.831 ; C769.1@62.575,160.649 v1(62.575,161.736) ; C432.1@62.758,169.623 v1(62.758,170.71) ; v1(62.772,186.744) C437.2@62.772,187.831 ; C352.2@62.772,197.03 v1(62.772,198.117) ; C405.2@63.094,226.087 v1(63.094,227.174) ; v1(63.124,159.562) C769.1@63.124,160.649 ; v1(63.179,213.896) C402.2@63.179,214.983 ; C432.1@63.395,169.623 v1(63.395,170.71) ; C352.2@63.41,197.03 v1(63.41,198.117) ; v1(63.417,186.744) C437.2@63.417,187.831 ; C769.1@63.68,160.649 v1(63.68,161.736) ; C405.2@63.74,226.087 v1(63.74,227.174) ; v1(63.816,213.896) C402.2@63.816,214.983 ; v1(64.229,159.562) C769.1@64.229,160.649 ; C405.2@64.377,226.087 v1(64.377,227.174) ; v1(64.461,213.896) C402.2@64.461,214.983 ; C446.2@64.594,169.623 v1(64.594,170.71) ; C374.2@64.609,197.03 v1(64.609,198.117) ; v1(64.617,186.744) C443.2@64.617,187.831 ; C769.1@64.777,160.649 v1(64.777,161.736) ; C446.2@65.24,169.623 v1(65.24,170.71) ; v1(65.254,186.744) C443.2@65.254,187.831 ; C374.2@65.254,197.03 v1(65.254,198.117) ; C404.2@65.576,226.087 v1(65.576,227.174) ; v1(65.661,213.896) C401.2@65.661,214.983 ; C446.2@65.877,169.623 v1(65.877,170.71) ; C374.2@65.892,197.03 v1(65.892,198.117) ; v1(65.899,186.744) C443.2@65.899,187.831 ; C768.1@65.979,160.649 v1(65.979,161.736) ; C404.2@66.222,226.087 v1(66.222,227.174) ; v1(66.298,213.896) C401.2@66.298,214.983 ; v1(66.527,159.563) C768.1@66.527,160.649 ; C404.2@66.859,226.087 v1(66.859,227.174) ; v1(66.943,213.896) C401.2@66.943,214.983 ; C445.2@67.076,169.623 v1(67.076,170.71) ; C768.1@67.084,160.649 v1(67.084,161.736) ; C371.2@67.091,197.03 v1(67.091,198.117) ; v1(67.099,186.744) C442.2@67.099,187.831 ; v1(67.632,159.563) C768.1@67.632,160.649 ; C445.2@67.722,169.623 v1(67.722,170.71) ; v1(67.736,186.744) C442.2@67.736,187.831 ; C371.2@67.736,197.03 v1(67.736,198.117) ; C403.2@68.058,226.057 v1(68.058,227.144) ; v1(68.143,213.866) C400.2@68.143,214.953 ; C768.1@68.181,160.649 v1(68.181,161.736) ; C445.2@68.359,169.623 v1(68.359,170.71) ; C371.2@68.374,197.03 v1(68.374,198.117) ; v1(68.382,186.744) C442.2@68.382,187.831 ; C403.2@68.704,226.057 v1(68.704,227.144) ; v1(68.78,213.866) C400.2@68.78,214.953 ; C403.2@69.341,226.057 v1(69.341,227.144) ; C767.1@69.419,160.65 v1(69.419,161.737) ; v1(69.425,213.866) C400.2@69.425,214.953 ; C444.2@69.558,169.592 v1(69.558,170.679) ; C376.2@69.573,196.999 v1(69.573,198.086) ; v1(69.581,186.713) C441.2@69.581,187.8 ; v1(69.967,159.563) C767.1@69.967,160.65 ; C444.2@70.204,169.592 v1(70.204,170.679) ; v1(70.218,186.713) C441.2@70.218,187.8 ; C376.2@70.218,196.999 v1(70.218,198.086) ; C767.1@70.524,160.65 v1(70.524,161.737) ; C444.2@70.841,169.592 v1(70.841,170.679) ; C376.2@70.856,196.999 v1(70.856,198.086) ; v1(70.864,186.713) C441.2@70.864,187.8 ; v1(71.072,159.563) C767.1@71.072,160.65 ; C767.1@71.621,160.65 v1(71.621,161.737) ; v1(72.877,163.201) T15.8@73.964,163.201 ; v1(72.877,164.471) T15.7@73.964,164.471 ; v1(72.877,165.741) T15.6@73.964,165.741 ; v1(72.877,167.011) T15.5@73.964,167.011 ; C766.1@72.887,160.649 v1(72.887,161.736) ; v1(73.13,178.003) T13.8@74.217,178.003 ; v1(73.13,179.273) T13.7@74.217,179.273 ; v1(73.13,180.543) T13.6@74.217,180.543 ; v1(73.13,181.813) T13.5@74.217,181.813 ; v1(73.435,159.562) C766.1@73.435,160.649 ; C766.1@73.992,160.649 v1(73.992,161.736) ; v1(74.017,193.746) T19.8@75.104,193.746 ; v1(74.017,195.016) T19.7@75.104,195.016 ; v1(74.017,196.286) T19.6@75.104,196.286 ; v1(74.017,197.556) T19.5@75.104,197.556 ; v1(74.086,214.079) T17.8@75.173,214.079 ; v1(74.086,215.349) T17.7@75.173,215.349 ; v1(74.086,216.619) T17.6@75.173,216.619 ; v1(74.086,217.889) T17.5@75.173,217.889 ; v1(74.54,159.562) C766.1@74.54,160.649 ; T6.8@75.072,249.548 v1(75.072,250.635) ; v1(75.078,220.589) T10.5@75.078,221.676 ; C766.1@75.088,160.649 v1(75.088,161.736) ; T6.7@76.342,249.548 v1(76.342,250.635) ; v1(76.348,220.589) T10.6@76.348,221.676 ; T6.6@77.612,249.548 v1(77.612,250.635) ; v1(77.618,220.589) T10.7@77.618,221.676 ; T6.5@78.882,249.548 v1(78.882,250.635) ; v1(78.888,220.589) T10.8@78.888,221.676 ; v1(82.072,220.589) T9.5@82.072,221.676 ; T5.8@82.072,249.548 v1(82.072,250.635) ; v1(83.342,220.589) T9.6@83.342,221.676 ; T5.7@83.342,249.548 v1(83.342,250.635) ; v1(84.612,220.589) T9.7@84.612,221.676 ; T5.6@84.612,249.548 v1(84.612,250.635) ; v1(85.091,256.835) C348.2@85.091,257.922 ; v1(85.728,256.835) C348.2@85.728,257.922 ; v1(85.882,220.589) T9.8@85.882,221.676 ; T5.5@85.882,249.548 v1(85.882,250.635) ; v1(86.374,256.835) C348.2@86.374,257.922 ; v1(87.573,256.835) C347.2@87.573,257.922 ; v1(88.21,256.835) C347.2@88.21,257.922 ; v1(88.856,256.835) C347.2@88.856,257.922 ; v1(90.055,256.835) C372.2@90.055,257.922 ; v1(90.692,256.835) C372.2@90.692,257.922 ; v1(91.338,256.835) C372.2@91.338,257.922 ; v1(92.537,256.835) C375.2@92.537,257.922 ; v1(93.174,256.835) C375.2@93.174,257.922 ; v1(93.82,256.835) C375.2@93.82,257.922 ; v1(95.019,256.804) C373.2@95.019,257.891 ; v1(95.656,256.804) C373.2@95.656,257.891 ; v1(96.302,256.804) C373.2@96.302,257.891
  other v1: 74.782,163.22 76.034,163.22 77.285,163.22 74.782,164.471 76.034,164.471 77.285,164.471 74.782,165.723 76.034,165.723 77.285,165.723 74.782,166.975 76.034,166.975 77.285,166.975 75.035,178.022 76.287,178.022 77.539,178.022 75.035,179.273 76.287,179.273 77.539,179.273 75.035,180.525 76.287,180.525 77.539,180.525 75.035,181.777 76.287,181.777 77.539,181.777 75.922,193.764 77.173,193.764 78.425,193.764 75.922,195.016 77.173,195.016 78.425,195.016 75.922,196.267 77.173,196.267 78.425,196.267 75.922,197.519 77.173,197.519 78.425,197.519 75.991,214.097 77.243,214.097 78.495,214.097 75.991,215.349 77.243,215.349 78.495,215.349 75.991,216.6 77.243,216.6 78.495,216.6 75.991,217.852 77.243,217.852 78.495,217.852 75.114,222.494 76.366,222.494 77.618,222.494 78.869,222.494 82.108,222.494 83.36,222.494 84.612,222.494 85.863,222.494 75.114,223.745 76.366,223.745 77.618,223.745 78.869,223.745 82.108,223.745 83.36,223.745 84.612,223.745 85.863,223.745 75.114,224.997 76.366,224.997 77.618,224.997 78.869,224.997 82.108,224.997 83.36,224.997 84.612,224.997 85.863,224.997 75.09,246.226 76.342,246.226 77.593,246.226 78.845,246.226 82.09,246.226 83.342,246.226 84.593,246.226 85.845,246.226 75.09,247.478 76.342,247.478 77.593,247.478 78.845,247.478 82.09,247.478 83.342,247.478 84.593,247.478 85.845,247.478 75.09,248.73 76.342,248.73 77.593,248.73 78.845,248.73 82.09,248.73 83.342,248.73 84.593,248.73 85.845,248.73
  other v6: 50.447,190.32 49.788,191.057 49.2,191.821 50.448,191.822 49.2,196.145 50.448,196.145 49.788,196.91 50.447,197.647
  other v17: 49.027,193.583 49.027,194.383
PWR_PowerAlert0: R974.2 U35_I2C_Expander_PWR_Dist.22 U64_U_Pomiar_pradu_napiecia_1.3 | length 185
  L1 w0.2: U35_I2C_Expander_PWR_Dist.22@51.043,162.178 51.043,164.287 51.145,164.389 v1(51.422,164.389)
  L5 (Sign) w0.2: v1(51.422,164.389) 52.616,163.195 52.616,162.496 61.775,153.338 104.104,153.338 122.515,171.748 124.026,171.748 124.595,172.317 124.595,176.381 129.07,180.856 129.07,183.133 131.998,186.06 131.998,189.079 137.972,195.053 164.416,195.053 168.945,199.582 175.282,199.582 193.748,218.048 196.583,218.048
PWR_PowerAlert1: R975.2 U35_I2C_Expander_PWR_Dist.23 U64_U_Pomiar_pradu_napiecia_2.3 | length 185.7
  L1 w0.2: U35_I2C_Expander_PWR_Dist.23@50.393,162.178 50.393,164.287 51.145,165.039 v1(51.422,165.039)
  L5 (Sign) w0.2: v1(51.422,165.039) 53.266,163.195 53.266,162.496 61.775,153.987 104.305,153.987 122.384,172.066 123.895,172.066 124.295,172.466 124.295,176.53 128.753,180.988 128.753,183.24 131.68,186.167 131.68,189.21 137.823,195.353 164.292,195.353 168.82,199.882 175.158,199.882 193.624,218.348 196.583,218.348
PWR_Switch1_En: U6.A2 U35_I2C_Expander_PWR_Dist.24 | length 9.5
  L1 w0.12: U6.A2@45.21,169.189 44.91,169.189 44.66,168.939 44.66,167.785 49.709,162.737 49.709,162.212 U35_I2C_Expander_PWR_Dist.24@49.743,162.178
PWR_Switch1_Flag: R29.1 U6.A3 U35_I2C_Expander_PWR_Dist.25 | length 10.5
  L1 w0.12: U6.A3@45.21,169.589 44.86,169.589 44.459,169.188 44.144,169.188 43.904,168.948 R29.1@43.904,168.898 43.904,168.084 49.093,162.894 U35_I2C_Expander_PWR_Dist.25@49.093,162.178
PWR_Switch2_En: U7.A2 U35_I2C_Expander_PWR_Dist.26 | length 22.2
  L1 w0.12: U7.A2@44.875,179.775 44.875,180.078 44.629,180.325 44.08,180.325 43.555,179.8 43.555,179.312 42.879,178.636 42.879,173.855 43.129,173.606 43.129,168.38 48.443,163.066 U35_I2C_Expander_PWR_Dist.26@48.443,162.178
PWR_Switch2_Flag: R30.1 U7.A3 U35_I2C_Expander_PWR_Dist.27 | length 25.3
  L1 w0.12: U7.A3@45.275,179.775 45.275,180.894 R30.1@45.281,180.9 45.281,181.293 44.783,181.791 43.944,181.791 43.116,180.963 43.116,179.184 42.659,178.727 42.659,173.764 42.83,173.594 42.83,168.368 47.793,163.405 U35_I2C_Expander_PWR_Dist.27@47.793,162.178
RAM_DDR4_VTT: C722.2 C723.2 R31.2 R32.2 R33.2 R34.2 R35.2 R36.2 R37.2 R38.2 R39.2 R40.2 R41.2 R42.2 R43.2 R44.2 R45.2 R46.2 R47.2 R48.2 R49.2 R50.2 R51.2 R53.2 R55.2 R57.2 R59.2 R689.1 U73.8 | length 34.8
  L1 w0.25: v1(156.593,333.611) R46.2@157.837,333.611 ; v1(156.593,334.7) R59.2@157.837,334.7 ; v1(156.593,335.789) R51.2@157.837,335.789 ; v1(156.593,336.878) R57.2@157.837,336.878 ; v1(156.593,337.967) R37.2@157.837,337.967 ; v1(156.593,339.056) R34.2@157.837,339.055 ; v1(156.593,340.144) R33.2@157.837,340.144 ; v1(156.593,341.233) R41.2@157.837,341.233 ; v1(156.593,342.322) R48.2@157.837,342.322 ; v1(156.593,343.411) R45.2@157.837,343.411 ; v1(156.593,344.5) R53.2@157.837,344.5 ; R38.2@162.769,345.7 v1(162.769,346.944) ; R44.2@163.977,345.7 v1(163.977,346.944) ; R55.2@165.186,345.7 v1(165.186,346.944) ; R40.2@166.395,345.7 v1(166.395,346.944) ; R36.2@167.603,345.7 v1(167.603,346.944) ; R49.2@168.812,345.7 v1(168.812,346.944) ; R32.2@170.02,345.7 v1(170.02,346.944) ; R39.2@171.229,345.7 v1(171.229,346.944) ; R42.2@172.438,345.7 v1(172.438,346.944) ; R35.2@173.646,345.7 v1(173.646,346.944) ; R31.2@174.855,345.7 v1(174.855,346.944) ; R50.2@176.063,345.7 v1(176.063,346.944) ; R47.2@177.272,345.7 v1(177.272,346.944) ; R43.2@178.481,345.7 v1(178.481,346.944)
  L1 w0.3: U73.8@151.644,349.985 v1(152.387,349.985) ; C722.2@153.683,349.532 v1(153.683,350.275) ; C723.2@154.673,349.532 v1(154.673,350.275) ; v1(158.909,347.162) 159.652,347.162 ; R689.1@160.795,347.112 v1(161.538,347.112)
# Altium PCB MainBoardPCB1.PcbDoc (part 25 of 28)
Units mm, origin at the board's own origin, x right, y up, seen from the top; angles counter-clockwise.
Board outline 258.95 x 308.86 mm, 16 copper layers (L1, L2 (GND), L3 (Sign), L4 (GND), L5 (Sign), L6 (PWR/GND), L7(PWR/GND), L8 (Plane_GND), L9 (PWR/GND), L10 (PWR/GND), L11 (PWR/GND), L12 (Sign), L13 (GND), L14 (Sign), L15 (GND), L16), stack 2.502 mm thick; 2397 components, 1744 nets, 8397 pads, 4112 vias.
Unrouted connection lines stored in the file: 3547.

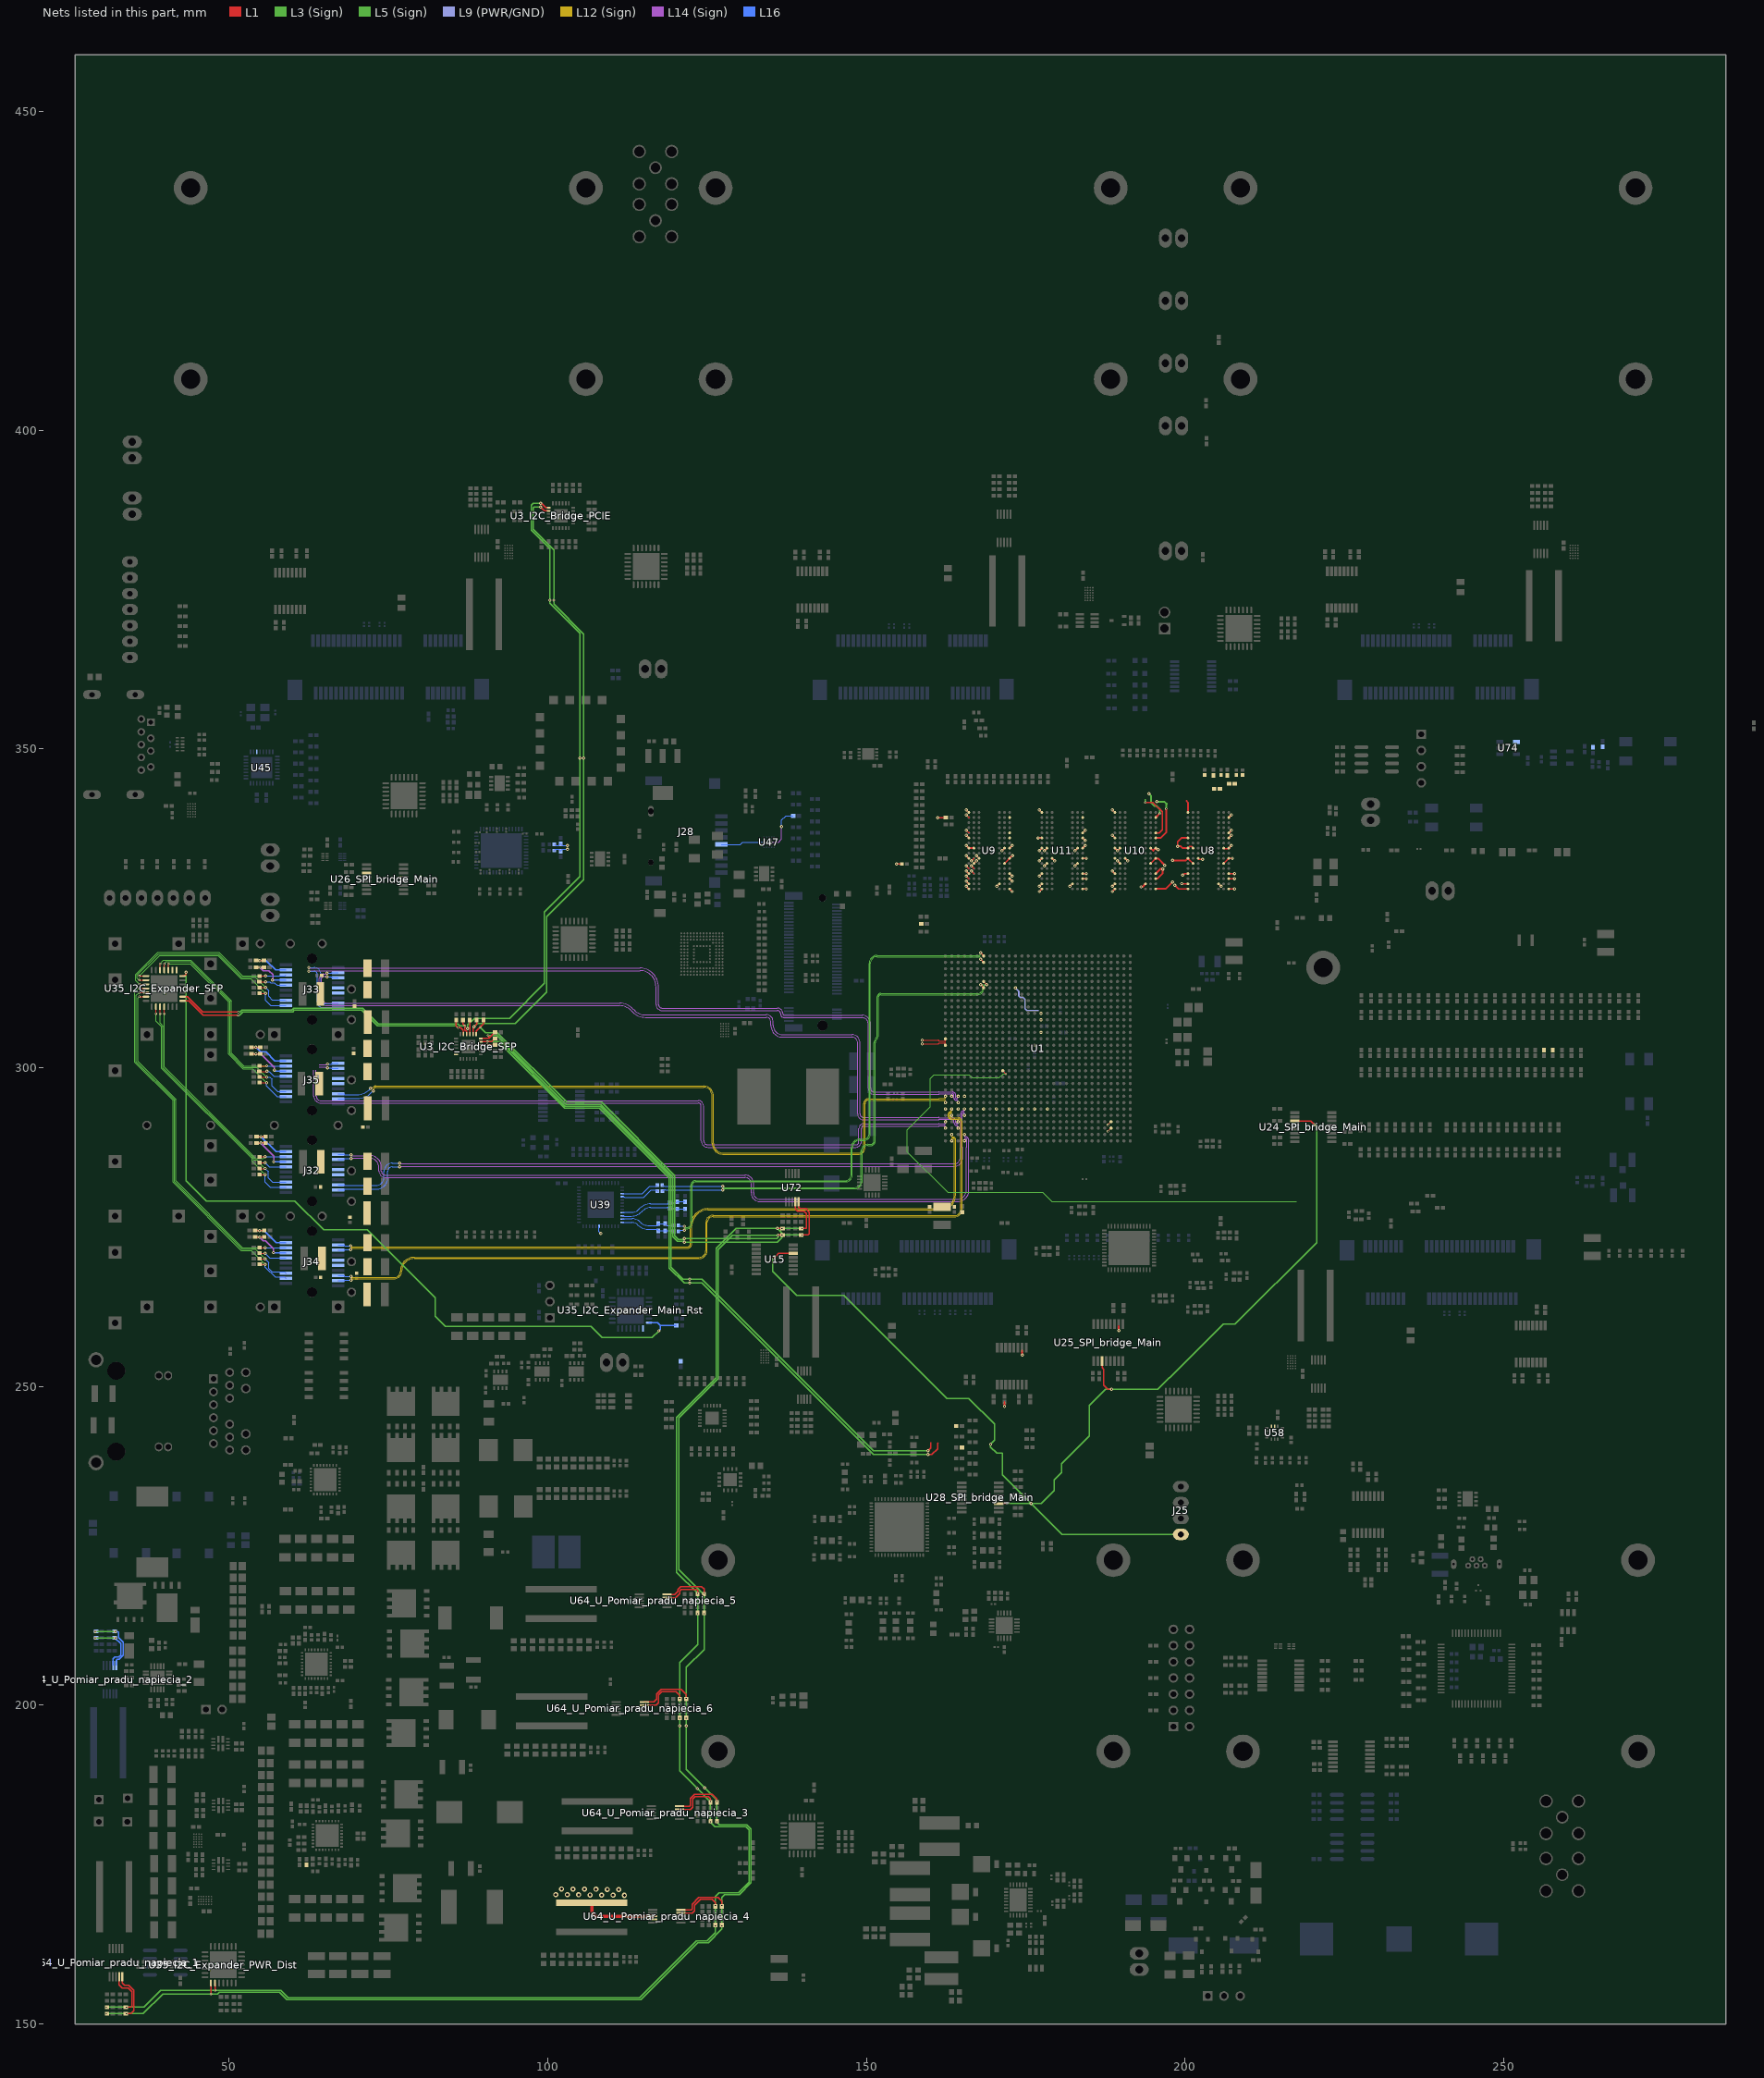
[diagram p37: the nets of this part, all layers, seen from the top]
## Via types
v1: diameter 0.5, hole 0.2, L1 to L16, tented both sides, 1457 vias
v2: diameter 0.35/0/0.35 (per signal layer), hole 0.127, L1 to L3 (Sign), tented both sides, 479 vias
v3: diameter 0.5/0.35/0.35/0.35/0.35/0.35/0.35/0.35/0.35/0.35/0.35/0.35/0.35/0.35/0.35/0.5 (per signal layer), hole 0.15, L1 to L16, tented both sides, 453 vias
v4: diameter 0.5, hole 0.2, L1 to L16, 451 vias
v5: diameter 0.5/0.35/0.35/0.35/0.35/0.35/0.35/0.35/0.35/0.35/0.35/0.35/0.35/0.35/0.35/0.5 (per signal layer), hole 0.2, L1 to L16, tented both sides, 373 vias
v6: diameter 0.8, hole 0.4, L1 to L16, tented both sides, 168 vias
v7: diameter 0.35/0/0.35 (per signal layer), hole 0.127, L1 to L3 (Sign), 138 vias
v8: diameter 2.54, hole 1.02, L1 to L16, 113 vias
v9: diameter 0.5/0/0.5 (per signal layer), hole 0.2, L14 (Sign) to L16, tented both sides, 102 vias
v10: diameter 1.4, hole 0.5, L1 to L16, tented both sides, 80 vias
v11: diameter 0.5, hole 0.2, L3 (Sign) to L6 (PWR/GND), tented both sides, 54 vias
v12: diameter 0.35, hole 0.127, L1 to L2 (GND), tented both sides, 47 vias
v13: diameter 0.4, hole 0.2, L1 to L16, tented both sides, 46 vias
v14: diameter 0.35, hole 0.127, L1 to L16, tented both sides, 16 vias
v15: diameter 0.25, hole 0.2, L1 to L16, 16 vias
v16: diameter 0.5, hole 0.2, L11 (PWR/GND) to L14 (Sign), tented both sides, 16 vias
v17: diameter 0.4, hole 0.2, L1 to L16, 16 vias
v18: diameter 0.3, hole 0.2, L1 to L16, 15 vias
v19: diameter 0.45, hole 0.15, L1 to L16, 12 vias
v20: diameter 0.5/0.35/0.35/0.35/0.35/0.35/0.35/0.35/0.35/0.35/0.35/0.35/0.35/0.35/0.35/0.45 (per signal layer), hole 0.15, L1 to L16, tented both sides, 10 vias
v21: diameter 0.2/0/0.2 (per signal layer), hole 0.1, L1 to L3 (Sign), tented both sides, 9 vias
v22: diameter 0.3, hole 0.127, L14 (Sign) to L16, tented both sides, 8 vias
v23: diameter 0.4, hole 0.1, L1 to L16, 7 vias
v24: diameter 1.15, hole 1.15, L1 to L16, 5 vias
v25: diameter 1.65, hole 1.65, L1 to L16, 5 vias
v26: diameter 0.2, hole 0.1, L1 to L16, 4 vias
v27: diameter 0.4, hole 0.15, L1 to L16, 2 vias
v28: diameter 0.5/0.35/0.35/0.35/0.35/0.35/0.35/0.35/0.35/0.35/0.35/0.35/0.35/0.35/0.35/0.5 (per signal layer), hole 0.15, L1 to L16, 2 vias
v29: diameter 0.35, hole 0.127, L3 (Sign) to L6 (PWR/GND), tented both sides, 2 vias
v30: diameter 0.3, hole 0.127, L15 (GND) to L16, tented both sides, 1 vias
v31: diameter 0.35, hole 0.127, L1 to L2 (GND), 1 vias
v32: diameter 0.5/0.35/0.35/0.35/0.35/0.35/0.35/0.35/0.35/0.35/0.35/0.35/0.35/0.35/0.35/0.5 (per signal layer), hole 0.2, L1 to L16, 1 vias
v33: diameter 0.35/0.35/0.35 (per signal layer), hole 0.127, L1 to L3 (Sign), tented both sides, 1 vias
v34: diameter 0.45/0/0.45 (per signal layer), hole 0.15, L1 to L3 (Sign), tented both sides, 1 vias
v35: diameter 0.45/0/0.45 (per signal layer), hole 0.2, L14 (Sign) to L16, tented both sides, 1 vias

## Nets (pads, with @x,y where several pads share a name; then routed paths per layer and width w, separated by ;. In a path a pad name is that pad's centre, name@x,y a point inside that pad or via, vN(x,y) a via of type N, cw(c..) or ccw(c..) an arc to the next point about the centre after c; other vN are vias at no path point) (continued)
RAM_Vcc1V2: C36.2 C220.1 C222.1 C223.2 C224.2 C225.2 C226.2 C227.2 C228.2 C229.2 C230.2 C231.2 C232.2 C233.2 C234.2 C235.2 C236.2 C237.2 C238.2 C239.2 C240.2 C241.2 C242.2 C244.1 C246.1 C247.2 C248.2 C249.2 C250.2 C251.2 C252.2 C253.2 C254.2 C255.2 C256.2 C257.2 C258.2 C259.2 C260.2 C261.2 C262.2 C263.2 C264.2 C265.2 C266.2 C741.2 C760.1 C761.2 R58.2 R165.2 R166.2 R169.2 R171.2 R297.2 R448_U_Pomiar_pradu_napiecia_4.2 R695.1 U1.A6 U1.B8 U1.C6 U1.D8 U1.E6 U1.G6 U1.J6 U1.L6 U1.M25 U1.N6 U1.R6 U1.T18 U1.T20 U1.T21 U1.U6 U8.A1 U8.A6 U8.B3 U8.B6 U8.C1 U8.D1 U8.D6 U8.F2 U8.F5 U8.G1 U8.G4 U8.G6 U8.J1 U8.J2 U8.J5 U8.J6 U8.L1 U8.L6 U8.R1 U8.T6 U9.A1 U9.A6 U9.B3 U9.B6 U9.C1 U9.D1 U9.D6 U9.F2 U9.F5 U9.G1 U9.G4 U9.G6 U9.J1 U9.J2 U9.J5 U9.J6 U9.L1 U9.L6 U9.R1 U9.T6 U10.A1 U10.A6 U10.B3 U10.B6 U10.C1 U10.D1 U10.D6 U10.F2 U10.F5 U10.G1 U10.G4 U10.G6 U10.J1 U10.J2 U10.J5 U10.J6 U10.L1 U10.L6 U10.R1 U10.T6 U11.A1 U11.A6 U11.B3 U11.B6 U11.C1 U11.D1 U11.D6 U11.F2 U11.F5 U11.G1 U11.G4 U11.G6 U11.J1 U11.J2 U11.J5 U11.J6 U11.L1 U11.L6 U11.R1 U11.T6 U64_U_Pomiar_pradu_napiecia_4.8 U64_U_Pomiar_pradu_napiecia_4.9 | length 101.8
  L1 w0.2: v3(189.4,334.057) v3@189.4,334.064 ; v1(198.412,328.613) 198.964,328.06 U8.A6@200.457,328.06 ; v1(199.479,328.887) 200.43,328.887 U8.B6@200.457,328.86 ; v1(199.657,330.225) 199.892,330.46 U8.D6@200.457,330.46 ; U8.G4@202.057,332.86 202.215,332.702 v3(202.757,332.702) ; U8.J2@206.057,334.46 206.18,334.337 206.734,334.337 U8.J1@206.857,334.46 v3(207.261,334.864) ; U8.A1@206.857,328.06 v3(207.785,328.06) ; U8.C1@206.857,329.66 v3(207.785,329.66) ; U8.D1@206.857,330.46 v3(207.785,330.46) ; U8.G1@206.857,332.86 v3(207.428,332.86) ; U8.L1@206.857,336.06 v3(207.261,336.464) ; U8.R1@206.857,339.26 v3(207.261,339.664)
  L1 w0.25: v1(154.724,331.965) C36.2@155.566,331.965 ; v1(161.216,339.242) R58.2@162.46,339.242 ; v3(165.672,328.464) U9.A6@166.076,328.06 ; v3(165.672,329.264) U9.B6@166.076,328.86 ; v3(165.672,330.064) 166.076,329.66 ; v3(165.672,330.864) U9.D6@166.076,330.46 ; v3(165.672,331.664) 166.076,331.26 ; v3(165.672,333.264) U9.G6@166.076,332.86 ; v3(165.672,334.864) U9.J6@166.076,334.46 U9.J5@166.876,334.46 ; v3(165.672,336.464) U9.L6@166.076,336.06 ; v3(165.672,337.264) 166.076,336.86 ; v3(165.672,339.664) 166.076,339.26 ; v3(165.672,340.464) U9.T6@166.076,340.06 ; v3(166.472,330.864) 166.876,330.46 ; v3(166.472,331.664) 166.876,331.26 ; v3(166.472,332.457) 166.876,332.86 ; U9.F5@166.876,332.06 v3(167.279,332.464) ; v3(167.272,333.264) U9.G4@167.676,332.86 ; v3(170.472,328.457) U9.B3@170.876,328.86 ; v3(171.272,334.057) U9.J2@171.676,334.46 ; U9.F2@171.676,332.06 172.876,333.261 v3(172.923,333.261) ; U9.A1@172.476,328.06 v3(172.879,327.657) ; U9.C1@172.476,329.66 v3(172.879,329.257) ; U9.D1@172.476,330.46 v3(172.879,330.057) ; U9.J1@172.476,334.46 v3(172.879,334.864) ; v3(176.95,336.055) U11.L6@177.521,336.055 ; v3(177.133,327.657) U11.A6@177.536,328.06 ; v3(177.133,328.457) U11.B6@177.536,328.86 ; v3(177.133,330.057) U11.D6@177.536,330.46 ; v3(177.133,332.457) U11.G6@177.536,332.86 ; v3(177.133,334.057) U11.J6@177.536,334.46 ; v3(177.133,340.464) U11.T6@177.536,340.06 ; v3(177.933,331.657) U11.F5@178.336,332.06 ; v3(177.933,334.057) U11.J5@178.336,334.46 ; U11.G4@179.136,332.86 v3(179.54,332.457) ; v3(181.933,328.457) U11.B3@182.336,328.86 ; v3(182.733,331.657) U11.F2@183.136,332.06 ; v3(182.733,334.057) U11.J2@183.136,334.46 ; U11.A1@183.936,328.06 v3(184.507,328.06) ; U11.C1@183.936,329.66 v3(184.507,329.66) ; U11.D1@183.936,330.46 v3(184.507,330.46) ; U11.G1@183.936,332.86 v3(184.507,332.86) ; U11.J1@183.936,334.46 v3(184.34,334.864) ; U11.L1@183.936,336.06 v3(184.34,335.657) ; v3(188.593,327.657) U10.A6@188.997,328.06 ; v3(188.593,328.457) U10.B6@188.997,328.86 ; v3(188.593,330.864) U10.D6@188.997,330.46 ; v3(188.593,336.464) U10.L6@188.997,336.06 ; v3(188.593,340.464) U10.T6@188.997,340.06 ; U10.J6@188.997,334.46 v3(189.4,334.057) ; v3(189.393,332.464) U10.F5@189.797,332.06 ; v3@189.4,334.064 U10.J5@189.797,334.46 ; U10.G4@190.597,332.86 v3(191,332.457) ; U10.F2@194.597,332.06 U10.G1@195.397,332.86 ; U8.B3@205.257,328.86 v3(205.661,328.457)
  L1 w0.254: v1(198.031,332.524) 200.121,332.524 U8.G6@200.457,332.86 U8.F5@201.257,332.06 ; 200.203,341.884 200.457,341.63 U8.T6@200.457,340.06 ; U8.L6@200.457,336.06 199.439,336.06 198.847,335.469 v1(198.847,334.75) 199.326,334.75 199.615,334.46 U8.J6@200.457,334.46 200.727,334.73 200.987,334.73 U8.J5@201.257,334.46 ; U8.F2@206.057,332.06 U8.G1@206.857,332.86
  L1 w0.3: v5(171.673,246.866) 171.673,247.556 ; v5(174.448,254.962) 174.448,255.651 ; v5(189.598,258.759) 189.598,259.448 ; v1(193.116,328.384) 193.32,328.384 U10.B3@193.797,328.86 ; U10.J2@194.597,334.46 195.008,334.049 U10.J1@195.397,334.46 195.644,334.213 v1(195.77,334.213) ; U10.A1@195.397,328.06 196.956,328.06 v1(198.022,329.127) ; U10.C1@195.397,329.66 195.643,329.66 196.494,330.512 v1(196.494,331.178) 196.114,331.178 U10.D1@195.397,330.46 ; U10.G1@195.397,332.86 195.441,332.816 195.791,332.816 196.812,331.795 v1(196.812,331.762) ; U10.L1@195.397,336.06 196.172,336.06 197.039,336.927 v2(197.039,340.639) ; U10.R1@195.397,339.26 195.988,339.852 v2(196.026,339.852)
  L1 w0.5: R448_U_Pomiar_pradu_napiecia_4.2@106.904,169.038 106.904,167.583 107.583,166.903 U64_U_Pomiar_pradu_napiecia_4.8@116.507,166.903
  L9 (PWR/GND) w0.254: v5(173.397,312.539) 173.901,312.035 173.901,311.315 174.18,311.036 174.587,311.036 174.892,310.731 174.892,309.26 175.173,308.978 176.958,308.978
  L3 (Sign) w0.3: v1(194.323,342.976) 194.694,342.605 194.694,341.572 195.22,341.046 195.567,341.046 196.026,340.587 v2@196.026,339.831 ; v1(195.568,341.757) 196.748,341.757 197.104,341.401 197.039,341.336 v2(197.039,340.639)
  L16 w0.2: v1@199.452,328.887 v1(199.479,328.887)
  L16 w0.254: v1(198.847,334.75) v1@198.897,334.75
  L16 w0.3: v1@193.116,328.325 v1(193.116,328.384)
  other v3: 162.397,293.539 164.397,293.539 166.397,293.539 168.397,293.539 170.397,293.539 172.397,293.539 174.397,293.539 176.397,293.539 178.397,293.539 163.397,295.539 165.397,295.539
  other v5: 177.397,305.539 177.397,307.539 177.397,308.539
  other v6: 112.047,170.186 110.249,170.206 108.45,170.226 104.854,170.267 106.652,170.246 103.056,170.287 101.258,170.307 111.158,171.095 109.36,171.115 105.763,171.156 107.561,171.135 103.965,171.176 102.167,171.196
RAM_VrefA: C221.1 R166.1 R168.1 U8.M1 | length 0.6
  L1 w0.2: U8.M1@206.857,336.86 v3(207.261,337.264)
RAM_VrefB: C243.1 R169.1 R170.1 U10.M1 | length 7.8
  L1 w0.2: v2(193.786,341.617) 194.952,341.617 196.417,340.153 196.417,337.357 195.92,336.86 U10.M1@195.397,336.86
  L3 (Sign) w0.2: v2(193.786,341.617) 193.786,342.141
RAM_VrefC: C219.1 R165.1 R167.1 U9.M1
RAM_VrefD: C245.1 R171.1 R172.1 U11.M1 | length 0.6
  L1 w0.25: U11.M1@183.936,336.86 v3(184.34,337.264)
RefClk_Si53323_N: R253.1 R255.2 U31.7
RefClk_Si53323_P: C341.2 R252.1 R254.2 U31.6
RESET_N: R712.1 R713.2 U39.43 | length 1.2
  L16 w0.12: U39.43@108.049,275.125 108.049,274.309 v1(108.344,274.015)
RESETB: U45.27 U74.4
RST_brigde: R757.1 U3_I2C_Bridge_SFP.24 U35_I2C_Expander_Main_Rst.1
SD_Card_CLK: J28.5 U47.C5 | length 6.8
  L16 w0.098: J28.5@127.237,335.032 130.228,335.032 130.6,335.404 U47.C5@133.927,335.404
SD_Card_en: R382.1 U47.C2 | length 6.8
  L14 (Sign) w0.12: v22(135.129,335.404) 136.23,335.404 136.703,335.877 v9(136.703,337.858)
  L16 w0.12: v9(136.703,337.858) 136.703,338.84 137.385,339.522 R382.1@138.513,339.522
Sel_CLK_R: R900.1 U1.K12 | length 90.5
  L1 w0.116: U1.K12@171.397,299.539 v2(171.884,299.052)
  L3 (Sign) w0.12: v2(171.884,299.052) 171.468,299.052 170.84,298.425 166.56,298.425 166.103,298.882 160.604,298.882 160.045,298.323 160.045,293.918 156.396,290.269 156.396,289.545 156.396,286.815 162.761,280.45 177.671,280.45 179.106,279.015 217.475,279.015
SetClk_Si53323_2: R900.2 T36.1
SFP0_ABS: J32.6 R65.1 | length 4.4
  L1 w0.12: R65.1@54.779,285.118 v4(55.639,285.118)
  L16 w0.12: v4(55.639,285.118) 56.31,284.447 J32.6@58.904,284.447
SFP0_LOS: J32.8 R66.1 U35_I2C_Expander_SFP.4 | length 35.6
  L1 w0.12: U35_I2C_Expander_SFP.4@39.827,309.578 39.84,309.566 39.84,308.496 v7(39.853,308.483) ; R66.1@54.779,286.047 v4(55.639,286.047)
  L3 (Sign) w0.12: v7(39.853,308.483) 39.853,300.103 54.029,285.926 54.029,285.75 55.342,285.75 v4(55.639,286.047)
  L16 w0.12: v4(55.639,286.047) J32.8@58.904,286.047
SFP0_RS0: J32.7 R72.2 R74.1 | length 7.1
  L1 w0.2: R74.1@54.293,288.188 54.991,288.188 v1(55.004,288.201) 55.72,288.201 R72.2@55.733,288.188
  L14 (Sign) w0.2: v1(55.004,288.201) 55.004,288.125 56.997,286.132 v9(56.997,285.247)
  L16 w0.2: v9(56.997,285.247) J32.7@58.904,285.247
SFP0_RS1: J32.9 R71.2 R73.1 | length 6.3
  L1 w0.2: R73.1@54.293,289.204 v1(55.016,289.204) R71.2@55.733,289.204
  L16 w0.2: v1(55.016,289.204) 57.374,286.847 J32.9@58.904,286.847
SFP0_Rx_N: J32.19 U1.D5 | length 109
  L14 (Sign) w0.076: 165.112,287.487 ccw(c165.059,287.487) 165.059,287.539 165.059,292.771 cw(c165.24,292.771) 165.24,292.951 cw(c165.24,292.794) 165.397,292.794 v3(165.397,292.539)
  L14 (Sign) w0.08: v9(76.759,284.447) cw(c76.869,284.447) 76.869,284.557 163.792,284.557 ccw(c163.792,285.877) 165.112,285.877 165.112,287.487
  L16 w0.081: J32.19@67.104,280.847 68.038,280.847 ccw(c68.038,280.954) 68.145,280.954 73.081,280.954 ccw(c73.081,282.765) 74.893,282.765 74.893,283.732 cw(c75.616,283.732) 75.616,284.455 76.759,284.455 v9(76.759,284.447)
SFP0_Rx_P: J32.18 U1.D6 | length 108.8
  L14 (Sign) w0.076: 164.732,287.487 cw(c164.784,287.487) 164.784,287.539 164.784,292.771 cw(c165.24,292.771) 165.24,293.227 ccw(c165.24,293.384) 165.397,293.384 v3(165.397,293.539)
  L14 (Sign) w0.08: v9(76.759,285.047) ccw(c76.869,285.047) 76.869,284.937 163.792,284.937 ccw(c163.792,285.877) 164.732,285.877 164.732,287.487
  L16 w0.081: J32.18@67.104,281.647 68.038,281.647 cw(c68.038,281.539) 68.145,281.539 73.081,281.539 ccw(c73.081,282.765) 74.308,282.765 74.308,283.732 cw(c75.616,283.732) 75.616,285.04 76.759,285.04 v9(76.759,285.047)
SFP0_Tx_N: J32.12 U1.D1 | length 113
  L14 (Sign) w0.076: v3(165.397,288.539) 165.397,288.754 cw(c165.544,288.754) 165.544,288.902 165.568,288.902 cw(c165.568,288.722) 165.748,288.722 165.748,287.539 ccw(c165.748,287.487) 165.696,287.487
  L14 (Sign) w0.08: v9(69.139,286.347) ccw(c69.249,286.347) 69.249,286.237 72.056,286.237 cw(c72.056,284.404) 73.889,284.404 73.889,283.844 ccw(c74.562,283.844) 74.562,283.171 130.962,283.171 cw(c130.962,281.825) 132.309,281.825 132.309,280.365 ccw(c133.274,280.365) 133.274,279.4 164.313,279.4 ccw(c164.313,280.783) 165.696,280.783 165.696,287.487
  L16 w0.081: J32.12@67.104,286.447 68.038,286.447 cw(c68.038,286.339) 68.145,286.339 69.139,286.339 v9(69.139,286.347)
SFP0_Tx_P: J32.13 U1.D2 | length 114
  L14 (Sign) w0.076: v3(165.397,289.539) 165.397,289.325 ccw(c165.544,289.325) 165.544,289.177 165.568,289.177 cw(c165.568,288.722) 166.023,288.722 166.023,287.539 cw(c166.023,287.487) 166.075,287.487
  L14 (Sign) w0.08: v9(69.139,285.747) cw(c69.249,285.747) 69.249,285.857 72.056,285.857 cw(c72.056,284.404) 73.509,284.404 73.509,283.844 ccw(c74.562,283.844) 74.562,282.791 130.962,282.791 cw(c130.962,281.825) 131.929,281.825 131.929,280.365 ccw(c133.274,280.365) 133.274,279.02 164.313,279.02 ccw(c164.313,280.783) 166.075,280.783 166.075,287.487
  L16 w0.081: J32.13@67.104,285.647 68.038,285.647 ccw(c68.038,285.754) 68.145,285.754 69.139,285.754 v9(69.139,285.747)
SFP0_TxDis: J32.3 R68.1 U35_I2C_Expander_SFP.3 | length 38.1
  L1 w0.12: v7(39.177,308.496) U35_I2C_Expander_SFP.3@39.177,309.578 ; R68.1@54.779,284.205 v4(55.639,284.205)
  L3 (Sign) w0.12: v7(39.177,308.496) 39.177,306.993 39.633,306.538 39.633,300.012 53.809,285.835 53.809,285.53 54.314,285.53 v4(55.639,284.205)
  L16 w0.12: v4(55.639,284.205) 56.134,283.71 56.134,282.74 56.828,282.047 J32.3@58.904,282.047
SFP0_TxF: J32.2 R67.1 U35_I2C_Expander_SFP.2 | length 39.1
  L1 w0.12: v7(38.527,308.483) U35_I2C_Expander_SFP.2@38.527,309.578 ; R67.1@54.779,283.247 54.794,283.261 v4(55.639,283.261)
  L3 (Sign) w0.12: v7(38.527,308.483) 38.527,307.332 39.413,306.446 39.413,299.921 53.589,285.744 53.589,285.31 v4(55.639,283.261)
  L16 w0.12: v4(55.639,283.261) 55.639,282.067 56.459,281.247 J32.2@58.904,281.247
SFP0_VccR: C37.2 C38.1 J32.15 L1.2
SFP0_VccT: C39.2 C40.1 J32.16 L2.2
SFP1_ABS: J33.6 R135.1 | length 4.4
  L1 w0.12: R135.1@54.767,313.497 v4(55.702,313.497)
  L16 w0.12: v4(55.702,313.497) 56.379,313.497 56.56,313.316 57.134,313.316 57.503,312.947 J33.6@58.904,312.947
SFP1_LOS: J33.8 R136.1 U35_I2C_Expander_SFP.24 | length 30.3
  L1 w0.12: v7(35.903,313.131) 35.917,313.117 36.938,313.117 U35_I2C_Expander_SFP.24@36.952,313.103 ; R136.1@54.776,314.403 v4(55.702,314.403)
  L3 (Sign) w0.12: v7(35.903,313.131) 35.348,313.686 35.348,314.633 38.824,318.11 48.367,318.11 52.073,314.403 v4(55.702,314.403)
  L16 w0.12: v4(55.702,314.403) 58.761,314.403 J33.8@58.904,314.547
SFP1_RS0: J33.7 R142.2 R144.1 | length 6.2
  L1 w0.2: R144.1@54.222,315.759 v1(54.864,315.759) v1@54.877,315.759
  L14 (Sign) w0.2: v1(54.864,315.759) 55.372,315.251 56.256,315.251 56.883,314.624 56.883,313.817 v9(56.807,313.741)
  L16 w0.2: v9(56.807,313.741) 58.898,313.741 J33.7@58.904,313.747
SFP1_RS1: J33.9 R141.2 R143.1 | length 5.4
  L1 w0.2: v1(54.813,316.827) R141.2@55.461,316.827
  L16 w0.2: v1(54.813,316.827) 55.829,316.827 57.309,315.347 J33.9@58.904,315.347
SFP1_Rx_N: J33.19 U1.C7 | length 129.4
  L14 (Sign) w0.076: 161.345,295.858 ccw(c161.345,295.91) 161.397,295.91 163.512,295.91 cw(c163.512,295.678) 163.745,295.678 163.745,295.266 ccw(c164.109,295.266) 164.109,294.902 cw(c164.109,294.614) 164.397,294.614 v3(164.397,294.539)
  L14 (Sign) w0.08: v9(62.509,315.141) cw(c62.619,315.141) 62.619,315.251 114.452,315.251 cw(c114.452,312.711) 116.992,312.711 116.992,312.477 116.992,309.918 ccw(c117.919,309.918) 117.919,308.991 136.03,308.991 cw(c136.03,308.52) 136.501,308.52 ccw(c137.159,308.52) 137.159,307.862 149.338,307.862 cw(c149.338,306.921) 150.279,306.921 150.279,296.761 ccw(c151.182,296.761) 151.182,295.858 153.379,295.858 161.345,295.858
  L16 w0.081: v9(62.509,315.141) 62.509,315.15 63.335,315.15 cw(c63.335,314.639) 63.846,314.639 63.846,310.325 ccw(c64.714,310.325) 64.714,309.456 66.064,309.456 ccw(c66.173,309.456) 66.173,309.347 J33.19@67.104,309.347
SFP1_Rx_P: J33.18 U1.C8 | length 129.4
  L14 (Sign) w0.076: 161.345,296.238 cw(c161.345,296.186) 161.397,296.186 163.512,296.186 cw(c163.512,295.678) 164.02,295.678 164.02,295.266 ccw(c164.109,295.266) 164.109,295.177 ccw(c164.109,295.465) 164.397,295.465 v3(164.397,295.539)
  L14 (Sign) w0.08: v9(62.509,315.741) ccw(c62.619,315.741) 62.619,315.631 114.452,315.631 cw(c114.452,312.711) 117.372,312.711 117.372,312.477 117.372,309.918 ccw(c117.919,309.918) 117.919,309.371 136.03,309.371 cw(c136.03,308.52) 136.881,308.52 ccw(c137.159,308.52) 137.159,308.242 149.338,308.242 cw(c149.338,306.921) 150.659,306.921 150.659,296.761 ccw(c151.182,296.761) 151.182,296.238 153.379,296.238 161.345,296.238
  L16 w0.081: v9(62.509,315.741) 62.509,315.732 63.335,315.732 cw(c63.335,314.639) 64.427,314.639 64.427,310.325 ccw(c64.714,310.325) 64.714,310.037 66.064,310.037 cw(c66.173,310.037) 66.173,310.147 J33.18@67.104,310.147
SFP1_Tx_N: J33.12 U1.C3 | length 123.1
  L14 (Sign) w0.076: 161.345,291.845 ccw(c161.345,291.897) 161.397,291.897 163.402,291.897 cw(c163.402,291.554) 163.745,291.554 163.745,291.431 ccw(c164.274,291.431) 164.274,290.902 cw(c164.274,290.779) 164.397,290.779 v3(164.397,290.539)
  L14 (Sign) w0.08: v9(65.354,314.847) cw(c65.244,314.847) 65.244,314.737 64.859,314.737 ccw(c64.859,314.026) 64.149,314.026 64.149,311.074 ccw(c65.481,311.074) 65.481,309.741 111.278,309.741 cw(c111.278,307.201) 113.074,308.998 113.312,308.76 ccw(c115.329,310.777) 115.329,307.924 134.112,307.924 134.304,307.924 cw(c134.304,307.226) 135.002,307.226 135.002,306.654 ccw(c136.844,306.654) 136.844,304.813 147.739,304.813 cw(c147.739,303.935) 148.617,303.935 148.617,292.786 ccw(c149.558,292.786) 149.558,291.845 152.337,291.845 161.345,291.845
  L16 w0.081: v9(65.354,314.847) 65.354,314.837 66.064,314.837 cw(c66.173,314.837) 66.173,314.947 J33.12@67.104,314.947
SFP1_Tx_P: J33.13 U1.C4 | length 122
  L14 (Sign) w0.076: 161.345,292.225 cw(c161.345,292.172) 161.397,292.172 163.402,292.172 cw(c163.402,291.554) 164.02,291.554 164.02,291.431 ccw(c164.274,291.431) 164.274,291.177 ccw(c164.274,291.3) 164.397,291.3 v3(164.397,291.539)
  L14 (Sign) w0.08: v9(65.354,314.247) ccw(c65.244,314.247) 65.244,314.357 64.859,314.357 ccw(c64.859,314.026) 64.529,314.026 64.529,311.074 ccw(c65.481,311.074) 65.481,310.121 111.279,310.121 cw(c111.279,307.203) 113.342,309.267 113.578,309.031 ccw(c115.333,310.786) 115.333,308.304 134.112,308.304 134.304,308.304 cw(c134.304,307.226) 135.382,307.226 135.382,306.654 ccw(c136.844,306.654) 136.844,305.193 147.739,305.193 cw(c147.739,303.935) 148.996,303.935 148.996,292.786 ccw(c149.558,292.786) 149.558,292.225 152.337,292.225 161.345,292.225
  L16 w0.081: v9(65.354,314.247) 65.354,314.256 66.064,314.256 ccw(c66.173,314.256) 66.173,314.147 J33.13@67.104,314.147
SFP1_TxDis: J33.3 R138.1 U35_I2C_Expander_SFP.23 | length 31.1
  L1 w0.12: v7(35.903,313.747) 35.906,313.75 36.949,313.75 U35_I2C_Expander_SFP.23@36.952,313.753 ; R138.1@54.779,312.59 v4(55.702,312.59)
  L3 (Sign) w0.12: v7(35.903,313.747) 35.568,314.082 35.568,314.542 38.882,317.857 48.309,317.857 51.982,314.183 54.109,314.183 v4(55.702,312.59)
  L16 w0.12: v4(55.702,312.59) 56.223,312.069 56.223,311.218 56.769,310.671 58.78,310.671 J33.3@58.904,310.547
SFP1_TxF: J33.2 R137.1 U35_I2C_Expander_SFP.22 | length 30.2
  L1 w0.12: v7(35.903,314.403) U35_I2C_Expander_SFP.22@36.952,314.403 ; R137.1@54.779,311.684 v4(55.702,311.684)
  L3 (Sign) w0.12: v7(35.903,314.403) 39.114,317.614 48.24,317.614 51.891,313.963 53.423,313.963 v4(55.702,311.684)
  L16 w0.12: v4(55.702,311.684) 55.702,310.553 56.514,309.741 58.899,309.741 J33.2@58.904,309.747
SFP1_VccR: C207.2 C208.1 J33.15 L3.2
SFP1_VccT: C209.2 C210.1 J33.16 L4.2
SFP2_ABS: J34.6 R145.1 | length 4.4
  L1 w0.12: R145.1@54.794,270.912 v4(55.639,270.912)
  L16 w0.12: v4(55.639,270.912) 56.355,270.197 J34.6@58.904,270.197
SFP2_LOS: J34.8 R146.1 U35_I2C_Expander_SFP.27 | length 55
  L1 w0.12: v7(35.903,311.153) U35_I2C_Expander_SFP.27@36.952,311.153 ; R146.1@54.794,271.797 v4(55.639,271.797)
  L3 (Sign) w0.12: v7(35.903,311.153) 35.671,310.921 35.671,301.015 41.626,295.06 41.626,282.262 52.091,271.797 v4(55.639,271.797)
  L16 w0.12: v4(55.639,271.797) J34.8@58.904,271.797
SFP2_RS0: J34.7 R152.2 R154.1 | length 6.9
  L1 w0.2: R154.1@54.105,273.456 v1(54.813,273.456) R152.2@55.514,273.456
  L14 (Sign) w0.2: v1(54.813,273.456) 55.385,272.885 55.696,272.885 56.938,271.642 v9(56.938,271.005)
  L16 w0.2: v9(56.938,271.005) 58.896,271.005 J34.7@58.904,270.997
SFP2_RS1: J34.9 R151.2 R153.1 | length 6.3
  L1 w0.2: R153.1@54.105,274.472 R151.2@55.514,274.472
  L16 w0.2: v1(54.794,274.472) 55.524,274.472 57.4,272.597 J34.9@58.904,272.597
SFP2_Rx_N: J34.19 U1.B5 | length 123.6
  L12 (Sign) w0.073: v1(69.113,266.697) cw(c69.314,266.697) 69.314,266.897 75.876,266.897 ccw(c75.876,268.097) 77.076,268.097 cw(c79.048,268.097) 79.048,270.069 123.698,270.069 ccw(c123.698,271.39) 125.019,271.39 125.019,275.73 cw(c125.924,275.73) 125.924,276.635 163.855,276.635 ccw(c163.855,277.787) 165.008,277.787 165.008,287.539 165.008,291.579 ccw(c164.424,291.579) 164.424,292.163 163.258,292.163 cw(c163.258,292.417) 163.005,292.417 163.005,292.647 cw(c163.297,292.647) 163.297,292.939 cw(c163.297,292.839) 163.397,292.839 v3(163.397,292.539)
  L16 w0.081: J34.19@67.104,266.597 68.045,266.597 ccw(c68.045,266.697) 68.145,266.697 v1(69.113,266.697)
SFP2_Rx_P: J34.18 U1.B6 | length 123.6
  L12 (Sign) w0.073: v1(69.113,267.297) ccw(c69.314,267.297) 69.314,267.096 75.876,267.096 ccw(c75.876,268.097) 76.877,268.097 cw(c79.048,268.097) 79.048,270.269 123.698,270.269 ccw(c123.698,271.39) 124.819,271.39 124.819,275.73 cw(c125.924,275.73) 125.924,276.835 163.855,276.835 ccw(c163.855,277.787) 164.808,277.787 164.808,287.539 164.808,291.579 ccw(c164.424,291.579) 164.424,291.964 163.258,291.964 cw(c163.258,292.417) 162.805,292.417 162.805,292.647 cw(c163.297,292.647) 163.297,293.139 ccw(c163.297,293.24) 163.397,293.24 v3(163.397,293.539)
  L16 w0.081: J34.18@67.104,267.397 68.045,267.397 cw(c68.045,267.297) 68.145,267.297 v1(69.113,267.297)
SFP2_Tx_N: J34.12 U1.B1 | length 112.3
  L12 (Sign) w0.073: v1(69.101,272.097) ccw(c69.301,272.097) 69.301,271.896 121.907,271.896 ccw(c121.907,272.395) 122.406,272.395 122.406,275.162 cw(c125.146,275.162) 125.146,277.901 161.684,277.901 ccw(c161.684,280.01) 163.792,280.01 163.792,287.539 163.792,288.724 ccw(c163.576,288.724) 163.576,288.939 163.51,288.939 ccw(c163.51,288.826) 163.397,288.826 v3(163.397,288.539)
  L16 w0.081: J34.12@67.104,272.197 68.038,272.197 cw(c68.038,272.089) 68.145,272.089 69.101,272.089 v1(69.101,272.097)
SFP2_Tx_P: J34.13 U1.B2 | length 112.9
  L12 (Sign) w0.073: v1(69.101,271.497) cw(c69.301,271.497) 69.301,271.697 121.907,271.697 ccw(c121.907,272.395) 122.606,272.395 122.606,275.162 cw(c125.146,275.162) 125.146,277.702 161.684,277.702 ccw(c161.684,280.01) 163.992,280.01 163.992,287.539 163.992,288.724 ccw(c163.576,288.724) 163.576,289.139 163.51,289.139 cw(c163.51,289.252) 163.397,289.252 v3(163.397,289.539)
  L16 w0.081: J34.13@67.104,271.397 68.038,271.397 ccw(c68.038,271.504) 68.145,271.504 69.101,271.504 v1(69.101,271.497)
SFP2_TxDis: J34.3 R148.1 U35_I2C_Expander_SFP.26 | length 58.2
  L1 w0.12: v7(35.903,311.79) 35.909,311.797 36.946,311.797 U35_I2C_Expander_SFP.26@36.952,311.803 ; R148.1@54.794,270.046 v4(55.639,270.046)
  L3 (Sign) w0.12: v7(35.903,311.79) 35.451,311.339 35.451,300.923 41.406,294.968 41.406,282.171 52,271.577 54.108,271.577 v4(55.639,270.046)
  L16 w0.12: v4(55.639,270.046) 56.22,269.466 56.22,268.495 56.728,267.987 58.714,267.987 J34.3@58.904,267.797
SFP2_TxF: J34.2 R147.1 U35_I2C_Expander_SFP.25 | length 59.3
  L1 w0.12: v7(35.903,312.517) 35.935,312.485 36.92,312.485 U35_I2C_Expander_SFP.25@36.952,312.453 ; R147.1@54.798,269.173 v4(55.639,269.173)
  L3 (Sign) w0.12: v7(35.903,312.517) 35.231,311.846 35.231,300.832 41.186,294.877 41.186,282.08 51.909,271.357 53.455,271.357 v4(55.639,269.173)
  L16 w0.12: v4(55.639,269.173) 55.66,269.151 55.66,268.743 57.216,267.187 58.714,267.187 J34.2@58.904,266.997
SFP2_VccR: C211.2 C212.1 J34.15 L5.2
SFP2_VccT: C213.2 C214.1 J34.16 L6.2
SFP3_ABS: J35.6 R155.1 | length 4.5
  L1 w0.12: R155.1@54.767,299.431 55.905,299.431 v4(55.927,299.453)
  L16 w0.12: v4(55.927,299.453) 55.949,299.431 56.298,299.431 57.033,298.697 J35.6@58.904,298.697
SFP3_LOS: J35.8 R156.1 U35_I2C_Expander_SFP.19 | length 33.7
  L1 w0.12: U35_I2C_Expander_SFP.19@39.177,315.328 v7(39.177,316.297) ; R156.1@54.776,300.308 v4(55.905,300.308)
  L3 (Sign) w0.12: v7(39.177,316.297) 39.732,316.852 43.998,316.852 50.344,310.506 50.344,302.315 52.35,300.308 v4(55.905,300.308)
  L16 w0.12: v4(55.905,300.308) J35.8@58.892,300.308
SFP3_RS0: J35.7 R162.2 R164.1 | length 7.4
  L1 w0.2: R164.1@53.532,302.189 v1(54.204,302.189) R162.2@54.871,302.189
  L14 (Sign) w0.2: v1(54.204,302.189) 54.973,302.189 57.112,300.05 v9(57.112,299.652)
  L16 w0.2: v9(57.112,299.652) 57.267,299.497 J35.7@58.904,299.497
SFP3_RS1: J35.9 R161.2 R163.1 | length 6.9
  L1 w0.2: R163.1@53.532,303.205 R161.2@54.871,303.205
  L16 w0.2: v1(54.204,303.225) 54.94,302.489 55.778,302.489 57.17,301.097 J35.9@58.904,301.097
SFP3_Rx_N: J35.19 U1.A7 | length 113.4
  L12 (Sign) w0.073: v1(72.612,296.361) cw(c73.296,296.361) 72.812,296.844 cw(c73.015,296.642) 73.015,296.928 74.282,296.928 124.496,296.928 cw(c124.496,295.631) 125.793,295.631 125.793,288.154 ccw(c127.495,288.154) 127.495,286.452 148.831,286.452 ccw(c148.831,287.388) 149.767,287.388 149.767,294.373 cw(c150.326,294.373) 150.326,294.932 161.397,294.932 ccw(c161.435,294.932) 161.435,294.894
  L12 (Sign) w0.076: 161.435,294.894 162.255,294.894 cw(c162.255,294.752) 162.397,294.752 v3(162.397,294.539)
  L16 w0.081: J35.19@67.104,295.097 68.037,295.097 ccw(c68.037,295.204) 68.145,295.204 70.152,295.204 ccw(c70.152,298.326) 72.359,296.118 72.602,296.361 v1(72.612,296.361)
SFP3_Rx_P: J35.18 U1.A8 | length 113.1
  L12 (Sign) w0.073: v1(72.188,296.785) ccw(c72.188,297.469) 72.671,296.985 72.673,296.987 cw(c73.013,296.646) 73.013,297.127 74.282,297.127 124.496,297.127 cw(c124.496,295.631) 125.993,295.631 125.993,288.154 ccw(c127.495,288.154) 127.495,286.652 148.831,286.652 ccw(c148.831,287.388) 149.568,287.388 149.568,294.373 cw(c150.326,294.373) 150.326,295.132 161.397,295.132 cw(c161.435,295.132) 161.435,295.17
  L12 (Sign) w0.076: 161.435,295.17 162.255,295.17 ccw(c162.255,295.311) 162.397,295.311 v3(162.397,295.539)
  L16 w0.081: J35.18@67.104,295.897 68.037,295.897 cw(c68.037,295.789) 68.145,295.789 70.15,295.789 ccw(c70.15,298.329) 71.946,296.533 72.188,296.775 v1(72.188,296.785)
SFP3_Tx_N: J35.12 U1.A3 | length 116.3
  L14 (Sign) w0.076: 161.345,290.849 ccw(c161.345,290.902) 161.397,290.902 162.217,290.902 cw(c162.217,290.722) 162.397,290.722 v3(162.397,290.539)
  L14 (Sign) w0.08: 63.285,299.656 63.285,295.592 ccw(c64.403,295.592) 64.403,294.475 123.622,294.475 cw(c123.622,294.017) 124.08,294.017 124.08,288.595 ccw(c125.135,288.595) 125.135,287.54 148.349,287.54 ccw(c148.349,288.391) 149.2,288.391 149.2,290.48 cw(c149.569,290.48) 149.569,290.849 161.345,290.849 ; 64.122,300.494 65.34,300.494 ccw(c65.34,300.597) v1(65.443,300.597)
  L16 w0.081: v1(65.443,300.597) 65.443,300.589 66.064,300.589 cw(c66.171,300.589) 66.171,300.697 J35.12@67.104,300.697
SFP3_Tx_P: J35.13 U1.A4 | length 115.7
  L14 (Sign) w0.076: 161.345,291.229 cw(c161.345,291.177) 161.397,291.177 162.217,291.177 ccw(c162.217,291.357) 162.397,291.357 v3(162.397,291.539)
  L14 (Sign) w0.08: 63.665,299.656 63.665,295.592 ccw(c64.403,295.592) 64.403,294.855 123.622,294.855 cw(c123.622,294.017) 124.46,294.017 124.46,288.595 ccw(c125.135,288.595) 125.135,287.92 148.349,287.92 ccw(c148.349,288.391) 148.82,288.391 148.82,290.48 cw(c149.569,290.48) 149.569,291.229 161.345,291.229 ; 64.122,300.114 65.326,300.114 cw(c65.326,299.997) v1(65.443,299.997)
  L16 w0.081: v1(65.443,299.997) 65.443,300.004 66.064,300.004 ccw(c66.171,300.004) 66.171,299.897 J35.13@67.104,299.897
SFP3_TxDis: J35.3 R158.1 U35_I2C_Expander_SFP.18 | length 35.2
  L1 w0.12: U35_I2C_Expander_SFP.18@39.827,315.328 v7(39.827,316.297) ; R158.1@54.779,298.554 v4(55.905,298.554)
  L3 (Sign) w0.12: v7(39.827,316.297) 40.162,316.632 43.907,316.632 50.124,310.415 50.124,302.224 52.259,300.088 54.371,300.088 v4(55.905,298.554)
  L16 w0.12: v4(55.905,298.554) 56.398,298.554 56.718,298.234 56.718,297.155 57.594,296.278 58.886,296.278 J35.3@58.904,296.297
SFP3_TxF: J35.2 R157.1 U35_I2C_Expander_SFP.17 | length 34.2
  L1 w0.12: U35_I2C_Expander_SFP.17@40.477,315.328 v7(40.477,316.297) ; R157.1@54.779,297.677 v4(55.905,297.677)
  L3 (Sign) w0.12: v7(40.477,316.297) 43.931,316.297 49.904,310.324 49.904,302.133 52.168,299.868 53.714,299.868 v4(55.905,297.677)
  L16 w0.12: v4(55.905,297.677) 55.905,297.16 57.569,295.497 J35.2@58.904,295.497
SFP3_VccR: C215.2 C216.1 J35.15 L7.2
SFP3_VccT: C217.2 C218.1 J35.16 L8.2
SFP_I2C4.SCL: R9_I2C_Bridge_SFP.2 R130.2 U3_I2C_Bridge_SFP.11 U58.13 | length 107.9
  L1 w0.2: U3_I2C_Bridge_SFP.11@89.47,304.096 v2(90.513,304.096) 91.198,304.096 91.688,304.586 R9_I2C_Bridge_SFP.2@91.738,304.586 ; v1(159.639,239.947) 160.071,240.378 160.071,241.201
  L5 (Sign) w0.2: v11(122.276,266.825) 124.193,266.825 151.071,239.947 v1(159.639,239.947)
  L3 (Sign) w0.2: v2(90.513,304.096) 92.65,304.096 102.764,293.981 108.218,293.981 119.35,282.849 119.35,268.708 121.233,266.825 v11(122.276,266.825)
SFP_I2C4.SDA: R10_I2C_Bridge_SFP.2 R131.2 U3_I2C_Bridge_SFP.10 U58.14 | length 109.3
  L1 w0.2: U3_I2C_Bridge_SFP.10@89.47,303.596 90.139,303.596 90.156,303.612 v2(90.449,303.612) R10_I2C_Bridge_SFP.2@91.738,303.612 ; v1(159.639,239.347) 160.264,239.347 161.165,240.248 161.165,241.093 161.265,241.193
  L5 (Sign) w0.2: v11(122.276,266.225) 124.193,266.225 151.071,239.347 v1(159.639,239.347)
  L3 (Sign) w0.2: v2(90.449,303.612) 92.709,303.612 102.64,293.681 108.094,293.681 119.05,282.725 119.05,268.583 121.409,266.225 v11(122.276,266.225)
SFP_I2C5.SCL: R7_I2C_Bridge_SFP.2 R22.2 R389.2 R457.2 R465.2 R563.2 R567.2 R571.2 R575.2 R579.2 R583.2 R587.2 R591.2 R593.2 R597.2 U3_I2C_Bridge_SFP.13 U35_I2C_Expander_PWR_CLK.8 U35_I2C_Expander_PWR_Dist.8 U64_U_Pomiar_pradu_napiecia_1.5 U64_U_Pomiar_pradu_napiecia_2.5 U64_U_Pomiar_pradu_napiecia_3.5 U64_U_Pomiar_pradu_napiecia_4.5 U64_U_Pomiar_pradu_napiecia_5.5 U64_U_Pomiar_pradu_napiecia_6.5 U72.5 | length 369.5
  L1 w0.2: v7(30.713,151.621) R465.2@30.838,151.621 ; U64_U_Pomiar_pradu_napiecia_1.5@33.245,157.414 33.245,156.428 33.62,156.053 34.279,156.053 35.079,155.253 35.079,152.071 34.629,151.621 34.195,151.621 v7(33.895,151.621) ; v2(47.143,154.724) U35_I2C_Expander_PWR_Dist.8@47.143,156.428 ; U3_I2C_Bridge_SFP.13@88.785,305.281 88.785,305.803 v2(89.373,306.39) 89.93,306.948 R7_I2C_Bridge_SFP.2@89.93,307.492 ; U64_U_Pomiar_pradu_napiecia_6.5@115.141,200.508 116.635,200.508 117.098,200.971 117.098,201.775 117.83,202.507 120.948,202.507 121.73,201.725 v7(121.73,201.096) R587.2@121.73,200.971 ; U64_U_Pomiar_pradu_napiecia_5.5@118.748,217.393 119.952,217.393 120.414,217.855 120.414,218.193 120.826,218.605 124.153,218.605 124.536,218.222 R579.2@124.536,217.437 ; U64_U_Pomiar_pradu_napiecia_3.5@120.678,184.159 122.237,184.159 122.387,184.31 122.387,185.396 123.039,186.048 125.79,186.048 126.53,185.307 R563.2@126.53,184.76 ; U64_U_Pomiar_pradu_napiecia_4.5@120.907,167.903 122.547,167.903 122.664,168.021 122.664,168.792 123.711,169.838 126.737,169.838 127.313,169.262 R571.2@127.313,168.461 ; v7(124.536,214.38) R583.2@124.536,214.505 ; v7(127.313,165.404) R575.2@127.313,165.529 ; v1(136.131,273.716) 136.188,273.772 R389.2@136.866,273.772 ; U72.5@139.353,279.003 139.353,278.153 139.604,277.901 140.497,277.901 141.025,277.374 141.025,273.977 140.82,273.772 R22.2@139.754,273.772
  L5 (Sign) w0.2: v11(121.463,273.238) 135.928,273.238 136.153,273.463 136.153,273.694 v1(136.131,273.716) ; v11(121.73,196.761) 121.73,189.928 v11(124.62,187.038)
  L3 (Sign) w0.2: v4(29.001,211.587) v4(32.183,211.587) ; v7(30.713,151.621) v7(33.895,151.621) 36.521,151.621 39.624,154.724 v2(47.143,154.724) 48.158,154.724 48.44,155.005 57.933,155.005 59.084,153.854 114.603,153.854 123.515,162.767 125.188,162.767 127.313,164.892 v7(127.313,165.404) v7(127.313,168.586) 127.313,169.846 127.749,170.282 130.044,170.282 131.908,172.146 131.908,180.589 131.239,181.257 126.975,181.257 v7(126.53,181.703) v7(126.53,184.885) 126.53,185.128 v11(124.62,187.038) ; v2(89.373,306.39) 90.252,305.511 92.083,305.511 103.012,294.581 108.467,294.581 119.95,283.098 119.95,273.634 120.496,273.088 121.313,273.088 v11(121.463,273.238) ; v11(121.73,196.761) v7(121.73,197.989) 121.73,205.956 124.536,208.763 v7(124.536,214.38) v7(124.536,217.562) 124.259,217.562 120.536,221.285 120.536,245.052 126.745,251.262 126.745,271.446 129.015,273.716 v1(136.131,273.716) ; v7(136.741,273.772) v7(139.879,273.772)
  L16 w0.2: v4(29.001,211.587) R597.2@29.126,211.587 ; R593.2@32.058,211.587 32.545,211.587 32.663,211.47 32.663,210.626 33.419,209.869 33.419,207.842 32.762,207.185 32.452,207.185 32.298,207.031 U64_U_Pomiar_pradu_napiecia_2.5@32.298,206.235
SFP_I2C5.SDA: R8_I2C_Bridge_SFP.2 R24.2 R390.2 R459.2 R466.2 R564.2 R568.2 R572.2 R576.2 R580.2 R584.2 R588.2 R592.2 R594.2 R598.2 U3_I2C_Bridge_SFP.12 U35_I2C_Expander_PWR_CLK.9 U35_I2C_Expander_PWR_Dist.9 U64_U_Pomiar_pradu_napiecia_1.4 U64_U_Pomiar_pradu_napiecia_2.4 U64_U_Pomiar_pradu_napiecia_3.4 U64_U_Pomiar_pradu_napiecia_4.4 U64_U_Pomiar_pradu_napiecia_5.4 U64_U_Pomiar_pradu_napiecia_6.4 U72.4 | length 363.3
  L1 w0.2: v7(30.713,152.637) R466.2@30.838,152.637 ; U64_U_Pomiar_pradu_napiecia_1.4@32.745,157.414 32.745,156.153 33.245,155.653 34.195,155.653 34.779,155.069 34.779,152.787 34.629,152.637 R459.2@33.77,152.637 ; U35_I2C_Expander_PWR_Dist.9@47.793,156.428 47.803,156.419 v2(47.803,155.296) ; U3_I2C_Bridge_SFP.12@89.47,304.596 90.724,304.596 ; v2(90.633,305.092) 90.724,305 90.724,304.596 ; R8_I2C_Bridge_SFP.2@91.738,305.56 91.688,305.56 90.724,304.596 ; U64_U_Pomiar_pradu_napiecia_6.4@115.141,200.008 117.004,200.008 117.398,200.403 117.398,201.651 117.868,202.121 120.17,202.121 120.714,201.577 v7(120.714,201.096) ; U64_U_Pomiar_pradu_napiecia_5.4@118.748,216.893 120.098,216.893 120.714,217.509 120.714,217.943 120.964,218.193 123.403,218.193 123.52,218.076 R580.2@123.52,217.437 ; U64_U_Pomiar_pradu_napiecia_3.4@120.678,183.659 122.387,183.659 122.758,184.03 122.758,185.343 123.116,185.701 125.214,185.701 125.514,185.401 R564.2@125.514,184.76 ; v7(120.714,197.989) R592.2@120.714,198.039 ; U64_U_Pomiar_pradu_napiecia_4.4@120.907,167.403 122.682,167.403 123.039,167.761 123.039,168.63 123.947,169.538 125.797,169.538 126.297,169.038 R572.2@126.297,168.461 ; v7(123.52,214.38) R584.2@123.52,214.505 ; v7(125.514,181.703) R568.2@125.514,181.828 ; v1(136.042,274.79) 136.859,274.79 R390.2@136.866,274.797 v7(136.741,274.797) ; U72.4@138.853,279.003 138.853,277.853 139.193,277.513 140.229,277.513 140.614,277.127 140.614,274.914 140.497,274.797 R24.2@139.754,274.797
  L5 (Sign) w0.2: v11(120.688,196.774) 120.688,189.711 v11(123.457,186.942) ; v11(121.463,272.638) 136.031,272.638 136.741,273.348 136.741,274.091 v1(136.042,274.79)
  L3 (Sign) w0.2: v4(29.001,210.571) v4(32.183,210.571) ; v7(30.713,152.637) v7(33.895,152.637) 36.635,152.637 39.294,155.296 v2(47.803,155.296) 47.812,155.305 58.103,155.305 59.254,154.154 114.433,154.154 123.345,163.067 125.018,163.067 126.297,164.346 v7(126.297,165.404) v7(126.297,168.586) 126.297,169.987 126.901,170.591 129.916,170.591 131.608,172.284 131.608,180.464 131.115,180.957 126.259,180.957 v7(125.514,181.703) v7(125.514,184.885) v11(123.457,186.942) ; v2(90.633,305.092) 92.077,305.092 102.888,294.281 108.342,294.281 119.65,282.974 119.65,273.51 120.372,272.788 121.313,272.788 v11(121.463,272.638) ; v11(120.688,196.774) 120.688,197.963 v7(120.714,197.989) v7(120.714,201.096) 120.714,206.706 123.52,209.512 v7(123.52,214.38) v7(123.52,217.562) 120.231,220.851 120.231,245.172 126.445,251.386 126.445,271.662 129.573,274.79 v1(136.042,274.79) ; v7(136.741,274.797) v7(139.879,274.797)
  L16 w0.2: v4(29.001,210.571) R598.2@29.126,210.571 ; U64_U_Pomiar_pradu_napiecia_2.4@31.798,206.235 31.798,207.28 32.058,207.54 32.693,207.54 33.007,207.854 33.007,209.671 32.108,210.571 R594.2@32.058,210.571
SFP_I2C6.SCL: R5_I2C_Bridge_SFP.2 U3_I2C_Bridge_PCIE.19 U3_I2C_Bridge_SFP.15 | length 101.2
  L1 w0.2: R5_I2C_Bridge_SFP.2@87.775,307.492 87.785,307.482 U3_I2C_Bridge_SFP.15@87.785,305.281 ; v1(98.87,388.569) 99.004,388.569 99.722,387.851 99.735,387.863 U3_I2C_Bridge_PCIE.19@100.135,387.863
  L5 (Sign) w0.2: v1(87.439,306.146) 87.439,306.73 88.476,307.767 94.026,307.767 99.5,313.24 99.5,324.455 105.057,330.012 v11(105.057,348.564) ; v1(98.87,388.569) 97.727,388.569 97.426,388.269 97.426,384.348 100.352,381.422 v11(100.352,373.355)
  L3 (Sign) w0.2: v11(100.352,373.355) 100.352,372.875 105.057,368.171 v11(105.057,348.564)
SFP_I2C6.SDA: R6_I2C_Bridge_SFP.2 U3_I2C_Bridge_PCIE.20 U3_I2C_Bridge_SFP.14 | length 100.4
  L1 w0.2: U3_I2C_Bridge_SFP.14@88.285,305.281 88.285,306.298 v1(88.415,306.428) 88.853,306.866 R6_I2C_Bridge_SFP.2@88.853,307.492 ; v1(98.87,387.96) 99.466,387.363 U3_I2C_Bridge_PCIE.20@100.135,387.363
  L5 (Sign) w0.2: v1(88.415,306.428) 88.935,306.948 94.883,306.948 99.8,311.864 99.8,323.675 105.657,329.532 v11(105.657,348.564) ; v1(98.87,387.96) 97.892,387.96 97.727,387.794 97.727,384.472 100.952,381.246 v11(100.952,373.355)
  L3 (Sign) w0.2: v11(100.952,373.355) 100.952,372.699 105.657,367.995 v11(105.657,348.564)
SFP_I2C7.SCL: R3_I2C_Bridge_SFP.2 U3_I2C_Bridge_SFP.17 U35_I2C_Expander_SFP.8 | length 48.5
  L1 w0.2: U35_I2C_Expander_SFP.8@42.702,310.503 43.669,310.503 45.898,308.274 v2(51.448,308.274) ; R3_I2C_Bridge_SFP.2@85.62,307.492 85.62,306.616 v2(85.938,306.299) 86.34,306.299 86.69,305.949 86.69,305.836 86.785,305.74 U3_I2C_Bridge_SFP.17@86.785,305.281
  L3 (Sign) w0.2: v2(51.448,308.274) 51.689,308.274 52.165,308.751 59.983,308.751 60.255,309.022 70.839,309.022 73.271,306.591 85.645,306.591 v2(85.938,306.299)
SFP_I2C7.SDA: R4_I2C_Bridge_SFP.2 U3_I2C_Bridge_SFP.16 U35_I2C_Expander_SFP.9 | length 49.3
  L1 w0.2: U35_I2C_Expander_SFP.9@42.702,311.153 43.443,311.153 45.872,308.724 v2(51.448,308.724) ; R4_I2C_Bridge_SFP.2@86.698,307.492 86.698,306.874 v2(87.013,306.558) 87.114,306.457 86.99,306.333 86.99,305.96 87.253,305.696 87.285,305.696 U3_I2C_Bridge_SFP.16@87.285,305.281
  L3 (Sign) w0.2: v2(51.448,308.724) 51.714,308.724 52.041,309.051 59.859,309.051 60.13,309.322 70.963,309.322 73.395,306.891 85.77,306.891 85.787,306.874 85.893,306.874 86.208,306.558 v2(87.013,306.558)
SFP_INT0: R854.2 U35_I2C_Expander_SFP.16
SFP_INT1: R857.2 U35_I2C_Expander_SFP.15
SFP_IO_nReset: R756.1 U35_I2C_Expander_Main_Rst.28 U35_I2C_Expander_SFP.14 | length 125.6
  L1 w0.2: U35_I2C_Expander_SFP.14@42.702,314.403 43.068,314.403 43.269,314.604 v1(43.269,314.973)
  L5 (Sign) w0.2: v1(43.269,314.973) 43.269,282.296 46.457,279.108 60.325,279.108 64.846,274.587 71.691,274.587 82.359,263.919 82.359,261.036 83.972,259.423 106.769,259.423 108.52,257.672 116.35,257.672 v1(117.424,258.746)
  L16 w0.2: U35_I2C_Expander_Main_Rst.28@115.873,260.018 117.261,260.018 117.691,259.588 ; v1(117.424,258.746) 117.691,259.013 117.691,259.588 ; R756.1@120.169,259.588 117.691,259.588
SGMI_C_Rx_N: C484.1 U1.G26 | length 81.5
  L1 w0.116: U1.G26@168.397,313.539 v5(168.884,313.052)
  L5 (Sign) w0.073: v1(127.483,280.827) cw(c127.683,280.827) 127.683,281.027 148.16,281.027 ccw(c148.16,282.232) 149.365,282.232 149.365,286.931 cw(c150.219,286.931) 150.219,287.786 150.673,287.786 ccw(c150.673,288.497) 151.384,288.497 151.384,303.898 cw(c152.266,303.898) 151.642,304.522 151.654,304.534 ccw(c151.028,305.16) 151.914,305.16 151.914,311.137 cw(c152.244,311.137) 152.244,311.467 161.397,311.467 167.411,311.467 ccw(c167.411,312.556) 168.5,312.556 168.5,312.941 cw(c168.612,312.941) 168.612,313.052 v5(168.884,313.052)
  L16 w0.081: C484.1@117.996,280.645 cw(c118.454,280.186) 118.454,280.835 127.483,280.835 v1(127.483,280.827)
SGMI_C_Rx_P: C483.1 U1.G25 | length 81.2
  L1 w0.116: v5(167.909,313.027) U1.G25@168.397,312.539
  L5 (Sign) w0.073: v1(127.483,281.427) ccw(c127.683,281.427) 127.683,281.227 148.16,281.227 ccw(c148.16,282.232) 149.165,282.232 149.165,286.931 cw(c150.219,286.931) 150.219,287.985 150.673,287.985 ccw(c150.673,288.497) 151.184,288.497 151.184,303.901 cw(c152.261,303.901) 151.5,304.662 151.511,304.673 ccw(c151.02,305.164) 151.714,305.164 151.714,311.137 cw(c152.244,311.137) 152.244,311.667 161.397,311.667 167.411,311.667 ccw(c167.411,312.556) 168.3,312.556 168.3,312.941 ccw(c168.214,312.941) 168.214,313.027 v5(167.909,313.027)
  L16 w0.081: C483.1@117.974,281.61 ccw(c118.432,282.068) 118.432,281.42 127.483,281.42 v1(127.483,281.427)
SGMI_C_Tx_N: C482.1 U1.G29 | length 88.8
  L1 w0.116: v5(167.909,317.027) U1.G29@168.397,316.539
  L5 (Sign) w0.073: v1(121.437,274.543) cw(c121.638,274.543) 121.638,274.743 121.832,274.743 ccw(c121.832,275.577) 122.666,275.577 122.666,281.593 cw(c123.177,281.593) 123.177,282.105 146.732,282.105 ccw(c146.732,283.172) 147.799,283.172 147.799,287.435 cw(c148.984,287.435) 148.984,288.62 149.653,288.62 ccw(c149.653,289.585) 150.618,289.585 150.618,316.357 cw(c151.688,316.357) 151.688,317.427 167.627,317.427 cw(c167.627,317.145) 167.909,317.145 v5(167.909,317.027)
  L16 w0.081: C482.1@120.503,274.345 120.701,274.543 v1(121.437,274.543) v1@121.437,274.55
SGMI_C_Tx_P: C479.1 U1.G30 | length 88.8
  L1 w0.116: v5(167.909,318.027) U1.G30@168.397,317.539
  L5 (Sign) w0.073: v1(121.437,275.143) ccw(c121.638,275.143) 121.638,274.943 121.832,274.943 ccw(c121.832,275.577) 122.466,275.577 122.466,281.593 cw(c123.177,281.593) 123.177,282.305 146.732,282.305 ccw(c146.732,283.172) 147.599,283.172 147.599,287.435 cw(c148.984,287.435) 148.984,288.82 149.653,288.82 ccw(c149.653,289.585) 150.419,289.585 150.419,316.357 cw(c151.689,316.357) 151.689,317.627 167.627,317.627 ccw(c167.627,317.909) 167.909,317.909 v5(167.909,318.027)
  L16 w0.081: C479.1@120.503,275.285 120.645,275.143 v1(121.437,275.143) v1@121.437,275.136
SGMI_CLK_Out_N: R320.1 R321.1 R326.2 U39.34 | length 10.3
  L16 w0.081: U39.34@111.699,276.775 111.997,276.775 cw(c111.997,276.732) 112.04,276.732 113.1,276.732 ccw(c113.1,279.106) 114.779,277.428 114.922,277.571 cw(c116.178,276.316) 116.178,278.091 118.759,278.091 cw(c118.759,277.554) R321.1@119.139,277.934 120.131,277.934 cw(c120.131,277.649) R320.1@120.332,277.851 R326.2@121.539,277.851
SGMI_CLK_Out_P: R319.1 R321.2 R325.2 U39.33 | length 10.3
  L16 w0.081: U39.33@111.699,277.275 111.997,277.275 ccw(c111.997,277.318) 112.04,277.318 113.099,277.318 ccw(c113.099,279.11) 114.366,277.843 114.509,277.985 cw(c116.178,276.316) 116.178,278.677 118.759,278.677 ccw(c118.759,279.214) R321.2@119.139,278.834 119.964,278.834 ccw(c119.964,279.356) R319.1@120.332,278.987 R325.2@121.539,278.987
SGMI_Rx_N: C484.2 U39.28 | length 6.1
  L16 w0.081: U39.28@111.699,279.775 112.007,279.775 112.078,279.705 115.088,279.705 116.218,280.835 117.026,280.835 C484.2@117.216,280.645
SGMI_Rx_P: C483.2 U39.27 | length 6
  L16 w0.081: U39.27@111.699,280.275 112.062,280.275 112.078,280.29 114.846,280.29 115.975,281.42 117.004,281.42 C483.2@117.194,281.61
SGMI_Tx_N: C482.2 R323.1 R328.2 U39.36 | length 8.6
  L16 w0.081: U39.36@111.699,275.775 111.997,275.775 cw(c111.997,275.732) 112.04,275.732 113.221,275.732 cw(c113.221,274.423) 114.148,275.349 ccw(c115.745,276.946) 115.745,274.687 117.293,274.687 117.293,274.468 R323.1@117.334,274.427 R328.2@118.427,274.427 119.641,274.427 C482.2@119.723,274.345
SGMI_Tx_P: C479.2 R322.1 R327.2 U39.35 | length 8.7
  L16 w0.081: U39.35@111.699,276.275 111.997,276.275 ccw(c111.997,276.318) 112.04,276.318 113.221,276.318 cw(c113.221,274.423) 114.562,275.763 ccw(c115.745,276.946) 115.745,275.272 117.293,275.272 117.293,275.531 R322.1@117.334,275.572 R327.2@118.427,275.572 118.714,275.285 C479.2@119.723,275.285
Si53323_1_Q1_N: C330.1 R249.1 U31.9 | length 6.2
  L1 w0.081: U31.9@41.529,534.348 41.79,534.348 cw(c41.79,533.28) 42.545,534.035 43.284,533.296 ccw(c44.422,534.433) 44.422,532.825 46.813,532.825 C330.1@47.12,532.517
Si53323_1_Q1_P: C325.1 R246.2 U31.10 | length 6.3
  L1 w0.081: U31.10@41.529,534.848 41.529,534.933 41.79,534.933 cw(c41.79,533.28) 42.959,534.449 43.696,533.712 ccw(c44.425,534.44) 44.425,533.41 46.813,533.41 C325.1@47.12,533.718
Si53323_1_Q2_LVDS_N: C725.2 R386.2 R387.2 U1.AG3 | length 0.7
  L1 w0.116: v2(187.909,290.052) U1.AG3@188.397,290.539
Si53323_1_Q2_LVDS_P: C724.2 U1.AG4 | length 0.7
  L1 w0.116: v2(187.909,291.052) U1.AG4@188.397,291.539
Si53323_1_Q2_N: R301.1 R385.2 U31.12 | length 6.4
  L1 w0.081: U31.12@41.529,535.848 42.148,535.848 ccw(c42.148,538.388) 43.944,536.592 44.33,536.978 cw(c45.266,536.041) 45.266,537.366 47.14,537.366 R385.2@47.34,537.566
Si53323_1_Q2_P: R291.1 R384.2 U31.11 | length 6.4
  L1 w0.081: U31.11@41.529,535.262 42.15,535.262 ccw(c42.15,538.383) 44.356,536.176 44.742,536.562 cw(c45.269,536.036) 45.269,536.78 47.14,536.78 R384.2@47.34,536.58
Si53323_2_CLK1_N: C330.2 R245.2 R248.2 R251.2 U32.4 | length 4.6
  L1 w0.081: C330.2@47.9,532.517 48.208,532.825 52.349,532.825
Si53323_2_CLK1_P: C325.2 R245.1 R247.2 R250.2 U32.3 | length 4.6
  L1 w0.081: C325.2@47.9,533.718 48.208,533.41 52.349,533.41
Si53323_2_Q1_N: C44.2 R79.2 U32.10 | length 2.4
  L16 w0.087: C44.2@101.021,334.061 101.227,334.267 101.737,334.267 R79.2@102.019,333.985 102.301,334.267 103.081,334.267 v9(103.086,334.262)
Si53323_2_Q1_P: C43.2 R76.1 U32.9 | length 2.4
  L16 w0.087: C43.2@101.041,335.064 101.247,334.858 101.737,334.858 R76.1@102.019,335.14 102.301,334.858 103.081,334.858 v9(103.086,334.862)
Si53323_2_Q2_LVDS_N: C727.2 R486.2 R487.2 U1.A16 | length 4.1
  L1 w0.063: 161.236,303.747 ccw(c161.236,303.908) 161.397,303.908 162.31,303.908 cw(c162.31,303.821) 162.397,303.821 U1.A16@162.397,303.539
  L1 w0.081: v1(158.763,303.739) 158.763,303.747 161.236,303.747
Si53323_2_Q2_LVDS_P: C726.2 U1.A17 | length 4.1
  L1 w0.063: 161.236,304.332 cw(c161.236,304.171) 161.397,304.171 162.31,304.171 ccw(c162.31,304.258) 162.397,304.258 U1.A17@162.397,304.539
  L1 w0.081: v1(158.763,304.339) 158.763,304.332 161.236,304.332
Si53323_2_Q2_N: R483.1 R485.2 U32.12
Si53323_2_Q2_P: R482.1 R484.2 U32.11
SPI1_CLK: J25.1 R803.1 U15.14 U24_SPI_bridge_Main.3 U25_SPI_bridge_Main.3 U26_SPI_bridge_Main.3 U27_SPI_bridge_Main.3 U28_SPI_bridge_Main.3 | length 190.4
  L1 w0.2: v2(135.431,270.093) 136.238,270.901 U15.14@138.523,270.901 ; U28_SPI_bridge_Main.3@170.769,231.638 172.063,231.638 v2(172.06,231.635) ; U25_SPI_bridge_Main.3@186.998,254.021 186.998,252.956 187.254,252.7 187.254,250.211 187.897,249.568 v1(188.493,249.568) ; U24_SPI_bridge_Main.3@217.232,291.652 219.719,291.652 v1(220.31,291.061)
  L5 (Sign) w0.2: v11(169.494,240.936) 169.494,240.538 170.485,239.547 171.336,239.547 171.336,236.154 v11(175.854,231.635) 177.444,231.635 179.475,233.666 179.475,235.377 180.594,236.496 180.594,237.896 184.95,242.252 184.95,247.028 187.49,249.568 v1(188.493,249.568) 195.71,249.568 197.564,251.422 197.612,251.422 205.98,259.79 207.824,259.79 220.631,272.597 220.631,290.74 v1(220.31,291.061)
  L3 (Sign) w0.2: v2(135.431,270.093) 135.431,270.052 135.322,269.943 135.322,268.076 139.082,264.315 146.471,264.315 162.628,248.158 166.08,248.158 170.131,244.107 170.131,241.572 v11(169.494,240.936) ; v2(172.06,231.635) v11(175.854,231.635) 180.696,226.794 199.329,226.794 J25.1@199.336,226.8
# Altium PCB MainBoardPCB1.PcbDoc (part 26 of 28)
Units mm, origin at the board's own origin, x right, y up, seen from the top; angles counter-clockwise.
Board outline 258.95 x 308.86 mm, 16 copper layers (L1, L2 (GND), L3 (Sign), L4 (GND), L5 (Sign), L6 (PWR/GND), L7(PWR/GND), L8 (Plane_GND), L9 (PWR/GND), L10 (PWR/GND), L11 (PWR/GND), L12 (Sign), L13 (GND), L14 (Sign), L15 (GND), L16), stack 2.502 mm thick; 2397 components, 1744 nets, 8397 pads, 4112 vias.
Unrouted connection lines stored in the file: 3547.

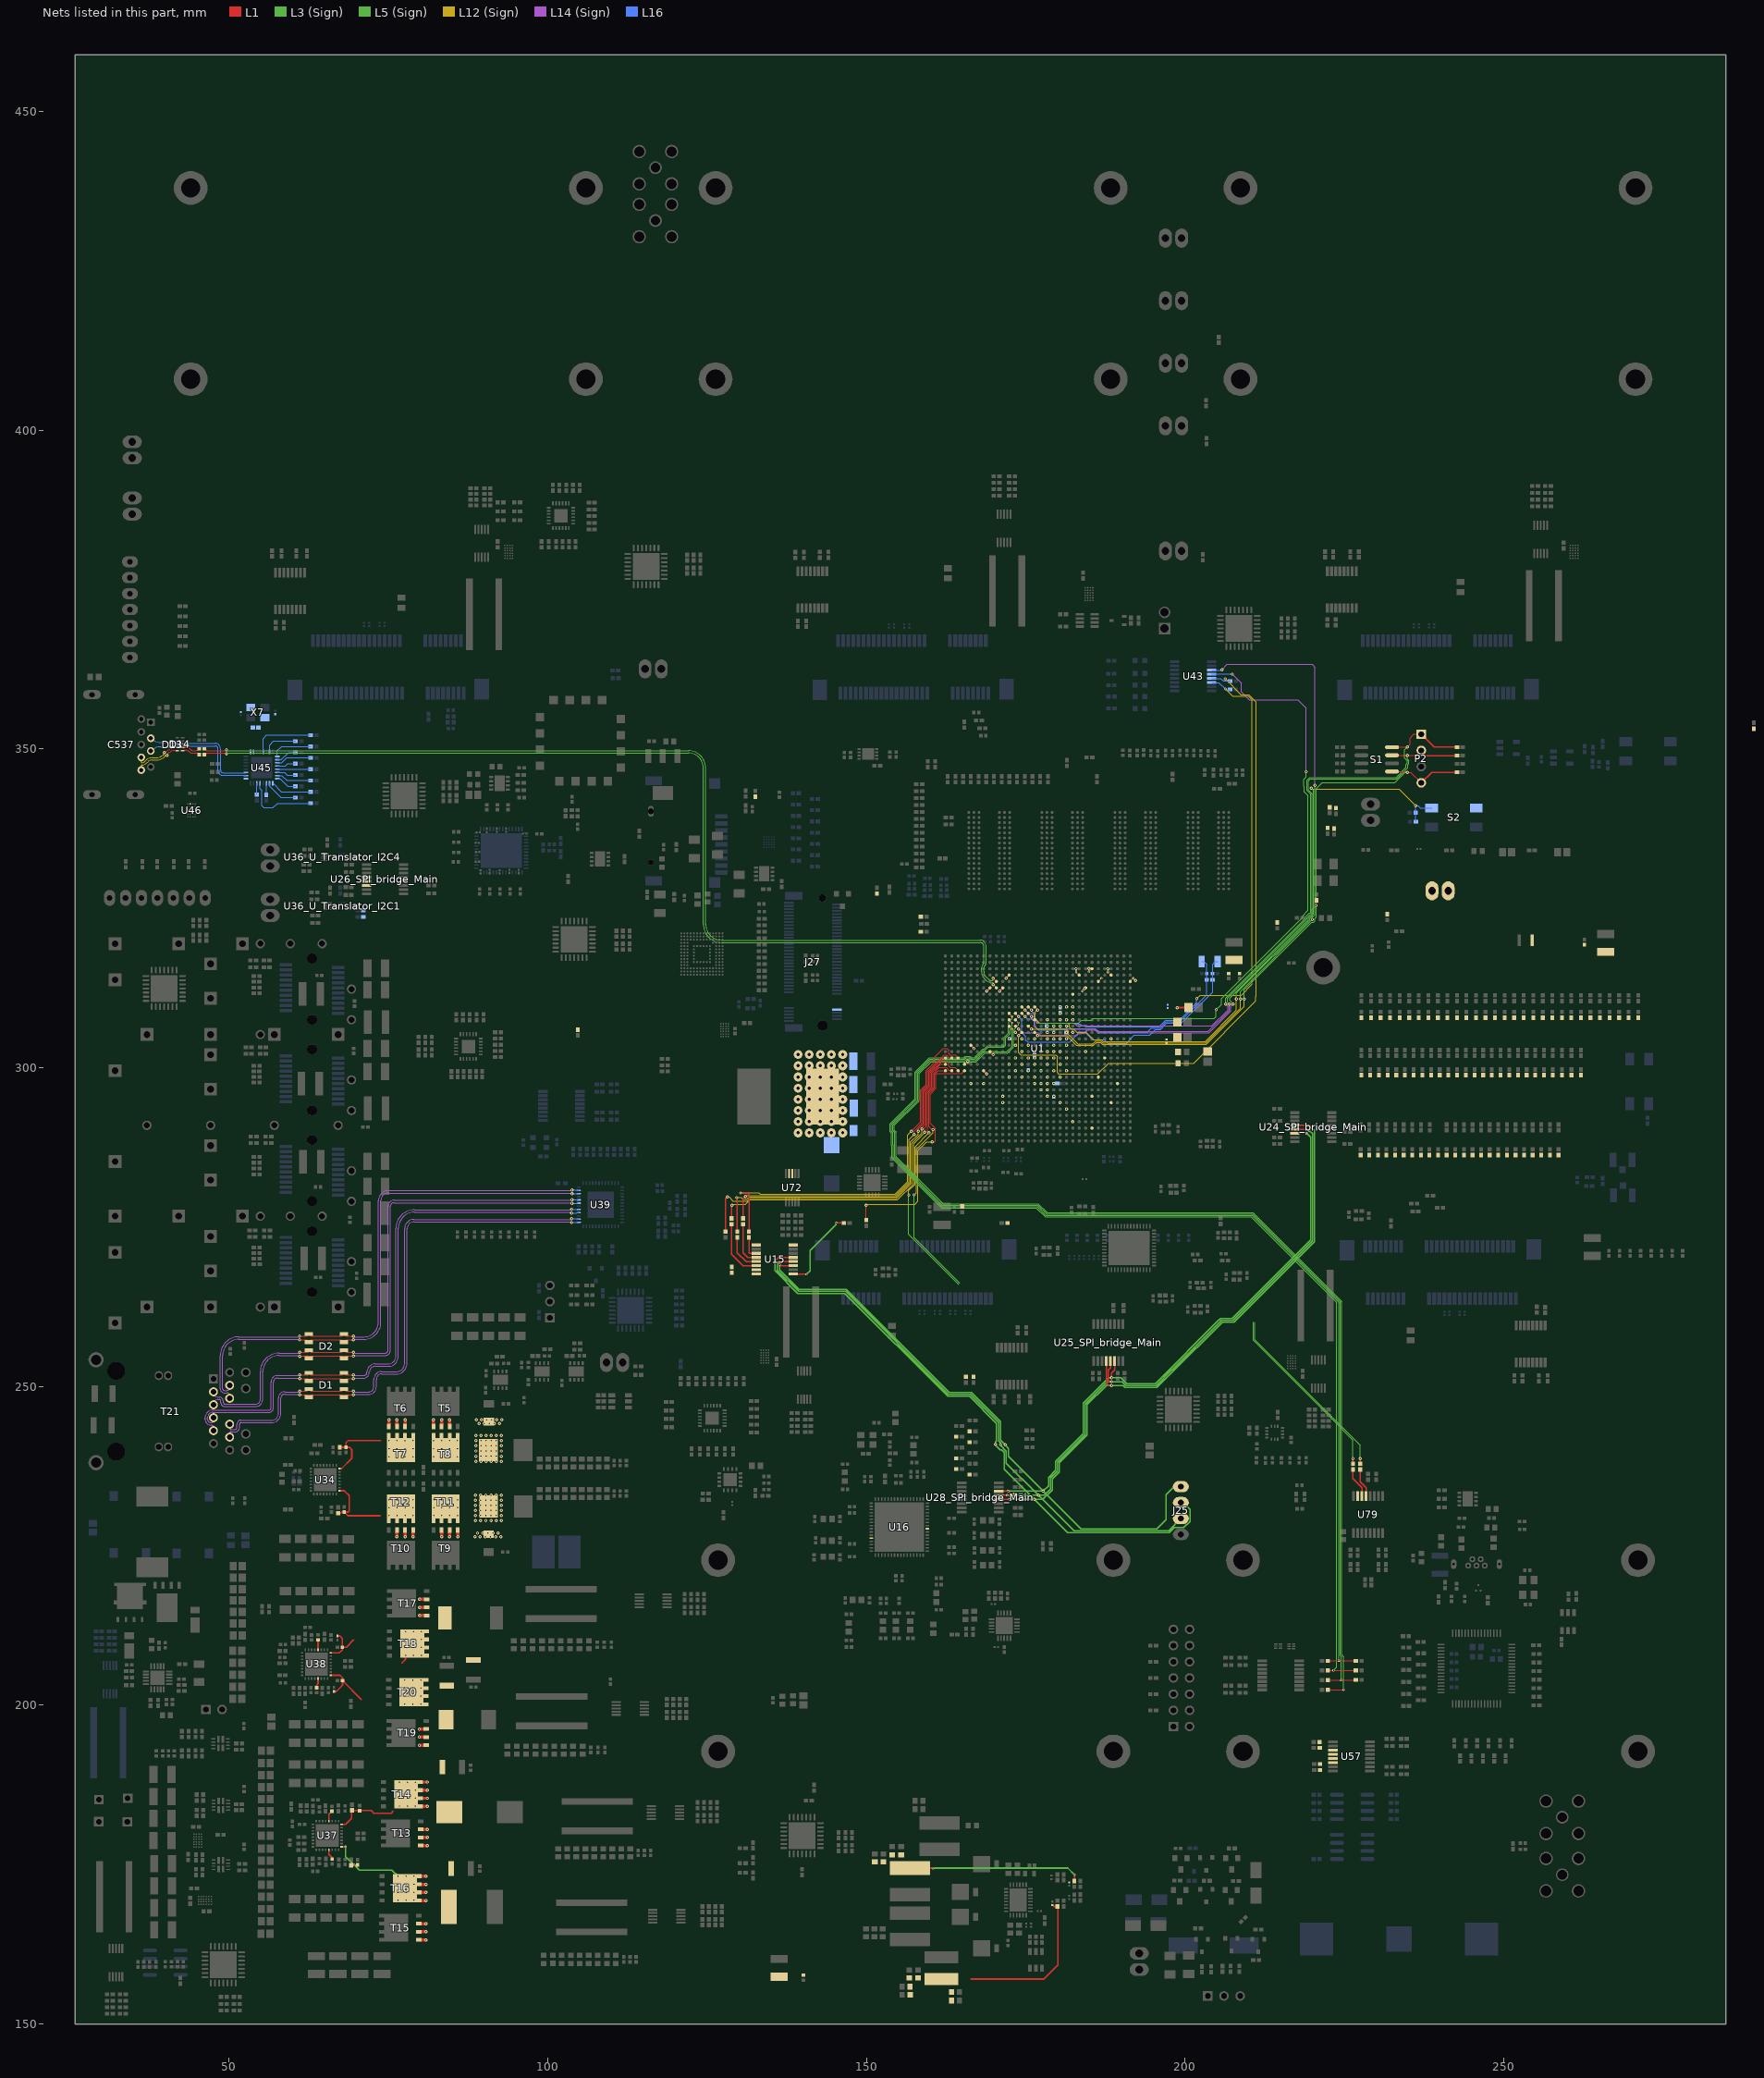
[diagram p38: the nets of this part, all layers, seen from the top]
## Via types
v1: diameter 0.5, hole 0.2, L1 to L16, tented both sides, 1457 vias
v2: diameter 0.35/0/0.35 (per signal layer), hole 0.127, L1 to L3 (Sign), tented both sides, 479 vias
v3: diameter 0.5/0.35/0.35/0.35/0.35/0.35/0.35/0.35/0.35/0.35/0.35/0.35/0.35/0.35/0.35/0.5 (per signal layer), hole 0.15, L1 to L16, tented both sides, 453 vias
v4: diameter 0.5, hole 0.2, L1 to L16, 451 vias
v5: diameter 0.5/0.35/0.35/0.35/0.35/0.35/0.35/0.35/0.35/0.35/0.35/0.35/0.35/0.35/0.35/0.5 (per signal layer), hole 0.2, L1 to L16, tented both sides, 373 vias
v6: diameter 0.8, hole 0.4, L1 to L16, tented both sides, 168 vias
v7: diameter 0.35/0/0.35 (per signal layer), hole 0.127, L1 to L3 (Sign), 138 vias
v8: diameter 2.54, hole 1.02, L1 to L16, 113 vias
v9: diameter 0.5/0/0.5 (per signal layer), hole 0.2, L14 (Sign) to L16, tented both sides, 102 vias
v10: diameter 1.4, hole 0.5, L1 to L16, tented both sides, 80 vias
v11: diameter 0.5, hole 0.2, L3 (Sign) to L6 (PWR/GND), tented both sides, 54 vias
v12: diameter 0.35, hole 0.127, L1 to L2 (GND), tented both sides, 47 vias
v13: diameter 0.4, hole 0.2, L1 to L16, tented both sides, 46 vias
v14: diameter 0.35, hole 0.127, L1 to L16, tented both sides, 16 vias
v15: diameter 0.25, hole 0.2, L1 to L16, 16 vias
v16: diameter 0.5, hole 0.2, L11 (PWR/GND) to L14 (Sign), tented both sides, 16 vias
v17: diameter 0.4, hole 0.2, L1 to L16, 16 vias
v18: diameter 0.3, hole 0.2, L1 to L16, 15 vias
v19: diameter 0.45, hole 0.15, L1 to L16, 12 vias
v20: diameter 0.5/0.35/0.35/0.35/0.35/0.35/0.35/0.35/0.35/0.35/0.35/0.35/0.35/0.35/0.35/0.45 (per signal layer), hole 0.15, L1 to L16, tented both sides, 10 vias
v21: diameter 0.2/0/0.2 (per signal layer), hole 0.1, L1 to L3 (Sign), tented both sides, 9 vias
v22: diameter 0.3, hole 0.127, L14 (Sign) to L16, tented both sides, 8 vias
v23: diameter 0.4, hole 0.1, L1 to L16, 7 vias
v24: diameter 1.15, hole 1.15, L1 to L16, 5 vias
v25: diameter 1.65, hole 1.65, L1 to L16, 5 vias
v26: diameter 0.2, hole 0.1, L1 to L16, 4 vias
v27: diameter 0.4, hole 0.15, L1 to L16, 2 vias
v28: diameter 0.5/0.35/0.35/0.35/0.35/0.35/0.35/0.35/0.35/0.35/0.35/0.35/0.35/0.35/0.35/0.5 (per signal layer), hole 0.15, L1 to L16, 2 vias
v29: diameter 0.35, hole 0.127, L3 (Sign) to L6 (PWR/GND), tented both sides, 2 vias
v30: diameter 0.3, hole 0.127, L15 (GND) to L16, tented both sides, 1 vias
v31: diameter 0.35, hole 0.127, L1 to L2 (GND), 1 vias
v32: diameter 0.5/0.35/0.35/0.35/0.35/0.35/0.35/0.35/0.35/0.35/0.35/0.35/0.35/0.35/0.35/0.5 (per signal layer), hole 0.2, L1 to L16, 1 vias
v33: diameter 0.35/0.35/0.35 (per signal layer), hole 0.127, L1 to L3 (Sign), tented both sides, 1 vias
v34: diameter 0.45/0/0.45 (per signal layer), hole 0.15, L1 to L3 (Sign), tented both sides, 1 vias
v35: diameter 0.45/0/0.45 (per signal layer), hole 0.2, L14 (Sign) to L16, tented both sides, 1 vias

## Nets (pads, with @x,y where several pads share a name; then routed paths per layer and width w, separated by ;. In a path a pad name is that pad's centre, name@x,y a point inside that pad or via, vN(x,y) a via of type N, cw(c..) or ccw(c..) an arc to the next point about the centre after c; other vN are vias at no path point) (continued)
SPI1_CS: J25.4 R123.1 R124.1 R806.1 U15.11 U24_SPI_bridge_Main.6 U25_SPI_bridge_Main.6 U26_SPI_bridge_Main.6 U27_SPI_bridge_Main.6 U28_SPI_bridge_Main.6 | length 183.8
  L1 w0.2: v2(136.385,269.138) 136.573,268.951 U15.11@138.523,268.951 ; U28_SPI_bridge_Main.6@170.769,233.588 v2(172.215,233.588) 172.72,233.083 R124.1@173.353,233.083 ; v1(188.493,251.368) 188.493,252.14 188.948,252.594 U25_SPI_bridge_Main.6@188.948,254.021 ; U24_SPI_bridge_Main.6@217.232,289.702 218.082,289.702 218.169,289.789 v1(219.037,289.789)
  L5 (Sign) w0.2: v11(171.755,240.843) 172.275,240.322 172.275,239.063 v11(177.751,233.588) 178.575,234.412 178.575,235.75 179.694,236.869 179.694,238.269 184.05,242.625 184.05,247.4 188.017,251.368 v1(188.493,251.368) 189.939,251.368 190.837,250.469 195.339,250.469 205.319,260.45 205.352,260.45 205.592,260.689 207.403,260.689 219.697,272.984 219.697,289.128 v1(219.037,289.789)
  L3 (Sign) w0.2: v2(136.385,269.138) 136.385,268.285 139.455,265.215 146.844,265.215 163.001,249.058 166.452,249.058 171.031,244.479 171.031,241.567 v11(171.755,240.843) ; v2(172.215,233.588) v11(177.751,233.588) 183.644,227.695 195.581,227.695 197.028,229.142 197.028,233.07 198.258,234.3 J25.4@199.336,234.3
SPI1_MISO: J25.3 R807.1 U15.13 U24_SPI_bridge_Main.4 U25_SPI_bridge_Main.4 U26_SPI_bridge_Main.4 U27_SPI_bridge_Main.4 U28_SPI_bridge_Main.4 | length 191.6
  L1 w0.2: v2(135.749,269.775) 136.225,270.251 U15.13@138.523,270.251 ; U28_SPI_bridge_Main.4@170.769,232.288 v2(172.423,232.288) ; U25_SPI_bridge_Main.4@187.648,254.021 187.647,250.515 187.995,250.168 v1(188.493,250.168) ; U24_SPI_bridge_Main.4@217.232,291.002 219.52,291.002 v1(219.885,290.637)
  L5 (Sign) w0.2: v11(170.282,240.936) 170.282,240.779 170.98,240.081 171.171,240.081 171.404,239.847 171.46,239.847 171.636,239.672 171.636,239.616 171.641,239.611 171.641,237.018 v11(176.37,232.288) 177.673,232.288 179.175,233.79 179.175,235.501 180.294,236.62 180.294,238.021 184.65,242.377 184.65,247.152 187.666,250.168 v1(188.493,250.168) 190.291,250.168 190.589,249.869 195.587,249.869 197.74,252.022 197.78,252.022 205.848,260.09 207.692,260.09 220.326,272.724 220.326,290.197 v1(219.885,290.637)
  L3 (Sign) w0.2: v2(135.749,269.775) 135.622,269.647 135.622,268.2 139.206,264.615 146.595,264.615 162.752,248.458 166.204,248.458 170.431,244.231 170.431,241.448 170.282,241.299 v11(170.282,240.936) ; v2(172.423,232.288) v11(176.37,232.288) 181.565,227.094 197.553,227.094 198.335,227.875 199.806,227.875 200.786,228.855 200.786,230.725 199.711,231.8 J25.3@199.336,231.8
SPI1_MOSI: J25.2 R808.1 U15.12 U24_SPI_bridge_Main.5 U25_SPI_bridge_Main.5 U26_SPI_bridge_Main.5 U27_SPI_bridge_Main.5 U28_SPI_bridge_Main.5 | length 182.4
  L1 w0.2: v2(136.067,269.457) 136.211,269.601 U15.12@138.523,269.601 ; U28_SPI_bridge_Main.5@170.769,232.938 v2(172.098,232.938) ; U25_SPI_bridge_Main.5@188.298,254.021 188.298,252.94 187.947,252.589 187.947,251.003 188.182,250.768 v1(188.493,250.768) ; U24_SPI_bridge_Main.5@217.232,290.352 219.322,290.352 v1(219.461,290.213)
  L5 (Sign) w0.2: v11(171.031,240.906) 171.031,240.767 171.958,239.839 171.958,237.998 v11(177.018,232.938) 177.899,232.938 178.875,233.914 178.875,235.625 179.994,236.745 179.994,238.145 184.35,242.501 184.35,247.276 187.842,250.768 v1(188.493,250.768) 190.115,250.768 190.713,250.169 195.463,250.169 197.915,252.622 197.948,252.622 205.716,260.389 207.56,260.389 220.021,272.85 220.021,288.705 220.01,288.716 220.01,289.664 v1(219.461,290.213)
  L3 (Sign) w0.2: v2(136.067,269.457) 136.067,269.351 136.01,269.294 136.01,268.235 139.33,264.915 146.719,264.915 162.877,248.758 166.328,248.758 170.731,244.355 170.731,241.442 171.031,241.142 v11(171.031,240.906) ; v2(172.098,232.938) v11(177.018,232.938) 182.562,227.393 197.429,227.393 J25.2@199.336,229.3
SPI_05028_CS: R2.2 R129.1 R912.2 U16.24
SPI_05028_MISO: R1.2 R128.2 R133.2 U16.60
SPI_DAC_CS: R238_SPI_bridge_Main.1 U27_SPI_bridge_Main.11 U30.14 | length 13.8
  L1 w0.2: R238_SPI_bridge_Main.1@50.395,495.579 51.352,495.579 v2(51.884,495.047) U27_SPI_bridge_Main.11@51.884,492.853 ; v2(59.744,494.275) 59.757,494.275 U30.14@59.757,492.711
  L3 (Sign) w0.2: v2(51.884,495.047) 59.146,495.047 59.744,494.449 v2(59.744,494.275)
SPI_FPGA_CLK: R905.2 U15.3 | length 3.6
  L1 w0.2: R905.2@131.572,273.4 131.572,271.005 131.677,270.901 U15.3@132.723,270.901
SPI_FPGA_CLK_R: R905.1 U1.C14 | length 60.8
  L1 w0.116: 163.909,302.027 U1.C14@164.397,301.539
  L1 w0.12: v1(157.048,290.03) 158.505,291.487 158.505,296.523 159.385,297.403 159.385,299.53 160.611,300.755 160.611,301.593 162.052,303.035 162.617,303.035 162.902,302.75 162.902,302.235 163.111,302.027 163.909,302.027
  L1 w0.2: v1(130.258,280.365) 131.318,280.365 131.572,280.111 R905.1@131.572,274.3
  L12 (Sign) w0.12: v1(130.258,280.365) 133.121,280.365 133.324,280.162 154.489,280.162 156.502,282.175 156.502,289.484 v1(157.048,290.03)
SPI_FPGA_CS: R365.2 R908.2 U15.6 | length 9.3
  L1 w0.2: R908.2@128.841,275.463 128.841,270.739 130.629,268.951 U15.6@132.723,268.951
SPI_FPGA_CS_R: R908.1 U1.A13 | length 53.2
  L1 w0.12: v1(159.169,289.928) 159.169,290.627 159.385,290.843 159.385,296.158 160.265,297.038 160.265,299.165 161.639,300.539 U1.A13@162.397,300.539
  L1 w0.2: R908.1@128.841,276.363 128.841,278.397 v1(128.892,278.447)
  L12 (Sign) w0.12: v1(128.892,278.447) 129.032,278.587 131.051,278.587 131.746,279.282 154.854,279.282 157.382,281.81 157.382,288.057 159.169,289.844 v1(159.169,289.928)
SPI_FPGA_MISO: R906.2 U15.4 | length 6.8
  L1 w0.2: R906.2@130.658,275.463 130.658,271.005 131.412,270.251 U15.4@132.723,270.251
SPI_FPGA_MISO_R: R906.1 U1.B14 | length 53.9
  L1 w0.116: 162.552,302.027 163.039,301.539 U1.B14@163.397,301.539
  L1 w0.12: v1(157.493,289.535) 157.493,290.081 158.725,291.313 158.725,296.432 159.605,297.312 159.605,299.439 162.193,302.027 162.552,302.027
  L1 w0.2: R906.1@130.658,276.363 130.658,279.473 v1(131.013,279.828)
  L12 (Sign) w0.12: v1(131.013,279.828) 131.026,279.828 131.139,279.942 154.58,279.942 156.722,282.084 156.722,288.764 v1(157.493,289.535)
SPI_FPGA_MOSI: R907.2 U15.5 | length 6
  L1 w0.2: R907.2@129.731,273.4 129.731,270.996 131.126,269.601 U15.5@132.723,269.601
SPI_FPGA_MOSI_R: R907.1 U1.A14 | length 55.9
  L1 w0.12: v1(158.119,290.068) 158.119,290.385 158.945,291.212 158.945,296.34 159.825,297.22 159.825,299.348 162.017,301.539 U1.A14@162.397,301.539
  L1 w0.2: v1(129.616,279.641) 129.731,279.527 R907.1@129.731,274.3
  L12 (Sign) w0.12: v1(129.616,279.641) 130.381,279.641 130.604,279.418 131.26,279.418 131.564,279.722 154.672,279.722 156.942,281.993 156.942,288.368 158.119,289.545 v1(158.119,290.068)
SPI_FPGA_nOE: R75.2 U15.9 | length 13.3
  L1 w0.2: U15.9@138.523,267.651 138.572,267.602 v2(140.614,267.602) ; v2(145.263,275.666) 145.529,275.666 145.542,275.653 R75.2@146.458,275.653
  L3 (Sign) w0.2: v2(140.614,267.602) 141.182,268.169 141.182,271.319 145.263,275.399 v2(145.263,275.666)
SPI_FPGA_OE_R: R903.1 U1.D12 | length 37.8
  L1 w0.12: R903.1@149.974,276.122 v1(149.974,278.409) ; v1(160.311,288.392) 160.682,288.392 160.849,288.559 160.849,290.466 160.045,291.27 160.045,295.885 160.925,296.765 160.925,298.892 161.13,299.097 164.954,299.097 U1.D12@165.397,299.539
  L12 (Sign) w0.12: v1(149.974,278.409) 150.187,278.622 157.604,278.622 158.042,279.06 158.042,287.011 159.423,288.392 v1(160.311,288.392)
SS1_1: C639.2 U37.28 | length 1.7
  L1 w0.254: U37.28@65.675,181.817 65.675,182.903 C639.2@66.141,183.369
SS1_2: C647.2 U38.28 | length 1.6
  L1 w0.254: U38.28@63.953,208.714 C647.2@63.953,210.264
SS2_1: C640.2 U37.13 | length 1.6
  L1 w0.254: U37.13@65.675,177.317 65.675,176.584 66.161,176.097 C640.2@66.161,175.893
SS2_2: C648.2 U38.13 | length 1.5
  L1 w0.254: C648.2@63.741,202.763 63.741,203.154 63.953,203.366 U38.13@63.953,204.214
SUSCLK: J27.60
SW1: C346.2 L9.1 R610.2 R613.2 T5.1 T5.2 T5.3 T6.1 T6.2 T6.3 T7.5 T7.6 T7.7 T7.8 T8.5 T8.6 T8.7 T8.8 U34.24 | length 18.8
  L1 w0.254: U34.24@67.322,237.139 67.657,237.139 69.236,238.718 69.236,240.156 68.922,240.47 C346.2@68.336,240.47 ; R610.2@67.378,240.47 C346.2@68.336,240.47 ; 73.8,241.529 68.669,241.529 68.336,241.196 C346.2@68.336,240.47
  L1 w0.5: T6.1@75.072,243.723 v1(75.072,244.81) ; T6.2@76.342,243.723 v1(76.342,244.81) ; T6.3@77.612,243.723 v1(77.612,244.81) ; T5.1@82.072,243.723 v1(82.072,244.81) ; T5.2@83.342,243.723 v1(83.342,244.81) ; T5.3@84.612,243.723 v1(84.612,244.81)
  other v1: 88.711,238.28 89.517,238.28 90.322,238.28 91.128,238.28 91.934,238.28 92.74,238.28 75.09,238.992 76.342,238.992 77.593,238.992 78.845,238.992 82.09,238.992 83.342,238.992 84.593,238.992 85.845,238.992 88.711,239.086 89.517,239.086 90.322,239.086 91.128,239.086 91.934,239.086 92.74,239.086 88.711,239.892 89.517,239.892 90.322,239.892 91.128,239.892 91.934,239.892 92.74,239.892 75.09,240.244 76.342,240.244 77.593,240.244 78.845,240.244 82.09,240.244 83.342,240.244 84.593,240.244 85.845,240.244 88.711,240.697 89.517,240.697 90.322,240.697 91.128,240.697 91.934,240.697 92.74,240.697 75.09,241.496 76.342,241.496 77.593,241.496 78.845,241.496 82.09,241.496 83.342,241.496 84.593,241.496 85.845,241.496 88.711,241.503 89.517,241.503 90.322,241.503 91.128,241.503 91.934,241.503 92.74,241.503 88.711,242.309 89.517,242.309 90.322,242.309 91.128,242.309 91.934,242.309 92.74,242.309 89.212,244.228 90.018,244.228 90.823,244.228 91.629,244.228 92.435,244.228 88.788,244.811 89.594,244.811 90.4,244.811 91.206,244.811 92.011,244.811 92.817,244.811
SW1_1: C390.2 L11.1 R288.2 R619.2 T13.1 T13.2 T13.3 T14.5 T14.6 T14.7 T14.8 U37.24 | length 17.6
  L1 w0.2: U37.24@67.675,181.317 68.299,181.317 69.242,182.259 69.242,183.46 C390.2@70.485,183.46 72.337,183.46 72.701,183.096 75.442,183.096 75.779,183.433
  L1 w0.5: T14.5@80.039,184.15 v1(81.126,184.15) ; T14.6@80.039,185.42 v1(81.126,185.42) ; T14.7@80.039,186.69 v1(81.126,186.69) ; T14.8@80.039,187.96 v1(81.126,187.96) ; T13.1@80.042,178.003 v1(81.129,178.003) ; T13.2@80.042,179.273 v1(81.129,179.273) ; T13.3@80.042,180.543 v1(81.129,180.543)
  other v1: 76.718,184.187 77.97,184.187 79.221,184.187 76.718,185.438 77.97,185.438 79.221,185.438 76.718,186.69 77.97,186.69 79.221,186.69 76.718,187.942 77.97,187.942 79.221,187.942
SW1_2: C431.2 L19.1 R306.2 R625.1 T17.1 T17.2 T17.3 T18.5 T18.6 T18.7 T18.8 U38.24 | length 11.2
  L1 w0.254: U38.24@65.953,208.214 67.293,208.214 67.758,208.68 C431.2@67.758,209.091 ; R625.1@67.001,210.879 67.377,210.879 67.781,210.475 C431.2@67.781,209.114 68.392,209.114 69.532,210.254 ; 77.166,206.68 77.677,207.192 77.677,207.477
  L1 w0.5: v1(79.911,214.079) T17.1@80.998,214.079 ; v1(79.911,215.349) T17.2@80.998,215.349 ; v1(79.911,216.619) T17.3@80.998,216.619
  other v1: 77.677,207.834 78.929,207.834 80.18,207.834 77.677,209.086 78.929,209.086 80.18,209.086 77.677,210.337 78.929,210.337 80.18,210.337 77.677,211.589 78.929,211.589 80.18,211.589
SW2: C350.2 L10.1 R611.2 R616.2 T9.1 T9.2 T9.3 T10.1 T10.2 T10.3 T11.5 T11.6 T11.7 T11.8 T12.5 T12.6 T12.7 T12.8 U34.17 | length 18.5
  L1 w0.254: R611.2@67.113,230.147 67.513,230.147 67.688,230.322 C350.2@68.072,230.322 ; U34.17@67.322,233.639 68.085,233.639 68.854,232.87 68.854,230.471 68.705,230.322 C350.2@68.072,230.322 ; C350.2@68.072,230.317 C350.2@68.072,230.322 ; 73.69,229.73 68.663,229.73 C350.2@68.072,230.322
  L1 w0.5: v1(76.348,226.414) T10.3@76.348,227.501 ; v1(77.618,226.414) T10.2@77.618,227.501 ; v1(78.888,226.414) T10.1@78.888,227.501 ; v1(83.342,226.414) T9.3@83.342,227.501 ; v1(84.612,226.414) T9.2@84.612,227.501 ; v1(85.882,226.414) T9.1@85.882,227.501
  other v1: 88.597,226.45 89.402,226.45 90.208,226.45 91.014,226.45 91.82,226.45 92.625,226.45 88.979,227.033 89.785,227.033 90.59,227.033 91.396,227.033 92.202,227.033 88.674,228.952 89.48,228.952 90.286,228.952 91.091,228.952 91.897,228.952 92.703,228.952 75.108,229.757 76.36,229.757 77.612,229.757 78.863,229.757 82.108,229.757 83.36,229.757 84.612,229.757 85.863,229.757 88.674,229.758 89.48,229.758 90.286,229.758 91.091,229.758 91.897,229.758 92.703,229.758 88.674,230.564 89.48,230.564 90.286,230.564 91.091,230.564 91.897,230.564 92.703,230.564 75.108,231.008 76.36,231.008 77.612,231.008 78.863,231.008 82.108,231.008 83.36,231.008 84.612,231.008 85.863,231.008 88.674,231.369 89.48,231.369 90.286,231.369 91.091,231.369 91.897,231.369 92.703,231.369 88.674,232.175 89.48,232.175 90.286,232.175 91.091,232.175 91.897,232.175 92.703,232.175 75.108,232.26 76.36,232.26 77.612,232.26 78.863,232.26 82.108,232.26 83.36,232.26 84.612,232.26 85.863,232.26 88.674,232.981 89.48,232.981 90.286,232.981 91.091,232.981 91.897,232.981 92.703,232.981
SW2_1: C394.2 L12.1 R298.2 R620.2 T15.1 T15.2 T15.3 T16.5 T16.6 T16.7 T16.8 U37.17 | length 20.3
  L1 w0.2: U37.17@67.675,177.817 v2(68.301,177.817) ; R620.2@69.151,174.917 v2(69.659,174.917) 70.076,174.917 C394.2@70.142,174.983
  L1 w0.5: T15.1@79.789,163.201 v1(80.876,163.201) ; T15.2@79.789,164.471 v1(80.876,164.471) ; T15.3@79.789,165.741 v1(80.876,165.741) ; T16.5@79.835,169.38 v1(80.922,169.38) ; T16.6@79.835,170.65 v1(80.922,170.65) ; T16.7@79.835,171.92 v1(80.922,171.92) ; T16.8@79.835,173.19 v1(80.922,173.19)
  L3 (Sign) w0.2: v2(68.301,177.817) 68.301,176.276 v2(69.659,174.917) 70.441,174.135 75.551,174.135 v1(76.514,173.172)
  other v1: 76.514,169.417 77.766,169.417 79.017,169.417 76.514,170.668 77.766,170.668 79.017,170.668 76.514,171.92 77.766,171.92 79.017,171.92 77.766,173.172 79.017,173.172
SW2_2: C435.2 L20.1 R302.1 R316.2 T19.1 T19.2 T19.3 T20.5 T20.6 T20.7 T20.8 U38.17 | length 12.3
  L1 w0.254: U38.17@65.953,204.714 67.394,204.714 67.796,204.312 C435.2@67.796,203.864 ; R302.1@66.453,202.163 66.794,202.163 67.796,203.166 C435.2@67.796,203.864 ; 70.746,200.92 C435.2@67.796,203.864
  L1 w0.5: v1(79.842,193.746) T19.1@80.929,193.746 ; v1(79.842,195.016) T19.2@80.929,195.016 ; v1(79.842,196.286) T19.3@80.929,196.286
  other v1: 77.578,200.189 78.83,200.189 80.081,200.189 77.578,201.44 78.83,201.44 80.081,201.44 77.578,202.692 78.83,202.692 80.081,202.692 77.578,203.944 78.83,203.944 80.081,203.944
SYNC_WR_R: R904.1 U1.C12 | length 60.5
  L1 w0.116: 163.909,300.027 U1.C12@164.397,299.539
  L1 w0.12: v1(158.75,290.436) 158.75,290.627 159.165,291.042 159.165,296.249 160.045,297.129 160.045,299.257 161.817,301.028 162.635,301.028 162.902,300.761 162.902,300.254 163.129,300.027 163.909,300.027
  L1 w0.2: R904.1@127.889,274.3 127.889,279.425 v1(128.2,279.737)
  L12 (Sign) w0.12: v1(128.2,279.737) 128.441,279.737 129.057,279.121 131.274,279.121 131.655,279.502 154.763,279.502 157.162,281.901 157.162,288.148 158.75,289.736 v1(158.75,290.436)
TD_A_N: D1.2 D1.7 T21.10 U39.2 | length 86
  L1 w0.081: v1(61.087,249.283) 61.094,249.276 62.186,249.276 D1.7@62.528,249.618 62.87,249.276 67.686,249.276 D1.2@68.028,249.618 68.37,249.276 69.493,249.276 v1(69.5,249.283)
  L14 (Sign) w0.08: T21.10@50.092,244.096 50.092,243.509 ccw(c50.33,243.509) 50.33,243.271 50.968,243.271 ccw(c50.968,243.561) 51.257,243.561 51.257,244.093 cw(c51.892,244.093) 51.892,244.728 56.717,244.728 ccw(c56.717,245.745) 57.734,245.745 57.734,248.166 cw(c58.742,248.166) 58.742,249.173 60.977,249.173 v1(61.087,249.283) ; v1(69.5,249.283) ccw(c69.61,249.283) 69.61,249.173 71.959,249.173 ccw(c71.959,249.936) 72.721,249.936 72.721,251.117 cw(c73.968,251.117) 73.968,252.363 76.314,252.363 ccw(c76.314,253.584) 77.535,253.584 77.535,274.714 cw(c79.036,274.714) 79.036,276.215 103.662,276.215 ccw(c103.662,276.325) v9(103.772,276.325)
  L16 w0.081: v9(103.772,276.325) 103.772,276.318 104.559,276.318 ccw(c104.602,276.318) 104.602,276.275 U39.2@104.899,276.275
TD_A_P: D1.1 D1.8 T21.11 U39.1 | length 86
  L1 w0.081: v1(61.087,248.684) 61.094,248.691 62.186,248.691 D1.8@62.528,248.349 62.87,248.691 67.686,248.691 D1.1@68.028,248.349 68.37,248.691 69.493,248.691 v1(69.5,248.684)
  L14 (Sign) w0.08: T21.11@50.092,242.066 50.092,242.653 cw(c50.33,242.653) 50.33,242.891 50.968,242.891 ccw(c50.968,243.561) 51.637,243.561 51.637,244.093 cw(c51.892,244.093) 51.892,244.348 56.717,244.348 ccw(c56.717,245.745) 58.114,245.745 58.114,248.166 cw(c58.742,248.166) 58.742,248.794 60.977,248.794 v1(61.087,248.684) ; v1(69.5,248.684) cw(c69.61,248.684) 69.61,248.794 71.959,248.794 ccw(c71.959,249.936) 73.101,249.936 73.101,251.117 cw(c73.968,251.117) 73.968,251.984 76.314,251.984 ccw(c76.314,253.584) 77.915,253.584 77.915,274.714 cw(c79.036,274.714) 79.036,275.835 103.662,275.835 cw(c103.662,275.725) v9(103.772,275.725)
  L16 w0.081: v9(103.772,275.725) 103.772,275.732 104.559,275.732 cw(c104.602,275.732) 104.602,275.775 U39.1@104.899,275.775
TD_B_N: D1.4 D1.5 T21.5 U39.5 | length 91.3
  L1 w0.081: v1(61.087,251.823) 61.087,251.816 62.186,251.816 ccw(c62.186,252.118) 62.487,252.118 D1.5@62.528,252.159 62.87,251.816 67.686,251.816 D1.4@68.028,252.159 68.37,251.816 69.493,251.816 v1(69.5,251.823)
  L14 (Sign) w0.08: T21.5@47.552,243.081 47.552,243.566 ccw(c47.168,243.566) 47.168,243.95 cw(c47.168,244.889) 46.229,244.889 46.229,245.11 cw(c47.42,245.11) 47.42,246.301 56.208,246.301 ccw(c56.208,246.661) 56.567,246.661 56.567,250.685 cw(c57.595,250.685) 57.595,251.713 60.977,251.713 ccw(c60.977,251.823) v1(61.087,251.823) ; v1(69.5,251.823) ccw(c69.61,251.823) 69.61,251.713 71.107,251.713 ccw(c71.107,252.235) 71.628,252.235 cw(c72.948,252.235) 72.948,253.554 75.005,253.554 ccw(c75.005,254.711) 76.162,254.711 76.162,274.795 cw(c79.082,274.795) 79.082,277.715 103.662,277.715 ccw(c103.662,277.825) v9(103.772,277.825)
  L16 w0.081: v9(103.772,277.825) 103.772,277.818 104.559,277.818 ccw(c104.602,277.818) 104.602,277.775 U39.5@104.899,277.775
TD_B_P: D1.3 D1.6 T21.4 U39.4 | length 90
  L1 w0.081: v1(61.087,251.224) 61.087,251.231 62.186,251.231 cw(c62.186,250.929) 62.487,250.929 D1.6@62.528,250.888 62.87,251.231 67.686,251.231 D1.3@68.028,250.888 68.37,251.231 69.493,251.231 v1(69.5,251.224)
  L14 (Sign) w0.08: T21.4@47.552,245.111 47.552,244.714 cw(c47.168,244.714) 47.168,244.33 cw(c47.168,244.889) 46.609,244.889 46.609,245.11 cw(c47.436,245.11) 47.436,245.937 56.223,245.937 ccw(c56.223,246.661) 56.947,246.661 56.947,250.685 cw(c57.595,250.685) 57.595,251.334 60.977,251.334 cw(c60.977,251.224) v1(61.087,251.224) ; v1(69.5,251.224) cw(c69.61,251.224) 69.61,251.334 71.107,251.334 ccw(c71.107,252.235) 72.008,252.235 cw(c72.948,252.235) 72.948,253.174 75.005,253.174 ccw(c75.005,254.711) 76.542,254.711 76.542,274.795 cw(c79.082,274.795) 79.082,277.335 103.662,277.335 cw(c103.662,277.225) v9(103.772,277.225)
  L16 w0.081: v9(103.772,277.225) 103.772,277.232 104.559,277.232 cw(c104.602,277.232) 104.602,277.275 U39.4@104.899,277.275
TD_C_N: D2.2 D2.7 T21.2 U39.8 | length 89.2
  L1 w0.081: v1@61.087,255.359 62.243,255.359 ccw(c62.243,255.604) 62.487,255.604 cw(c62.626,255.604) D2.7@62.528,255.702 62.87,255.359 67.686,255.359 D2.2@68.028,255.702 68.37,255.359 69.493,255.359 v1(69.5,255.367)
  L14 (Sign) w0.08: T21.2@47.552,249.171 47.552,249.066 ccw(c48.273,249.066) 48.273,248.346 48.439,248.346 cw(c48.439,247.688) 49.097,247.688 49.097,247.495 ccw(c49.336,247.495) 49.336,247.256 54.178,247.256 ccw(c54.178,247.98) 54.902,247.98 54.902,252.324 cw(c57.822,252.324) 57.822,255.243 60.977,255.243 ccw(c60.977,255.354) v1(61.087,255.354) ; v1(69.5,255.367) ccw(c69.61,255.367) 69.61,255.257 74.511,255.257 ccw(c74.511,255.677) 74.931,255.677 74.931,278.282 cw(c75.864,278.282) 75.864,279.215 103.674,279.215 ccw(c103.674,279.325) v9(103.784,279.325)
  L16 w0.081: v9(103.784,279.325) 103.784,279.318 104.559,279.318 ccw(c104.602,279.318) 104.602,279.275 U39.8@104.899,279.275
TD_C_P: D2.1 D2.8 T21.3 U39.7 | length 89.2
  L1 w0.081: v1(61.087,254.754) cw(c61.108,254.754) 61.108,254.774 62.243,254.774 cw(c62.243,254.53) 62.487,254.53 ccw(c62.626,254.53) D2.8@62.528,254.432 62.87,254.774 67.686,254.774 D2.1@68.028,254.432 68.37,254.774 69.493,254.774 v1(69.5,254.767)
  L14 (Sign) w0.08: T21.3@47.552,247.141 47.552,247.246 cw(c48.273,247.246) 48.273,247.966 48.439,247.966 cw(c48.439,247.688) 48.717,247.688 48.717,247.495 ccw(c49.336,247.495) 49.336,246.876 54.178,246.876 ccw(c54.178,247.98) 55.282,247.98 55.282,252.324 cw(c57.822,252.324) 57.822,254.864 60.977,254.864 cw(c60.977,254.754) v1(61.087,254.754) ; v1(69.5,254.767) cw(c69.61,254.767) 69.61,254.877 74.511,254.877 ccw(c74.511,255.677) 75.311,255.677 75.311,278.282 cw(c75.864,278.282) 75.864,278.835 103.674,278.835 cw(c103.674,278.725) v9(103.784,278.725)
  L16 w0.081: v9(103.784,278.725) 103.784,278.732 104.559,278.732 cw(c104.602,278.732) 104.602,278.775 U39.7@104.899,278.775
TD_D_N: D2.4 D2.5 T21.9 U39.11 | length 87.7
  L1 w0.081: v1(61.056,257.907) 61.063,257.899 62.186,257.899 D2.5@62.528,258.242 62.87,257.899 67.686,257.899 D2.4@68.028,258.242 68.37,257.899 69.493,257.899 v1(69.5,257.907)
  L14 (Sign) w0.08: T21.9@50.092,248.156 50.092,248.575 ccw(c49.657,248.575) 49.657,249.01 49.276,249.01 cw(c49.276,249.671) 48.615,249.671 48.615,254.877 cw(c51.535,254.877) 51.535,257.797 60.946,257.797 v1(61.056,257.907) ; v1(69.5,257.907) 69.61,257.797 71.158,257.797 ccw(c71.158,260.071) 73.431,260.071 73.431,279.171 cw(c74.992,279.171) 74.992,280.732 103.692,280.732 ccw(c103.692,280.825) v9(103.784,280.825)
  L16 w0.081: v9(103.784,280.825) 103.784,280.818 104.559,280.818 ccw(c104.602,280.818) 104.602,280.775 U39.11@104.899,280.775
TD_D_P: D2.3 D2.6 T21.8 U39.10 | length 86.5
  L1 w0.081: v1(61.056,257.307) 61.063,257.314 62.186,257.314 D2.6@62.528,256.972 62.87,257.314 67.686,257.314 D2.3@68.028,256.972 68.37,257.314 69.493,257.314 v1(69.5,257.307)
  L14 (Sign) w0.08: T21.8@50.092,250.186 50.092,249.825 cw(c49.657,249.825) 49.657,249.39 49.276,249.39 cw(c49.276,249.671) 48.995,249.671 48.995,254.877 cw(c51.535,254.877) 51.535,257.417 60.946,257.417 v1(61.056,257.307) ; v1(69.5,257.307) 69.61,257.417 71.158,257.417 ccw(c71.158,260.071) 73.811,260.071 73.811,279.171 cw(c74.992,279.171) 74.992,280.352 103.657,280.352 cw(c103.657,280.225) v9(103.784,280.225)
  L16 w0.081: v9(103.784,280.225) 103.784,280.232 104.559,280.232 cw(c104.602,280.232) 104.602,280.275 U39.10@104.899,280.275
TTC_0: R810.1
TTC_3: R804.1
uart0_RxD: R779.1 U57.12
uart0_TxD: R778.1 U57.11
uart1_RxD: R776.1 U57.13
uart1_TxD: R777.1 U57.14
uart_FPGA_RxD_R: R909.1 U1.B12 | length 70.3
  L1 w0.116: 162.543,300.027 163.031,299.539 U1.B12@163.397,299.539
  L1 w0.12: v1(159.791,289.801) 159.605,289.987 159.605,296.067 160.485,296.947 160.485,299.074 161.438,300.027 162.543,300.027
  L1 w0.2: R909.1@226.359,237.884 v1(226.359,238.671)
  L5 (Sign) w0.12: v1(156.653,280.06) 156.653,273.869 164.482,266.04 ; 210.703,260.124 210.703,257.266 222.671,245.298 222.671,245.262 222.996,244.937 223.032,244.937 226.359,241.61 v1(226.359,238.671)
  L12 (Sign) w0.12: v1(156.653,280.06) 156.653,280.77 157.602,281.719 157.602,287.612 v1(159.791,289.801)
uart_FPGA_TxD_R: R910.1 U1.A12 | length 68.5
  L1 w0.12: v1(160.439,290.297) 160.318,290.297 159.825,290.79 159.825,295.976 160.705,296.856 160.705,298.983 161.262,299.539 U1.A12@162.397,299.539
  L1 w0.2: R910.1@227.482,237.884 v1(227.482,238.671)
  L5 (Sign) w0.12: v1(157.493,280.073) 157.493,273.34 164.573,266.26 ; 210.96,260.058 210.96,257.32 222.891,245.389 222.891,245.353 223.087,245.157 223.124,245.157 227.482,240.798 v1(227.482,238.671)
  L12 (Sign) w0.12: v1(157.493,280.073) 157.822,280.402 157.822,287.21 160.439,289.827 v1(160.439,290.297)
US2_FTDI_UART1_RXD: R910.2 U79.13 | length 4.5
  L1 w0.2: R910.2@227.482,236.984 227.482,235.056 228.398,234.141 U79.13@228.398,232.825
US2_FTDI_UART1_TXD: R909.2 U79.14 | length 4.8
  L1 w0.2: R909.2@226.359,236.984 226.359,235.554 227.782,234.131 227.782,232.859 U79.14@227.748,232.825
US+_DxN: R279.1 R286.1 U1.V15
  other v5: 179.397,302.539
US+_DxP: R282.1 R283.1 U1.V14
  other v5: 179.397,301.539
US+_GND_PS_ADC: C627.1 C628.1 FB39.2 U1.W21
  other v5: 180.397,308.539
US+_GNDADC: C629.1 C630.1 FB41.2 U1.R14 U1.U14 U1.U15
  other v5: 176.397,301.539 178.397,301.539 178.397,302.539
US+_MGTRref: R173.1 U1.K7
  other v3: 171.397,294.539
US+_MGTRref_K8: R695.2 U1.K8
  other v3: 171.397,295.539
US+_MGTVccAux: C605.2 C606.2 C607.2 C610.2 C611.2 C756.2 C759.2 L16.2 R212.2 R363.1 R364.1 R365.1 R515.1 R522.1 R523.2 R531.1 R546.2 R548.1 R549.2 R551.1 R552.2 R554.1 R555.2 R557.1 R607.2 R659.1 R660.2 R661.1 R662.2 R663.1 R664.2 R735.1 R736.2 R765.1 R766.2 R817.1 R818.2 R820.1 R821.2 R823.1 R824.2 R847.1 R848.2 R849.1 R850.2 R852.1 R853.2 R855.1 R856.2 R858.1 R859.2 R861.2 R921.1 R922.2 R923.1 R924.2 R925.1 R926.2 R927.1 R928.2 R929.1 R930.2 R931.1 R932.2 R933.1 R934.2 R935.1 R936.2 R937.1 R938.2 R939.1 R940.2 R941.1 R942.2 R943.1 R944.2 R945.1 R946.2 R947.1 R948.2 R949.1 R950.2 R951.1 R952.2 R953.1 R954.2 R955.1 R956.2 R957.1 R958.2 R959.1 R960.2 U1.AA4 U1.AC15 U1.AD3 U1.AD8 U1.AE11 U1.AF14 U1.AG7 U1.AG17 U1.AH10 U1.D13 U1.E10 U1.E16 U1.G10 U1.G12 U1.H15 U1.H25 U1.K25 U1.L27 U15.1 U15.7 U15.8 U15.16 U36_U_Translator_I2C1.2 U36_U_Translator_I2C4.2 U79.15 | length 32.1
  L1 w0.254: L16.2@156.819,174.442 156.835,174.458 v7(160.468,174.458) ; R212.2@182.642,172.415 v7(182.642,173.417)
  L1 w0.3: U1.D13@165.397,300.539 v5(165.884,301.027) ; U1.E16@166.397,303.539 v5(166.884,303.052) ; U1.G12@168.397,299.539 v5(168.884,299.052) ; v5(168.909,312.052) U1.H25@169.397,312.539 ; U1.H15@169.397,302.539 v5(169.884,302.052) ; v5(170.909,312.052) U1.K25@171.397,312.539 ; v5(171.909,314.052) U1.L27@172.397,314.539
  L3 (Sign) w0.254: v7(160.468,174.458) 181.602,174.458 v7(182.642,173.417)
  other v3: 166.397,297.539 168.397,297.539
  other v5: 182.397,291.539 184.397,302.539 188.397,304.539
US+_POR_OVE: R693.1 U1.Y6
  other v5: 181.397,293.539
US+_Pudc_B: R694.2 R696.1 U1.W7
  other v5: 180.397,294.539
US+_Vcc_PS_ADC: C627.2 C628.2 FB38.2 U1.W22 | length 1.8
  L1 w0.254: v1(198.768,309.397) 198.819,309.448 FB38.2@200.559,309.448
  other v5: 180.397,309.539
US+_Vcc_PS_Batt: B1.1 C747.1 C748.2 R276.1 U1.U20
  other v5: 178.397,307.539
US+_Vcc_PS_DDR_504: C616.2 C617.2 C618.2 C619.2 C620.2 C621.2 C622.2 C753.1 C754.2 C755.2 L18.2 R220.2 U1.AA24 U1.AB27 U1.AC25 U1.AD28 U1.AE26 U1.AG27 U1.AK26 | length 31.4
  L1 w0.116: v2(182.909,315.027) U1.AB27@183.397,314.539 ; v2(183.91,312.052) U1.AC25@184.397,312.539 ; v2(184.91,315.052) U1.AD28@185.397,315.539 ; U1.AE26@186.397,313.539 v2(186.884,314.027) ; v2(187.909,315.027) U1.AG27@188.397,314.539 ; U1.AK26@191.397,313.539 v2(191.884,314.027)
  L1 w0.254: 166.401,157.07 177.861,157.07 180.059,159.268 180.059,168.365 R220.2@179.984,168.44 179.434,168.44 179.184,168.69 C616.2@179.174,168.69
  L3 (Sign) w0.254: v2(182.909,315.027) v11@182.909,315.531 ; v2(183.91,312.052) v11@184.266,312.408 ; v2(184.91,315.052) v11@184.91,315.556 ; v11(187.897,315.544) 187.909,315.531 v2(187.909,315.027) ; v2(191.884,314.027) v11@192.241,313.671
  other v11: 184.266,312.427 192.259,313.67 182.897,315.544 184.897,315.569
US+_Vcc_PS_DDR_PLL: C631.2 C632.2 FB42.2 U1.U18 U1.U19
  other v5: 178.397,305.539 178.397,306.539
US+_Vcc_PS_IntFp: C738.1 C739.1 C740.2 C744.2 C745.2 C751.1 C752.2 C762.1 C763.2 R271.2 R617.2 U1.AA18 U1.AA20 U1.AA21 U1.AA22 U1.L11 U1.L13 U1.L17 U1.M12 U1.M14 U1.M16 U1.M18 U1.N11 U1.N13 U1.N15 U1.N17 U1.P12 U1.P14 U1.P16 U1.R10 U1.R11 U1.R13 U1.R17 U1.T9 U1.T10 U1.T12 U1.T16 U1.U8 U1.U9 U1.U10 U1.U11 U1.U13 U1.U17 U1.V8 U1.V10 U1.V12 U1.V16 U1.V17 U1.V18 U1.V19 U1.W11 U1.W13 U1.W15 U1.W17 U1.W19 U1.W20 U1.Y12 U1.Y14 U1.Y16 U1.Y17 U1.Y18 U1.Y19 U1.Y20 U1.Y22 U72.8 U72.9
  other v3: 178.397,295.539 179.397,295.539 177.397,296.539 178.397,296.539 176.397,297.539 177.397,297.539 178.397,297.539 179.397,297.539 172.397,298.539 174.397,298.539 176.397,298.539 178.397,298.539
  other v5: 180.397,298.539 173.397,299.539 175.397,299.539 177.397,299.539 179.397,299.539 181.397,299.539 172.397,300.539 174.397,300.539 176.397,300.539 178.397,300.539 180.397,300.539 173.397,301.539 175.397,301.539 181.397,301.539 174.397,302.539 180.397,302.539 173.397,303.539 175.397,303.539 177.397,303.539 179.397,303.539 181.397,303.539 172.397,304.539 174.397,304.539 176.397,304.539 178.397,304.539 179.397,304.539 180.397,304.539 181.397,304.539 173.395,305.545 179.397,305.539 181.397,305.539 182.397,305.539 179.397,306.539 180.397,306.539 181.397,306.539 180.397,307.539 181.397,307.539 182.397,307.539 182.397,308.539 181.397,309.539 182.397,309.539
  other v10: 142.777,289.801 144.53,289.801 146.282,289.801 139.272,289.801 141.025,289.801 139.272,291.554 141.025,291.554 142.777,291.554 144.53,291.554 146.282,291.554 142.777,293.306 144.53,293.306 146.282,293.306 139.272,293.306 141.025,293.306 139.272,295.059 141.025,295.059 142.777,295.059 144.53,295.059 146.282,295.059 142.777,296.812 144.53,296.812 146.282,296.812 139.272,296.812 141.025,296.812 139.272,298.564 141.025,298.564 142.777,298.564 144.53,298.564 146.282,298.564 142.777,300.317 144.53,300.317 146.282,300.317 139.272,300.317 141.025,300.317 139.272,302.07 141.025,302.07 142.777,302.069 144.53,302.069 146.282,302.069
US+_Vcc_PS_IntFpDDR: C764.1 C765.2
US+_VccADC: C629.2 C630.2 FB40.2 U1.R15
  other v5: 176.397,302.539
US+_VN: J29.1 U1.T15
  other v5: 177.397,302.539
US+_VP: J29.2 U1.T14
  other v5: 177.397,301.539
US_PADI: C535.2 R374.1 U1.M21 X5.1 | length 44.3
  L1 w0.116: U1.M21@173.397,308.539 v5(173.884,308.052)
  L16 w0.12: v5(173.884,308.052) 174.422,307.515 174.422,305.511 174.987,304.946 174.987,304.37 175.227,304.129 175.259,304.129 175.336,304.052 181.909,304.052 183.463,305.605 184.29,305.605 185.476,304.419 187.329,304.419 187.914,303.835 190.761,303.835 192.044,305.118 194.462,305.118 195.356,306.011 196.139,306.011 197.118,306.99 199.408,306.99 204.31,311.893 R374.1@204.31,313.797 C535.2@204.31,314.782 204.31,316.26 204.7,316.649 X5.1@205.11,316.649
US_PADO: C536.2 R374.2 U1.N21 X5.2 | length 39
  L1 w0.116: U1.N21@174.397,308.539 v5(174.884,308.052)
  L16 w0.12: v5(174.884,308.052) 175.294,307.642 175.987,307.642 176.397,307.232 176.397,306.539 176.987,305.949 179.724,305.949 179.827,306.052 185.884,306.052 186.397,305.539 194.032,305.539 194.724,306.231 196.048,306.231 197.027,307.21 199.188,307.21 203.41,311.433 R374.2@203.41,313.797 C536.2@203.41,314.782 203.41,316.237 202.998,316.649 X5.2@202.61,316.649
US_PS_DONE: R357.1 U1.N22 U43.6 | length 93.7
  L1 w0.116: U1.N22@174.397,309.539 v5(174.884,309.052)
  L12 (Sign) w0.12: v1(201.841,310.865) 202.36,311.383 208.827,311.383 210.541,313.097 210.541,357.716 209.943,358.314 207.454,358.314 v1(206.34,359.428)
  L16 w0.12: v5(174.884,309.052) 175.397,308.539 176.106,308.539 176.39,308.255 176.39,307.783 177.138,307.035 182.481,307.035 182.654,306.863 183.519,306.863 183.74,306.642 184.294,306.642 184.485,306.451 186.729,306.451 186.74,306.462 187.079,306.462 187.09,306.451 195.957,306.451 196.936,307.43 199.097,307.43 201.841,310.175 v1(201.841,310.865) ; U43.6@204.17,360.429 205.318,360.429 206.319,359.428 v1(206.34,359.428) 206.422,359.346 R357.1@207.068,359.346
US_PS_Err_Out: U1.R22 U43.3 | length 113.5
  L1 w0.116: U1.R22@176.397,309.539 v5(176.884,309.052)
  L5 (Sign) w0.12: v1(208.077,310.803) 208.077,311.715 219.567,323.205 219.567,323.41 219.807,323.65 220.012,323.65 220.388,324.026 220.388,344.314 v1(220.405,344.297)
  L12 (Sign) w0.12: v5(176.884,309.052) 176.806,309.052 176.403,308.649 176.403,307.77 177.138,307.035 181.546,307.035 181.864,306.718 181.864,306.356 182.15,306.07 182.55,306.07 183.058,305.562 184.455,305.562 185.598,304.419 186.906,304.419 187.185,304.14 203.175,304.14 208.077,309.042 v1(208.077,310.803)
  L14 (Sign) w0.12: v9(205.791,362.42) 205.791,362.445 206.616,363.271 219.926,363.271 220.405,362.792 v1(220.405,344.297)
  L16 w0.12: U43.3@204.17,362.379 205.75,362.379 v9(205.791,362.42)
US_PS_Err_Status: U1.R20 U43.4 | length 101.7
  L1 w0.116: U1.R20@176.397,307.539 v2(176.884,307.052)
  L5 (Sign) w0.12: v11(204.889,309.131) 205.702,309.943 205.702,310.896 218.467,323.66 218.467,323.866 219.288,324.687 219.288,342.714 218.687,343.315 218.687,344.126 218.63,344.183 218.63,345.245 219.011,345.626 v1(219.011,346.443)
  L3 (Sign) w0.12: v2(176.884,307.052) 183.341,307.052 183.769,307.48 185.337,307.48 185.574,307.717 204.555,307.717 204.889,308.051 v11(204.889,309.131)
  L14 (Sign) w0.12: v9(207.366,361.747) 208.813,360.299 208.813,358.978 210.071,357.721 217.716,357.721 218.999,356.438 218.999,346.456 v1(219.011,346.443)
  L16 w0.12: U43.4@204.17,361.729 204.188,361.747 v9(207.366,361.747)
US_PS_Init_B: R353.2 U1.N18 U43.5 | length 104.9
  L1 w0.116: v5(173.909,305.052) U1.N18@174.397,305.539
  L12 (Sign) w0.12: v5(173.909,305.052) 173.909,302.344 174.21,302.044 179.696,302.044 179.946,301.794 179.946,299.237 180.149,299.034 186.315,299.034 188.017,300.736 201.346,300.736 211.112,310.502 211.112,311.198 211.112,357.455 210.034,358.534 208.775,358.534 v1(206.286,361.023)
  L16 w0.12: U43.5@204.17,361.079 205.607,361.079 206.019,360.667 206.286,360.667 ; v1(206.286,361.023) 206.286,360.667 ; R353.2@207.068,360.667 206.286,360.667
US_PS_JTAG_TCK: R346.2 R1028.2 U1.L19 | length 178.2
  L1 w0.116: U1.L19@172.397,306.539 v2(172.884,306.052)
  L1 w0.12: R1028.2@222.413,203.95 222.426,203.962 v2@224.511,203.962 ; v2@224.511,203.944 v2(224.523,203.956) ; v2@224.523,203.962 R346.2@226.797,203.962
  L3 (Sign) w0.12: 172.84,305.845 172.84,303.326 172.019,302.505 170.216,302.505 170.114,302.607 169.654,302.607 169.553,302.505 168.463,302.505 167.117,301.159 166.219,301.159 166.219,301.166 166.023,301.362 165.746,301.362 165.549,301.166 165.549,301.159 160.048,301.159 158.065,299.177 158.065,294.932 154.186,291.053 154.186,290.136 154.408,289.914 154.408,288.003 154.416,287.994 154.416,285.994 161.941,278.47 176.85,278.47 178.286,277.035 210.582,277.035 224.341,263.275 224.341,207.815 224.523,207.632 v2(224.523,203.956) ; 172.84,305.845 172.84,306.008 v2(172.884,306.052)
US_PS_JTAG_TDI: R347.2 R1026.2 U1.L20 | length 175.5
  L1 w0.116: U1.L20@172.397,307.539 v2(172.884,307.052)
  L1 w0.12: R1026.2@222.413,206.983 v2@224.121,206.983 ; v2(224.121,207.006) v2@224.13,206.997 ; v2@224.13,206.983 R347.2@226.797,206.983
  L3 (Sign) w0.12: v2(172.884,307.052) 172.884,306.559 172.542,306.217 172.542,305.376 171.856,304.69 171.856,303.551 171.549,303.244 169.101,303.244 168.583,302.725 168.372,302.725 167.026,301.379 166.317,301.379 166.114,301.582 165.654,301.582 165.452,301.379 159.957,301.379 157.845,299.268 157.845,295.024 153.966,291.145 153.966,290.045 154.188,289.823 154.188,287.912 154.196,287.903 154.196,285.903 161.85,278.25 176.759,278.25 178.194,276.815 210.49,276.815 224.121,263.184 v2(224.121,207.006)
US_PS_JTAG_TDO: R1029.2 U1.M20 | length 179.3
  L1 w0.116: U1.M20@173.397,307.539 v2(173.884,307.052)
  L1 w0.12: R1029.2@222.413,202.433 v2@224.892,202.433
  L3 (Sign) w0.12: v2(173.884,307.052) 173.884,306.754 173.219,306.089 173.219,305.913 173.063,305.757 173.063,305.687 173.06,305.684 173.06,304.68 173.062,304.678 173.062,304.401 173.063,304.4 173.063,303.679 173.062,303.678 173.062,303.237 172.11,302.285 170.125,302.285 170.023,302.387 169.746,302.387 169.644,302.285 168.554,302.285 167.208,300.939 166.219,300.939 166.219,300.888 166.023,300.692 165.746,300.692 165.549,300.888 165.549,300.939 160.139,300.939 158.285,299.085 158.285,294.841 154.406,290.962 154.406,290.227 154.628,290.005 154.628,288.094 154.636,288.086 154.636,286.086 162.032,278.69 176.942,278.69 178.377,277.255 210.673,277.255 224.561,263.367 224.561,207.912 224.892,207.582 v2(224.892,202.438)
US_PS_JTAG_TMS: R348.2 R1027.2 U1.L21 | length 178.3
  L1 w0.116: U1.L21@172.397,308.539 v2(172.884,308.052)
  L1 w0.12: R1027.2@222.413,205.466 223.297,205.466 v2(223.304,205.473) R348.2@226.797,205.472
  L3 (Sign) w0.12: v2(172.884,308.052) 172.884,307.699 172.339,307.154 172.339,306.378 172.288,306.327 172.288,305.433 171.636,304.782 171.636,303.644 171.456,303.464 169.01,303.464 168.492,302.945 168.281,302.945 166.935,301.599 166.408,301.599 166.205,301.802 165.563,301.802 165.361,301.599 159.866,301.599 157.625,299.359 157.625,295.115 153.746,291.236 153.746,289.954 153.968,289.732 153.968,287.821 153.976,287.812 153.976,285.812 161.759,278.03 176.668,278.03 178.103,276.595 210.399,276.595 223.786,263.208 223.786,205.955 v2(223.304,205.473)
US_PS_Mode0: P2.4 R349.1 S1.1 U1.R18 | length 102.5
  L1 w0.116: U1.R18@176.397,305.539 v5(176.884,305.052)
  L1 w0.12: S1.1@232.473,346.481 234.772,346.481 v1(234.899,346.354) 235.42,346.354 P2.4@237.071,344.703
  L1 w0.2: P2.4@237.071,344.703 238.722,346.354 R349.1@242.659,346.354
  L5 (Sign) w0.12: v1(209.277,310.803) 209.277,312.229 219.878,322.83 220.147,322.83 220.387,323.071 220.387,323.41 220.608,323.631 220.608,343.829 221.52,344.742 232.925,344.742 234.537,346.354 v1(234.899,346.354)
  L12 (Sign) w0.12: v5(176.884,305.052) 181.422,305.052 182.971,303.502 185.646,303.502 186.118,303.974 186.728,303.974 187.004,303.699 203.343,303.699 203.344,303.7 203.357,303.7 209.277,309.62 v1(209.277,310.803)
US_PS_Mode2: P2.2 R351.1 S1.3 U1.P21 | length 106.1
  L1 w0.116: U1.P21@175.397,308.539 v5(175.884,308.052)
  L1 w0.12: S1.3@232.473,349.021 v1(234.886,349.021) 236.309,349.021 P2.2@237.071,349.783
  L1 w0.2: P2.2@237.071,349.783 237.875,348.979 R351.1@242.659,348.979
  L5 (Sign) w0.12: v1(206.963,309.994) 206.68,310.278 206.68,310.94 219.127,323.387 219.127,323.592 219.625,324.09 219.83,324.09 219.948,324.208 219.948,342.987 219.347,343.588 219.347,345.013 219.664,345.33 233.202,345.33 234.92,347.048 234.92,347.491 235.11,347.681 235.11,348.203 234.886,348.426 v1(234.886,349.021)
  L14 (Sign) w0.12: v5(175.884,308.052) 175.884,307.668 176.416,307.137 176.416,306.458 176.705,306.169 185.941,306.169 186.43,305.68 203.657,305.68 206.963,308.986 v1(206.963,309.994)
US_PS_Mode3: P2.1 R352.1 S1.4 U1.P22 | length 108.7
  L1 w0.116: U1.P22@175.397,309.539 v5(175.884,309.052)
  L1 w0.12: S1.4@232.473,350.291 234.836,350.291 v1(234.874,350.329) 235.318,350.774 235.318,351.726 235.915,352.323 P2.1@237.071,352.323
  L1 w0.2: P2.1@237.071,352.323 239.103,350.291 R352.1@242.659,350.291
  L5 (Sign) w0.12: v1(206.363,309.994) 206.363,310.935 218.907,323.478 218.907,323.684 219.533,324.31 219.657,324.31 219.728,324.381 219.728,342.896 219.127,343.497 219.127,345.111 219.566,345.55 233.111,345.55 234.7,347.14 234.7,347.582 234.89,347.772 234.89,348.112 234.444,348.558 234.444,349.9 v1(234.874,350.329)
  L14 (Sign) w0.12: v5(175.884,309.052) 175.884,308.925 176.397,308.413 176.397,307.613 177.013,306.997 182.608,306.997 183.052,306.553 204.218,306.553 206.743,309.077 206.743,309.614 v1(206.363,309.994)
US_PS_Prog_B: R356.2 R367.1 S2.1 S2.2 U1.M19 | length 100.2
  L1 w0.116: U1.M19@173.397,306.539 v5(173.884,306.052)
  L5 (Sign) w0.12: v1(207.563,309.994) 207.01,310.548 207.01,310.959 219.347,323.296 219.347,323.501 219.716,323.87 219.921,323.87 220.168,324.117 220.168,343.458 v1(219.786,343.84)
  L12 (Sign) w0.12: v1(219.786,343.84) 219.913,343.713 233.578,343.713 v1(236.156,341.135)
  L14 (Sign) w0.12: v5(173.884,306.052) 174.476,305.46 176.95,305.46 177.343,305.067 183.058,305.067 183.337,305.346 183.719,305.346 183.765,305.392 184.043,305.392 184.075,305.36 184.664,305.949 185.85,305.949 186.339,305.46 203.749,305.46 207.183,308.895 207.183,309.614 v1(207.563,309.994)
  L16 w0.12: R367.1@236.156,340.03 236.156,338.684 R356.2@236.207,338.633 ; R367.1@236.194,340.03 236.194,341.097 v1(236.156,341.135) 236.565,341.135 236.932,340.768 S2.2@238.702,340.768
US_PS_Ref_Clk: R375.2 U1.P19 | length 59.2
  L1 w0.116: U1.P19@175.397,306.539 v5(175.884,306.052)
  L1 w0.12: v2(220.575,325.438) 220.65,325.512 R375.2@220.65,326.285
  L5 (Sign) w0.12: v1(208.677,310.803) 208.677,311.94 v11(219.977,323.24)
  L12 (Sign) w0.12: v5(175.884,306.052) 181.358,306.052 181.732,305.678 181.732,305.18 183.189,303.722 185.555,303.722 186.027,304.194 186.819,304.194 187.095,303.919 203.252,303.919 203.253,303.92 203.266,303.92 208.677,309.331 v1(208.677,310.803)
  L3 (Sign) w0.12: v11(219.977,323.24) 219.977,324.839 v2(220.575,325.438)
USB2_CLK: R362.2 U45.1 | length 6.4
  L16 w0.12: U45.1@57.555,348.841 57.555,349.719 58.233,350.397 R362.2@62.801,350.397
USB2_D0: R116.2 U45.3 | length 5.6
  L16 w0.12: U45.3@57.555,347.841 58.268,347.841 59.046,348.619 R116.2@62.801,348.619
USB2_D1: R117.2 U45.4 | length 3
  L16 w0.12: U45.4@57.555,347.341 58.86,347.341 59.222,347.702 R117.2@60.427,347.702
USB2_D2: R115.2 U45.5 | length 5.2
  L16 w0.12: U45.5@57.555,346.841 R115.2@62.801,346.841
USB2_D3: R119.2 U45.6 | length 3
  L16 w0.12: U45.6@57.555,346.341 58.726,346.341 59.137,345.929 R119.2@60.427,345.929
USB2_D4: R120.2 U45.7 | length 5.6
  L16 w0.12: U45.7@57.555,345.841 58.286,345.841 59.064,345.063 R120.2@62.801,345.063
USB2_D5: R121.2 U45.9 | length 6.5
  L16 w0.12: U45.9@56.855,344.641 58.211,343.285 R121.2@62.801,343.285
USB2_D6: R122.2 U45.10 | length 5.3
  L16 w0.12: U45.10@56.355,344.641 56.355,344.177 58.149,342.383 R122.2@60.427,342.383
USB2_D7: R802.1 U45.13 | length 11.7
  L16 w0.12: U45.13@54.855,344.641 54.855,343.778 55.118,343.515 55.118,341.135 55.461,340.792 56.896,340.792 57.611,341.507 R802.1@62.801,341.507
USB2_DIR: R800.1 U45.31 | length 5.4
  L16 w0.12: U45.31@56.355,349.541 56.355,350.64 56.964,351.248 R800.1@60.427,351.248
USB2_NXT: R801.1 U45.2 | length 3.3
  L16 w0.12: U45.2@57.555,348.341 58.21,348.341 59.343,349.475 R801.1@60.427,349.475
USB2_STP: R118.2 U45.29 | length 9.8
  L16 w0.12: U45.29@55.355,349.541 55.355,351.625 55.905,352.175 R118.2@62.801,352.175
USB_D_N: C537.2 D13.2 U45.19 | length 19.4
  L16 w0.1: C537.2@37.721,351.698 ccw(c39.29,353.267) 39.29,351.048 D13.2@40.723,351.048 40.868,350.903 41.273,350.903 41.273,350.91 41.361,350.998 41.785,350.998 41.873,350.91 41.873,350.903 47.805,350.903 cw(c47.805,350.05) 48.657,350.05 48.657,346.659 ccw(c49.021,346.659) 49.021,346.296 52.61,346.296 U45.19@52.655,346.341
USB_D_P: C537.3 D13.1 U45.18 | length 19.4
  L16 w0.1: C537.3@37.721,349.698 cw(c39.29,348.129) 39.29,350.348 D13.1@40.723,350.348 40.868,350.493 41.273,350.493 41.273,350.486 41.361,350.398 41.785,350.398 41.873,350.486 41.873,350.493 47.805,350.493 cw(c47.805,350.05) 48.247,350.05 48.247,346.659 ccw(c49.021,346.659) 49.021,345.886 52.61,345.886 U45.18@52.655,345.841
USB_En_Vout: U45.17 U46.A2
USB_OSC_IN: C736.2 R491.2 U45.26 X7.1
USB_OSC_Out: C737.2 R491.1 U45.25 X7.3
USB_RS0: R376.1 U45.8 | length 3.4
  L16 w0.12: U45.8@57.555,345.341 58.031,345.341 59.216,344.156 R376.1@60.427,344.156
USB_RS1: R377.1 U45.11 | length 1.8
  L16 w0.12: R377.1@55.855,342.837 U45.11@55.855,344.641
USB_RS2: R378.1 U45.14 | length 1.8
  L16 w0.12: R378.1@54.355,342.847 U45.14@54.355,344.641
USB_RX_C_N: C537.5 C543.2 D14.1 D14.10 | length 10
  L1 w0.1: v1(40.276,349.009) cw(c40.6,349.009) 40.371,349.238 40.45,349.317 cw(c41.522,348.244) 41.522,349.761 D14.10@41.874,349.761 ; D14.1@42.708,349.761 cw(c42.817,349.653) 42.817,349.806 43.256,349.806 cw(c43.256,349.207) 43.68,349.631 43.744,349.567 ccw(c44.245,350.068) 44.245,349.359 44.806,349.359 cw(c44.806,348.679) 45.286,349.16 C543.2@45.33,349.116
  L12 (Sign) w0.1: C537.5@36.22,346.698 36.22,347.364 cw(c36.373,347.364) 36.373,347.517 36.375,347.517 ccw(c36.375,348.459) 37.04,347.793 37.205,347.957 cw(c37.935,347.227) 37.935,348.259 38.429,348.259 ccw(c38.429,350.504) 40.016,348.917 40.017,348.918 cw(c40.237,348.698) 40.237,349.009 v1(40.276,349.009)
USB_RX_C_P: C537.6 C542.2 D14.2 D14.9 | length 10
  L1 w0.1: v1(39.852,349.433) ccw(c39.852,349.757) 40.081,349.528 40.161,349.608 cw(c41.738,348.03) 41.738,350.261 D14.9@41.874,350.261 ; D14.2@42.709,350.261 ccw(c42.817,350.37) 42.817,350.216 43.258,350.216 cw(c43.258,349.211) 43.969,349.922 44.032,349.858 ccw(c44.247,350.073) 44.247,349.769 44.806,349.769 ccw(c44.806,350.449) 45.286,349.968 C542.2@45.33,350.012
  L12 (Sign) w0.1: C537.6@36.22,348.698 36.22,348.031 ccw(c36.373,348.031) 36.373,347.879 ccw(c36.373,348.463) 36.786,348.05 36.951,348.215 cw(c37.932,347.234) 37.932,348.622 38.427,348.622 ccw(c38.427,350.507) 39.76,349.174 ccw(c39.54,349.394) 39.852,349.394 v1(39.852,349.433)
USB_RX_N: C543.1 U1.J25 | length 158.3
  L1 w0.1: C543.1@46.11,349.116 46.192,349.116 ccw(c46.192,349.359) 46.435,349.359 49.499,349.359 cw(c49.499,349.264) v1(49.593,349.264)
  L1 w0.116: v5(169.909,313.027) U1.J25@170.397,312.539
  L5 (Sign) w0.1: v1(49.593,349.264) cw(c49.712,349.264) 49.712,349.383 122.066,349.383 cw(c122.066,347.052) 124.396,347.052 124.396,322.567 ccw(c127.299,322.567) 127.299,319.665 167.85,319.665 cw(c167.85,319.087) 168.427,319.087 168.427,316.531 cw(c167.987,316.531) 168.298,316.219 ccw(c168.892,315.626) 168.052,315.626 168.052,315.11 ccw(c169.605,315.11) 168.507,314.012 168.886,313.633 ccw(c169.58,314.327) 169.58,313.346 169.761,313.346 cw(c169.761,313.197) 169.909,313.197 v5(169.909,313.027)
USB_RX_P: C542.1 U1.J26 | length 158.3
  L1 w0.1: C542.1@46.11,350.012 46.192,350.012 cw(c46.192,349.769) 46.435,349.769 49.499,349.769 ccw(c49.499,349.864) v1(49.593,349.864)
  L1 w0.116: v5(169.909,314.027) U1.J26@170.397,313.539
  L5 (Sign) w0.1: v1(49.593,349.864) ccw(c49.712,349.864) 49.712,349.745 122.066,349.745 cw(c122.066,347.052) 124.759,347.052 124.759,322.567 ccw(c127.299,322.567) 127.299,320.027 167.85,320.027 cw(c167.85,319.087) 168.79,319.087 168.79,316.531 cw(c167.987,316.531) 168.554,315.963 ccw(c168.892,315.626) 168.415,315.626 168.415,315.112 ccw(c169.61,315.112) 168.765,314.267 169.141,313.891 ccw(c169.583,314.334) 169.583,313.708 169.761,313.708 ccw(c169.761,313.857) 169.909,313.857 v5(169.909,314.027)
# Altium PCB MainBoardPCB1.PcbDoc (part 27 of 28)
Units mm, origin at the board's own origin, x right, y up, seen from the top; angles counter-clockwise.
Board outline 258.95 x 308.86 mm, 16 copper layers (L1, L2 (GND), L3 (Sign), L4 (GND), L5 (Sign), L6 (PWR/GND), L7(PWR/GND), L8 (Plane_GND), L9 (PWR/GND), L10 (PWR/GND), L11 (PWR/GND), L12 (Sign), L13 (GND), L14 (Sign), L15 (GND), L16), stack 2.502 mm thick; 2397 components, 1744 nets, 8397 pads, 4112 vias.
Unrouted connection lines stored in the file: 3547.

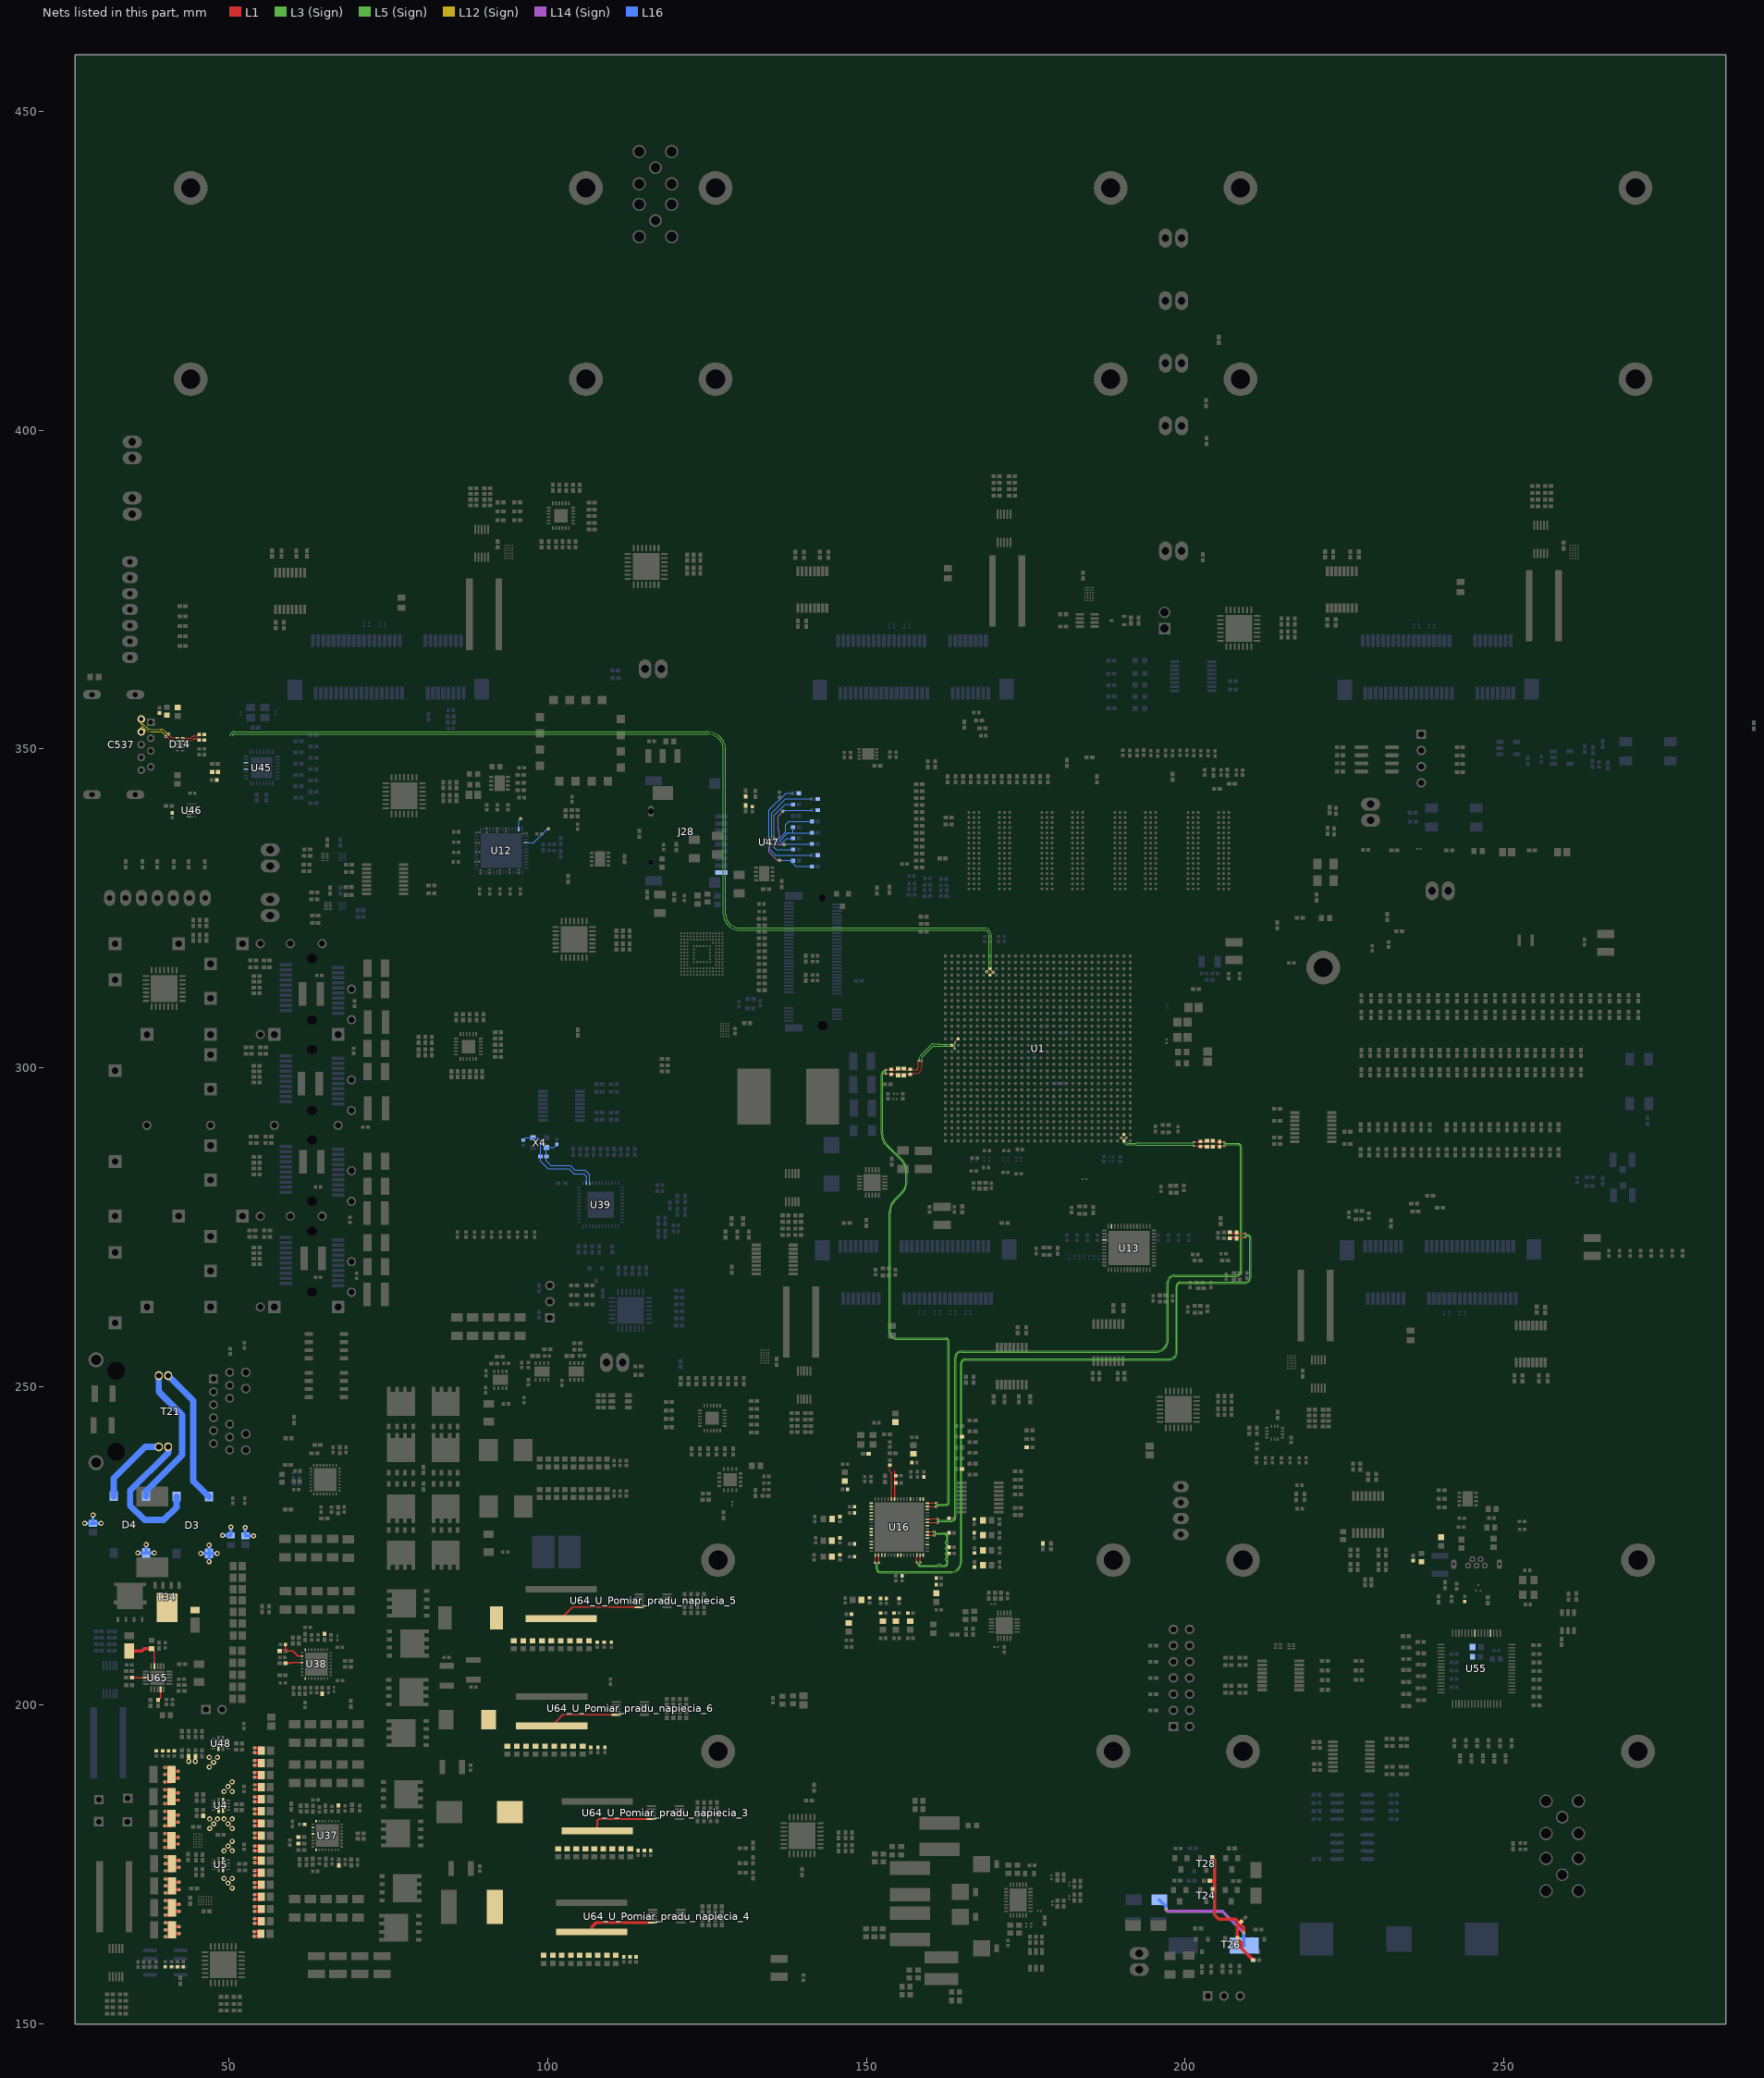
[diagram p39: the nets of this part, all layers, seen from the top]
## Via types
v1: diameter 0.5, hole 0.2, L1 to L16, tented both sides, 1457 vias
v2: diameter 0.35/0/0.35 (per signal layer), hole 0.127, L1 to L3 (Sign), tented both sides, 479 vias
v3: diameter 0.5/0.35/0.35/0.35/0.35/0.35/0.35/0.35/0.35/0.35/0.35/0.35/0.35/0.35/0.35/0.5 (per signal layer), hole 0.15, L1 to L16, tented both sides, 453 vias
v4: diameter 0.5, hole 0.2, L1 to L16, 451 vias
v5: diameter 0.5/0.35/0.35/0.35/0.35/0.35/0.35/0.35/0.35/0.35/0.35/0.35/0.35/0.35/0.35/0.5 (per signal layer), hole 0.2, L1 to L16, tented both sides, 373 vias
v6: diameter 0.8, hole 0.4, L1 to L16, tented both sides, 168 vias
v7: diameter 0.35/0/0.35 (per signal layer), hole 0.127, L1 to L3 (Sign), 138 vias
v8: diameter 2.54, hole 1.02, L1 to L16, 113 vias
v9: diameter 0.5/0/0.5 (per signal layer), hole 0.2, L14 (Sign) to L16, tented both sides, 102 vias
v10: diameter 1.4, hole 0.5, L1 to L16, tented both sides, 80 vias
v11: diameter 0.5, hole 0.2, L3 (Sign) to L6 (PWR/GND), tented both sides, 54 vias
v12: diameter 0.35, hole 0.127, L1 to L2 (GND), tented both sides, 47 vias
v13: diameter 0.4, hole 0.2, L1 to L16, tented both sides, 46 vias
v14: diameter 0.35, hole 0.127, L1 to L16, tented both sides, 16 vias
v15: diameter 0.25, hole 0.2, L1 to L16, 16 vias
v16: diameter 0.5, hole 0.2, L11 (PWR/GND) to L14 (Sign), tented both sides, 16 vias
v17: diameter 0.4, hole 0.2, L1 to L16, 16 vias
v18: diameter 0.3, hole 0.2, L1 to L16, 15 vias
v19: diameter 0.45, hole 0.15, L1 to L16, 12 vias
v20: diameter 0.5/0.35/0.35/0.35/0.35/0.35/0.35/0.35/0.35/0.35/0.35/0.35/0.35/0.35/0.35/0.45 (per signal layer), hole 0.15, L1 to L16, tented both sides, 10 vias
v21: diameter 0.2/0/0.2 (per signal layer), hole 0.1, L1 to L3 (Sign), tented both sides, 9 vias
v22: diameter 0.3, hole 0.127, L14 (Sign) to L16, tented both sides, 8 vias
v23: diameter 0.4, hole 0.1, L1 to L16, 7 vias
v24: diameter 1.15, hole 1.15, L1 to L16, 5 vias
v25: diameter 1.65, hole 1.65, L1 to L16, 5 vias
v26: diameter 0.2, hole 0.1, L1 to L16, 4 vias
v27: diameter 0.4, hole 0.15, L1 to L16, 2 vias
v28: diameter 0.5/0.35/0.35/0.35/0.35/0.35/0.35/0.35/0.35/0.35/0.35/0.35/0.35/0.35/0.35/0.5 (per signal layer), hole 0.15, L1 to L16, 2 vias
v29: diameter 0.35, hole 0.127, L3 (Sign) to L6 (PWR/GND), tented both sides, 2 vias
v30: diameter 0.3, hole 0.127, L15 (GND) to L16, tented both sides, 1 vias
v31: diameter 0.35, hole 0.127, L1 to L2 (GND), 1 vias
v32: diameter 0.5/0.35/0.35/0.35/0.35/0.35/0.35/0.35/0.35/0.35/0.35/0.35/0.35/0.35/0.35/0.5 (per signal layer), hole 0.2, L1 to L16, 1 vias
v33: diameter 0.35/0.35/0.35 (per signal layer), hole 0.127, L1 to L3 (Sign), tented both sides, 1 vias
v34: diameter 0.45/0/0.45 (per signal layer), hole 0.15, L1 to L3 (Sign), tented both sides, 1 vias
v35: diameter 0.45/0/0.45 (per signal layer), hole 0.2, L14 (Sign) to L16, tented both sides, 1 vias

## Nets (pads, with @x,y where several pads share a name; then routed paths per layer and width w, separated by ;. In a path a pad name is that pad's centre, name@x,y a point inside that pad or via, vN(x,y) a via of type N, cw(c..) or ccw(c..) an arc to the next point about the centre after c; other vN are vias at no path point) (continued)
USB_TX_C_N: C537.8 C541.2 D14.4 D14.7 | length 10.1
  L1 w0.1: v1(40.042,351.954) cw(c40.042,351.629) 40.271,351.859 40.348,351.782 ccw(c41.604,353.038) 41.604,351.261 D14.7@41.874,351.261 ; D14.4@42.708,351.261 42.996,351.261 ccw(c42.996,351.306) 43.041,351.306 43.828,351.306 ccw(c43.828,352.131) 44.411,351.548 ; 44.412,351.549 cw(c44.629,351.331) 44.629,351.639 44.92,351.639 cw(c44.92,351.234) 45.206,351.52 C541.2@45.33,351.396
  L12 (Sign) w0.1: C537.8@36.22,352.698 36.22,353.39 cw(c36.347,353.39) 36.347,353.517 cw(c36.347,353.423) 36.413,353.489 36.755,353.147 ccw(c37.718,354.11) 37.718,352.749 39.191,352.749 cw(c39.191,352.207) 39.573,352.59 40.042,352.122 v1(40.042,351.954)
USB_TX_C_P: C537.9 C540.2 D14.5 D14.6 | length 10
  L1 w0.1: v1(40.466,352.378) ccw(c40.79,352.378) v1@40.561,352.149 ; v1@40.561,352.149 40.635,352.074 ccw(c41.39,352.829) 41.39,351.761 D14.6@41.874,351.761 ; D14.5@42.708,351.761 42.996,351.761 cw(c42.996,351.716) 43.041,351.716 43.827,351.716 ccw(c43.827,352.134) 44.122,351.839 44.124,351.84 cw(c44.627,351.337) 44.627,352.049 44.92,352.049 ccw(c44.92,352.453) 45.206,352.167 C540.2@45.33,352.291
  L12 (Sign) w0.1: C537.9@36.22,354.698 36.22,354.006 ccw(c36.347,354.006) 36.347,353.879 ; 36.348,353.879 cw(c36.348,353.426) 36.669,353.746 37.01,353.405 ccw(c37.721,354.116) 37.721,353.111 39.192,353.111 cw(c39.192,352.21) 39.829,352.847 40.298,352.378 v1(40.466,352.378)
USB_TX_N: C541.1 U1.H28 | length 154.5
  L1 w0.116: v5(168.909,315.052) U1.H28@169.397,315.539
  L5 (Sign) w0.1: 50.521,352.069 cw(c50.813,352.069) 50.813,352.361 125.025,352.361 cw(c125.025,349.821) 127.565,349.821 127.565,324.167 ccw(c130.168,324.167) 130.168,321.564 168.504,321.564 cw(c168.504,320.852) 169.216,320.852 169.216,315.358 cw(c168.909,315.358) v5(168.909,315.052)
USB_TX_P: C540.1 U1.H27 | length 155.7
  L1 w0.116: U1.H27@169.397,314.539 v5(169.884,315.027)
  L5 (Sign) w0.1: 50.158,352.069 cw(c50.813,352.069) 50.813,352.724 125.025,352.724 cw(c125.025,349.821) 127.927,349.821 127.927,324.167 ccw(c130.168,324.167) 130.168,321.926 168.504,321.926 cw(c168.504,320.852) 169.578,320.852 169.578,315.333 ccw(c169.884,315.333) v5(169.884,315.027)
USB_Vbus: R490.1 U45.22
USB_Vdd33: C731.2 U45.20
USB_Vout: C538.2 C539.2 C734.2 FB26.1 R490.2 U46.C2 U46.D1 U46.D2 U46.E1 U46.E2 U46.F1 U46.F2
uSD_CD: J28.9 R381.1 R782.1 U47.D3 | length 9.1
  L14 (Sign) w0.12: v22(134.727,335.004) 134.727,333.839 136.042,332.524 v9(136.36,332.524)
  L16 w0.12: v9(136.36,332.524) 138.495,332.524 R782.1@138.495,332.473 138.495,332.014 138.925,331.584 R381.1@141.461,331.584
uSD_CLK: R96.2 R97.1 U47.C1 | length 7.5
  L16 w0.098: U47.C1@135.527,335.404 U47.C1@135.529,335.404
  L16 w0.12: U47.C1@135.529,335.404 136.23,335.404 137.693,336.868 137.706,336.855 138.452,336.855 ; R96.2@138.495,337.753 138.495,336.898 138.452,336.855 ; R97.1@141.461,336.855 138.452,336.855
uSD_CMD: R95.2 U47.D2 | length 6.4
  L14 (Sign) w0.12: v22(135.127,335.004) v9(137.109,335.005)
  L16 w0.12: v9(137.109,335.005) 137.212,335.107 R95.2@141.461,335.107
uSD_D0: R87.2 U47.D1 | length 3.4
  L16 w0.098: U47.D1@135.527,335.004 U47.D1@135.529,335.004 135.824,335.004
  L16 w0.12: 135.824,335.004 136.453,335.004 137.437,335.989 R87.2@138.495,335.989
uSD_D1: R88.2 U47.E1 | length 3.1
  L16 w0.12: U47.E1@135.529,334.604 135.903,334.231 R88.2@138.495,334.231
uSD_D2: R89.2 U47.A1 | length 7
  L16 w0.12: U47.A1@135.529,336.204 135.529,339.58 137.262,341.312 R89.2@138.475,341.312
uSD_D3: R90.2 U47.B1 | length 7.8
  L16 w0.098: U47.B1@135.527,335.804 135.788,335.804
  L16 w0.12: 135.788,335.804 136.171,335.804 137.338,336.972 137.338,338.15 137.808,338.62 141.436,338.62 R90.2@141.461,338.645
uSD_D4: R91.1 U47.B2 | length 10.7
  L14 (Sign) w0.12: v22(135.129,335.804) 136.171,335.804 136.322,335.956 136.322,337.152 136.131,337.343 136.131,339.473 136.917,340.258 v9(136.868,340.258)
  L16 w0.12: v9(136.868,340.258) 137.02,340.411 141.461,340.411
uSD_D5: R92.1 U47.A2 | length 11
  L16 w0.12: U47.A2@135.129,336.204 135.129,339.955 137.35,342.176 141.461,342.176
uSD_D6: R93.1 U47.A3 | length 9.1
  L16 w0.12: U47.A3@134.729,336.204 134.729,340.431 137.363,343.065 138.495,343.065
uSD_D7: R94.1 U47.E3 | length 7.4
  L16 w0.12: U47.E3@134.729,334.604 134.729,334.333 135.712,333.35 141.461,333.35
V_KEY: C609.2 D24.2 R647.2 R648.2 R653.1 T24.1 T26.1 T28.1 | length 41.2
  L1 w0.5: R653.1@203.866,172.467 204.611,172.467 204.648,172.504 ; T28.1@204.277,176.105 204.648,175.734 204.648,172.504 ; T24.1@204.29,171.114 204.624,171.114 204.648,171.09 ; v1(209.232,164.325) 209.232,165.14 208.554,165.818 ; R648.2@210.688,160.033 208.827,161.893 208.827,162.805 T26.1@208.214,163.418 208.214,165.479 208.554,165.818 ; 204.648,171.09 204.648,172.504 ; 204.648,171.09 204.648,167.081 205.296,166.433 207.939,166.433 208.554,165.818
  L14 (Sign) w0.5: v9(197.002,167.945) 197.252,167.696 205.862,167.696 v1(209.232,164.325)
  L16 w0.5: D24.2@195.954,169.495 197.002,168.447 v9(197.002,167.945) ; v1(209.232,164.325) 209.232,162.395 C609.2@209.295,162.332
V_PoE+: C595.2 C596.2 D3.1 D4.1 D27.1 R149.2 R324.2 T34.5 U65.18 | length 20.3
  L1 w0.254: R149.2@34.773,204.343 34.798,204.318 U65.18@36.92,204.318
  L16 w0.5: v6(27.345,228.551) C595.2@28.639,228.551 ; v6(28.639,229.845) C595.2@28.639,228.551 ; v6(29.932,228.551) C595.2@28.639,228.551 ; v6(35.686,223.896) D4.1@36.98,223.896 ; v6(36.98,225.19) D4.1@36.98,223.896 ; v6(38.274,223.896) D4.1@36.98,223.896 ; v6(45.554,223.832) D3.1@46.848,223.832 ; v6(46.848,222.539) D3.1@46.848,223.832 ; v6(46.848,225.126) D3.1@46.848,223.832 ; v6(48.141,223.832) D3.1@46.848,223.832 ; v6(48.998,226.657) R324.2@50.292,226.657 v6(50.292,227.951) ; v6(52.54,227.889) C596.2@52.54,226.595 v6(53.834,226.595)
VBB: C344.1 R257.1 U33.3 U33.4
VC1~: D3.4 T21.13 | length 21.6
  L16 w1: T21.13@40.432,251.716 44.386,247.762 44.386,235.194 D3.4@46.848,232.732
VC2~: D3.3 T21.14 | length 22.4
  L16 w1: T21.14@40.432,240.536 40.432,239.625 34.468,233.66 34.468,231.356 36.767,229.057 39.738,229.057 41.748,231.066 D3.3@41.748,232.732
VC3~: D4.4 T21.15 | length 22.8
  L16 w1: D4.4@36.98,232.796 36.98,233.601 42.608,239.23 42.608,245.567 38.972,249.203 T21.15@38.972,251.716
VC4~: D4.3 T21.16 | length 11.9
  L16 w1: D4.3@31.88,232.796 31.88,235.613 36.803,240.536 T21.16@38.972,240.536
Vcc_CLK_Mux_Fine: C326.2 C327.2 C328.2 C329.2 FB23.2 R250.1 R251.1 R259.1 R260.1 R386.1 R486.1 R488.2 U31.5 U32.5
VCCINT: C598.2 D26.2 R669.1 U65.4 U65.14 | length 8.4
  L1 w0.254: C598.2@37.846,208.912 38.26,208.498 U65.14@38.26,206.158 ; R669.1@38.887,200.831 39.26,201.204 U65.4@39.26,202.478
  L1 w0.5: D26.2@34.353,208.547 36.347,208.547 36.713,208.912 C598.2@37.846,208.912
VCCO_1: C398.2 R289.2 R293.2 R295.1 R296.1 U37.2 U37.4 U37.9 U37.32
VCCO_2: C439.2 R307.2 R310.2 R313.1 R314.1 U38.2 U38.4 U38.9 U38.32 | length 6.6
  L1 w0.254: R307.2@58.845,206.596 59.525,206.596 59.643,206.714 U38.4@61.453,206.714 ; C439.2@58.845,209.529 58.845,208.526 60.003,208.526 60.815,207.714 U38.2@61.453,207.714
VDD_APLL1: C88.1 C110.2 FB13.2 U16.49
VDD_APLL2: C89.1 C127.2 FB15.2 U16.37
VDD_CLK_MUX_DIV_3.3V: C336.2 C337.2 C338.2 C340.2 FB24.2 U33.1 U33.8 U33.9 U33.12
VDD_DIG: C93.1 C165.2 C590.2 FB21.2 FB37.1 R127.2 R128.1 R129.2 R366.1 R544.2 U16.8
VDD_IN0: C63.1 C101.2 FB8.2 U16.3
VDD_IN1: C64.1 C105.2 FB10.2 U16.16
VDD_IN2: C67.1 C109.2 FB12.2 U16.9
VDD_IN3: C70.1 C126.2 FB14.2 U16.4
VDD_TCXO: C92.1 C148.2 FB19.2 U16.19
VDD_XO: C90.1 C144.2 FB17.2 U16.42 | length 4.4
  L1 w0.2: U16.42@154.415,232.345 154.415,236.761
VDDO_0: C75.1 C143.2 FB16.2 U16.21
VDDO_1: C76.1 C147.2 FB18.2 U16.25
VDDO_6: C77.1 C164.2 FB20.2 U16.59
VDDO_7: C81.1 C180.2 FB22.2 U16.63
VDDO_23: C82.1 C102.2 FB9.2 U16.30
VDDO_45: C83.1 C106.2 FB11.2 U16.50
VLDO: C544.2 R383.2 U47.B4
  other v22: 134.329,335.804
Vout1_1: C406.2 C407.2 C408.2 C409.2 C410.2 C411.2 C412.2 C413.2 C414.2 C415.2 C416.2 C417.2 L11.2 R448_U_Pomiar_pradu_napiecia_3.1 U64_U_Pomiar_pradu_napiecia_3.10 | length 10.2
  L1 w0.3: R448_U_Pomiar_pradu_napiecia_3.1@107.759,180.301 107.759,181.902 108.017,182.159 U64_U_Pomiar_pradu_napiecia_3.10@116.278,182.159
Vout1_2: C447.2 C448.2 C449.2 C450.2 C451.2 C452.2 C453.2 C454.2 C455.2 C456.2 C457.2 C458.2 L19.2 R448_U_Pomiar_pradu_napiecia_5.1 U64_U_Pomiar_pradu_napiecia_5.10 | length 13
  L1 w0.2: R448_U_Pomiar_pradu_napiecia_5.1@102.092,213.587 103.898,215.393 U64_U_Pomiar_pradu_napiecia_5.10@114.348,215.393
Vout2_1: C418.2 C419.2 C420.2 C421.2 C422.2 C423.2 C424.2 C425.2 C426.2 C427.2 C428.2 C429.2 L12.2 R448_U_Pomiar_pradu_napiecia_4.1 U64_U_Pomiar_pradu_napiecia_4.10 | length 9.9
  L1 w0.5: R448_U_Pomiar_pradu_napiecia_4.1@106.904,164.438 106.904,165.228 107.579,165.903 115.778,165.903
Vout2_2: C459.2 C460.2 C461.2 C462.2 C463.2 C464.2 C465.2 C466.2 C467.2 C468.2 C469.2 C470.2
Vout_1_Selector: C4.1 C5.1 C6.1 C7.1 C8.2 C9.2 C10.2 C11.2 C20.2 C21.2 C22.2 C23.2 C24.2 C25.2 C26.2 C27.2 R15.2 U4.7 U5.1 U5.8 | length 39.1
  L1 w0.5: v1(39.961,163.667) C4.1@41.048,163.667 ; v1(39.961,164.772) C4.1@41.048,164.772 ; v1(39.961,165.868) C4.1@41.048,165.868 ; v1(39.961,167.121) C5.1@41.048,167.121 ; v1(39.961,168.226) C5.1@41.048,168.226 ; v1(39.961,169.323) C5.1@41.048,169.323 ; v1(39.961,170.575) C7.1@41.048,170.575 ; v1(39.961,171.68) C7.1@41.048,171.68 ; v1(39.961,172.777) C7.1@41.048,172.777 ; v1(39.961,174.03) C6.1@41.048,174.03 ; v1(39.961,175.135) C6.1@41.048,175.135 ; v1(39.961,176.232) C6.1@41.048,176.232 ; C4.1@41.048,164.215 v1(42.135,164.215) ; C4.1@41.048,165.32 v1(42.135,165.32) ; C5.1@41.048,167.669 v1(42.135,167.669) ; C5.1@41.048,168.774 v1(42.135,168.774) ; C7.1@41.048,171.124 v1(42.135,171.124) ; C7.1@41.048,172.229 v1(42.135,172.229) ; C6.1@41.048,174.578 v1(42.135,174.578) ; C6.1@41.048,175.683 v1(42.135,175.683) ; v1(53.932,163.773) C20.2@55.019,163.774 ; v1(53.932,164.497) C20.2@55.019,164.497 ; v1(53.959,166.505) C27.2@55.046,166.505 ; v1(53.959,168.403) C22.2@55.046,168.403 ; v1(53.959,170.301) C21.2@55.046,170.301 ; v1(53.959,172.199) C24.2@55.046,172.199 ; v1(53.959,174.096) C25.2@55.046,174.096 ; v1(53.959,175.994) C23.2@55.046,175.994 ; v1(53.959,165.781) C27.2@55.046,165.781 ; v1(53.959,167.679) C22.2@55.046,167.679 ; v1(53.959,169.577) C21.2@55.046,169.577 ; v1(53.959,171.475) C24.2@55.046,171.475 ; v1(53.959,173.373) C25.2@55.046,173.373 ; v1(53.959,175.27) C23.2@55.046,175.27 ; v1(53.989,177.168) C26.2@55.076,177.168 ; v1(53.989,177.892) C26.2@55.076,177.892
  other v6: 50.48,171.336 49.821,172.073 49.233,172.838 50.481,172.838 49.233,177.161 50.481,177.161 49.821,177.926 50.48,178.663 46.94,180.658 47.599,181.395 46.939,182.16 48.188,182.16
  other v17: 49.06,174.6 49.06,175.4 48.36,183.921
Vout_2_Selector: C12.1 C13.1 C14.1 C15.1 C16.2 C17.2 C18.2 C19.2 C28.2 C29.2 C30.2 C31.2 C32.2 C33.2 C34.2 C35.2 R677.2 R678.2 U4.1 U4.8 U48.7 | length 40.8
  L1 w0.5: v1(39.88,177.689) C12.1@40.967,177.689 ; v1(39.88,178.794) C12.1@40.967,178.794 ; v1(39.88,179.891) C12.1@40.967,179.891 ; v1(39.88,181.134) C15.1@40.967,181.134 ; v1(39.88,182.239) C15.1@40.967,182.239 ; v1(39.88,183.336) C15.1@40.967,183.336 ; v1(39.88,184.579) C13.1@40.967,184.579 ; v1(39.88,185.684) C13.1@40.967,185.684 ; v1(39.88,186.781) C13.1@40.967,186.781 ; v1(39.88,188.024) C14.1@40.967,188.024 ; v1(39.88,189.129) C14.1@40.967,189.129 ; v1(39.88,190.226) C14.1@40.967,190.226 ; C12.1@40.967,178.237 v1(42.054,178.237) ; C12.1@40.967,179.342 v1(42.054,179.342) ; C15.1@40.967,181.682 v1(42.054,181.682) ; C15.1@40.967,182.787 v1(42.054,182.787) ; C13.1@40.967,185.127 v1(42.054,185.127) ; C13.1@40.967,186.232 v1(42.054,186.232) ; C14.1@40.967,188.573 v1(42.054,188.573) ; C14.1@40.967,189.678 v1(42.054,189.678) ; v6(43.658,191.22) R678.2@43.658,192.033 ; v6(44.716,191.22) R677.2@44.716,192.033 ; v1(53.971,179.205) C31.2@55.058,179.205 ; v1(53.971,179.929) C31.2@55.058,179.929 ; v1(53.971,181.103) C30.2@55.058,181.103 ; v1(53.971,181.827) C30.2@55.058,181.827 ; v1(53.971,183.001) C32.2@55.058,183.001 ; v1(53.971,183.725) C32.2@55.058,183.725 ; v1(53.971,184.899) C29.2@55.058,184.899 ; v1(53.971,185.623) C29.2@55.058,185.623 ; v1(53.971,186.796) C28.2@55.058,186.796 ; v1(53.971,187.52) C28.2@55.058,187.52 ; v1(53.971,188.694) C33.2@55.058,188.694 ; v1(53.971,189.418) C33.2@55.058,189.418 ; v1(53.971,190.592) C34.2@55.058,190.592 ; v1(53.971,191.316) C34.2@55.058,191.316 ; v1(53.997,192.534) C35.2@55.084,192.534 ; v1(53.996,193.258) C35.2@55.083,193.258
  other v6: 50.48,180.658 49.821,181.395 49.233,182.16 50.481,182.16 49.233,186.483 50.481,186.483 49.821,187.248 50.48,187.985 46.907,190.32 47.566,191.057 46.906,191.822 48.155,191.821
  other v17: 49.06,183.921 49.06,184.721 48.327,193.583
Vout_5V@10A_INA: L20.2 R448_U_Pomiar_pradu_napiecia_6.1 U64_U_Pomiar_pradu_napiecia_6.10 | length 10.8
  L1 w0.2: R448_U_Pomiar_pradu_napiecia_6.1@100.635,196.76 102.383,198.508 U64_U_Pomiar_pradu_napiecia_6.10@110.741,198.508
VPHY_FTDI: C661.2 C662.2 FB44.2 U55.4
VPLL_FTDI: C659.2 C660.2 FB43.2 U55.9
VREF+_1: C61.2 C62.2 FB3.2 U12.44 | length 4.4
  L16 w0.12: U12.44@96.597,335.311 97.8,335.311 99.751,337.261 99.979,337.49 v1(100.114,337.49)
VREF+_2: C73.2 C74.2 FB5.2 U13.44
VREF+_3: C57.2 C58.2 FB2.2
VSD_REF: R911.2 U47.C4
  other v22: 134.329,335.404
VVCO+_1: C86.2 C87.2 FB6.2 U12.39 | length 1.7
  L16 w0.12: U12.39@95.447,337.461 95.447,338.767 v1(95.745,339.065)
VVCO+_2: C97.2 C98.2 FB7.2 U13.39
VVCO+_3: C68.2 C69.2 FB4.2
WR_LMK_CLK_HF1_N: C728.2 R1086.2 U16.26 | length 111.1
  L1 w0.081: U16.26@159.565,228.695 159.863,228.695 cw(c159.863,228.653) 159.906,228.653 v13(161.137,228.653) ; R1086.2@204.354,288.544 204.574,288.544 cw(c204.574,288.373) 204.745,288.373 205.099,288.373 ccw(c205.099,288.417) 205.144,288.417 C728.2@205.454,288.417 205.667,288.417 cw(c205.667,288.32) 205.765,288.32 v13(206.177,288.32)
  L5 (Sign) w0.073: v13(161.137,228.653) cw(c161.33,228.653) 161.33,228.846 163.338,228.846 ccw(c163.338,229.58) 164.073,229.58 164.073,254.606 cw(c164.833,254.606) 164.833,255.367 195.445,255.367 ccw(c195.445,257.315) 197.392,257.315 197.392,266.346 cw(c198.343,266.346) 198.343,267.297 208.082,267.297 ccw(c208.082,268.141) 208.926,268.141 208.926,287.468 ccw(c208.267,287.468) 208.267,288.127 206.37,288.127 cw(c206.37,288.32) v13(206.177,288.32)
WR_LMK_CLK_HF1_P: C728.1 R1085.2 U16.27 | length 110.5
  L1 w0.081: U16.27@159.565,229.195 159.863,229.195 ccw(c159.863,229.238) 159.906,229.238 v13(161.137,229.238) ; R1085.2@204.354,287.617 204.574,287.617 ccw(c204.574,287.788) 204.745,287.788 205.144,287.788 ccw(c205.294,287.788) 205.294,287.637 C728.1@205.454,287.637 205.667,287.637 ccw(c205.667,287.735) 205.765,287.735 v13(206.177,287.735)
  L5 (Sign) w0.073: v13(161.137,229.238) ccw(c161.33,229.238) 161.33,229.045 163.338,229.045 ccw(c163.338,229.58) 163.873,229.58 163.873,254.606 cw(c164.833,254.606) 164.833,255.566 195.445,255.566 ccw(c195.445,257.315) 197.193,257.315 197.193,266.346 cw(c198.343,266.346) 198.343,267.496 208.082,267.496 ccw(c208.082,268.141) 208.727,268.141 208.727,287.468 ccw(c208.267,287.468) 208.267,287.927 206.37,287.927 ccw(c206.37,287.735) v13(206.177,287.735)
WR_LMK_CLK_HF2_N: C793.1 R1088.2 U16.32 | length 84.9
  L1 w0.081: v13(153.021,299.664) 153.575,299.664 cw(c153.673,299.664) 153.673,299.761 C793.1@153.886,299.761 154.067,299.761 cw(c154.067,299.632) 154.196,299.632 154.813,299.632 ccw(c154.813,299.756) 154.936,299.756 cw(c155.075,299.756) R1088.2@154.977,299.854 ; U16.32@159.565,231.695 159.863,231.695 ccw(c159.863,231.738) 159.906,231.738 v13(160.952,231.738)
  L5 (Sign) w0.073: v13(153.021,299.664) 153.021,299.635 cw(c152.857,299.635) 152.857,299.471 ccw(c152.857,298.941) 152.327,298.941 152.327,289.7 ccw(c155.065,289.7) 153.129,287.764 155.515,285.378 cw(c153.867,283.731) 156.197,283.731 156.197,282.196 cw(c153.657,282.196) 155.453,280.4 154.374,279.321 ccw(c156.309,277.385) 153.572,277.385 153.572,258.432 ccw(c154.575,258.432) 154.575,257.429 162.408,257.429 cw(c162.408,257.035) 162.801,257.035 162.801,231.826 cw(c162.521,231.826) 162.521,231.545 161.145,231.545 cw(c161.145,231.738) v13(160.952,231.738)
WR_LMK_CLK_HF2_P: C793.2 R1087.2 U16.31 | length 84.8
  L1 w0.081: v13(153.021,299.078) 153.575,299.078 ccw(c153.673,299.078) 153.673,298.981 C793.2@153.886,298.981 154.196,298.981 cw(c154.262,298.981) 154.262,299.047 154.813,299.047 cw(c154.813,298.923) 154.936,298.923 ccw(c155.075,298.923) R1087.2@154.977,298.825 ; U16.31@159.565,231.195 159.863,231.195 cw(c159.863,231.153) 159.906,231.153 v13(160.952,231.153)
  L5 (Sign) w0.073: v13(153.021,299.078) 153.021,299.107 ccw(c152.857,299.107) 152.857,299.271 ccw(c152.857,298.941) 152.527,298.941 152.527,289.701 ccw(c155.067,289.701) 153.271,287.905 155.659,285.517 cw(c153.877,283.735) 156.397,283.735 156.397,282.195 cw(c153.66,282.195) 155.595,280.26 154.516,279.18 ccw(c156.312,277.384) 153.772,277.384 153.772,258.432 ccw(c154.575,258.432) 154.575,257.629 162.408,257.629 cw(c162.408,257.035) 163.001,257.035 163.001,231.826 cw(c162.521,231.826) 162.521,231.346 161.145,231.346 ccw(c161.145,231.153) v13(160.952,231.153)
WR_LMK_CLK_HF3_N: U16.33
WR_LMK_CLK_HF3_P: U16.34
WR_LMK_CLK_HF4_N: U16.52
WR_LMK_CLK_HF4_P: U16.51
WR_LMK_CLK_HF5_N: U16.53
WR_LMK_CLK_HF5_P: U16.54
WR_LMK_CLK_HF6_N: U16.58
WR_LMK_CLK_HF6_P: U16.57
WR_LMK_CLK_HF7_N: U16.61
WR_LMK_CLK_HF7_P: U16.62
WR_LMK_CLK_IN_N: R311.1 R1084.2 U16.2 | length 115
  L1 w0.081: U16.2@151.915,223.545 151.915,223.247 ccw(c151.958,223.247) 151.958,223.205 v13(151.958,222.364) ; R1084.2@207.034,273.253 207.247,273.253 ccw(c207.247,273.43) 207.424,273.43 207.592,273.43 cw(c207.592,273.273) 207.749,273.273 R311.1@208.089,273.273 208.273,273.273 ccw(c208.273,273.43) 208.43,273.43 v13(209.436,273.43)
  L5 (Sign) w0.073: v13(151.958,222.364) ccw(c151.958,222.171) 151.765,222.171 151.765,221.335 ccw(c152.107,221.335) 152.107,220.993 163.246,220.993 ccw(c163.246,222.529) 164.782,222.529 164.782,253.628 cw(c165.494,253.628) 165.494,254.339 197.474,254.339 ccw(c197.474,255.46) 198.595,255.46 198.595,265.724 cw(c199.276,265.724) 199.276,266.404 209.431,266.404 ccw(c209.431,267.133) 210.16,267.133 210.16,273.397 ; v13(209.436,273.43) cw(c209.629,273.43) 209.629,273.623 209.78,273.623 cw(c209.78,273.244) 210.16,273.244
WR_LMK_CLK_IN_P: R311.2 R1083.2 U16.1 | length 116
  L1 w0.081: v13(151.372,222.364) 151.372,223.205 ccw(c151.372,223.247) 151.415,223.247 U16.1@151.415,223.545 ; R1083.2@207.034,274.193 207.247,274.193 cw(c207.247,274.016) 207.424,274.016 207.749,274.016 cw(c207.906,274.016) 207.906,274.173 R311.2@208.089,274.173 208.273,274.173 cw(c208.273,274.016) 208.43,274.016 v13(209.436,274.016)
  L5 (Sign) w0.073: v13(151.372,222.364) cw(c151.372,222.171) 151.565,222.171 151.565,221.335 ccw(c152.107,221.335) 152.107,220.793 163.246,220.793 ccw(c163.246,222.529) 164.982,222.529 164.982,253.628 cw(c165.494,253.628) 165.494,254.14 197.474,254.14 ccw(c197.474,255.46) 198.795,255.46 198.795,265.724 cw(c199.276,265.724) 199.276,266.205 209.431,266.205 ccw(c209.431,267.133) 210.359,267.133 210.359,273.397 ; v13(209.436,274.016) ccw(c209.629,274.016) 209.629,273.823 209.78,273.823 cw(c209.78,273.244) 210.359,273.244
WR_LMK_CLK_LF_N: U16.14 U16.23 | length 14.6
  L1 w0.081: v13(157.872,222.402) 157.872,223.205 ccw(c157.872,223.247) 157.915,223.247 U16.14@157.915,223.545 ; U16.23@159.565,227.195 159.863,227.195 ccw(c159.863,227.238) 159.906,227.238 v13(160.642,227.238)
  L5 (Sign) w0.073: v13(157.872,222.402) cw(c157.872,222.21) 158.065,222.21 158.065,222.135 ccw(c158.442,222.135) 158.442,221.758 162.281,221.758 ccw(c162.281,222.288) 162.81,222.288 162.81,226.339 ccw(c162.105,226.339) 162.105,227.045 160.835,227.045 cw(c160.835,227.238) v13(160.642,227.238)
WR_LMK_CLK_LF_P: U16.15 U16.22 | length 14.6
  L1 w0.081: U16.15@158.415,223.545 158.415,223.247 ccw(c158.458,223.247) 158.458,223.205 v13(158.458,222.402) ; U16.22@159.565,226.695 159.863,226.695 cw(c159.863,226.653) 159.906,226.653 v13(160.642,226.653)
  L5 (Sign) w0.073: v13(158.458,222.402) ccw(c158.458,222.21) 158.265,222.21 158.265,222.135 ccw(c158.442,222.135) 158.442,221.958 159.182,221.958 161.124,221.958 ccw(c161.124,222.044) 161.21,222.044 161.21,222.068 cw(c161.295,222.068) 161.295,222.154 161.552,222.154 cw(c161.552,222.068) 161.638,222.068 161.638,222.044 ccw(c161.724,222.044) 161.724,221.958 162.066,221.958 162.281,221.958 ccw(c162.281,222.288) 162.611,222.288 162.611,222.631 ccw(c162.544,222.631) 162.544,222.698 cw(c162.544,222.784) 162.458,222.784 162.458,223.041 cw(c162.544,223.041) 162.544,223.126 ccw(c162.544,223.193) 162.611,223.193 162.611,223.488 ccw(c162.544,223.488) 162.544,223.555 cw(c162.544,223.641) 162.458,223.641 162.458,223.898 cw(c162.544,223.898) 162.544,223.983 ccw(c162.544,224.05) 162.611,224.05 162.611,224.345 ccw(c162.544,224.345) 162.544,224.412 cw(c162.544,224.497) 162.458,224.497 162.458,224.754 cw(c162.544,224.754) 162.544,224.84 ccw(c162.544,224.907) 162.611,224.907 162.611,225.202 ccw(c162.544,225.202) 162.544,225.268 cw(c162.544,225.354) 162.458,225.354 162.458,225.611 cw(c162.544,225.611) 162.544,225.697 ccw(c162.544,225.764) 162.611,225.764 162.611,226.125 162.611,226.339 ccw(c162.105,226.339) 162.105,226.846 160.835,226.846 ccw(c160.835,226.653) v13(160.642,226.653)
WR_LMK_CLK_RC_HF1_N: C729.1 R1086.1 U1.AJ1 | length 14.9
  L1 w0.081: v2(201.358,288.345) 202.115,288.345 cw(c202.212,288.345) 202.212,288.442 C729.1@202.425,288.442 202.639,288.442 cw(c202.639,288.345) 202.736,288.345 203.063,288.345 cw(c203.263,288.345) 203.263,288.544 R1086.1@203.454,288.544
  L1 w0.116: U1.AJ1@190.397,288.539 v2(190.884,289.027)
  L3 (Sign) w0.076: v2(190.884,289.027) 190.716,289.027 ccw(c190.716,288.779) 190.468,288.779 ccw(c191.057,288.779) 191.057,288.19 192.345,288.19 ccw(c192.345,288.242) 192.397,288.242
  L3 (Sign) w0.08: 192.397,288.242 201.256,288.242 ccw(c201.256,288.345) v2(201.358,288.345)
WR_LMK_CLK_RC_HF1_P: C729.2 R1085.1 U1.AJ2 | length 15.2
  L1 w0.081: v2(201.358,287.759) 202.115,287.759 ccw(c202.212,287.759) 202.212,287.662 C729.2@202.425,287.662 202.639,287.662 ccw(c202.639,287.759) 202.736,287.759 202.944,287.759 cw(c202.944,287.64) 203.063,287.64 ccw(c203.087,287.64) 203.087,287.617 R1085.1@203.454,287.617
  L1 w0.116: v2(189.909,289.052) U1.AJ2@190.397,289.539
  L3 (Sign) w0.076: v2(189.909,289.052) 189.919,289.052 cw(c189.919,288.779) 190.192,288.779 ccw(c191.057,288.779) 191.057,287.914 192.345,287.914 cw(c192.345,287.862) 192.397,287.862
  L3 (Sign) w0.08: 192.397,287.862 201.256,287.862 cw(c201.256,287.759) v2(201.358,287.759)
WR_LMK_CLK_RC_HF2_N: C730.1 R1088.1 U1.C17 | length 11.9
  L1 w0.081: R1088.1@155.877,299.854 156.046,299.854 cw(c156.046,299.632) 156.268,299.632 156.578,299.632 cw(c156.707,299.632) 156.707,299.761 C730.1@156.889,299.761 157.102,299.761 cw(c157.102,299.664) 157.199,299.664 157.69,299.664 ccw(c157.69,300.105) 158.132,300.105 158.132,301.1 cw(c158.2,301.1) v2(158.2,301.168)
  L1 w0.116: v2(163.909,304.052) U1.C17@164.397,304.539
  L3 (Sign) w0.076: 161.345,303.742 cw(c161.345,303.69) 161.397,303.69 163.779,303.69 ccw(c163.779,303.82) 163.909,303.82 v2(163.909,304.052)
  L3 (Sign) w0.08: v2(158.2,301.168) 158.235,301.203 158.235,301.246 cw(c159.329,301.246) 158.555,302.02 160.167,303.632 cw(c160.433,303.366) 160.433,303.742 161.345,303.742
WR_LMK_CLK_RC_HF2_P: C730.2 R1087.1 U1.B16 | length 12.2
  L1 w0.081: R1087.1@155.877,298.825 156.046,298.825 ccw(c156.046,299.047) 156.268,299.047 156.513,299.047 cw(c156.513,298.981) 156.578,298.981 C730.2@156.889,298.981 157.102,298.981 ccw(c157.102,299.078) 157.199,299.078 157.69,299.078 ccw(c157.69,300.105) 158.717,300.105 158.717,301.1 ccw(c158.65,301.1) v2(158.65,301.168)
  L1 w0.116: U1.B16@163.397,303.539 v2(163.884,303.052)
  L3 (Sign) w0.076: 161.345,303.362 ccw(c161.345,303.414) 161.397,303.414 163.779,303.414 cw(c163.779,303.309) 163.884,303.309 v2(163.884,303.052)
  L3 (Sign) w0.08: v2(158.65,301.168) 158.614,301.203 158.614,301.244 cw(c159.335,301.244) 158.825,301.753 160.434,303.362 161.345,303.362
X1: C481.2 R335.2 U39.14 X4.1 | length 15.5
  L16 w0.12: C481.2@96.15,288.662 96.497,289.01 X4.1@97.67,289.01 98.47,289.01 98.87,288.61 R335.2@98.87,286.117 98.87,285.356 100.025,284.201 103.314,284.201 104.114,283.4 105.615,283.4 106.049,282.966 U39.14@106.049,281.925
X2: C480.2 R335.1 U39.15 X4.3 | length 12.9
  L16 w0.12: C480.2@101.403,287.959 101.403,287.949 100.964,287.51 X4.3@99.77,287.51 R335.1@99.77,286.117 99.77,285.399 100.476,284.693 103.507,284.693 104.276,283.925 105.838,283.925 106.549,283.214 U39.15@106.549,281.925
XO_LMK05028_P: C589.2 U16.43 | length 5.4
  L1 w0.086: C589.2@153.67,237.664 153.67,236.715 153.915,236.47 U16.43@153.915,232.345
pads on no net: C558.4 D28.1 J1_PCIE0.48 J1_PCIE0.50 J1_PCIE1.48 J1_PCIE1.50 J1_PCIE2.48 J1_PCIE2.50 J1_PCIE3.48 J1_PCIE3.50 J1_PCIE4.48 J1_PCIE4.50 J14.3 J27.5 J27.6 J27.7 J27.8 J27.11 J27.13 J27.17 J27.19 J27.20 J27.22 J27.23 J27.24 J27.25 J27.26 J27.28 J27.30 J27.32 J27.34 J27.36 J27.40 J27.42 J27.44 J27.46 J27.48 J27.56 J27.58 J27.59 J28.MH1 J28.MH2 J32. J33. J34. J35. P12.13 R867.2 R868.2 R869.2 R870.2 R883.2 R884.2 R885.2 R886.2 R980.2 R981.2 R982.2 R983.2 R984.2 R985.2 R986.2 R987.2 R988.2 R989.2 R990.2 R991.2 R992.2 R993.2 R994.2 R995.2 R996.2 R997.2 R998.2 R999.2 R1000.2 R1004.2 R1005.2 R1006.2 R1007.2 R1008.2 R1009.2 R1010.2 R1011.2 R1012.2 R1013.2 R1014.2 R1015.2 R1016.2 R1017.2 R1018.2 R1019.2 R1020.2 R1021.2 R1022.1 R1023.2 R1024.1 R1025.2 R1035.2 T21.MH1 T21.MH2 U1.A15 U1.AA8 U1.AA17 U1.AA26 U1.AA30 U1.AB5 U1.AB6 U1.AB8 U1.AB18 U1.AB19 U1.AB20 U1.AB21 U1.AB29 U1.AC7 U1.AC8 U1.AC13 U1.AC19 U1.AD7 U1.AD17 U1.AE3 U1.AE7 U1.AE10 U1.AE12 U1.AE17 U1.AF1 U1.AF2 U1.AF5 U1.AF6 U1.AF11 U1.AF12 U1.AF13 U1.AF15 U1.AF16 U1.AF17 U1.AG5 U1.AG6 U1.AG8 U1.AG9 U1.AG11 U1.AG14 U1.AG15 U1.AG19 U1.AH1 U1.AH4 U1.AH6 U1.AH7 U1.AH8 U1.AH11 U1.AH12 U1.AH14 U1.AJ6 U1.AJ7 U1.AJ12 U1.AJ27 U1.AK2 U1.AK3 U1.B15 U1.C13 U1.D14 U1.D15 U1.D17 U1.E12 U1.E13 U1.E14 U1.E15 U1.E17 U1.F12 U1.F13 U1.F15 U1.F16 U1.G13 U1.G15 U1.G16 U1.J15 U1.K14 U1.K15 U1.L14 U1.L15 U1.L25 U1.L26 U1.W9 U1.W10 U1.W26 U1.W27 U1.Y1 U1.Y9 U1.Y27 U1.Y29 U1.Y30 U8.T4 U9.T4 U10.T4 U11.T4 U13.42 U16.5 U16.6 U16.10 U16.11 U16.18 U30.6 U30.7 U30.8 U31.3 U31.4 U31.8 U31.13 U31.14 U31.15 U31.16 U32.8 U32.13 U32.14 U32.15 U32.16 U33.7 U35_I2C_Expander_00.7 U35_I2C_Expander_00.10 U35_I2C_Expander_01.7 U35_I2C_Expander_01.10 U35_I2C_Expander_02.7 U35_I2C_Expander_02.10 U35_I2C_Expander_10.7 U35_I2C_Expander_10.10 U35_I2C_Expander_11.7 U35_I2C_Expander_11.10 U35_I2C_Expander_12.7 U35_I2C_Expander_12.10 U35_I2C_Expander_Main_Rst.7 U35_I2C_Expander_Main_Rst.10 U35_I2C_Expander_PWR_CLK.7 U35_I2C_Expander_PWR_CLK.10 U35_I2C_Expander_PWR_Dist.7 U35_I2C_Expander_PWR_Dist.10 U35_I2C_Expander_SFP.7 U35_I2C_Expander_SFP.10 U39.18 U39.25 U39.26 U39.29 U39.32 U39.37 U39.38 U39.40 U40.6 U41.A1 U41.A2 U41.A7 U41.A8 U41.A9 U41.A10 U41.A11 U41.A12 U41.A13 U41.A14 U41.B1 U41.B7 U41.B8 U41.B9 U41.B10 U41.B11 U41.B12 U41.B13 U41.B14 U41.C1 U41.C3 U41.C5 U41.C7 U41.C8 U41.C9 U41.C10 U41.C11 U41.C12 U41.C13 U41.C14 U41.D1 U41.D2 U41.D3 U41.D4 U41.D12 U41.D13 U41.D14 U41.E1 U41.E2 U41.E3 U41.E5 U41.E8 U41.E9 U41.E10 U41.E12 U41.E13 U41.E14 U41.F1 U41.F2 U41.F3 U41.F10 U41.F12 U41.F13 U41.F14 U41.G1 U41.G2 U41.G3 U41.G10 U41.G12 U41.G13 U41.G14 U41.H1 U41.H2 U41.H3 U41.H5 U41.H12 U41.H13 U41.H14 U41.J1 U41.J2 U41.J3 U41.J12 U41.J13 U41.J14 U41.K1 U41.K2 U41.K3 U41.K6 U41.K7 U41.K10 U41.K12 U41.K13 U41.K14 U41.L1 U41.L2 U41.L3 U41.L12 U41.L13 U41.L14 U41.M1 U41.M2 U41.M3 U41.M7 U41.M8 U41.M9 U41.M10 U41.M11 U41.M12 U41.M13 U41.M14 U41.N1 U41.N3 U41.N6 U41.N7 U41.N8 U41.N9 U41.N10 U41.N11 U41.N12 U41.N13 U41.N14 U41.P1 U41.P2 U41.P7 U41.P8 U41.P9 U41.P10 U41.P11 U41.P12 U41.P13 U41.P14 U42.6 U44.8 U44.9 U45.12 U45.15 U45.16 U46.B3 U46.C4 U47.E2 U47.E4 U55.36 U55.60 U58.10 U58.11 U59_5V_to_3V3_for_FTDI.6 U59_U_5V_to_3V31.6 U59_U_5V_to_3V32.6 U59_U_5V_to_3V33.6 U60.8 U63.5 U65.1 U69.8 U73.3 U78.3 U78.4
copper on no net: | length 10.8
  L1 w0.116: 182.909,292.052 183.397,292.539 ; 182.909,293.052 183.397,293.539 ; 186.909,300.052 187.397,300.539 ; 206.324,342.392 v3(206.728,342.796) ; 211.541,342.801 211.938,342.405 v2(211.938,342.402) ; 370.718,242.339 v2(371.408,242.339) ; 374.352,239.977 v5(374.839,240.464) ; 374.809,249.091 v4(375.296,249.579) ; 376.803,243.901 v2(377.29,244.389)
  L1 w0.254: 58.826,204.716 59.784,204.716 60.282,205.214 61.453,205.214
  L5 (Sign) w0.116: v29(371.685,243.799) v29(372.706,242.779)
  L3 (Sign) w0.092: 212.405,343.017 v11(212.801,342.621)
  other v3: 195.377,344.081
  other v4: 46.145,775.697 49.078,775.697
  other v5: 181.397,288.539
  other v8: 432.41,144.308 420.332,144.31 426.39,144.335 408.8,144.805 436.27,149.708 412.902,150.025 425.945,150.05 419.456,150.368 406.07,150.482 363.601,171.336 370.967,171.336 377.901,171.336 385.267,171.336 392.633,171.336 399.986,171.336 407.352,171.336 414.719,171.336 422.084,171.336 429.45,171.336 436.816,171.336 443.738,171.336 451.104,171.336 458.47,171.336 465.836,171.336 473.202,171.336 480.555,171.336 487.921,171.336 495.287,171.336 502.653,171.336 510.019,171.336 517.385,171.336 424.548,180.556 486.004,180.556 516.725,180.556 546.189,180.556 576.91,180.556 607.631,180.556 638.111,180.556 668.833,180.556 698.284,180.556 727.748,180.556 757.199,180.556 786.651,180.556 816.115,180.556 845.566,180.556 875.03,180.556 396.837,182.689 458.445,183.172 412.026,189.916 363.106,190.792 393.827,190.792 424.548,190.792 455.282,190.792 486.004,190.792 516.725,190.792 546.189,190.792 576.91,190.792 607.631,190.792 638.111,190.792 668.833,190.792 698.284,190.792 727.748,190.792 757.199,190.792 786.651,190.792 816.115,190.792 845.566,190.792 875.03,190.792 471.614,197.193 372.58,198.709 392.557,201.028 422.008,201.028 480.924,201.028 510.375,201.028 538.569,201.028 568.02,201.028 597.484,201.028 626.682,201.028 656.133,201.028 684.327,201.028 712.508,201.028 740.689,201.028 768.883,201.028 797.065,201.028 825.259,201.028 853.44,201.028 394.081,211.264 425.056,211.264 456.044,211.264 487.02,211.264 517.995,211.264 548.983,211.264 579.958,211.264 610.933,211.264 641.668,211.264 396.875,221.501 414.325,225.006 415.887,238.595 318.376,241.186 315.887,253.987 291.516,475.577 286.55,477.545 292.138,481.889 310.299,484.721 282.943,484.886 304.775,485.33 291.122,487.426 282.651,489.623 299.022,490.918 282.88,494.703 290.271,494.982 313.512,496.341 301.447,496.564 307.416,496.786
  other v24: 170.237,267.894 252.59,267.894 62.485,362.892 144.837,362.892 227.19,362.892
  other v25: 145.237,267.894 227.59,267.894 87.485,362.892 169.837,362.892 252.19,362.892
  other v33: 375.296,249.579

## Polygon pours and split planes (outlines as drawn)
5V_RAIL on L1 "L1-3V3_RAIL" (solid, pour order 263): 100.266,199.987 106.921,199.987 107.481,200.546 107.481,203.009 106.286,204.203 94.818,204.203 93.408,202.794 93.408,200.406 93.815,200 100.33,200
Vout_5V@10A_INA on L1 "L1-Vout_5V@10A_INA" (solid, pour order 249): 92.405,200.584 94.996,197.993 108.153,197.993 110.045,196.101 110.045,193.205 109.828,192.987 89.918,192.987 87.816,195.089 87.816,199.136 89.264,200.584
0.85V@40A_INA on L1 "0.85V@40A_INA_L01_P113" (solid, pour order 113): 130.202,304.332 127.457,301.587 127.457,290.055 130.149,287.363 137.2,287.363 137.746,287.91 137.735,287.92 137.735,303.785 137.189,304.332
RAM_Vcc1V2 on L1 "L1-3V3_RAIL" (solid, pour order 261): 106.536,167.665 113.19,167.665 113.75,168.225 113.75,170.687 112.555,171.882 101.087,171.882 99.678,170.472 99.678,168.084 100.084,167.678 106.599,167.678
NetC674_2 on L1 "L1-NetC674_2" (solid, pour order 302): 128.613,238.074 128.613,236.766 128.75,236.629 129.591,236.629 129.807,236.413 129.807,234.95 130.018,234.739 131.78,234.739 132.702,235.661 132.702,238.557 132.626,238.633 129.172,238.633
NetD18_1 on L1 "NETD18_1_L01_P284" (solid, remove dead copper, pour order 284): 165.413,175.061 162.592,175.061 161.281,176.372 161.206,176.372 158.311,176.372 158.311,179.008 166.738,179.008 169.406,176.339 169.406,173.573 170.547,172.432 170.547,170.872 172.231,170.872 172.278,170.825 172.278,170.575 169.766,170.575 166.724,173.617 166.724,173.749
NetD18_2 on L1 "NETD18_2_L01_P285" (solid, remove dead copper, pour order 285): 170.041,175.704 170.041,173.315 170.847,172.509 170.847,171.1 172.253,171.1 172.253,172.278 171.578,172.953 171.578,175.704
NetD17_2 on L1 "NETD17_2_L01_P286" (solid, remove dead copper, pour order 286): 166.741,171.335 168.425,171.335 169.361,170.398 172.278,170.398 172.278,170.075 171.578,170.075 171.568,170.065 166.741,170.065
NetD17_1 on L1 "NETD17_1_L01_P287" (solid, remove dead copper, pour order 287): 161.206,169.43 160.994,169.218 153.669,169.218 153.669,171.97 166.106,171.97 166.106,170.185 166.466,169.825 172.278,169.825 172.278,169.575 170.672,169.575 170.527,169.43
NetD16_1 on L1 "NETD16_1_L01_P288" (solid, remove dead copper, pour order 288): 153.669,168.476 165.488,168.476 166.424,169.2 170.696,169.2 170.821,169.325 172.278,169.325 172.278,169.075 171.578,169.075 171.461,168.957 170.979,168.957 170.913,168.89 167.651,168.89 166.106,167.346 166.106,165.543 162.84,165.543 153.719,165.543
NetD16_2 on L1 "NETD16_2_L01_P289" (solid, remove dead copper, pour order 289): 166.741,166.178 167.503,166.178 169.658,168.333 170.758,168.333 171,168.575 172.278,168.575 172.278,168.825 171.578,168.825 170.989,168.824 170.696,168.575 168.062,168.575 166.741,167.448
NetD19_1 on L1 "NETD19_1_L01_P290" (solid, remove dead copper, pour order 290): 169.572,163.299 169.572,160.759 168.306,159.493 165.636,159.493 164.418,159.493 164.418,159.043 164.118,158.743 161.768,158.743 159.168,158.743 159.168,159.443 159.118,159.493 159.118,161.393 160.321,161.393 162.062,163.133 166.574,163.133 168.191,164.751 168.588,165.433 169.522,167.524 170.073,168.075 170.804,168.075 171.054,168.325 172.278,168.325 172.278,168.075 171.578,168.075 171.22,168.074 170.274,167.119 170.274,164.001
NetD19_2 on L1 "NETD19_2_L01_P291" (solid, remove dead copper, pour order 291): 172.278,167.825 171.378,167.825 170.6,167.047 170.6,163.709 170.041,163.151 170.041,161.228 170.803,161.228 170.803,162.498 171.568,163.263 171.568,166.865 172.278,167.575
NetC612_1 on L1 "NETC612_1_L01_P292" (solid, remove dead copper, pour order 292): 178.768,173.015 181.35,173.015 181.35,172.14 181.346,172.144 177.822,172.144 176.753,171.075 175.378,171.075 175.378,171.325 176.303,171.325 177.98,173.003
NetC605_1 on L1 "NETC605_1_L01_P293" (solid, remove dead copper, pour order 293): 183.234,171.15 178.155,171.15 177.58,170.575 175.378,170.575 175.378,170.825 177.205,170.825 178.23,171.85 183.234,171.85
NetC603_1 on L1 "NETC603_1_L01_P294" (solid, remove dead copper, pour order 294): 183.234,170.625 183.227,170.617 178.093,170.617 177.8,170.325 175.378,170.325 175.378,170.075 181.527,170.075 181.684,169.917 181.691,169.925 183.234,169.925
NetC616_1 on L1 "NETC616_1_L01_P295" (solid, remove dead copper, pour order 295): 181.25,168.994 181.25,169.694 178.049,169.69 177.822,169.825 177.73,169.825 175.378,169.825 175.378,169.575 177.122,169.575 177.702,168.994
US+_MGTVccAux on L1 "US+_MGTVCCAUX_L01_P296" (solid, remove dead copper, pour order 296): 150.725,176.047 153.253,176.047 153.58,176.373 153.58,177.183 155.861,177.183 155.9,177.144 155.9,175.942 156.05,175.792 159.919,175.792 159.919,173.417 159.969,173.367 152.115,173.367 151.475,174.008 151.475,174.608 151.064,174.608 150.725,174.946
ADP1741_3.6V on L1 "ADP1741_3.6V_L01_P297" (solid, remove dead copper, pour order 297): 149.356,164.301 149.381,164.326 159.969,164.326 159.969,162.176 154.782,162.176 154.22,161.613 154.22,161.013 149.356,161.013
US+_Vcc_PS_DDR_504 on L1 "US+_VCC_PS_DDR_504_L01_P298" (solid, remove dead copper, pour order 298): 158.996,157.871 159.118,157.993 164.606,157.993 165.269,157.33 166.551,157.33 166.551,156.881 165.763,156.093 164.418,156.093 164.418,155.924 163.975,155.48 163.975,153.078 157.165,153.078 156.129,154.114 156.129,157.871
ETH_VDDIO on L1 "ETH_VDDIO_L01_P299" (solid, remove dead copper, pour order 299): 158.243,180.539 158.243,185.622 166.449,185.622 166.674,185.397 166.674,180.238 166.308,179.872 158.911,179.872
12V_LT3042 on L1 "12V_LT3042_L01_P300" (solid, remove dead copper, pour order 300): 172.103,164.915 172.104,164.914 174.366,164.914 174.403,164.952 174.403,165.939 174.204,165.939 173.703,166.44 173.703,167.4 172.453,167.4 172.103,167.05
12V_LT3042 on L1 "12V_LT3042_L01_P301" (solid, remove dead copper, pour order 301): 171.828,174.057 174.153,174.057 174.727,174.631 174.727,175.178 175.968,175.178 175.978,175.168 175.978,174.648 175.809,174.648 175.203,174.042 175.203,173.192 174.57,173.192 173.578,172.2 173.578,171.625 173.703,171.5 172.453,171.5 172.441,172.2
SW2_1 on L1 "L1-SW2_1" (solid, pour order 199): 81.298,174.135 83.515,176.352 85.649,176.352 86.39,175.611 86.39,173.63 88.405,171.615 88.405,163.639 85.458,160.693 80.519,160.693 80.519,160.705 78.842,162.382 78.842,167.589 78.308,168.123 75.806,168.123 74.924,169.005 74.924,173.647 75.412,174.135
SW1_1 on L1 "L1-SW1_1" (solid, pour order 195): 78.661,189.37 81.455,192.164 84.112,192.164 85.052,191.224 85.052,188.316 88.405,184.963 88.405,178.905 86.398,176.898 83.145,176.898 79.629,176.898 78.943,177.584 78.943,182.601 78.715,182.829 76.057,182.829 75.311,183.576 75.311,188.341 76.34,189.37
SW2_2 on L1 "L1-SW2_2" (solid, pour order 193): 76.53,204.802 84.863,204.802 86.716,202.949 86.716,194.412 85.407,193.103 80.099,193.103 79.642,193.561 79.642,198.171 79.21,198.603 77.127,198.603 76.086,199.644 76.086,204.357
SW1_2 on L1 "L1-SW1_2" (solid, pour order 191): 81.128,218.415 79.616,216.903 79.616,213.618 79.237,213.239 77.361,213.239 76.276,212.153 76.276,206.375 76.556,206.096 81.946,206.096 82.628,206.778 82.628,208.421 83.041,208.833 84.861,208.833 86.271,207.424 86.271,206.605 86.915,205.962 90.794,205.962 91.421,206.589 91.421,209.055 89.935,210.541 89.027,210.541 87.516,212.052 87.516,217.018 86.119,218.415
SW1 on L1 "SW1_L01_P163" (solid, remove dead copper, pour order 163): 88.328,245.2 74.78,245.2 73.662,244.056 73.662,237.96 93.442,237.96 93.442,245.2
B503_Ground on L1 "L1-eMMC_GND" (solid, pour order 147): 112.801,233.236 112.8,233.237 98.128,233.237 97.698,233.667 97.684,233.654 73.698,233.654 73.698,237.566 73.711,237.579 97.621,237.579 98.031,237.989 98.032,237.989 112.877,237.989 112.878,237.989 112.878,233.234
NetC693_1 on L1 "L1-NetC693_1" (solid, pour order 203): 35.331,225.234 31.229,221.132 31.229,215.252 32.029,214.452 37.211,214.452 38.544,215.786 38.544,217.276 38.909,217.64 42.862,217.64 42.862,223.444 41.072,225.234
SW2 on L1 "SW2_L01_P165" (solid, pour order 165): 88.786,226.099 75.077,226.099 73.698,227.457 73.698,233.323 93.442,233.323 93.442,226.099
US+_Vcc_PS_IntFp on L1 "US+_VCC_PS_INTFP_L01_P099" (solid, pour order 99): 145.706,304.356 148.104,301.958 148.104,289.481 146.012,287.388 138.648,287.388 138.102,287.934 138.112,287.945 138.112,303.81 138.659,304.356
CSP on L1 "L1-CSP" (solid, pour order 279): 35.344,235.28 43.258,235.28 45.949,232.589 45.949,230.226 44.005,228.282 36.106,228.282 34.023,230.365 34.023,234.036 35.242,235.255
no net on L1 "L1-No Net" (solid, pour order 269): 91.618,222.154
12V_LT3042 on L1 "L1-3V3_RAIL" (solid, pour order 267): 101.724,216.814 108.378,216.814 108.938,217.374 108.938,219.836 107.743,221.031 96.275,221.031 94.866,219.621 94.866,217.233 95.272,216.827 101.787,216.827
3V3_RAIL on L1 "L1-3V3_RAIL" (solid, pour order 251): 107.391,183.528 114.046,183.528 114.605,184.087 114.605,186.55 113.411,187.744 101.943,187.744 100.533,186.334 100.533,183.947 100.94,183.54 107.455,183.54
Vout2_1 on L1 "L1-Vout2_1" (solid, pour order 247): 91.63,172.441 93.398,172.441 100.103,165.735 113.817,165.735 115.595,163.957 115.595,160.909 114.91,160.223 114.91,160.147 114.14,160.147 93.738,160.146 89.599,164.285 89.599,171.501 90.538,172.441
Vout1_1 on L1 "L1-Vout1_1" (solid, pour order 243): 96.208,186.85 101.498,181.559 113.602,181.559 114.579,180.581 114.579,179.317 116.187,179.317 117.615,177.889 117.615,176.949 117.516,176.851 93.685,176.851 90.081,180.454 90.081,185.039 91.892,186.85
Vout1_2 on L1 "L1-Vout1_2" (solid, pour order 239): 92.926,217.589 95.618,214.897 108.372,214.897 111.443,211.826 111.443,210.338 110.605,209.5 92.239,209.5 88.816,212.924 88.816,216.209 90.195,217.589
PWR_OUT_20V on L1 "L1-PWR_OUT_20V" (solid, pour order 235): 48.822,193.927 48.683,193.788 48.683,190.731 49.716,189.698 50.563,189.698 50.931,190.066 50.931,192.373 49.378,193.926 48.835,193.926
PWR_OUT_20V on L1 "L1-PWR_OUT_20V 1" (solid, pour order 233): 48.822,194.039 48.683,194.179 48.683,197.235 49.716,198.269 50.563,198.269 50.931,197.901 50.931,195.593 49.378,194.041 48.835,194.041
Vout_2_Selector on L1 "L1-Vout_2_Selector" (solid, pour order 231): 48.532,193.927 48.671,193.788 48.671,190.731 47.638,189.698 46.792,189.698 46.424,190.066 46.424,192.373 47.976,193.926 48.519,193.926
Battery_PWR on L1 "L1-Battery_PWR" (solid, pour order 229): 48.532,194.039 48.671,194.179 48.671,197.235 47.638,198.269 46.792,198.269 46.424,197.901 46.424,195.593 47.976,194.041 48.519,194.041
Power2_In_CM on L1 "L1-Power2_In_CM" (solid, pour order 227): 45.733,178.917 45.472,179.178 45.202,179.178 45.075,179.051 45.075,177.137 45.288,176.924 45.288,176.32 45.473,176.136 46.943,176.136 47.123,175.943 48.009,175.057 48.552,175.057 48.565,175.056 48.704,175.195 48.704,178.252 47.671,179.285 46.825,179.285 46.456,178.917
Power1_In_CM on L1 "L1-Power1_In_CM" (solid, pour order 225): 46.038,172.167 45.337,172.868 45.337,173.437 45.739,173.839 46.878,173.839 46.892,173.825 48.009,174.942 48.552,174.942 48.565,174.943 48.704,174.804 48.704,171.747 48.636,171.679 48.636,170.464 47.561,169.389 45.822,169.389 45.809,169.402 45.809,169.788 46.038,170.017
Vout_1_Selector on L1 "L1-Vout_1_Selector" (solid, pour order 223): 48.855,175.056 48.716,175.195 48.716,178.252 49.749,179.285 50.595,179.285 50.964,178.917 50.964,176.61 49.411,175.057 48.868,175.057
Vout_1_Selector on L1 "L1-Vout_1_Selector 1" (solid, pour order 221): 48.855,174.943 48.716,174.804 48.716,171.747 49.749,170.714 50.595,170.714 50.964,171.082 50.964,173.389 49.411,174.942 48.868,174.942
Vout_2_Selector on L1 "L1-Vout_2_Selector 1" (solid, pour order 219): 48.855,184.265 48.716,184.126 48.716,181.069 49.749,180.036 50.595,180.036 50.964,180.404 50.964,182.711 49.411,184.264 48.868,184.264
Vout_2_Selector on L1 "L1-Vout_2_Selector 2" (solid, pour order 217): 48.855,184.378 48.716,184.517 48.716,187.574 49.749,188.607 50.595,188.607 50.964,188.239 50.964,185.932 49.411,184.379 48.868,184.379
Vout_1_Selector on L1 "L1-Vout_1_Selector 2" (solid, pour order 215): 48.565,184.265 48.704,184.126 48.704,181.069 47.671,180.036 46.825,180.036 46.456,180.404 46.456,182.711 48.009,184.264 48.552,184.264
CSN on L1 "L1-CSN" (solid, pour order 213): 48.565,184.378 48.704,184.517 48.704,187.574 47.671,188.607 46.825,188.607 46.456,188.239 46.456,185.932 48.009,184.379 48.552,184.379
no net on L1 "L1-No Net" (solid, pour order 159): 92.507,97.142
0.85V@40A_INA on L1 "0.85V@40A_INA_L01_P150" (solid, pour order 150): 93.832,226.109 93.832,233.306 97.534,233.306 97.862,232.978 113.243,232.978 113.243,238.214 97.767,238.214 97.5,237.947 93.832,237.947 93.832,245.2 117.137,245.2 117.137,226.109
AGND_2 on L1 "AGND_2_L01_P134" (solid, remove dead copper, pour order 134): 58.433,213.225 68.437,213.225 68.437,199.489 59.212,199.489 56.667,202.034 56.667,211.46
B503_Ground on L7(PWR/GND) "B503_GROUND_L07_P259" (solid, pour order 259): 25.865,150.02 359.494,150.02 359.494,499.397 25.865,499.397
3V3_RAIL on L7(PWR/GND) "L7(PWR/GND)-3V3_RAIL" (solid, pour order 255): 112.573,190.82 111.872,190.119 102.243,190.119 99.2,187.076 99.2,183.629 100.419,182.41 114.783,182.41 115.557,181.635 115.557,163.36 119.215,159.702 127.203,159.702 139.268,171.767 139.268,196.139 164.376,221.247 222.872,221.247 272.682,271.056 290.906,271.056 306.794,286.944 306.794,350.291 314.642,358.14 314.642,390.233 302.438,402.438 169.887,402.438 160.692,411.632 53.708,411.632 30.81,388.734 30.81,368.173 63.41,335.573 134.278,335.573 154.508,355.803 205.664,355.803 224.879,336.588 224.879,298.629 207.669,281.419 186.436,281.419 124.422,219.405 117.399,219.354 96.353,219.354 84.569,231.138 84.569,244.284 90.322,250.038 112.674,250.038 114.579,251.943 114.529,251.993 114.529,311.302 105.156,320.675 87.287,320.675 81.534,326.428 38.5,326.428 32.118,320.046 32.118,199.146 38.91,192.354 38.91,168.532 42.951,164.49 71.285,164.49 73.33,166.535 73.33,180.226 87.744,194.64 111.364,194.64 112.573,193.432
US+_Vcc_PS_IntFp on L7(PWR/GND) "US+_VCC_PS_INTFP_L07_P100" (solid, pour order 100): 183.397,310.539 184.397,309.539 184.397,295.539 176.309,287.452 153.022,287.452 138.532,287.452 138.102,287.881 138.102,305.501 143.141,310.539
0.85V@40A_INA on L7(PWR/GND) "0.85V@40A_INA_L07_P148" (solid, pour order 148): 98.514,243.599 121.488,243.599 125.463,247.574 125.463,300.596 129.984,305.118 136.742,305.118 137.719,304.141 137.719,287.35 142.303,282.765 142.303,232.004 137.132,226.832 98.615,226.832 97.942,227.506 97.942,243.027
Vout_1_Selector on L7(PWR/GND) "VOUT_1_SELECTOR_L07_P114" (solid, pour order 114): 48.71,171.566 49.56,170.714 50.782,170.714 51.219,171.151 51.219,179.279 48.872,181.626 48.872,183.189 48.133,183.928 48.369,184.163 48.797,184.163 48.581,184.379 47.911,184.379 45.775,182.242 45.775,180.368 48.71,177.432
SW2 on L7(PWR/GND) "SW2_L07_P135" (solid, pour order 135): 88.786,226.099 75.077,226.099 73.698,227.457 73.698,233.323 93.442,233.323 93.442,226.099
SW1 on L7(PWR/GND) "SW1_L07_P139" (solid, remove dead copper, pour order 139): 88.328,245.2 74.78,245.2 73.662,244.056 73.662,237.96 93.442,237.96 93.442,245.2
B503_Ground on L8 (Plane_GND) "B503_GROUND_L08_P273" (solid, pour order 273): 25.87,150.012 359.499,150.012 359.499,499.389 25.87,499.389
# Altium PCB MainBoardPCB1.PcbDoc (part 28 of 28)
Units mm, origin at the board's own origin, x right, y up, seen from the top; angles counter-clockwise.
Board outline 258.95 x 308.86 mm, 16 copper layers (L1, L2 (GND), L3 (Sign), L4 (GND), L5 (Sign), L6 (PWR/GND), L7(PWR/GND), L8 (Plane_GND), L9 (PWR/GND), L10 (PWR/GND), L11 (PWR/GND), L12 (Sign), L13 (GND), L14 (Sign), L15 (GND), L16), stack 2.502 mm thick; 2397 components, 1744 nets, 8397 pads, 4112 vias.
Unrouted connection lines stored in the file: 3547.

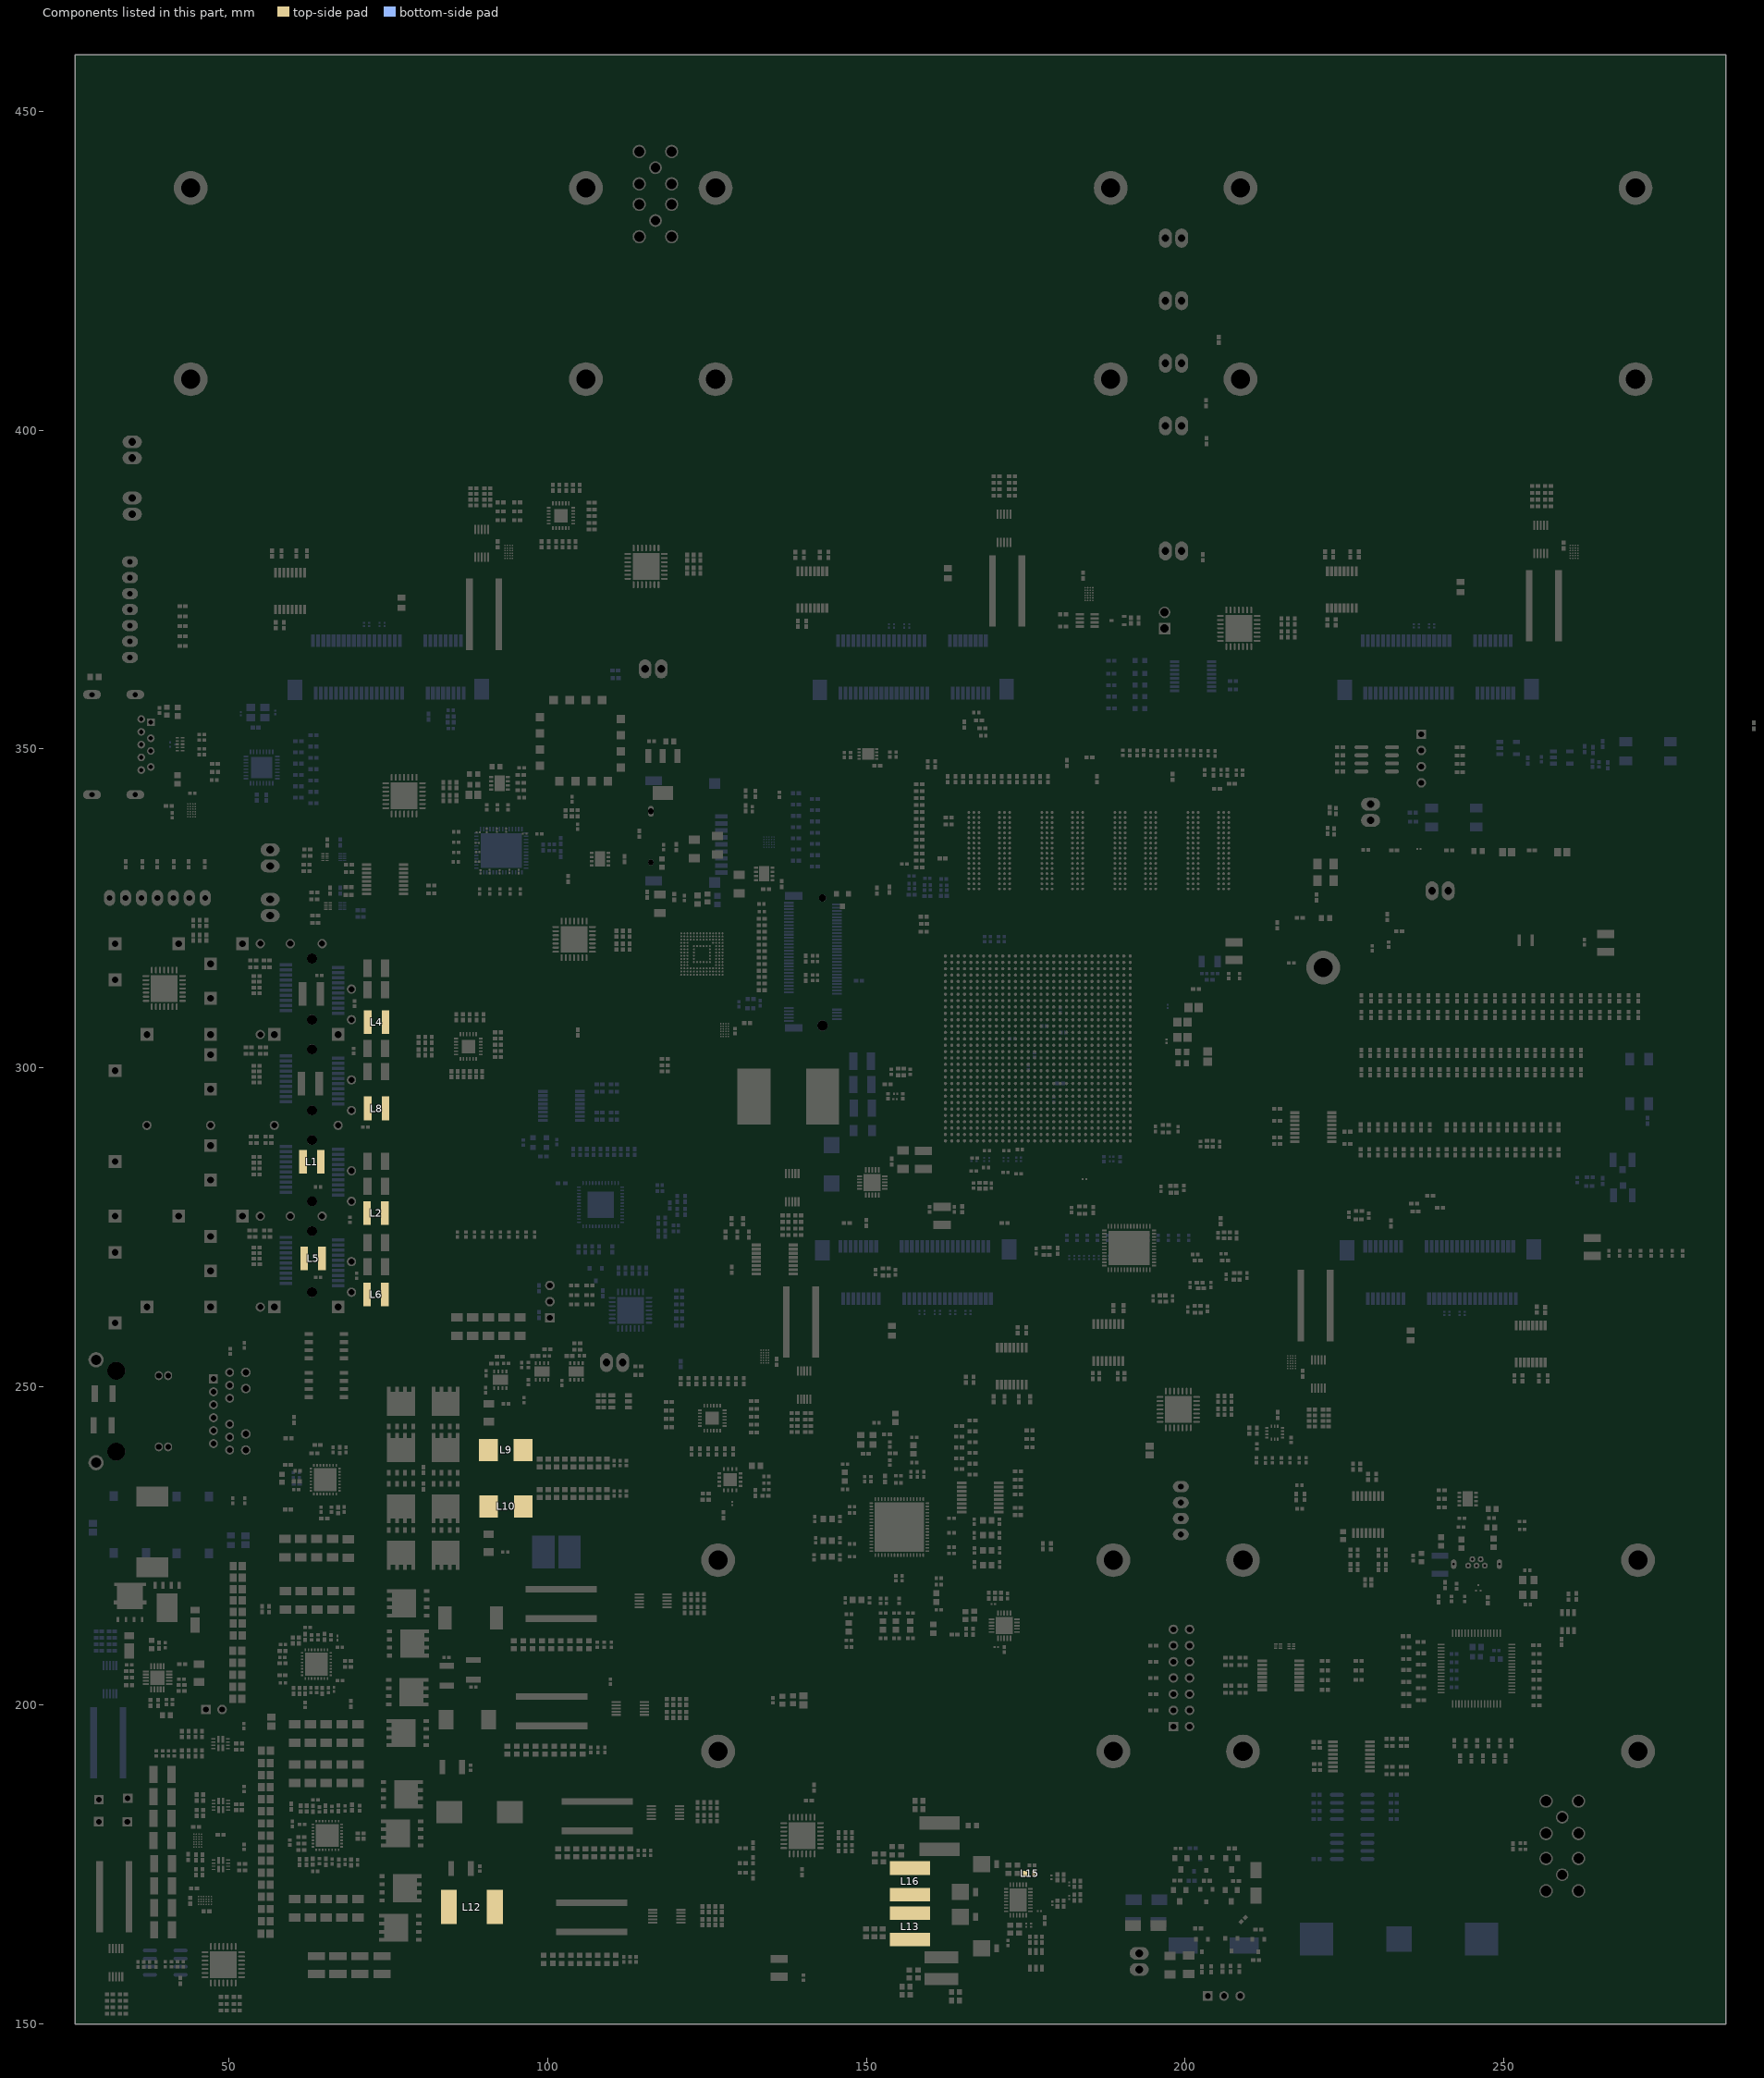
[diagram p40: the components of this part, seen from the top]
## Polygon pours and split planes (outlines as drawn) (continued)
5V_RAIL on L8 (Plane_GND) "L8 (Plane_GND)-No Net" (solid, pour order 265): 106.762,206.926 93.345,206.926 91.326,204.907 91.326,200.932 93.421,198.836 118.986,198.836 145.39,172.433 210.274,172.433 236.918,199.078 236.918,225.405 234.721,225.405 216.332,243.794 160.071,243.794 131.305,215.029 114.859,215.029 106.769,206.939
US+_Vcc_PS_IntFp on L8 (Plane_GND) "US+_VCC_PS_INTFP_L08_P098" (solid, pour order 98): 184.397,309.539 184.397,295.539 176.309,287.452 153.022,287.452 138.532,287.452 138.102,287.881 138.102,305.501 142.141,309.539
0.85V@40A_INA on L8 (Plane_GND) "0.85V@40A_INA_L08_P104" (solid, pour order 104): 98.514,243.599 121.488,243.599 125.463,247.574 125.463,300.596 129.984,305.118 136.742,305.118 137.719,304.141 137.719,287.35 142.303,282.765 142.303,232.004 137.132,226.832 98.615,226.832 97.942,227.506 97.942,243.027
0V9@1A_REG3 on L8 (Plane_GND) "L8 (Plane_GND)-0V9@1A_REG3" (solid, pour order 97): 150.203,285.681 152.641,283.243 152.641,280.772 153.492,279.921 154.788,279.921 155.613,280.746 155.613,285.064 153.282,287.395 150.54,287.395 150.203,287.058
B503_Ground on L6 (PWR/GND) "B503_GROUND_L06_P277" (solid, remove dead copper, pour order 277): 25.87,150.012 359.499,150.012 359.499,499.389 25.87,499.389
US+_Vcc_PS_DDR_504 on L6 (PWR/GND) "US+_VCC_PS_DDR_504_L06_P106" (solid, pour order 106): 181.397,311.539 181.397,314.539 182.909,316.052 185.433,316.052 185.737,315.845 190.59,315.845 192.492,313.944 193.822,313.944 195.929,311.837 195.929,310.267 195.184,309.522 193.352,309.522 191.076,311.798 185.229,311.798 184.459,311.027 181.884,311.027 181.884,311.052
CSP on L6 (PWR/GND) "L6 (PWR/GND)-CSP" (solid, pour order 275): 36.83,235.496 43.193,235.496 49.835,228.854 49.835,202.349 49.136,201.651 44.228,201.651 42.634,203.245 42.634,224.104 35.573,231.166 35.573,234.239
RAM_Vcc1V2 on L9 (PWR/GND) "L9 (PWR/GND)-RAM_Vcc1V2" (solid, pour order 281): 168.383,287.344 168.383,290.919 169.004,291.539 176.973,291.539 179.214,293.781 179.214,303.068 177.965,304.317 177.965,308.994 177.905,309.054 176.912,309.054 175.397,307.539 175.397,295.539 174.397,294.539 167.397,294.539 165.95,295.986 161.915,295.986 161.468,295.539 161.62,295.387 161.662,288.579 160.426,287.344 160.426,228.549 122.517,190.64 122.517,178.689 119.875,176.048 102.984,176.048 97.701,170.764 97.701,167.411 99.936,165.176 131.623,165.176 180.442,213.995 180.442,245.478 202.594,267.631 202.594,278.057 216.421,291.884 216.421,340.462 210.642,346.24 160.845,346.24 153.314,338.709 153.314,328.981 160.426,321.869 188.337,321.869 193.314,316.892 193.256,316.834 193.256,284.607 178.613,269.964 168.432,269.964 167.246,271.488 167.246,277.553 168.453,278.76 168.453,287.274
PWR_OUT_20V on L9 (PWR/GND) "PWR_OUT_20V_L09_P167" (solid, pour order 167): 79.121,258.534 86.487,258.534 88.341,256.68 88.341,156.502 55.689,156.502 55.689,240.974 74.155,258.534
US+_MGTVccAux on L9 (PWR/GND) "US+_MGTVCCAUX_L09_P103" (solid, pour order 103): 172.397,315.539 173.397,314.539 173.397,313.539 172.397,312.539 172.397,311.539 170.397,311.539 169.397,310.539 169.397,304.539 170.397,303.539 170.397,297.539 169.911,297.053 164.883,297.053 163.397,298.539 159.207,298.539 158.919,298.828 158.919,302.717 159.741,303.539 164.397,303.539 166.397,305.539 166.397,312.539 169.397,315.539
Vout_2_Selector on L9 (PWR/GND) "L9 (PWR/GND)-Vout_2_Selector" (solid, pour order 237): 48.73,184.339 48.729,180.589 49.654,179.663 50.529,179.663 51.194,180.328 51.194,188.436 48.98,190.649 48.98,193.68 48.677,193.983 47.99,193.983 46.284,192.277 46.284,189.77 48.73,187.325
no net on L9 (PWR/GND) "NONET_L09_P145" (solid, pour order 145): 60.856,45.86
B503_Ground on L10 (PWR/GND) "B503_GROUND_L10_P109" (solid, remove dead copper, pour order 109): 25.87,150.012 359.499,150.012 359.499,499.389 25.87,499.389
ETH_VDDIO on L10 (PWR/GND) "ETH_VDDIO_L10_P102" (solid, pour order 102): 165.557,315.862 166.637,314.782 166.637,309.004 167.615,308.026 174.91,308.026 175.793,307.143 175.793,305.13 165.037,305.13 162.826,307.341 156.743,307.341 156.743,312.423 160.391,312.423 163.83,315.862
1V8@0.5A_ADC_filtered on L10 (PWR/GND) "1V8@0.5A_ADC_FILTERED_L10_P101" (solid, pour order 101): 170.129,298.272 170.129,297.437 171.027,296.539 175.855,296.539 176.847,295.546 176.847,288.442 174.282,285.877 154.432,285.877 152.514,283.959 152.514,282.283 152.921,281.876 169.202,281.876 193.18,281.876 203.429,292.125 203.429,311.147 202.308,312.268 199.887,312.268 198.73,311.11 198.73,294.792 191.071,287.134 181.576,287.134 179.921,288.789 179.921,296.215 182.397,298.691 182.397,300.539 182.397,307.048 179.393,310.052 177.324,310.052 176.987,309.715 176.987,309.172 180.397,305.763 180.397,301.644 177.749,298.996 170.854,298.996
US+_MGTVccAux on L10 (PWR/GND) "US+_MGTVCCAUX_L10_P108" (solid, pour order 108): 186.023,304.851 188.62,304.851 189.154,304.317 189.154,298.782 189.686,298.25 189.686,295.829 188.747,294.89 188.747,293.357 185.572,290.182 182.27,290.182 182.067,290.385 182.067,291.808 184.01,293.751 184.01,302.838
0V9@1A_REG3 on L10 (PWR/GND) "L10 (PWR/GND)-No Net" (solid, pour order 107): 158.064,296.05 156.223,294.208 156.223,289.56 152.133,285.471 151.257,285.471 150.431,286.296 150.431,287.376 153.302,290.246 153.302,294.754 156.718,298.171 158.077,298.171 167.653,298.171 169.901,295.923 171.839,295.923 172.093,296.177 175.76,296.177 176.397,295.539 176.397,294.539 165.397,294.539 163.887,296.05
no net on L2 (GND) "NONET_L02_P115" (solid, remove dead copper, pour order 115): 174.608,280.136 174.555,280.189 174.555,291.295 189.304,291.295 189.307,291.298 189.307,280.136
no net on L2 (GND) "NONET_L02_P136" (solid, remove dead copper, pour order 136): 216.165,276.488 216.165,286.209 231.974,286.209 231.974,276.984 230.962,275.972 216.681,275.972
B503_Ground on L16 "L16-No Net" (solid, pour order 149): 112.814,233.236 112.813,233.237 98.141,233.237 97.71,233.667 97.696,233.654 73.71,233.654 73.71,237.566 73.723,237.579 97.634,237.579 98.044,237.989 112.89,237.989 112.89,233.234
CSN on L12 (Sign) "L12 (Sign)-CSN" (solid, pour order 211): 41.567,193.065 47.899,186.734 51.083,186.734 51.349,187 51.349,190.07 46.736,194.683 46.736,207.893 46.336,208.293 44.302,208.293 41.567,205.557
RAM_DDR4_VTT on L5 (Sign) "L5 (Sign)-RAM_DDR4_VTT" (solid, pour order 283): 150.244,350.898 150.425,351.079 157.856,351.079 159.956,348.979 179.167,348.979 180.048,348.098 180.048,346.265 179.199,345.417 159.258,345.417 158.737,344.896 158.737,333.997 157.204,332.464 155.766,332.464 154.407,333.823 154.407,345.503 152.552,347.358 150.832,347.358 150.244,347.945
V_PoE+ on L14 (Sign) "L14 (Sign)-V_PoE+" (solid, pour order 207): 49.6,234.95 55.334,229.216 55.334,219.532 47.324,211.522 31.861,211.522 26.619,216.764 26.619,233.705 27.864,234.95
B503_Ground on L13 (GND) "B503_GROUND_L13_P110" (solid, pour order 110): 25.87,150.012 359.499,150.012 359.499,499.389 25.87,499.389
B503_Ground on L4 (GND) "B503_GROUND_L04_P111" (solid, pour order 111): 25.87,150.012 359.499,150.012 359.499,499.389 25.87,499.389
B503_Ground on L15 (GND) "B503_GROUND_L15_P112" (solid, pour order 112): 25.87,150.012 359.499,150.012 359.499,499.389 25.87,499.389

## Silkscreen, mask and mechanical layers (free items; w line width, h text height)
Top Overlay:
  text "0.85V 40A" at 102.387,243.332 h0.51
  text "12V 8A" at 106.648,211.722 h0.51
  text "5V 10A" at 104.902,195.707 h0.51

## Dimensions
26.129,458.617 to 26.129,150.271 on L1
26.129,458.617 to 284.564,458.617 on L1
